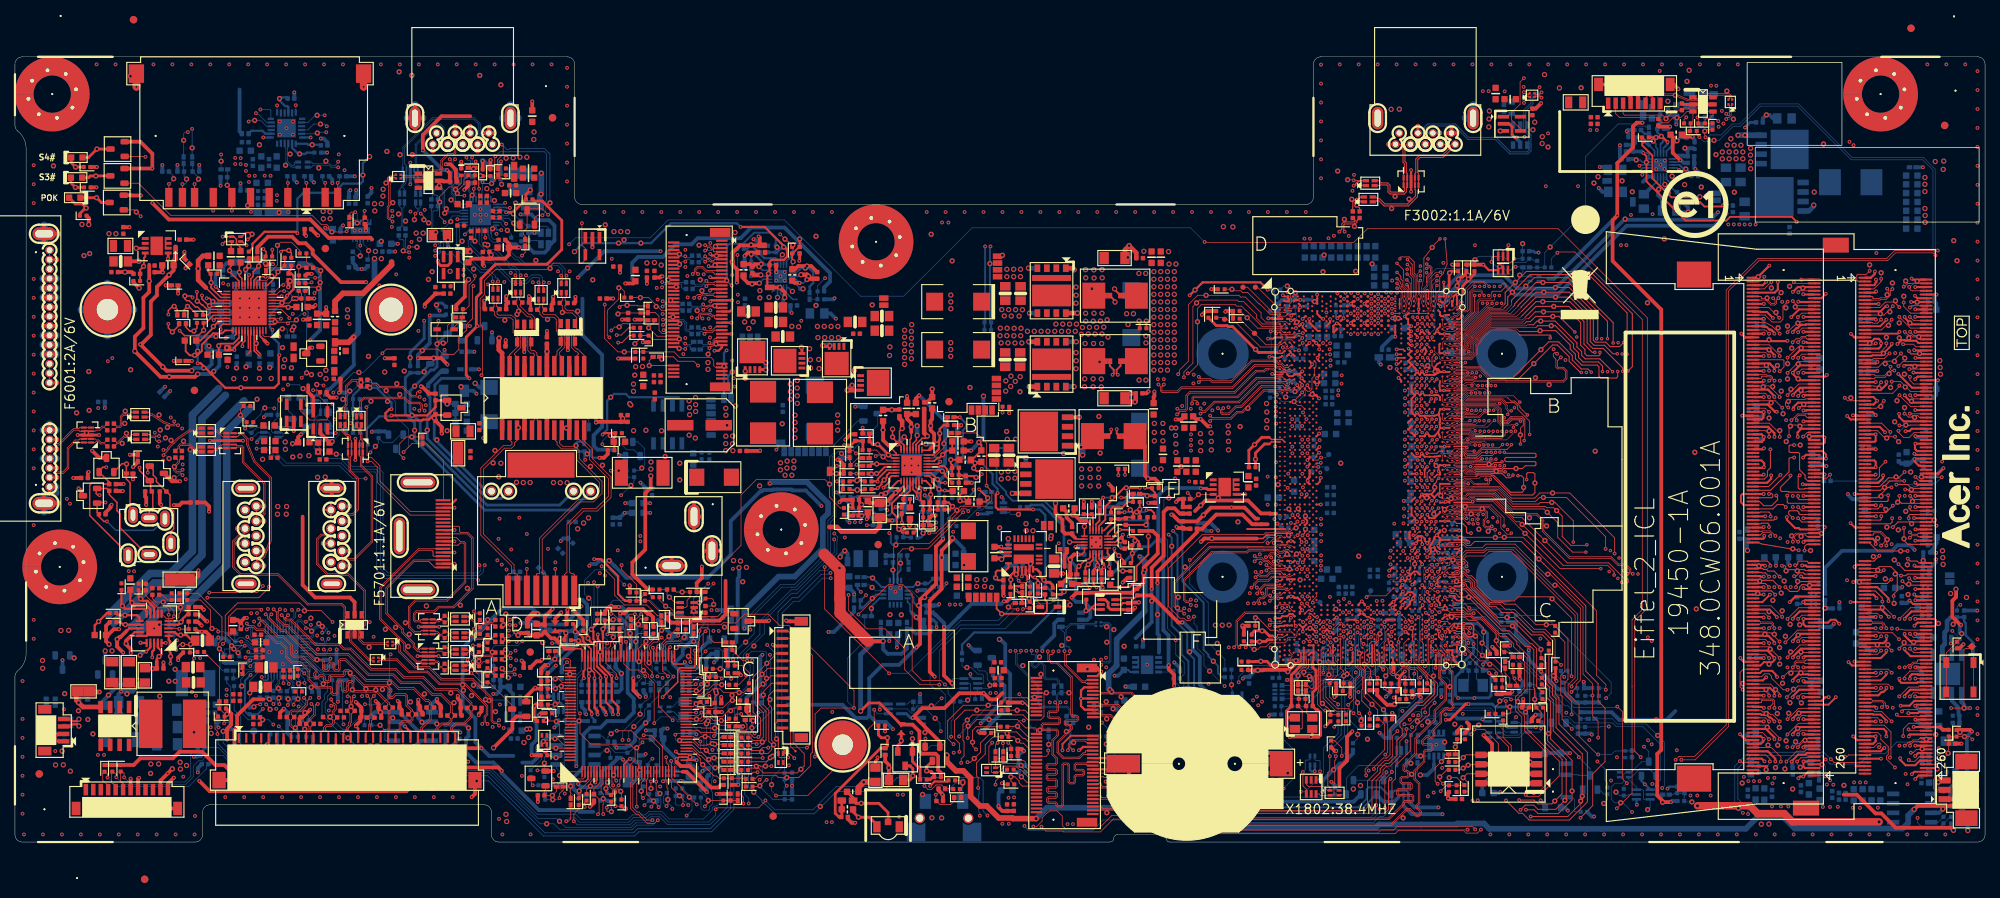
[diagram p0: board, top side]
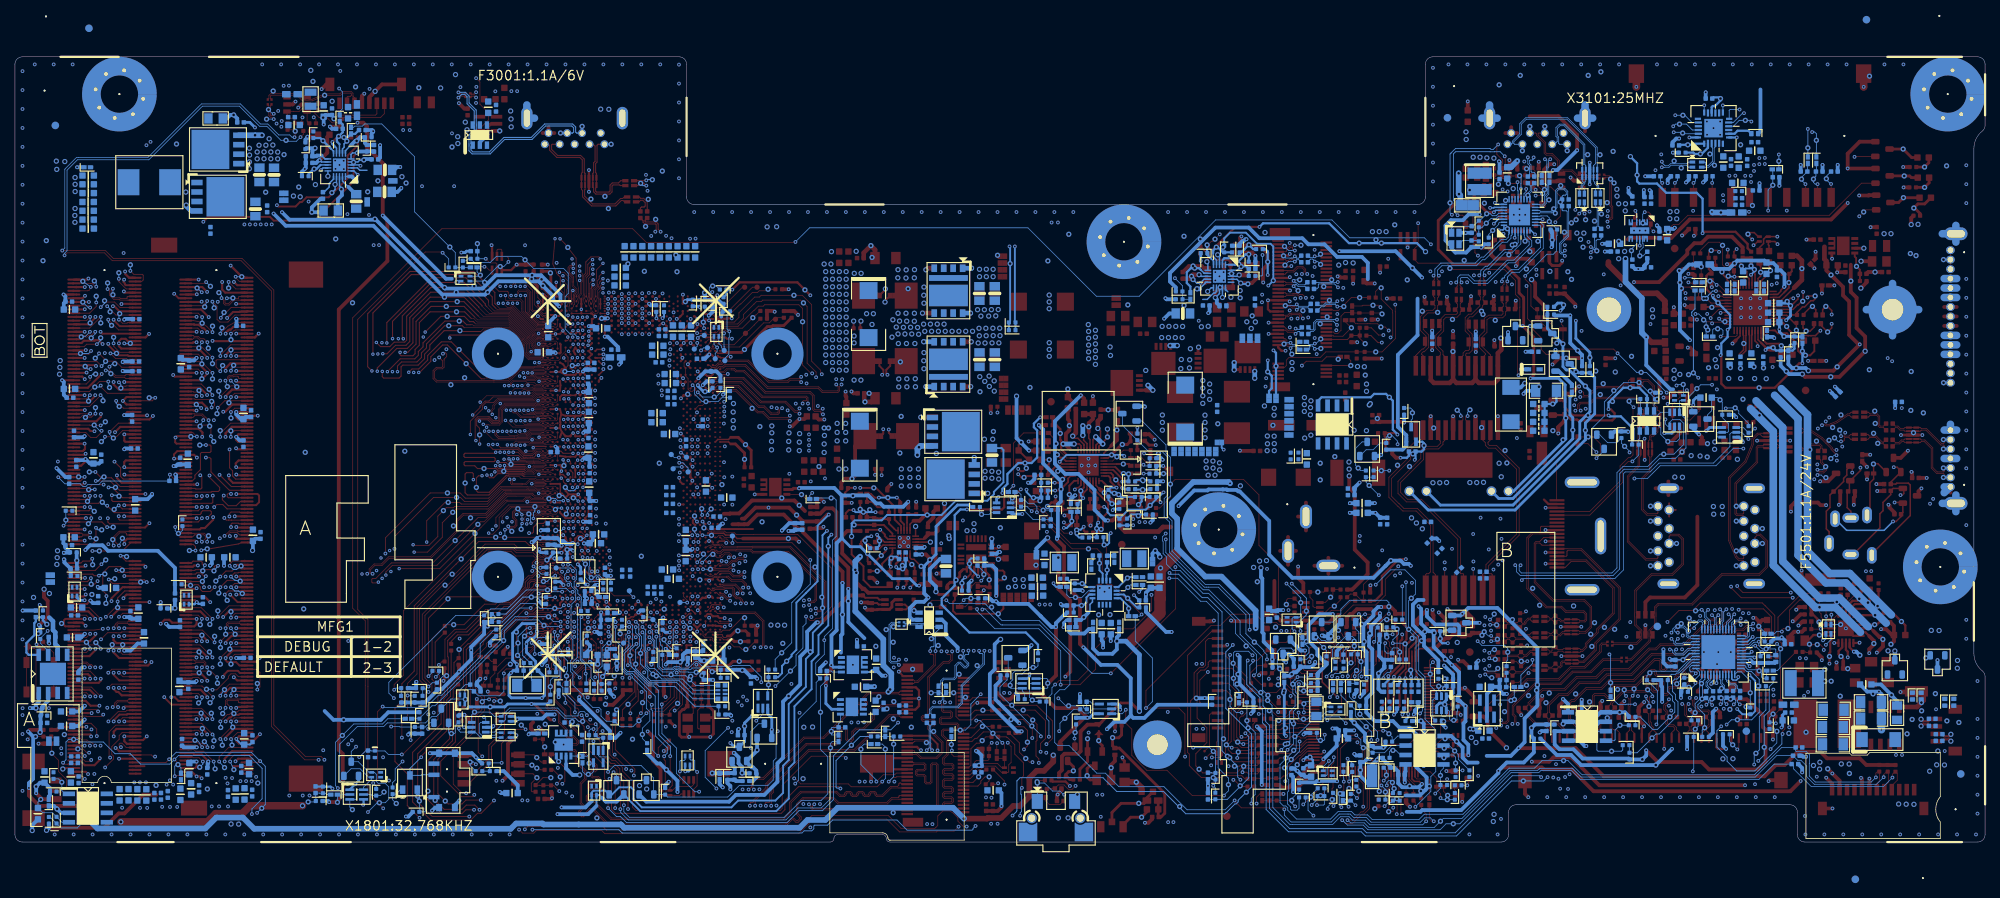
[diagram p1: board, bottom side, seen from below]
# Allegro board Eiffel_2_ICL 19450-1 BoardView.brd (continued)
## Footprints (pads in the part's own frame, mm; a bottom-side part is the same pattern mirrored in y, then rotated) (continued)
C166KK-12209-L
  round 0.254 hole 1.27 unplated: (-15.595,0) (15.595,0)
  oval 1.727x3.124 hole 1.016x2.413: 23(18.075,1.11) 24(-18.075,1.11)
  oval 1.041x1.168 hole 0.762: P1(1.905,1.84) P2(0.635,1.84) P3(-0.635,1.84) P4(-1.905,1.84) P5(-3.175,1.84) P6(-4.445,1.84) P7(-5.715,1.84) P8(-6.985,1.84) P9(-8.255,1.84) P10(-9.525,1.84) P11(-10.795,1.84) P12(-12.065,1.84) P13(-13.335,1.84) P14(-14.605,1.84) P15(-15.875,1.84) S1(15.875,1.84) S2(14.605,1.84) S3(13.335,1.84) S4(12.065,1.84) S5(10.795,1.84) S6(9.525,1.84) S7(8.255,1.84)
C402-TO0D2H26
  custom 0.152x0.152 smd: 1(0,0.457) 2(0,-0.457)
C402H22
  custom 0.152x0.152 smd: 1(0,0.445) 2(0,-0.445)
C402H24
  custom 0.152x0.152 smd: 1(0,0.445) 2(0,-0.445)
C603H32
  custom 0.216x0.216 smd: 1(0,0.762) 2(0,-0.762)
C603H36
  custom 0.216x0.216 smd: 1(0,0.762) 2(0,-0.762)
C603H38
  custom 0.216x0.216 smd: 1(0,0.762) 2(0,-0.762)
C603H40
  custom 0.216x0.216 smd: 1(0,0.762) 2(0,-0.762)
C805H54
  rect 1.397x1.143 smd: 1(0,0.965) 2(0,-0.965)
C805H56
  rect 1.397x1.143 smd: 1(0,0.965) 2(0,-0.965)
C1206H71
  rect 1.651x1.27 smd: 1(0,1.397) 2(0,-1.397)
CON2C-U
  custom 0.171x0.171 smd: 1(0,0.533) 2(0,-0.533)
CON2O-U
  custom 0.159x0.159 smd: 1(0,0.254) 2(0,-0.254)
CT7343H79
  rect 2.413x2.286 smd: 1(0,3.15) 2(0,-3.15)
CT7343H83
  rect 2.413x2.286 smd: 1(0,3.15) 2(0,-3.15)
D4724AKH44
  rect 2.007x1.549 smd: A(0,2.221) K(0,-2.221)
DFN8F3-G2517H32
  rect 0.406x0.94 smd: 1(0.975,1.538) 2(0.325,1.538) 3(-0.325,1.538) 4(-0.975,1.538) 5(-0.975,-1.538)
  rect 0.025x0.025 smd: 6(-0.325,-1.538) 8(0.975,-1.538)
  custom 0.235x0.235 smd: 7(0.325,-1.538)
  rect 2.489x1.676 smd: 9(0,0)
DFN10G2510H22
  rect 0.305x0.787 smd: 1(1,0.494) 5(-1,0.494) 6(-1,-0.494) 10(1,-0.494)
  rect 0.254x0.787 smd: 2(0.521,0.494) 4(-0.521,0.494) 7(-0.521,-0.494) 9(0.521,-0.494)
  rect 0.025x0.025 smd: 3(0,0.494)
  rect 0.406x1.753 smd: 8(0,-0.494)
DO214AAAK-1121H97
  rect 2.311x2.032 smd: A(0,2.322) K(0,-2.322)
DUMMY-LD65D85-4PH20
  rect 0.305x0.356 smd: 1(-0.25,0.325) 2(-0.25,-0.325) 3(0.25,-0.325) 4(0.25,0.325)
GAP-CLOSE-PWR-3
  rect 0.66x0.762 smd: 1(-0.305,0) 2(0.305,0)
GEN315R158-8-F-C-S-U
  round 0.254 hole 4.013 unplated: (0,0)
  round 0.864 hole 0.508: 1(3.189,0.634) 2(1.806,2.703) 3(-0.634,3.189) 4(-2.703,1.806) 5(-3.189,-0.634) 6(-1.806,-2.703) 7(0.634,-3.189) 8(2.703,-1.806)
J1100D-C6DH-0002R
  oval 1.321x2.235 hole 0.61x1.524: 1(2.9,-1) 4(2.1,2.3) 5(-2.18,2.8) 6(-2.825,-2.6)
  oval 2.235x1.321 hole 1.524x0.61: 2(0,2.43) 3(0,-2.48)
L402-TO0D2H24
  custom 0.152x0.152 smd: 1(0,0.457) 2(0,-0.457)
L402H24
  custom 0.14x0.14 smd: 1(0,0.445) 2(0,-0.445)
L603H38
  custom 0.216x0.216 smd: 1(0,0.762) 2(0,-0.762)
L2520-D620H48
  rect 2.261x1.245 smd: 1(0,1.018) 2(0,-1.018)
L3030-3009-2H40
  rect 3.251x1.524 smd: 1(0,1.108) 2(0,-1.108)
L4947-1115H119
  rect 2.007x2.261 smd: 1(0,2.049) 2(0,-2.049)
L7066-1830-UH119
  rect 3.505x2.921 smd: 1(0,2.78) 2(0,-2.78)
L7366-1930H158
  rect 3.505x3.073 smd: 1(0,2.856) 2(0,-2.856)
L8080-6020H158
  rect 6.502x3.15 smd: 1(0,2.944) 2(0,-2.944)
L125100-4P-1H37
  rect 0.762x0.432 smd: 1(0.625,0.341) 2(-0.625,0.341) 3(-0.625,-0.341) 4(0.625,-0.341)
L125100-4P-4H24
  rect 0.762x0.432 smd: 1(-0.625,0.341) 2(0.625,0.341) 3(0.625,-0.341) 4(-0.625,-0.341)
L125100-4P-5H24
  rect 0.457x0.838 smd: 1(-0.326,0.587) 2(0.326,0.587) 3(-0.326,-0.587) 4(0.326,-0.587)
LED1608-1A2KH40
  custom 0.216x0.216 smd: 1A(0,0.762) 2K(0,-0.762)
LED3020-3P-6H44
  rect 0.991x1.499 smd: 1(1.495,0) 3(-1.495,0)
  rect 0.889x0.889 smd: 2(0,-0.65)
LQFP128H63
  rect 0.203x1.524 smd: 1(6.2,7.747) 2(5.8,7.747) 3(5.4,7.747) 4(5,7.747) 5(4.6,7.747) 6(4.2,7.747) 7(3.8,7.747) 8(3.4,7.747) 9(3,7.747) 10(2.6,7.747) 11(2.2,7.747) 12(1.8,7.747) 13(1.4,7.747) 14(0.999,7.747) 15(0.599,7.747) 16(0.199,7.747) 17(-0.199,7.747) 18(-0.599,7.747) 19(-0.999,7.747) 20(-1.4,7.747) 21(-1.8,7.747) 22(-2.2,7.747) 23(-2.6,7.747) 24(-3,7.747) 25(-3.4,7.747) 26(-3.8,7.747) 27(-4.2,7.747) 28(-4.6,7.747) 29(-5,7.747) 30(-5.4,7.747) 31(-5.8,7.747) 32(-6.2,7.747) 65(-6.2,-7.747) 66(-5.8,-7.747) 67(-5.4,-7.747) 68(-5,-7.747) 69(-4.6,-7.747) 70(-4.2,-7.747) 71(-3.8,-7.747) 72(-3.4,-7.747) 73(-3,-7.747) 74(-2.6,-7.747) 75(-2.2,-7.747) 76(-1.8,-7.747) 77(-1.4,-7.747) 78(-0.999,-7.747) 79(-0.599,-7.747) 80(-0.199,-7.747) 81(0.199,-7.747) 82(0.599,-7.747) 83(0.999,-7.747) 84(1.4,-7.747) 85(1.8,-7.747) 86(2.2,-7.747) 87(2.6,-7.747) 88(3,-7.747) 89(3.4,-7.747) 90(3.8,-7.747) 91(4.2,-7.747) 92(4.6,-7.747) 93(5,-7.747) 94(5.4,-7.747) 95(5.8,-7.747) 96(6.2,-7.747)
  rect 1.524x0.203 smd: 33(-7.747,6.2) 34(-7.747,5.8) 35(-7.747,5.4) 36(-7.747,5) 37(-7.747,4.6) 38(-7.747,4.2) 39(-7.747,3.8) 40(-7.747,3.4) 41(-7.747,3) 42(-7.747,2.6) 43(-7.747,2.2) 44(-7.747,1.8) 45(-7.747,1.4) 46(-7.747,0.999) 47(-7.747,0.599) 48(-7.747,0.199) 49(-7.747,-0.199) 50(-7.747,-0.599) 51(-7.747,-0.999) 52(-7.747,-1.4) 53(-7.747,-1.8) 54(-7.747,-2.2) 55(-7.747,-2.6) 56(-7.747,-3) 57(-7.747,-3.4) 58(-7.747,-3.8) 59(-7.747,-4.2) 60(-7.747,-4.6) 61(-7.747,-5) 62(-7.747,-5.4) 63(-7.747,-5.8) 64(-7.747,-6.2) 97(7.747,-6.2) 98(7.747,-5.8) 99(7.747,-5.4) 100(7.747,-5) 101(7.747,-4.6) 102(7.747,-4.2) 103(7.747,-3.8) 104(7.747,-3.4) 105(7.747,-3) 106(7.747,-2.6) 107(7.747,-2.2) 108(7.747,-1.8) 109(7.747,-1.4) 110(7.747,-0.999) 111(7.747,-0.599) 112(7.747,-0.199) 113(7.747,0.199) 114(7.747,0.599) 115(7.747,0.999) 116(7.747,1.4) 117(7.747,1.8) 118(7.747,2.2) 119(7.747,2.6) 120(7.747,3) 121(7.747,3.4) 122(7.747,3.8) 123(7.747,4.2) 124(7.747,4.6) 125(7.747,5) 126(7.747,5.4) 127(7.747,5.8) 128(7.747,6.2)
MSS3-Q-T-R
  round 0.254 hole 0.965 unplated: (-1.5,0) (1.5,0)
  rect 0.61x1.499 smd: 1(-2.25,1.75) 2(0.751,1.75) 3(2.25,1.75)
  rect 0.991x0.813 smd: 4(-3.65,1.056) 5(-3.65,-1.056) 6(3.65,1.056) 7(3.65,-1.056)
NTC-402H22-U
  custom 0.14x0.14 smd: 1(0,0.445) 2(0,-0.445)
OSC-3225-4P-4H36
  rect 1.397x1.067 smd: 1(-1.171,-0.756) 2(1.171,-0.756) 3(1.171,0.756) 4(-1.171,0.756)
POLYSW-2114H30
  rect 1.6x0.965 smd: 1(0,0.94) 2(0,-0.94)
POLYSW-4633-UH43
  rect 3.505x1.626 smd: 1(0,1.834) 2(0,-1.834)
PPAK-5PH48
  rect 0.762x1.524 smd: 1(-1.905,-3.81) 2(-0.635,-3.81) 3(0.635,-3.81) 4(1.905,-3.81)
  rect 5.283x5.08 smd: 5(1.499,1.448)
  rect 0.025x0.025 smd: 6(-1.499,1.448) 7(-1.499,-1.448) 8(1.499,-1.448)
PPAK-8P-3333-1H40
  rect 0.406x0.94 smd: 1(-0.975,-2.283) 2(-0.325,-2.283) 3(0.325,-2.283) 4(0.975,-2.283)
  rect 0.025x0.025 smd: 5(0.65,1) 6(0,1) 7(-0.65,1)
  rect 3.251x3.099 smd: 8(0,0)
PPAK-8P-3333-2H40
  rect 0.406x0.914 smd: 1(-0.975,-2.347) 2(-0.325,-2.347) 3(0.325,-2.347) 4(0.975,-2.347)
  rect 3.48x3.023 smd: 5(1.01,0.895)
  rect 0.025x0.025 smd: 6(-1.01,0.895) 7(-1.01,-0.895) 8(1.01,-0.895)
PPAK-8P-G5324H44-COLAY
  rect 0.762x1.016 smd: 1(-1.905,-3.01) 2(-0.635,-3.01) 3(0.635,-3.01) 4(1.905,-3.01) 5(1.905,3.01) 6(0.635,3.01) 7(-0.635,3.01) 8(-1.905,3.01)
  rect 5.207x2.896 smd: 9(0,0.65)
  rect 5.207x0.787 smd: 10(0,-1.7)
PPAK-8PH48
  rect 0.762x1.524 smd: 1(-1.905,-3.81) 2(-0.635,-3.81) 3(0.635,-3.81) 4(1.905,-3.81)
  rect 5.283x5.08 smd: 5(0,0)
  rect 0.025x0.025 smd: 6(0.635,2.032) 7(-0.635,2.032) 8(-1.905,2.032)
QFN16G3-G2H34
  rect 0.305x0.787 smd: 1(0.75,1.614) 2(0.25,1.614) 3(-0.25,1.614) 4(-0.75,1.614) 9(-0.75,-1.614) 10(-0.25,-1.614) 11(0.25,-1.614) 12(0.75,-1.614)
  rect 0.787x0.305 smd: 5(-1.614,0.75) 6(-1.614,0.25) 7(-1.614,-0.25) 8(-1.614,-0.75) 13(1.614,-0.75) 14(1.614,-0.25) 15(1.614,0.25) 16(1.614,0.75)
  rect 2.007x2.007 smd: 17(0,0)
QFN20-G1D75H32
  rect 0.203x0.914 smd: 1(0.8,1.551) 2(0.4,1.551) 3(0,1.551) 4(-0.4,1.551) 5(-0.8,1.551) 11(-0.8,-1.551) 12(-0.4,-1.551) 13(0,-1.551) 14(0.4,-1.551) 15(0.8,-1.551)
  rect 0.914x0.203 smd: 6(-1.551,0.8) 7(-1.551,0.4) 8(-1.551,0) 9(-1.551,-0.4) 10(-1.551,-0.8) 16(1.551,-0.8) 17(1.551,-0.4) 18(1.551,0) 19(1.551,0.4) 20(1.551,0.8)
  rect 1.753x1.753 smd: 21(0,0)
QFN20-G2D1H34
  rect 0.305x1.092 smd: 1(0.999,1.956) 5(-0.999,1.956) 11(-0.999,-1.956) 15(0.999,-1.956)
  rect 0.305x1.143 smd: 2(0.5,1.93) 3(0,1.93) 4(-0.5,1.93) 12(-0.5,-1.93) 13(0,-1.93) 14(0.5,-1.93)
  rect 1.092x0.305 smd: 6(-1.956,0.999) 10(-1.956,-0.999) 16(1.956,-0.999) 20(1.956,0.999)
  rect 1.143x0.305 smd: 7(-1.93,0.5) 8(-1.93,0) 9(-1.93,-0.5) 17(1.93,-0.5) 18(1.93,0) 19(1.93,0.5)
  rect 2.108x2.108 smd: 21(0,0)
QFN22G4-G2P-1H36
  rect 0.305x0.914 smd: 1(1.25,2.051) 2(0.75,2.051) 3(0.25,2.051) 4(-0.25,2.051) 5(-0.75,2.051) 6(-1.25,2.051) 12(-1.25,-2.051) 13(-0.75,-2.051) 14(-0.25,-2.051) 15(0.25,-2.051) 16(0.75,-2.051) 17(1.25,-2.051)
  rect 0.914x0.305 smd: 7(-2.051,1.25) 8(-2.051,0.75) 9(-2.051,0.25) 10(-2.051,-0.75) 11(-2.051,-1.25) 18(2.051,-1.25) 19(2.051,-0.75) 20(2.051,-0.25) 21(2.051,0.25) 22(2.051,1.25)
  rect 2.692x1.245 smd: 23(0,0.7)
  rect 2.692x0.838 smd: 24(0,-0.9)
QFN24-G2D5H40-U
  rect 0.305x0.838 smd: 1(1.25,2.095) 6(-1.25,2.095) 13(-1.25,-2.095) 18(1.25,-2.095)
  rect 0.305x0.965 smd: 2(0.751,2.032) 3(0.25,2.032) 4(-0.25,2.032) 5(-0.751,2.032) 14(-0.751,-2.032) 15(-0.25,-2.032) 16(0.25,-2.032) 17(0.751,-2.032)
  rect 0.838x0.305 smd: 7(-2.095,1.25) 12(-2.095,-1.25) 19(2.095,-1.25) 24(2.095,1.25)
  rect 0.965x0.305 smd: 8(-2.032,0.751) 9(-2.032,0.25) 10(-2.032,-0.25) 11(-2.032,-0.751) 20(2.032,-0.751) 21(2.032,-0.25) 22(2.032,0.25) 23(2.032,0.751)
  rect 2.489x2.489 smd: 25(0,0)
QFN32J4-G2D75H32
  rect 0.203x0.838 smd: 1(1.4,2.051) 8(-1.4,2.051) 17(-1.4,-2.051) 24(1.4,-2.051)
  rect 0.203x0.914 smd: 2(1,2.051) 3(0.6,2.051) 4(0.2,2.051) 5(-0.2,2.051) 6(-0.6,2.051) 7(-1,2.051) 18(-1,-2.051) 19(-0.6,-2.051) 20(-0.2,-2.051) 21(0.2,-2.051) 22(0.6,-2.051) 23(1,-2.051)
  rect 0.838x0.203 smd: 9(-2.051,1.4) 16(-2.051,-1.4) 25(2.051,-1.4) 32(2.051,1.4)
  rect 0.914x0.203 smd: 10(-2.051,1) 11(-2.051,0.6) 12(-2.051,0.2) 13(-2.051,-0.2) 14(-2.051,-0.6) 15(-2.051,-1) 26(2.051,-1) 27(2.051,-0.6) 28(2.051,-0.2) 29(2.051,0.2) 30(2.051,0.6) 31(2.051,1)
  rect 2.743x2.743 smd: 33(0,0)
QFN32J4-G2D85H36
  rect 0.203x0.864 smd: 1(1.4,2.085) 2(1,2.085) 3(0.6,2.085) 4(0.2,2.085) 5(-0.2,2.085) 6(-0.6,2.085) 7(-1,2.085) 8(-1.4,2.085) 17(-1.4,-2.085) 18(-1,-2.085) 19(-0.6,-2.085) 20(-0.2,-2.085) 21(0.2,-2.085) 22(0.6,-2.085) 23(1,-2.085) 24(1.4,-2.085)
  rect 0.864x0.203 smd: 9(-2.085,1.4) 10(-2.085,1) 11(-2.085,0.6) 12(-2.085,0.2) 13(-2.085,-0.2) 14(-2.085,-0.6) 15(-2.085,-1) 16(-2.085,-1.4) 25(2.085,-1.4) 26(2.085,-1) 27(2.085,-0.6) 28(2.085,-0.2) 29(2.085,0.2) 30(2.085,0.6) 31(2.085,1) 32(2.085,1.4)
  rect 2.845x2.845 smd: 33(0,0)
QFN48J6-G4D55H40
  rect 0.203x1.016 smd: 1(2.2,3) 2(1.8,3) 3(1.4,3) 4(1,3) 5(0.6,3) 6(0.2,3) 7(-0.2,3) 8(-0.6,3) 9(-1,3) 10(-1.4,3) 11(-1.8,3) 12(-2.2,3) 25(-2.2,-3) 26(-1.8,-3) 27(-1.4,-3) 28(-1,-3) 29(-0.6,-3) 30(-0.2,-3) 31(0.2,-3) 32(0.6,-3) 33(1,-3) 34(1.4,-3) 35(1.8,-3) 36(2.2,-3)
  rect 1.016x0.203 smd: 13(-3,2.2) 14(-3,1.8) 15(-3,1.4) 16(-3,1) 17(-3,0.6) 18(-3,0.2) 19(-3,-0.2) 20(-3,-0.6) 21(-3,-1) 22(-3,-1.4) 23(-3,-1.8) 24(-3,-2.2) 37(3,-2.2) 38(3,-1.8) 39(3,-1.4) 40(3,-1) 41(3,-0.6) 42(3,-0.2) 43(3,0.2) 44(3,0.6) 45(3,1) 46(3,1.4) 47(3,1.8) 48(3,2.2)
  rect 4.547x4.547 smd: 49(0,0)
QFN48J6-G465H40
  rect 0.203x0.965 smd: 1(2.2,3.025) 2(1.8,3.025) 3(1.4,3.025) 4(1,3.025) 5(0.6,3.025) 6(0.2,3.025) 7(-0.2,3.025) 8(-0.6,3.025) 9(-1,3.025) 10(-1.4,3.025) 11(-1.8,3.025) 12(-2.2,3.025) 25(-2.2,-3.025) 26(-1.8,-3.025) 27(-1.4,-3.025) 28(-1,-3.025) 29(-0.6,-3.025) 30(-0.2,-3.025) 31(0.2,-3.025) 32(0.6,-3.025) 33(1,-3.025) 34(1.4,-3.025) 35(1.8,-3.025) 36(2.2,-3.025)
  rect 0.965x0.203 smd: 13(-3.025,2.2) 14(-3.025,1.8) 15(-3.025,1.4) 16(-3.025,1) 17(-3.025,0.6) 18(-3.025,0.2) 19(-3.025,-0.2) 20(-3.025,-0.6) 21(-3.025,-1) 22(-3.025,-1.4) 23(-3.025,-1.8) 24(-3.025,-2.2) 37(3.025,-2.2) 38(3.025,-1.8) 39(3.025,-1.4) 40(3.025,-1) 41(3.025,-0.6) 42(3.025,-0.2) 43(3.025,0.2) 44(3.025,0.6) 45(3.025,1) 46(3.025,1.4) 47(3.025,1.8) 48(3.025,2.2)
  rect 4.648x4.648 smd: 49(0,0)
R402H14
  custom 0.14x0.14 smd: 1(0,0.445) 2(0,-0.445)
R402H15
  custom 0.14x0.14 smd: 1(0,0.445) 2(0,-0.445)
R402H16
  custom 0.14x0.14 smd: 1(0,0.445) 2(0,-0.445)
R402H18
  custom 0.14x0.14 smd: 1(0,0.445) 2(0,-0.445)
R603H22
  custom 0.216x0.216 smd: 1(0,0.762) 2(0,-0.762)
R805H24
  rect 1.397x1.143 smd: 1(0,0.965) 2(0,-0.965)
R1206H26
  rect 1.651x1.27 smd: 1(0,1.397) 2(0,-1.397)
R1206H28
  rect 1.651x1.27 smd: 1(0,1.397) 2(0,-1.397)
R2512H32
  rect 3.505x1.778 smd: 1(0,2.794) 2(0,-2.794)
SC70-5H44
  rect 0.406x1.219 smd: 1(0.65,0.826) 2(0,0.826) 3(-0.65,0.826) 4(-0.65,-0.826) 5(0.65,-0.826)
SC70-6H44
  rect 0.406x1.016 smd: 1(-0.65,-0.94) 2(0,-0.94) 3(0.65,-0.94) 4(0.65,0.94) 5(0,0.94) 6(-0.65,0.94)
SE331721H237
  rect 1.422x3.556 smd: 1(0,2.574) 2(0,-2.574)
SKRBAJF010
  rect 1.473x0.813 smd: 1(-1.971,1.825) 2(-1.971,-1.825) 3(1.971,1.825) 4(1.971,-1.825)
SKT-HDMI22-148070
  rect 0.305x2.007 smd: 1(4.21,3.37) 2(3.71,3.37) 3(3.21,3.37) 4(2.71,3.37) 5(2.21,3.37) 6(1.71,3.37) 7(1.21,3.37) 8(0.71,3.37) 9(0.21,3.37) 10(-0.29,3.37) 11(-0.79,3.37) 12(-1.29,3.37) 13(-1.79,3.37) 14(-2.29,3.37) 15(-2.79,3.37) 16(-3.29,3.37) 17(-3.79,3.37) 18(-4.29,3.37) 19(-4.79,3.37)
  oval 4.928x1.524 hole 4.216x0.813: 20(0,-2.48)
  oval 1.524x4.674 hole 0.813x3.962: 21(-7.2,0) 22(7.2,0)
SKT-SOIC8-1H211
  rect 0.889x1.499 smd: 1(1.905,3.751) 2(0.635,3.751) 3(-0.635,3.751) 4(-1.905,3.751) 5(-1.905,-3.751) 6(-0.635,-3.751) 7(0.635,-3.751) 8(1.905,-3.751)
SKT-USB11-138166
  round 1.067 hole 0.711: 1(-3.5,2) 2(-1,2) 3(1,2) 4(3.5,2) 5(4,3.5) 6(2,3.5) 7(0,3.5) 8(-2,3.5) 9(-4,3.5)
  oval 1.524x3.023 hole 0.813x2.311: 10(-6.4,0) 11(6.4,0)
SKT-USB11-160090-3-U
  round 1.27 hole 0.864: 1(-3.5,-0.1) 2(-1,-0.1) 3(1,-0.1) 4(3.5,-0.1) 5(4,1.4) 6(2,1.4) 7(0,1.4) 8(-2,1.4) 9(-4,1.4)
  oval 1.321x2.921 hole 0.61x2.21: 10(-6.4,0) 11(6.4,0)
SMD49-12H34
  rect 1.753x1.397 smd: 1(0,1.295) 2(0,-1.295)
SMD-ARES4
  rect 0.356x0.66 smd: 1(-0.325,-0.599) 2(0.325,-0.599) 3(0.325,0.599) 4(-0.325,0.599)
SMD-ARES4H18
  rect 0.356x0.66 smd: 1(-0.325,-0.599) 2(0.325,-0.599) 3(0.325,0.599) 4(-0.325,0.599)
SMD-ARES4H20
  rect 0.356x0.66 smd: 1(-0.325,-0.599) 2(0.325,-0.599) 3(0.325,0.599) 4(-0.325,0.599)
SMD-OSC38H32
  rect 1.092x0.737 smd: 1(-0.769,-0.495) 2(0.769,-0.495) 3(0.769,0.495) 4(-0.769,0.495)
SOD323AKH38
  rect 0.559x1.016 smd: A(0,1.143) K(0,-1.143)
SOD882-10D6-1H20
  custom 0.114x0.114 smd: 1(0,0.445) 2(0,-0.445)
SOD-523-4H28
  rect 0.559x0.864 smd: 1(0,0.778) 2(0,-0.778)
SOIC8-1H86
  rect 0.635x1.651 smd: 1(-1.905,-3.493) 2(-0.635,-3.493) 3(0.635,-3.493) 4(1.905,-3.493) 5(1.905,3.493) 6(0.635,3.493) 7(-0.635,3.493) 8(-1.905,3.493)
SOIC8-G3530H63
  rect 0.635x1.651 smd: 1(-1.905,-2.555) 2(-0.635,-2.555) 3(0.635,-2.555) 4(1.905,-2.555) 5(1.905,2.555) 6(0.635,2.555) 7(-0.635,2.555) 8(-1.905,2.555)
  rect 3.505x2.997 smd: 9(0,0)
SOIC8H69
  rect 0.635x1.651 smd: 1(-1.905,-2.54) 2(-0.635,-2.54) 3(0.635,-2.54) 4(1.905,-2.54) 5(1.905,2.54) 6(0.635,2.54) 7(-0.635,2.54) 8(-1.905,2.54)
SOIC8H75
  rect 0.635x1.651 smd: 1(-1.905,-2.54) 2(-0.635,-2.54) 3(0.635,-2.54) 4(1.905,-2.54) 5(1.905,2.54) 6(0.635,2.54) 7(-0.635,2.54) 8(-1.905,2.54)
SON14J3020-G2610H34
  rect 0.025x0.025 smd: 1(1.2,1.105) 6(-0.8,1.105) 9(-0.8,-1.105) 14(1.2,-1.105)
  custom 0.151x0.151 smd: 2(0.8,1.105) 7(-1.2,1.105) 8(-1.2,-1.105) 13(0.8,-1.105)
  rect 0.203x0.813 smd: 3(0.4,1.105) 4(0,1.105) 5(-0.4,1.105) 10(-0.4,-1.105) 11(0,-1.105) 12(0.4,-1.105)
  rect 2.591x0.889 smd: 15(0,0)
SOT23-2D4-312H44
  custom 0.191x0.191 smd: 1(-0.984,-0.953) 2(0.984,-0.953) 3(0,0.953)
SOT23-2D4-312H46
  custom 0.191x0.191 smd: 1(-0.984,-0.953) 2(0.984,-0.953) 3(0,0.953)
SOT23CBE2D4H44
  custom 0.191x0.191 smd: B(-0.984,-0.953) C(0,0.953) E(0.984,-0.953)
SOT23DGS2D4H44
  custom 0.191x0.191 smd: D(0,0.953) G(-0.984,-0.953) S(0.984,-0.953)
SOT-6-1H58
  rect 0.584x1.219 smd: 1(-0.95,-1.194) 2(0,-1.194) 3(0.95,-1.194) 4(0.95,1.194) 5(0,1.194) 6(-0.95,1.194)
SOT-6H58
  rect 0.584x1.016 smd: 1(-0.953,-1.346) 2(0,-1.346) 3(0.953,-1.346) 4(0.953,1.346) 5(0,1.346) 6(-0.953,1.346)
SOT-23-5H40
  rect 0.508x1.524 smd: 1(-0.95,-1.143) 2(0,-1.143) 3(0.95,-1.143) 4(0.95,1.143) 5(-0.95,1.143)
SOT-23-10H44
  rect 0.762x1.143 smd: 1(-0.984,-0.953) 2(0.984,-0.953) 3(0,0.953)
SOT-323H40
  rect 0.508x1.168 smd: 1(-0.648,-0.991) 2(0.648,-0.991) 3(0,0.991)
SOT-363-1H44
  rect 0.356x1.219 smd: 1(-0.65,-0.922) 2(0,-0.922) 3(0.65,-0.922) 4(0.65,0.922) 5(0,0.922) 6(-0.65,0.922)
SOT-363H44
  rect 0.406x1.016 smd: 1(-0.65,-0.94) 2(0,-0.94) 3(0.65,-0.94) 4(0.65,0.94) 5(0,0.94) 6(-0.65,0.94)
STF236R128H34
  round 5.994 hole 3.251: 1(0,0)
STF256R109H124
  round 6.502 hole 2.769: 1(0,0)
STF256R113-UH286
  round 6.502 hole 2.87: 1(0,0)
TA2-32N-Q-T-R
  rect 1.499x2.007 smd: 1(-2.5,2.25) 2(2.5,2.25)
  custom 0.622x0.622 smd: 3(-3.75,-1.85) 4(3.75,-1.85)
  round 1.372 hole 0.965: 5(3.25,0) 6(-3.25,0)
TPAD14-OP
  round 0.356 smd: 1(0,0)
TPAD28
  round 0.711 smd: 1(0,0)
TVS5436-1121H105
  rect 2.337x2.007 smd: 1(0,2.299) 2(0,-2.299)
unnamed#2
  round 0.254 hole 3.2 unplated: (0,0)
XFORM24C1510H168
  rect 0.61x2.642 smd: 1(-5.5,-4.314) 2(-4.5,-4.314) 3(-3.5,-4.314) 4(-2.5,-4.314) 5(-1.5,-4.314) 6(-0.5,-4.314) 7(0.5,-4.314) 8(1.5,-4.314) 9(2.5,-4.314) 10(3.5,-4.314) 11(4.5,-4.314) 12(5.5,-4.314) 13(5.5,4.314) 14(4.5,4.314) 15(3.5,4.314) 16(2.5,4.314) 17(1.5,4.314) 18(0.5,4.314) 19(-0.5,4.314) 20(-1.5,4.314) 21(-2.5,4.314) 22(-3.5,4.314) 23(-4.5,4.314) 24(-5.5,4.314)

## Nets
1V_CPU_CORE: C701.1 C702.1 C703.1 CPU1.A19 CPU1.A21 CPU1.A23 CPU1.A24 CPU1.A27 CPU1.A29 CPU1.AA12 CPU1.AB1 CPU1.AB13 CPU1.AC12 CPU1.B19 CPU1.B23 CPU1.B27 CPU1.B29 CPU1.BN10 CPU1.BP9 CPU1.BP11 CPU1.BR10 CPU1.BT9 CPU1.BT11 CPU1.BU10 CPU1.BV9 CPU1.BV36 CPU1.BW9 CPU1.BW10 CPU1.BW36 CPU1.BY10 CPU1.C19 CPU1.C23 CPU1.C27 CPU1.C29 CPU1.CA9 CPU1.CA36 CPU1.CB10 CPU1.CC9 CPU1.CC11 CPU1.CC36 CPU1.CD10 CPU1.CE11 CPU1.CE34 CPU1.CE35 CPU1.CF10 CPU1.CF33 CPU1.CG11 CPU1.CG34 CPU1.CG35 CPU1.CH10 CPU1.CJ11 CPU1.CJ34 CPU1.CJ35 CPU1.CK10 CPU1.CL34 CPU1.CL35 CPU1.CN34 CPU1.CN35 CPU1.CP33 CPU1.CR34 CPU1.CR35 CPU1.CT33 CPU1.CT34 CPU1.CT35 CPU1.CU33 CPU1.D19 CPU1.D21 CPU1.D23 CPU1.D24 CPU1.D27 CPU1.D29 CPU1.F19 CPU1.F21 CPU1.F23 CPU1.F24 CPU1.F27 CPU1.F29 CPU1.G1 CPU1.G19 CPU1.G23 CPU1.G27 CPU1.G29 CPU1.H19 CPU1.H23 CPU1.H27 CPU1.H29 CPU1.J18 CPU1.J20 CPU1.J22 CPU1.J23 CPU1.J26 CPU1.J28 CPU1.J30 CPU1.J32 CPU1.K17 CPU1.K19 CPU1.K21 CPU1.K23 CPU1.K24 CPU1.K27 CPU1.K29 CPU1.K31 CPU1.M1 CPU1.U1 CPU1.V13 CPU1.W12 CPU1.Y13 FC9001.1 FC9002.1 FC9003.1 FC9004.1 FC9005.1 FC9006.1 G2401.1 PC1002.1 PC1003.1 PC1004.1 PC1005.1 PC1006.1 PC1007.1 PC1008.1 PC1009.1 PC1010.1 PC1011.1 PC1012.1 PC1013.1 PC1014.1 PC1026.1 PC1027.1 PC1028.1 PC1029.1 PC1030.1 PC1031.1 PC1032.1 PG4701.2 PG4707.2 PL4701.2 PL4702.2 PR4638.2 PT4701.1 R704.1
3V_5V_PWRGD: D5301.K PR4509.2 PR4510.2 PR4511.1
3V_MIC2V: R2723.2 U2701.29
5V_3D3V_S0_ON: C4013.1 R4035.2 U4003.3 U4003.5
5V_AUDIO_S0: C2706.1 C2707.1 C2708.1 C2709.1 R2714.2 R2755.2 U2701.41 U2701.46
5V_AUDIO_S0_S: D2701.1 R2714.1 R2768.2 R2769.2
5V_AUX_S5: PG4533.2 R2712.2 RC4502.1
5V_FANCTL1_FSM#: R2601.2 U2601.1
5V_HDD: C6001.1 C6002.1 F6001.2 SATA1.P7 SATA1.P8 SATA1.P9
5V_HDMI: F5701.2 R5720.1
5V_HDMI_CONN: C5714.1 HDMI1.18 R5720.2
5V_PANEL_VCC: C5527.1 C5528.1 C5550.1 C5551.1 LVDS1.1 LVDS1.2 LVDS1.3 U5504.1
5V_PVDD2: C2710.1 C2711.1 R2755.1 U2701.26
5V_S0: C2601.1 C2602.1 C4011.1 C4048.1 C5713.1 D5701.3 EC6908.1 EC6909.1 EC6910.1 F5701.1 F6001.1 Q5702.G R2604.1 R2606.1 R2769.1 R6404.2 U2601.2 U4003.13 U4003.14
5V_S5: C3405.1 C3515.1 C3524.1 C4009.1 C4017.1 C5554.1 C5556.1 EC6906.1 EC6907.1 EC6913.1 EC6914.1 EC6915.1 EC6916.1 EC6917.1 EC6923.1 G6401.1 PC5206.1 PC5302.1 PG4505.2 PG4506.2 PG4511.2 PG4512.2 PG4516.2 PG4517.2 PR4604.1 PR4609.1 PR5001.1 PR5005.2 PR5108.2 PR5109.1 PR5410.1 PR5413.1 PR5422.1 PU5201.6 PU5301.21 R2768.1 R3401.1 R3402.1 R6402.1 R24010.2 U3401.5 U3402.5 U3503.5 U3504.5 U4003.1 U4003.2 U4003.4 U4007.3 U4010.3 U4011.3 U4012.3 U5301.3 U5504.5
5V_STB: R2710.1 R2712.1 U2701.20
5V_SUS1: L6406.2 R6407.2
5V_USB30E: C3521.1 C3522.1 C3523.1 C3526.1 ED3502.5 U3504.1 USB3R2.1
5V_USB30F: C3516.1 C3517.1 C3518.1 C3520.1 ED3505.5 U3503.1 USB3R1.1
5V_USB30H: C3409.1 C3411.1 C3418.1 C3423.1 ED3401.5 U3402.1 USB3R4.1
5V_USB30R: C3404.1 C3406.1 C3407.1 C3417.1 U3401.1 USB3R3.1
19V_AD_JK: DCIN1.3 EC4301.1 EC4302.1 ED4301.K PC4301.1 PR4301.2 PU4301.1 PU4301.2 PU4301.3
19V_ADP: PC4302.1 PR4302.1 PR4303.1 PR4305.1 PU4301.5 PU4301.6 PU4301.7 PU4301.8 R4325.1
19V_ADP_GATE: PC4301.2 PR4301.1 PR4304.1 PU4301.4
19V_BOOST_ISW: C5501.1 R5535.2 U5501.19
19V_BOOST_ISW_R: Q5506.1 Q5506.2 Q5506.3 R5535.1 R5538.1 R5539.1
19V_BOOST_LDR: R5533.2 U5501.1
19V_BOOST_LDR_R: Q5506.4 R5533.1
19V_BOOST_LX: D5501.A L5502.2 Q5506.5 Q5506.6 Q5506.7 Q5506.8 R5532.1
19V_BOOST_SNB: C5544.1 R5532.2
19V_DCBATOUT: EC6901.1 EC6902.1 EC6903.1 EC6904.1 EC6905.1 EC6918.1 EC6919.1 EC6920.1 EC6921.1 EC6922.1 F5501.1 PC4505.1 PC4506.1 PG4503.1 PG4504.1 PG4507.1 PG4510.1 PG4518.1 PG4702.1 PG4703.1 PG4704.1 PG4705.1 PG4708.1 PG4709.1 PG4710.1 PG4711.1 PG5001.1 PG5002.1 PG5003.1 PG5004.1 PG5101.1 PG5102.1 PG5301.1 PG5302.1 PR4305.2 PR4605.2 PT4703.1 PT5002.1 PU4503.12 R4318.1 R4324.1 R5503.1 R24018.1 R24096.2
19V_DCBATOUT_LCD: C5502.1 C5503.1 C5536.1 C5541.1 F5501.2 L5502.1 R5503.2 R5506.1
19V_DCBATOUT_LCD_BOOST: C5537.1 C5538.1 C5539.1 C5540.1 C5542.1 CNVBD1.9 CNVBD1.10 D5501.K U5501.18
19V_DCBATOUT_LCD_VIN: C5505.1 R5506.2 U5501.4
AV18: C3302.2 U3301.1
GND: BTT1.2 C501.2 C701.2 C702.2 C703.2 C1101.2 C1102.2 C1103.2 C1104.2 C1105.2 C1106.2 C1107.2 C1108.2 C1109.2 C1110.2 C1111.2 C1112.2 C1113.2 C1114.2 C1115.2 C1116.2 C1117.2 C1118.2 C1119.2 C1120.2 C1121.2 C1122.2 C1125.2 C1126.2 C1127.2 C1128.2 C1129.2 C1205.2 C1206.2 C1207.2 C1208.2 C1209.2 C1213.2 C1214.2 C1215.2 C1216.2 C1217.2 C1218.2 C1219.2 C1220.2 C1222.2 C1223.2 C1232.2 C1234.2 C1235.2 C1236.2 C1237.2 C1238.2 C1250.2 C1251.2 C1252.2 C1271.2 C1272.2 C1281.2 C1302.2 C1312.2 C1313.2 C1314.2 C1315.2 C1316.2 C1317.2 C1318.2 C1319.2 C1320.2 C1321.2 C1322.2 C1325.2 C1327.2 C1329.2 C1330.2 C1331.2 C1332.2 C1333.2 C1334.2 C1335.2 C1336.2 C1338.2 C1339.2 C1340.2 C1341.2 C1342.2 C1343.2 C1701.2 C1705.2 C1801.2 C1802.2 C1805.2 C1806.2 C1820.2 C1821.2 C1823.2 C1904.2 C2201.2 C2202.2 C2203.2 C2204.2 C2205.2 C2206.2 C2207.2 C2208.2 C2209.2 C2210.2 C2211.2 C2212.2 C2213.2 C2214.2 C2215.2 C2216.2 C2217.2 C2218.2 C2219.2 C2401.1 C2402.2 C2403.2 C2405.2 C2406.2 C2408.2 C2410.2 C2412.1 C2415.2 C2416.2 C2417.2 C2418.1 C2419.2 C2420.2 C2422.2 C2423.2 C2424.2 C2425.2 C2426.2 C2501.2 C2502.2 C2503.2 C2507.2 C2601.2 C2602.2 C2603.2 C2604.2 C2605.2 C2701.2 C2704.1 C2706.2 C2707.2 C2708.2 C2709.2 C2714.2 C2716.2 C2717.2 C2718.2 C2719.1 C2720.2 C2726.2 C2907.2 C2908.2 C2910.2 C2911.2 C3001.2 C3002.2 C3004.2 C3005.2 C3006.2 C3007.2 C3008.2 C3009.2 C3102.2 C3103.2 C3106.2 C3118.2 C3119.2 C3125.2 C3126.1 C3127.1 C3128.2 C3129.2 C3130.2 C3133.2 C3134.2 C3135.2 C3136.2 C3137.2 C3138.2 C3139.2 C3140.2 C3141.2 C3142.2 C3143.2 C3147.2 C3151.2 C3152.2 C3153.2 C3154.2 C3155.2 C3301.2 C3302.1 C3303.2 C3304.2 C3305.2 C3306.2 C3307.2 C3308.2 C3309.1 C3312.1 C3313.1 C3314.1 C3401.2 C3404.2 C3405.2 C3406.2 C3407.2 C3409.2 C3411.2 C3412.2 C3417.2 C3418.2 C3423.2 C3515.2 C3516.2 C3517.2 C3518.2 C3520.2 C3521.2 C3522.2 C3523.2 C3524.2 C3526.2 C4001.2 C4007.2 C4008.2 C4009.2 C4011.2 C4012.2 C4013.2 C4014.2 C4015.2 C4016.2 C4017.2 C4018.2 C4019.2 C4020.2 C4024.2 C4025.2 C4026.2 C4030.2 C4048.2 C4049.2 C4053.2 C4060.2 C4061.2 C4062.2 C4069.2 C4070.2 C4072.2 C4085.1 C4093.2 C4303.2 C4304.2 C4501.2 C4502.2 C5301.2 C5302.2 C5303.2 C5304.2 C5502.2 C5503.2 C5506.2 C5507.1 C5508.1 C5513.1 C5514.1 C5516.1 C5517.1 C5518.1 C5519.1 C5521.1 C5522.1 C5523.1 C5524.1 C5525.1 C5526.1 C5527.2 C5528.2 C5529.1 C5530.1 C5531.1 C5532.1 C5533.1 C5534.1 C5536.2 C5537.2 C5538.2 C5539.2 C5540.2 C5541.2 C5542.2 C5544.2 C5545.2 C5550.2 C5551.2 C5554.2 C5556.2 C5559.2 C5607.2 C5608.2 C5609.2 C5610.2 C5611.2 C5612.2 C5613.2 C5614.2 C5615.2 C5616.2 C5617.2 C5618.2 C5619.2 C5620.2 C5621.2 C5713.2 C5714.2 C5721.2 C5722.2 C6001.2 C6002.2 C6103.2 C6104.2 C6105.2 C6106.2 C6107.2 C6108.2 C6109.2 C6301.2 C6303.2 C6304.2 C6305.2 C6341.2 C6342.2 C6345.2 C6401.2 CAM1.4 CAM1.5 CAM1.9 CAM1.10 CNVBD1.1 CNVBD1.2 CNVBD1.3 CNVBD1.13 CNVBD1.14 CPU1.A3 CPU1.A11 CPU1.A16 CPU1.A17 CPU1.A31 CPU1.A34 CPU1.A36 CPU1.A39 CPU1.A42 CPU1.A44 CPU1.A46 CPU1.A48 CPU1.A49 CPU1.AA45 CPU1.AA47 CPU1.AB3 CPU1.AB5 CPU1.AB6 CPU1.AB11 CPU1.AB38 CPU1.AB39 CPU1.AB41 CPU1.AB42 CPU1.AB43 CPU1.AC45 CPU1.AC49 CPU1.AD10 CPU1.AD11 CPU1.AD34 CPU1.AD37 CPU1.AE6 CPU1.AF37 CPU1.AF45 CPU1.AF47 CPU1.AG1 CPU1.AG3 CPU1.AG5 CPU1.AG9 CPU1.AG11 CPU1.AG38 CPU1.AG39 CPU1.AG41 CPU1.AG42 CPU1.AG43 CPU1.AH2 CPU1.AH37 CPU1.AH45 CPU1.AH49 CPU1.AJ2 CPU1.AJ3 CPU1.AK37 CPU1.AL2 CPU1.AL6 CPU1.AL45 CPU1.AL47 CPU1.AM2 CPU1.AM37 CPU1.AN2 CPU1.AN6 CPU1.AN38 CPU1.AN39 CPU1.AN41 CPU1.AN42 CPU1.AN43 CPU1.AN45 CPU1.AN49 CPU1.AR1 CPU1.AR2 CPU1.AR3 CPU1.AR7 CPU1.AR9 CPU1.AR11 CPU1.AT3 CPU1.AT5 CPU1.AT6 CPU1.AT7 CPU1.AT45 CPU1.AT47 CPU1.AU37 CPU1.AV3 CPU1.AV7 CPU1.AV11 CPU1.AV38 CPU1.AV39 CPU1.AV41 CPU1.AV42 CPU1.AV43 CPU1.AV45 CPU1.AV49 CPU1.AY3 CPU1.AY7 CPU1.B2 CPU1.B3 CPU1.B17 CPU1.B21 CPU1.B24 CPU1.B31 CPU1.B48 CPU1.BA1 CPU1.BA2 CPU1.BA45 CPU1.BA47 CPU1.BB3 CPU1.BB7 CPU1.BB11 CPU1.BC37 CPU1.BD3 CPU1.BD5 CPU1.BD6 CPU1.BD7 CPU1.BD38 CPU1.BD39 CPU1.BD41 CPU1.BD42 CPU1.BD43 CPU1.BD45 CPU1.BD49 CPU1.BE1 CPU1.BE2 CPU1.BF3 CPU1.BF7 CPU1.BF45 CPU1.BF47 CPU1.BG3 CPU1.BG7 CPU1.BG41 CPU1.BH37 CPU1.BJ1 CPU1.BJ2 CPU1.BJ3 CPU1.BJ7 CPU1.BJ41 CPU1.BJ43 CPU1.BJ45 CPU1.BJ49 CPU1.BM3 CPU1.BM5 CPU1.BM6 CPU1.BM7 CPU1.BM11 CPU1.BM45 CPU1.BM47 CPU1.BP1 CPU1.BP2 CPU1.BP3 CPU1.BP7 CPU1.BP43 CPU1.BR45 CPU1.BR49 CPU1.BT3 CPU1.BT7 CPU1.BT39 CPU1.BT41 CPU1.BT42 CPU1.BT43 CPU1.BU45 CPU1.BU47 CPU1.BV1 CPU1.BV2 CPU1.BV3 CPU1.BV7 CPU1.BV11 CPU1.BW3 CPU1.BW5 CPU1.BW6 CPU1.BW7 CPU1.BW37 CPU1.BY37 CPU1.BY45 CPU1.BY49 CPU1.C6 CPU1.C11 CPU1.C13 CPU1.C14 CPU1.C16 CPU1.C17 CPU1.C21 CPU1.C24 CPU1.C31 CPU1.C34 CPU1.C39 CPU1.C48 CPU1.C49 CPU1.CA3 CPU1.CA7 CPU1.CA38 CPU1.CA41 CPU1.CA42 CPU1.CA43 CPU1.CB37 CPU1.CB45 CPU1.CB47 CPU1.CC3 CPU1.CC7 CPU1.CE9 CPU1.CE37 CPU1.CE45 CPU1.CE49 CPU1.CG9 CPU1.CG37 CPU1.CG39 CPU1.CG43 CPU1.CG45 CPU1.CG47 CPU1.CH3 CPU1.CH5 CPU1.CJ9 CPU1.CJ37 CPU1.CJ42 CPU1.CK9 CPU1.CK45 CPU1.CK49 CPU1.CL37 CPU1.CL42 CPU1.CL49 CPU1.CM9 CPU1.CM45 CPU1.CM47 CPU1.CN3 CPU1.CN5 CPU1.CN37 CPU1.CN39 CPU1.CP9 CPU1.CR32 CPU1.CR37 CPU1.CR45 CPU1.CR49 CPU1.CT9 CPU1.CT37 CPU1.CT39 CPU1.CT42 CPU1.CU45 CPU1.CU47 CPU1.CU49 CPU1.CV3 CPU1.CV5 CPU1.CV9 CPU1.CV34 CPU1.CV35 CPU1.CY9 CPU1.CY41 CPU1.CY45 CPU1.CY49 CPU1.D13 CPU1.D17 CPU1.D31 CPU1.D44 CPU1.D49 CPU1.DA9 CPU1.DA10 CPU1.DA33 CPU1.DB32 CPU1.DB35 CPU1.DB38 CPU1.DB45 CPU1.DB47 CPU1.DB49 CPU1.DC3 CPU1.DC5 CPU1.DC6 CPU1.DC49 CPU1.DD37 CPU1.DD42 CPU1.DE6 CPU1.DE10 CPU1.DE13 CPU1.DE15 CPU1.DE17 CPU1.DE18 CPU1.DE20 CPU1.DE22 CPU1.DE23 CPU1.DE26 CPU1.DE28 CPU1.DE29 CPU1.DE33 CPU1.DE45 CPU1.DF13 CPU1.DF22 CPU1.DF28 CPU1.DF33 CPU1.DF35 CPU1.DF39 CPU1.DG6 CPU1.DG10 CPU1.DG12 CPU1.DG13 CPU1.DG15 CPU1.DG22 CPU1.DG23 CPU1.DG47 CPU1.DH1 CPU1.DH3 CPU1.DH5 CPU1.DH45 CPU1.DJ19 CPU1.DJ21 CPU1.DJ27 CPU1.DJ31 CPU1.DJ33 CPU1.DJ36 CPU1.DJ42 CPU1.DK3 CPU1.DK4 CPU1.DK6 CPU1.DK8 CPU1.DK49 CPU1.DL10 CPU1.DL13 CPU1.DL44 CPU1.DL47 CPU1.DM47 CPU1.DN15 CPU1.DN19 CPU1.DN24 CPU1.DN31 CPU1.DN36 CPU1.DN42 CPU1.DP45 CPU1.DR49 CPU1.DT1 CPU1.DT3 CPU1.DT6 CPU1.DT7 CPU1.DT8 CPU1.DT10 CPU1.DT15 CPU1.DT20 CPU1.DT27 CPU1.DT32 CPU1.DT37 CPU1.DT42 CPU1.DT49 CPU1.DU1 CPU1.DU2 CPU1.DU7 CPU1.DU10 CPU1.DU15 CPU1.DU20 CPU1.DU27 CPU1.DU32 CPU1.DU37 CPU1.DU47 CPU1.DU48 CPU1.DU49 CPU1.DV2 CPU1.DV8 CPU1.DV44 CPU1.DV48 CPU1.DW1 CPU1.DW2 CPU1.DW7 CPU1.DW10 CPU1.DW20 CPU1.DW27 CPU1.DW44 CPU1.DW46 CPU1.DW48 CPU1.DW49 CPU1.E6 CPU1.E11 CPU1.E34 CPU1.E36 CPU1.E39 CPU1.E42 CPU1.F8 CPU1.F11 CPU1.F31 CPU1.F45 CPU1.F47 CPU1.G3 CPU1.G5 CPU1.G21 CPU1.G24 CPU1.G31 CPU1.G36 CPU1.G49 CPU1.H17 CPU1.H21 CPU1.H24 CPU1.H31 CPU1.H33 CPU1.H36 CPU1.H45 CPU1.H49 CPU1.J6 CPU1.J10 CPU1.J13 CPU1.J15 CPU1.J16 CPU1.J36 CPU1.K8 CPU1.K11 CPU1.K15 CPU1.K33 CPU1.L36 CPU1.L39 CPU1.L41 CPU1.L42 CPU1.L43 CPU1.L45 CPU1.L47 CPU1.M3 CPU1.M5 CPU1.M10 CPU1.M36 CPU1.N45 CPU1.N49 CPU1.P8 CPU1.P11 CPU1.P41 CPU1.R3 CPU1.R37 CPU1.T11 CPU1.T36 CPU1.T41 CPU1.T43 CPU1.T45 CPU1.T47 CPU1.U3 CPU1.U5 CPU1.U37 CPU1.V9 CPU1.V11 CPU1.V36 CPU1.V45 CPU1.V49 CPU1.W37 CPU1.Y9 CPU1.Y36 CPU1.Y38 CPU1.Y43 CRS1.3 CRS1.6 CRS1.12 CRS1.13 D2401.3 D2402.3 D2403.3 D2701.3 D3102.1 D6301.2 D6903.2 D6904.2 DBGH1.3 DBGH1.15 DBGH1.16 DCIN1.1 DCIN1.2 DIMM1.1 DIMM1.2 DIMM1.5 DIMM1.6 DIMM1.9 DIMM1.10 DIMM1.14 DIMM1.15 DIMM1.18 DIMM1.19 DIMM1.22 DIMM1.23 DIMM1.26 DIMM1.27 DIMM1.30 DIMM1.31 DIMM1.35 DIMM1.36 DIMM1.39 DIMM1.40 DIMM1.43 DIMM1.44 DIMM1.47 DIMM1.48 DIMM1.51 DIMM1.52 DIMM1.56 DIMM1.57 DIMM1.60 DIMM1.61 DIMM1.64 DIMM1.65 DIMM1.68 DIMM1.69 DIMM1.72 DIMM1.73 DIMM1.77 DIMM1.78 DIMM1.81 DIMM1.82 DIMM1.85 DIMM1.86 DIMM1.89 DIMM1.90 DIMM1.93 DIMM1.94 DIMM1.98 DIMM1.99 DIMM1.102 DIMM1.103 DIMM1.106 DIMM1.107 DIMM1.166 DIMM1.167 DIMM1.168 DIMM1.171 DIMM1.172 DIMM1.175 DIMM1.176 DIMM1.180 DIMM1.181 DIMM1.184 DIMM1.185 DIMM1.188 DIMM1.189 DIMM1.192 DIMM1.193 DIMM1.196 DIMM1.197 DIMM1.201 DIMM1.202 DIMM1.205 DIMM1.206 DIMM1.209 DIMM1.210 DIMM1.213 DIMM1.214 DIMM1.217 DIMM1.218 DIMM1.222 DIMM1.223 DIMM1.226 DIMM1.227 DIMM1.230 DIMM1.231 DIMM1.234 DIMM1.235 DIMM1.238 DIMM1.239 DIMM1.243 DIMM1.244 DIMM1.247 DIMM1.248 DIMM1.251 DIMM1.252 DIMM1.256 DIMM1.260 DIMM1.261 DIMM1.262 DIMM2.1 DIMM2.2 DIMM2.5 DIMM2.6 DIMM2.9 DIMM2.10 DIMM2.14 DIMM2.15 DIMM2.18 DIMM2.19 DIMM2.22 DIMM2.23 DIMM2.26 DIMM2.27 DIMM2.30 DIMM2.31 DIMM2.35 DIMM2.36 DIMM2.39 DIMM2.40 DIMM2.43 DIMM2.44 DIMM2.47 DIMM2.48 DIMM2.51 DIMM2.52 DIMM2.56 DIMM2.57 DIMM2.60 DIMM2.61 DIMM2.64 DIMM2.65 DIMM2.68 DIMM2.69 DIMM2.72 DIMM2.73 DIMM2.77 DIMM2.78 DIMM2.81 DIMM2.82 DIMM2.85 DIMM2.86 DIMM2.89 DIMM2.90 DIMM2.93 DIMM2.94 DIMM2.98 DIMM2.99 DIMM2.102 DIMM2.103 DIMM2.106 DIMM2.107 DIMM2.166 DIMM2.167 DIMM2.168 DIMM2.171 DIMM2.172 DIMM2.175 DIMM2.176 DIMM2.180 DIMM2.181 DIMM2.184 DIMM2.185 DIMM2.188 DIMM2.189 DIMM2.192 DIMM2.193 DIMM2.196 DIMM2.197 DIMM2.201 DIMM2.202 DIMM2.205 DIMM2.206 DIMM2.209 DIMM2.210 DIMM2.213 DIMM2.214 DIMM2.217 DIMM2.218 DIMM2.222 DIMM2.223 DIMM2.226 DIMM2.227 DIMM2.230 DIMM2.231 DIMM2.234 DIMM2.235 DIMM2.238 DIMM2.239 DIMM2.243 DIMM2.244 DIMM2.247 DIMM2.248 DIMM2.251 DIMM2.252 DIMM2.256 DIMM2.261 DIMM2.262 EC1720.2 EC1801.2 EC1802.2 EC2902.2 EC2903.2 EC2904.2 EC2905.2 EC3101.2 EC3102.2 EC3103.2 EC3104.2 EC3105.2 EC3106.2 EC3107.2 EC3108.2 EC3321.2 EC3322.2 EC3323.2 EC3324.2 EC3325.2 EC3326.2 EC3327.2 EC3328.2 EC4301.2 EC4302.2 EC5501.2 EC5502.2 EC5503.2 EC6401.2 EC6402.2 EC6901.2 EC6902.2 EC6903.2 EC6904.2 EC6905.2 EC6906.2 EC6907.2 EC6908.2 EC6909.2 EC6910.2 EC6913.2 EC6914.2 EC6915.2 EC6916.2 EC6917.2 EC6918.2 EC6919.2 EC6920.2 EC6921.2 EC6922.2 EC6923.2 ECIO1.6 ECIO1.35 ECIO1.71 ED2901.3 ED2902.3 ED2903.3 ED2904.3 ED2905.3 ED3002.2 ED3101.1 ED3102.1 ED3103.1 ED3401.2 ED3402.3 ED3402.8 ED3403.3 ED3403.8 ED3501.3 ED3501.8 ED3502.2 ED3504.3 ED3504.8 ED3505.2 ED4301.A ED5701.3 ED5701.8 ED5702.3 ED5702.8 ED5703.2 ED6001.3 ED6001.8 ED6101.2 ED6902.1 FANC1.3 FANC1.4 FANC1.5 FC9001.2 FC9002.2 FC9003.2 FC9004.2 FC9005.2 FC9006.2 FC9007.2 FC9008.2 FC9009.2 FC9010.2 FC9011.2 FC9012.2 FC9085.2 FC9086.2 FC9087.2 FC9088.2 FC9089.2 FC9090.2 FC9091.2 FC9092.2 G2530.2 GDT1.1 H1.1 H1.2 H1.3 H1.4 H1.5 H1.6 H1.7 H1.8 H2.1 H2.2 H2.3 H2.4 H2.5 H2.6 H2.7 H2.8 H3.1 H3.2 H3.3 H3.4 H3.5 H3.6 H3.7 H3.8 H4.1 H4.2 H4.3 H4.4 H4.5 H4.6 H4.7 H4.8 H5.1 H5.2 H5.3 H5.4 H5.5 H5.6 H5.7 H5.8 HDMI1.2 HDMI1.5 HDMI1.8 HDMI1.11 HDMI1.17 HDMI1.20 HDMI1.21 HDMI1.22 HS5.1 HS6.1 HS7.1 LAN1.33 LED1.3 LVDS1.7 LVDS1.14 LVDS1.17 LVDS1.24 LVDS1.31 LVDS1.32 MFG1.4 MFG1.5 MFG1.6 MFG1.7 NGFFE1.1 NGFFE1.7 NGFFE1.13 NGFFE1.18 NGFFE1.19 NGFFE1.33 NGFFE1.39 NGFFE1.45 NGFFE1.51 NGFFE1.57 NGFFE1.63 NGFFE1.69 NGFFE1.75 NGFFE1.76 NGFFE1.77 NGFFM1.1 NGFFM1.3 NGFFM1.9 NGFFM1.15 NGFFM1.21 NGFFM1.27 NGFFM1.33 NGFFM1.39 NGFFM1.45 NGFFM1.51 NGFFM1.57 NGFFM1.71 NGFFM1.73 NGFFM1.75 NGFFM1.76 NGFFM1.77 PC1002.2 PC1003.2 PC1004.2 PC1005.2 PC1006.2 PC1007.2 PC1008.2 PC1009.2 PC1010.2 PC1011.2 PC1012.2 PC1013.2 PC1014.2 PC1026.2 PC1027.2 PC1028.2 PC1029.2 PC1030.2 PC1031.2 PC1032.2 PC1042.2 PC1043.2 PC1044.2 PC1045.2 PC1046.2 PC1047.2 PC1048.2 PC1049.2 PC1050.2 PC1051.2 PC1052.2 PC1053.2 PC1054.2 PC1055.2 PC1056.2 PC1057.2 PC1058.2 PC1059.2 PC4302.2 PC4501.2 PC4502.2 PC4503.2 PC4504.2 PC4505.2 PC4506.2 PC4507.2 PC4508.2 PC4509.2 PC4510.2 PC4511.2 PC4514.2 PC4515.2 PC4516.2 PC4517.2 PC4602.2 PC4603.2 PC4605.2 PC4606.2 PC4608.1 PC4609.2 PC4611.2 PC4624.1 PC4701.2 PC4702.2 PC4703.2 PC4704.2 PC4705.2 PC4706.2 PC4707.2 PC4708.2 PC4709.2 PC4710.2 PC5001.2 PC5002.2 PC5004.2 PC5006.2 PC5007.2 PC5008.2 PC5013.1 PC5101.2 PC5102.2 PC5103.2 PC5104.2 PC5105.2 PC5106.2 PC5107.2 PC5108.2 PC5109.2 PC5110.2 PC5113.2 PC5114.2 PC5115.2 PC5116.2 PC5117.1 PC5118.1 PC5119.1 PC5120.1 PC5121.1 PC5122.1 PC5201.2 PC5202.2 PC5203.2 PC5205.2 PC5206.2 PC5207.2 PC5301.2 PC5302.2 PC5303.2 PC5305.2 PC5306.2 PC5307.2 PC5308.2 PC5313.2 PC5314.2 PC5315.2 PC5316.2 PC5401.1 PC5402.1 PC5403.1 PC5406.1 PC5407.1 PC5410.2 PC5411.2 PC5412.2 PR4302.2 PR4303.2 PR4304.2 PR4503.2 PR4504.2 PR4507.2 PR4508.2 PR4637.1 PR4644.2 PR4659.2 PR4667.2 PR4668.2 PR4669.2 PR5004.1 PR5006.2 PR5018.2 PR5106.2 PR5116.2 PR5201.2 PR5303.2 PR5304.2 PR5407.2 PT4501.2 PT4502.2 PT4701.2 PT4703.2 PT5001.2 PT5002.2 PU4503.21 PU4504.1 PU4504.2 PU4504.3 PU4505.1 PU4505.2 PU4505.3 PU4601.33 PU4701.5 PU4701.6 PU4701.7 PU4702.5 PU4702.6 PU4702.7 PU4703.5 PU4703.6 PU4703.7 PU4704.5 PU4704.6 PU4704.7 PU5001.14 PU5001.21 PU5003.1 PU5003.2 PU5003.3 PU5004.1 PU5004.2 PU5004.3 PU5102.1 PU5102.2 PU5102.3 PU5103.1 PU5103.3 PU5103.14 PU5103.21 PU5201.1 PU5301.4 PU5301.12 PU5301.13 PU5301.14 PU5301.15 PU5301.19 PU5401.9 PU5401.12 PU5401.17 PWRBT1.2 PWRBT1.4 Q2401.S Q2402.S Q2403.1 Q2403.4 Q2404.S Q2501.S Q3401.1 Q3401.4 Q3402.S Q4001.1 Q4001.4 Q4004.1 Q4004.4 Q4006.1 Q4006.4 Q4007.S Q4009.4 Q4012.1 Q4012.4 Q4013.E Q4301.S Q4308.S Q5702.S Q6805.S R301.1 R309.1 R310.1 R313.1 R401.1 R403.1 R505.1 R506.1 R507.1 R605.1 R607.1 R705.1 R1215.2 R1306.2 R1502.2 R1511.2 R1512.2 R1513.2 R1514.2 R1516.2 R1517.2 R1521.2 R1523.2 R1525.2 R1527.2 R1529.2 R1533.2 R1534.2 R1602.2 R1603.2 R1604.2 R1706.2 R1726.2 R1728.1 R1729.1 R1730.2 R1746.2 R1818.2 R1819.2 R1821.2 R1833.2 R1839.1 R1840.1 R1841.1 R1842.1 R1843.1 R1844.1 R1902.2 R1903.2 R2101.2 R2102.2 R2103.1 R2209.2 R2210.2 R2511.2 R2514.2 R2531.2 R2601.1 R2607.2 R2702.1 R2703.1 R2704.1 R2705.1 R2706.1 R2730.2 R2909.1 R2922.1 R2923.1 R2924.1 R3102.1 R3161.2 R3301.1 R3311.2 R3404.2 R4012.2 R4038.2 R4057.1 R4321.2 R4326.1 R5502.1 R5531.2 R5538.2 R5539.2 R5602.2 R5606.2 R5610.2 R5612.2 R5618.2 R5619.2 R5620.2 R5622.2 R5623.2 R5624.2 R5730.2 R6119.2 R6120.2 R6308.2 R6410.2 R6802.2 R6807.2 R24011.2 R24029.2 R24055.2 R24062.2 R24065.2 R24091.2 R24097.2 R24110.2 R24111.2 RC4502.2 RJ1.13 RN1201.2 RN1301.2 SATA1.23 SATA1.24 SATA1.P4 SATA1.P5 SATA1.P6 SATA1.P10 SATA1.P11 SATA1.P12 SATA1.S1 SATA1.S4 SATA1.S7 SPK1.5 SPK1.6 TSMT1.6 TSMT1.16 TSMT1.49 U2401.4 U2501.4 U2504.4 U2601.5 U2601.6 U2601.7 U2601.8 U2701.49 U3101.2 U3102.2 U3103.2 U3301.24 U3301.25 U3401.2 U3402.2 U3503.2 U3504.2 U4003.11 U4003.15 U4007.5 U4009.3 U4010.5 U4011.5 U4012.5 U4013.3 U4020.3 U4303.1 U4303.2 U5301.5 U5501.20 U5504.2 U5602.1 U5602.2 U5602.4 U5602.7 USB3R1.4 USB3R1.7 USB3R1.10 USB3R1.11 USB3R2.4 USB3R2.7 USB3R2.10 USB3R2.11 USB3R3.4 USB3R3.7 USB3R3.10 USB3R3.11 USB3R4.4 USB3R4.7 USB3R4.10 USB3R4.11 X1802.2 X1802.4 X3101.2 X3101.4
V12: SATA1.P13 SATA1.P14 SATA1.P15
V33: SATA1.P1 SATA1.P2 SATA1.P3
VCCAUX_SENSE: CPU1.BF9 PC5013.2 PR5016.2 PR5017.2
VCCCORE_SENSE: CPU1.F17 PR4671.2 R704.2
VCCIN_AUX_VID0: CPU1.CL38 D4005.1 PR5035.1 RN2201.3(B)
VCCIN_AUX_VID1: CPU1.CJ38 D4005.2 PR5034.1 RN2201.4
VCCPLL_OC: C4015.1 R4016.1 U4007.6 U4007.7 U4007.8
VCCST_EN: D4004.3 D4005.3 R4054.2
VCCST_OVERRIDE: D4004.1 Q4004.6 R4052.2
VCCST_OVERRIDE_N: Q4004.2 Q4004.3 R4053.2
VCCST_PWRGD: CPU1.CF2 R4005.2
VCCST_PWRGD_R: R4004.1 R4005.1 U4013.4
VCCSTPWRGOOD_TCSS: CPU1.CE3 CPU1.CE4 Q4004.5 R4057.2
VDDQ_EN: PC5207.1 PR5113.1 R5206.1 R24053.2 U4020.4
VDDQ_EN_EC: ECIO1.55 R24053.1
VSSAUX_SENSE: CPU1.BD9 PR5018.1 PU5001.7
VSSCORE_SENSE: CPU1.G17 PR4672.2 R705.2
0D6V_VREF_S0: C1234.1 C1250.1 C1251.1 C1252.1 C1319.1 C1320.1 C1321.1 C1322.1 DIMM1.258 DIMM2.258 PG5104.1
0D85V_S5_VCCLDOSTD_OUT: C2213.1 CPU1.DW37
1D2V_EDP: C5617.1 C5618.1 C5619.1 C5620.1 R5607.2 TSMT1.11 TSMT1.15 TSMT1.43
1D2V_EDP_SWR: R5607.1 TSMT1.17
1D2V_S3: C1102.1 C1103.1 C1104.1 C1105.1 C1106.1 C1107.1 C1109.1 C1110.1 C1111.1 C1112.1 C1113.1 C1116.1 C1117.1 C1118.1 C1128.1 C1129.1 C1205.1 C1206.1 C1207.1 C1208.1 C1209.1 C1213.1 C1214.1 C1215.1 C1216.1 C1217.1 C1218.1 C1219.1 C1220.1 C1222.1 C1223.1 C1237.1 C1312.1 C1313.1 C1314.1 C1315.1 C1316.1 C1317.1 C1318.1 C1327.1 C1329.1 C1330.1 C1331.1 C1332.1 C1333.1 C1334.1 C1335.1 C1336.1 C4016.1 CPU1.AA37 CPU1.AA49 CPU1.AB36 CPU1.AC35 CPU1.AC37 CPU1.AD35 CPU1.AD36 CPU1.AE36 CPU1.AF49 CPU1.AG36 CPU1.AJ36 CPU1.AL36 CPU1.AL49 CPU1.AN36 CPU1.AP37 CPU1.AR36 CPU1.AR37 CPU1.AT36 CPU1.AT49 CPU1.AV36 CPU1.AW37 CPU1.AY36 CPU1.BA37 CPU1.BA49 CPU1.BB36 CPU1.BD36 CPU1.BE37 CPU1.BF36 CPU1.BF37 CPU1.BF49 CPU1.BG36 CPU1.BJ36 CPU1.BL37 CPU1.BM49 CPU1.BN37 CPU1.BP38 CPU1.BP39 CPU1.BR37 CPU1.BT38 CPU1.BU37 CPU1.BU49 CPU1.CA39 CPU1.CB49 CPU1.L38 CPU1.L49 CPU1.N36 CPU1.T49 DIMM1.12 DIMM1.33 DIMM1.54 DIMM1.75 DIMM1.96 DIMM1.111 DIMM1.112 DIMM1.117 DIMM1.118 DIMM1.123 DIMM1.124 DIMM1.129 DIMM1.130 DIMM1.135 DIMM1.136 DIMM1.141 DIMM1.142 DIMM1.147 DIMM1.148 DIMM1.153 DIMM1.154 DIMM1.159 DIMM1.160 DIMM1.163 DIMM1.178 DIMM1.199 DIMM1.220 DIMM1.241 DIMM2.12 DIMM2.33 DIMM2.54 DIMM2.75 DIMM2.96 DIMM2.111 DIMM2.112 DIMM2.117 DIMM2.118 DIMM2.123 DIMM2.124 DIMM2.129 DIMM2.130 DIMM2.135 DIMM2.136 DIMM2.141 DIMM2.142 DIMM2.147 DIMM2.148 DIMM2.153 DIMM2.154 DIMM2.159 DIMM2.160 DIMM2.163 DIMM2.178 DIMM2.199 DIMM2.220 DIMM2.241 FC9085.1 FC9086.1 FC9087.1 FC9088.1 FC9089.1 FC9090.1 FC9091.1 FC9092.1 PC5103.1 PC5117.2 PC5118.2 PC5119.2 PC5120.2 PC5121.2 PC5122.2 PG5103.1 PL5101.2 PR5120.2 R510.1 R1231.1 R1303.1 R24020.1 RN1201.1 RN1301.1 U4007.1 U4007.2 U4007.9
1D2V_VCCPLL_OC: C1114.1 C1115.1 CPU1.CG38 CPU1.CG41 CPU1.CG42 CPU1.CG49 R4016.2
1D05V_LAN: C3106.1 C3137.1 C3138.1 C3139.1 C3140.1 C3141.1 C3142.1 C3147.1 L3101.2 LAN1.3 LAN1.8 LAN1.22 LAN1.30 R3103.2
1D05V_LAN_OUT: L3101.1 LAN1.24 R3103.1
1D05V_S5_BYPASS: CPU1.DJ15 PG5402.1 R2209.1
1D05V_S5_OUT: C2208.1 C4085.2 C4093.1 CPU1.BY2 CPU1.CB2 CPU1.CC1 U4010.1 U4010.2 U4010.9 U4011.1 U4011.2 U4011.9
1D05V_S5_VCCDSW_OUT: C2204.1 CPU1.DD34
1D05V_S5_VCCPRIM_OUT: C2203.1 CPU1.DF29 CPU1.DF31 CPU1.DG29 CPU1.DG31
1D05V_VCCIO_OUT: CPU1.AD7 R606.2 TP808.1
1D05V_VCCPLL: C1119.1 C1120.1 CPU1.CD1 CPU1.CD2
1D05V_VCCST: C1121.1 C1122.1 C4018.1 C4053.1 CPU1.CB1 PG4601.1 R302.1 R702.1 R707.1 R708.1 R4004.2 U4011.6 U4011.7 U4011.8
1D05V_VCCST_EN: C4062.1 R4054.1 U4011.4
1D05V_VCCSTG: C1126.1 C1127.1 C4019.1 C4060.1 CPU1.BY1 U4010.6 U4010.7 U4010.8
1D05V_VCCSTG_EN: C4061.1 R4006.1 R4034.1 R4047.1 U4007.4 U4010.4
1D05V_VCCSTG_EN_R: R4047.2 U4009.4
1D05V_VCCSTG_OUT_FUSE: CPU1.F33 CPU1.G33 R808.2
1D05V_VCCSTG_OUT_FUSE_R: C1125.1 CPU1.AB34 CPU1.R35 CPU1.T34 CPU1.U35 CPU1.V34 R808.1
1D05V_VCCSTG_OUT_LGC: CPU1.E5 R809.1
1D05V_VCCSTG_TERM: R306.1 R311.1 R312.1 R809.2 RN303.1 RN303.2
1D05V_VNN_BYPASS: CPU1.CY34 PG5401.1 R2210.1
1D8V_AUDIO_S0: C2715.1 R2701.2 R2766.1 R2767.2 U2701.40
1D8V_FCH_C10: C1101.1 C1108.1 C4020.1 C4070.1 CPU1.BG9 CPU1.BJ9 CPU1.BM9 CPU1.BW1 CPU1.BW2 U4012.6 U4012.7 U4012.8
1D8V_FCH_C10_EN: C4072.1 R4051.1 U4012.4
1D8V_S0: C5303.1 C5304.1 R2108.1 R2766.2 U5301.6 U5301.7 U5301.8
1D8V_S0_EN: C5302.1 R5301.2 U5301.4
1D8V_S5: C2210.1 C2211.1 C2212.1 C2410.1 C2420.1 C4069.1 C5301.1 CPU1.DD35 CPU1.DF15 CPU1.DF17 CPU1.DF18 CPU1.DF20 CPU1.DF34 CPU1.DG17 CPU1.DG18 CPU1.DG20 ECIO1.34 PG5304.2 PG5305.2 PG5318.2 PG5320.2 Q1904.2 Q1904.5 R1507.1 R1530.1 R2104.2 R2105.2 R2204.1 R2767.1 R6160.2 R24116.2 RN1914.1 RN1914.2 U4012.1 U4012.2 U4012.9 U5301.1 U5301.2 U5301.9
1D8V_S5_CLKLDO: C2215.1 CPU1.DW15 R2204.2 R2206.1
1D8V_S5_CLKLDO_R: C2216.1 R2206.2
1D8V_S5_PWRGD: PR5052.1 PR5317.1 PR5326.1
1D8V_VCCIN_AUX: C2217.1 C2218.1 C2219.1 CPU1.AH1 CPU1.AJ1 CPU1.AL1 CPU1.AM1 CPU1.AN1 CPU1.AT9 CPU1.AT11 CPU1.AU10 CPU1.AV9 CPU1.AW10 CPU1.AY9 CPU1.AY11 CPU1.BA10 CPU1.BB9 CPU1.CH1 CPU1.CK11 CPU1.CL10 CPU1.CM11 CPU1.CN1 CPU1.CN10 CPU1.CP11 CPU1.CR10 CPU1.CT11 CPU1.CU10 CPU1.CV1 CPU1.CV11 CPU1.CW10 CPU1.CY11 CPU1.DC1 CPU1.DC11 CPU1.DE12 CPU1.DF12 CPU1.P13 CPU1.R12 CPU1.T13 CPU1.U12 FC9007.1 FC9008.1 FC9009.1 FC9010.1 FC9011.1 FC9012.1 PC1042.1 PC1043.1 PC1044.1 PC1045.1 PC1046.1 PC1047.1 PC1048.1 PC1049.1 PC1050.1 PC1051.1 PC1052.1 PC1053.1 PC1054.1 PC1055.1 PC1056.1 PC1057.1 PC1058.1 PC1059.1 PG5006.1 PL5001.2 PR5017.1 PT5001.1
1D24V_S5_VCCDPHY_OUT: C2205.1 CPU1.DW32
2D5V_S3: C1232.1 C1235.1 C1236.1 C1238.1 C1340.1 C1341.1 C1342.1 C1343.1 DIMM1.257 DIMM1.259 DIMM2.257 DIMM2.259 PG5201.2 PG5203.2
2D5V_S3_EN: PR5204.1 Q4013.C R24042.2 RN4001.3(B)
2D5V_S3_EN_EC: ECIO1.56 R24042.1
2D5V_S3_PWRGD: PR5202.2 PU5201.7 R5206.2 U4020.2
3D3V_AUDIO_S0: C2716.1 C2717.1 C2719.2 C2720.1 R2709.2 R2721.2 R2758.2 R2759.2 U2701.1 U2701.9
3D3V_AUX_S5: C2406.1 C2408.1 C2416.1 C2426.1 D2401.1 D2402.1 D2403.2 ECIO1.3 ECIO1.32 ECIO1.64 L2401.2 PG4532.1 PR4509.1 R2519.2 R2710.2 R5522.1 R5523.1 R5524.1 R6408.2 R24006.1 R24030.2 R24035.1 R24045.1 R24056.2 R24060.1 R24072.2 R24076.1 R24086.1 R24088.2 R24095.2 R24104.1 R24109.1 R24115.1 RN2402.3(B) RN2402.4 RN2404.3(B) RN2404.4 U2401.8
3D3V_CAM: C3004.1 C3005.1 CAM1.8 ED3002.5 F3001.2
3D3V_CAM_R: F3001.1 R3005.2 R3006.2
3D3V_CARD: R3302.1 U3301.7
3D3V_CARD_C: C3309.2 C3312.2 C3313.2 C3314.2 CRS1.4 R3302.2 R3311.1
3D3V_DB1: DBGH1.10 R6810.1
3D3V_DMIC_R: F3002.1 R3008.2
3D3V_EDP_VDDIO: C5608.1 C5609.1 C5610.1 L5601.2 R5611.2 R5613.1 R5614.1 R5617.2 TSMT1.5 U5602.3 U5602.8
3D3V_EDP_VDDIOX: C5611.1 C5612.1 C5613.1 C5614.1 C5615.1 C5616.1 L5602.2 TSMT1.18 TSMT1.22
3D3V_LAN: C3118.1 C3119.1 C3129.1 C3130.1 C3133.1 C3134.1 C3135.1 C3136.1 C3143.1 C3153.1 D3102.2 ED3101.2 ED3102.2 ED3103.2 LAN1.11 LAN1.32 Q3111.G R3107.2 R3135.2 R3138.2 R3139.2 R3143.2 R3144.2 R3154.2 U3101.5 U3102.5 U3103.1
3D3V_LAN_EN: C3154.1 R3106.2 U3103.4
3D3V_LAN_VDDREG: C3102.1 C3103.1 LAN1.23 R3135.1
3D3V_MAIN_MSSD: C3303.1 C3304.1 C3305.1 C3306.1 C3307.1 C3308.1 L3302.2 U3301.5 U3301.6 U3301.8
3D3V_RTC_AUX: C2206.1 C2207.1 C2507.1 CPU1.DG33 D2501.3 R1704.1 R24004.2 RN1804.1 RN1804.2
3D3V_RTC_PWR: D2501.2 Q2501.G R2510.2 R2511.1
3D3V_RTC_VCC: BTT1.1 R2510.1
3D3V_S0: C1271.1 C1272.1 C1338.1 C1339.1 C4014.1 C4049.1 C6303.1 C6304.1 C6305.1 C6341.1 C6342.1 C6345.1 DIMM1.255 DIMM2.255 L3302.1 NGFFM1.2 NGFFM1.4 NGFFM1.12 NGFFM1.14 NGFFM1.16 NGFFM1.18 NGFFM1.70 NGFFM1.72 NGFFM1.74 PR4607.1 Q1801.2 Q1801.5 Q5701.2 Q5701.5 Q5705.G R1302.1 R1605.2 R1701.1 R1712.1 R1812.1 R1813.1 R2001.1 R2002.1 R2041.2 R2603.1 R2758.1 R3005.1 R3008.1 R3116.1 R3160.1 R4002.1 R4033.1 R4044.2 R5301.1 R5505.1 R5732.1 R6305.2 R6806.2 R6810.2 R24001.2 R24003.2 R24021.2 R24054.2 R24069.2 R24079.2 R24107.2 R24112.1 RN1810.3(B) RN1810.4 RN1915.1 RN1915.2 RN2403.3(B) RN2403.4 RN2405.3(B) RN2405.4 RN4002.1 RN4002.2 RN5702.3(B) RN5702.4 U4003.8 U4003.9
3D3V_S5: C2201.1 C2202.1 C2209.1 C2214.1 C2501.1 C2502.1 C3006.1 C3007.1 C3155.1 C4012.1 C4025.1 C4030.1 C5607.1 C6104.1 C6105.1 C6106.1 C6107.1 C6108.1 C6109.1 CPU1.DC33 CPU1.DE31 CPU1.DF23 CPU1.DF26 CPU1.DG26 CPU1.DG28 D4302.1 ED6101.5 L5601.1 L5602.1 NGFFE1.2 NGFFE1.4 NGFFE1.72 NGFFE1.74 PG4501.1 PG4502.1 PG4508.1 PG4509.1 PG4513.1 PG4514.1 PG4520.1 PG5202.2 PG5204.2 PR4510.1 PR5003.2 PR5110.1 PR5202.1 PR5325.1 PR5327.1 PR5420.1 PR5421.1 Q6402.G Q6801.S Q6803.S R1501.1 R1503.1 R1504.1 R1505.1 R1506.1 R1508.1 R1518.1 R1519.1 R1520.1 R1522.1 R1524.1 R1526.1 R1528.1 R1531.1 R1532.2 R1606.2 R1608.2 R1705.1 R1713.1 R1714.2 R1715.2 R1716.2 R1717.2 R1718.1 R1732.2 R1915.2 R2003.2 R2021.1 R2023.1 R2031.1 R2201.2 R2208.1 R2508.1 R2759.1 R3006.1 R3106.1 R3107.1 R4003.1 R4026.1 R4052.1 R4053.1 R4331.2 R5518.2 R6112.2 R6310.1 R6403.1 R24013.1 R24014.2 R24017.2 R24026.2 R24028.2 R24038.2 R24039.2 R24044.2 R24048.2 R24049.2 R24059.2 R24063.2 R24066.2 R24071.2 R24075.2 R24078.2 R24084.1 R24099.2 R24100.1 R24101.1 R24108.2 R24117.2 R24118.2 R24121.2 RN1811.3(B) RN1811.4 RN1812.5(B) RN1812.6 RN1812.7 RN1812.8 RN2201.1 RN2201.2 RN4001.1 RN4001.2 RN6119.3(B) RN6119.4 RN6120.3(B) RN6120.4 U2501.8 U2504.8 U3103.5 U4003.6 U4003.7 U4009.5 U4013.5 U4020.5
3D3V_S5_SPI: CPU1.DB34 R2208.2
3D3V_SB_RTC: C2503.1 D2501.1 R2514.1 R2519.1
3D3V_SB_SYS: D2402.2 ECIO1.67 R24026.1
3D3V_SIO_AVCC3: C2405.1 C2425.1 ECIO1.96 L2401.1
3D3V_VBAT_SIO: C2419.1 ECIO1.66 R24004.1
65W_OCP: ECIO1.17 Q4308.G R4331.1
AC_PRESENT: CPU1.DE46 R1713.2
ALL_SYS_PWRGD: Q4001.3 R4013.1 R4036.2 R4037.2 U4013.2
AUD_AGND: C2702.1 C2705.1 C2710.2 C2711.2 C2712.1 C2713.2 C2715.2 C2907.1 C2908.1 C2910.1 C2911.1 EC2909.2 EC2910.2 EC2911.2 EC2912.2 EC2913.2 R2702.2 R2703.2 R2704.2 R2705.2 R2706.2 R2711.1 R2733.2 R2902.2 R2909.2 R2922.2 R2923.2 R2924.2 U2701.25 U2701.38
AUD_HP1_JACK_L1: AUDS1.1 EC2912.1 ED2903.1 L2903.2
AUD_HP1_JACK_L2: C2723.2 R2904.1 RN2703.2 U2701.32
AUD_HP1_JACK_L2_R: L2903.1 R2904.2
AUD_HP1_JACK_R1: AUDS1.2 EC2910.1 ED2903.2 L2910.2
AUD_HP1_JACK_R2: C2724.2 R2905.1 RN2703.1 U2701.33
AUD_HP1_JACK_R2_R: L2910.1 R2905.2
AUD_HP1_JD#: AUDS1.6 EC2911.1 ED2904.1 R2713.2
AUD_HP1_JD#_TYPE: AUDS1.5 ED2904.2 R2902.1
AUD_SENSE_A: R2709.1 R2713.1 U2701.13
AUD_SPK_L+: ED2901.1 L2904.1 U2701.42
AUD_SPK_L+_CON: EC2902.1 L2904.2 SPK1.1
AUD_SPK_L-: ED2901.2 L2905.1 U2701.43
AUD_SPK_L-_CON: EC2903.1 L2905.2 SPK1.2
AUD_SPK_R+: ED2902.1 L2906.1 U2701.45
AUD_SPK_R+_CON: EC2904.1 L2906.2 SPK1.3
AUD_SPK_R-: ED2902.2 L2907.1 U2701.44
AUD_SPK_R-_CON: EC2905.1 L2907.2 SPK1.4
AUDIO_PC_BEEP: C2725.2 R2730.1 R2778.1
AUDIO_PC_BEEP255: R2732.1 U2701.12
AUDIO_PC_BEEP256: R2731.1 U2701.16
AUDIO_PC_BEEP_R: C2725.1 R2731.2 R2732.2
AUDIO_VREF: C2705.2 U2701.28
BIOS_REC: CPU1.DK29 R2108.2
BKLT_ADJ: R5510.1 R5511.2 R5512.1
BKLT_ADJ_PWM: C5515.1 R5511.1 R5515.1 U5501.5
BKLT_EN: C5506.1 R5504.2 R5505.2 R5509.2 R5519.2 R24040.1
BKLT_EN_EC: ECIO1.23 R24040.2
BKLT_EN_ENA: C5520.1 R5518.1 R5519.1 R5521.1 U5501.3
BOOT_HALT: R1503.2 R1510.1 R1511.1
BT_DISABLE_N: ECIO1.59 R6134.2 R24108.1
BT_PCMFRM_RSTN: NGFFE1.10 R1913.1
BT_PCMOUT_CLKREQ0: NGFFE1.14 R1912.1 R6119.1
BT_USB20_CON_N: ED6101.1 EL6103.1 NGFFE1.5
BT_USB20_CON_P: ED6101.6 EL6103.4 NGFFE1.3
BT_USB20_N: CPU1.DP10 EL6103.2
BT_USB20_P: CPU1.DN10 EL6103.3
CBN: C2703.1 U2701.35
CBP: C2703.2 U2701.37
CCD_USB20_CON_N: CAM1.7 ED3002.6 EL3001.3
CCD_USB20_CON_P: CAM1.6 ED3002.1 EL3001.2
CCD_USB20_N: CPU1.DK13 EL3001.4
CCD_USB20_P: CPU1.DJ13 EL3001.1
CFG0: CPU1.AB10 CPU1.AE7 CPU1.AG6 CPU1.AJ5 CPU1.AL7 CPU1.V10 CPU1.Y10 R606.1
CFG4: CPU1.AE9 R607.2
CFG_RCOMP: CPU1.AD6 R605.2
CHGR_PSYS_IMVP: PR4688.1 R4601.1
CNV_BRI_DT: NGFFE1.36 R1530.2 R2107.2 R6160.1
CNV_BRI_DT_R: CPU1.DL31 R2107.1
CNV_BRI_RSP: CPU1.DL29 R2104.1 R6131.1
CNV_BRI_RSP_R: NGFFE1.22 R6131.2
CNV_RGI_DT: NGFFE1.32 R1507.2 R1516.1 R2106.2
CNV_RGI_DT_R: CPU1.DP31 R2106.1
CNV_RGI_RSP: CPU1.DN29 R2105.1 R6132.1
CNV_RGI_RSP_R: NGFFE1.34 R6132.2
CNV_WR_CLK_DN: CPU1.DK44 NGFFE1.21
CNV_WR_CLK_DP: CPU1.DJ44 NGFFE1.23
CNV_WR_DN0: CPU1.DP44 NGFFE1.15
CNV_WR_DN1: CPU1.DG42 NGFFE1.9
CNV_WR_DP0: CPU1.DN44 NGFFE1.17
CNV_WR_DP1: CPU1.DG44 NGFFE1.11
CNV_WT_CLK_DN: CPU1.DL42 NGFFE1.71
CNV_WT_CLK_DP: CPU1.DK42 NGFFE1.73
CNV_WT_DN0: CPU1.DV45 NGFFE1.65
CNV_WT_DN1: CPU1.DU44 NGFFE1.59
CNV_WT_DP0: CPU1.DU45 NGFFE1.67
CNV_WT_DP1: CPU1.DT44 NGFFE1.61
CNV_WT_RCOMP: CPU1.DT45 R2102.1
CNVI_EN#: CPU1.DL27 TP2111.1
CODEC_I2C_SCL_DMIC_L: CPU1.DG36 Q1904.1 RN1914.4
CODEC_I2C_SCL_DMIC_R: Q1904.6 R3004.2 RN1915.4
CODEC_I2C_SDA_DMIC_L: CPU1.DG34 Q1904.4 RN1914.3(B)
CODEC_I2C_SDA_DMIC_R: Q1904.3 R3003.2 RN1915.3(B)
CPU_C10_GATE#: CPU1.DU40 R1712.2 R4006.2 R4034.2 R4051.2 R24113.2 U4009.1
CPU_C10_GATE#_EC: ECIO1.79 R24113.1
CPU_FAN_CTRL: C2603.1 R2602.2 U2601.4
CPU_FAN_CTRL_SIO: ECIO1.8 R2602.1 R2603.2
CPU_FAN_TACH_SIO: C2423.1 C2605.1 ECIO1.7 FANC1.2 R2606.2 R2607.1
CPU_POPI_RCOMP: CPU1.CJ41 R309.2
CPU_SMB_SCL: CPU1.DK27 Q1801.3 R5608.2 R6103.1 RN1811.1
CPU_SMB_SCL_DDR: DIMM1.253 DIMM2.253 Q1801.4 RN1810.1
CPU_SMB_SCL_P0: CPU1.DK24 RN1812.4
CPU_SMB_SCL_P1: CPU1.DN22 RN1812.2
CPU_SMB_SCL_WLAN: NGFFE1.60 R6103.2
CPU_SMB_SDA: CPU1.DP24 Q1801.6 R5609.2 R6104.1 RN1811.2
CPU_SMB_SDA_DDR: DIMM1.254 DIMM2.254 Q1801.1 RN1810.2
CPU_SMB_SDA_P0: CPU1.DJ24 RN1812.3
CPU_SMB_SDA_P1: CPU1.DL22 RN1812.1
CPU_SMB_SDA_WLAN: NGFFE1.58 R6104.2
CPVDD: C2701.1 C2714.1 R2701.1 R2721.1 U2701.36
CPVEE: C2704.2 U2701.34
CR_PE_REXT: R3301.2 U3301.2
CR_USB20_CON_N: L3301.2 U3301.3
CR_USB20_CON_P: L3301.3 U3301.4
CR_USB20_N: CPU1.DP11 L3301.1
CR_USB20_P: CPU1.DN11 L3301.4
CSI_RCOMP: CPU1.B4 R2103.2
D4302_PIN3: D4302.3 R4326.2
DBG_PMODE: CPU1.DL15 R1533.1 TP9904.1
DDR_VTT_CNTL_L1: C4026.1 Q4006.5 R4020.2
DDR_VTT_CNTL_L2: Q4006.2 Q4006.3 RN4002.3(B)
DDR_VTT_CNTL_L3: Q4006.6 R4018.1 RN4002.4
DEVSLP2: CPU1.CV48 R1605.1 R6320.1
DEVSLP2_CON: NGFFM1.38 R6320.2
DISP_RCOMP: CPU1.R2 R401.2
DMIC1_DATA_CON: R3001.1 U2701.2
DMIC_CLK_CON: R3002.1 U2701.3
DMIC_CLK_DMIC1: C3009.1 CAM1.3 ED3002.4 R3002.2 R3004.1
DMIC_DATA_DMIC1: C3008.1 CAM1.2 ED3002.3 R3001.2 R3003.1
DP_REXT: R5606.1 TSMT1.12
DP_VARY_BL_R: R5601.1 R5620.1 TSMT1.21
E51_RXD: DBGH1.12 TP4402.1
E51_TXD: DBGH1.11 R6141.2 R24074.2
E51_TXD_EC: ECIO1.97 R24074.1
E51_TXD_R: NGFFE1.44 R6141.1
EAPD#: R2754.2 U2701.47
EC_AUDIO_MUTE: ECIO1.81 R24015.1 R24017.1
EC_DTR2#_PH: ECIO1.26 R24069.1
EC_EUP: ECIO1.1 R24030.1 R24094.1
EC_EUP_EN: C2412.2 Q2402.G R24094.2
EC_EUP_EN#: Q2402.D R4501.1 R4502.1 R24072.1
EC_SCI#: CPU1.DU14 R2021.2
EC_SMB_SCL: R5625.2 R24118.1 R24119.2
EC_SMB_SCL_OZ: ECIO1.63 L5501.2 R24119.1 RN2402.1
EC_SMB_SCL_OZ_C: C5510.1 L5501.1 U5501.6
EC_SMB_SCL_TSMT: R5608.1 R5625.1 TSMT1.13
EC_SMB_SDA: R5626.2 R24117.1 R24120.2
EC_SMB_SDA_OZ: ECIO1.62 L5501.3 R24120.1 RN2402.2
EC_SMB_SDA_OZ_C: C5512.1 L5501.4 U5501.7
EC_SMB_SDA_TSMT: R5609.1 R5626.1 TSMT1.14
EC_SMI#: CPU1.DT14 R2023.2 R24005.1
EC_SMI#_R: ECIO1.9 R24005.2
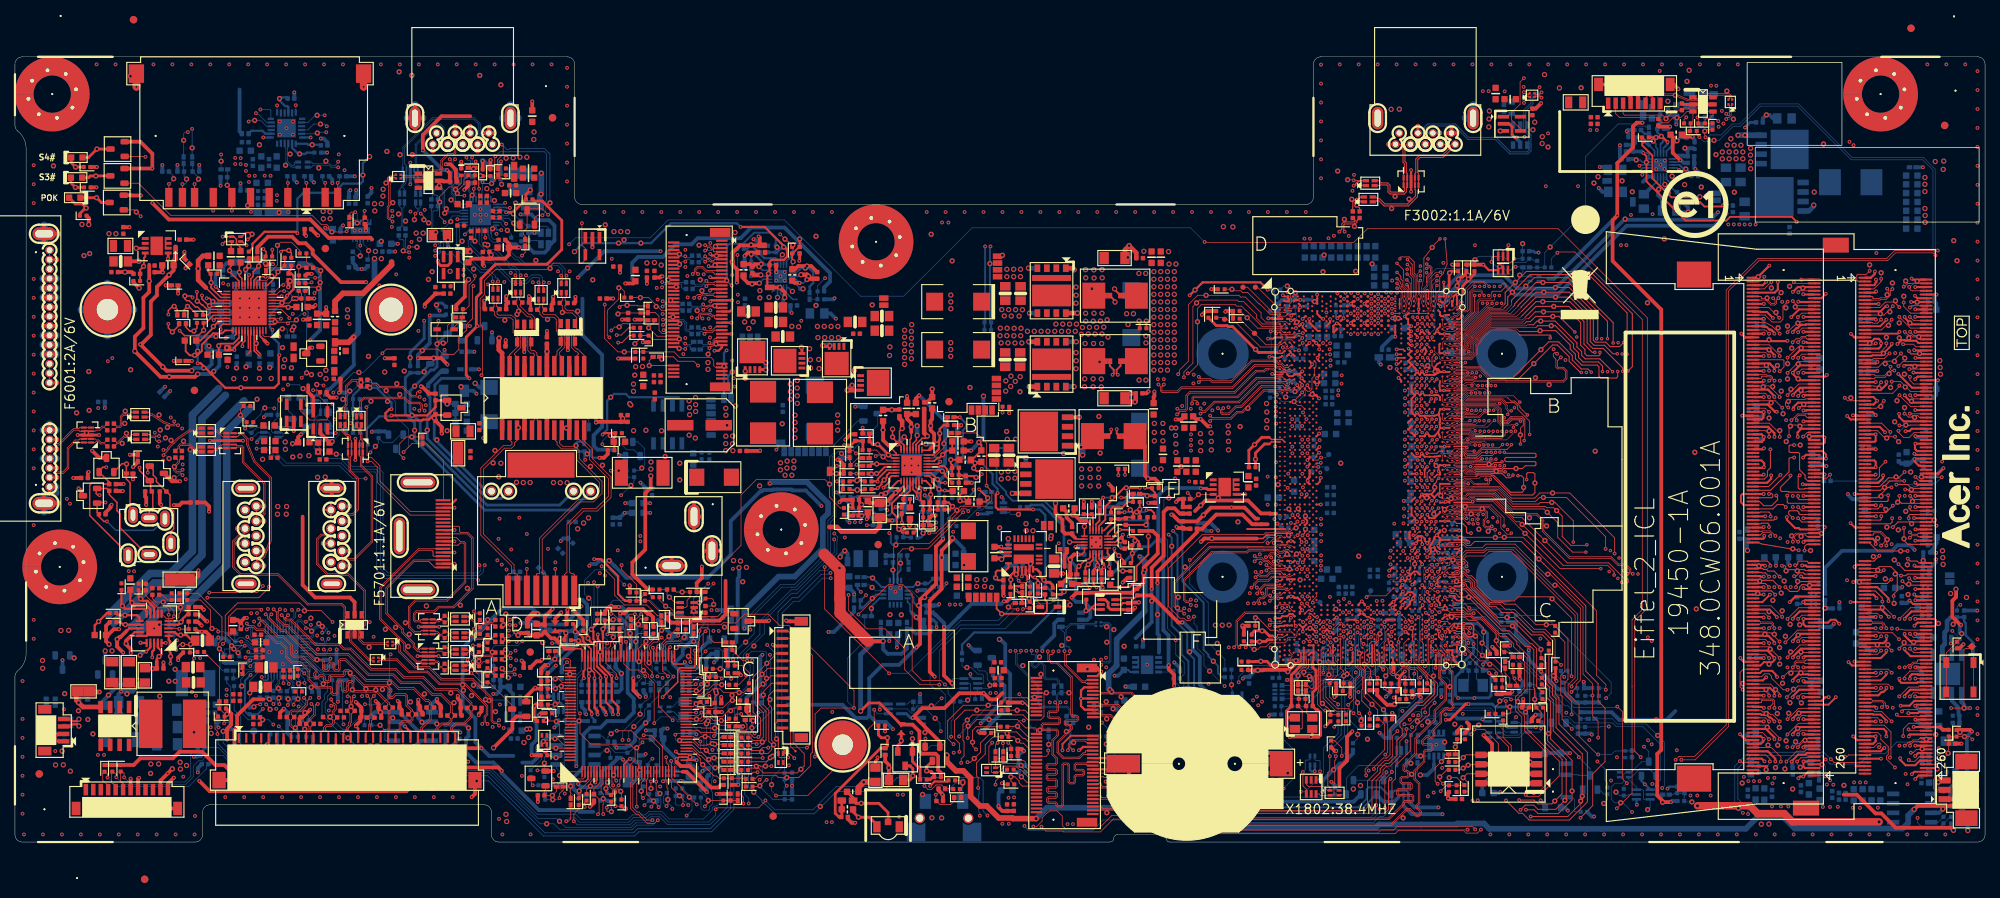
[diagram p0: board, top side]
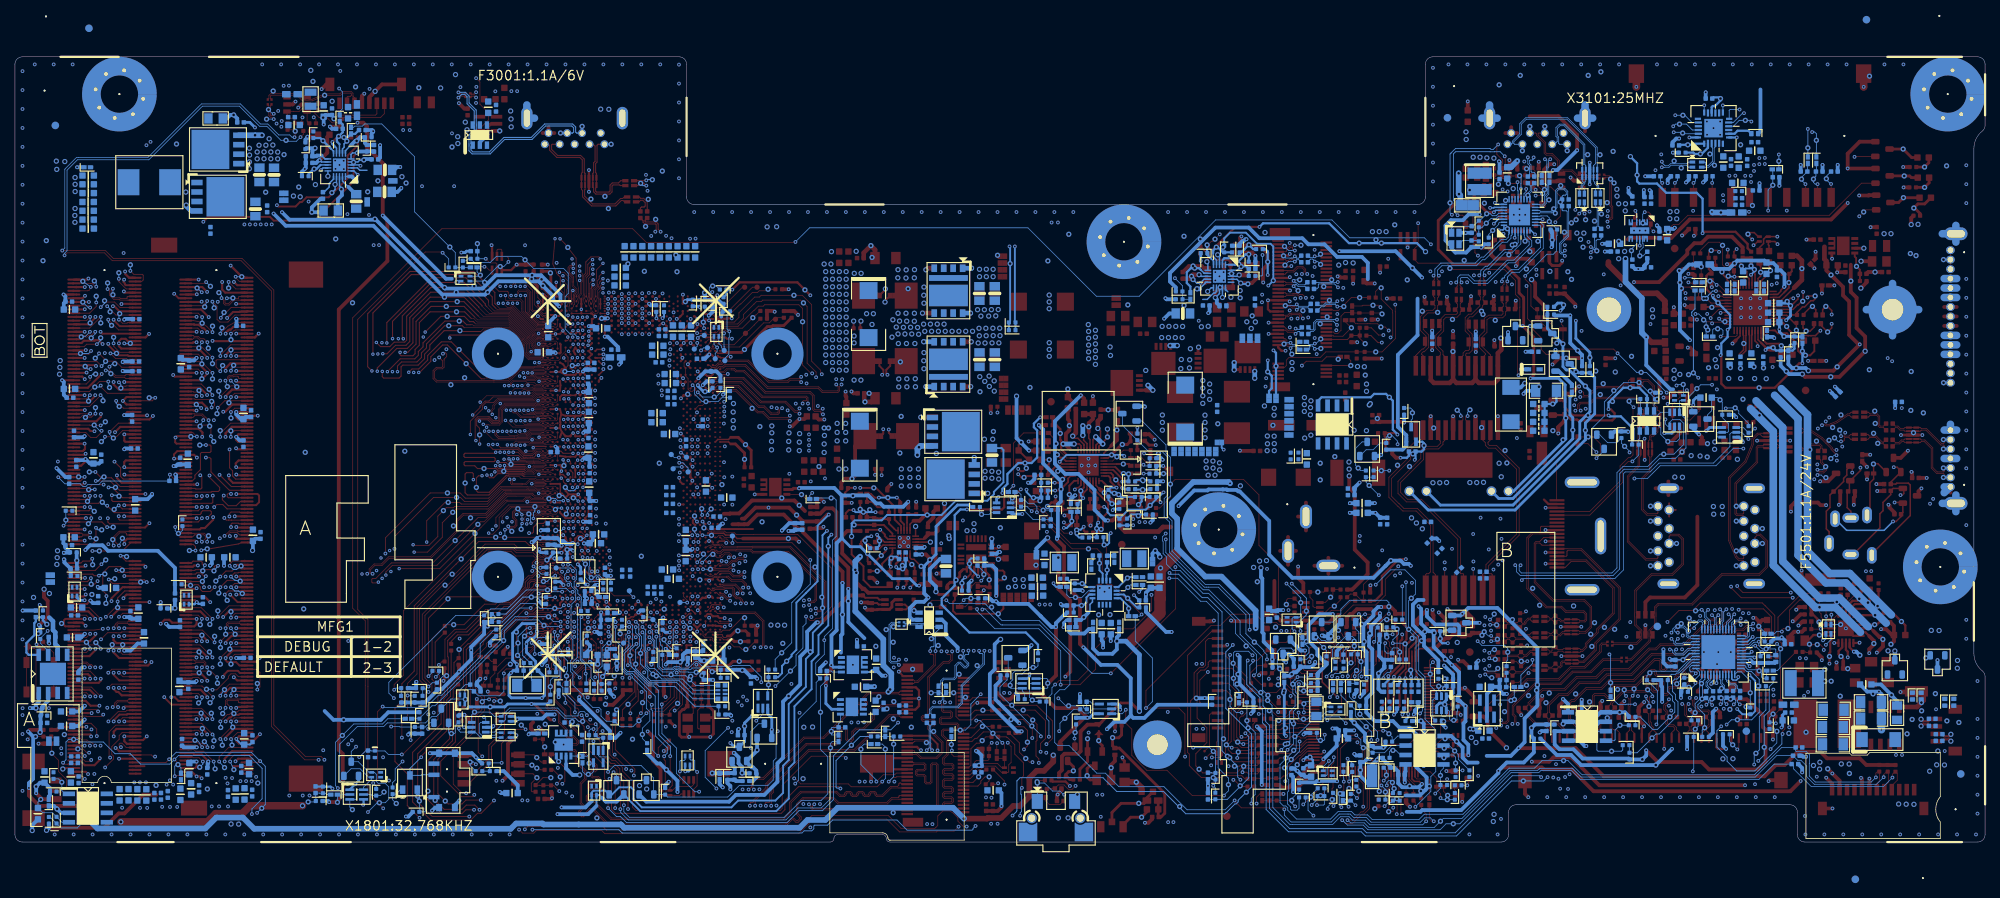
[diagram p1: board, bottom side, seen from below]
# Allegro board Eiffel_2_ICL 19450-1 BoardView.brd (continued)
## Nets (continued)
EC_VFSPI: C2402.1 ECIO1.15 R24035.2
ECIO_RSMRST#: R1709.1 R24014.1 R24037.2
EDP_AUX_CON_N: C5601.2 TSMT1.3
EDP_AUX_CON_P: C5602.2 TSMT1.4
EDP_AUX_CPU_N: C5601.1 CPU1.W4
EDP_AUX_CPU_P: C5602.1 CPU1.W3
EDP_BLCTRL_CPU: CPU1.DU19 R5510.2 R5601.2
EDP_BLEN_CPU: CPU1.DL19 R1844.2 R5504.1
EDP_HPD_CPU: CPU1.DW11 R5624.1 R5627.1
EDP_TX_C_N0: C5603.2 TSMT1.8
EDP_TX_C_N1: C5605.2 TSMT1.10
EDP_TX_C_P0: C5604.2 TSMT1.7
EDP_TX_C_P1: C5606.2 TSMT1.9
EDP_TX_CPU_N0: C5603.1 CPU1.Y5
EDP_TX_CPU_N1: C5605.1 CPU1.Y1
EDP_TX_CPU_P0: C5604.1 CPU1.Y3
EDP_TX_CPU_P1: C5606.1 CPU1.Y2
EDP_VDDEN_CPU: CPU1.DN21 R1843.2 R5537.1
EMMC_RCOMP: CPU1.DU28 R2101.1
ESPI_CON_ALERT#: DBGH1.1 R6801.2
ESPI_CPU_CLK: CPU1.CR47 R1804.1 R1805.1
ESPI_CPU_CLK_DBG: DBGH1.2 EC1802.1 R1805.2
ESPI_CPU_CLK_EC: EC1801.1 R1804.2 R24034.1
ESPI_CPU_CS#: CPU1.CT45 R24052.1 R24085.1
ESPI_CPU_CS#_DB: DBGH1.5 R24052.2
ESPI_CPU_CS#_EC: ECIO1.37 R24085.2
ESPI_CPU_IO0: CPU1.CN45 R24012.1 R24082.1
ESPI_CPU_IO0_DB: DBGH1.9 R24012.2
ESPI_CPU_IO0_EC: ECIO1.38 R24082.2
ESPI_CPU_IO1: CPU1.CN48 R24025.1 R24047.1
ESPI_CPU_IO1_DB: DBGH1.8 R24047.2
ESPI_CPU_IO1_EC: ECIO1.39 R24025.2
ESPI_CPU_IO2: CPU1.CN49 R24024.1 R24093.1
ESPI_CPU_IO2_DB: DBGH1.7 R24093.2
ESPI_CPU_IO2_EC: ECIO1.40 R24024.2
ESPI_CPU_IO3: CPU1.CN47 R24036.1 R24092.1
ESPI_CPU_IO3_DB: DBGH1.6 R24092.2
ESPI_CPU_IO3_EC: ECIO1.41 R24036.2
ESPI_CPU_RST#: CPU1.CR46 DBGH1.4 ECIO1.43 R1818.1
ESPI_EC_ALERT#: ECIO1.36 R1920.1 R6801.1 R24079.1 R24116.1
ESPI_EC_ALERT#_CPU: CPU1.DA49 R1920.2
EUP_DSW_SEL: ECIO1.12 R24060.2
EXT_PWR_GATE#: R24022.2 R24063.1
EXT_PWR_GATE#_R: ECIO1.78 R24022.1
FAN5V_OUT: R2605.1 U2601.3
FAN5V_OUT_CONN: C2604.1 FANC1.1 R2604.2 R2605.2
GPD_7: CPU1.DC47 R1528.2 R1529.1
GPP_A8_SFRM: CPU1.CT48 R1913.2
GPP_A9_CLKREQ0: CPU1.CT47 R1912.2 R1916.2
GPP_C2/SMBALERT#: CPU1.DL24 R1532.1
GPP_C5: CPU1.DP22 R1501.2 R1502.1
GPP_E6_JTAG_ODT: CPU1.DT12 R1504.2 R1512.1
GPP_H0: CPU1.DK38 R6309.1
GPP_H2: CPU1.DJ38 R1519.2 R6111.2
GSPI_MOSI: CPU1.CF48 R1520.2 R1521.1
H_CATERR#: CPU1.J4 R312.2
H_RCIN#: ECIO1.42 R24111.1
HDA_BITCLK_CODEC: R1904.1 U2701.6
HDA_BITCLK_CPU: CPU1.CY46 R1904.2
HDA_RST_N_CODEC: R1919.1 R2722.2
HDA_RST_N_CODEC_R: R2722.1 U2701.11
HDA_RST_N_CPU: C1904.1 CPU1.DA47 R1919.2
HDA_SDIN0_CODEC: C2726.1 R2718.2 U2701.8
HDA_SDIN0_CPU: CPU1.CV45 R2718.1
HDA_SDOUT_CODEC: R1905.1 U2701.5
HDA_SDOUT_CPU: CPU1.CY47 MFG1.2 Q1901.3 R1518.2 R1905.2
HDA_SPKR: CPU1.CH47 R2778.2
HDA_SYNC_CODEC: R1901.1 U2701.10
HDA_SYNC_CPU: CPU1.CV49 R1901.2
HDD_SATA_RX_CMC_N: C6006.1 EL6002.1
HDD_SATA_RX_CMC_P: C6005.1 EL6002.2
HDD_SATA_RX_CON_N: C6006.2 ED6001.4 ED6001.7 SATA1.S5
HDD_SATA_RX_CON_P: C6005.2 ED6001.5 ED6001.6 SATA1.S6
HDD_SATA_RX_N: CPU1.CK7 EL6002.3
HDD_SATA_RX_P: CPU1.CK6 EL6002.4
HDD_SATA_TX_CMC_N: C6004.1 EL6001.2
HDD_SATA_TX_CMC_P: C6003.1 EL6001.1
HDD_SATA_TX_CON_N: C6004.2 ED6001.2 ED6001.9 SATA1.S3
HDD_SATA_TX_CON_P: C6003.2 ED6001.1 ED6001.10 SATA1.S2
HDD_SATA_TX_N: CPU1.CW2 EL6001.4
HDD_SATA_TX_P: CPU1.CW1 EL6001.3
HDMI1_DDCCLK_CON: ED5703.1 HDMI1.15 Q5701.6 R5721.1
HDMI1_DDCDATA_CON: ED5703.6 HDMI1.16 Q5701.3 R5722.1
HDMI1_HPD_C: Q5705.D R5731.1
HDMI1_HPD_CON: ED5703.4 HDMI1.19 R5730.1 R5731.2
HDMI1_LS_R: Q5702.D R5701.2 R5702.2 R5703.2 R5706.2 R5707.2 R5708.2 R5709.2 R5710.2
HDMI_DDI_TX_CMC_N0: C5702.2 EL5703.1 R5702.1
HDMI_DDI_TX_CMC_N1: C5704.2 EL5702.2 R5706.1
HDMI_DDI_TX_CMC_N2: C5707.2 EL5701.2 R5708.1
HDMI_DDI_TX_CMC_N3: C5709.2 EL5704.1 R5710.1
HDMI_DDI_TX_CMC_P0: C5701.2 EL5703.2 R5701.1
HDMI_DDI_TX_CMC_P1: C5703.2 EL5702.1 R5703.1
HDMI_DDI_TX_CMC_P2: C5705.2 EL5701.1 R5707.1
HDMI_DDI_TX_CMC_P3: C5708.2 EL5704.2 R5709.1
HDMI_DDI_TX_CON_N0: ED5702.2 ED5702.9 EL5703.3 HDMI1.9 R5713.2
HDMI_DDI_TX_CON_N1: ED5701.5 ED5701.6 EL5702.4 HDMI1.6 R5712.1
HDMI_DDI_TX_CON_N2: ED5701.2 ED5701.9 EL5701.4 HDMI1.3 R5711.1
HDMI_DDI_TX_CON_N3: ED5702.5 ED5702.6 EL5704.3 HDMI1.12 R5715.2
HDMI_DDI_TX_CON_P0: ED5702.1 ED5702.10 EL5703.4 HDMI1.7 R5713.1
HDMI_DDI_TX_CON_P1: ED5701.4 ED5701.7 EL5702.3 HDMI1.4 R5712.2
HDMI_DDI_TX_CON_P2: ED5701.1 ED5701.10 EL5701.3 HDMI1.1 R5711.2
HDMI_DDI_TX_CON_P3: ED5702.4 ED5702.7 EL5704.4 HDMI1.10 R5715.1
HDMI_DDI_TX_N0: C5702.1 CPU1.AC5
HDMI_DDI_TX_N1: C5704.1 CPU1.AE2
HDMI_DDI_TX_N2: C5707.1 CPU1.AE3
HDMI_DDI_TX_N3: C5709.1 CPU1.AC1
HDMI_DDI_TX_P0: C5701.1 CPU1.AC3
HDMI_DDI_TX_P1: C5703.1 CPU1.AE1
HDMI_DDI_TX_P2: C5705.1 CPU1.AE5
HDMI_DDI_TX_P3: C5708.1 CPU1.AC2
HDMI_DET_CPU: CPU1.CV42 Q5705.S R5732.2
HDMI_SCL_CPU: CPU1.DL40 Q5701.1 RN5702.1
HDMI_SCL_R: C5721.1 D5701.1 R5721.2
HDMI_SDA_CPU: CPU1.DP42 Q5701.4 RN5702.2
HDMI_SDA_R: C5722.1 D5701.2 ED5703.5 R5722.2
HM_VCCP: G2401.2 R24061.1
HM_VCCP_R: C2409.1 ECIO1.95 R24061.2
HPGP_M2_SATA_DET#: CPU1.CR43 NGFFM1.69 R1608.1 R6305.1 R6308.1
ICH_RSMRST_N_R: D6904.1 ECIO1.82 R24037.1
IMON_VIN: C4303.1 R4318.2 U4303.3
IMON_VIN_N: C4302.1 R4324.2 U4303.5
IMON_VIN_P: C4302.2 R4325.2 U4303.4
IMON_VOUT: R4320.1 U4303.6
IMON_VOUT_Q5: Q4308.D R4327.2
IMON_VOUT_R1: R4319.1 R4320.2 R4321.1 R4322.1 R4327.1 R4332.1
IMON_VOUT_R1_G: Q4301.G R4332.2
INPUT3VSEL: CPU1.DN49 R1705.2 R1706.1
JP1: ECIO1.121 R24121.1
KBDATA: ECIO1.77 R24099.1
LAN_CLK_CPU_N: LAN1.16 R10013.2
LAN_CLK_CPU_N_C: CPU1.CJ3 R10013.1
LAN_CLK_CPU_P: LAN1.15 R10014.2
LAN_CLK_CPU_P_C: CPU1.CJ5 R10014.1
LAN_CLKREQ_CPU_N: D3101.K LAN1.12 R3116.2 R3143.1 R10021.2
LAN_CLKREQ_CPU_N_C: CPU1.DK33 D3101.A R10021.1
LAN_EESK: LAN1.27 R3136.1
LAN_LED_ACTIVE: R3154.1 RJ1.11
LAN_LINK_100: LAN1.26 R3152.2
LAN_LINK_1000: LAN1.25 R3151.2
LAN_LINK_N: ED3103.3 R3136.2 RJ1.12
LAN_MDI0_N: L3105.2 LAN1.2
LAN_MDI0_P: L3105.3 LAN1.1
LAN_MDI1_N: L3103.2 LAN1.5
LAN_MDI1_P: L3103.3 LAN1.4
LAN_MDI2_N: L3104.2 LAN1.7
LAN_MDI2_P: L3104.3 LAN1.6
LAN_MDI3_N: L3102.2 LAN1.10
LAN_MDI3_P: L3102.3 LAN1.9
LAN_MDO0_N: EC3102.1 L3105.1 U3102.1 XF3101.14
LAN_MDO0_N_C: RJ1.2 XF3101.11
LAN_MDO0_P: EC3101.1 L3105.4 U3102.6 XF3101.13
LAN_MDO0_P_C: RJ1.1 XF3101.12
LAN_MDO1_N: EC3104.1 L3103.1 U3101.1 XF3101.20
LAN_MDO1_N_C: RJ1.6 XF3101.5
LAN_MDO1_P: EC3103.1 L3103.4 U3101.6 XF3101.19
LAN_MDO1_P_C: RJ1.3 XF3101.6
LAN_MDO2_N: EC3106.1 L3104.1 U3102.4 XF3101.17
LAN_MDO2_N_C: RJ1.5 XF3101.8
LAN_MDO2_P: EC3105.1 L3104.4 U3102.3 XF3101.16
LAN_MDO2_P_C: RJ1.4 XF3101.9
LAN_MDO3_N: EC3108.1 L3102.1 U3101.4 XF3101.23
LAN_MDO3_N_C: RJ1.8 XF3101.2
LAN_MDO3_P: EC3107.1 L3102.4 U3101.3 XF3101.22
LAN_MDO3_P_C: RJ1.7 XF3101.3
LAN_PCIE_RX_N: C3145.1 LAN1.18
LAN_PCIE_RX_N_C: C3145.2 CPU1.CP7
LAN_PCIE_RX_P: C3146.1 LAN1.17
LAN_PCIE_RX_P_C: C3146.2 CPU1.CP6
LAN_PCIE_TX_N: C3132.2 LAN1.14
LAN_PCIE_TX_N_C: C3132.1 CPU1.DA2
LAN_PCIE_TX_P: C3131.2 LAN1.13
LAN_PCIE_TX_P_C: C3131.1 CPU1.DA1
LAN_RSET: LAN1.31 R3102.2
LAN_WAKE#: CPU1.DE47 R1714.1 R3141.1
LAN_WAKE#_R: Q3111.D R3141.2 R3142.1
LAN_WAKEB: LAN1.21 Q3111.S R3142.2 R3144.1
LAN_XTAL1: C3126.2 LAN1.28 R3121.1 X3101.1
LAN_XTAL2: LAN1.29 R3121.2 R3150.2
LAN_XTAL2_R: C3127.2 R3150.1 X3101.3
LCD_5V_ON1: C5545.1 C5559.1 R5536.1 R5537.2 U5504.4
LDO1_CAP: C2702.2 R2711.2 U2701.27
LDO2_CAP: C2712.2 U2701.39
LDO3_CAP: C2718.1 U2701.7
LDRQ#: ECIO1.45 R24021.1
LED2_N: LED683.2K R6802.1
LED2_P: LED683.1A Q6803.D
LED9_N: LED685.2K Q6805.D
LED9_P: LED685.1A R6806.1
LED10_N: LED684.2K R6807.1
LED10_P: LED684.1A Q6801.D
LED_GND: C5501.2 C5504.1 C5505.2 C5509.2 C5510.2 C5511.2 C5512.2 C5515.2 C5520.2 R5502.2 R5507.2 R5513.2 R5514.2 R5515.2 R5521.2 U5501.15 U5501.21
LINE1_L: C2723.1 U2701.22
LINE1_R: C2724.1 U2701.21
LINE1_VREFO_L: RN2703.3(B) U2701.31
LINE1_VREFO_R: RN2703.4 U2701.30
LPC_PME#: ECIO1.70 R24078.1
LPSS_UART2_RXD: CPU1.DT22 DBGH1.14 R2001.2 RN6120.1
LPSS_UART2_TXD: CPU1.DW22 DBGH1.13 R2002.2 RN6120.2
LVDS1_PIN4_PD: LVDS1.4 R5531.1
LVDS_TXE_N0: C5508.2 LVDS1.30 TSMT1.32
LVDS_TXE_N1: C5514.2 LVDS1.28 TSMT1.30
LVDS_TXE_N2: C5517.2 LVDS1.26 TSMT1.28
LVDS_TXE_N3: C5519.2 LVDS1.21 TSMT1.24
LVDS_TXE_NC: C5522.2 LVDS1.23 TSMT1.26
LVDS_TXE_P0: C5507.2 LVDS1.29 TSMT1.31
LVDS_TXE_P1: C5513.2 LVDS1.27 TSMT1.29
LVDS_TXE_P2: C5516.2 LVDS1.25 TSMT1.27
LVDS_TXE_P3: C5518.2 LVDS1.20 TSMT1.23
LVDS_TXE_PC: C5521.2 LVDS1.22 TSMT1.25
LVDS_TXO_N0: C5524.2 LVDS1.19 TSMT1.42
LVDS_TXO_N1: C5526.2 LVDS1.16 TSMT1.40
LVDS_TXO_N2: C5530.2 LVDS1.13 TSMT1.38
LVDS_TXO_N3: C5532.2 LVDS1.9 TSMT1.34
LVDS_TXO_NC: C5534.2 LVDS1.11 TSMT1.36
LVDS_TXO_P0: C5523.2 LVDS1.18 TSMT1.41
LVDS_TXO_P1: C5525.2 LVDS1.15 TSMT1.39
LVDS_TXO_P2: C5529.2 LVDS1.12 TSMT1.37
LVDS_TXO_P3: C5531.2 LVDS1.8 TSMT1.33
LVDS_TXO_PC: C5533.2 LVDS1.10 TSMT1.35
M_A_A0: CPU1.BB48 DIMM1.144
M_A_A1: CPU1.BL49 DIMM1.133
M_A_A2: CPU1.BG38 DIMM1.132
M_A_A3: CPU1.BL45 DIMM1.131
M_A_A4: CPU1.BJ46 DIMM1.128
M_A_A5: CPU1.BG48 DIMM1.126
M_A_A6: CPU1.BE45 DIMM1.127
M_A_A7: CPU1.BG45 DIMM1.122
M_A_A8: CPU1.BG47 DIMM1.125
M_A_A9: CPU1.BE47 DIMM1.121
M_A_A10: CPU1.BJ38 DIMM1.146
M_A_A11: CPU1.BB47 DIMM1.120
M_A_A12: CPU1.BE48 DIMM1.119
M_A_A13: CPU1.BM39 DIMM1.158
M_A_A14: CPU1.BG43 DIMM1.151
M_A_A15: CPU1.BJ42 DIMM1.156
M_A_A16: CPU1.BM41 DIMM1.152
M_A_ACT_N: CPU1.BE49 DIMM1.114
M_A_ALERT_N: CPU1.BD46 DIMM1.116
M_A_BA0: CPU1.BM43 DIMM1.150
M_A_BA1: CPU1.BG39 DIMM1.145
M_A_BG0: CPU1.BB49 DIMM1.115
M_A_BG1: CPU1.BD47 DIMM1.113
M_A_CKE0: CPU1.BG49 DIMM1.109
M_A_CKE1: CPU1.BF41 DIMM1.110
M_A_CLK0: CPU1.BL47 DIMM1.137
M_A_CLK1: CPU1.BF43 DIMM1.138
M_A_CLK#0: CPU1.BL48 DIMM1.139
M_A_CLK#1: CPU1.BF42 DIMM1.140
M_A_CS#0: CPU1.BM38 DIMM1.149
M_A_CS#1: CPU1.BG42 DIMM1.157
M_A_DQ0: CPU1.CA48 DIMM1.208
M_A_DQ1: CPU1.CA47 DIMM1.207
M_A_DQ2: CPU1.CA49 DIMM1.203
M_A_DQ3: CPU1.BV49 DIMM1.190
M_A_DQ4: CPU1.CA45 DIMM1.204
M_A_DQ5: CPU1.BV47 DIMM1.195
M_A_DQ6: CPU1.BV45 DIMM1.194
M_A_DQ7: CPU1.BV48 DIMM1.191
M_A_DQ8: CPU1.CC42 DIMM1.232
M_A_DQ9: CPU1.CC39 DIMM1.233
M_A_DQ10: CPU1.CC43 DIMM1.236
M_A_DQ11: CPU1.CE38 DIMM1.246
M_A_DQ12: CPU1.CC38 DIMM1.237
M_A_DQ13: CPU1.CE39 DIMM1.250
M_A_DQ14: CPU1.CE42 DIMM1.249
M_A_DQ15: CPU1.CE43 DIMM1.245
M_A_DQ16: CPU1.BT48 DIMM1.183
M_A_DQ17: CPU1.BT47 DIMM1.186
M_A_DQ18: CPU1.BT49 DIMM1.187
M_A_DQ19: CPU1.BN49 DIMM1.174
M_A_DQ20: CPU1.BT45 DIMM1.182
M_A_DQ21: CPU1.BN47 DIMM1.170
M_A_DQ22: CPU1.BN45 DIMM1.169
M_A_DQ23: CPU1.BN48 DIMM1.173
M_A_DQ24: CPU1.BV42 DIMM1.212
M_A_DQ25: CPU1.BV39 DIMM1.211
M_A_DQ26: CPU1.BV43 DIMM1.216
M_A_DQ27: CPU1.BW38 DIMM1.224
M_A_DQ28: CPU1.BV38 DIMM1.215
M_A_DQ29: CPU1.BW39 DIMM1.228
M_A_DQ30: CPU1.BW42 DIMM1.225
M_A_DQ31: CPU1.BW43 DIMM1.229
M_A_DQ32: CPU1.AY48 DIMM1.84
M_A_DQ33: CPU1.AY47 DIMM1.70
M_A_DQ34: CPU1.AY49 DIMM1.79
M_A_DQ35: CPU1.AU45 DIMM1.83
M_A_DQ36: CPU1.AY45 DIMM1.80
M_A_DQ37: CPU1.AU47 DIMM1.67
M_A_DQ38: CPU1.AU48 DIMM1.71
M_A_DQ39: CPU1.AU49 DIMM1.66
M_A_DQ40: CPU1.AY42 DIMM1.25
M_A_DQ41: CPU1.AY38 DIMM1.24
M_A_DQ42: CPU1.AY43 DIMM1.29
M_A_DQ43: CPU1.BB39 DIMM1.37
M_A_DQ44: CPU1.AY39 DIMM1.28
M_A_DQ45: CPU1.BB38 DIMM1.41
M_A_DQ46: CPU1.BB42 DIMM1.38
M_A_DQ47: CPU1.BB43 DIMM1.42
M_A_DQ48: CPU1.AR48 DIMM1.63
M_A_DQ49: CPU1.AR47 DIMM1.59
M_A_DQ50: CPU1.AR49 DIMM1.62
M_A_DQ51: CPU1.AM45 DIMM1.45
M_A_DQ52: CPU1.AR45 DIMM1.58
M_A_DQ53: CPU1.AM47 DIMM1.49
M_A_DQ54: CPU1.AM48 DIMM1.50
M_A_DQ55: CPU1.AM49 DIMM1.46
M_A_DQ56: CPU1.AT42 DIMM1.20
M_A_DQ57: CPU1.AT39 DIMM1.17
M_A_DQ58: CPU1.AR43 DIMM1.7
M_A_DQ59: CPU1.AT38 DIMM1.21
M_A_DQ60: CPU1.AR38 DIMM1.4
M_A_DQ61: CPU1.AR39 DIMM1.8
M_A_DQ62: CPU1.AR42 DIMM1.3
M_A_DQ63: CPU1.AT43 DIMM1.16
M_A_DQS_DN0: CPU1.BY47 DIMM1.198
M_A_DQS_DN1: CPU1.CC41 DIMM1.240
M_A_DQS_DN2: CPU1.BR47 DIMM1.177
M_A_DQS_DN3: CPU1.BV41 DIMM1.219
M_A_DQS_DN4: CPU1.AV46 DIMM1.74
M_A_DQS_DN5: CPU1.AY41 DIMM1.32
M_A_DQS_DN6: CPU1.AN46 DIMM1.53
M_A_DQS_DN7: CPU1.AR41 DIMM1.11
M_A_DQS_DP0: CPU1.BY46 DIMM1.200
M_A_DQS_DP1: CPU1.CE41 DIMM1.242
M_A_DQS_DP2: CPU1.BR46 DIMM1.179
M_A_DQS_DP3: CPU1.BW41 DIMM1.221
M_A_DQS_DP4: CPU1.AV47 DIMM1.76
M_A_DQS_DP5: CPU1.BB41 DIMM1.34
M_A_DQS_DP6: CPU1.AN47 DIMM1.55
M_A_DQS_DP7: CPU1.AT41 DIMM1.13
M_A_ODT0: CPU1.BJ39 DIMM1.155
M_A_ODT1: CPU1.BB45 DIMM1.161
M_A_PARITY: CPU1.BF39 DIMM1.143
M_B_A0: CPU1.P42 DIMM2.144
M_B_A1: CPU1.Y49 DIMM2.133
M_B_A2: CPU1.U48 DIMM2.132
M_B_A3: CPU1.Y45 DIMM2.131
M_B_A4: CPU1.U47 DIMM2.128
M_B_A5: CPU1.R49 DIMM2.126
M_B_A6: CPU1.U49 DIMM2.127
M_B_A7: CPU1.M47 DIMM2.122
M_B_A8: CPU1.M45 DIMM2.125
M_B_A9: CPU1.R47 DIMM2.121
M_B_A10: CPU1.P39 DIMM2.146
M_B_A11: CPU1.N46 DIMM2.120
M_B_A12: CPU1.R48 DIMM2.119
M_B_A13: CPU1.Y41 DIMM2.158
M_B_A14: CPU1.V41 DIMM2.151
M_B_A15: CPU1.Y42 DIMM2.156
M_B_A16: CPU1.V47 DIMM2.152
M_B_ACT_N: CPU1.M48 DIMM2.114
M_B_ALERT_N: CPU1.M49 DIMM2.116
M_B_BA0: CPU1.T38 DIMM2.150
M_B_BA1: CPU1.T42 DIMM2.145
M_B_BG0: CPU1.R45 DIMM2.115
M_B_BG1: CPU1.N47 DIMM2.113
M_B_CKE0: CPU1.U45 DIMM2.109
M_B_CKE1: CPU1.P43 DIMM2.110
M_B_CLK0: CPU1.Y47 DIMM2.137
M_B_CLK1: CPU1.M42 DIMM2.138
M_B_CLK#0: CPU1.Y48 DIMM2.139
M_B_CLK#1: CPU1.M43 DIMM2.140
M_B_CS#0: CPU1.V42 DIMM2.149
M_B_CS#1: CPU1.T39 DIMM2.157
M_B_DQ0: CPU1.AK48 DIMM2.203
M_B_DQ1: CPU1.AK45 DIMM2.207
M_B_DQ2: CPU1.AK49 DIMM2.208
M_B_DQ3: CPU1.AG47 DIMM2.195
M_B_DQ4: CPU1.AK47 DIMM2.204
M_B_DQ5: CPU1.AG45 DIMM2.191
M_B_DQ6: CPU1.AG48 DIMM2.194
M_B_DQ7: CPU1.AG49 DIMM2.190
M_B_DQ8: CPU1.AJ38 DIMM2.233
M_B_DQ9: CPU1.AL39 DIMM2.246
M_B_DQ10: CPU1.AJ39 DIMM2.237
M_B_DQ11: CPU1.AL43 DIMM2.249
M_B_DQ12: CPU1.AL38 DIMM2.250
M_B_DQ13: CPU1.AJ42 DIMM2.232
M_B_DQ14: CPU1.AL42 DIMM2.245
M_B_DQ15: CPU1.AJ43 DIMM2.236
M_B_DQ16: CPU1.AB49 DIMM2.173
M_B_DQ17: CPU1.AB48 DIMM2.174
M_B_DQ18: CPU1.AE49 DIMM2.187
M_B_DQ19: CPU1.AE47 DIMM2.186
M_B_DQ20: CPU1.AE48 DIMM2.182
M_B_DQ21: CPU1.AB47 DIMM2.169
M_B_DQ22: CPU1.AB45 DIMM2.170
M_B_DQ23: CPU1.AE45 DIMM2.183
M_B_DQ24: CPU1.AD38 DIMM2.212
M_B_DQ25: CPU1.AD39 DIMM2.216
M_B_DQ26: CPU1.AE39 DIMM2.224
M_B_DQ27: CPU1.AE43 DIMM2.225
M_B_DQ28: CPU1.AE38 DIMM2.228
M_B_DQ29: CPU1.AD43 DIMM2.215
M_B_DQ30: CPU1.AD42 DIMM2.211
M_B_DQ31: CPU1.AE42 DIMM2.229
M_B_DQ32: CPU1.J48 DIMM2.83
M_B_DQ33: CPU1.J45 DIMM2.79
M_B_DQ34: CPU1.J49 DIMM2.84
M_B_DQ35: CPU1.G47 DIMM2.66
M_B_DQ36: CPU1.J47 DIMM2.80
M_B_DQ37: CPU1.G45 DIMM2.71
M_B_DQ38: CPU1.G48 DIMM2.70
M_B_DQ39: CPU1.E48 DIMM2.67
M_B_DQ40: CPU1.J38 DIMM2.59
M_B_DQ41: CPU1.G39 DIMM2.46
M_B_DQ42: CPU1.G38 DIMM2.50
M_B_DQ43: CPU1.G42 DIMM2.45
M_B_DQ44: CPU1.J39 DIMM2.63
M_B_DQ45: CPU1.J42 DIMM2.62
M_B_DQ46: CPU1.G43 DIMM2.49
M_B_DQ47: CPU1.J43 DIMM2.58
M_B_DQ48: CPU1.B43 DIMM2.42
M_B_DQ49: CPU1.D43 DIMM2.24
M_B_DQ50: CPU1.A43 DIMM2.38
M_B_DQ51: CPU1.C40 DIMM2.29
M_B_DQ52: CPU1.C43 DIMM2.37
M_B_DQ53: CPU1.D40 DIMM2.41
M_B_DQ54: CPU1.B40 DIMM2.25
M_B_DQ55: CPU1.A40 DIMM2.28
M_B_DQ56: CPU1.B35 DIMM2.7
M_B_DQ57: CPU1.D35 DIMM2.21
M_B_DQ58: CPU1.A35 DIMM2.3
M_B_DQ59: CPU1.D38 DIMM2.4
M_B_DQ60: CPU1.C35 DIMM2.8
M_B_DQ61: CPU1.C38 DIMM2.16
M_B_DQ62: CPU1.B38 DIMM2.20
M_B_DQ63: CPU1.A38 DIMM2.17
M_B_DQS_DN0: CPU1.AH46 DIMM2.198
M_B_DQS_DN1: CPU1.AJ41 DIMM2.240
M_B_DQS_DN2: CPU1.AC47 DIMM2.177
M_B_DQS_DN3: CPU1.AE41 DIMM2.219
M_B_DQS_DN4: CPU1.H47 DIMM2.74
M_B_DQS_DN5: CPU1.G41 DIMM2.53
M_B_DQS_DN6: CPU1.C42 DIMM2.32
M_B_DQS_DN7: CPU1.D36 DIMM2.11
M_B_DQS_DP0: CPU1.AH47 DIMM2.200
M_B_DQS_DP1: CPU1.AL41 DIMM2.242
M_B_DQS_DP2: CPU1.AC46 DIMM2.179
M_B_DQS_DP3: CPU1.AD41 DIMM2.221
M_B_DQS_DP4: CPU1.H46 DIMM2.76
M_B_DQS_DP5: CPU1.J41 DIMM2.55
M_B_DQS_DP6: CPU1.D42 DIMM2.34
M_B_DQS_DP7: CPU1.C36 DIMM2.13
M_B_ODT0: CPU1.V43 DIMM2.155
M_B_ODT1: CPU1.V38 DIMM2.161
M_B_PARITY: CPU1.P38 DIMM2.143
M_VREF_CA_DIMMB: C1302.1 DIMM2.164 R1305.1 RN1301.3(B) RN1301.4
M_VREF_DQ_DIMMA: C1281.1 DIMM1.164 R1214.1 RN1201.3(B) RN1201.4
MCT1: GDT1.2 R3156.1 R3157.1 R3158.1 R3159.1 XF3101.1 XF3101.4 XF3101.7 XF3101.10
ME_CNTL1: Q1901.1 R1914.1
ME_CNTL2: MFG1.1 Q1901.2 R1915.1
ME_UNLOCK: CPU1.DU24 R1914.2 R2031.2
MIC_CAP: C2713.1 U2701.19
MINI1_WAKE#: NGFFE1.55 R6105.2 R6111.1 R6112.1
MINI_CLKREQ#_WLAN_C: NGFFE1.53 R6107.1
MODE_CFG0: R5611.1 R5612.1 TSMT1.47
MODE_CFG1: R5617.1 R5618.1 TSMT1.48
PB_IN_N_1: C2418.2 ECIO1.72 R24016.2 R24058.1
PCH_D1_SST: ECIO1.50 R24095.1
PCH_DPWROK: C1705.1 R1726.1 R1727.2 R24023.2 R24110.1
PCH_DPWROK_EC: ECIO1.57 R24023.1 R24048.1
PCH_DPWROK_R: CPU1.DR48 R1722.2 R1727.1
PCH_JTAG_TCK: CPU1.R5 TP9910.1
PCH_JTAG_TDO: CPU1.K2 CPU1.K3 R311.2 TP9909.1
PCH_OPI_RCOMP: CPU1.DU3 R310.2
PCH_PWROK: Q4007.D R1720.1 R4044.1
PCH_PWROK_C_1: Q4007.G Q4009.6 R4026.2
PCH_PWROK_C_2: Q4009.2 R4013.2
PCH_PWROK_C_3: Q4009.5 R4027.2
PCH_PWROK_R: CPU1.DN47 R1720.2 R1729.2
PCH_RTCRST_DOWN: CMOS1.2 CMOS1.4 R2531.1
PCH_SUSCLK_WLAN: NGFFE1.50 R6108.2
PCH_THERMTRIP: CPU1.E3 R302.2
PCIE_RCOMPN: CPU1.DN1 R1601.2
PCIE_RCOMPP: CPU1.DN3 R1601.1
PCIE_WAKE#: CPU1.DL45 R1716.1 R6105.1 R6301.1
PCIRST1#: ECIO1.30 R24008.1 R24106.2 RN2405.2
PCIRST2#: ECIO1.31 R24105.1 RN2405.1
PCIRST_LAN#: C3128.1 LAN1.19 R3114.1 R3115.1
PECI_EC: CPU1.CD5 R24002.1
PECI_EC_R: C2417.1 ECIO1.51 R24002.2
PLT_RST#: CPU1.CM49 D6903.1 EC1720.1 R3114.2 R24064.2
PLT_RST_N_SSD: C6301.1 D6301.1 NGFFM1.50 R6303.2
PLT_WLAN_RST#: C6103.1 NGFFE1.52 R6120.1 R24105.2
PLTRST_LAN_N: ED6902.2 R3115.2 R24106.1
PLTRST_N_SIO: ECIO1.46 R24064.1
PLTRST_SSD: R6303.1 R24008.2
PM_BATLOW#: CPU1.DH48 R1715.1
PM_CLKRUN#_EC: Q2401.D R1916.1 R24067.2
PM_CLKRUN#_EC_R: ECIO1.80 Q2401.G R24001.1 R24067.1
PM_PWRBTN#: CPU1.CY42 R1717.1 R24009.2
PM_RSMRST#: CPU1.DG49 R1709.2 R1722.1 R1728.2
PM_SLP_S0#: CPU1.CL45 R1718.2
PM_SLP_S3#: CPU1.DF47 D4004.2 PR5405.2 Q6803.G R1841.2 R4035.1 R4036.1 R4045.1 R24068.2 U4009.2
PM_SLP_S3_N: ECIO1.68 R24068.1
PM_SLP_S4#: CPU1.DC48 Q3401.2 Q6801.G R1842.2 R4011.1 R24057.2 U4020.1
PM_SLP_S4_N: ECIO1.74 R24057.1
PM_SLP_SUSB#: CPU1.DM49 R1840.2 R5305.1 R24081.1
PM_SLP_SUSB#_ECIO: ECIO1.5 R24081.2
PMCALERT#: CPU1.CL39 R1732.1
PROC_TCK: CPU1.N2 CPU1.P3 R301.2 TP9905.1
PROC_TDI: CPU1.K1 CPU1.K5 RN303.4 TP9906.1
PROC_TMS: CPU1.N3 CPU1.P4 RN303.3(B) TP9907.1
PROC_TRST#: CPU1.N1 CPU1.N5 R313.2 TP9908.1
PROCHOT#_CPU: PR4613.1 PU4601.2 R4602.1
PROCHOT#_CPU_R: R306.2 R325.2 R4602.2 R24924.1
PROCHOT_N_CPU: CPU1.C3 R24924.2
PROCHOT_N_EC: ECIO1.11 R24071.1
PROCHOT_N_OCP: Q4301.D R325.1 R24059.1 R24087.2
PROCHOT_N_OCP_R: ECIO1.54 R24087.1
PS8625_BKLT_EN: R5509.1 R5623.1 TSMT1.44
PS8625_BKLT_PWM: R5512.2 R5619.1 TSMT1.19
PS8625_HPD_R: R5627.2 TSMT1.1
PS8625_LCD_PW_EN: C5621.1 R5536.2 R5622.1 TSMT1.20
PSYS: R4319.2 R4601.2
PWR_1D05V: PC5410.1 PG5402.2 PL5402.2 PR5408.1
PWR_1D05V_EN: PR5403.1 PU5401.6
PWR_1D8V: PC5301.1 PC5303.1 PC5305.1 PC5306.1 PC5307.1 PG5304.1 PG5305.1 PG5315.2 PG5318.1 PG5320.1 PL5301.2
PWR_1D8V_BT: PC5320.2 PU5301.20
PWR_1D8V_EN: PC5314.1 PR5331.2 PU5301.2
PWR_1D8V_EN_R: D5301.A PR5325.2 PR5331.1 R5305.2
PWR_1D8V_PFM: PR5303.1 PU5301.3
PWR_1D8V_PG: PR5326.2 PR5327.2 PU5301.1
PWR_1D8V_PH: PC5320.1 PL5301.1 PU5301.10 PU5301.11 PU5301.16 PU5301.17 PU5301.18 PU5301.24
PWR_1D8V_SS: PC5313.1 PU5301.22
PWR_1D8V_TON: PR5301.2 PU5301.6
PWR_1D8V_VFB: PC5312.2 PR5302.2 PR5304.1 PU5301.5
PWR_1D8V_VFB_A: PC5312.1 PG5315.1 PR5302.1
PWR_2D5V_EN: PC5205.1 PR5204.2 PU5201.8
PWR_2D5V_FB: PC5204.2 PR5201.1 PR5203.2 PU5201.2
PWR_2D5V_VIN: PC5201.1 PG5202.1 PG5204.1 PU5201.5 PU5201.9
PWR_2D5V_VPP: PC5202.1 PC5203.1 PC5204.1 PG5201.1 PG5203.1 PR5203.1 PU5201.3 PU5201.4
PWR_3D3V: PC4514.1 PG4501.2 PG4502.2 PG4508.2 PG4509.2 PG4513.2 PG4514.2 PG4520.2 PG4529.2 PL4501.1 PT4501.1
PWR_3D3V_5V_PG: PR4511.2 PU4503.7
PWR_3D3V_BOOT2: PR4501.2 PU4503.9
PWR_3D3V_BOOT2_A: PC4512.2 PR4501.1
PWR_3D3V_CS2: PR4503.1 PU4503.5
PWR_3D3V_EN2: C4501.1 PU4503.6 R4501.2
PWR_3D3V_FB2: PR4505.2 PR4507.1 PU4503.4
PWR_3D3V_FB2_A: PG4529.1 PR4505.1
PWR_3D3V_HG2: PU4501.4 PU4503.10
PWR_3D3V_LDO3: PC4516.1 PG4532.2 PU4503.3
PWR_3D3V_LG2: PU4503.11 PU4504.4
PWR_3D3V_PH2: PC4512.1 PL4501.2 PU4501.1 PU4501.2 PU4501.3 PU4503.8 PU4504.5 PU4504.6 PU4504.7 PU4504.8
PWR_5V: PC4515.1 PG4505.1 PG4506.1 PG4511.1 PG4512.1 PG4516.1 PG4517.1 PG4530.2 PG4531.2 PL4502.2 PT4502.1
PWR_5V_BOOT1: PR4502.1 PU4503.17
PWR_5V_BOOT1_A: PC4513.1 PR4502.2
PWR_5V_BYP1: PG4530.1 PU4503.14
PWR_5V_CS1: PR4504.1 PU4503.1
PWR_5V_EN1: C4502.1 PU4503.20 R4502.2
PWR_5V_FB1: PR4506.2 PR4508.1 PU4503.2
PWR_5V_FB1_A: PG4531.1 PR4506.1
PWR_5V_HG1: PU4502.4 PU4503.16
PWR_5V_LDO5: PC4517.1 PG4533.1 PU4503.13
PWR_5V_LG1: PU4503.15 PU4505.4
PWR_5V_PH1: PC4513.2 PL4502.1 PU4502.1 PU4502.2 PU4502.3 PU4503.18 PU4505.5 PU4505.6 PU4505.7 PU4505.8
PWR_DCBATOUT_1D8V: PC5308.1 PC5315.1 PC5316.1 PG5301.2 PG5302.2 PR5301.1 PU5301.7 PU5301.8 PU5301.9 PU5301.23
PWR_DCBATOUT_3D3V: PC4501.1 PC4502.1 PC4503.1 PC4504.1 PG4503.2 PG4510.2 PU4501.5 PU4501.6 PU4501.7 PU4501.8
PWR_DCBATOUT_5V: PC4507.1 PC4508.1 PC4509.1 PC4510.1 PC4511.1 PG4504.2 PG4507.2 PG4518.2 PU4502.5 PU4502.6 PU4502.7 PU4502.8
PWR_DCBATOUT_VCCAUX: PC5006.1 PC5007.1 PC5008.1 PG5001.2 PG5002.2 PG5003.2 PG5004.2 PR5033.2 PU5002.5 PU5002.6 PU5002.7 PU5002.8 PU5005.5 PU5005.6 PU5005.7 PU5005.8
PWR_DCBATOUT_VCOREA: PC4702.1 PC4703.1 PC4704.1 PC4709.1 PG4702.2 PG4703.2 PG4704.2 PG4705.2 PU4701.2 PU4701.3 PU4701.4 PU4701.10 PU4702.2 PU4702.3 PU4702.4 PU4702.10
PWR_DCBATOUT_VCOREB: PC4705.1 PC4706.1 PC4707.1 PC4710.1 PG4708.2 PG4709.2 PG4710.2 PG4711.2 PU4703.2 PU4703.3 PU4703.4 PU4703.10 PU4704.2 PU4704.3 PU4704.4 PU4704.10
PWR_DCBATOUT_VDDQ: PC5101.1 PC5105.1 PC5106.1 PC5107.1 PG5101.2 PG5102.2 PR5111.1 PU5101.5 PU5101.6 PU5101.7 PU5101.8
PWR_DDR_SN: PC5104.1 PR5105.2
PWR_DMIC: C3001.1 C3002.1 CAM1.1 F3002.2
PWR_ID0: CNVBD1.4 EC5501.1 ECIO1.18 R5522.2
PWR_ID1: CNVBD1.5 EC5502.1 ECIO1.19 R5523.2
PWR_ID2: CNVBD1.6 EC5503.1 ECIO1.76 R5524.2
PWR_ISEN1: CNVBD1.12 U5501.17
PWR_ISEN2: CNVBD1.11 U5501.16
PWR_ISEN3: CNVBD1.8 U5501.14
PWR_ISEN4: CNVBD1.7 U5501.13
PWR_ISET: R5507.1 U5501.12
PWR_LPF: C5511.1 U5501.9
PWR_MCT1_R: C3125.1 R3156.2 R3157.2 R3158.2 R3159.2
PWR_RT: R5514.1 U5501.10
PWR_SSTCMP: R5508.1 U5501.11
PWR_SSTCMP_1: C5509.1 R5508.2
PWR_STATUS: R5513.1 U5501.8
PWR_VCCAUX_BOOT: PR5007.1 PU5001.10
PWR_VCCAUX_BOOTA: PC5003.1 PR5007.2
PWR_VCCAUX_COMP: PC5010.1 PC5012.1 PU5001.5
PWR_VCCAUX_COMPA: PC5010.2 PR5013.1
PWR_VCCAUX_COMPB: PC5011.2 PR5014.1
PWR_VCCAUX_CS_DIS: PR5004.2 PU5001.1
PWR_VCCAUX_EN: PC5002.1 PR5052.2 PU5001.19
PWR_VCCAUX_FB: PC5011.1 PC5012.2 PR5013.2 PR5015.1 PU5001.6
PWR_VCCAUX_FSWEL: PR5005.1 PR5006.1 PU5001.9
PWR_VCCAUX_HG: PU5001.11 PU5002.4 PU5005.4
PWR_VCCAUX_ISENSEN: PC5005.1 PG5006.2 PR5010.2 PR5011.2 PU5001.3
PWR_VCCAUX_ISENSEP: PC5005.2 PR5008.2 PR5009.1 PU5001.2
PWR_VCCAUX_ISENSEP_A: PG5005.2 PR5008.1
PWR_VCCAUX_LG: PU5001.13 PU5003.4 PU5004.4
PWR_VCCAUX_NTC: PR5009.2 PR5010.1 PR5011.1
PWR_VCCAUX_PG: PR5003.1 PR5402.2 PU5001.4
PWR_VCCAUX_PH: PC5003.2 PG5005.1 PL5001.1 PU5001.12 PU5002.1 PU5002.2 PU5002.3 PU5003.5 PU5003.6 PU5003.7 PU5003.8 PU5004.5 PU5004.6 PU5004.7 PU5004.8 PU5005.1 PU5005.2 PU5005.3
PWR_VCCAUX_PVCC: PC5001.1 PR5001.2 PR5002.1 PU5001.15
PWR_VCCAUX_VCC: PR5002.2 PU5001.16
PWR_VCCAUX_VID0: PR5035.2 PU5001.18
PWR_VCCAUX_VID1: PR5034.2 PU5001.17
PWR_VCCAUX_VOUT: PR5012.1 PU5001.8
PWR_VCCAUX_VOUTA: PR5012.2 PR5014.2 PR5015.2 PR5016.1
PWR_VCCAUX_VSYS: PC5004.1 PR5033.1 PU5001.20
PWR_VCORE_ALERT#: PR4630.2 PR4674.2 PU4601.3
PWR_VCORE_BOOTA: PR4612.1 PU4601.25
PWR_VCORE_BOOTA_A: PC4604.2 PR4612.2
PWR_VCORE_BOOTB: PR4616.1 PU4601.1
PWR_VCORE_BOOTB_A: PC4607.2 PR4616.2
PWR_VCORE_CLK: PR4634.2 PU4601.5
PWR_VCORE_COMP: PC4612.1 PR4640.1 PU4601.15
PWR_VCORE_DATA: PR4636.2 PU4601.4
PWR_VCORE_FB: PC4612.2 PC4613.1 PR4640.2 PR4641.1 PU4601.16
PWR_VCORE_HGA: PU4601.26 PU4701.1 PU4702.1
PWR_VCORE_HGB: PU4601.32 PU4703.1 PU4704.1
PWR_VCORE_IMON: PR4601.2 PU4601.11
PWR_VCORE_ISEN1N: PR4629.1 PU4601.19
PWR_VCORE_ISEN1N_A: PC4601.1 PC4608.2 PG4707.1 PR4629.2 PR4662.2
PWR_VCORE_ISEN1P: PC4601.2 PR4628.1 PR4662.1 PU4601.20
PWR_VCORE_ISEN1P_A: PG4706.1 PR4655.2
PWR_VCORE_ISEN1P_B: PR4628.2 PR4655.1
PWR_VCORE_ISEN2N: PR4635.1 PU4601.18
PWR_VCORE_ISEN2N_A: PC4610.2 PC4611.1 PG4701.1 PR4635.2 PR4663.2
PWR_VCORE_ISEN2P: PC4610.1 PR4633.1 PR4663.1 PU4601.17
PWR_VCORE_ISEN2P_A: PG4712.1 PR4646.2
PWR_VCORE_ISEN2P_B: PR4633.2 PR4646.1
PWR_VCORE_LGA: PU4601.28 PU4701.8 PU4702.8
PWR_VCORE_LGB: PU4601.30 PU4703.8 PU4704.8
PWR_VCORE_NTC1N: PR4639.1 PR4665.1
PWR_VCORE_NTC1N_A: PR4643.1 PR4665.2 PR4677.2
PWR_VCORE_NTC1P: PR4601.1 PR4639.2 PR4643.2
PWR_VCORE_PHA: PC4604.1 PG4706.2 PL4701.1 PR4704.1 PU4601.27 PU4701.9 PU4702.9
PWR_VCORE_PHB: PC4607.1 PG4712.2 PL4702.1 PR4705.1 PU4601.31 PU4703.9 PU4704.9
PWR_VCORE_PSYS: PC4624.2 PR4637.2 PR4688.2 PU4601.9
PWR_VCORE_PVCC: PC4603.1 PR4609.2 PU4601.29
PWR_VCORE_RGND: PR4644.1 PR4672.1 PU4601.13
PWR_VCORE_SET1: PR4624.1 PR4666.2 PU4601.8
PWR_VCORE_SET1_A: PR4619.2 PR4666.1
PWR_VCORE_SET1_B: PR4624.2 PR4669.1
PWR_VCORE_SET2: PR4625.1 PR4660.2 PU4601.7
PWR_VCORE_SET2_A: PR4620.2 PR4660.1
PWR_VCORE_SET2_B: PR4625.2 PR4668.1
PWR_VCORE_SET3: PR4626.1 PR4661.2 PU4601.6
PWR_VCORE_SET3_A: PR4621.2 PR4661.1
PWR_VCORE_SET3_B: PR4626.2 PR4667.1
PWR_VCORE_SNA: PC4701.1 PR4704.2
PWR_VCORE_SNB: PC4708.1 PR4705.2
PWR_VCORE_TSEN: PR4701.2 PR4702.2 PU4601.21
PWR_VCORE_TSEN_A: PR4622.2 PR4627.1 PR4701.1 PR4702.1
PWR_VCORE_TSEN_A_A: PR4627.2 PR4659.1
PWR_VCORE_VCC: PC4602.1 PR4604.2 PU4601.10
PWR_VCORE_VCCST: PC4609.1 PG4601.2 PR4613.2 PR4630.1 PR4631.1 PR4632.1
PWR_VCORE_VIN: PC4605.1 PR4605.1 PU4601.22
PWR_VCORE_VR_EN: PU4601.23 R4603.1
PWR_VCORE_VR_READY: PR4607.2 PU4601.24 R4604.1
PWR_VCORE_VREF: PR4615.2 PR4619.1 PR4620.1 PR4621.1 PR4622.1 PR4677.1 PU4601.12
PWR_VCORE_VREF_A: PC4606.1 PR4615.1
PWR_VCORE_VSEN: PC4613.2 PR4638.1 PR4641.2 PR4671.1 PU4601.14
PWR_VDDQ_BOOT: PR5115.1 PU5103.18
PWR_VDDQ_BOOT_A: PC5111.1 PR5115.2
PWR_VDDQ_CS: PR5106.1 PU5103.13
PWR_VDDQ_EN: PC5110.1 PR5113.2 PU5103.8
PWR_VDDQ_FB: PC5112.2 PR5116.1 PR5117.2 PU5103.6
PWR_VDDQ_HG: PU5101.4 PU5103.17
PWR_VDDQ_LG: PU5102.4 PU5103.15
PWR_VDDQ_PG: PR5110.2 PU5103.10
PWR_VDDQ_PH: PC5111.2 PL5101.1 PR5105.1 PU5101.1 PU5101.2 PU5101.3 PU5102.5 PU5102.6 PU5102.7 PU5102.8 PU5103.16
PWR_VDDQ_TON: PR5111.2 PU5103.9
PWR_VDDQ_VDD: PC5108.1 PR5109.2 PU5103.12
PWR_VDDQ_VDDQ: PC5112.1 PR5117.1 PR5120.1 PU5103.5
PWR_VDDQ_VID: PC5109.1 PR5108.1 PU5103.11
PWR_VDDQ_VLDOIN: PC5102.1 PG5103.2 PU5103.19
PWR_VDDQ_VTT: PC5114.1 PC5115.1 PG5104.2 PU5103.2 PU5103.20
PWR_VDDQ_VTTREF: PC5113.1 PU5103.4
PWR_VNN: PC5411.1 PC5412.1 PG5401.2 PL5401.2 PR5419.2
PWR_VNN1D05V_BOOTA: PC5404.2 PU5401.2
PWR_VNN1D05V_BOOTA_A: PC5404.1 PR5401.1
PWR_VNN1D05V_BOOTB: PC5405.2 PU5401.3
PWR_VNN1D05V_BOOTB_A: PC5405.1 PR5423.1
PWR_VNN1D05V_FB2: PR5407.1 PR5408.2 PU5401.5
PWR_VNN1D05V_PG1: PC5406.2 PR5403.2 PR5420.2 PU5401.14
PWR_VNN1D05V_PG2: PC5407.2 PR5421.2 PU5401.7
PWR_VNN1D05V_PHA: PL5401.1 PR5401.2 PU5401.1
PWR_VNN1D05V_PHB: PL5402.1 PR5423.2 PU5401.4
PWR_VNN1D05V_VCC: PC5401.2 PR5413.2 PU5401.8
PWR_VNN1D05V_VID: PR5405.1 PU5401.13
PWR_VNN1D05V_VINA: PC5402.2 PR5422.2 PU5401.11
PWR_VNN1D05V_VINB: PC5403.2 PR5410.2 PU5401.10
PWR_VNN1D05V_VOUT1: PR5419.1 PU5401.16
PWR_VNN_EN: PR5402.1 PU5401.15
PWR_VREF: C5504.2 U5501.2
PWR_VTT_EN: PC5116.1 PR5114.2 PU5103.7
PWRBTN#: EC6401.1 L6405.1 PWRBT1.1
PWRBTN#_1: L6405.2 R6408.1 R6409.2
PWRBTN_IN: C6401.1 R6409.1 R24058.2 R24088.1
PWRGD_PS_L: C2424.1 Q2403.2 R24018.2 R24097.1
PWRGD_PS_L1: Q2403.5 Q2403.6 R24100.2
PWRLED_CON: L6401.1 LED1.2 R6412.2
PWRLED_CON_5V: L6401.2 R6404.1
PWROK3_1: ECIO1.29 R24089.2
PWROK3_1_R: C2403.1 R24032.1 R24062.1 R24089.1 R24112.2
Q4002_2: C4001.1 Q4001.2 R4002.2 R4038.1
Q4002_6: Q4001.5 Q4001.6 R4003.2
Q9639_AB_EC: Q4009.1 Q4009.3
RING2: AUDS1.3 EC2913.1 ED2905.2 R2733.1 U2701.17
RSMRST_PWRGD#: PR5317.2 R24031.1
RSMRST_PWRGD#_ECIO: ECIO1.2 R24031.2
RSVD: CPU1.J3 R403.2
RTC_DET#: CPU1.CH45 Q2501.D R2003.1
RTC_INTRUDER#: C1701.1 CPU1.DR47 R1704.2 R1746.1
RTC_RST#: C1821.1 CMOS1.1 CMOS1.3 CPU1.DT47 G2530.1 Q1820.D RN1804.3(B)
RTC_RST#_R: Q1820.S R1833.1
RTCRST_ON: C1823.1 Q1820.G R1821.1 R24033.2 R24056.1
RTCRST_ON_R: ECIO1.75 R24033.1
RTL_ISOLATE_N: LAN1.20 R3160.2 R3161.1
SA1_DIMB: DIMM2.260 R1302.2
SATAXPCIE1: CPU1.CR42 TP1611.1
SD3_RCOMP: CPU1.CJ43 R1902.1
SD_CD_N#: CRS1.11 EC3328.1 U3301.10
SD_CLK: R3305.1 U3301.18
SD_CLK_1: CRS1.5 EC3326.1 R3305.2
SD_CMD: CRS1.2 EC3327.1 U3301.20
SD_DATA0: R3303.1 U3301.13
SD_DATA0_1: CRS1.7 EC3322.1 R3303.2
SD_DATA1: R3304.1 U3301.12
SD_DATA1_1: CRS1.8 EC3323.1 R3304.2
SD_DATA2: CRS1.9 EC3324.1 U3301.23
SD_DATA3: CRS1.1 EC3325.1 U3301.22
SD_WP: CRS1.10 EC3321.1 U3301.11
SDREG: C3301.1 U3301.16
SE_BJT_B1: Q4012.5 R4011.2
SE_BJT_B2: C4024.1 R4012.1 R4014.2 R4033.2
SE_BJT_B3: Q4012.2 R4014.1
SE_VPP_EN_B: Q4012.3 Q4012.6 Q4013.B RN4001.4
SE_VTT_EN: PR5114.1 R4018.2 R4022.2 R4045.2
SELEEVE: AUDS1.4 EC2909.1 ED2905.1 R2723.1 U2701.18
SIO_AGND: C2404.2 C2407.2 C2409.2 C2411.2 C2413.2 C2414.2 C2421.2 C2427.2 ECIO1.83 R24007.2 R24027.2 R24073.2 R24077.2 R24091.1 R24098.2 RT2401.2 RT2402.2
SIO_ATXPG: ECIO1.98 Q2403.3 R24054.1
SIO_AUDIO_MUTE: R2754.1 R24015.2
SIO_BOARD_ID1: ECIO1.102 R24065.1 R24084.2
SIO_BOARD_ID2: ECIO1.103 R24011.1 R24013.2
SIO_BOARD_ID3: ECIO1.104 R24055.1 R24101.2
SIO_CE_N: ECIO1.27 R24076.2 U2401.1
SIO_CLK_DB: ECIO1.48 R24103.1 RN2404.2
SIO_COPEN#: ECIO1.65 R24029.1
SIO_DAT_DB: ECIO1.49 R24103.2 RN2404.1
SIO_DEBUG_RX: ECIO1.124 RN2403.2
SIO_DEBUG_TX: ECIO1.123 RN2403.1
SIO_GP17: ECIO1.25 R24019.2 R24039.1
SIO_HOLD#: R24109.2 U2401.7
SIO_K8PWR_EN: ECIO1.125 R24075.1
SIO_MAIN_VCC3: ECIO1.89 R24051.1 R24107.1
SIO_PCICLK: ECIO1.44 R24034.2
SIO_PSON_N: ECIO1.73 Q2404.G R24066.1
SIO_PSON_N_1: Q2404.D R24051.2
SIO_SCK: R24006.2 R24102.2 U2401.6
SIO_SCK_R: ECIO1.22 R24102.1
SIO_SI: ECIO1.21 R24086.2 U2401.5
SIO_SO: ECIO1.28 R24045.2 U2401.2
SIO_VCORE: C2401.2 C2415.1 ECIO1.33
SIO_VIN1: ECIO1.94 R24020.2 R24027.1
SIO_VIN2: C2407.1 ECIO1.93 R24007.1 R24096.1
SIO_VIN3: C2413.1 ECIO1.92 R24010.1 R24073.1
SIO_VIN4: C2411.1 ECIO1.91 R24003.1 R24098.1
SIO_VIN5: C2414.1 C4304.1 D4302.2 ECIO1.90 R4322.2 R24077.1
SIO_VREF: C2421.1 ECIO1.88 R24046.2 R24114.2
SIO_WP#: R24115.2 U2401.3
SIO_WRST#: C2422.1 ECIO1.47 R24104.2
SM_DRAMRST#: C501.1 C1325.1 DIMM1.108 DIMM2.108 R511.1
SM_DRAMRST#_CPU: CPU1.DK47 R510.2 R511.2
SM_PGCNTL: CPU1.M39 R4020.1 R4022.1
SM_RCOMP_0: CPU1.D47 R505.2
SM_RCOMP_1: CPU1.E46 R506.2
SM_RCOMP_2: CPU1.C47 R507.2
SML1ALERT: CPU1.CL48 R1505.2 R1513.1
SNDW_RCOMP: CPU1.CV38 R1903.1
SPEED_100_L1: ED3102.3 R3138.1 R3152.1 RJ1.10
SPEED_1000_L1: ED3101.3 R3139.1 R3151.1 RJ1.9
SPI_CLK_ROM: R1823.1 U2501.6 U2504.6
SPI_CLK_ROM_R: CPU1.DB42 R1823.2 R1839.2
SPI_CS_CPU_N0: CPU1.DB43 R2508.2 U2501.1 U2504.1
SPI_HOLD_ROM: R1826.1 U2501.7 U2504.7
SPI_HOLD_ROM_R: CPU1.DD41 R1531.2 R1534.1 R1826.2
SPI_SI_ROM: R1825.1 U2501.5 U2504.5
SPI_SI_ROM_R: CPU1.DD43 R1510.2 R1825.2
SPI_SO_ROM: R1827.1 U2501.2 U2504.2
SPI_SO_ROM_R: CPU1.DF43 R1827.2
SPI_WP_R_N: ECIO1.14 R24028.1
SPI_WP_ROM: R1824.1 U2501.3 U2504.3
SPI_WP_ROM_R: CPU1.DF42 R1506.2 R1514.1 R1824.2
SRTC_RST#: C1820.1 CPU1.DK46 RN1804.4
SSD1_CLK_CPU_CON_N: NGFFM1.53 R6314.1
SSD1_CLK_CPU_CON_P: NGFFM1.55 R6313.1
SSD1_CLK_CPU_N: CPU1.CL2 R6314.2
SSD1_CLK_CPU_P: CPU1.CL1 R6313.2
SSD1_CLKREQ_CPU_N: CPU1.DN34 R1813.2 R6302.1
SSD1_PCIE_RX_N0: CPU1.CA6 NGFFM1.43
SSD1_PCIE_RX_N1: CPU1.CC5 NGFFM1.29
SSD1_PCIE_RX_N2: CPU1.CE6 NGFFM1.17
SSD1_PCIE_RX_N3: CPU1.CG7 NGFFM1.5
SSD1_PCIE_RX_P0: CPU1.CA5 NGFFM1.41
SSD1_PCIE_RX_P1: CPU1.CC6 NGFFM1.31
SSD1_PCIE_RX_P2: CPU1.CE7 NGFFM1.19
SSD1_PCIE_RX_P3: CPU1.CG6 NGFFM1.7
SSD1_PCIE_TX_CON_N0: C6307.1 NGFFM1.47
SSD1_PCIE_TX_CON_N1: C6309.1 NGFFM1.35
SSD1_PCIE_TX_CON_N2: C6311.1 NGFFM1.23
SSD1_PCIE_TX_CON_N3: C6332.1 NGFFM1.11
SSD1_PCIE_TX_CON_P0: C6306.1 NGFFM1.49
SSD1_PCIE_TX_CON_P1: C6308.1 NGFFM1.37
SSD1_PCIE_TX_CON_P2: C6310.1 NGFFM1.25
SSD1_PCIE_TX_CON_P3: C6331.1 NGFFM1.13
SSD1_PCIE_TX_N0: C6307.2 CPU1.CP1
SSD1_PCIE_TX_N1: C6309.2 CPU1.CR3
SSD1_PCIE_TX_N2: C6311.2 CPU1.CT2
SSD1_PCIE_TX_N3: C6332.2 CPU1.CT3
SSD1_PCIE_TX_P0: C6306.2 CPU1.CP2
SSD1_PCIE_TX_P1: C6308.2 CPU1.CR4
SSD1_PCIE_TX_P2: C6310.2 CPU1.CT1
SSD1_PCIE_TX_P3: C6331.2 CPU1.CT5
SSD_CLKREQ#: NGFFM1.52 R6302.2
SSD_WAKE#: NGFFM1.54 R6301.2 R6309.2 R6310.2
SUS_CLK_CPU: CPU1.DF49 R6108.1 R6311.1
SUSCLK_SSD: NGFFM1.68 R6311.2
SUSLED_1: Q6401.1 R6405.1
SUSLED_2: Q6402.D R6402.2 R6405.2
SUSLED_CON: EC6402.1 L6406.1 R6410.1 R6411.2 R6412.1
SUSLED_CON_OR: LED1.1 R6411.1
SUSLED_CON_P1: Q6401.3 R6407.1
SUSLED_N: ECIO1.20 Q6402.S R6403.2
SVID_ALERT#_CPU: PR4674.1 R706.2 R707.2
SVID_ALERT#_CPU_R: CPU1.H1 R706.1
SVID_CLK_CPU: CPU1.H2 PR4632.2 PR4634.1 R702.2
SVID_DATA_CPU: CPU1.H3 PR4631.2 PR4636.1 R708.2
SW_ON_N_SIO: ECIO1.69 R24009.1 R24016.1 R24044.1
SYS_PWROK: CPU1.DP19 Q6805.G R1730.1 R24032.2
SYS_RESET#: CPU1.DK19 R1701.2
SYS_TMPIN1: C2427.1 ECIO1.87 R24114.1 RT2402.1
TBT_LSX0_RXD: CPU1.DK17 R1522.2 R1523.1
TBT_LSX1_RXD: CPU1.DP17 R1524.2 R1525.1
TBT_LSX2_RXD: CPU1.DL34 R1526.2 R1527.1
TBT_LSX3_RXD: CPU1.DL33 R1508.2 R1517.1
TCRCOMP_DN: CPU1.AY1 R402.1
TCRCOMP_DP: CPU1.AY2 R402.2
TEST_MODE: R5602.1 TSMT1.2
THERMAL_SHUT#: CPU1.DU22 R2041.1 R24019.1
TP_CPU_PWRGD: CPU1.CF1 TP1702.1
TP_DA11: CPU1.DA11 TP619.1
TP_ISP_0: CPU1.BF11 TP603.1
TP_ISP_1: CPU1.BD11 TP602.1
TP_ISP_TRIG_0: CPU1.BE10 TP604.1
TP_ISP_TRIG_1: CPU1.BF10 TP605.1
TP_PCH_IST_1: CPU1.CY32 TP607.1
TP_PROC_SELECT#: CPU1.D4 TP609.1
TP_SKTOCC#: CPU1.C5 TP608.1
TS#_DIMM1_0: DIMM1.134 R1231.2
TS#_DIMM1_1: DIMM2.134 R1303.2
TSMT_SMB_SCL_U: R5615.2 U5602.6
TSMT_SMB_SCL_U_R: R5613.2 R5615.1 TSMT1.46
TSMT_SMB_SDA_U: R5616.2 U5602.5
TSMT_SMB_SDA_U_R: R5610.1 R5614.2 R5616.1 TSMT1.45
USB1_USB20_CON_N: ED3505.6 EL3509.2 USB3R1.2
USB1_USB20_CON_P: ED3505.1 EL3509.3 USB3R1.3
USB1_USB20_N: CPU1.DN8 EL3509.1
USB1_USB20_P: CPU1.DP8 EL3509.4
USB1_USB30_RX_CON_N: ED3504.1 ED3504.10 EL3508.4 USB3R1.5
USB1_USB30_RX_CON_P: ED3504.2 ED3504.9 EL3508.3 USB3R1.6
USB1_USB30_RX_N: CPU1.DJ8 EL3508.2
USB1_USB30_RX_P: CPU1.DJ6 EL3508.1
USB1_USB30_TX_CMC_N: C3513.2 EL3507.2
USB1_USB30_TX_CMC_P: C3514.2 EL3507.1
USB1_USB30_TX_CON_N: ED3504.4 ED3504.7 EL3507.4 USB3R1.8
USB1_USB30_TX_CON_P: ED3504.5 ED3504.6 EL3507.3 USB3R1.9
USB1_USB30_TX_N: C3513.1 CPU1.DJ2
USB1_USB30_TX_P: C3514.1 CPU1.DJ1
USB2_COMP: CPU1.DN5 R1603.1
USB2_USB20_CON_N: ED3502.6 EL3503.2 USB3R2.2
USB2_USB20_CON_P: ED3502.1 EL3503.3 USB3R2.3
USB2_USB20_N: CPU1.DK11 EL3503.1
USB2_USB20_P: CPU1.DJ11 EL3503.4
USB2_USB30_RX_CON_N: ED3501.1 ED3501.10 EL3502.4 USB3R2.5
USB2_USB30_RX_CON_P: ED3501.2 ED3501.9 EL3502.3 USB3R2.6
USB2_USB30_RX_N: CPU1.DG9 EL3502.2
USB2_USB30_RX_P: CPU1.DG7 EL3502.1
USB2_USB30_TX_CMC_N: C3501.2 EL3501.2
USB2_USB30_TX_CMC_P: C3502.2 EL3501.1
USB2_USB30_TX_CON_N: ED3501.4 ED3501.7 EL3501.4 USB3R2.8
USB2_USB30_TX_CON_P: ED3501.5 ED3501.6 EL3501.3 USB3R2.9
USB2_USB30_TX_N: C3501.1 CPU1.DJ3
USB2_USB30_TX_P: C3502.1 CPU1.DJ5
USB3_USB20_CON_N: ED3401.1 EL3401.3 USB3R3.2
USB3_USB20_CON_P: ED3401.6 EL3401.2 USB3R3.3
USB3_USB20_N: CPU1.DP13 EL3401.4
USB3_USB20_P: CPU1.DN13 EL3401.1
USB3_USB30_RX_CON_N: ED3402.1 ED3402.10 EL3404.4 USB3R3.5
USB3_USB30_RX_CON_P: ED3402.2 ED3402.9 EL3404.3 USB3R3.6
USB3_USB30_RX_N: CPU1.DE7 EL3404.2
USB3_USB30_RX_P: CPU1.DE9 EL3404.1
USB3_USB30_TX_CMC_N: C3413.2 EL3403.2
USB3_USB30_TX_CMC_P: C3414.2 EL3403.1
USB3_USB30_TX_CON_N: ED3402.4 ED3402.7 EL3403.4 USB3R3.8
USB3_USB30_TX_CON_P: ED3402.5 ED3402.6 EL3403.3 USB3R3.9
USB3_USB30_TX_N: C3413.1 CPU1.DF3
USB3_USB30_TX_P: C3414.1 CPU1.DF5
USB4_USB20_CON_N: ED3401.4 EL3402.3 USB3R4.2
USB4_USB20_CON_P: ED3401.3 EL3402.2 USB3R4.3
USB4_USB20_N: CPU1.DK10 EL3402.4
USB4_USB20_P: CPU1.DJ10 EL3402.1
USB4_USB30_RX_CON_N: ED3403.1 ED3403.10 EL3406.4 USB3R4.5
USB4_USB30_RX_CON_P: ED3403.2 ED3403.9 EL3406.3 USB3R4.6
USB4_USB30_RX_N: CPU1.DC7 EL3406.2
USB4_USB30_RX_P: CPU1.DC9 EL3406.1
USB4_USB30_TX_CMC_N: C3415.2 EL3405.2
USB4_USB30_TX_CMC_P: C3416.2 EL3405.1
USB4_USB30_TX_CON_N: ED3403.4 ED3403.7 EL3405.4 USB3R4.8
USB4_USB30_TX_CON_P: ED3403.5 ED3403.6 EL3405.3 USB3R4.9
USB4_USB30_TX_N: C3415.1 CPU1.DF2
USB4_USB30_TX_P: C3416.1 CPU1.DF1
USB_EN: C3401.1 Q3401.5 Q3401.6 Q3402.D R3401.2
USB_EN_FRONT: C3412.1 R3403.2 U3401.4 U3402.4 U3503.4 U3504.4
USB_EN_REAR: Q3401.3 R3402.2 R3403.1 R3404.1
USB_ID: CPU1.DL6 R1604.1
USB_OC#: CPU1.CT43 CPU1.DW14 R1606.1
USB_SIO_EUP: Q3402.G R24038.1 R24070.1
USB_SIO_EUP_R: ECIO1.10 R24070.2
USB_VBUSSENSE: CPU1.DL11 R1602.1
V_5_LED: G6401.2 Q6401.2
V_SMA_VREF_CA: C1221.1 CPU1.C44 R1214.2
V_SMA_VREF_CA_C: C1221.2 R1215.1
V_SMB_VREF_CA: C1328.1 CPU1.B45 R1305.2
V_SMB_VREF_CA_C: C1328.2 R1306.1
VCORE_EN: R4037.1 R4603.2 R24041.1
VCORE_EN_EC: ECIO1.4 R24041.2
VCORE_PWRGD: R4027.1 R4604.2
VRALERT#: CPU1.CN38 R2201.1
VRD_TMPIN2: C2404.1 ECIO1.86 R24046.1 RT2401.1
VTT_CT_3D3V_S0: C4008.1 U4003.10
VTT_CT_5V_S0: C4007.1 U4003.12
W_DISABLE#2: CPU1.DW12 R6133.2
W_DISABLE#2_CON: NGFFE1.54 R6133.1 R6134.1 RN6119.2
WIFI_DISABLE_N: ECIO1.58 NGFFE1.56 R24049.1 RN6119.1
WLAN_CLK_CPU_CON_N: NGFFE1.49 R6109.1
WLAN_CLK_CPU_CON_P: NGFFE1.47 R6110.1
WLAN_CLK_CPU_N: CPU1.CK3 R6109.2
WLAN_CLK_CPU_P: CPU1.CK4 R6110.2
WLAN_CLKREQ_CPU#: CPU1.DP36 R1812.2 R6107.2
WLAN_PCIE_RX_N: CPU1.CM7 NGFFE1.43
WLAN_PCIE_RX_P: CPU1.CM6 NGFFE1.41
WLAN_PCIE_TX_N: C6101.1 NGFFE1.37
WLAN_PCIE_TX_N_C: C6101.2 CPU1.CY3
WLAN_PCIE_TX_P: C6102.1 NGFFE1.35
WLAN_PCIE_TX_P_C: C6102.2 CPU1.CY4
XCLK_BIASREF: CPU1.DU6 R1819.1
XDP_PRDY#: CPU1.P6 TP9902.1
XDP_PREQ#: CPU1.M6 TP9901.1
XRF_TDC1: C3151.1 C3152.1 XF3101.15 XF3101.18 XF3101.21 XF3101.24
XTL_32K_X1_CPU: C1802.1 CPU1.DL48 R1811.1 X1801.1
XTL_32K_X2_CPU: C1801.1 CPU1.DL49 R1811.2 X1801.2
XTL_38D4M_X1_CPU: CPU1.DW8 ER1801.1
XTL_38D4M_X1_CPU_R: C1805.1 ER1801.2 R1820.1 X1802.3
XTL_38D4M_X2_CPU: CPU1.DU8 ER1802.1
XTL_38D4M_X2_CPU_R: C1806.1 ER1802.2 R1820.2 X1802.1

Pads without a net: CPU1 A4 A5 A7 A9 A12 A14 A33 A47 AA35 AB7 AB9 AD3 AD4 AD9 AE11 AF10 AG7 AH10 AJ6 AJ7 AJ9 AJ11 AK10 AL3 AL5 AL9 AL11 AM10 AN3 AN5 AN7 AN9 AN11 AP10 AR5 AR6 AR10 AT1 AT2 AU1 AU2 AV1 AV2 AV5 AV6 AY5 AY6 B7 B9 B12 B14 B33 B47 BB1 BB2 BB5 BB6 BC10 BD1 BD2 BF1 BF2 BF5 BF6 BF38 BG5 BG6 BG11 BH1 BH2 BH10 BJ5 BJ6 BJ11 BJ47 BL1 BL2 BL10 BM1 BM2 BM36 BM42 BP5 BP6 BP36 BP41 BP42 BR1 BR2 BT1 BT2 BT5 BT6 BT36 BV5 BV6 BW11 C1 C2 C7 C8 C9 C12 C33 CA11 CC45 CC47 CC48 CC49 CD3 CE46 CE47 CF3 CF5 CF45 CF47 CF49 CG32 CH33 CH48 CH49 CJ1 CJ2 CJ6 CJ7 CJ32 CJ39 CK33 CK46 CK47 CL3 CL5 CL32 CL41 CL43 CL47 CM33 CN32 CN41 CN42 CN43 CP3 CP5 CR38 CR39 CR41 CT6 CT7 CT32 CT38 CT41 CT49 CV6 CV7 CV32 CV37 CV39 CV41 CV43 CV47 CW3 CW5 CW33 CY6 CY7 CY35 CY37 CY38 CY39 CY43 D1 D2 D7 D8 D9 D12 D14 D33 DA3 DA5 DA6 DA7 DA45 DA48 DB10 DB37 DB39 DB41 DC45 DD1 DD2 DD3 DD5 DD38 DD39 DE3 DE4 DE49 DF37 DF38 DF41 DF45 DF48 DG38 DG40 DH47 DH49 DJ17 DJ22 DJ29 DJ34 DJ40 DK15 DK21 DK22 DK31 DK34 DK36 DK40 DL1 DL2 DL3 DL5 DL8 DL17 DL21 DL36 DL38 DN6 DN17 DN27 DN33 DN38 DN40 DN48 DP1 DP2 DP3 DP5 DP6 DP15 DP21 DP27 DP29 DP33 DP34 DP38 DP40 DR5 DT2 DT11 DT16 DT18 DT19 DT23 DT24 DT28 DT29 DT30 DT33 DT34 DT36 DT38 DT40 DT41 DU11 DU12 DU16 DU18 DU23 DU29 DU30 DU33 DU34 DU36 DU38 DU41 DU42 DV3 DV4 DV6 DV11 DV14 DV16 DV19 DV22 DV24 DV28 DV30 DV33 DV36 DV38 DV41 DV47 DW3 DW4 DW6 DW16 DW18 DW19 DW23 DW24 DW28 DW29 DW30 DW33 DW34 DW36 DW38 DW40 DW41 DW42 DW47 E1 E16 F6 F10 F13 F15 G6 G8 G10 G11 G13 G15 G34 H5 H34 J8 J11 J34 K6 K10 K13 L6 L8 L10 L11 L13 L34 M8 M11 M13 M34 M38 M41 N34 P10 R1 T6 T7 T9 T10 V1 V2 V3 V5 V6 V7 V39 V46 W35 Y6 Y7 Y11 Y34 Y39; D2401 2; D2403 1; D2701 2; DIMM1 87 88 91 92 95 97 100 101 104 105 162 165; DIMM2 87 88 91 92 95 97 100 101 104 105 162 165; ECIO1 13 16 24 52 53 60 61 84 85 99 100 101 105 106 107 108 109 110 111 112 113 114 115 116 117 118 119 120 122 126 127 128; ED3502 3 4; ED3505 3 4; ED5703 3; ED6101 3 4; HDMI1 13 14; LVDS1 5 6; MFG1 3; NGFFE1 6 8 12 16 20 38 40 42 46 48 62 64 66 68 70; NGFFM1 6 8 10 20 22 24 26 28 30 32 34 36 40 42 44 46 48 56 58 67; PU4503 19; PWRBT1 3 5 6; U2701 4 14 15 23 24 48; U3103 3; U3301 9 14 15 17 19 21; U3401 3; U3402 3; U3503 3; U3504 3; U4013 1; U5504 3

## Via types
v1: diameter 0.711, hole 0.356, TOP to BOTTOM, 1255 vias
v2: diameter 0.711, hole 0.406, TOP to BOTTOM, 536 vias
v3: diameter 0.508, hole 0.254, TOP to BOTTOM, 2813 vias
v4: diameter 0.457, hole 0.203, TOP to BOTTOM, 337 vias

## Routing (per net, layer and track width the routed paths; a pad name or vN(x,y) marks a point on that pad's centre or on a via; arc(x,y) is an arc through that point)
1V_CPU_CORE: length 146.1
  TOP w0.152: v3(168.47,62.77) 168.56,62.69 169.79,62.69 CPU1.AB1
  TOP w0.203: CPU1.U1 169.65,65.02 169.51,65.02 169.43,64.94 168.7,64.94 168.56,65.08 v3(168.09,65.08)
  TOP w0.254: CPU1.M1 168.79,67.67 168.62,67.5 v3(167.92,67.5)
  TOP w0.305: v3(167.95,70.23) 168.51,70.23 168.51,70.23 168.51,70.23 168.54,70.2 168.63,70.2 168.65,70.18 169.22,70.18 169.25,70.15 169.76,70.15 169.79,70.18 CPU1.G1
  TOP w0.508: v3(123.37,43.8) 122.85,43.8 PR4638.2 ; v3(73.2,30.79) 72.39,29.98 G2401.1
  L4 w0.508: 151.06,77.96 149.08,79.95 132.53,79.95 131.36,78.79 131.36,74.33 127.42,70.38 127.42,65.24 124.07,61.9 119.7,61.9 117.65,59.85 115.71,59.85 113.61,59.85 113.32,59.57 112.88,59.57 111.03,57.71 111.03,54.82 108.07,51.86 v3(108.07,45.06) 108.68,45.06 111.68,42.07 113.68,42.07 113.9,41.85 114.42,41.85 114.87,42.3 117.28,42.3 117.93,41.65 121.05,41.65 121.42,42.02 121.42,42.21 123.01,43.8 v3(123.37,43.8) ; v3(73.2,30.79) 73.2,31.28 75.52,33.59 75.52,35.23 76.55,36.26 76.55,36.64 v3(76.96,37.05)
  BOTTOM w0.508: v3(108.07,45.06) 105.98,47.15 104.18,47.15 104.05,47.29 102.15,47.29 102.15,47.28 101.61,47.28 101.54,47.21 100.27,47.21 100.09,47.03 99.89,47.03 95.92,43.06 95.92,38.54 92.82,35.44 81.94,35.44 80.33,37.05 80.32,37.05 v1(79.63,37.74) 78.31,37.74 77.88,37.3 77.21,37.3 v3(76.96,37.05)
  vias: v1(149.14,78.4) v1(149.54,60.18) v1(175.28,76.48) v1(175.44,78.72) v1(177.65,50.8) v1(179.66,76.54) v1(180.06,38.33) v1(181.86,77.54) v2(148.97,70.85) v2(149.88,70.85) v2(150.61,76.26) v2(150.64,61.95) v2(151.53,76.26) v2(151.56,67.86) v2(151.56,66.94) v2(151.55,61.95) v2(152.62,76.5) v2(152.62,75.48) v2(152.62,74.46) v2(152.62,73.45) v2(152.62,72.43) v2(152.62,71.42) v2(152.62,70.4) v2(152.62,69.38) v2(152.62,68.37) v2(152.62,67.35) v2(152.62,66.34) v2(152.62,65.32) v2(152.62,64.3) v2(152.62,63.29) v2(153.53,76.5) v2(153.53,75.48) v2(153.53,74.46) v2(153.53,73.45) v2(153.53,72.43) v2(153.53,71.42) v2(153.53,70.4) v2(153.53,69.38) v2(153.53,68.37) v2(153.53,67.35) v2(153.53,66.34) v2(153.53,65.32) v2(153.53,64.3) v2(153.53,63.29) v2(154.44,76.5) v2(154.44,75.48) v2(154.44,74.46) v2(154.44,73.45) v2(154.44,72.43) v2(154.44,71.42) v2(154.44,70.4) v2(154.44,69.38) v2(154.44,68.37) v2(154.44,67.35) v2(154.44,66.34) v2(154.44,65.32) v2(154.44,64.3) v2(154.44,63.29) v2(154.65,77.51) v2(155.36,76.5) v2(155.36,75.48) v2(155.36,74.46) v2(155.36,73.45) v2(155.36,72.43) v2(155.36,71.42) v2(155.36,70.4) v2(155.36,69.38) v2(155.36,68.37) v2(155.36,67.35) v2(155.36,66.34) v2(155.36,65.32) v2(155.36,64.3) v2(155.57,77.51) v3(175.02,43.34) v3(175.01,42.58) v3(175.03,41.24) v3(175.03,40.35) v3(176.29,64.61) v3(176.29,63.88) v3(178.1,72.84) v3(178.29,73.66) v3(179.01,70.89) v3(179.01,68.1) v3(179.06,73.64) v3(179.95,73.59) v3(179.93,72.84) v3(179.93,71.54) v3(179.93,70.89) v3(179.93,70.24) v3(179.93,68.11) v3(180.84,70.89) v3(180.86,73.59) v3(180.85,68.1) v3(181.73,73.57) v3(181.76,72.84) v3(181.76,72.19) v3(181.76,71.54) v3(181.76,70.89) v3(181.76,70.24) v3(181.76,69.59) v3(181.77,68.09) v3(182.68,73.49) v3(182.68,72.84) v3(182.68,72.19) v3(182.68,71.54) v3(182.68,70.89) v3(182.68,70.24) v3(182.68,69.59) v3(182.68,68.11) v3(183.59,72.84) v3(183.59,72.19) v3(183.59,71.54) v3(183.59,70.89) v3(184.27,38.16) v3(184.34,37.23) v3(184.36,39.08) v3(184.83,42.69) v3(185.94,36.31) v3(186.03,39.04) v3(186.13,44.72) v3(186.07,42.74) v3(186.15,43.67)
3V_5V_PWRGD: length 95.5
  TOP w0.102: D5301.K 141.28,31.55 141.38,31.65 v1(141.38,31.8) 141.38,32.14 141.1,32.42 139.2,32.42 v3(139.19,32.43) ; v3(117.15,22.62) 117.14,22.62 108.5,31.26 v3(108.5,36.87)
  L3 w0.127: v3(108.5,36.87) 108.83,37.21 108.83,49.32 108.75,49.41 108.75,52.64 110.84,54.74 110.84,57.85 113.28,60.29 113.28,70.9 v3(108.56,75.62)
  BOTTOM w0.102: v3(139.19,32.43) 138.75,31.98 134.01,31.98 131.75,29.72 126.77,29.72 119.67,22.62 v3(117.15,22.62) ; PR4511.1 PR4509.2 107.54,73.84 PR4510.2 107.55,74.61 v3(108.56,75.62)
3V_MIC2V: length 17
  TOP w0.203: R2723.2 34.49,78.55 v3(34.49,79.45) ; U2701.29 26.78,72.24 v1(26.52,72.49) 26.1,72.92 v3(25.7,72.92)
  L3 w0.203: v3(25.7,72.92) 25.75,72.92 25.75,75.6 28.82,78.66 33.7,78.66 34.49,79.45 v3(34.49,79.45)
5V_3D3V_S0_ON: length 8
  TOP w0.102: v3(45.6,84.47) 45.08,84.47 44.8,84.2 R4035.2 45.12,83.76 v1(45.86,83.01) 46.15,83.01 C4013.1 46.88,84.63 v3(46.86,84.65)
  BOTTOM w0.102: U4003.5 46.68,84.41 46.86,84.59 v3(46.86,84.65) ; U4003.3 45.88,84.2 v3(45.6,84.47)
5V_AUDIO_S0: length 16.9
  TOP w0.203: v3(30.48,66.5) 30.48,66.86 30.82,67.2 U2701.41 ; U2701.46 32.82,67.87 33.03,67.67
  TOP w0.254: 33.03,67.67 33.41,67.29
  TOP w0.508: 33.41,67.29 v3(33.84,66.85)
  BOTTOM w0.508: R2755.2 39.19,77.46 39.2,77.45 39.67,77.45 40.89,76.23 v1(40.89,75.04) 40.89,72.28 40.9,72.27 40.9,71.75 40.89,71.74 40.89,68.64 v3(39.55,67.3)
  vias: v1(32.33,66.86) v1(35.85,66.31)
5V_AUDIO_S0_S:
  vias: v1(37.05,63.6)
5V_AUX_S5: length 105.5
  TOP w0.305: v3(97.23,82.49) 97.24,82.49 97.24,82.47 97.26,82.49 100.47,82.49 103.49,79.46 103.49,78.52 103.06,78.08 101.41,78.08 101.12,77.79 RC4502.1 101.11,77.35 101.11,76.36 v1(100.98,76.23) 100.82,76.07 PG4533.2 ; R2712.2 31.36,79.17 31.82,79.64 31.82,80.21 33.45,81.84 37.66,81.84 v3(37.85,81.64)
  L4 w0.305: v2(74.98,79.17) 74.98,80.36 73.87,81.48 73.87,84.5 70.84,87.53 70.84,91.14 68.05,93.93 66.07,93.93 64.02,95.98 55.73,95.98 54.92,95.17 50.77,95.17 v2(47.53,91.92)
  BOTTOM w0.305: v2(74.98,79.17) 76.13,80.32 v1(80.89,80.32) 85.24,80.32 87.89,82.97 96.75,82.97 v3(97.23,82.49) ; v3(37.85,81.64) 37.85,86.28 38.64,87.06 42.72,87.06 43.97,88.3 46.33,88.3 46.63,88.6 v1(46.63,89.44) 46.63,91.02 v2(47.53,91.92)
5V_FANCTL1_FSM#: length 3.6
  BOTTOM w0.102: R2601.2 258.17,8.47 v1(257.72,8.02) 257.72,6.9 257.28,6.46 U2601.1
5V_HDD: length 5
  TOP w0.508: 3.8,70.48 SATA1.P8 5.48,70.48 ; 5.48,69.22 SATA1.P7 3.8,69.22 ; 3.8,71.75 SATA1.P9 5.48,71.75
  vias: v1(10.01,78.92)
5V_HDMI:
  vias: v1(57.91,55.17)
5V_HDMI_CONN: length 2
  TOP w0.305: 59.11,45.92 58.51,45.33 HDMI1.18
  vias: v1(56.55,53.94)
5V_PANEL_VCC:
  vias: v1(69.01,15.18) v2(33.79,11.18) v2(35.13,11.16) v2(68.21,13.35) v2(68.83,14.02)
5V_PVDD2: length 15.5
  TOP w0.203: U2701.26 27.8,73.44 27.39,73.85 27.39,73.98 26.92,74.46 26.92,74.46 v3(26.92,74.46)
  BOTTOM w0.508: R2755.1 36.3,76.86 34.32,76.86 v1(33.58,77.6) 33.2,77.98 29.56,77.98 C2711.1 29.2,77.63 28.36,77.63 27.89,77.15 C2710.1 27.39,76.67 26.88,76.16 26.88,74.5 v3(26.92,74.46)
5V_S0: length 291.7
  TOP w0.381: v3(115.6,11.35) 115.6,11.14 115.33,10.87 115.33,10.02 R6404.2
  TOP w0.508: v3(262.23,14.82) 262.01,15.03 R2606.1 ; Q5702.G 67.22,16.85 66.66,16.28 66.66,15.16 v2(64.14,12.64) ; v3(262.13,7.26) 262.13,6.25 260.72,4.84 254.97,4.84 v2(254.5,4.38)
  TOP w0.762: v2(136.83,3.14) 133.74,3.14 133.65,3.23 131.83,3.23 130.23,4.84 129.32,4.84 128.07,6.09 128.07,8.57 127.09,9.55 126.1,9.55 124.86,10.78 v2(124.86,11.65)
  L3 w0.762: v2(64.14,12.64) 64.34,12.44 72.05,12.44 72.8,11.68 80.96,11.68 81.87,12.59 85.43,12.59 85.74,12.9 91.21,12.9 92.42,11.7 93.05,11.7 93.72,11.03 98.42,11.03 99.07,10.38 100.44,10.38 102.2,12.14 105.33,12.14 108.04,9.42 113.66,9.42 v3(115.6,11.35) 115.89,11.65 v2(124.86,11.65)
  L4 w0.762: v2(49.55,63.04) 49.6,62.98 49.6,50.28 48.5,49.18 48.5,32.83 55.12,26.21 55.12,22.03 57.97,19.18 57.97,17.49 62.11,13.35 63.41,13.35 63.97,12.79 64,12.79 64.14,12.66 v2(64.14,12.64)
  BOTTOM w0.508: v3(262.23,14.82) 261.56,14.15 261.56,8.47 262.13,7.9 v3(262.13,7.26)
  BOTTOM w0.762: v2(136.83,3.14) 138.29,4.6 153.76,4.6 155.4,2.96 157.8,2.96 158.85,1.91 182.35,1.91 182.79,2.35 182.8,2.35 188.45,2.35 193.16,2.35 193.31,2.49 196.85,2.49 197.56,1.78 210.73,1.78 210.73,1.77 212.63,1.77 212.63,1.78 231.94,1.78 233.44,3.28 237.03,3.28 238.49,1.82 252.94,1.82 253.7,2.58 253.7,3.58 v2(254.5,4.38)
  vias: v1(47.38,65.13) v1(52.17,63.16) v1(54.83,63.07) v1(59.78,61.05) v2(12.61,81.58) v2(13.53,81.58) v2(44.54,70.42) v2(44.58,71.38)
5V_S5: length 340.8
  TOP w0.305: PU5301.21 132.68,38.38 v2(132.22,37.92)
  TOP w0.381: G6401.1 115.85,18.65 114.41,18.65 113.32,17.56 v2(113.32,17.56) ; U4012.3 159.82,47.27 159.67,47.43 v3(158.92,47.43) ; U5301.3 v2(16.25,79.63)
  TOP w0.508: v3(154.61,23.72) 154.61,23.16 155.33,22.43 v3(155.33,20.94) ; U3402.5 39.98,59.66 39.7,59.94 39.68,59.94 39.3,60.32 39.3,61.27 ; v3(74.79,31.12) 76.14,29.77 R24010.2 ; v3(142.85,34.39) 142.62,34.62 PR5001.1 ; v2(132.22,37.92) 132.08,38.05 PC5302.1 ; v3(121.17,59.91) 120.72,59.46 PR4609.1 ; 114.33,26.94 v2(116.34,26.94) ; v3(117.55,43.13) 116.92,43.13 116.49,43.56 PR4604.1 ; EC6915.1 69.91,24.24 70.42,24.24 v3(70.62,24.44) ; v3(224.81,94.59) 223.64,94.59 PR5109.1 ; PR5005.2 v3(144.3,45.64) ; EC6906.1 40.56,81.35 v3(40.61,81.35) ; R6402.1 124.08,9.27 123.71,9.64 123.71,11.49 123.36,11.83 121.54,11.83 121.2,12.18 121.2,14.83 120.29,15.74 G6401.1
  TOP w0.635: PR4604.1 115.87,42.28 115.23,41.64 110.76,41.64 110.16,42.24 109.15,42.24
  TOP w1.016: v2(249.8,2.7) 238.19,2.7 237.09,3.81 233.54,3.81 232.49,4.86 v2(225.47,4.86)
  TOP w1.524: 108.43,38.6 110.53,36.49 110.53,32.66 110.56,32.63 110.56,30.7 114.33,26.94
  L3 w0.508: v3(117.55,43.13) 117.73,43.13 118.17,43.56 121.44,43.56 122.32,44.44 124.33,44.44 124.84,43.93 124.84,42.54 123.45,41.15 123.45,40.19 123.96,39.68 125.35,39.68 125.81,39.23 125.81,36.59 126.38,36.02 131.25,36.02 131.64,36.41 131.64,37.34 v2(132.22,37.92)
  L3 w1.016: v2(188.32,9) 191.73,9 192.3,9.56 200.5,9.56 201.82,8.24 211.97,8.24 214.22,6 217.61,6 219.15,4.46 225.07,4.46 v2(225.47,4.86)
  L4 w0.635: v3(40.61,81.35) 39.1,82.85 19.47,82.85 v2(16.25,79.63) ; v3(144.3,45.64) 143.25,44.59 139.09,44.59 138.34,45.35 136.22,45.35 133.85,47.72 131.61,47.72 130.78,48.54 129.2,48.54 128.77,48.98 123.97,48.98 123.23,48.25 123.23,45.59 122,44.36 119.35,44.36 118.11,43.13 v3(117.55,43.13)
  BOTTOM w0.381: v3(154.61,23.72) 154.33,23.45 U4010.3 ; U4011.3 154.55,17.8 155.33,18.58 v3(155.33,20.94) ; 190.15,10.45 U4007.3 ; 153.21,40.76 152.06,39.61 150.7,39.61 146.41,35.32 144.07,35.32 143.14,34.39 v3(142.85,34.39)
  BOTTOM w0.508: v3(117.55,43.13) 117.9,43.13 119.33,44.55 119.33,47.21 121.49,49.37 123.26,49.37 124.64,50.74 124.64,56.44 v3(121.17,59.91) ; PR5422.1 116.04,27.75 116.34,27.44 v2(116.34,26.94) 116.34,25.84 116.94,25.24 118.82,25.24 119.53,25.95 PR5410.1 120.1,28.56 120.7,27.97 122.5,27.97 122.72,28.18 PR5413.1 ; v3(74.79,31.12) 74.79,30.27 73.69,29.17 70.69,29.17 70.47,28.95 70.47,27.87 ; v3(154.61,23.72) 154.61,23.75 154.59,23.78 154.59,27.71 153.89,28.4 153.89,40.09 153.21,40.76 153.21,46.49 ; v3(224.81,94.59) 224.81,94.46 225.07,94.19 PR5108.2 ; 153.21,46.49 149.66,46.49 148.58,45.41 148.02,45.41 147.57,44.96 144.98,44.96 v3(144.3,45.64) ; 153.21,46.49 154.21,47.48 158.87,47.48 v3(158.92,47.43) ; R3401.1 33.68,57.3 v3(33.36,56.97) ; 190.15,10.45 190.15,9.88 189.27,9 v2(188.32,9)
  BOTTOM w0.61: PU5201.6 258.27,26.22 258.59,26.53 PC5206.1 258.59,28.12 258.9,28.43 258.9,29.6 259.4,30.11
  BOTTOM w0.635: v2(113.32,17.56) 113.32,17.56 113.32,25.13 115.13,26.94 v2(116.34,26.94)
  vias: v1(32.45,59.39) v1(39.73,62.68) v1(77.43,75.39) v1(82.37,58.8) v1(205.43,93.21) v2(40.9,62.71) v2(41.3,84.58) v2(41.33,83.57) v2(41.67,63.27) v2(41.68,62.14) v2(42.21,84.53) v2(42.24,83.59) v2(70.73,26.77) v2(75.41,42.01) v2(76.2,42.78) v2(76.86,43.47) v2(90.34,59.17) v2(90.39,58.26) v2(90.41,57.3) v2(91.2,59.61) v2(91.21,58.66) v2(91.21,57.75) v2(96.57,58.48) v2(99.78,47.77) v2(161.93,82.52) v2(163.21,82.49) v2(184.42,98.26) v2(185.51,98.28) v2(203.42,95.52) v2(203.65,96.54) v2(204.65,93.68) v2(204.67,94.59) v2(257.32,91.26) v2(258.4,90.2) v2(258.45,91.32) v2(261.51,32.81) v3(79.98,78.22) v3(202.29,94.56) v3(205.43,95.04)
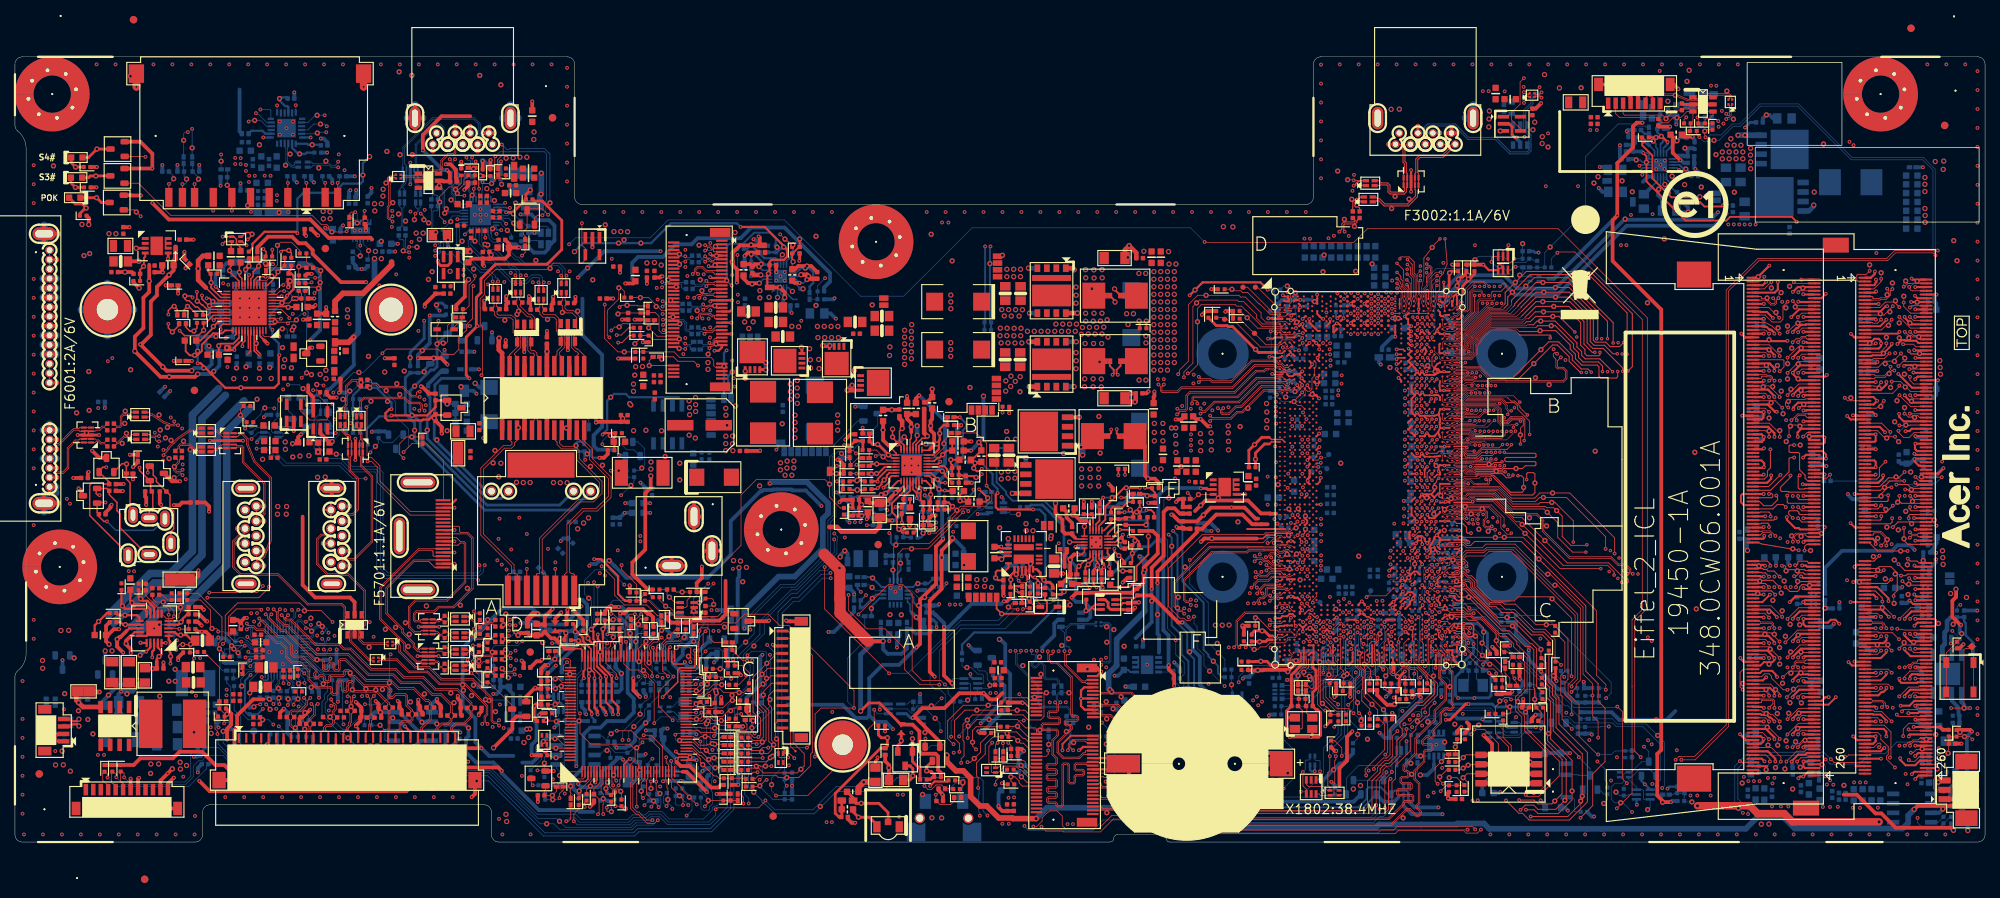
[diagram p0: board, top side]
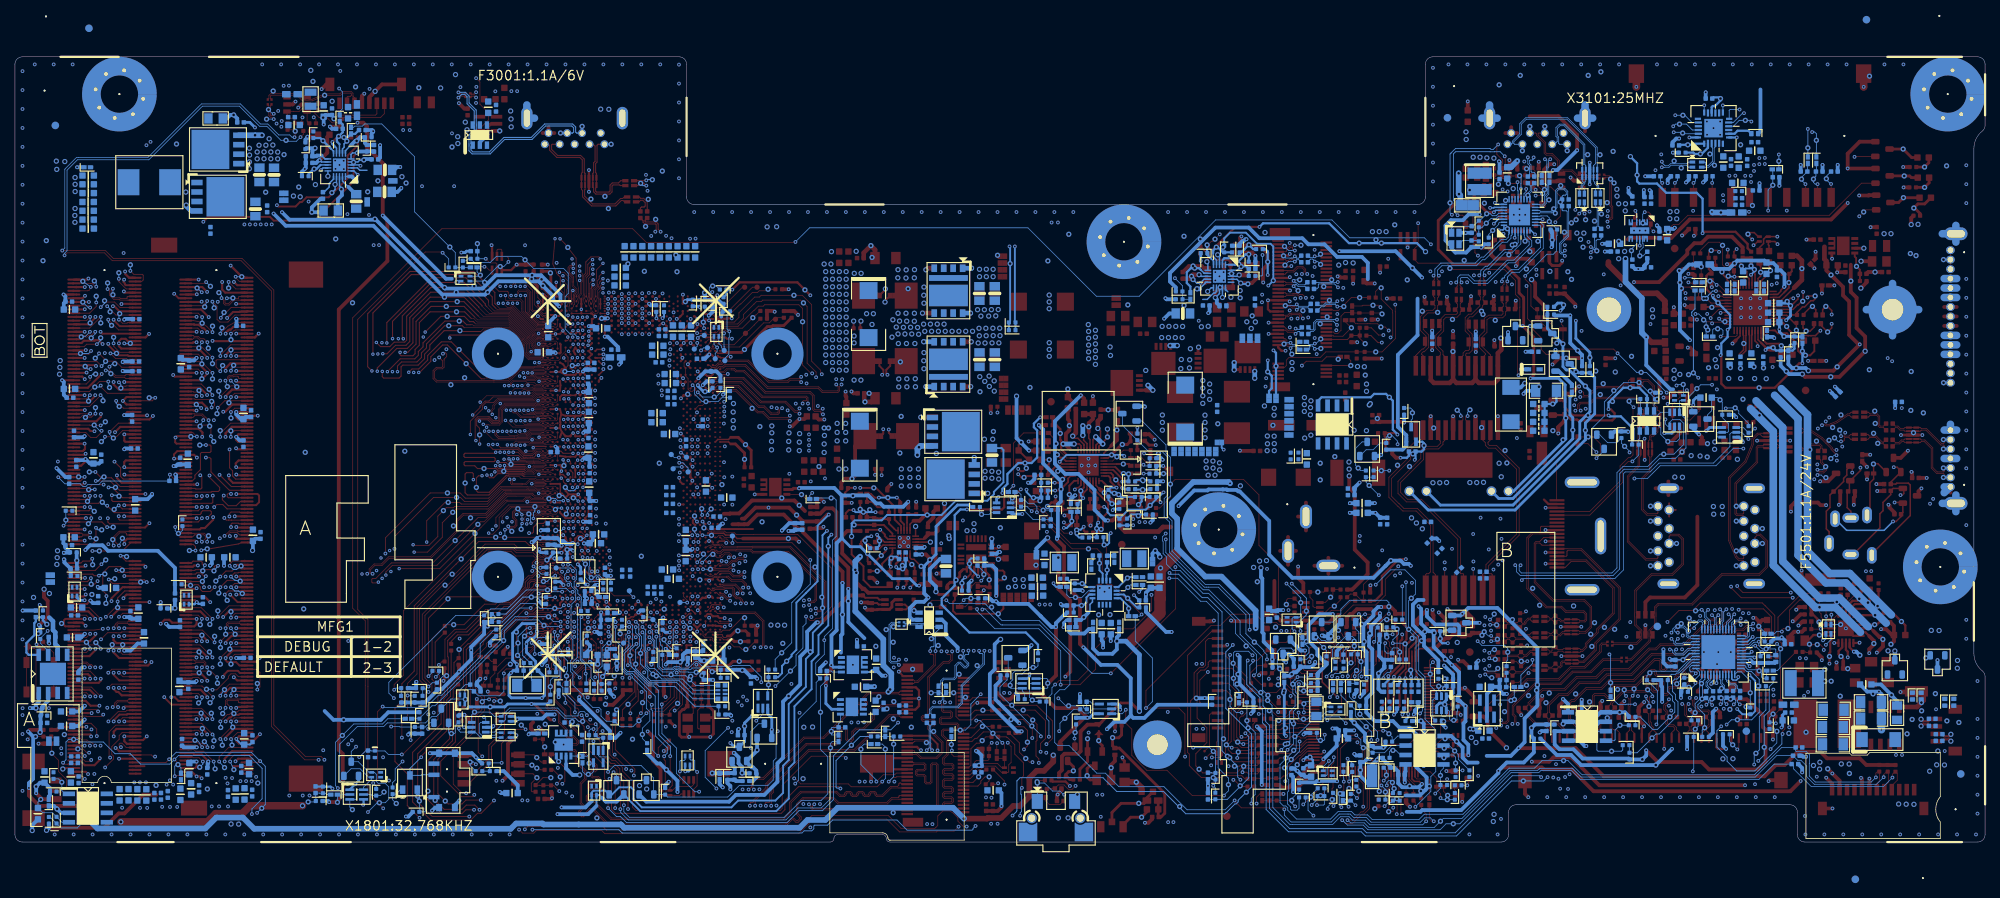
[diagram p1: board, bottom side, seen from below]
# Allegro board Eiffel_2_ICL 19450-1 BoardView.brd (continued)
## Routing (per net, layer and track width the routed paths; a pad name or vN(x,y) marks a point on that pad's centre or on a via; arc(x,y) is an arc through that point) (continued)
5V_STB: length 5
  TOP w0.203: 30.84,76.75 30.84,76.1 30.82,76.08 U2701.20
  TOP w0.508: R2710.1 R2712.1 31.34,77.27 ; 30.84,76.75 31.34,77.26 31.34,77.27 ; 31.34,77.27 v1(31.37,77.27)
5V_SUS1: length 3.6
  TOP w0.508: L6406.2 116.61,10.85 117.11,10.35 v1(117.11,9.96) R6407.2
5V_USB30E: length 2.4
  TOP w0.508: 191.71,95.08 USB3R2.1 ; USB3R2.1 192.5,95.87 ; USB3R2.1 193.29,95.08
  vias: v1(199.05,95.36) v2(197.52,96.96) v2(197.5,95.9) v2(197.58,98.04)
5V_USB30F: length 19.4
  TOP w0.508: USB3R1.1 63.5,95.87 ; USB3R1.1 64.29,95.08 ; USB3R1.1 62.71,95.08 ; ED3505.5 57.34,88.69 57.43,88.59 C3516.1 58.27,88.62 58.27,89.74 v3(57.9,90.11) ; 61.01,97.33 57.17,97.33 54.66,94.83 54.66,92.78 v3(54.67,92.77)
  BOTTOM w0.508: v3(54.67,92.77) 57.33,90.11 v3(57.9,90.11)
  vias: v1(79.11,82.77) v1(81.62,80.76) v2(69.53,94.22) v2(69.56,95.23) v2(80.27,81.86) v2(81.18,81.86) v2(82.09,81.85)
5V_USB30H: length 26.8
  TOP w0.254: 41.45,44.54 USB3R4.1 ; USB3R4.1 42.34,45.43 ; USB3R4.1 42.34,43.65
  TOP w0.508: ED3401.5 45.52,32.17 44.9,32.8 40.23,32.8 38.55,34.48 38.55,43.64
  L3 w0.508: USB3R4.1 42.34,45.43 ; USB3R4.1 42.34,43.65 ; USB3R4.1 41.45,44.54
  L4 w0.508: USB3R4.1 42.34,45.43 ; USB3R4.1 42.34,43.65 ; USB3R4.1 41.45,44.54
  vias: v1(37.23,51.64) v2(38.19,51.76) v2(39.39,51.82)
5V_USB30R: length 5.3
  L3 w0.508: 30.84,43.65 USB3R3.1 ; USB3R3.1 30.84,45.43 ; USB3R3.1 29.95,44.54
  L4 w0.508: USB3R3.1 30.84,45.43 ; USB3R3.1 30.84,43.65 ; USB3R3.1 29.95,44.54
  vias: v1(37.2,53.42) v2(35.22,45) v2(35.18,43.97) v2(36.22,53.65) v2(36.25,52.67) v2(36.4,45) v2(36.36,43.97)
19V_AD_JK: length 7.6
  TOP w0.508: DCIN1.3 89.87,37.05 ; DCIN1.3 88,35.98 ; DCIN1.3 86.13,37.05 ; DCIN1.3 88,38.12
  BOTTOM w0.508: EC4302.1 v3(85.12,45.44) ; EC4301.1 v3(85.13,44.15)
  vias: v1(81.44,56.8) v1(82.52,58.61) v1(89.09,50.8) v1(89.09,48.57) v2(82.9,55.17) v2(84.55,55.22) v2(86.64,55.16)
19V_ADP: length 17.8
  TOP w0.508: R4325.1 84.81,33.86 82.74,35.93 82.74,37.49 84.46,39.22 84.46,46.77 85.2,47.51 v2(85.2,49.1)
  vias: v1(87.14,51.69) v2(85.24,50.96) v2(85.22,50.01)
19V_ADP_GATE: length 20.4
  TOP w0.305: v3(78.75,54.65) 78.94,54.84 PR4301.1 80.45,54.4 80.23,54.19 PC4301.2 80.33,53.59 PR4304.1
  BOTTOM w0.305: v3(78.75,54.65) 78.75,54.7 79.36,55.31 79.36,59.18 v1(79.82,59.64) 80.27,60.09 81.87,60.09 82.32,59.64 88.92,59.64 89.38,59.18 PU4301.4
19V_BOOST_ISW: length 5.5
  TOP w0.305: U5501.19 19.15,26.1 19.62,25.63 19.62,25.2 v1(19.31,24.88) 19.02,24.59 19.02,24.24
  TOP w0.508: 19.02,24.24 C5501.1 17.46,23.27 R5535.2
19V_BOOST_ISW_R:
  vias: v1(15.01,19.87)
19V_BOOST_LDR: length 17.2
  TOP w0.305: U5501.1 20.6,27.1 20.75,26.95 20.75,25.48 20.85,25.37 v1(20.85,24.89) v3(20.85,23.93)
  TOP w0.635: v3(11.33,20.12) 10.24,20.12 R5533.2
  L3 w0.635: v3(20.85,23.93) 20.85,22.19 19.96,21.29 12.5,21.29 v3(11.33,20.12)
19V_BOOST_LDR_R: length 4.8
  TOP w0.635: Q5506.4 9.12,18.11 v1(8.53,18.7) 8.23,19 R5533.1
19V_BOOST_LX:
  vias: v1(10.45,14.5) v3(11.13,11.68) v3(11.94,11.68)
19V_BOOST_SNB: length 5
  BOTTOM w0.508: R5532.2 11.8,18.91 12.53,19.65 v1(12.53,19.71) 13.96,21.13 C5544.1
19V_DCBATOUT: length 61.5
  TOP w0.508: R24096.2 73.91,30.4 74.03,30.53 v3(74.03,31.14) ; PR4605.2 v3(128.12,52.5) ; v3(92.05,36.95) 92.05,35.43 91.35,34.73 R4324.1 92.52,33.53 R4318.1
  L3 w0.508: v3(80.79,39.12) 83.49,39.12 83.96,38.65 90.35,38.65 v3(92.05,36.95) ; v3(128.12,52.5) 126.39,50.78 126.39,46.79 127.34,45.84 128.04,45.84 128.04,45.84 130.24,45.84 131.35,44.73 134.57,44.73 136.17,43.12 v3(136.97,43.12)
  BOTTOM w0.203: PU4503.12 102.99,73.84 103.21,73.62 103.38,73.62 104.23,72.77 104.83,72.77
  BOTTOM w0.508: v2(129.78,59.79) 129.78,54.17 v3(128.12,52.5) ; R24018.1 73.26,24.38 75.18,26.3 75.18,27.61 76.67,29.1 76.67,31.84 76.05,32.46 75.23,32.46
  vias: v1(23.54,26.53) v1(125.59,77.93) v1(127.98,60.96) v1(177.25,89.98) v1(225.97,87.84) v1(227.94,92.19) v2(119.21,68.63) v2(119.21,67.71) v2(119.21,66.8) v2(119.21,65.88) v2(119.21,64.97) v2(119.21,64.06) v2(120.13,68.48) v2(120.13,67.56) v2(120.13,66.65) v2(120.13,65.73) v2(120.13,64.82) v2(120.17,69.39) v2(204.96,102.92) v2(224.35,103.49) v2(225.77,86.53) v2(226.68,86.64) v3(83.79,41.05) v3(83.82,40.32) v3(220.4,103.41)
19V_DCBATOUT_LCD: length 19.2
  TOP w0.508: v3(25.77,29.6) 25.65,29.6 24.72,30.52 R5506.1
  L4 w0.508: v3(26.23,15.39) 25,16.62 25,21.64 23.29,23.35 23.29,25.03 24.11,25.85 24.11,29.11 24.67,29.67 25.7,29.67 v3(25.77,29.6)
  vias: v1(20.62,21.57) v1(21.46,23.17) v1(21.48,21.56) v1(23.99,14.72) v2(26.29,14.58) v3(23.72,20.13) v3(24.25,19.62)
19V_DCBATOUT_LCD_BOOST: length 2.1
  TOP w0.305: U5501.18 18.65,25.78 18.4,25.53 v3(18.4,24.77)
  vias: v1(18.18,9.2) v1(18.4,23.25) v1(19.41,19.56) v2(18.21,10.46) v2(19.26,10.47)
19V_DCBATOUT_LCD_VIN: length 4.4
  TOP w0.305: R5506.2 23.06,30.52 22.47,29.93 22.47,29.72 v1(22.25,29.5) 21.9,29.15 U5501.4
  TOP w0.508: C5505.1 R5506.2
AV18: length 3.5
  BOTTOM w0.305: U3301.1 39.15,93.64 39.28,93.5 v1(39.84,93.5) 40.91,93.5 C3302.2
GND: length 2029.7
  TOP w0.127: CPU1.M5 171.46,67.74 171.94,68.22 172.56,68.22 v3(172.59,68.25) ; CPU1.BJ49 v4(193.79,49.31) ; 185.11,72.19 184.54,72.19 v3(184.52,72.17) ; CPU1.AH49 193.8,59.29 v4(193.89,59.2) ; v4(195.61,73.29) 195.61,71.14 193.9,69.44 193.9,69.44 CPU1.H49 ; v4(193.77,54.28) 193.76,54.29 CPU1.AV49 ; v4(193.77,61.78) 193.76,61.79 CPU1.AC49 ; CPU1.Y43 189.88,63.89 189.88,65.02 190.21,65.35 CPU1.T43 ; v4(193.82,46.77) 193.81,46.78 CPU1.BR49 ; CPU1.A42 189.41,73.78 v4(189.23,73.96) ; CPU1.A36 186.79,74.27 186.71,74.35 ; v3(193.87,35.68) 193.76,35.57 193.05,35.57 193.01,35.52 CPU1.CU49 ; 185.1,72.84 v3(184.51,72.84) ; v4(193.88,56.71) 193.81,56.79 CPU1.AN49 ; v3(193.81,66.8) 193.78,66.83 CPU1.N49 ; CPU1.E42 CPU1.E39 CPU1.E36 ; CPU1.V49 v4(193.75,64.3) ; v3(184.51,71.52) 184.53,71.54 185.1,71.54 ; v4(193.84,51.83) 193.8,51.79 192.91,51.79 CPU1.BD49 ; v3(194.06,28.24) 193.18,28.24 193.07,28.35 192.76,28.35 192.74,28.33 192.53,28.33 CPU1.DM47 ; CPU1.E34 184.56,70.89 v4(184.55,70.9)
  TOP w0.152: v3(193.88,32.43) 193.86,32.4 CPU1.DC49 ; v4(193.82,44.28) 193.82,44.28 CPU1.BY49 ; CPU1.DL47 192.09,28.62 192.75,29.28 CPU1.DK49 ; CPU1.B48 192.78,72.71 CPU1.A48
  TOP w0.18: v4(186.52,74.75) 186.71,74.56 186.71,74.35
  TOP w0.203: 185.55,71.51 CPU1.C34 CPU1.A34 ; CPU1.CK49 193.27,39.28 193.28,39.28 v3(193.74,39.28) 193.24,38.78 CPU1.CL49 ; CPU1.BA45 v4(191.57,53.04) CPU1.BA47 ; CPU1.DC49 192.88,32.76 CPU1.DB49 CPU1.DB47 ; CPU1.CU47 CPU1.CU49 ; v3(86.22,26.25) 86,26.03 ECIO1.71 ; v3(193.59,36.77) 193.53,36.77 193.53,36.77 CPU1.CR49 ; CPU1.BM45 190.92,48 190.92,46.82 CPU1.BR45 190.94,46.77 190.7,46.77 190.21,46.28 CPU1.BT43 ; CPU1.D49 193.39,71.4 193.91,71.93 193.91,72.37 v4(193.89,72.39) ; CPU1.AN43 CPU1.AN42 ; v4(189.21,42.99) 188.91,43.28 CPU1.CA41 ; v3(188.58,39.94) 188.58,40.16 188.48,40.27 188.48,40.47 CPU1.CG39 ; CPU1.CA38 187.15,42.98 CPU1.CB37 ; CPU1.CA38 187.61,43.25 ; CPU1.CA38 187.15,43.9 CPU1.BY37 ; v3(88.56,12.14) 88.91,11.78 ECIO1.35 ; NGFFE1.18 135.96,18 135.3,18.66 v3(135.04,18.66) ; CPU1.BD38 187.78,51.67 187.79,51.68 188.17,51.68 188.17,51.67 CPU1.BD39 ; CPU1.BD43 CPU1.BD42 CPU1.BD41 ; v3(194.16,29.29) 194.18,29.3 195.13,29.3 195.47,28.97 195.47,28.51 195.45,28.5 195.45,27.74 195.25,27.53 194.69,27.53 194.38,27.84 194.38,27.91 v3(194.06,28.24) ; CPU1.DP45 191.13,27.17 190.79,27.51 190.79,28.19 v3(190.85,28.25) ; CPU1.BJ43 190.57,49.28 CPU1.BJ45 ; v3(77.76,7.99) 77.76,8.09 78,8.32 ECIO1.6 ; v3(194.04,34.42) 193.72,34.42 193.62,34.32 192.96,34.32 CPU1.CY49 ; CPU1.DJ27 182.17,29.84 182.07,29.84 181.93,29.98 181.65,29.98 181.43,30.2 181.11,30.2 180.93,30.39 180.93,30.41 CPU1.DG23 ; CPU1.BG41 CPU1.BJ41 ; CPU1.AG39 v4(187.87,60.36) CPU1.AG38 ; CPU1.CE49 v3(193.54,41.78) ; CPU1.AG43 CPU1.AG42 CPU1.AG41 188.57,60.3 188.57,60.31 v4(188.56,60.32) ; v3(142.11,39.57) 142.36,39.82 PU5001.14
  TOP w0.229: v4(188.1,71.44) 188.1,71.44 CPU1.E39
  TOP w0.254: CPU1.DE23 180.87,31.89 v3(180.48,32.28) 180.47,32.27 180.45,32.27 180.04,31.86 CPU1.DE22 ; v3(242.68,51.42) 242.68,51.99 242.24,52.42 DIMM2.94 ; CPU1.CG47 CPU1.CG45 ; CPU1.CG45 190.96,40.72 v3(190.53,41.15) 190.48,41.15 190.21,40.88 CPU1.CG43 189.75,39.88 CPU1.CJ42 189.72,39.37 189.72,38.77 CPU1.CL42 ; CPU1.CG45 v3(190.74,39.76) 190.74,39.5 CPU1.CK45 ; CPU1.A44 CPU1.A46 191.46,73.18 v4(191.46,75.06) ; CPU1.Y9 173.82,63.91 v3(173.82,64.08) 173.82,64.15 CPU1.V9 ; CPU1.J16 177.19,68.8 CPU1.K15 176.66,68.4 CPU1.J15 177.02,69.55 v3(177.13,69.55) 177.36,69.55 CPU1.H17 ; v3(168.88,28.88) 169.36,28.88 169.46,28.98 170.05,28.98 170.11,29.04 CPU1.DK3 CPU1.DK4 ; 172.58,28.71 CPU1.DK6 ; 172.58,28.71 v3(172.58,28.23) ; 172.58,28.71 172.58,28.79 172.66,28.87 172.74,28.87 CPU1.DK8 ; CPU1.M3 CPU1.M5 ; 190.77,57.35 CPU1.AN43 ; 190.77,57.35 CPU1.AN45 190.96,56.37 190.9,56.32 190.9,56 190.96,55.95 CPU1.AT45 ; 190.77,57.35 CPU1.AL45 v4(191.44,58.04) CPU1.AL47 ; CPU1.CY45 190.68,34.27 v3(190.49,34.46) 190.49,34.68 190.62,34.82 190.62,35.19 CPU1.CU45 ; CPU1.B2 170.15,72.53 170.51,72.53 170.52,72.52 CPU1.B3 170.7,72.83 170.6,72.93 CPU1.A3 170.06,73.16 v3(169.89,73.33) ; CPU1.BT43 189.95,46.46 189.79,46.63 ; CPU1.C11 CPU1.A11 174.51,73.39 v3(174.49,73.41) ; v3(180.81,27.46) 181.22,27.87 CPU1.DN24 ; v3(174.8,52.98) CPU1.BB11 ; CPU1.DL47 192.26,28.3 CPU1.DM47 ; CPU1.P8 173.14,66.6 v3(173.46,66.92) ; v3(189.33,32.67) 189.33,32.44 CPU1.DD42 ; DIMM1.44 v3(254.66,64.92) ; CPU1.D44 190.96,71.06 CPU1.F45 191.1,70.53 v4(191.59,70.53) 191.75,70.69 CPU1.F47 ; DIMM1.260 255.1,8.92 v3(254.64,8.46) ; CPU1.AF47 191.53,60.54 191.5,60.57 v4(191.5,60.57) 191.47,60.54 CPU1.AF45 190.89,61.24 CPU1.AC45 ; v3(173.1,46.62) 173.1,46.46 CPU1.BT7 ; CPU1.BT39 188.31,46.27 188.42,46.46 v4(188.52,46.63) ; v3(179.88,29.55) 179.88,29.56 179.63,29.82 CPU1.DJ21 CPU1.DJ19 ; CPU1.DG47 192.1,30.39 v3(191.68,30.39) 191.68,30.33 CPU1.DH45 ; CPU1.DJ36 187.07,29.5 v3(187.2,29.5) ; v3(174.99,45.27) CPU1.BV11 ; v3(189.27,43.89) CPU1.CA42 CPU1.CA43 190.96,44.19 CPU1.BY45 ; v3(250.76,16.17) 250.76,16.32 250,17.09 249.01,17.09 248.92,17.17 DIMM1.227 ; CPU1.CT37 187.06,35.87 187.49,36.28 187.85,36.28 CPU1.CT39 ; CPU1.CT37 186.93,35.87 186.67,36.12 v3(186.67,36.29) 186.96,36.57 CPU1.CR37 ; CPU1.CT37 CPU1.CV35 185.92,35.34 185.92,35.39 v3(185.92,35.39) 185.91,35.39 185.66,35.14 CPU1.CV34 ; CPU1.L42 189.56,68.24 v4(189.22,68.57) ; CPU1.DU15 176.63,25.71 176.77,25.86 176.77,25.9 ; 189.16,46.63 189.79,46.63 ; 189.16,46.63 189.31,46.46 CPU1.BT42 ; 189.16,46.63 v4(188.52,46.63) ; 189.79,46.63 CPU1.BP43 ; CPU1.CH3 170.65,40.35 170.97,40.35 v3(170.99,40.37) 170.99,40.36 170.99,40.35 171.29,40.35 CPU1.CH5 ; v3(178.95,28.17) 178.83,28.17 CPU1.DN19 ; CPU1.DV8 173.68,25.41 CPU1.DU10 ; 176.77,25.9 176.77,25.97 176.63,26.12 CPU1.DT15 ; 176.77,25.9 v3(176.8,25.9) ; CPU1.AB5 171.22,62.48 170.72,62.48 CPU1.AB3 ; DIMM2.256 239.86,9.92 239.67,10.12 v3(239.67,10.8) 240.21,10.8 240.34,10.92 DIMM2.252 ; CPU1.BF47 191.65,50.54 191.59,50.48 v4(191.56,50.48) 191.55,50.48 191.49,50.54 CPU1.BF45 190.77,50.34 v4(190.77,49.74) 190.96,49.55 CPU1.BJ45 ; CPU1.DL10 174.23,28.24 174.37,28.24 v3(174.4,28.21) ; CPU1.AN42 CPU1.AN41 ; CPU1.AN41 188.91,57.02 v4(189.27,56.67) ; CPU1.AN41 CPU1.AN39 v4(187.86,57.6) CPU1.AN38 CPU1.AM37 CPU1.AK37 CPU1.AH37 CPU1.AG38 CPU1.AF37 CPU1.AD37 ; CPU1.J13 176.23,69.68 v3(176.23,70.13) ; CPU1.CB47 v4(191.63,43.03) CPU1.CB45 ; DIMM1.209 250.02,21.67 250.78,22.43 v3(250.78,22.71) ; CPU1.DB35 186.31,33.12 186.7,33.5 187.23,33.5 CPU1.DB38 187.61,33.1 187.36,32.85 187.36,32.68 v3(187.36,32.67) 187.36,32.67 187.21,32.52 187.21,32.51 187.2,32.5 187.2,32.5 186.96,32.25 CPU1.DD37 186.96,31.94 CPU1.DF35 ; 234.3,13.83 234.3,13.5 234,13.19 233.65,13.19 233.63,13.17 DIMM2.243 ; v3(235.15,33.17) 234.16,32.17 DIMM2.167 ; CPU1.H45 190.96,69.13 190.57,68.74 v4(190.57,68.55) ; v4(188.52,46.63) 188.67,46.46 CPU1.BT41 ; CPU1.DU10 CPU1.DT10 CPU1.DT8 ; CPU1.DU10 CPU1.DW10 174.01,24.37 173.91,24.28 v3(173.91,23.79) ; CPU1.DE45 190.96,32.03 190.62,32.37 v3(190.62,32.65) 190.62,32.68 CPU1.DB45 ; CPU1.V45 190.54,64.06 CPU1.Y43 190.74,63.4 CPU1.AA45 ; v3(180.45,30.8) 180.13,31.12 CPU1.DF22 ; DIMM1.27 249.95,69.17 250.78,70 v3(250.78,70.05) ; NGFFM1.15 93.06,77.15 v3(92.96,77.24) ; CPU1.W37 186.89,64.28 CPU1.V36 CPU1.U37 CPU1.T36 CPU1.R37 187.06,65.86 v4(186.74,66.18) ; CPU1.W37 CPU1.Y36 ; CPU1.W37 CPU1.Y38 v4(187.89,63.1) ; CPU1.V11 174.56,64.71 v3(174.56,64.94) 174.56,64.95 174.56,65.06 174.78,65.27 CPU1.T11 ; CPU1.G3 170.77,70.15 170.95,69.96 v3(170.99,69.96) 171.28,69.96 CPU1.G5 ; DIMM1.43 248.78,65.17 248.88,65.27 250.12,65.27 251.49,66.65 v3(251.49,66.81) ; CPU1.DE33 184.94,31.77 v3(184.61,31.44) 184.92,31.12 CPU1.DF33 ; v3(249.35,70.06) 249.35,70.08 249.26,70.17 DIMM1.23 ; CPU1.DT27 CPU1.DU27 CPU1.DW27 v3(181.87,23.71) ; CPU1.AT45 190.71,54.99 ; CPU1.AT45 190.99,55.51 v4(191.49,55.51) 191.52,55.54 CPU1.AT47 ; CPU1.DN36 186.44,28.19 v3(186.35,28.19) ; v4(190.57,68.55) 190.96,68.16 CPU1.L45 v4(191.57,68.13) CPU1.L47 ; v4(190.57,68.55) 190.57,68.5 CPU1.L43 ; CPU1.DF39 188.62,31.66 v3(188.62,31.78) ; CPU1.U3 170.67,65.39 v3(170.96,65.39) ; CPU1.F8 172.89,70.5 v3(172.56,70.16) ; v3(183.52,29.5) 183.84,29.82 CPU1.DJ31 CPU1.DJ33 ; CPU1.DJ42 189.23,29.55 v3(189.07,29.55) ; v3(191.7,38.04) 191.68,38.03 CPU1.CM45 ; v3(194.16,29.29) 194.15,29.28 CPU1.DK49 ; CPU1.R3 170.96,65.72 v3(170.96,65.39) ; v3(171.83,61.27) 171.83,61.18 CPU1.AE6 ; CPU1.DV44 CPU1.DW44 190.4,23.39 v3(190.36,23.36) ; CPU1.L39 v4(188.52,68.59) 188.52,68.53 CPU1.L41 ; 190.71,54.99 190.33,54.55 CPU1.AV43 CPU1.AV42 189.56,54.49 v4(189.2,54.85) 188.91,54.56 CPU1.AV41 CPU1.AV39 ; 190.71,54.99 190.87,54.55 CPU1.AV45 ; v4(188.5,65.85) 188.91,66.26 CPU1.P41 189.02,66.1 189.16,65.85 189.01,65.59 CPU1.T41 ; v3(189.14,35.42) 189.56,35.83 CPU1.CT42 ; CPU1.BD39 v4(188.52,52.12) 188.68,51.94 CPU1.BD41 ; v3(184.16,36.4) 184.54,36.78 CPU1.CR32 ; CPU1.N45 190.87,66.74 190.87,65.64 CPU1.T45 v4(191.54,65.58) 191.57,65.55 CPU1.T47 ; CPU1.AH45 190.96,59.3 190.96,59.67 190.7,59.94 190.32,59.94 190.28,59.91 CPU1.AG43 ; CPU1.BW37 CPU1.BY37 ; CPU1.DT32 184.67,26.21 v3(184.67,25.91) 184.67,25.59 CPU1.DU32 ; v3(174.77,54.78) 174.77,54.78 CPU1.AV11 ; CPU1.AG39 188.34,59.93 188.56,60.3 188.56,60.31 v4(188.56,60.32) ; CPU1.A48 193.05,73.44 193.35,73.44 193.35,73.44 v4(193.34,73.44) 193.24,73.34 CPU1.A49 CPU1.C49 ; CPU1.DN15 176.44,28.13 v3(176.25,28.13) 176.2,28.13 175.8,28.52 CPU1.DL13 175.45,28.19 v3(175.33,28.19) ; CPU1.DT42 189.73,26.1 189.92,25.91 v3(189.92,25.91) ; DIMM2.90 242.35,53.42 242.53,53.6 242.53,54.2 v3(242.48,54.25) ; v4(187.89,63.1) CPU1.AB39 v4(188.54,63.14) 188.54,63.08 CPU1.AB41 CPU1.AB42 CPU1.AB43 CPU1.AA45 ; v4(187.89,63.1) CPU1.AB38 ; v3(252.52,68.43) 252.27,68.17 DIMM1.31 ; NGFFE1.33 141.48,14.25 140.37,13.14 v3(140.37,12.29) ; v3(185.41,62.24) 185.76,61.89 CPU1.AD34 ; CPU1.DR49 193.73,26.85 v3(193.74,26.83) ; CPU1.A39 CPU1.C39 188.1,71.44 v4(188.1,71.44) ; v3(168.9,30.04) 169.58,30.04 CPU1.DH1 CPU1.DH3 170.48,30.28 170.77,30.57 171.17,30.57 171.18,30.57 171.18,30.57 171.46,30.29 CPU1.DH5 ; v3(253.14,63.84) 253.25,63.96 254.07,63.96 254.11,63.92 DIMM1.48 ; CPU1.CA7 172.85,43.44 173.16,43.13 173.16,42.82 172.87,42.52 CPU1.CC7 ; v3(170.96,65.39) 171.28,65.39 CPU1.U5 ; CPU1.BG41 188.91,50.01 v4(189.23,50.33) ; CPU1.DU47 191.94,25.71 CPU1.DU48 192.61,25.06 CPU1.DV48 192.78,24.89 CPU1.DW48 193.38,23.83 v3(193.38,23.74) ; v3(174.47,62.2) 174.78,62.51 CPU1.AB11 ; v3(253.89,32.38) 254.35,31.93 254.44,31.93 254.45,31.92 254.87,31.92 254.88,31.93 DIMM1.168 ; v4(191.5,63.09) 191.5,63.08 ; 191.5,63.08 191.65,63.08 191.69,63.05 CPU1.AA47 ; 191.5,63.08 191.34,63.08 191.31,63.05 CPU1.AA45 ; v3(188.57,37.24) 188.57,37.38 CPU1.CN39 ; DIMM1.176 257.24,29.93 257.43,29.74 257.43,29.1 257.25,28.93 DIMM1.180 ; CPU1.C6 172.2,72.03 v3(172.2,71.71) 172.04,71.55 CPU1.E6 ; CPU1.CG39 187.93,40.36 187.93,40.23 v3(187.74,40.04) 187.72,40.01 187.22,40.01 187.16,40.07 ; CPU1.BD45 CPU1.BD43 ; CPU1.DT37 186.95,26.22 v3(186.95,25.9) 186.95,25.57 CPU1.DU37 ; CPU1.E36 186.68,70.89 186.44,70.65 186.4,70.65 v4(186.23,70.48) 186.57,70.14 CPU1.G36 CPU1.H36 v4(187.11,69.18) CPU1.J36 v4(187.1,68.5) CPU1.L36 v4(187.1,67.85) CPU1.M36 v4(187.1,67.2) ; DIMM1.222 254.79,18.42 v3(254.64,18.27) ; DIMM1.256 257.39,9.92 257.52,9.8 v2(257.59,9.8) ; v3(174.98,48.85) 174.86,48.73 174.86,48.34 174.53,48.01 CPU1.BM11 ; v3(173.46,70.15) 173.46,69.66 CPU1.J10 174.57,68.55 CPU1.K11 ; DIMM2.222 243.01,18.42 243.99,19.41 v3(243.99,19.43) ; CPU1.DW46 191.47,23.98 191.62,23.83 v3(191.62,23.83) ; CPU1.BU47 192.11,45.65 v3(191.73,45.65) 191.61,45.53 CPU1.BU45 ; v3(178.7,23.8) 178.83,23.8 179.23,24.2 179.23,24.22 179.25,24.23 CPU1.DW20 CPU1.DU20 ; DIMM1.22 v3(254.64,70.42) ; CPU1.J6 172.36,69.47 v3(172.55,69.47) 172.55,69 CPU1.K8 ; v3(187.88,42.99) 187.61,43.25 ; CPU1.DT7 CPU1.DU7 CPU1.DW7 172.7,23.8 v3(172.68,23.79) ; v3(145.56,22.85) 144.96,22.25 NGFFE1.1 ; CPU1.DT20 178.91,26.73 v3(178.91,26.79) ; v3(184.96,67.77) CPU1.K33 CPU1.H33 ; CPU1.AU37 187.15,54.88 CPU1.AV38 187.61,54.63 v4(187.85,54.87) ; DIMM2.201 233.91,23.67 234.36,24.12 235.5,24.12 235.76,24.38 v3(235.76,24.67) ; v3(189.05,27.51) 189.15,27.51 CPU1.DN42 ; CPU1.E11 174.51,70.82 CPU1.F11 175.17,70.16 v3(175.32,70.16) ; CPU1.DN31 184.32,27.57 184.42,27.57 v3(184.42,27.56) ; CPU1.BM47 CPU1.BM45 ; CPU1.AG11 174.41,59.85 v3(174.75,59.5) ; DIMM1.56 v3(257.67,61.92) ; CPU1.CR45 190.96,36.52 v3(190.68,36.25) ; CPU1.CN3 170.77,37.7 v3(170.96,37.52) 171.28,37.52 CPU1.CN5 ; DIMM1.5 249.15,74.67 249.27,74.8 249.27,74.93 249.45,75.11 249.45,75.39 249.42,75.43 249.42,75.42 v3(249.37,75.42) ; v3(235.76,16.17) 235.76,16.24 235.74,16.24 235.27,16.71 235.09,16.71 234.74,17.05 234.02,17.05 233.9,17.17 DIMM2.227 ; DIMM2.22 v3(239.67,70.42) ; CPU1.BC37 CPU1.BD38 ; DIMM2.205 233.85,22.67 234.14,22.96 235.44,22.96 235.48,22.92 235.5,22.92 235.94,22.48 235.94,22.33 v3(236.13,22.14) ; CPU1.DT49 CPU1.DU49 ; CPU1.BH37 v4(187.85,49.39) ; CPU1.DL44 190.59,28.52 v3(190.85,28.25) ; CPU1.G49 193.51,70.11 v3(193.92,70.52) ; CPU1.CY41 188.91,34.12 v3(188.58,34.45) ; v3(245.98,32.17) DIMM1.167
  TOP w0.279: DIMM1.64 v3(254.66,59.92) ; DIMM2.60 239.18,60.92 238.26,60 238.26,59.95 v3(238.25,59.95) ; v3(254.43,15.44) 254.45,15.42 DIMM1.234 ; DIMM2.5 234.21,74.67 v3(234.65,75.12) ; v3(254.15,75.56) 254.29,75.42 DIMM1.2 ; v3(235.76,24.67) 235.76,24.74 234.83,25.67 DIMM2.193 ; DIMM1.201 246.17,23.67 v3(245.7,24.14) ; DIMM2.192 239.32,25.92 238.27,24.87 238.27,24.75 v3(238.24,24.75) ; DIMM2.217 234.28,19.67 234.33,19.63 v3(234.34,19.63) ; DIMM2.230 239.72,16.42 v3(239.67,16.48) ; DIMM1.78 253.09,56.42 252.48,57.04 v3(252.48,57.41) ; DIMM2.9 235.81,73.67 236.23,74.1 v3(236.23,75.11) ; v3(254.64,19.53) 254.74,19.42 DIMM1.218 ; DIMM1.94 254.91,52.42 254.74,52.6 254.72,52.6 254.61,52.7 254.61,53.37 v3(254.66,53.42) DIMM1.90 ; DIMM1.252 255.26,10.92 254.64,10.3 253.35,10.3 252.63,11.01 v3(252.63,11.24) ; DIMM2.52 v3(239.66,62.92) ; v3(239.65,14.51) 239.65,14.52 239.75,14.42 DIMM2.238 ; DIMM2.6 238.89,74.42 v3(238.25,73.78) ; DIMM1.72 v3(254.64,57.92) ; DIMM1.52 254.47,62.92 254.43,62.97 254.4,62.97 v3(254.4,62.96) ; v3(242.48,54.25) 242.31,54.42 DIMM2.86 ; DIMM1.15 249.7,72.17 v3(249.72,72.15) ; DIMM2.56 239.09,61.92 238.24,62.77 v3(238.24,62.92) 238.24,62.99 239.18,63.92 DIMM2.48 ; DIMM1.35 248.86,67.17 249.18,67.49 249.73,67.49 250.06,67.16 v3(250.06,66.88) 250.06,66.5 249.74,66.17 DIMM1.39 ; DIMM1.210 254.96,21.42 254.89,21.35 252.78,21.35 252.5,21.63 v3(252.5,21.9) ; v3(258.42,50.14) 257.71,49.42 DIMM1.106 ; v3(249.35,22.71) 249.32,22.67 DIMM1.205 ; DIMM1.40 254.56,65.92 v3(254.51,65.97) ; DIMM1.93 v3(249.35,52.67) ; v3(254.63,11.54) 255.02,11.92 DIMM1.248 ; v3(250.59,54.96) 249.88,55.67 DIMM1.81 ; v3(251.1,30.21) 251.09,30.21 250.12,31.17 DIMM1.171 ; v3(238.24,64.93) 238.28,64.93 238.28,65.05 239.15,65.92 DIMM2.40 ; DIMM2.106 242.36,49.42 v3(242.49,49.29) ; DIMM1.243 249,13.17 249.34,13.52 v3(249.34,14.17) DIMM1.239 ; v3(242.68,51.42) DIMM2.98 ; DIMM1.36 255.07,66.92 254.76,67.23 253.32,67.23 253.24,67.31 252.79,67.31 252.27,66.79 v3(252.26,66.79) ; DIMM1.175 v3(249.34,30.17) ; DIMM2.10 239.66,73.42 v3(239.63,73.46) ; DIMM1.69 249.05,58.68 v3(249.53,59.16) 249.53,59.19 249.05,59.68 DIMM1.65 ; DIMM2.202 239.66,23.42 v3(239.66,23.43) ; DIMM1.202 254.66,23.42 v3(254.66,23.43) ; DIMM2.166 239.88,32.42 v3(239.63,32.17) 239.88,31.93 DIMM2.168 ; v3(237.52,67.21) 237.49,67.17 DIMM2.35 ; DIMM2.72 240.11,57.92 240.06,57.87 v3(239.67,57.87) ; DIMM1.166 254.66,32.42 v3(254.66,32.43) ; DIMM2.44 v3(239.67,64.92) ; DIMM2.30 239.66,68.42 v3(239.66,68.43) ; DIMM2.239 233.97,14.17 234.3,13.85 234.3,13.83 v3(234.34,13.83) ; DIMM1.217 249.69,19.67 250.14,20.13 250.39,20.13 250.78,20.52 v3(250.78,20.67) ; DIMM1.14 v3(254.09,72.42) ; DIMM2.181 v3(234.34,28.67) ; v3(238.31,58.04) 238.3,58.04 238.3,58.3 238.93,58.92 DIMM2.68 ; v3(249.34,49.28) 249.23,49.17 DIMM1.107 ; v3(250.78,61.7) 250.78,61.38 250.07,60.68 DIMM1.61 ; v3(236.1,30.17) 235.1,31.17 DIMM2.171 ; DIMM1.86 v3(254.66,54.42) ; v3(239.64,12.71) 239.86,12.92 DIMM2.244 ; v3(253.93,21.9) 253.93,22.22 254.21,22.5 254.99,22.5 255.07,22.42 DIMM1.206 ; v3(234.36,17.98) 234.36,17.98 234.23,18.11 233.89,18.11 233.89,18.12 232.96,18.12 DIMM2.223 ; v3(238.08,10.8) 238.08,10.85 238.96,11.72 239.95,11.72 240.15,11.92 DIMM2.248 ; v3(250.79,27.61) 250.79,27.07 250.39,26.67 DIMM1.189 ; v3(239.67,24.75) 239.69,24.75 239.87,24.92 DIMM2.196 ; v3(254.64,27.93) DIMM1.184 ; v3(234.44,10.83) 234.09,11.17 DIMM2.251 ; v3(254.64,25.92) DIMM1.192 ; v3(238.91,54.33) 238.87,54.33 238.87,54.92 239.37,55.42 DIMM2.82 ; DIMM2.247 234.89,12.17 235.89,11.17 v3(235.89,10.81) ; DIMM1.68 254.13,58.92 253.24,59.82 v3(253.24,59.92) ; v3(239.38,75.42) DIMM2.2 ; DIMM1.6 v3(254.64,74.42) ; DIMM1.231 v3(249.34,16.17) ; v3(235.57,70.28) 235.57,70.28 234.76,71.09 233.92,71.09 233.89,71.12 232.96,71.12 DIMM2.19 ; v3(253.24,29.93) 253.24,30.01 254.15,30.93 DIMM1.172 ; DIMM1.98 254.61,51.42 v3(254.54,51.36) 254.54,51.27 254.58,51.24 254.58,51.02 255.11,50.48 255.34,50.48 255.39,50.42 DIMM1.102 ; v3(238.24,16.48) 238.23,16.48 238.25,16.48 238.25,16.6 239.07,17.42 DIMM2.226 ; v3(253.72,17.29) 254.29,17.29 254.29,17.3 255.02,17.3 255.15,17.42 DIMM1.226 ; DIMM1.89 249.2,53.67 249.34,53.81 v3(249.34,54.67) DIMM1.85 ; DIMM2.107 234.23,49.17 v3(234.34,49.28) ; v3(254.66,68.43) 254.66,68.42 DIMM1.30 ; DIMM1.230 254.66,16.42 v3(254.66,16.43) ; v3(238.24,29.93) 238.24,30.01 239.15,30.93 DIMM2.172 ; DIMM1.99 249.15,51.17 249.35,50.98 v3(249.35,50.28) 249.25,50.17 DIMM1.103 ; DIMM2.235 234.63,15.17 235.77,14.03 v3(235.77,13.81) ; v3(239.67,67.03) 240.09,67.03 240.19,66.92 DIMM2.36 ; DIMM2.213 235.17,20.67 235.77,20.07 v3(235.77,19.62) ; DIMM1.235 250.39,15.17 250.76,14.81 v3(250.76,14.17) ; DIMM2.102 v3(242.73,50.42) ; DIMM1.197 250.03,24.67 250.78,25.43 v3(250.78,25.67) ; DIMM1.60 254.21,60.92 v3(252.37,62.77) ; DIMM1.82 254.18,55.42 253.87,55.12 253.32,55.12 253.31,55.13 253.31,55.1 v3(253.34,55.1) ; v3(253.21,19.53) 253.21,19.65 253.98,20.42 DIMM1.214 ; DIMM2.218 239.66,19.42 v3(239.66,19.43) ; v3(234.36,72.17) DIMM2.15 ; v3(249.35,20.67) DIMM1.213 ; DIMM1.251 v3(250.05,11.17) ; DIMM1.47 249.36,64.17 v3(249.56,64.38) ; DIMM2.18 239.06,71.42 v3(238.03,70.4) ; DIMM2.210 239.83,21.42 v3(239.66,21.59) ; DIMM1.26 254.12,69.42 253.21,70.33 v3(253.21,70.42) ; DIMM2.78 v3(239.66,56.42) ; DIMM1.247 250.02,12.17 250.34,12.49 250.34,12.56 250.4,12.61 v3(250.51,12.61) ; v3(253.21,25.92) 253.21,25.73 254.02,24.92 DIMM1.196 ; DIMM2.99 234.03,51.17 234.41,50.8 234.41,50.33 v3(234.35,50.28) ; DIMM2.26 240.01,69.42 239.96,69.37 239.41,69.37 239.36,69.32 239.29,69.32 238.88,68.92 238.72,68.92 238.24,68.43 v3(238.24,68.38) ; v3(234.67,22.1) 234.67,22.11 234.23,21.67 DIMM2.209 ; DIMM1.181 v3(249.34,28.67) ; DIMM2.197 v3(234.34,24.67) ; DIMM2.185 234.6,27.67 234.63,27.65 234.96,27.65 235.76,26.84 v3(235.76,26.67) ; DIMM2.206 240.36,22.42 240.29,22.5 238.97,22.5 238.22,21.75 v3(238.22,21.63) ; v3(234.34,30.11) 234.27,30.17 DIMM2.175 ; v3(235.76,68.17) 235.74,68.17 235.74,68.31 235.46,68.59 235.41,68.59 235.28,68.72 235.09,68.72 234.72,69.09 234.43,69.09 234.35,69.17 DIMM2.27 ; DIMM2.188 v3(239.66,26.93) ; DIMM1.193 v3(249.35,25.67) ; v3(238.98,72.47) 238.99,72.47 238.99,72.48 239.04,72.42 DIMM2.14 ; v3(239.66,59.82) 239.76,59.92 DIMM2.64 ; v3(238.24,14.43) 238.24,14.55 239.11,15.42 DIMM2.234 ; DIMM2.231 v3(234.34,16.17) ; DIMM1.73 248.93,57.67 v3(249.35,57.25) ; v3(250.88,71.86) 250.68,71.86 250,71.17 DIMM1.19 ; v3(238.24,26.93) 238.24,27.02 239.14,27.93 DIMM2.184 ; DIMM1.176 v3(254.66,29.93) ; DIMM2.176 v3(239.66,29.93) 239.66,29.23 239.96,28.93 DIMM2.180 ; v3(249.44,17.97) 249.24,18.17 DIMM1.223 ; DIMM1.77 245.97,56.67 v3(245.51,57.14) ; v3(254.64,71.45) 254.66,71.42 DIMM1.18 ; DIMM1.9 249.27,73.67 249.4,73.81 v3(249.4,73.84) ; DIMM2.189 v3(234.34,26.67) ; v3(253.79,14.16) 253.79,14.32 253.9,14.42 DIMM1.238 ; DIMM1.185 249.33,27.67 v3(249.36,27.65) ; v3(254.66,12.93) 254.66,12.92 DIMM1.244 ; DIMM2.23 v3(234.34,70.17) ; v3(253.21,27.93) 253.21,27.69 253.98,26.93 DIMM1.188 ; DIMM1.10 v3(257.48,73.42) ; v3(238.22,19.41) 238.24,19.41 238.24,19.55 239.11,20.42 DIMM2.214
  TOP w0.305: v3(234.37,52.81) 234.24,52.67 DIMM2.93 ; v3(235.09,77.3) 233.46,75.67 DIMM2.1 ; v3(187.08,87.21) ED3501.3 ED3501.8 v3(187.08,90.12) ; v3(170.97,35.04) 170.99,35.06 ; 170.99,35.06 170.99,35.11 171.1,35.23 CPU1.CV5 ; 170.99,35.06 170.82,35.23 CPU1.CV3 ; v3(191.7,38.04) 191.72,38.03 CPU1.CM47 ; LVDS1.17 46,15.21 v3(45.69,15.52) ; Q4006.4 197.51,76.7 v3(196.77,77.43) ; LVDS1.14 v3(43,12.49) ; v3(52.27,15.49) 53,14.77 LVDS1.24 ; CPU1.AD10 174.14,61.73 174.14,61.67 v3(174.48,61.33) 174.78,61.62 CPU1.AD11 ; NGFFE1.7 143.29,20.75 142.85,20.32 v3(142.85,19.25) ; CPU1.DG23 180.85,30.49 180.77,30.49 v3(180.45,30.8) 180.12,30.47 CPU1.DG22 ; v3(234.34,65.17) DIMM2.43 ; v3(56.78,24.93) ED5701.8 ED5701.3 v3(53.95,24.93) ; v3(93.18,72.5) 93.34,72.65 NGFFM1.33 v3(96.09,72.65) 96.09,71.46 95.79,71.15 NGFFM1.39 ; CPU1.DG6 172.18,30.83 172.44,31.08 v3(172.5,31.08) 172.5,31.11 172.18,31.43 CPU1.DE6 ; NGFFM1.9 93.38,78.65 v3(93.17,78.87) ; HDMI1.17 v3(58.89,44.83) ; v3(54.1,28.87) 54.11,28.87 ED5702.8 ED5702.3 v3(56.86,28.87) ; DIMM2.57 234.16,61.68 v3(234.36,61.88) ; NGFFE1.39 143.12,12.75 142.69,12.32 v3(142.58,12.32) ; DIMM2.65 234.34,59.68 v3(234.34,59.67) ; v3(190.53,41.15) 190.53,41.2 190.96,41.63 CPU1.CE45 ; CPU1.B21 179.34,72.51 v3(179.01,72.19) 179.34,71.86 CPU1.C21 ; v3(236.09,57.71) 236.08,57.71 236.08,57.71 235.84,57.71 234.88,58.68 DIMM2.69 ; CPU1.AB5 172.11,62.72 CPU1.AB6 172.18,62.78 v3(172.51,63.12) ; CPU1.DC6 171.88,32.76 CPU1.DC5 171.29,32.93 v3(170.99,32.93) 170.65,32.93 CPU1.DC3 ; CPU1.CG37 186.87,40.78 186.87,41.52 CPU1.CE37 ; DIMM1.57 249.33,61.68 v3(249.35,61.7) ; v3(234.35,50.28) 234.25,50.17 DIMM2.103 ; DIMM2.81 234.93,55.67 235.76,54.84 235.76,54.34 v3(235.78,54.33) ; CPU1.M10 174.05,67.25 v3(174.38,66.92) 174.7,66.6 CPU1.P11 ; HDMI1.2 57.38,37.32 58.88,37.32 v3(58.89,37.33) ; v3(142.85,19.25) 142.85,18.24 143.35,17.75 NGFFE1.19 ; v3(142.85,19.25) NGFFE1.13 ; NGFFM1.57 94.72,66.32 94.29,65.89 v3(93.74,65.89) ; v3(20.22,26.7) U5501.20 ; CPU1.G21 179.34,69.92 v3(179.01,69.59) 179.34,69.27 CPU1.H21 ; CPU1.C24 181.17,71.86 v3(180.84,72.19) 181.17,72.51 CPU1.B24 ; v3(249.24,76.51) 249.23,76.51 249.23,76.21 248.7,75.67 DIMM1.1 ; DIMM2.85 234.05,54.67 234.36,54.37 v3(234.36,54.33) 234.36,53.95 234.08,53.67 DIMM2.89 ; v3(132.16,39.61) 132.4,39.38 PU5301.19 ; CPU1.G24 181.17,69.92 v3(180.84,69.59) 181.17,69.27 CPU1.H24 ; CPU1.AG9 CPU1.AG11 ; DIMM2.77 234.07,56.67 234.29,56.9 234.29,57.62 v3(234.34,57.67) DIMM2.73 ; v3(249.56,63.17) DIMM1.51 ; v3(200.13,80.04) 200.13,79.98 200.06,79.91 Q4006.1 ; LVDS1.7 36,12.72 35.77,12.49 v3(34.71,12.49) ; HDMI1.11 57.83,41.83 57.83,41.83 57.84,41.83 58.89,41.83 v3(58.9,41.84) ; NGFFM1.45 v3(96.01,69.65) ; v3(93.14,73.96) 93.33,74.15 NGFFM1.27 ; v3(235.76,65.2) 235.76,65.32 234.91,66.17 DIMM2.39 ; NGFFE1.45 147.77,11.25 BTT1.2 147.77,9.75 NGFFE1.51 ; v3(235.76,63.19) 235.76,63.55 235.14,64.17 DIMM2.47 ; NGFFM1.51 v3(96.01,68.15) ; NGFFM1.21 93.27,75.65 v3(93.16,75.76) ; CPU1.C48 192.6,72.53 CPU1.B48 ; v3(235.76,59.67) 235.76,59.81 234.9,60.68 DIMM2.61 ; PU5301.4 135.44,35.85 135.67,35.62 135.67,35.2 v3(135.82,35.05) ; DIMM2.31 v3(234.34,68.17) ; HDMI1.8 v3(58.89,40.33) ; DIMM2.51 v3(234.34,63.17) ; HDMI1.5 v3(58.89,38.83) ; DIMM1.234 257.96,15.42
  TOP w0.381: v3(11.28,54.58) ED6001.3 ED6001.8 v3(8.4,54.58) ; R4057.1 148.45,31.15 148.4,31.2 Q4004.4 146.81,31.2 146.49,31.52 146.49,32.12 146.1,32.5 Q4004.1 ; X1802.4 170.38,16.69 170.38,16.68 ; v3(201.23,94.48) 201,94.48 200.62,94.86 200.62,95.92 200.22,96.32 U3504.2 ; v3(173.91,23.79) 173.91,23.41 174.34,22.98 174.34,22.31 174.35,22.31 174.35,20.52 173.9,20.08 C1805.2 174.35,17.78 174.52,17.78 174.96,17.34 174.96,14.34 174.69,14.07 173.81,14.07 173.78,14.1 v3(173.65,14.1) ; R1512.2 175.6,15.52 v3(175.58,15.52) ; ED3002.2 223.5,98.92 C3009.2 ; v3(56.67,77.97) 56.67,77.69 57.05,77.31 58.01,77.31 58.39,77.69 U3103.2 ; 170.38,16.68 170.38,17.57 C1806.2 171.04,22.4 172.43,23.79 v3(172.68,23.79) ; 170.38,16.68 170.4,16.66 170.4,14.51 v3(170.82,14.08) 173.64,14.08 v3(173.65,14.1) ; U4012.5 v3(164.87,46.62) ; EC3103.2 69.1,72.14 EC3106.2 ; v3(45.63,54.09) 45.63,54.09 ED3403.3 ED3403.8 45.63,51.94 45.62,51.93 45.62,51.61 45.61,51.6 v3(45.61,51.25) ; v3(116.59,14.84) 116.59,15.33 116.59,15.33 R6410.2 ; C4501.2 105.16,77.99 v3(105.11,77.94) ; X1802.2 173.85,14.29 v3(173.65,14.1) ; v3(101.55,26.45) 101.55,26.46 101.71,26.3 DBGH1.3 ; v3(26.12,53.83) ED3402.3 ED3402.8 v3(30.56,53.83) ; R1706.2 198.4,21.81 v3(197.54,22.67) ; v3(20.5,78.23) 20.54,78.26 U5301.5
  TOP w0.508: SATA1.23 3.91,46.54 ; SATA1.23 5.73,45.43 ; SATA1.23 3.91,44.31 ; 111.51,79.87 H2.1 111.67,79.33 ; R2922.1 v3(20.2,74.65) ; DCIN1.1 93.4,40.92 ; DCIN1.1 92.33,39.05 ; DCIN1.1 93.4,37.18 ; DCIN1.1 94.47,39.05 ; PC5302.2 132.13,39.58 v3(132.16,39.61) ; Q6805.S 15.55,86.75 15.59,86.71 v3(16.87,86.71) ; R2607.2 258.34,15.05 257.96,15.42 ; LVDS1.31 28.88,8.3 v3(29,8.17) ; PC4602.2 114.27,43.49 114.15,43.37 v3(114.15,43.31) ; C3423.2 37.95,54.29 v3(38.34,54.68) ; v3(65.76,67.31) 65.76,66.51 C3152.2 ; EC6906.2 38.82,81.49 v3(39.02,81.3) ; v3(56.55,19.18) 56.55,18.82 57.06,18.32 C5517.1 C5513.1 ; R5502.1 24.07,35.2 24.59,35.71 v3(24.59,36.42) ; 19.8,76.42 C5301.2 ; 19.8,76.42 v3(19.82,76.4) ; 19.8,76.42 19.74,76.48 C5303.2 ; R6120.2 134.37,11.54 C6103.2 134.93,12.5 v3(135.21,12.22) ; v3(38.61,70.06) 39.36,70.06 C2716.2 ; v3(94.64,19.46) 94.64,18.65 C2417.2 ; 91,41.78 DCIN1.2 ; DCIN1.2 92.07,43.65 ; DCIN1.2 91,45.52 ; 3.8,74.3 SATA1.P11 5.48,74.3 ; C2502.2 192.13,5.78 v3(192.04,5.87) 192.04,6.6 R1534.2 ; 3.8,65.41 SATA1.P4 5.48,65.41 ; v3(150.09,31.44) 149.81,31.15 R4057.1 ; v3(102.03,76.43) 102.01,76.45 RC4502.2 ; v3(67.89,24.32) 68.18,24.04 EC6915.2 ; v3(177.05,12.21) 176.87,12.21 R1730.2 ; 1.6,102.41 H1.8 1.76,102.64 ; C3119.2 62.69,77.42 v3(62.87,77.23) ; C3119.2 62.68,78.23 61.24,78.23 C3153.2 ; C3119.2 62.69,78.24 C3118.2 65.69,78.24 66.2,78.75 C3136.2 ; v3(43.09,59.61) 42.27,59.61 41.76,60.12 C3412.2 ; USB3R1.11 53.6,98.85 ; USB3R1.11 53.6,95.31 ; USB3R1.11 52.58,97.08 ; USB3R1.11 54.62,97.08 ; C5522.1 54.62,17.39 54.27,17.74 C5516.1 54.27,18.26 54.05,18.48 v3(54.05,19.08) ; v3(60.22,87.48) 60.74,88 C3128.2 ; EC6401.2 124.37,6.28 v3(124.27,6.37) 124.27,6.42 123.76,6.92 C6401.2 ; EC6908.2 15.32,82.46 15.32,82.45 v3(15.34,82.45) ; v3(54.4,61.1) 54.4,61.1 54.4,61.08 54.54,61.08 55.49,60.14 56.36,60.14 C5721.2 ; CAM1.9 214.81,101.6 215.74,100.67 v2(215.74,100.67) 216.18,100.23 216.18,100.23 216.5,99.91 CAM1.4 ; v3(110.49,45.57) 110.81,45.89 PC4624.1 PR4637.1 ; v3(94.02,6.45) R24062.2 94.94,6.46 C2403.2 ; SATA1.24 5.73,81.57 ; SATA1.24 3.91,82.69 ; SATA1.24 3.91,80.46 ; PC1048.2 158.23,56.73 v3(158.87,56.73) 159.86,55.74 v3(160.17,55.74) ; 5.48,73.03 SATA1.P10 3.8,73.03 ; C2422.2 v3(94.73,17.43) ; C3136.2 67.28,79.72 67.3,79.74 v3(67.54,79.74) ; C3136.2 66.2,80.25 C3134.2 ; 113.05,77.26 H2.2 113.28,77.1 ; v3(203.77,17.07) 203.25,16.55 C1904.2 ; 5.48,67.94 SATA1.P6 3.8,67.94 ; C5524.1 49.09,17.43 48.73,17.79 C5518.1 48.73,18.51 v3(48.35,18.89) ; R2531.2 260.55,25.97 v3(261.1,26.52) ; v3(222.91,100.97) 222.28,101.6 CAM1.10 ; v3(45.69,15.52) 45.69,15.65 46.29,16.24 C5523.1 46.42,16.81 C5526.1 46.42,18.04 v3(45.68,18.77) ; v3(112.58,2.58) 112.12,2.58 111.61,3.09 EC6402.2 ; U3503.2 v3(77.38,79.74) ; R1511.2 193.25,14.86 v3(193.8,15.4) ; PR5018.2 147.1,47.48 v3(146.56,48.02) ; v3(86.76,75.85) 86.56,75.85 86.41,75.7 C6305.2 ; R3161.2 v3(62.68,91.34) ; C1127.2 156.52,44.94 C1126.2 156.52,45.93 C4072.2 155.99,46.01 v3(155.6,45.61) ; v3(36.62,74.41) 36.62,74.42 36.67,74.48 C2719.1 ; PR4304.2 79.44,52.04 78.93,51.53 v3(78.33,51.53) ; 114.45,84.38 H2.7 114.22,84.22 ; v3(187.24,19.4) 187.28,19.45 187.28,20.1 R1516.2 ; 2.76,38.17 H5.8 2.61,38.71 ; EC6916.2 81.21,56.35 EC6917.2 81.2,56.35 77.94,56.35 v3(77.85,56.26) ; C5533.1 38.14,16.59 C5532.1 38.57,16.76 v3(39.56,17.75) ; C2718.2 40,71.75 v3(40.26,72.01) ; v3(151.9,60.42) 151.87,60.42 151.87,60.41 151.63,60.17 PC4701.2 ; R1603.2 164.53,29.01 v3(164.49,29.04) 164.49,28.84 164.69,28.64 164.69,28.08 164.68,28.06 R1604.2 ; R2923.1 v3(21.28,64.53) ; LVDS1.32 61.65,6.46 v3(61.21,6.02) ; U2501.4 202.55,11.69 v3(202.23,11.37) ; C3524.2 203.78,98.36 v3(204.51,99.09) ; NGFFE1.76 144.98,23.35 145.48,22.85 v3(145.56,22.85) ; R2909.1 v3(15.39,51.94) ; v3(82.36,34.42) 82.4,34.39 R4321.2 ; D2403.3 100.96,29.62 v3(101.04,29.7) ; R2924.1 22.71,78.25 v3(22.71,79.17) ; C2907.2 v3(7.82,48.83) ; v3(43.43,60.26) 43.64,60.46 43.64,62.08 EC6907.2 ; v3(71.3,68.53) 71.3,67.72 C3151.2 ; v2(16.62,77.89) 15.17,77.89 C6002.2 ; v3(41.71,71.72) C2717.2 41.68,70.86 C2720.2 ; 3.8,75.56 SATA1.P12 5.48,75.56 ; 3.8,55.24 SATA1.S7 ; SATA1.S7 5.48,55.24 ; SATA1.S7 4.64,56.02 ; C3515.2 v3(81.08,76.37) ; R1728.1 v3(200.36,26.35) ; 5.63,96.43 H1.3 5.33,96.42 ; BTT1.2 149.28,9.74 v3(149.28,8.1) ; v3(111.28,53.96) 112,54.69 PC4609.2 ; 3.8,66.67 SATA1.P5 5.48,66.67 ; 1.28,99.13 H1.1 1.12,99.67 ; 140.64,36.88 140.64,38.47 140.94,38.77 PC5308.2 ; USB3R4.10 42.44,48.35 ; USB3R4.10 44.16,47.44 ; USB3R4.10 42.44,46.53 ; USB3R4.10 40.73,47.44 ; C4093.2 156.6,42.02 C1121.2 155.82,42.11 v3(155.65,42.28) ; C2605.2 v3(260.84,13.19) ; EC3107.2 65.83,72.13 EC3104.2 65.84,72.56 v3(65.84,73.2) ; PC1042.2 152.59,59.71 152.69,59.81 v3(152.69,60.41) ; PC4605.2 v3(128.16,53.72) ; v3(196.77,77.43) 195.58,77.43 R505.1 194.49,77.44 R507.1 ; v3(22.11,48.38) 21.04,48.38 ED2903.3 ; ED2905.3 8.92,46.63 8.92,47.04 v3(8.53,47.43) ; v3(135.04,18.66) 134.98,18.72 R6119.2 ; v3(217.19,100.36) 217.5,100.05 CAM1.5 ; PC4516.2 99.58,79.07 99.57,79.06 98.22,79.06 v3(97.78,78.61) ; v3(226.04,98.49) 225.61,98.92 ED3002.2 ; v3(140.5,36) 140.47,36.02 PC5315.2 ; 4.83,40.63 H5.7 5.06,40.78 ; v3(103.34,29.7) 103.4,29.7 103.5,29.6 103.88,29.6 103.89,29.6 DBGH1.15 ; 111.99,82.61 H2.8 112.15,82.84 ; 3.83,104.02 H1.7 4.06,104.18 ; 3.89,33.5 H5.2 3.66,33.66 ; C5722.2 57.24,55.62 57.24,55.53 57.18,55.47 57.18,54.86 57.24,54.8 57.24,54.8 v3(57.19,54.8) ; C2412.1 v3(70.07,5.38) ; v3(221.79,95.94) 220.38,95.94 C3008.2 ; v3(128.23,48.19) PC4608.1 ; C2908.2 25.51,45.54 26.01,45.03 v3(26.01,44.32) ; R24065.2 R24011.2 70.52,20.57 69.83,20.57 v3(69.7,20.69) 68.52,19.51 Q5702.S ; v3(155.54,56.67) 156.29,56.67 PC1047.2 ; 5.48,47.62 SATA1.S1 4.64,46.85 ; R301.1 159.92,71.21 R401.1 159.57,71.21 v3(159.07,70.7) ; C3409.2 40.93,54.8 U3402.2 ; C4013.2 47.04,82.69 v3(47.04,82.01) ; v3(178.93,19.49) 178.95,19.5 R1525.2 ; v3(10.34,52.48) 11.3,51.52 ED2904.3 ; v3(72.12,73.12) EC3102.2 71.92,72.08 EC3105.2 ; v3(68.25,68.45) U3101.2 ; EC3108.2 62.89,71.57 v3(62.89,72.6) ; D6301.2 v3(83.03,70.06) ; v3(36.04,17.88) 35.52,17.36 C5531.1 ; v3(131.81,4.84) 131.81,4.67 132.31,4.16 C6105.2 132.97,4.17 C6106.2 ; C6001.2 v2(14.74,76.44) 15.66,76.44 15.75,76.35 15.75,76.34 C5302.2 ; v3(162.2,71.12) 162.3,71.23 R403.1 R313.1 ; v3(54.91,71.8) 54.91,72.1 C3154.2 56.36,73.55 C3155.2 ; v3(75.11,73.12) 75.11,72.45 EC3101.2 ; C2726.2 v3(40.13,72.89) ; C6345.2 v3(84.68,74.88) ; 2.66,97.06 H1.2 2.89,96.9 ; EC6909.2 v3(49.56,64.87) ; C5508.1 62.52,17.53 62.15,17.16 v3(62.15,17.02) ; PR5006.2 v3(143.23,45.64) ; CNVBD1.14 v3(20.45,4.5) ; v3(31.06,30.06) 30.78,30.06 30.26,29.54 C5612.2 30.17,29.46 29.86,29.77 29.22,29.77 C5611.2 ; R1726.2 201.61,22.82 C1705.2 201.62,21.9 v3(201.66,21.9) ; C2405.2 69.96,29.2 70.86,29.2 C2425.2 71,30.21 v3(72.04,31.25) ; PC5313.2 132.43,33.09 v3(132.5,33.01) ; C5521.1 51.83,17.73 C5519.1 51.52,18.7 v3(51.3,18.92) ; U3102.2 v3(74.09,68.57) ; PC4515.2 99.85,52.45 v3(99.85,52.49) ; v3(55.54,89.12) 55.11,88.69 ED3505.2 ; U3401.2 37.36,55.14 v3(37.37,55.14) ; v3(57.73,90.89) 58.36,90.89 59.08,90.17 59.08,89.07 59.19,88.97 C3516.2 ; R506.1 193.39,77.43 v3(192.6,77.43) ; C3517.2 v3(69.32,99.32) ; PR5004.1 149.09,35.44 v3(148.44,34.8) ; v3(39.75,76.2) 39.15,76.2 R2730.2 ; C2423.2 77.59,5.24 77.57,5.24 v3(77.06,4.73) ; v3(10.92,87.79) R6802.2 ; C6301.2 v3(81.36,70.06) ; C5304.2 v3(23.94,80.79) ; C6342.2 82.86,74.91 v3(81.79,74.91) ; PC5013.1 152.77,45.49 v3(151.88,45.49) ; v3(119.55,59.8) PC4603.2 ; R6807.2 v3(10.97,90.52) ; v3(70.27,17.05) 70.5,17.28 R24055.2 ; ED3401.2 v3(45.52,29.08) ; D2701.3 39.03,65.8 39.54,66.3 v3(39.84,66.3) ; R24110.2 97,22.64 v3(97.27,22.37) ; EC3103.2 v3(68.89,73.19) ; R6308.2 v3(80.85,64.84) ; ED6902.1 v3(59.81,91.23) ; Q2402.S v3(72.18,9.51) ; EC6913.2 v3(80.17,72.89) ; v3(59.34,19.6) 59.34,19.26 59.72,18.88 59.72,18 C5507.1 59.73,17.09 C5514.1
  TOP w0.635: v3(119.87,42.45) 119.87,42.48 119.93,42.55 PC4606.2
  TOP w1.016: v3(46.73,101.27) 46.73,101.28 CRS1.12 ; 246.12,99.67 H4.1 246.28,99.13 ; 246.6,102.41 H4.8 246.76,102.64 ; v3(16.27,101.27) 16.28,101.28 CRS1.13 ; 250.63,96.43 H4.3 250.33,96.42 ; 247.89,96.9 H4.2 247.66,97.06
  L3 w0.254: v3(210.21,21.49) v3(204.41,27.29) 204.4,27.28 200.15,27.28 199.41,28.02 196.38,28.02 195.23,29.17 194.27,29.17 v3(194.16,29.29) 193.96,29.49 192.58,29.49 v3(191.68,30.39) 191.68,31.45 191.55,31.59 191.55,31.72 v3(190.62,32.65) 190.44,32.82 190.44,32.85 190.17,33.13 190.14,33.13 190.1,33.16 189.74,33.16 189.33,32.75 v3(189.33,32.67) 188.58,33.42 v3(188.58,34.45) 188.34,34.69 188,34.69 186.67,36.03 v3(186.67,36.29) 186.64,36.29 185.26,37.67 185.26,41.16 187.03,42.93 187.82,42.93 v3(187.88,42.99) ; v3(254.64,74.42) 254.64,75.08 v3(254.15,75.56) 253.82,75.9 253.82,76.93 252.65,78.09 250.34,78.09 249.77,78.65 249.77,78.65 v3(249.44,78.99) 245.76,82.67 234.14,82.67 233.99,82.82 v3(233.25,82.82) v3(232.51,82.82) v3(231.78,82.82) 231.07,82.82 v3(231.06,82.82) v3(230.33,82.82) v3(229.59,82.82) 227.95,81.18 196.79,81.18 v3(195.64,80.03)
  L3 w1.016: 5.48,75.56 SATA1.P12 3.8,75.56 ; 52.58,97.08 USB3R1.11 ; USB3R1.11 54.62,97.08 ; USB3R1.11 53.6,98.85 ; 3.8,74.3 SATA1.P11 5.48,74.3 ; USB3R1.10 67.42,97.08 ; USB3R1.10 66.4,98.85 ; USB3R1.10 65.38,97.08 ; SATA1.23 3.91,46.54 ; SATA1.23 5.73,45.43 ; SATA1.23 3.91,44.31 ; 3.91,80.46 SATA1.24 ; SATA1.24 5.73,81.57 ; SATA1.24 3.91,82.69 ; 4.64,56.02 SATA1.S7 3.8,55.24 ; 245.2,99.67 H4.1 245.2,102.38 ; 3.8,66.67 SATA1.P5 5.48,66.67 ; 3.8,67.94 SATA1.P6 5.48,67.94 ; 5.48,73.03 SATA1.P10 3.8,73.03 ; 5.48,66.18 SATA1.P4 3.8,65.41
  L4 w0.127: 201.84,36.22 201.84,36.36 198.6,39.6 198.12,39.6 196.94,40.78 194.53,40.78 v3(193.54,41.78) 193.54,42.23 191.38,44.38 187.49,44.38 187.19,44.68 187.17,44.68 v3(186.11,45.75)
  L4 w0.254: v4(185.2,73.64) 184.93,73.91 184.93,73.92 184.55,74.3 183.85,74.3 183.17,74.98 183.17,80.42 190.7,87.95 v3(205.14,87.95) v3(209.45,87.95) 209.69,87.71 v3(212.23,87.71) 217.33,87.71 217.33,87.71 218.92,87.71 220.62,86.01 224.53,86.01 v3(224.65,85.89) 224.71,85.82 225.82,85.82 229.54,82.1 230.91,82.1 230.93,82.08 231.13,82.08 232.13,81.08 232.17,81.08 235.09,78.16 v3(235.09,77.3) ; 201.84,36.22 201.84,33.21 210.21,24.85 v3(210.21,21.49) 210.49,21.49 212.14,19.84 212.14,19.53 216.59,15.07 217.33,15.07 218.08,14.32 219.98,14.32 221.99,12.31 v3(222.69,12.31) 223.44,11.56 223.53,11.56 223.84,11.24 223.84,11.16 226.26,8.73 v3(231.68,8.73) 232.46,8.73 232.9,9.18 238.04,9.18 v3(239.67,10.8)
  L4 w1.016: 3.8,55.24 SATA1.S7 ; SATA1.S7 4.64,56.02 ; SATA1.S7 5.48,55.24 ; 3.8,73.03 SATA1.P10 5.48,73.03 ; 3.8,74.3 SATA1.P11 5.48,74.3 ; HS6.1 12.4,73.29 ; HS6.1 12.4,69.51 ; HS6.1 14.29,71.4 ; HS6.1 10.51,71.4 ; 5.48,47.62 SATA1.S1 5.48,46.85 ; SATA1.24 5.73,81.57 ; SATA1.24 3.91,82.69 ; SATA1.24 3.91,80.46 ; 5.48,65.41 SATA1.P4 3.8,65.41 ; SATA1.23 5.73,45.43 ; SATA1.23 3.91,44.31 ; SATA1.23 3.91,46.54 ; 65.38,97.08 USB3R1.10 ; USB3R1.10 67.42,97.08 ; USB3R1.10 66.4,98.85 ; 3.8,75.56 SATA1.P12 5.48,75.56 ; 3.8,66.67 SATA1.P5 5.48,66.67 ; 2.81,41.7 H5.1 2.81,32.1 ; USB3R1.11 53.6,98.85 ; USB3R1.11 52.58,97.08 ; USB3R1.11 54.62,97.08 ; 5.48,67.94 SATA1.P6 3.8,67.94 ; 5.48,51.44 SATA1.S4 3.8,51.44
  BOTTOM w0.203: v3(217.7,90.69) 217.71,90.69 217.71,90.68 217.83,90.8 PU5103.3 ; PU5103.1 218.59,90 v3(218.07,89.49) ; PU5103.14 222.71,90.4 223,90.12 223,90.11 v3(222.99,90.11) ; U4003.11 v3(46.28,79.99) ; v3(31.53,24.37) 31.64,24.47 TSMT1.16 ; TSMT1.6 35.94,21.35 v3(35.99,21.31)
  BOTTOM w0.254: U4010.5 149.45,22.8 149.17,23.09 148.6,23.09 C4060.2 ; C1336.2 232.51,13.07 C1317.2 233.63,13.07 234.3,13.75 234.3,13.83 v3(234.34,13.83) ; v3(33.22,17.84) 32.52,17.14 R5606.2 31.22,17.14 30.81,17.55 30.81,21.63 v3(31.58,22.4)
  BOTTOM w0.305: v3(217.34,5) 217.28,5.05 Q4012.4 ; Q4013.E 217.95,8.21 v3(218.41,7.76) 219.12,7.04 Q4012.1 ; U3301.24 v3(39.62,94.49) ; Q4009.4 128.34,21.92 128.03,22.22 v3(128.03,22.53) ; C4304.2 77.21,51.8 77.48,51.53 v3(78.33,51.53) ; C4024.2 223.7,7.44 R4012.2 222.72,7.43 221.71,7.43 v3(221.45,7.17) ; RN1301.2 239.94,31.9 239.67,32.17 v3(239.63,32.17) 239.4,31.94 C1302.2
  BOTTOM w0.356: v3(186.47,13.53) 186.48,13.53 U4009.3 ; RN1201.2 255.68,32.78 255.32,32.43 v3(254.66,32.43)
  BOTTOM w0.381: Q4001.1 130.39,43.99 v3(129.01,43.99) ; R1902.2 193.56,38.82 193.74,39 v3(193.74,39.28) ; v3(204.18,79.05) 203.67,79.05 203.49,79.23 C4026.2 ; v3(193.59,36.77) 193.52,36.84 R1818.2 ; Q3401.1 32.97,54.29 32.45,53.78 v3(32.45,53.61) ; PR4669.2 116.76,44.65 v3(116.9,44.52) ; v3(115.89,17.75) 115.89,18.23 116.17,18.51 U4020.3 ; Q2403.4 73.49,18.25 73.11,18.64 72.6,18.64 72.19,19.04 Q2403.1 71.7,19.55 71.29,19.96 C2424.2 ; C3401.2 38.71,59.6 39.1,59.22 v3(39.1,58.61) ; v3(27.28,15.37) 27.14,15.51 C5502.2 27.14,16.31 27.14,17.01 C5503.2 ; v3(191.62,23.83) 191.49,23.7 R2102.2 ; v3(231.84,95.83) 232.52,96.51 PC5104.2 ; R2209.2 176.87,28.13 v3(176.25,28.13) ; R1903.2 188.19,36.86 v3(188.57,37.24) ; U4013.3 163.13,17.18 162.59,16.64 v3(162.59,15.07) ; v3(123.49,28.81) 123.47,28.84 123.47,29.4 123.09,29.78 PC5401.1 ; v3(132.21,46.27) 132.46,46.03 Q4001.4 ; v3(52.98,88.21) ED3504.3 ; v3(172.2,71.71) 172.33,71.85 R2103.1 ; Q3401.4 36.91,55.59 v3(37.37,55.14) ; ED5703.2 45.31,55.87 v3(44.99,56.19) ; PR4503.2 v3(105.11,77.94) ; v3(190.49,34.46) 190.94,34.91 R1839.1 ; 197.79,19.64 197.79,22.42 v3(197.54,22.67) 197.22,22.99 C1802.2 v3(196.73,23.84) 197.31,24.42 197.31,28 196.02,29.29 v3(194.16,29.29) 194.06,29.19 v3(194.06,28.24) 194.06,27.78 194.52,27.32 194.93,27.32 195.45,26.8 v3(195.45,26.55) 195.45,25.44 194.22,24.21 194.22,23.3 C1801.2 193.03,22.12 193.03,19.66 v3(193.39,19.31) v3(195.56,19.31) 195.58,19.34 197.49,19.34 197.79,19.64
  BOTTOM w0.406: ED3504.3 ED3504.8 v3(52.98,91.11)
  BOTTOM w0.508: R1843.1 178.46,24.29 178.7,24.05 v3(178.7,23.8) ; C2424.2 R24097.2 71.29,22.47 v3(72.48,23.67) ; PC4611.2 127.37,48.69 127.88,48.19 v3(128.23,48.19) ; EC3323.2 v3(21.78,90.81) ; C2206.2 183.82,29.8 v3(183.52,29.5) ; C1107.2 193.48,41.84 v3(193.54,41.78) ; C2215.2 173.84,23.86 v3(173.91,23.79) ; v3(221.79,95.94) 221.51,95.65 PC5110.2 ; v3(254.64,18.27) 255.4,17.51 PC5202.2 ; v3(172.49,55.79) 172.46,55.76 C2218.2 ; v3(164.55,21.92) 164.78,22.15 C4030.2 166.33,23.1 R1523.2 ; v3(254.64,27.93) 255.12,27.44 PC5201.2 ; v3(168.99,26.07) 169.04,26.01 C2216.2 ; C6104.2 131.81,6.58 v3(131.81,4.84) ; v3(257.67,61.92) 257.45,61.7 C1215.2 257.45,59.98 C1222.2 ; C1205.2 246.22,45.98 245.63,46.58 v3(245.63,46.68) ; ED3101.1 v3(57.57,66.01) ; v3(176.8,25.9) 176.77,25.9 176.77,25.86 176.37,25.45 R1844.1 176.34,25.08 R1602.2 ; v4(191.59,70.53) 192.53,69.59 C1116.2 ; v2(61.67,61.52) 62.22,60.97 GDT1.1 ; C4014.2 v3(51.31,80.23) ; v3(135.21,12.22) 135.12,12.14 134.99,12.14 134.48,11.63 C2209.2 134.49,10.24 C2201.2 ; PC5001.2 142.22,39.45 v3(142.11,39.57) ; v3(239.66,21.59) 239.83,21.43 C1333.2 241.76,21.43 C1316.2 ; EC4302.2 v3(81.78,45.44) ; 13.86,19.2 13.86,19.81 v3(14.22,20.17) 15.79,20.17 C5544.2 ; v3(254.66,16.43) 255.53,15.55 PC5203.2 ; R1729.1 189.84,25.84 v3(189.92,25.91) ; U5602.1 55.89,18.51 v3(56.55,19.18) ; v3(244.47,32.17) 244.47,31.34 R1306.2 ; C2910.2 20.5,60.19 20.5,60.19 v3(20.8,60.48) ; C1106.2 187.01,50.38 187.01,51.39 C1111.2 187.66,51.53 v4(187.98,51.22) ; v3(151.17,27.13) 151.16,26.76 151.16,26.26 C4019.2 ; v3(137.68,25.62) 137.68,26.1 139.27,27.69 139.27,29.31 139.77,29.81 ED6101.2 ; v3(180.45,30.8) 180.19,31.06 R1533.2 ; C1318.2 241.53,64.67 240.74,64.67 C1331.2 240.01,64.58 v3(239.67,64.92) ; R5730.2 v3(43.43,60.26) ; C5620.2 41.51,23.55 42.6,23.55 43.1,24.05 v3(43.1,25.83) ; C5554.2 68.16,24.06 v3(67.89,24.32) ; v3(160.34,41.72) 159.62,41.72 C1119.2 C1120.2 ; v3(97.78,78.61) PR4504.2 97.77,77.82 C4502.2 ; PC4506.2 109.31,70.89 v3(110.01,70.19) ; v3(254.66,23.43) 254.97,23.43 255.48,22.92 255.48,22.69 C1216.2 ; v3(208.09,4.21) 207.69,4.62 MFG1.4 ; FC9087.2 249.25,52.78 v3(249.35,52.67) ; PR4644.2 122.49,45.33 122.49,45.99 121.99,46.48 v3(121.91,46.48) ; v3(258.42,50.14) 257.21,48.93 C501.2 ; C3143.2 74.08,67.72 74.08,67.81 74.09,67.83 v3(74.09,68.57) ; C5545.2 65.09,20.81 C5556.2 66.21,20.42 66.75,19.87 U5504.2 ; C5545.2 65.06,21.68 C5559.2 ; C5545.2 65.06,20.34 64.58,19.86 v3(64.09,19.86) ; R1529.2 193.39,31.94 v3(193.88,32.43) ; v3(41.59,82.37) 41.59,82.38 41.75,82.22 42.59,82.22 C4011.2 ; v3(40.07,88.46) 39.69,88.84 EC3325.2 ; R5612.2 40.3,21.14 40.3,20.87 40.71,20.46 R5618.2 40.75,20.09 v3(40.75,19.35) ; v3(191.7,38.04) 191.67,38.01 R309.1 ; C1322.2 238.17,10.01 238.17,10.51 238.16,10.52 238.16,10.72 v3(238.08,10.8) ; PC5403.1 118.38,27.01 118.19,26.82 v3(118.19,26.09) ; PR5304.2 136.21,34.67 v3(135.82,35.05) ; v4(187.89,63.1) 187.62,63.37 C1104.2 C1103.2 ; v3(234.34,70.17) 234.31,70.14 C1129.2 ; EC3324.2 42.53,88.85 v3(42.53,88.37) ; v3(243.73,29.26) 243.73,29.25 243.32,28.84 C1332.2 ; v3(43.27,18.81) 43.27,20.8 43.4,20.93 R5610.2 43.4,21.71 R5623.2 ; v3(112.59,58.38) 112.66,58.44 Q4301.S ; v3(83.82,48.2) 84.49,47.53 EC6919.2 84.49,47.4 EC6904.2 ; Q4007.S 128.49,25.69 v3(127.79,26.4) ; v3(201.66,21.9) 201.66,21.86 202.11,21.41 C1820.2 201.61,20.62 C1821.2 ; v3(34.71,12.49) 35.11,12.9 R5531.2 ; v4(187.85,54.87) 187.65,55.08 C1105.2 187.09,55.13 C1109.2 ; v3(203.77,17.07) 204.44,17.07 R1833.2 ; v3(53.44,12.88) 53.64,12.88 54.36,13.59 U5602.4 ; MFG1.5 205.04,4.95 204.44,5.55 v3(204.44,5.58) ; v3(249.34,30.17) 248.62,30.17 C1220.2 248.38,29.94 C1209.2 ; v3(36.04,17.88) 36.48,17.44 36.48,14.64 R5602.2 ; v3(193.38,23.74) 193.38,23.84 192.88,24.33 R1746.2 ; v3(239.67,10.8) 240.42,10.8 C1320.2 ; PR5303.2 134.08,38 134.08,37.13 PC5314.2 133.01,37.08 132.5,36.57 v3(132.5,33.01) ; v3(168.13,7.06) 168.13,7.52 168.53,7.92 R2514.2 168.53,8.35 C2503.2 167.4,8.18 R2511.2 ; v3(252.9,34.22) 252.76,34.08 C1208.2 ; R24091.2 75.96,18.11 76.41,17.65 76.41,17.26 v3(76.55,17.13) ; C3302.1 41.89,93.83 41.38,94.34 v3(40.99,94.34) ; v3(179.01,72.19) 178.81,71.98 R705.1 ; ED2901.3 v3(6.38,24.39) ; D2402.3 v3(67.75,29.39) ; R1514.2 v3(202.23,11.37) 202.78,11.92 MFG1.7 MFG1.6 v3(208.39,11.92) ; v3(254.66,54.42) 254.81,54.28 FC9088.2 ; C1110.2 187.04,45.86 C703.2 186.11,45.75 v3(186.11,45.75) ; C1207.2 257.51,40.07 C1217.2 257.24,39.48 R1215.2 256.67,38.79 257.43,38.79 257.43,38.78 v3(257.44,38.78) ; v3(168.03,16.97) 168.03,16.97 168.03,16.96 168.17,17.1 R1502.2 ; FC9008.2 171.53,64.82 v3(170.96,65.39) ; v3(211.3,14.41) 211.15,14.56 210.43,14.56 R1821.2 209.44,14.54 C1823.2 ; U5602.2 54.56,16.13 54.05,16.64 v3(54.05,19.08) ; v3(37.44,100.54) C3301.2 ; v3(104.09,70.95) 103.92,71.12 PC4505.2 ; v3(77.76,7.99) 77.76,9.02 C2416.2 77.75,9.36 77.66,9.45 U2401.4 ; EC3327.2 37.4,88.84 v3(37.78,88.46) ; v3(249.56,64.38) 249.49,64.45 FC9085.2 ; C1102.2 187.09,61.35 C1113.2 187.86,60.37 v4(187.87,60.36) ; v3(234.34,24.67) 233.34,24.67 C1335.2 ; C4048.2 43.63,82.31 43.97,82.64 v3(43.97,82.7) ; v3(242.73,50.42) 242.43,50.42 242.22,50.64 C1334.2 240.91,50.64 C1329.2 ; C2207.2 185.76,27.95 186.01,28.19 v3(186.35,28.19) ; C4060.2 147.82,22.31 v3(147.34,22.31) ; EC6918.2 73.48,40.72 v3(73.14,40.38) ; C3126.1 69.6,81.7 v3(69.61,81.69) 69.63,81.71 X3101.4 ; C1112.2 257.45,72.25 C1218.2 257.24,72.49 257.24,73.18 v3(257.48,73.42) ; v3(193.7,25.23) 193.56,25.23 193.2,25.59 C1701.2 ; v3(162.59,15.07) Q2501.S ; R2101.2 184.65,25.89 v3(184.67,25.91) 184.71,25.87 C2205.2 ; C2213.2 187.44,25.41 v3(186.95,25.9) 186.95,26.38 R1527.2 ; v3(47.78,87.72) 47.78,87.08 C4012.2 ; PC5406.1 v3(112.45,33.22) 112.45,33.43 PC5411.2 PC5412.2 ; v3(176.39,8.08) 176.87,7.61 R1841.1 ; v3(155.35,24.09) 156.1,23.34 C4061.2 ; v3(249.35,57.25) 248.44,57.25 248.42,57.27 C1223.2 ; C3125.2 61.44,60.52 v3(61.84,60.12) ; D3102.1 v3(62.18,63.39) ; D6904.2 84.23,20.07 84.45,19.86 84.45,19.85 84.53,19.77 v3(84.53,19.46) ; EC6901.2 26.86,27.04 v3(27.25,27.44) 27.39,27.3 28.23,27.3 R5620.2 ; v3(169.11,60) 168.63,60.48 R607.1 ; PR4659.2 111.53,43.16 v3(111.85,42.84) ; v3(77.85,56.26) 77.85,57.31 R4326.1 ; v3(201.23,94.48) 201.23,94.32 201.7,93.85 ED3502.2 ; v3(190.74,39.76) 191.57,39.76 C1114.2 191.69,39.88 C1115.2 ; C1312.2 237.61,37.33 237.85,37.09 237.85,37.09 v3(237.84,37.09) ; v3(187.74,40.04) 187.74,40.04 187.02,40.04 PC1030.2 186.55,40.51 PC1005.2 ; v3(44.95,87.41) 44.76,87.22 C4009.2 ; C4008.2 46.89,76.84 v3(46.47,76.84) 45.88,76.84 EC6910.2 45.65,77.32 45.26,77.7 C4007.2 ; C1125.2 183.19,66.39 184.57,67.77 v3(184.96,67.77) ; ED3103.1 v3(63.93,68.37) ; v3(212.23,87.71) 212.23,87.7 212.74,87.19 PC5115.2 ; v3(215.07,93.45) 215.07,93.44 215.07,91.79 PC5113.2 ; v3(24.51,9.35) 24.51,9.93 EC5501.2 ; C3314.1 v3(30.23,88.35) ; R5624.2 v3(39.93,12.45) ; v3(23.98,11.43) 24.39,11.43 24.54,11.59 EC5502.2 ; Q2401.S 87.92,27.88 Q2404.S 88.57,27.59 88.68,27.7 v3(88.87,27.7) ; EC1802.2 104.13,7.55 v3(104.13,7.54) EC1801.2 ; PR5106.2 225.54,89.88 v3(225.16,90.27) 225.03,90.4 PC5108.2 225.02,91.08 PC5109.2 ; v4(191.57,53.04) 191.32,52.79 FC9091.2 ; v3(184.61,31.44) 184.6,31.42 C2203.2 ; v3(200.36,26.35) 200.36,26.75 R1842.1 ; v3(65.13,91.28) 65.06,91.21 C3106.2 ; FC9002.2 187.83,42.94 v3(187.88,42.99) ; v3(91.32,14.43) 91.11,14.64 R24111.2 ; v3(93.67,24.09) 94.06,24.48 D2401.3 93.3,25.25 92.64,24.59 92.64,24.51 R24029.2 92.64,24.5 92.64,23.53 C2419.2 ; v3(94.05,31.1) 94.8,31.1 C2426.2 95.63,30.99 C2408.2 ; PC1011.2 186.43,69.18 v4(187.11,69.18) ; FC9001.2 184.74,35.7 v3(184.14,35.7) ; PC5206.2 259.48,26.71 v3(259.41,26.64) ; Q4308.S 81.21,51.76 81.06,51.91 v3(80.92,51.91) ; v3(173.21,39.32) 173.33,39.19 PC1057.2 174.11,39.19 PC1012.2 ; v3(212.37,90.53) 212.77,90.53 213.16,90.14 PC5114.2 ; v3(123.85,31.91) 123.66,31.72 PC5407.1 ; R1521.2 211.15,20.64 211.14,20.63 R1513.2 210.24,20.64 210.24,21.45 v3(210.21,21.49) ; v3(59.68,14.7) 59.63,14.7 59.45,14.88 C5607.2 ; R605.1 171.31,61.79 v3(171.83,61.27) ; v3(38.34,54.68) 39.1,55.43 Q3402.S ; v3(234.36,54.33) 233.89,53.87 C1128.2 ; v3(167.02,15.14) 167.02,15.14 167.12,15.04 C2507.2 ; v3(262.96,31.04) 262.96,31.05 PC5205.2 ; C1315.2 233.08,57 C1330.2 233.7,56.71 234.34,57.35 v3(234.34,57.67) ; v3(193.74,26.83) 193.46,26.55 192.68,26.55 R1840.1 ; v3(253.89,32.38) 253.54,32.04 252.83,32.04 252.81,32.05 C1281.2 ; R3102.1 67.12,80.16 v3(67.54,79.74) 67.58,79.78 C3127.1 69.55,79.05 70.97,79.05 71.48,79.56 X3101.2 71.79,80.17 72.3,80.68 72.3,82.68 71.58,83.39 69.97,83.39 69.2,84.17 v3(67.74,84.17) ; EC4301.2 v3(81.7,44.15) 81.06,43.51 EC6902.2 81.04,43.49 EC6905.2 ; v3(52.27,15.49) 51.63,16.13 U5602.7 ; v3(41.83,92.46) R3301.1 ; v3(45.73,87.43) 45.73,86.58 C4017.2 ; C2603.2 261.68,2.27 v2(261.68,1.54) ; v4(191.54,65.58) 191.65,65.69 C1118.2 ; v3(84.52,11.82) 84.32,11.62 C2402.2 ; EC3328.2 v3(45.54,89.28) ; v3(31.53,24.37) 31.41,24.37 31.07,24.02 R5619.2 30.08,24.02 R5622.2 28.17,24.02 C5621.2 ; v3(261.99,17.96) PR5201.2 261.21,18.38 260.81,18.78 PU5201.1 ; v3(249.35,25.67) 248.51,25.67 247.56,26.62 C1206.2 ; C4049.2 v3(50.96,79.19) ; FC9089.2 254.69,51.21 v3(254.54,51.36) 253.96,50.77 253.49,50.77 C1214.2 252.73,50.76 FC9090.2 ; C2501.2 198.86,6.57 199,6.7 v3(199.04,6.7) ; C2204.2 187.62,32.41 v3(187.36,32.67) 187.64,32.95 R2210.2 ; FC9092.2 241.59,12.91 241.38,12.71 v3(239.64,12.71) ; v3(84.54,14.97) C2410.2 85.73,14.27 C2420.2 ; v3(117.16,26.96) PC5402.1 ; C1313.2 235.98,38.16 v3(235.98,37.05) ; v2(232.16,39.1) 232.17,39.1 232.11,39.16 C1327.2 231.81,40.67 C1314.2 ; R1517.2 184.34,20.38 184.23,20.27 184.23,20 183.72,19.5 v3(183.74,19.5) ; v3(120.92,33.69) 121.02,33.78 PR5407.2 ; C2401.1 91.11,8.76 C2415.2 91.64,9 92.14,9.51 v3(92.14,9.54) 92.24,9.54 92.56,9.86 C2406.2 ; C3005.2 222.41,97.5 C3004.2 v3(222.63,96.23) ; v3(27.56,88.01) 27.56,89.15 ; ED2902.3 v2(12.09,25.63) ; v3(249.56,63.17) 249.52,63.14 FC9086.2 ; v3(86.22,26.25) 86.87,25.6 C2418.1 ; ED3102.1 v3(60.97,69.2) ; v3(68.25,68.45) 68.25,67.93 68.24,67.93 68.24,67.49 C3129.2 ; v3(249.35,70.06) 249.26,70.15 248.23,70.15 C1237.2 ; EC3322.2 v3(24.7,90.81) ; PR5116.2 216.21,95.03 215.99,95.24 v3(215.99,95.33) 216.14,95.48 PC5116.2 ; EC3321.2 v3(19.75,90.81) ; C1325.2 242.41,49.2 v3(242.49,49.29) ; PC5207.2 v3(121.28,19.85) ; v3(110.13,48.37) PR4667.2 PR4668.2 ; C3130.2 v3(61.57,65.75) ; v3(98.97,80.84) 99.13,80.84 99.39,80.57 99.53,80.57 99.89,80.22 PR4508.2 PR4507.2
  BOTTOM w0.635: C4085.1 148.82,20.83 v3(148.82,20.85)
  BOTTOM w0.762: v3(62.68,91.34) 63.53,90.49 C3147.2
  BOTTOM w1.016: SATA1.S7 4.64,56.02 ; SATA1.S7 5.48,55.24 ; SATA1.S7 3.8,55.24 ; 5.48,51.44 SATA1.S4 3.8,51.44 ; 8.89,71.4 HS6.1 ; HS6.1 12.4,67.89 ; HS6.1 15.91,71.4 ; HS6.1 12.4,74.91 ; 3.8,65.41 SATA1.P4 5.48,65.41 ; 13.86,19.2 13.89,19.18 C5537.2 C5538.2 v3(13.89,15.06) ; 5.48,66.67 SATA1.P5 3.8,66.67 ; 111.99,82.61 H2.8 112.15,82.84 ; 247.89,96.9 H4.2 247.66,97.06 ; SATA1.23 3.91,46.54 ; SATA1.23 3.91,44.31 ; SATA1.23 5.73,45.43 ; 250.33,96.42 H4.3 250.63,96.43 ; 3.8,73.03 SATA1.P10 5.48,73.03 ; 115.72,76.62 H2.3 116.02,76.62 ; 52.58,97.08 USB3R1.11 ; USB3R1.11 53.6,98.85 ; USB3R1.11 54.62,97.08 ; SATA1.24 5.73,81.57 ; SATA1.24 3.91,82.69 ; SATA1.24 3.91,80.46 ; 3.8,75.56 SATA1.P12 5.48,75.56 ; 113.28,77.1 H2.2 113.05,77.26 ; 3.8,67.94 SATA1.P6 5.48,67.94 ; 5.48,47.62 SATA1.S1 5.48,46.85 ; USB3R1.10 67.42,97.08 ; USB3R1.10 65.38,97.08 ; USB3R1.10 66.4,98.85 ; 194.38,97.08 USB3R2.10 195.4,98.85 ; 3.8,74.3 SATA1.P11 5.48,74.3 ; 246.28,99.13 H4.1 246.12,99.67 ; 246.76,102.64 H4.8 246.6,102.41 ; 111.67,79.33 H2.1 111.51,79.87
  vias: v1(5.16,90.67) v1(6.66,19.9) v1(8.27,57.55) v1(9.25,78.64) v1(9.59,54.89) v1(9.9,63.1) v1(9.95,57.89) v1(15.49,102.71) v1(15.51,63.34) v1(49.84,92.62) v1(51.48,103.29) v1(53.18,102.81) v1(62.28,102.81) v1(65.11,101.55) v1(107.34,81.23) v1(107.34,71.96) v1(122.78,81.51) v1(259.79,80.65) v1(260.24,77.96) v2(6.32,12.2) v2(7.43,9.5) v2(9.54,5.06) v2(10.57,5.07) v2(11.58,5.1) v2(13.01,25.64) v2(22.14,10.7) v2(22.18,9.78) v2(23,10.27) v2(33.19,51.33) v2(36,63.74) v2(36.16,64.69) v2(40.55,48.92) v2(41.58,48.94) v2(64.83,48.98) v2(65.12,50.8) v2(67.21,48.24) v2(67.68,91.84) v2(68.12,48.21) v2(68.59,91.84) v2(69.04,48.21) v2(72.16,48.21) v2(73.08,48.18) v2(73.99,48.18) v2(82.89,61.41) v2(82.89,60.45) v2(90.35,54.57) v2(91.17,54.17) v2(96.49,81.74) v2(103.91,61.42) v2(103.91,60.4) v2(103.91,59.36) v2(104.1,69.16) v2(104.83,61.89) v2(104.83,60.88) v2(104.83,59.84) v2(104.83,58.83) v2(105.01,69.1) v2(106.49,66.16) v2(106.58,64.68) v2(106.62,63.58) v2(107.53,69.15) v2(107.6,67.65) v2(107.71,64.71) v2(107.77,63.49) v2(108.45,69.15) v2(108.51,67.65) v2(109.36,69.15) v2(109.43,67.65) v2(110.28,69.15) v2(110.34,67.65) v2(117.25,66.4) v2(117.2,65.25) v2(122.87,3.25) v2(124.18,3.23) v2(125.41,73.35) v2(125.41,72.44) v2(125.41,71.52) v2(125.4,66.97) v2(125.4,66.05) v2(125.4,65.14) v2(132.04,68.91) v2(132,67.91) v2(132.23,71.41) v2(132.15,66.94) v2(132.18,49.6) v2(132.17,48.68) v2(132.57,70.55) v2(132.91,67.91) v2(132.96,68.91) v2(133.07,66.94) v2(133.09,49.72) v2(133.09,48.79) v2(133.15,71.4) v2(133.52,70.53) v2(133.9,68.9) v2(133.86,67.9) v2(134.01,66.92) v2(134,49.72) v2(134,48.8) v2(134.09,71.39) v2(134.56,70.53) v2(134.81,68.9) v2(134.77,67.9) v2(134.92,66.92) v2(135.01,71.39) v2(135.48,42.69) v2(135.51,41.78) v2(135.68,68.49) v2(136.42,41.75) v2(136.59,68.49) v2(137.51,68.49) v2(138.42,68.49) v2(139.34,68.49) v2(139.5,69.45) v2(140.25,68.49) v2(140.41,69.45) v2(141.17,68.49) v2(141.32,69.45) v2(142.08,68.49) v2(142.24,69.45) v2(142.9,68.09) v2(143.05,69) v2(143.48,69.85) v2(143.82,68.13) v2(143.99,69.03) v2(144.5,69.85) v2(144.74,68.13) v2(144.95,69.02) v2(145.46,69.87) v2(145.67,68.13) v2(145.9,69.06) v2(146.36,70.04) v2(146.48,67.71) v2(149.15,69.41) v2(151.27,79.22) v2(152.66,50.03) v2(153.58,50.03) v2(154.58,79.18) v2(228.79,92.53) v2(228.79,91.62) v2(229.44,93.47) v2(229.71,92.54) v2(229.71,91.63) v2(229.93,94.32) v2(230.37,93.44) v2(230.62,92.54) v2(230.62,91.63) v2(231.29,93.44) v2(231.54,92.54) v2(231.54,91.62) v2(232.58,93.04) v2(232.56,92.12) v2(232.59,91.21) v2(232.59,90.3) v2(255.94,89.12) v2(255.93,88.2) v2(255.93,87.24) v2(255.94,84.96) v2(255.97,84.02) v2(255.96,83.11) v3(1.02,21.59) v3(1.02,16.51) v3(1.02,13.97) v3(1.02,11.43) v3(1.02,8.89) v3(1.02,6.35) v3(1.02,3.81) v3(1.22,1.02) v3(2.52,90.76) v3(2.52,88.22) v3(2.52,85.68) v3(2.52,75.52) v3(2.52,72.98) v3(2.52,70.44) v3(2.52,67.9) v3(2.52,65.36) v3(2.52,62.82) v3(2.52,60.28) v3(2.52,57.74) v3(2.52,55.2) v3(2.52,52.66) v3(2.52,50.12) v3(2.52,42.5) v3(2.52,29.8) v3(2.52,27.26) v3(3.76,1.02) v3(5.41,12.2) v3(6.3,1.02) v3(6.57,17.8) v3(8.84,1.02) v3(10.94,104.28) v3(11.16,58.2) v3(11.38,1.02) v3(13.48,104.28) v3(13.92,1.02) v3(16.46,1.02) v3(18.56,104.28) v3(18.74,54.9) v3(19,1.02) v3(19.14,53.04) v3(19.87,51.16) v3(20.88,56.94) v3(21.1,104.28) v3(21.54,1.02) v3(22.41,55.46) v3(22.48,50.64) v3(22.89,48.65) v3(23.64,104.28) v3(24,24.63) v3(24.13,3.5) v3(24.08,1.02) v3(24.82,24.67) v3(26.18,104.28) v3(26.57,84.68) v3(28.19,6.02) v3(28.35,19.67) v3(28.37,20.44) v3(28.72,104.28) v3(29.51,91.74) v3(29.51,90.93) v3(30.15,72.91) v3(30.15,71.64) v3(30.15,70.37) v3(30.25,91.72) v3(30.25,90.91) v3(30.73,6.02) v3(30.96,90.81) v3(30.96,89.99) v3(31.26,104.28) v3(31.42,72.91) v3(31.42,71.64) v3(31.42,70.37) v3(32.05,29.57) v3(32.44,30.7) v3(32.69,72.91) v3(32.69,71.64) v3(32.69,70.37) v3(33.27,6.02) v3(33.47,89.36) v3(33.8,104.28) v3(33.9,31.25) v3(34.07,25.47) v3(34.26,89.35) v3(35.02,17.87) v3(35.11,86.75) v3(35.08,85.99) v3(35.5,96.63) v3(35.5,94.85) v3(35.74,25.47) v3(35.81,6.02) v3(35.91,23.86) v3(36.23,31.1) v3(36.34,104.28) v3(36.39,95.74) v3(37.25,94.85) v3(37.23,70.83) v3(37.28,96.63) v3(37.67,25.47) v3(38.01,18.18) v3(38.18,30.33) v3(38.35,6.02) v3(38.88,104.28) v3(39.66,29.12) v3(40.5,27.69) v3(40.6,25.85) v3(40.89,6.02) v3(41.42,104.28) v3(42.06,17.64) v3(42.82,27.66) v3(43.39,92.21) v3(43.43,6.02) v3(43.96,104.28) v3(44.17,90.09) v3(44.45,18.78) v3(45.52,82.01) v3(45.97,6.02) v3(46.28,82.01) v3(46.51,19.57) v3(48.51,6.02) v3(49.04,104.28) v3(50.51,82.5) v3(50.56,84.64) v3(51.05,6.02) v3(51.58,104.28) v3(52.84,78.38) v3(53.01,84.55) v3(53.14,80.48) v3(53.52,58.11) v3(53.59,6.02) v3(54.12,104.28) v3(54.9,84.78) v3(54.87,59.34) v3(55.06,58.58) v3(56.13,6.02) v3(56.31,80.04) v3(56.66,104.28) v3(58.67,6.02) v3(59.2,104.28) v3(61.62,84.11) v3(61.74,104.28) v3(61.74,91.26) v3(62.38,84.88) v3(62.38,84.11) v3(62.38,83.35) v3(62.74,54.18) v3(63.14,84.11) v3(63.4,74.79) v3(64.02,15.44) v3(64.28,104.28) v3(64.65,37.78) v3(64.8,40.66) v3(64.93,43.37) v3(64.87,3.1) v3(65.23,37.2) v3(65.32,1.02) v3(65.5,15.29) v3(65.58,75.11) v3(65.87,36.55) v3(66.2,28.36) v3(66.44,76.34) v3(66.42,23.64) v3(66.51,39.24) v3(66.82,104.28) v3(66.97,30.18) v3(67.09,29.06) v3(67.08,25.66) v3(67.25,26.84) v3(67.17,24.38) v3(67.6,43.5) v3(67.67,22.3) v3(68.49,76) v3(68.6,41.3) v3(68.57,37.62) v3(69.1,1.03) v3(69.36,104.28) v3(69.41,75.07) v3(71.43,39.32) v3(71.58,75) v3(71.9,104.28) v3(72.41,37.51) v3(72.77,76.53) v3(73.98,103.83) v3(73.98,101.29) v3(73.98,98.75) v3(73.98,96.21) v3(73.98,93.67) v3(73.98,91.13) v3(73.98,88.59) v3(74.33,76.53) v3(76.45,84.48) v3(76.8,34.76) v3(78.99,84.48) v3(81.53,84.48) v3(84.07,84.48) v3(86,74.31) v3(86.12,72.75) v3(86.61,84.48) v3(86.8,70.81) v3(86.93,68.64) v3(89.15,84.48) v3(89.56,65.44) v3(89.84,79.43) v3(89.84,77.11) v3(89.83,67.59) v3(90.12,75.91) v3(90.15,73.04) v3(90.7,70.35) v3(91.69,84.48) v3(92.29,76.14) v3(92.45,72.89) v3(92.96,70.19) v3(93.14,67.66) v3(93.18,80.34) v3(93.18,71.29) v3(93.17,69.02) v3(93.34,31.1) v3(94.23,84.48) v3(96.33,62.2) v3(96.42,61.08) v3(96.77,84.48) v3(96.87,73.41) v3(96.9,72.39) v3(99.31,84.48) v3(101.85,84.48) v3(102.03,75.31) v3(102.59,75.87) v3(103.15,76.43) v3(103.15,75.31) v3(104.39,84.48) v3(104.8,15.19) v3(105.37,69.91) v3(105.67,15.18) v3(106.93,84.48) v3(109.47,84.48) v3(117.36,34.08) v3(117.99,33.57) v3(118.5,3.39) v3(118.63,34.08) v3(119.23,50.5) v3(120.14,51.41) v3(120.14,50.5) v3(120.14,49.58) v3(121.06,50.5) v3(122.17,84.48) v3(124.71,84.48) v3(125.27,31.85) v3(125.72,41.61) v3(125.98,31.85) v3(126.71,31.85) v3(127.25,84.48) v3(129.79,84.48) v3(130.7,19.98) v3(131.45,20.01) v3(132.33,84.48) v3(133.38,25.62) v3(134.87,84.48) v3(135.51,25.65) v3(137.41,84.48) v3(138.67,18.73) v3(139.85,25.58) v3(139.95,84.48) v3(140.82,18.75) v3(141.05,2.39) v3(141.76,2.41) v3(142.49,84.48) v3(144.3,40.78) v3(144.3,39.67) v3(144.86,40.22) v3(145.03,84.48) v3(145.42,40.78) v3(145.42,39.67) v3(146.21,24.72) v3(146.24,23.43) v3(146.15,8.1) v3(147.57,84.48) v3(150.11,84.48) v3(150.21,16.06) v3(151.01,16.04) v3(151.91,16.04) v3(152.65,84.48) v3(153.15,62.07) v3(153.94,62.07) v3(155.19,84.48) v3(155.45,48.77) v3(156.12,5.1) v3(156.41,58.47) v3(157.26,30.18) v3(157.35,48.36) v3(157.37,31.12) v3(157.57,58.11) v3(157.73,84.48) v3(157.92,61.5) v3(157.96,62.67) v3(158.28,32.39) v3(158.29,31.68) v3(158.35,5.1) v3(159.37,58.79) v3(160.27,84.48) v3(160.46,57.89) v3(161.95,4.89) v3(162.61,58.31) v3(162.65,26.1) v3(162.81,84.48) v3(164.08,4.89) v3(164.24,7.06) v3(164.92,26.11) v3(165.22,32.01) v3(165.35,84.48) v3(165.48,33.37) v3(166.49,7.05) v3(166.82,38.58) v3(166.91,37.41) v3(167.02,36.24) v3(167.45,32) v3(167.89,84.48) v3(167.87,49.01) v3(168.26,26.08) v3(168.67,37.62) v3(168.7,33.57) v3(168.87,53.06) v3(168.95,48.92) v3(169.01,56.12) v3(168.98,50.94) v3(168.97,45.26) v3(170.43,84.48) v3(170.63,49.4) v3(170.55,47.51) v3(170.97,42.79) v3(171.16,56.71) v3(171.17,55.77) v3(171.17,53.03) v3(171.18,52.13) v3(172.42,46.64) v3(172.49,53.96) v3(172.52,53.05) v3(172.52,52.13) v3(172.52,49.39) v3(172.6,57.62) v3(172.59,47.56) v3(172.69,26.82) v3(172.8,80.92) v3(172.97,84.48) v3(173.07,56.71) v3(173.24,41.15) v3(173.25,38.4) v3(173.2,36.56) v3(173.18,35.66) v3(173.53,80.91) v3(174.91,49.55) v3(175.02,104.25) v3(175.02,101.71) v3(175.02,99.17) v3(175.02,96.63) v3(175.02,94.09) v3(175.02,91.55) v3(175.02,89.01) v3(175.74,71.03) v3(176.02,80.97) v3(176.74,81.3) v3(177.22,73.57) v3(177.34,60.58) v3(177.31,59.9) v3(177.37,32.26) v3(177.53,104.28) v3(177.79,62.59) v3(177.77,61.48) v3(178.09,32.61) v3(178.74,81.28) v3(178.82,32.12) v3(179.23,87.34) v3(179.44,89.47) v3(180.07,104.28) v3(182.48,32.33) v3(182.61,104.28) v3(183.25,32.36) v3(183.77,73.7) v3(184.41,73.69) v3(184.55,75.3) v3(185.15,104.28) v3(186.63,38.09) v3(187.69,104.28) v3(188.57,15.62) v3(190.23,104.28) v3(191.41,77.67) v3(192.77,104.28) v3(195.31,104.28) v3(196.7,100.69) v3(197.47,100.7) v3(197.71,1.02) v3(197.85,104.28) v3(199.63,100.67) v3(200.25,1.02) v3(200.39,104.28) v3(202.17,101.27) v3(202.21,99.12) v3(202.79,1.02) v3(202.93,104.28) v3(204.3,101.24) v3(205.33,1.02) v3(205.47,104.28) v3(206.18,66.09) v3(207.77,64.64) v3(207.87,1.02) v3(208.01,104.28) v3(210.41,1.02) v3(210.55,104.28) v3(211.1,95.48) v3(211.98,95.48) v3(212.95,1.02) v3(213.09,104.28) v3(214.67,11.37) v3(215.49,1.02) v3(215.63,104.28) v3(216.48,101) v3(218.03,1.02) v3(218.17,104.28) v3(219.44,84.2) v3(219.94,91.37) v3(219.93,90.25) v3(220.51,90.8) v3(220.57,1.02) v3(220.71,104.28) v3(221.04,90.28) v3(221.09,91.39) v3(223.11,1.02) v3(223.25,104.28) v3(224.53,6.24) v3(225.44,6.24) v3(225.65,1.02) v3(225.79,104.28) v3(227.23,6.24) v3(228.19,1.02) v3(228.33,104.28) v3(228.25,96.69) v3(228.29,95.93) v3(228.72,98.05) v3(228.94,96.35) v3(230.73,1.02) v3(230.87,104.28) v3(233.27,1.02) v3(235.45,4.78) v3(235.77,35.6) v3(235.76,34.17) v3(235.81,1.02) v3(236.5,61.88) v3(236.54,40.73) v3(236.48,28.67) v3(236.49,17.98) v3(236.65,4.78) v3(236.82,72.45) v3(237.34,56.57) v3(237.53,40.24) v3(237.52,23.43) v3(237.49,12.75) v3(237.63,4.78) v3(237.95,34.2) v3(238.24,46.42) v3(238.24,44.92) v3(238.35,1.02) v3(240.89,1.02) v3(242.26,4.71) v3(243.22,4.71) v3(243.43,1.02) v3(244.27,4.72) v3(245.51,35.11) v3(245.97,1.02) v3(246.28,4.58) v3(247.24,4.58) v3(248.51,1.02) v3(249.63,4.6) v3(251.05,1.02) v3(251.48,39.95) v3(251.51,28.64) v3(251.63,18.01) v3(251.96,65.57) v3(252.52,23.43) v3(252.52,12.93) v3(252.59,43.43) v3(253.24,46.42) v3(253.61,7.75) v3(253.59,1.02) v3(256.13,1.02) v3(256.27,104.28) v3(258.67,1.02) v3(258.81,104.28) v3(261.35,104.28) v3(262.98,103.38) v3(262.98,100.84) v3(262.98,98.3) v3(262.98,95.76) v3(262.98,93.22) v3(262.98,90.68) v3(262.98,88.14) v3(262.98,85.6) v3(262.98,83.06) v3(262.98,80.52) v3(262.98,77.98) v3(262.98,75.44) v3(262.98,72.9) v3(262.98,70.36) v3(262.98,67.82) v3(262.98,65.28) v3(262.98,62.74) v3(262.98,60.2) v3(262.98,57.66) v3(262.98,55.12) v3(262.98,52.58) v3(262.98,50.04) v3(262.98,47.5) v3(262.98,44.96) v3(262.98,39.88) v3(262.98,37.34) v3(262.98,34.8) v3(262.98,32.26) v3(262.98,29.72) v3(262.98,27.18) v3(262.97,17.95) v3(262.98,17.02) v3(262.98,14.48) v3(262.98,6.86) v4(186.57,76.82) v4(188.33,77.24) v4(188.33,75.95) v4(189.18,76.34) v4(189.35,78.2) v4(195.3,43.23) v4(195.42,42.66) v4(196.05,43.31) v4(196.28,74.51) v4(196.26,53.2) v4(196.37,62.48) v4(196.64,61.21) v4(196.67,72.25) v4(196.85,56.5) v4(196.96,60.23) v4(197.21,51.39) v4(197.4,42.95) v4(197.51,73.29) v4(197.5,55.09) v4(197.82,52.27) v4(198.01,53.25) v4(198.14,57.91) v4(198.06,43.51) v4(198.24,74.51) v4(198.39,61.21) v4(198.67,55.08) v4(198.91,73.29) v4(198.94,41.4) v4(198.99,52.27) v4(198.99,50.48) v4(199.21,72.25) v4(199.56,56.91) v4(199.96,53.31) v4(200.01,41.91) v4(200.14,49.24) v4(200.48,55.08) v4(200.8,55.63) v4(200.93,58.24) v4(209.28,67.73) v4(210.57,62.97) v4(212.62,67.5) v4(213.41,63.08) v4(213.62,36.28) v4(213.79,39.09) v4(214.82,66.96) v4(214.79,35.36) v4(214.95,38.1) v4(215.37,65.45) v4(215.54,36.41) v4(217.49,35.95)
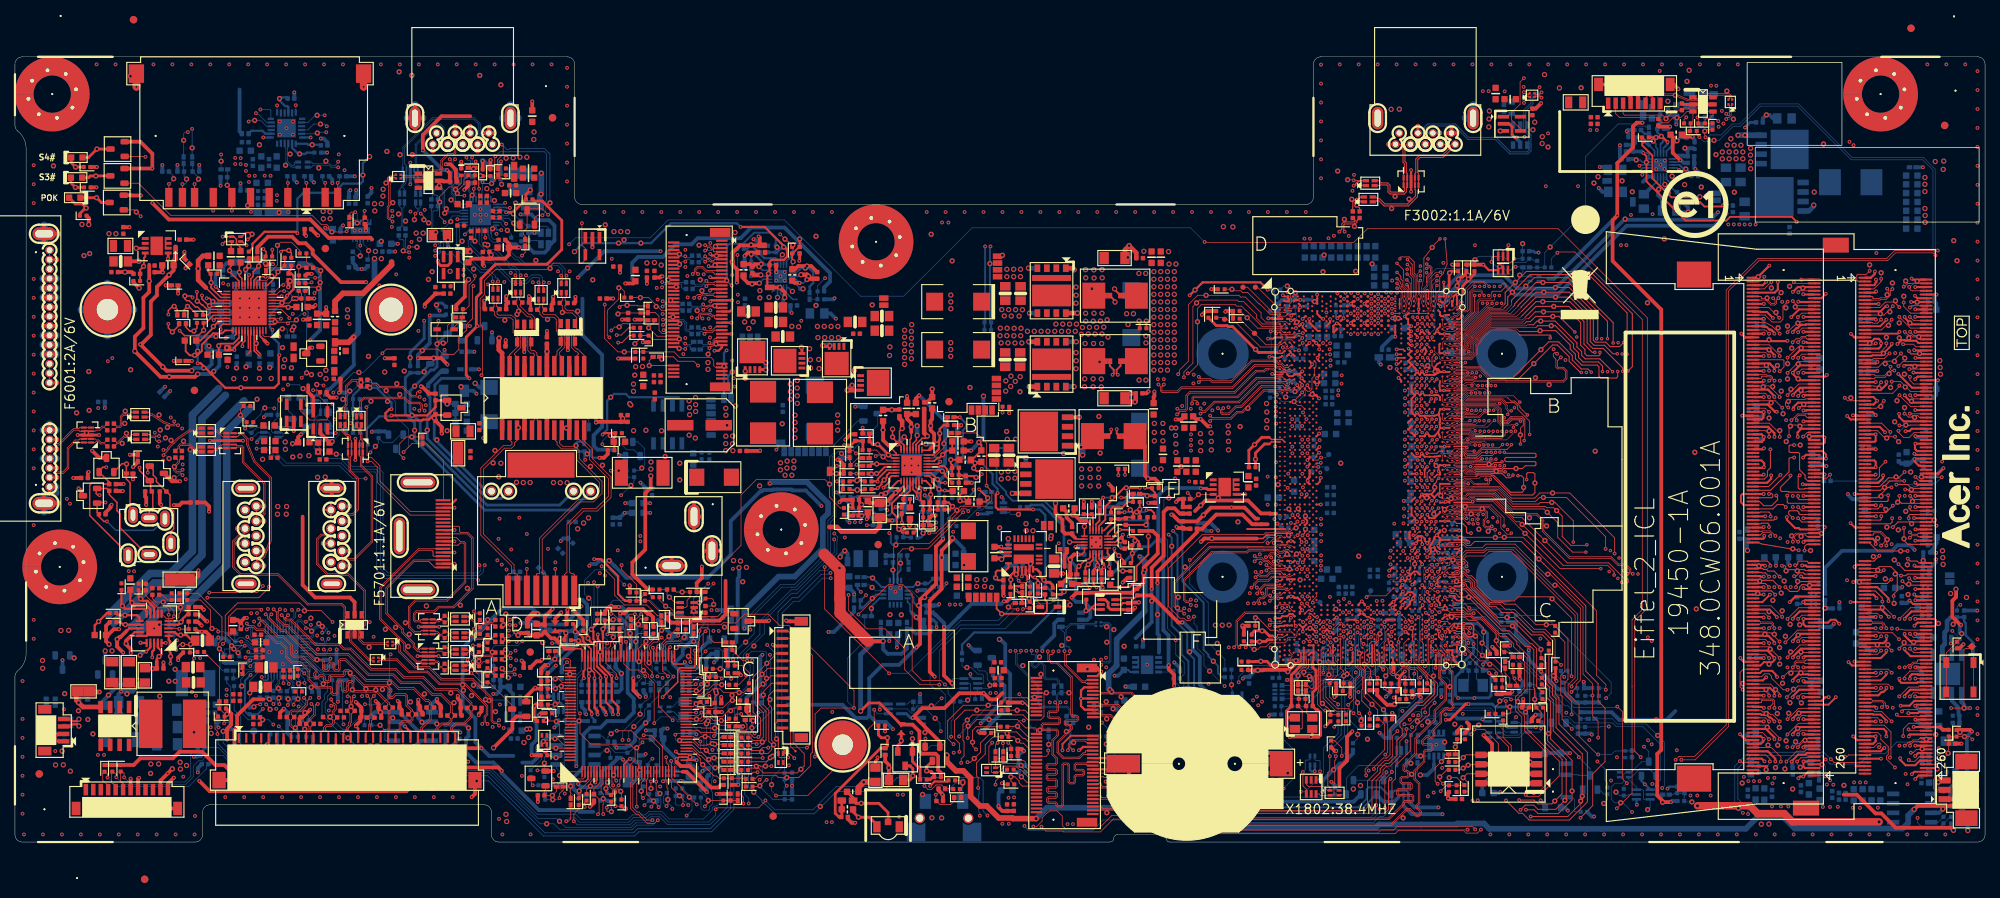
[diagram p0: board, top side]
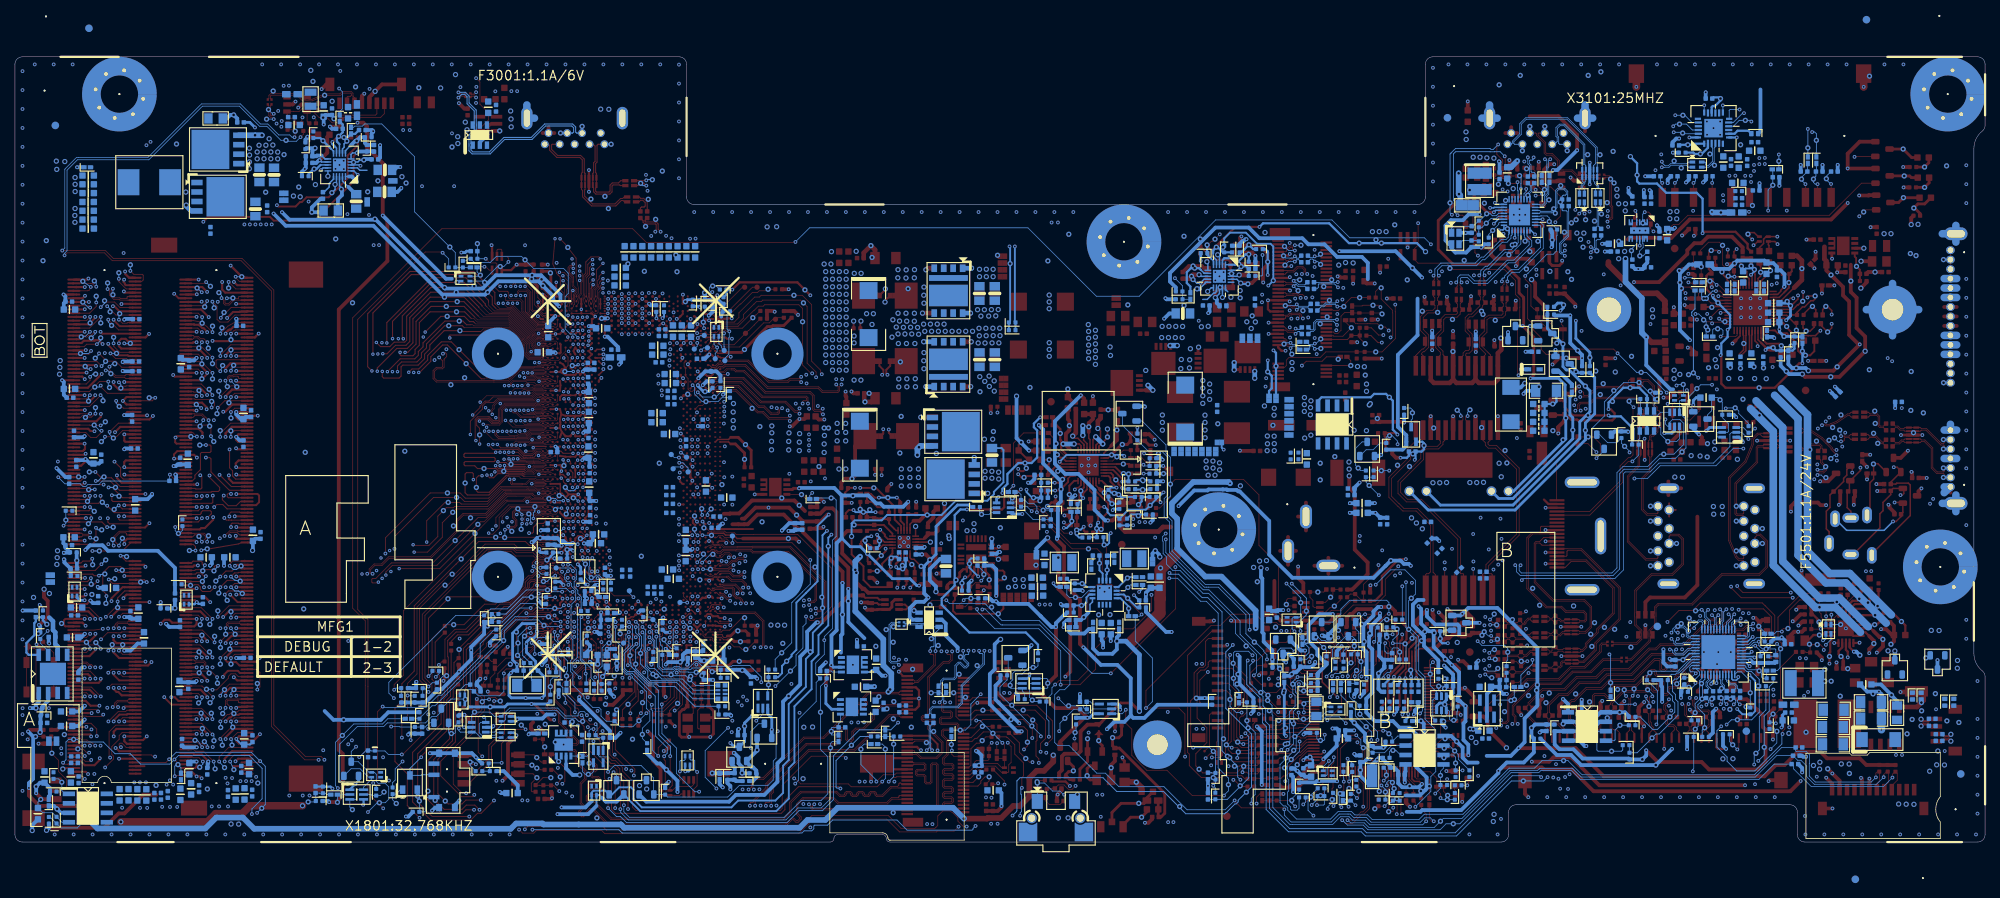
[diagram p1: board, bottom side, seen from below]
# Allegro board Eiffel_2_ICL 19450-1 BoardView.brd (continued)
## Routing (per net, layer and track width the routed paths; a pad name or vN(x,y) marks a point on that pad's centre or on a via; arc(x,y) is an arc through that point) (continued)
V12: length 3.5
  TOP w0.102: SATA1.P13 SATA1.P14 SATA1.P15
  BOTTOM w0.102: SATA1.P14 v1(5.57,78.11)
V33: length 3.5
  TOP w0.102: SATA1.P3 SATA1.P2 SATA1.P1
  BOTTOM w0.102: SATA1.P1 v1(5.57,61.59)
VCCAUX_SENSE: length 29.1
  TOP w0.254: PR5016.2 151.45,46.7 v1(151.71,46.44) 151.76,46.39 PC5013.2 152.78,46.84 152.37,47.25 PR5017.2 152.33,47.51 v3(151.44,47.51) ; v3(173.2,50.34) 173.2,50.34 173.2,50.35 173.48,50.62 CPU1.BF9
  L4 w0.254: v3(151.44,47.51) 151.57,47.63 154.17,47.63 155.73,47.63 156.5,48.4 156.5,49.01 157.76,50.27 166.31,50.27 167.45,51.42 170.07,51.42 170.95,50.54 172.99,50.54 173.2,50.35 v3(173.2,50.34)
VCCCORE_SENSE: length 88.8
  TOP w0.254: v3(177.22,70.26) 177.52,70.57 CPU1.F17 ; PR4671.2 123.07,42.49 v3(123.44,42.86)
  L4 w0.254: v3(123.44,42.86) 123.62,42.68 124.04,42.68 124.5,43.14 124.5,44.76 126.39,46.65 130.52,46.65 131.66,45.51 132.77,45.51 134.18,44.09 138.25,44.09 138.7,43.64 140.24,43.64 143.36,40.51 143.36,39.76 144.91,38.21 147.87,38.21 150.31,40.65 150.31,45.22 149.15,46.38 149.15,48.08 150.23,49.16 154.48,49.16 157.18,51.86 164.88,51.86 167.86,54.84 172.67,54.84 176.17,58.34 176.17,62.45 177.66,63.93 177.66,69.82 v3(177.22,70.26)
  BOTTOM w0.254: R704.2 177.02,70.45 v3(177.22,70.26)
VCCIN_AUX_VID0: length 143.4
  TOP w0.254: PR5035.1 144.52,34.56 v3(144.94,34.14)
  TOP w0.305: v3(188.02,39.08) 187.61,38.67 CPU1.CL38
  L3 w0.254: v3(155.19,41.73) 155.32,41.59 155.32,40.88 150.58,36.13 149.65,36.13 148.95,35.43 148.95,34.59 148.65,34.29 148.23,34.29 147.8,34.72 145.2,34.72 144.94,34.47 v3(144.94,34.14)
  L4 w0.254: 191.5,39.28 190.07,39.28 189.8,39.55 189,39.55 188.53,39.08 v3(188.02,39.08)
  L4 w0.508: v3(190.75,4.64) 192.41,4.64 193.49,5.73 193.49,6.91 193.53,6.95 193.53,7.42 199.53,13.42 200.23,13.42 202.98,16.17 202.98,17.22 203.71,17.96 203.71,18.08 204.32,18.69 204.32,21.07 205.12,21.87 205.12,22.22 205.24,22.34 205.24,25.51 202.13,28.62 199.82,28.62 195.29,33.14 195.29,38 194.62,38.67 192.72,38.67 192.12,39.28 191.5,39.28
  BOTTOM w0.254: 186.72,5.62 RN2201.3 186.72,6.63 186.47,6.88 184.87,6.88 D4005.1 183.98,6.39 183.03,7.34 181.44,7.34 181.12,7.02 181.12,5.78 179.99,4.65 167.99,4.65 167.08,5.56 162.09,5.56 161.06,6.59 161.06,9.31 161.06,10.23 160.31,10.99 160.31,18.51 158.01,20.81 158.01,24.55 157.08,25.48 157.08,28.06 155.78,29.36 v1(155.78,31.39) 155.78,41.13 v3(155.19,41.73)
  BOTTOM w0.508: 186.72,5.62 186.72,5.48 187.56,4.64 v3(190.75,4.64)
VCCIN_AUX_VID1: length 150.1
  TOP w0.254: PR5034.1 143.43,34.71 v3(144.02,34.12)
  TOP w0.305: v3(187.2,39.07) 187.61,39.48 CPU1.CJ38
  L3 w0.254: v3(154.59,41.23) 153.48,40.11 153.48,40.09 152.35,38.96 152.33,38.96 150.26,36.89 149.53,36.89 147.93,35.29 144.71,35.29 144.02,34.61 v3(144.02,34.12)
  L4 w0.254: 190.09,40.46 189.71,40.46 189.48,40.7 187.6,40.7 187.1,40.19 187.1,39.18 v3(187.2,39.07)
  L4 w0.508: 190.09,40.46 193.44,40.46 194.44,39.45 194.74,39.45 195.97,38.21 195.97,33.54 200.13,29.38 203.38,29.38 206,26.76 206,25.82 206,22.02 205.88,21.9 205.88,21.55 205.54,21.21 205.54,14.02 204.94,13.42 201.48,13.42 200.72,12.66 199.84,12.66 194.29,7.1 194.29,5.45 192.72,3.88 191.44,3.88 v3(191.29,3.74)
  BOTTOM w0.254: D4005.2 181.88,5.87 181.88,5.82 180.21,4.14 161.98,4.14 160.3,5.82 160.3,9.92 159.55,10.67 159.55,18.2 157.25,20.5 157.25,24.23 156.32,25.16 156.32,27.74 155.01,29.06 v1(155.01,39.67) 155.01,40.81 v3(154.59,41.23) ; 186.07,4.85 RN2201.4 185.69,6.3 185.33,5.93
  BOTTOM w0.508: 186.07,4.85 187.18,3.74 v3(191.29,3.74) ; D4005.2 183.38,5.41 184.81,5.41 185.33,5.93
VCCPLL_OC:
  vias: v1(192.94,15.79)
VCCST_EN: length 49.3
  TOP w0.102: v3(183.78,9.36) 183.78,9.13 182.87,8.22 v3(182.87,4.41)
  BOTTOM w0.102: R4054.2 154.48,13.47 154.71,13.23 v1(154.71,12.64) 154.71,5.8 155.94,4.57 159.07,4.57 160.68,2.96 181.81,2.96 182.83,3.98 182.83,4.36 v3(182.87,4.41) ; v3(183.78,9.36) 183.39,8.97 D4005.3 D4004.3
VCCST_OVERRIDE: length 54.5
  TOP w0.254: R4052.2 150.06,32.76 148.43,32.76 148.18,32.5 Q4004.6
  TOP w0.508: R4052.2 152.27,33.07 155.89,29.45 v3(156.43,29.45)
  BOTTOM w0.508: D4004.1 179.38,5.41 168.31,5.41 167.4,6.32 163.57,6.32 161.83,8.07 161.83,10.55 161.07,11.3 161.07,18.83 v1(160.33,19.58) 158.77,21.13 158.77,24.87 157.85,25.79 157.85,28.2 156.6,29.45 v3(156.43,29.45)
VCCST_OVERRIDE_N: length 5.1
  TOP w0.254: 144.34,31.46 143.92,31.04 v1(143.53,31.04) 143.53,31.95 143.57,31.99 R4053.2 ; 144.34,31.46 144.73,31.85 Q4004.2 ; 144.34,31.46 144.59,31.2 Q4004.3
VCCST_PWRGD: length 30.9
  TOP w0.102: v3(157.43,37.82) 157.55,37.82 159.88,40.15 167.23,40.15 167.94,40.86 168.93,40.86 169.2,41.13 169.67,41.13 169.95,40.85 CPU1.CF2
  BOTTOM w0.102: v3(157.43,37.82) 157.43,34.59 158.45,33.57 158.45,33.56 159.81,32.2 159.82,32.2 159.91,32.1 159.91,26.72 v1(161.25,25.38) 162.13,24.5 R4005.2
VCCST_PWRGD_R: length 3.6
  BOTTOM w0.102: R4005.1 163.02,22.1 R4004.1 v1(163.02,21.09) 163.02,20.53 163.13,20.42 U4013.4
VCCSTPWRGOOD_TCSS: length 28.1
  TOP w0.203: 166.42,40.7 167.23,40.7 167.69,41.17 168.78,41.17 169.02,41.41 CPU1.CE3 CPU1.CE4
  TOP w0.254: Q4004.5 148.27,31.85 148.46,32.04 R4057.2
  TOP w0.508: R4057.2 149.62,32.04 149.7,32.12 150.59,32.12 v3(150.62,32.15) ; v3(158.93,40.27) 158.95,40.27 159.38,40.7 v1(160.36,40.7) 166.42,40.7
  L3 w0.508: v3(150.62,32.15) 151.42,32.15 154.38,35.11 154.38,35.88 158.77,40.27 v3(158.93,40.27)
VDDQ_EN: length 231.4
  TOP w0.102: v3(97.98,22.35) 97.98,22.09 96.98,21.09 R24053.2
  L3 w0.127: v3(109.8,41.37) 109.49,41.68 109.49,49.21 109.13,49.57 109.13,52.49 111.23,54.58 111.23,57.7 114.78,61.26 114.78,63.16 113.74,64.2 113.74,68.51 128.36,83.13 165.84,83.13 166.17,82.8 169.75,82.8 174.73,82.8 176.86,84.94 176.86,93.9 177.7,94.73 177.7,98.03 182.51,102.84 200.41,102.84 201.48,101.77 204.47,101.77 206.01,100.22 206.01,97.32 206.4,96.93 212.06,96.93 212.51,97.38 212.59,97.38 214.33,99.12 218.62,99.12 v3(220.55,101.05) ; v3(97.98,22.35) 98.01,22.38 103.35,22.38 103.45,22.28 105.67,22.28 107.05,20.9 115.05,20.9 115.79,20.16 118.76,20.16 119.3,20.7 121.91,20.7 122.37,20.25 122.9,20.25 123.87,19.27 v3(124.18,19.27)
  BOTTOM w0.102: v3(109.8,41.37) 110.24,40.93 110.24,40.4 110.14,40.3 110.14,38.69 109.68,38.23 109.68,37.26 108.83,36.41 107.85,36.41 104.8,33.35 104.04,33.35 100.45,29.76 100.45,27.97 97.64,25.16 97.64,22.7 v3(97.98,22.35) ; U4020.4 119.59,18.51 119.9,18.82 PC5207.1 120.38,18.81 120.38,18.34 120.37,18.32 120.37,17.82 R5206.1 120.59,17.81 120.78,17.99 120.78,18.16 120.88,18.26 v1(122.81,18.26) 123.17,18.26 v3(124.18,19.27) ; v3(220.55,101.05) 220.09,100.59 220.09,98.36 220.47,97.97 PR5113.1
VDDQ_EN_EC: length 6.3
  TOP w0.102: ECIO1.55 91.86,19.78 92.54,20.46 92.94,20.46 93.57,21.09 v1(94.72,21.09) R24053.1
VSSAUX_SENSE: length 35.2
  TOP w0.203: 145.57,42.7 145.26,42.39 PU5001.7
  TOP w0.254: CPU1.BD9 173.48,51.5 v3(173.19,51.21) ; v3(150.73,47.5) v1(148.91,47.5) 148.63,47.5 147.4,46.27 PR5018.1 147.1,45.95 146.11,44.96 146.11,43.24 145.57,42.7
  L4 w0.254: v3(173.19,51.21) 172.91,50.93 171.11,50.93 170.23,51.8 167.29,51.8 166.15,50.66 157.6,50.66 156.11,49.17 156.11,48.56 155.57,48.01 154.96,48.01 151.06,48.01 150.73,47.68 150.73,47.5 v3(150.73,47.5)
VSSCORE_SENSE: length 91.1
  TOP w0.254: v3(178.04,70.23) 177.72,69.92 CPU1.G17
  L4 w0.254: v3(123.44,42.13) 123.45,42.13 123.62,42.3 124.2,42.3 124.88,42.98 124.88,44.6 126.54,46.27 130.36,46.27 131.51,45.13 132.61,45.13 134.03,43.71 138.09,43.71 138.54,43.26 140.08,43.26 142.98,40.35 142.98,39.6 144.76,37.83 148.02,37.83 150.69,40.49 150.69,45.38 149.53,46.54 149.53,47.92 150.39,48.78 154.64,48.78 157.34,51.48 165.04,51.48 168.02,54.46 172.83,54.46 176.55,58.18 176.55,62.29 178.04,63.77 v3(178.04,70.23)
  BOTTOM w0.254: R705.2 178.04,71.06 v3(178.04,70.23) ; v3(123.44,42.13) 123.05,42.13 122.39,42.79 v1(122.39,43.03) 122.39,44.18 PR4672.2
0D6V_VREF_S0: length 60.3
  TOP w0.254: v3(254.2,9.11) 254.51,9.42 DIMM1.258
  TOP w0.279: DIMM2.258 240.28,9.42 v3(239.65,8.8) 239.23,8.8 v3(238.98,8.55)
  L4 w1.016: 259.82,78.4 258.57,79.64 258.57,79.7 256.26,82.02 238.28,82.02 230.47,89.84 229.17,89.84 225.83,93.17 222.71,93.17 222.47,92.93 219.76,92.93 219.39,93.3 216.46,93.3 212.38,89.23 v2(212.14,89.23)
  vias: v1(211.58,88.37) v1(238.21,7.11) v1(255.57,12.5) v3(253.36,9.13)
0D85V_S5_VCCLDOSTD_OUT: length 3.1
  TOP w0.203: CPU1.DW37 187.11,24.31 v3(186.96,24.16)
  BOTTOM w0.508: v3(186.96,24.16) 186.65,23.85 v1(185.92,23.85) C2213.1
1D2V_EDP: length 18.4
  L3 w0.508: v3(31.55,23.58) 31.7,23.43 32.92,23.43 34.08,24.58 v3(42.27,24.58)
  BOTTOM w0.203: C5620.1 41.49,24.43 40.49,24.43 v1(40.48,24.45) 40.46,24.45 39.63,25.27 TSMT1.43 ; v3(31.55,23.58) 32.04,24.07 TSMT1.15 ; TSMT1.11 33.94,21.88 33.78,21.72 33.31,21.72 33.07,21.96 v3(33.07,22.13)
  BOTTOM w0.508: C5620.1 42.11,24.43 v3(42.27,24.58)
  vias: v1(30.42,20.92)
1D2V_EDP_SWR: length 1.9
  BOTTOM w0.203: TSMT1.17 31.02,24.87 v3(30.9,24.76)
  vias: v1(29.9,25.38)
1D2V_S3: length 281.2
  TOP w0.076: CPU1.AA49 192.92,63.01 194.6,63.01 v4(194.7,62.92) ; v4(195.16,60.21) 194.69,60.21 194.37,60.53 192.9,60.53 CPU1.AF49 ; CPU1.T49 193.47,65.51 193.56,65.5 194.56,65.5 194.64,65.58 194.64,65.58 v4(194.82,65.76) ; CPU1.AL49 192.91,58.02 194.62,58.02 v4(194.65,57.99) ; CPU1.BF49 193.17,50.55 193.33,50.54 194.5,50.54 194.63,50.4 v4(195.07,50.36) ; v4(195.68,55.16) 195.68,55.27 195.45,55.5 193.32,55.5 CPU1.AT49
  TOP w0.127: v4(194.56,52.89) 194.4,53.04 CPU1.BA49 ; v4(193.83,68.2) 193.76,68.13 CPU1.L49 ; v4(194.75,48.05) 194.73,48.03 CPU1.BM49
  TOP w0.152: CPU1.BU49 192.89,45.52 195.22,45.52 v3(195.34,45.64) ; v3(195.11,41.43) 194.65,41.43 194.52,41.56 194.52,42.21 194,42.73 193.18,42.73 CPU1.CB49
  TOP w0.229: v3(234.34,33.19) 234.32,33.17 DIMM2.163
  TOP w0.254: v3(188.58,43.89) 188.58,43.75 CPU1.CA39 ; CPU1.L38 187.92,67.83 v4(187.92,67.68) ; 249.34,34.17 249.57,34.17 251.06,32.68 v3(251.06,32.31) ; DIMM2.123 231.68,45.17 231.28,45.57 231.28,46.46 231.5,46.68 232.89,46.68 DIMM2.117 ; v3(186.27,50.34) 186.69,50.75 CPU1.BF36 ; v3(245.98,42.76) 246.56,42.17 DIMM1.135 ; CPU1.N36 186.96,66.62 v4(187.2,66.62) ; v3(242.66,73.52) 242.06,72.92 DIMM2.12 ; CPU1.BU37 187.44,46.02 187.45,46.02 CPU1.BT38 ; DIMM2.154 239.63,35.42 239.45,35.6 239.34,35.6 v3(239.34,35.62)
  TOP w0.279: DIMM1.117 v3(246.52,46.67) ; DIMM2.135 234.26,42.17 v3(234.34,42.25) ; v3(250.33,49.17) 250.33,48.82 249.69,48.17 DIMM1.111 ; DIMM1.148 254.69,36.92 v3(254.54,37.08) ; v3(254.53,52.07) 254.68,51.92 DIMM1.96 ; v3(254.65,48.19) 254.92,47.92 DIMM1.112 ; v3(249.34,39.97) 249.34,40.29 248.95,40.67 DIMM1.141 ; v3(239.66,40.23) 239.86,40.42 DIMM2.142 ; DIMM2.54 242.59,62.42 v3(242.8,62.64) ; v3(231.21,24.69) 231.21,24.69 231.21,24.62 231.65,24.17 DIMM2.199 ; v3(234.55,43.68) 234.56,43.68 234.56,43.67 DIMM2.129 ; DIMM1.136 v3(254.66,41.92) ; v3(234.51,37.05) 234.54,37.05 234.41,37.17 DIMM2.147 ; DIMM2.130 v3(239.66,43.42) ; v3(246.51,36.91) 246.51,36.99 246.69,37.17 DIMM1.147 ; v3(254.53,29.01) 254.95,29.42 DIMM1.178 ; v3(239.49,37.09) 239.49,37.08 239.99,37.08 240.15,36.92 DIMM2.148 ; DIMM2.141 234.27,40.67 234.4,40.8 234.4,40.98 234.42,41 234.42,41.06 v3(234.41,41.06) ; v3(235.33,49.17) 235.33,48.72 234.79,48.17 DIMM2.111 ; DIMM2.136 239.21,41.92 239.03,42.11 238.55,42.11 237.44,43.21 v3(237.44,43.57) ; DIMM1.153 v3(249.34,35.67) ; DIMM2.160 239.78,33.93 v3(239.66,34.04) ; DIMM2.96 239.99,51.92 v3(239.62,51.56) ; DIMM1.142 v3(254.66,40.42) ; v3(254.61,73.25) 254.94,72.92 DIMM1.12 ; v3(244.46,29.28) 243.94,29.81 243.32,29.81 242.94,29.42 DIMM2.178 ; v3(239.57,47.98) 239.62,47.93 240.02,47.93 240.03,47.94 241.09,47.94 DIMM2.112 ; DIMM1.33 246.5,67.67 v3(246.03,68.15) ; v3(234.34,35.61) 234.32,35.58 233.93,35.58 233.83,35.67 DIMM2.153 ; DIMM1.130 254.5,43.42 v3(254.48,43.44) ; DIMM1.160 254.66,33.93 v3(254.66,33.92) ; DIMM1.123 249.22,45.17 249.22,45.17 v3(249.35,45.17) ; v3(234.34,46.67) 234.33,46.67 DIMM2.117 ; v3(243.04,19.43) 242.59,19.43 242.09,18.92 DIMM2.220 ; DIMM2.159 v3(234.34,34.17) ; DIMM1.124 v3(254.66,44.92) ; v3(249.37,43.68) 249.36,43.67 DIMM1.129 ; DIMM1.241 246.83,13.67 v3(246.33,14.17) ; v3(254.64,62.07) 254.64,62.08 254.98,62.42 DIMM1.54 ; DIMM2.124 v3(239.66,44.92) ; v3(252.68,18.28) 253.87,18.28 254.51,18.92 DIMM1.220 ; v3(249.46,32.7) 249.46,32.78 249.06,33.17 DIMM1.163 ; v3(246.51,24.2) 246.51,24.19 246.52,24.17 DIMM1.199 ; DIMM1.159 249.34,34.17 ; DIMM2.118 v3(239.66,46.42) ; DIMM1.154 v3(254.62,35.42) ; DIMM1.118 v3(254.66,46.42)
  TOP w0.305: CPU1.AT36 186.69,55.33 CPU1.AR37 ; DIMM2.33 231.85,67.67 v3(231.34,68.18) ; DIMM2.75 v3(231.46,57.17) ; DIMM1.75 246.42,57.17 246.37,57.22 v3(246.29,57.22) ; v3(231.17,14.46) 231.95,13.67 DIMM2.241 ; CPU1.AR36 187.14,56.71 CPU1.AP37
  L4 w0.508: v3(75.22,10.18) 75.61,9.79 86.37,9.79 90.33,5.83 91.95,5.83 92.35,5.44 92.72,5.44 92.74,5.41 95.47,5.41 95.89,5.83 98.61,5.83 99.11,5.32 99.11,4.7 100.17,3.63 107.4,3.63 108.15,4.39 120.12,4.39 120.38,4.65 121.85,4.65 121.95,4.55 127.05,4.55 127.15,4.65 130.16,4.65 130.98,5.47 132.14,5.47 132.71,4.9 135.13,4.9 135.5,5.27 141.67,5.27 142.84,4.11 156.08,4.11 157.39,2.8 157.76,2.8 158.46,2.11 181.08,2.11 181.09,2.12 184.25,2.12 189.58,7.44 189.58,7.86 190.66,8.94 190.66,9.35 v3(191.25,9.95)
  BOTTOM w0.508: 222.5,17.57 221.32,16.39 v1(219.95,16.39) 214.98,16.39 213.96,17.4 209.81,17.4 R510.1 ; v3(75.22,10.18) 75.22,15.87 v1(75.59,16.24) 75.61,16.23 R24020.1
  vias: v1(194.73,10.31) v1(211.76,52.42) v1(215.76,83.54) v1(218.76,72.31) v1(221.02,80.88) v1(225.1,52.26) v1(225.31,31.26) v2(257.93,64.56) v2(257.98,63.65) v2(258.02,62.74) v2(258.29,39.06) v2(258.34,38.14) v2(258.38,37.23) v3(186.25,53.98) v3(186.25,53.1) v3(186.25,52.19) v3(186.26,60.55) v3(186.28,59.52) v3(186.26,58.63) v3(186.28,57.62) v3(186.26,54.97) v3(186.26,51.24) v3(186.27,49.42) v3(186.25,48.47) v3(190.47,13.07) v3(215.21,80.05) v3(215.93,80.05) v3(216.55,84.09) v3(218.81,27.46) v3(218.85,13.64) v3(219.33,26.96) v3(219.33,13.11) v3(258.24,51.03)
1D2V_VCCPLL_OC: length 64.6
  TOP w0.203: CPU1.CG38 187.96,41.04 188.11,41.04 188.11,41.05 188.41,41.05 188.41,41.04 188.56,41.04 CPU1.CG41 ; CPU1.CG49 194.5,40.53 194.76,40.27 v3(194.76,40.21)
  TOP w0.254: CPU1.CG42 189.56,40.41 v3(189.24,40.09) 188.91,40.43 CPU1.CG41
  L3 w0.508: v3(195.16,14.45) 195.97,14.45 196.47,14.95 197.45,14.95 198.22,14.18 203.24,14.18 204.01,13.41 210.71,13.41 v3(210.97,13.68)
  L4 w0.508: v3(194.76,40.21) 195.05,40.21 196.73,38.53 196.73,33.86 200.35,30.23 203.6,30.23 209.52,24.32 209.52,20.29 209.83,19.98 209.83,14.82 v3(210.97,13.68)
  BOTTOM w0.508: v3(194.76,40.21) 194.59,40.21 194.02,40.78 v1(193.62,40.78) 192.62,40.78 C1115.1 191.69,40.77 C1114.1 191.29,40.76 190.9,40.37 190.49,40.37 190.17,40.05 190.15,40.05 190.08,39.98 189.36,39.98 v3(189.24,40.09) ; R4016.2 195.06,14.55 v3(195.16,14.45)
1D05V_LAN: length 7.9
  BOTTOM w0.203: LAN1.8 60.85,82.03 v3(60.3,81.48) ; LAN1.3 62.98,81.1 v3(63.04,81.04) ; v3(65.83,82.92) 65.23,83.51 LAN1.30
  BOTTOM w0.762: v1(70.54,89.69) 70.54,86.94 v1(70.5,86.89) 70.32,86.72 R3103.2
  vias: v1(64.01,82.25) v1(64.25,86.03) v2(63.23,87.62)
1D05V_LAN_OUT:
  vias: v1(67.09,85.68)
1D05V_S5_BYPASS: length 86
  TOP w0.254: v3(177.12,30.11) 177.12,30.12 176.99,30.12 CPU1.DJ15
  TOP w0.508: v2(125.62,40.8) 125.62,40.55 124.18,39.11 v1(124.18,38.15) 124.18,33.95 122.59,32.36 122.59,22.84 v3(123.24,22.18)
  L3 w0.508: v3(123.24,22.18) 126.97,22.18 127.26,21.89 135.33,21.89 136.85,20.37 141.37,20.37 141.82,20.82 147.83,20.82 148.54,21.53 154.43,21.53 154.95,22.05 157.95,22.05 161.34,25.44 167.52,25.44 167.64,25.31 176.54,25.31 176.56,25.29 177.07,25.29 177.42,25.65 177.42,27.88 177.15,28.15 177.15,29.47 177.12,29.5 v3(177.12,30.11)
  BOTTOM w0.508: v2(125.62,40.8) 125.69,40.8 127.13,39.36 PG5402.1 ; v3(177.12,30.11) 177.21,30.02 R2209.1
1D05V_S5_OUT: length 30.6
  TOP w0.508: 167.86,42.62 167.04,42.62 167.04,42.61 166.27,42.61 166.26,42.62 165.8,42.62 164.49,43.92 160.98,43.92 159.08,42.02 C4093.1 158.38,41.53 153.1,36.25 v3(153.1,34.73)
  BOTTOM w0.508: v3(169.15,42.7) 169.25,42.7 169.76,42.19 C2208.1 ; 153.31,25.39 153.31,27.71 153.11,27.91 v1(153.11,30.51) 153.11,34.73 v3(153.1,34.73)
  vias: v3(151.71,23.77)
1D05V_S5_VCCDSW_OUT: length 2
  TOP w0.254: CPU1.DD34 186.15,32.69 v3(186.68,32.69)
  BOTTOM w0.508: v3(186.68,32.69) 186.68,32 C2204.1
1D05V_S5_VCCPRIM_OUT: length 0.8
  BOTTOM w0.508: C2203.1 183.02,30.71 v3(182.95,30.78)
1D05V_VCCIO_OUT: length 5
  TOP w0.254: CPU1.AD7 172.42,62.15 v3(172.42,62.2)
  BOTTOM w0.508: R606.2 169.46,62.59 169.99,63.12 TP808.1 171.5,63.12 v3(172.42,62.2)
1D05V_VCCPLL: length 8.2
  TOP w0.254: 165.1,41.98 CPU1.CD1 CPU1.CD2
  BOTTOM w0.508: v3(161.22,41.77) 161.23,41.77 160.24,42.77 C1119.1 C1120.1
  vias: v1(163.88,42.94)
1D05V_VCCST: length 163.6
  TOP w0.254: 110.07,49.4 PG4601.1
  TOP w0.508: v3(154.95,43.91) 155.12,43.91 156.03,43 C1121.1 158.41,43 v1(159.26,43.85) 160.26,44.85 v3(163.02,44.85) 164.77,44.85 166.25,43.37 166.59,43.37 ; R302.1 v3(160.32,74.13) ; v3(110.21,51.27) 110.42,51.27 111.08,50.61 R707.1 111.05,50.54 111.05,50.45 111.06,50.44 111.06,49.41 R702.1 110.07,49.4 110.07,49.4
  L3 w0.508: v3(111.21,40.84) 111.21,42.58 111.21,50.74 110.69,51.27 v3(110.21,51.27) ; v3(160.32,74.13) 160.32,69.83 158.24,67.75 158.24,64 163.39,58.85 163.39,47.77 163.02,47.4 v3(163.02,44.85)
  L4 w0.508: v3(154.95,43.91) 154.19,43.91 153.18,42.9 153.18,40.49 150.97,38.28 v3(150.74,38.28) 149.39,36.93 147.53,36.93 147.26,36.66 147.26,36.65 146.89,36.28 146.88,36.28 146.82,36.22 144.18,36.22 142.88,37.51 142.01,37.51 141.16,38.36 139.96,38.36 137.67,40.64 135.29,40.64 132.09,43.85 131.32,43.85 130.13,45.03 126.61,45.03 125.77,44.19 125.77,42.61 124.52,41.36 123.94,41.36 122.97,40.39 116.73,40.39 116.42,40.71 111.35,40.71 v3(111.21,40.84)
  BOTTOM w0.254: R4004.2 161.75,22.1 161.21,22.63 161.21,23.63 v1(160.59,24.25) 159.93,24.9 159.93,25.13 159.29,25.77 159.29,32.11 158.01,33.38 158.01,33.39 156.8,34.6 156.8,34.61 156.44,34.96 156.44,42.42 v3(154.95,43.91)
  BOTTOM w0.508: v3(110.21,51.27) 110.41,51.47 R708.1
  BOTTOM w0.762: v1(146.96,20.14) 146.56,20.54 146.56,22.61 147.64,23.69 147.64,27.19 151.39,30.95 v1(151.39,36.51) 151.39,37.63 v3(150.74,38.28)
  vias: v3(168.77,43.3)
1D05V_VCCST_EN: length 4.8
  BOTTOM w0.102: U4011.4 153.38,16.12 153.64,15.86 153.64,15.39 C4062.1 154.51,15.38 154.61,15.28 v1(154.61,14.85) 154.61,14.44 154.53,14.36 R4054.1
1D05V_VCCSTG: length 34.7
  TOP w0.508: 158.13,44.39 v1(158.9,45.15) 159.55,45.8 165.23,45.8 166.97,44.07 168.17,44.07 168.22,44.02 169.01,44.02 ; v3(152.32,33.95) 152.32,36.79 153.93,38.39 153.93,44.25 154.44,44.76 155.38,44.76 156.1,44.04 C1126.1 157.4,44.04 C1127.1
  BOTTOM w0.508: v3(152.32,33.95) v1(152.32,32.32) 152.32,29.49 150.17,27.34
  vias: v1(148.64,26.25)
1D05V_VCCSTG_EN: length 67.6
  TOP w0.102: v3(182.4,4.94) 182.41,4.94 182.41,8.26 183.33,9.17 183.33,9.68 183.82,10.18 184.28,10.18 185.58,11.48 185.58,13.5 186.45,14.37 186.45,15.14 v3(186.46,15.15)
  BOTTOM w0.102: U4010.4 154.49,22.8 154.63,22.93 C4061.1 R4034.1 155.21,21.73 156.05,20.89 v1(156.05,17.41) 156.05,12.41 155.08,11.44 155.08,6.46 155.97,5.57 158.63,5.57 160.88,3.32 181.66,3.32 182.41,4.06 182.41,4.94 v3(182.4,4.94) ; U4007.4 188.43,11.53 188.4,11.5 187.96,11.5 R4047.1 187.32,11.51 187.07,11.75 R4006.1 187.07,14.92 186.84,15.15 v3(186.46,15.15)
1D05V_VCCSTG_EN_R: length 4.1
  BOTTOM w0.102: U4009.4 186.48,9.45 186.84,9.09 v1(187.16,9.09) 187.59,9.09 187.94,9.44 R4047.2
1D05V_VCCSTG_OUT_FUSE: length 10.3
  TOP w0.203: CPU1.F33 184.9,70.57 v3(184.57,70.23) 184.89,69.92 CPU1.G33
  L3 w0.508: v3(184.57,70.23) 184.34,70 184.34,64.46 183.91,64.04 v3(183.03,64.04)
  BOTTOM w0.508: v3(184.57,70.23) v1(185.38,70.23) ; v3(183.03,64.04) 182.76,64.31 R808.2
1D05V_VCCSTG_OUT_FUSE_R: length 4.8
  TOP w0.203: CPU1.R35 186.01,66.07 v3(185.15,66.07) ; CPU1.AB34 185.74,62.65 185.15,63.24 v3(185.15,63.43) ; v3(185.14,64.76) 185.3,64.92 186,64.92 186.02,64.94 CPU1.U35 ; CPU1.T34 v3(185.14,65.4) ; CPU1.V34 185.39,64.11 v3(185.14,64.11)
  vias: v1(184.26,63.64)
1D05V_VCCSTG_OUT_LGC: length 2
  TOP w0.254: CPU1.E5 171.23,70.8 v3(171.03,70.6)
  BOTTOM w0.508: R809.1 170.51,71.11 v3(171.03,70.6)
1D05V_VCCSTG_TERM: length 5.6
  BOTTOM w0.508: v1(171.59,73.66) 171.59,73.46 171.56,73.43 R312.1 171.55,72.69 170.55,72.69 170.55,72.69 R809.2 169.75,72.69 169.24,72.18 R306.1 169.06,71.18 R311.1 169.35,70.89 169.35,70.46
1D05V_VNN_BYPASS: length 103.1
  TOP w0.254: v3(185.92,34.49) 185.66,34.23 CPU1.CY34
  L3 w0.508: v3(185.92,34.49) 185.54,34.49 185.14,34.89 177.22,34.89 176.25,33.91 176.25,32.92 v3(176.21,32.88)
  L4 w0.508: v3(176.21,32.88) 176.08,32.88 173.99,34.97 173.99,43.46 172.53,44.92 172.13,44.92 171.02,46.02 167.8,46.02 167.56,45.79 158.78,45.79 155.91,42.91 154.94,42.91 153.95,41.92 153.95,40.17 149.94,36.17 147.85,36.17 147.2,35.52 147.2,35.52 147.13,35.45 143.86,35.45 142.57,36.75 141.69,36.75 140.84,37.6 133.17,37.6 133.01,37.43 132.99,37.43 131.54,35.98 126.39,35.98 125.81,36.57 125.81,39.12 125.3,39.63 116.42,39.63 116.1,39.94 111.14,39.94 110.58,39.38 v2(110.58,38.23)
  BOTTOM w0.508: R2210.1 186.75,33.94 186.25,34.44 185.96,34.44 v3(185.92,34.49) ; PG5401.1 111.57,38.69 v1(111.2,39.06) 110.68,38.55 110.68,38.33 v2(110.58,38.23)
1D8V_AUDIO_S0: length 9.1
  TOP w0.203: U2701.40 30.42,67.37 30.03,66.98
  TOP w0.305: 30.03,66.98 29.42,66.36 v3(29.42,65.99) 28.82,65.99 28.61,66.2 C2715.1
  BOTTOM w0.305: v3(29.42,65.99) 29.11,66.29 28.62,66.29 28.61,66.29 28.6,66.29 v1(28.4,66.29) 28.02,65.91 R2767.2 27.39,65.91 R2766.1 25.79,65.91 25.53,66.17 R2701.2
1D8V_FCH_C10: length 2
  TOP w0.305: CPU1.BM9 173.22,48.27 v3(173.22,48.45) 173.22,48.67 CPU1.BJ9 CPU1.BG9
  vias: v1(169.26,47.93) v3(167.87,45.24)
1D8V_FCH_C10_EN: length 5.2
  TOP w0.102: v3(157.16,46.82) 157.48,46.5 C4072.1 158.01,46.01 v1(158.6,46.6) 158.63,46.62 U4012.4
  BOTTOM w0.102: v3(157.16,46.82) 157.5,46.49 R4051.1
1D8V_S0: length 267.1
  TOP w0.508: C5303.1 21.26,76.66 v1(20.65,76.05) 20.3,75.69 20.28,75.69 19.03,74.44 19.03,73.31 18.21,72.49 18.21,68.01 16.94,66.74 v3(16.8,66.74) v1(19.82,63.72) 20.33,63.21 v2(23.68,63.21) ; v3(60.74,10.78) 58.42,10.78 57.84,11.35 55.42,11.35 51.69,7.61 v3(32.16,7.61)
  TOP w0.635: C5303.1 21.26,77.91 21.52,78.17 21.52,79.82
  L3 w0.508: v3(175.22,6.72) 174.23,5.74 155.62,5.74 155.26,5.38 145.1,5.38 144.95,5.53 136.02,5.53 134.66,4.17 131.53,4.17 131.04,4.65 117.68,4.65 116.82,3.79 107.25,3.79 106.82,3.36 106.17,3.36 94.05,3.36 93.79,3.62 91.51,3.62 90.9,4.23 89.15,4.23 88.61,3.69 85.22,3.69 84.54,3.01 77.3,3.01 76.24,4.06 72.29,4.06 70.33,6.02 69.25,6.02 66.39,8.88 64.89,8.88 64.27,9.49 63.08,9.49 62.67,9.91 61.61,9.91 v3(60.74,10.78) ; v3(32.16,7.61) 32.16,7.46 31.71,7 23.33,7 22.55,7.78 v3(22.55,8.76)
  L4 w0.508: v3(22.55,8.76) 23.83,10.04 23.83,10.59 22.47,11.95 22.47,20.09 19.05,23.5 19.05,25.47 18.67,25.86 18.67,25.97 18.4,26.24 18.4,27.36 17.74,28.03 17.74,31.8 12.85,36.7 12.85,39.92 9.58,43.19 9.58,44.73 7.11,47.19 7.11,50.59 7.76,51.24 7.76,58.6 15.91,66.74 v3(16.8,66.74)
  BOTTOM w0.508: v2(23.68,63.21) 24.04,63.57 v1(25.29,63.57) 25.85,63.57 26.36,64.07 26.36,65.02 R2766.2 ; R2108.1 179.29,11.88 177.94,10.53 177.54,10.53 v1(176.71,9.7) 175.22,8.21 v3(175.22,6.72)
1D8V_S0_EN: length 4
  TOP w0.254: R5301.2 16.77,76.19 C5302.1 16.78,76.75 v1(17.23,77.2) 17.28,77.25 17.28,78.32 17.46,78.51 U5301.4
1D8V_S5: length 310.3
  TOP w0.203: v3(88.66,11.11) 88.93,11.38 ECIO1.34
  TOP w0.254: 185.94,31.79 185.94,31.81 186.31,32.18 CPU1.DD35 ; 185.94,31.79 185.94,31.73 185.66,31.45 CPU1.DF34 ; 185.94,31.79 v3(185.95,31.79)
  TOP w0.381: R1530.1 185.5,20.49 185.5,22.13 186.24,22.87 v3(186.24,22.87)
  TOP w0.508: v3(88.66,11.11) 88.66,10.74 89.22,10.18 90.41,10.18 93.29,7.3 94.23,7.3 94.59,7.66 R24116.2 ; R6160.2 129.31,14.64 v3(129.11,14.84) ; R2104.2 182.54,20.37 R2105.2 182.54,19.73 183.87,18.4 184.82,18.4 ; v2(24.49,62.75) 24.12,62.38 v1(20.68,62.38) 19.51,62.38 v2(16.07,65.82) 16.07,67.79 17.22,68.93 17.22,72.99 17.99,73.77 v1(17.99,75.24) 17.99,77.42
  L3 w0.508: v3(185.92,17.59) 186.49,18.15 189.33,18.15 190.38,17.11 v3(191.69,17.11) ; v3(196.67,16.46) 197.71,16.46 198.62,15.55 v3(199.89,15.55) 199.89,15.56 203.63,15.56 203.8,15.39 v3(203.81,15.39) ; v3(31.67,30.68) 31.67,31.56 32.71,32.61 38.44,32.61 39.39,31.66 v2(55.14,31.66)
  L4 w0.508: v2(16.07,65.82) 9.05,58.8 9.05,51.31 8.48,50.74 8.48,48.76 9.2,48.04 9.2,46.19 10.56,44.83 10.56,43.28 13.61,40.23 13.61,37.01 19.44,31.19 19.44,26.17 20.54,25.07 22.18,25.07 23.24,26.13 23.24,29.31 24.37,30.44 30.55,30.44 30.8,30.69 31.65,30.69 v3(31.67,30.68) ; v3(177.96,30.79) 177.96,31.3 177.6,31.65 177.12,31.65 176.76,32.01 176.76,32.51 177.04,32.78 177.04,34.03 175.7,35.37 175.7,43.69 173.38,46.01 172.85,46.01 172.83,46.03 172.17,46.03 171.81,46.39 171.81,46.45 171.45,46.81 168.06,46.81 167.19,47.68 161.43,47.68 160.23,48.88 v3(160.23,49.39) ; v3(186.24,22.87) 186.31,22.94 186.31,27.11 185.74,27.67 185.74,30.24 186.05,30.55 186.05,31.69 v3(185.95,31.79) ; v3(129.11,14.84) 128.94,14.84 128.4,15.38 126.25,15.38 125.68,14.81 125.08,14.81 123.5,13.22 116.88,13.22 116.34,13.76 113.64,13.76 111.93,15.47 106.28,15.47 105.91,15.84 102.41,15.84 101.73,16.52 97.6,16.52 97.08,16.52 95.79,15.22 v3(87.44,15.22) 85.19,15.22 84.81,15.61 80.27,15.61 78.31,13.65 70.82,13.65 69.66,14.81 68.52,14.81 65.94,17.4 64.44,17.4 58.29,23.55 58.29,28.63 55.26,31.66 v2(55.14,31.66)
  BOTTOM w0.356: RN1914.2 197.05,16.85 v3(196.67,16.46) 196.93,16.2 RN1914.1
  BOTTOM w0.381: Q1904.5 v3(203.81,15.39)
  BOTTOM w0.406: Q1904.2 200.05,15.39 v3(199.89,15.55)
  BOTTOM w0.508: v2(24.49,62.75) 26.27,62.75 v1(26.63,63.12) 27.39,63.87 R2767.1 ; v3(191.69,17.11) 192.77,17.11 193.31,16.56 196.57,16.56 v3(196.67,16.46) ; v2(131.92,27.18) 132.05,27.18 132.71,26.52 132.71,23.17 133.36,22.52 133.36,18.47 129.73,14.84 v3(129.11,14.84) ; v3(87.44,15.22) 86.87,15.22 C2410.1 86.62,14.15 C2420.1 86.88,12.89 v3(88.66,11.11)
  vias: v1(146.28,28.87) v1(157.41,25.51) v1(161.11,26.64) v1(176.99,31.23) v2(160.87,29.08) v2(161.78,29.08) v2(162.7,29.1) v3(178.79,30.8)
1D8V_S5_CLKLDO: length 7.2
  TOP w0.203: CPU1.DW15 176.63,23.96 v3(176.78,23.81)
  BOTTOM w0.508: R2204.2 171.9,25.57 R2206.1 173.83,25.57 C2215.1 173.99,25.56 174.23,25.32 174.29,25.32 174.5,25.11 174.5,24.47 v1(174.85,24.13) 176.47,24.13 v3(176.78,23.81)
1D8V_S5_CLKLDO_R: length 2.4
  BOTTOM w0.508: C2216.1 170.57,24.32 v1(171.66,24.32) 172.06,24.32 172.43,24.68 R2206.2
1D8V_S5_PWRGD: length 17.3
  TOP w0.305: PR5052.1 145.62,34.49 145.77,34.34 v3(145.77,34.11) ; PR5317.1 134.95,32.71 134.98,32.74 PR5326.1 134.94,33.47 134.47,33.47 v3(134.18,33.76)
  L3 w0.305: v3(134.18,33.76) 134.23,33.82 138.93,33.82 140.43,35.32 142.72,35.32 143.49,34.55 143.49,33.9 143.54,33.85 143.54,33.74 143.84,33.43 145.15,33.43 145.77,34.05 v3(145.77,34.11)
1D8V_VCCIN_AUX: length 12
  TOP w0.203: CPU1.CH1 169.65,40.35 168.92,40.35 v3(168.68,40.11) ; CPU1.CV1 169.64,35.04 v3(169.15,35.04)
  TOP w0.254: v3(169.3,32.68) 169.38,32.76 CPU1.DC1 ; CPU1.CN1 v3(169.3,37.7)
  TOP w0.508: PL5001.2 151.42,53.11 151.42,49.15 v1(151.84,48.72) 152.75,48.72 153.26,48.22 PR5017.1
  vias: v1(154.98,55.52) v1(155.56,55.53) v1(156.25,50.35) v1(161.25,46.14) v1(164.18,55.71) v1(165.22,58.17) v1(172.21,35.16) v1(173.85,60.05) v2(152.68,56.14) v2(152.68,54.94) v2(152.68,53.79) v2(153.82,56.14) v2(153.82,54.94) v2(153.82,53.79) v2(155.53,54.53) v2(155.56,53.39) v2(155.56,52.24) v2(158.86,54.77) v2(158.89,53.63) v2(158.89,52.49) v2(160.28,54.87) v2(160.31,53.73) v2(160.31,52.58) v2(162.58,55.8) v2(162.58,54.88) v2(162.62,53.74) v2(162.62,52.59) v2(167.72,58.8) v2(167.74,55.54) v2(167.75,57.66) v2(167.75,56.52) v3(157.59,54.67) v3(157.59,53.94) v3(157.59,53.2) v3(157.59,52.49) v3(168.94,58.39) v3(168.94,57.09) v3(168.95,59.04) v3(168.95,57.74) v3(173.19,52.13) v3(173.26,53.96) v3(173.25,53.04) v3(174.78,66.08) v3(174.83,53.89) v3(174.89,55.48) v3(175.03,38.44) v3(175.01,37.71) v3(175.01,37.07) v3(175,36.44) v3(175.29,66.92) v3(176.23,66.89) v3(176.18,66.08) v3(176.24,65.39)
1D24V_S5_VCCDPHY_OUT: length 3.6
  TOP w0.254: CPU1.DW32 184.66,24.59 184.66,24.02
  TOP w0.508: 184.66,24.02 184.71,23.98 v3(184.71,22.79)
  BOTTOM w0.254: v3(184.71,22.79) 185.25,22.24 v1(185.25,22.19)
  BOTTOM w0.508: v3(184.71,22.79) C2205.1
2D5V_S3:
  vias: v1(231.45,7.91) v1(245.09,7.6) v1(259.05,11.91) v3(232.28,8.17) v3(233.03,8.17) v3(233.78,8.17) v3(246.45,8) v3(247.25,7.99) v3(248.01,7.99) v3(257.79,12.58) v3(257.78,11.83)
2D5V_S3_EN: length 224
  TOP w0.102: v3(94.72,21.93) 94.71,21.93 94.49,22.15 R24042.2
  L3 w0.127: v3(94.72,21.93) 95.56,21.1 105.77,21.1 106.96,19.91 114.62,19.91 115.16,19.37 122.7,19.37 123.65,18.42 134.39,18.42 134.62,18.19 134.84,18.19 134.84,18.19 135.87,18.19 136.71,17.35 143.49,17.35 144.85,18.71 155.41,18.71 156.45,19.75 159.16,19.75 163.07,23.65 167.53,23.65 168.08,24.21 175.36,24.21 175.53,24.04 175.85,24.04 176.5,23.39 176.99,23.39 177.94,24.35 179.47,24.35 180.37,25.25 187.89,25.25 188.33,24.82 189.77,24.82 191.17,23.41 191.86,23.41 192.64,24.19 194.45,24.19 194.95,24.69 204.78,24.69 206.85,22.61 207.8,22.61 208.08,22.34 208.08,22.08 210.04,20.12 212.81,20.12 213.16,19.77 213.78,19.77 218.29,15.26 v3(218.29,12.79) ; v3(260.68,31.81) 260.63,31.86 260.42,31.86 260.05,31.49 260.05,29.13 260.53,28.64 260.53,27.19 260.04,26.7 260.04,10.78 259.33,10.08 259.33,7.97 256.43,5.07 256.39,5.07 255.13,3.81 254.14,3.81 253.82,4.13 248.44,4.13 247.78,3.47 245.46,3.47 245.46,3.47 244.83,3.47 244.83,3.47 238.41,3.47 238.39,3.5 232.91,3.5 232.43,3.01 217.69,3.01 216.67,4.02 v3(216.7,4.02)
  BOTTOM w0.102: v3(216.7,4.02) 215.44,5.27 v1(215.17,5.27) 214.37,5.27 213.91,5.74 213.91,7.39 214.39,7.88 215.32,7.88 215.58,8.13 215.58,9.09 215.83,9.34 RN4001.3 216.55,9.34 217.98,10.77 Q4013.C 218.94,12.14 v3(218.29,12.79) ; PR5204.1 260.25,31.55 260.52,31.82 260.67,31.82 v3(260.68,31.81)
2D5V_S3_EN_EC: length 4.3
  TOP w0.102: R24042.1 93.06,21.46 v1(92.77,21.17) 92.53,20.93 92.44,20.93 91.7,20.18 ECIO1.56
2D5V_S3_PWRGD: length 184.3
  L3 w0.127: v3(259.61,28.32) 258.83,28.32 258.5,27.99 258.5,10.97 258.16,10.63 258.16,8.45 255.75,6.04 248.77,6.04 248.25,5.52 232.33,5.52 229.41,8.44 227.02,8.44 227.02,8.44 218.37,8.44 211.94,14.88 210.94,14.88 210.05,13.98 206.4,13.98 205.63,14.75 198.45,14.75 197.63,15.58 195.38,15.58 194.09,14.29 189.45,14.29 188.12,12.96 178.05,12.96 177.56,13.44 175.92,13.44 174.51,12.03 168.6,12.03 168.04,11.48 167.47,11.48 166.91,12.04 166.91,14.37 167.87,15.33 v3(167.87,16.27) ; v3(124.07,14.87) 124.26,14.68 128.28,14.68 128.91,15.31 129.3,15.31 129.55,15.06 152.93,15.06 154.29,16.42 156.35,16.42 157.27,17.34 v3(158.86,17.34)
  L4 w0.127: v3(158.86,17.34) 158.99,17.46 166.68,17.46 v3(167.87,16.27)
  BOTTOM w0.102: v3(259.61,28.32) 259.61,28.3 260.61,27.3 PR5202.2 260.61,26.67 259.54,25.61 PU5201.7 ; v3(124.07,14.87) 123.97,14.96 123.97,15.93 v1(123.31,16.59) 122.09,17.81 R5206.2 120.73,17.29 120.13,17.29 119.57,17.86 U4020.2
3D3V_AUDIO_S0: length 35.8
  TOP w0.203: U2701.9 35.96,72.64 36.05,72.73
  TOP w0.305: 36.05,72.73 36.33,73 36.33,73.13 v3(36.47,73.27) 37.33,74.13 37.33,75.93 37.02,76.24 C2719.2 36.67,76.5 37.01,76.84 R2709.2 ; v3(24.48,64.2) 24.9,64.2 28.18,60.92 v1(30.28,60.92) 34.78,60.92 35.35,61.48 35.35,65.2 v3(35.44,65.3)
  BOTTOM w0.305: v3(35.44,65.3) 35.35,65.4 35.35,66.87 34.5,67.72 v3(34.5,68.7) 34.17,69.03 34.17,70.69 v1(35.79,72.31) 36.48,73 36.48,73.27 v3(36.47,73.27) ; R2721.2 v1(24.48,65.83) v3(24.48,64.2)
  vias: v1(37.16,68.67)
3D3V_AUX_S5: length 429.8
  TOP w0.203: v3(75.47,7.78) 75.82,8.13 76.46,8.13 76.8,8.47 ECIO1.3 ; ECIO1.32 89.46,9.43 89.48,9.42 ; v3(86.79,19.43) 88.82,21.45 88.82,23.08 89.09,23.35 89.09,23.38 ECIO1.64 90.96,23.38 91.12,23.54 v3(91.12,25.68)
  TOP w0.305: R6408.2 124.94,8.12 123.23,8.12 v3(122.63,7.52)
  TOP w0.508: R5522.1 13.05,10.33 R5523.1 14.17,10.33 R5524.1 15.91,10.33 16.8,11.22 21.18,11.22 22.06,12.11 25.09,12.11 26.87,10.33 28.04,10.33 29.55,8.82 51.09,8.82 54.87,12.59 v3(62.51,12.59) ; v3(96.73,75.04) 96.76,75.08 96.76,76.79 96.16,77.39 96.16,79 97.18,80.02 PG4532.1 99.81,81.05 v3(99.66,81.21) ; R24095.2 98.08,18.04 R24104.1 98.01,17.58 v3(98.38,17.21) ; v3(92.72,6.7) 90,9.42 89.48,9.42 ; v3(47.05,75.09) 43.69,75.09 39.9,78.87 39.9,79.37 38.96,80.31 38.01,80.31 37.14,81.18 33.92,81.18 32.49,79.75 R2710.2
  TOP w0.61: L2401.2 68.69,29.84
  TOP w0.762: 68.69,29.84 69.45,30.6 v3(70.05,30.6)
  L3 w0.508: v3(47.05,75.09) 47.05,70.92 49.32,68.65 53.23,68.65 53.79,69.21 57.12,69.21 61.75,73.84 73.58,73.84 v3(75.45,75.71) ; v3(75.47,7.78) 76.11,7.78 76.97,6.93 85.6,6.93 85.85,6.68 89.85,6.68 89.87,6.7 v3(92.72,6.7) 94,5.43 94.33,5.43 95.25,4.51 105.7,4.51 106.14,4.95 115.99,4.95 118.02,6.99 119.83,6.99 120.33,6.48 121.77,6.48 122.63,7.35 v3(122.63,7.52) 123.14,7.01 124.53,7.01 125.7,5.84 129.91,5.84 129.94,5.88 132.29,5.88 132.85,5.31 134.19,5.31 135.55,6.67 145.42,6.67 145.57,6.52 154.79,6.52 155.33,7.06 162.08,7.06 162.72,7.7 168.79,7.7 v3(169.15,7.33) ; v3(109.83,72.92) 109.83,73.41 105.87,77.37 105.87,78.07 103.11,80.84 101.38,80.84 101.01,81.21 v3(99.66,81.21) 99.66,79.13 98.27,77.74 96.88,77.74 93.64,80.98 91.83,80.98 91.11,80.26 87.73,80.26 86.7,79.23 v3(86.52,79.23)
  L3 w0.762: v3(75.47,7.78) 72.74,7.78 v3(72.09,8.43)
  L4 w0.508: v3(80.62,12.66) 81.5,11.78 81.5,11.06 v3(81.48,11.04) ; v3(101.17,48.1) 100.91,48.36 100.91,50.38 98,53.29 98,58.22 97.05,59.17 97.05,68 96.64,68.41 96.64,70.21 95.46,71.39 95.46,73.14 96.73,74.41 v3(96.73,75.04)
  BOTTOM w0.508: R24056.2 84.97,16.44 v1(84.51,15.99) 83.09,14.56 83.09,13.59 82.36,12.87 R24045.1 81.86,12.66 v3(80.62,12.66) 80.53,12.75 80.53,12.75 80.34,12.94 R24076.1 ; v3(92.72,6.7) 92.72,8.75 C2406.1 ; v3(86.52,79.23) 78.98,79.23 v1(76.73,76.99) v3(75.45,75.71) ; v3(169.15,7.33) 169.57,7.75 R2519.2 ; D2402.1 70.28,30.38 v3(70.05,30.6) 69.26,31.39 65.35,31.39 59.99,26.03 v1(59.99,21.08) 59.99,18.28 61.7,16.57 61.7,13.4 v3(62.51,12.59) 63.55,11.56 66.79,11.56 ; v3(75.47,7.78) 75.89,7.35 78.12,7.35 78.64,7.88 C2416.1 78.64,9.46 79.15,9.96 R24060.1 79.7,10.17 80.12,10.6 80.18,10.6 80.69,11.11 R24115.1 81.23,11.29 v3(81.48,11.04) 81.48,11.03 82.14,10.37 R24035.1 ; v3(109.83,72.92) 109.69,72.78 PR4509.1 ; v3(98.38,17.21) 98.03,17.56 R24088.2 98.03,19.32 99.89,21.19 99.89,24.84 v3(100.16,25.11) ; v3(91.12,25.68) 91.71,25.68 93.08,27.05 D2401.1 ; U2401.8 71.53,14.21 v1(70.81,13.49) 70,12.69 70,11.31 69.34,10.65 67.99,10.65
  BOTTOM w0.762: v3(101.17,48.1) 101.35,48.28 106.11,48.28 108.96,45.43 108.96,44.06 108.26,43.36 108.26,39.37 104.48,35.6 102.31,35.6 97.74,31.02 v3(97.74,28.67)
  vias: v1(95.08,28.82) v1(99.02,26.29) v3(93.6,28.31) v3(94.31,28.31)
3D3V_CAM: length 1.3
  TOP w0.508: v3(226.4,99.3) 226.78,98.92 ED3002.5
  vias: v1(222.5,100.15) v2(221.49,99.34)
3D3V_CAM_R:
  vias: v1(224.06,102.01)
3D3V_CARD: length 15
  L3 w0.762: v3(36.6,84.5) 36.6,87.25 35.16,88.69 35.16,92.6 v3(33.27,94.49)
  BOTTOM w0.305: U3301.7 v3(33.27,94.49)
  BOTTOM w0.762: v3(36.6,84.5) 36.52,84.43 v1(35.4,84.43) R3302.1
3D3V_CARD_C:
  vias: v1(31.18,85.36) v3(31.4,89.36) v3(31.36,88.52) v3(31.63,84.52) v3(32.14,89.34)
3D3V_DB1: length 3.8
  TOP w0.381: DBGH1.10 v3(104.57,19.3)
  BOTTOM w0.508: v1(105.69,19.3) v3(104.57,19.3) 103.57,19.3 R6810.1
3D3V_DMIC_R:
  vias: v1(218.36,101.27) v2(206.96,101.12)
3D3V_EDP_VDDIO: length 56.8
  TOP w0.508: v3(45.41,12.3) 43.84,10.73 37.99,10.73 36.99,9.73 30.44,9.73 29.41,10.77 29.41,15.06 29.78,15.43 29.78,16.98 31.94,19.14 33.28,19.14
  BOTTOM w0.203: v3(36.7,21.21) 36.7,21.21 36.7,21.4 36.34,21.76 TSMT1.5
  BOTTOM w0.508: v3(45.41,12.3) 45.41,11.6 v1(45.93,11.08) R5613.1 47.76,11.2 53.92,11.2 55.17,12.44 57.03,12.44 57.67,13.09 57.67,14.87 ; 57.67,14.87 55.89,14.87 U5602.3 54.06,14.86 51.52,17.4 U5602.8 v1(48.97,17.4) 48.25,17.4 47.74,16.9 R5614.1 ; 57.67,14.87 L5601.2
  vias: v1(35.31,20.61)
3D3V_EDP_VDDIOX: length 45.6
  L4 w0.508: v3(41.96,12.49) 39.97,14.47 33.94,14.47 30.24,18.18 30.24,25.01 30.74,25.52 v3(31.28,25.52)
  BOTTOM w0.203: v3(31.14,27.51) 31.19,27.51 31.82,26.87 TSMT1.22 ; TSMT1.18 31.52,25.27 v3(31.28,25.52)
  BOTTOM w0.508: v3(41.96,12.49) v1(44.13,10.32) 54.13,10.32 55.48,11.68 57.39,11.68 L5602.2
3D3V_LAN: length 46.3
  TOP w0.508: v3(57.96,64.04) 57.11,64.9 v1(56.11,64.9) v3(54,64.9) ; U3102.5 v3(74.09,65.96) ; U3101.5 v3(68.25,65.72)
  L3 w0.508: v3(55.59,70.61) 55.57,70.63 55.57,75.95 58.09,78.48 v3(58.09,79.78)
  L4 w1.016: 66.05,81.84 67.09,81.84 68.8,83.55 68.8,88.45 66.48,90.77
  BOTTOM w0.203: v3(65.16,82.07) 65.14,82.09 64.59,82.09 64.47,82.21 LAN1.32 ; v3(59.28,83.51) LAN1.11
  BOTTOM w0.508: ED3101.2 57.13,63.15 55.37,61.39 R3154.2 ; R3139.2 v3(54,64.9) 54,65.33 v1(54.59,65.92) 55.59,66.91 v3(55.59,70.61) 57.63,70.61 R3138.2 ; R3143.2 58.09,82 58.09,81.78 58.01,81.69 v1(58.01,80.73) 58.01,79.87 v3(58.09,79.78)
  vias: v1(57.8,84.91) v1(62.99,80.16) v1(71.3,65.78) v2(65.82,91.71) v2(66.77,91.75) v3(64.53,81.57)
3D3V_LAN_EN:
  vias: v1(55.91,76.49)
3D3V_LAN_VDDREG:
  vias: v1(65.21,88.21) v3(63.98,87.25) v3(64.65,87.52)
3D3V_MAIN_MSSD: length 3.4
  BOTTOM w0.305: L3302.2 31.71,95.38 33.17,95.38 33.57,94.99 U3301.8
  vias: v1(32.76,93.51)
3D3V_RTC_AUX: length 148.4
  TOP w0.33: v3(185.44,30.8) 185.35,30.8 CPU1.DG33
  TOP w0.381: v3(194.78,18.51) 194.4,18.51 192.28,16.39 v3(191.75,16.39)
  L3 w0.381: v3(168.14,13.28) 168.27,13.15 174.23,13.15 175.51,14.43 177.98,14.43 178.33,14.08 183.52,14.08 185.85,16.41 v3(186.91,16.41) 186.94,16.39 v3(191.75,16.39) ; v3(93.68,14.22) 97.23,14.22 98.88,15.86 101.88,15.86 102.46,16.44 111.41,16.44 112.48,15.37 113.38,15.37 114.49,14.26 119.72,14.26 v3(120.13,14.67)
  L4 w0.381: v3(186.91,16.41) 186.5,16.83 186.5,17.9 185.75,18.65 185.75,21.24 185.63,21.35 185.63,25.82 184.86,26.59 184.86,27.05 185.08,27.27 185.08,30.44 v3(185.44,30.8) ; v3(165.24,16.95) 160.52,16.95 160.23,16.66 149.9,16.66 148.28,15.03 137.59,15.03 137.27,15.35 135.17,15.35 133.65,16.88 126.77,16.88 125.4,15.52 125.37,15.52 125.35,15.5 123.18,15.5 122.42,14.75 120.2,14.75 v3(120.13,14.67)
  BOTTOM w0.381: v3(168.14,13.28) 167.63,12.77 D2501.3 166.23,13.46 C2507.1 v1(166.23,15.53) 166.23,15.95 v3(165.24,16.95) ; C2207.1 185.49,28.9 C2206.1 185.49,30.76 v3(185.44,30.8) ; R1704.1 192.62,18.51 v3(194.78,18.51) 197.97,18.51 198.36,18.12 v1(200.32,18.12) 203.17,18.12 203.39,17.9 ; R24004.2 v1(93.91,20.31) 93.91,14.44 v3(93.68,14.22)
3D3V_RTC_PWR: length 7.7
  BOTTOM w0.508: R2511.1 165.12,8.18 164.61,8.69 164.61,9.17 R2510.2 164.66,9.59 165.09,10.03 165.29,10.03 165.94,10.68 D2501.2 164.55,12.25 v1(164.55,12.35) Q2501.G
3D3V_RTC_VCC: length 6.9
  TOP w0.508: BTT1.1 168.24,11.96 167.8,11.96 167.78,11.98 167.74,11.98 167.71,11.95 v3(167.66,11.95)
  BOTTOM w0.508: v3(167.66,11.95) 167.66,11.95 167.61,11.95 167.03,11.37 167.03,10.55 166.56,10.07 v1(166.56,9.26) 166.51,9.21 R2510.1
3D3V_S0: length 455.6
  TOP w0.254: DIMM1.255 246.63,10.17
  TOP w0.279: DIMM2.255 234.81,10.17
  TOP w0.381: v3(206.58,21.61) 206.44,21.75 R1605.2
  TOP w0.508: v3(83.74,19.48) 82.87,20.35 v3(82.87,21.97) ; R24003.2 78.01,30.61 R24107.2 79.05,30.95 79.62,31.52 v3(80.93,31.52) ; R24021.2 97.56,15.52 v3(97.56,15.48) ; v2(9.9,82.81) 9.9,83.69 R6806.2 ; v3(198.67,8.22) 197.94,8.95 197.94,13.17 196.81,14.3 v3(196.81,14.32) ; v3(124.36,40.67) 124.36,40.56 123.42,39.62 123.42,34.63 121.29,32.5 121.29,26.57 v3(120.82,26.1) ; 245.05,6.35 246.81,6.35 249.32,3.84 250.1,3.84 252.03,1.92 259.42,1.92 v2(259.77,1.57) ; v3(218.09,96.47) 217.32,96.47 216.82,95.96 216.82,93.15 214.71,91.04 v3(214.71,84.01) 214.09,83.39 214.09,77.92 220.6,71.41 220.6,12.36 220.07,11.82 220.07,7.51 220.07,7.5 220.07,6.25 220.96,5.35 v3(221.89,5.35) ; v3(28.42,13.76) 28.42,15.19 28.98,15.75 28.98,17.21 R5505.1 ; v2(16.65,74.28) 15.88,75.05 R5301.1 ; R3160.1 63.71,90.2 63.71,91.42 v3(63.75,91.45) ; R1812.1 189.24,20.39 R1813.1 188.21,19.6 v3(188.38,19.42) ; R24079.2 v3(96.92,7.67) ; PR4607.1 v3(126.8,55.9) ; v2(60.77,75.44) 60.29,74.95 60.29,73.14 59.15,72 59.15,71.47 R3116.1
  TOP w0.762: v3(45.4,67.71) 44.71,67.01 R2758.1
  L3 w0.508: v3(30.83,7.76) 27.14,11.44 27.14,13.25 27.65,13.76 v3(28.42,13.76) ; v3(83.74,19.48) 75.32,19.48 72.28,16.44 v3(72.28,15.36) ; v3(129.41,15.93) 129.37,15.88 128.67,15.88 128.54,15.75 118.33,15.75 117.72,15.14 v3(117.66,15.14) ; v3(86.84,8.15) 86.89,8.2 v3(89.22,8.2) 89.44,8.43 92.74,8.43 93.11,8.79 95.8,8.79 v3(96.92,7.67)
  L4 w0.381: v3(206.58,21.61) 206.58,21.04 206.44,20.9 206.44,13.43 204.84,11.83 204.84,9.71 204.97,9.58
  L4 w0.508: v3(67.93,8.87) 67.93,7.83 69.28,6.48 71.97,6.48 74.52,9.03 85.96,9.03 v3(86.84,8.15) ; v3(42.53,58.76) 42.38,58.76 42.12,58.51 42.12,55.71 v3(42.99,54.85) ; v3(45.4,67.71) 47.11,66 47.11,59.29 47.82,58.57 v3(47.82,55) ; v3(63.75,91.45) 62.11,89.81 61.66,89.81 58.65,86.8 58.65,82.14 59.66,81.12 59.66,81.09 60.77,79.98 v2(60.77,75.44)
  L4 w1.016: v3(129.41,15.93) 133.25,15.93 134.78,14.4 135.57,14.4 136.64,14.4 137.05,13.99 151.44,13.99 152.87,15.42 v2(157.12,15.42)
  BOTTOM w0.305: RN1810.4 173.54,9.66 173.72,9.48 v3(174.17,9.48) 174.19,9.5 RN1810.3 ; RN1915.2 197.15,14.66 v3(196.81,14.32) 197.11,14.01 RN1915.1
  BOTTOM w0.381: v3(42.99,54.85) 41.99,54.85 41.61,55.23 Q5701.5
  BOTTOM w0.508: R4044.2 131.93,21.64 132.6,20.98 132.6,19.11 v3(129.41,15.93) ; v3(82.87,21.97) 82.87,25.44 83.31,25.88 83.31,29.01 81.96,30.36 81.96,30.9 81.35,31.52 v3(80.93,31.52) ; 41.81,60.71 42.16,60.71 45.4,63.95 v3(45.4,67.71) ; v3(124.36,40.67) 124.36,40.89 124.25,41 R4002.1 124.25,45.28 123.85,45.67 123.85,48.41 126.22,50.78 126.22,55.32 v3(126.8,55.9) ; R24001.2 83.24,20.19 83.24,19.99 83.69,19.54 83.69,19.54 v3(83.74,19.48) ; 114.48,16.98 114.48,21.97 116.27,23.76 118.47,23.76 v3(120.82,26.1) ; 114.48,16.98 114.15,16.65 112.64,16.65 110.88,18.41 R6810.2 ; 114.48,16.98 115.33,16.12 116.69,16.12 v3(117.66,15.14) ; 205.45,75.54 206.24,75.54 v3(214.71,84.01) ; v3(47.82,55) 47.89,55.07 R5732.1 49.63,55.07 Q5705.G ; v3(182.86,14.65) 183.52,13.98 R1712.1 184.28,14.91 188.38,19.01 v3(188.38,19.42) ; v3(97.56,15.48) 96.92,14.84 v3(96.92,7.67) ; L3302.1 30.1,95.3 30.1,100.92 ; v2(259.77,1.57) 259.45,1.89 R2603.1 ; v3(170.46,21.74) 170.46,21.76 R1701.1 ; R4033.1 222.03,5.5 221.89,5.36 v3(221.89,5.35) ; R24054.2 72.79,15.87 v3(72.28,15.36) ; v3(86.84,8.15) 86.89,8.2 v3(89.22,8.2) 89.52,8.2 89.72,8 91.85,8 R24112.1
  BOTTOM w0.762: v2(48.18,78.23) 48.18,75.12 45.99,72.93 45.99,68.3 v3(45.4,67.71)
  vias: v1(7.93,24.69) v1(50.19,88.91) v1(68.59,15.14) v1(83.05,62.62) v1(83.88,80.32) v1(107.92,4.76) v1(121.63,6.38) v1(181.25,13.79) v2(3.7,24.35) v2(3.72,23.31) v2(5.45,10.34) v2(6.16,28.36) v2(6.49,10.36) v2(7.2,28.38) v2(8.98,82.83) v2(48.31,79.21) v2(49.1,78.23) v2(49.34,87.53) v2(49.32,86.62) v2(65.8,3.72) v2(65.9,2.75) v2(83.18,63.74) v2(84.09,63.77) v2(84.68,77.66) v2(85.7,77.71) v2(86.61,77.37) v2(158.29,15.39) v2(158.39,8.49) v2(179.35,7.11) v2(180.3,7.57) v3(6.96,46.02) v3(7.38,45.37) v3(55.89,7.12) v3(56.94,7.16) v3(108.76,2.67) v3(109.47,2.67) v3(118.29,6.35) v3(119,6.35) v3(132.32,2.45) v3(133.19,2.45) v3(150.11,8.1) v3(150.83,8.1) v3(199.48,8.22) v3(234.91,8.58) v3(235.51,7.86) v3(235.77,8.62) v3(242.8,7.71) v3(243.24,8.27) v3(243.67,7.69)
3D3V_S5: length 512
  TOP w0.254: v3(184.75,32.21) 185.2,32.66 CPU1.DC33
  TOP w0.305: CPU1.DE31 184.63,32.21 v3(184.75,32.21)
  TOP w0.381: PR5327.1 133.4,33.27 133.4,32.76 132.92,32.29 v3(132.52,32.29)
  TOP w0.508: v3(24.72,8.19) 26.09,6.81 52.47,6.81 55.4,9.75 59.16,9.75 59.41,10 64.76,10 v3(65.21,9.55) ; R24118.2 95.25,24.76 v3(95.51,24.5) 95.52,24.49 95.52,24.29 95.56,24.25 R24059.2 ; v3(81.09,30.67) 81.67,30.67 82.23,31.23 84.18,31.23 84.81,30.6 85.07,30.6 85.51,30.16 R24063.2 85.51,28.91 R24099.2 ; R1518.1 204.5,23.72 v3(204.5,22.84) ; R2023.1 177.05,20.27 R1524.1 177.04,19.67 v3(176.82,19.45) ; R1503.1 194.32,14.67 194.86,15.21 194.86,15.76 194.56,16.06 ; 177.48,7.56 177.48,9.9 178.5,10.91 178.5,14.12 v3(179.21,14.84) ; Q6402.G 123.93,13.45 120.72,16.66 v3(120.29,16.66) 121.59,17.96 124.55,17.96 126.54,19.95 v3(129.83,19.95) 130.65,19.13 131.48,19.13 132.35,20 ; v3(200.64,20.18) 200.4,19.94 199.38,19.94 199.37,19.94 199.37,19.94 199.25,19.82 198.5,19.82 198.49,19.83 ; v3(87.41,30.56) 87.41,29.93 87.92,29.42 R24078.2 R24044.2 90.37,29.42 90.65,29.7 94.41,29.7 95.23,30.52 95.23,35.03 ; R6310.1 v3(84.13,67.03) ; v3(260.78,29.11) 260.7,29.11 259.61,30.2 259.61,32.36 260.12,32.86 260.12,33.02 260.12,33.02 260.12,33.88 v2(260.09,33.91) ; v3(197.97,26.17) 198.55,25.59 R1715.2 ; R24013.1 R24101.1 69.83,18.44 v3(69.63,18.24) 69.63,18.18 69.49,18.04 69.49,16.72 R24121.2 ; PR5003.2 152.46,41.72 153.14,41.04 153.14,38.7 151.26,36.81 v1(151.26,36.12) 151.26,34.84 R4052.1 150.19,33.96 149.65,33.43 143.72,33.43 143.69,33.4 R4053.1 143.55,33.39 142.2,33.39 v3(141.6,32.79) ; v3(21.88,24.39) 21.88,24.74 R5518.2 ; Q6803.S 18.39,90.32 v3(18.41,90.34) 18.41,92.31 16.8,93.92 14.71,93.92 Q6801.S ; R1714.2 201.98,18.21 202.11,18.34 v3(202.11,19.19) ; v3(71.45,23.74) 71.01,23.74 70.52,23.25 R24084.1 ; v3(124.5,28.84) 124.5,22.34 125.69,21.15 ; R24075.2 69.25,11.64 v3(69.24,11.65) ; v3(18.41,85.7) 20.62,83.49 39.58,83.49 42.04,81.02 47.66,81.02 47.87,80.82 ; v3(184.55,17.32) 184.6,17.27 184.6,16.55 R2031.1
  TOP w0.762: 50.47,77.79 50.47,77.41 46.65,73.59 43.95,73.59 42.91,72.54 42.91,72.13 42.89,72.12 R2759.1
  L3 w0.508: v3(75.91,31.61) 79.85,31.61 80.58,30.88 80.88,30.88 v3(81.09,30.67) 81.7,31.28 86.69,31.28 v3(87.41,30.56) ; v3(86.47,7.45) 86.48,7.44 89.53,7.44 89.76,7.66 93.27,7.66 v3(93.77,8.16) ; v3(24.72,8.19) 25.29,8.76 25.29,12.95 22.4,15.83 22.4,23.86 v3(21.88,24.39) ; v3(18.41,90.34) v3(18.41,85.7)
  L4 w0.508: v3(132.52,32.29) 132.97,32.29 133.22,32.54 133.26,32.54 133.51,32.79 136.28,32.79 136.59,33.1 139.21,33.1 139.22,33.09 139.47,33.09 139.77,32.79 v3(141.6,32.79) ; v3(103.71,10.29) 102.97,10.29 101.33,11.92 101,11.92 100.99,11.93 97.54,11.93 v3(93.77,8.16)
  BOTTOM w0.381: R4003.1 135.91,44.93 136.18,45.2 137.69,45.2 140.57,42.32 140.57,38.6 142.15,37.02 142.15,36.91 142.16,36.9 142.16,34.1 ; v3(120.29,16.66) 120.01,16.66 119.47,17.21 U4020.5
  BOTTOM w0.508: R1915.2 210.7,4 211.28,3.42 v3(211.61,3.42) ; 82.71,75.48 82.71,77.68 83.51,78.47 86.83,78.47 88.52,80.16 90.68,80.16 91.49,80.98 97.24,80.98 98.66,82.4 103.13,82.4 109.22,76.31 109.22,75.16 108.44,74.38 PR4510.1 ; PR5325.1 133.4,32.68 133.26,32.54 133.22,32.54 132.97,32.29 v3(132.52,32.29) 132.17,31.94 128.2,31.94 126.54,30.28 126.54,30.28 125.1,28.84 v3(124.5,28.84) 124.5,29.36 123.38,30.48 123.3,30.48 PR5421.1 ; PR5202.1 260.61,28.94 v3(260.78,29.11) ; v3(87.41,30.56) 89.2,30.56 90.65,29.12 90.65,26.98 89.48,25.82 89.48,25.09 88.47,24.08 88.31,24.08 R24066.2 88.25,23.8 89.44,22.6 R24108.2 89.44,22.4 R24049.2 R24048.2 ; C2501.1 196.62,7.64 198.49,9.51 R1506.1 ; 142.16,34.1 142.16,33.35 v3(141.6,32.79) 142.18,32.21 143.25,32.21 144.09,31.37 144.09,30.17 143.74,29.81 ED6101.5 ; R1520.1 212.25,18.72 211.6,18.72 211.59,18.73 210.44,18.73 R2003.2 210.42,18.72 R1505.1 209.03,18.72 207.46,20.29 R1718.1 206.8,20.48 204.5,22.79 v3(204.5,22.84) 202.86,24.48 v3(202.86,25.72) 202.86,26.19 201.12,27.92 R1717.2 201.11,29.52 R1713.1 200.1,29.54 R1528.1 ; v3(75.91,31.61) 75.57,31.27 75.57,29.29 74.55,28.27 R24026.2 73.89,28.26 73.89,26.18 v3(71.45,23.74) 70.49,22.77 70.49,19.74 70.68,19.55 R24100.1 70.54,18.92 70.37,18.92 69.73,18.28 69.63,18.28 v3(69.63,18.24) 69.63,16.19 69.9,15.92 69.9,13.7 69.24,13.04 v3(69.24,11.65) ; 76.05,72.88 76.05,67.97 78.69,65.33 78.69,55.68 77.55,54.55 D4302.1 77.55,53.13 78.06,52.63 R4331.2 ; L5601.1 58.76,15.76 58.77,15.76 C5607.1 60.31,15.77 v1(60.78,15.3) 60.78,14.18 L5602.1 60.46,12.02 61.81,10.67 64.1,10.67 v3(65.21,9.55) 65.21,9.26 70.19,4.28 75.42,4.28 75.66,4.05 77.5,4.05 ; 77.66,6.25 75.74,6.25 75.01,6.98 75.01,6.99 74.83,7.17 74.83,8.66 76.19,10.02 76.19,14.43 77.1,15.34 78.46,15.34 79.34,16.22 81.76,16.22 82.93,17.38 R24014.2 82.93,19.23 82.11,20.04 82.11,25.84 82.55,26.28 82.55,27.53 82.28,27.8 R24017.2 82.28,28.95 81.95,29.28 81.95,29.29 81.09,30.16 v3(81.09,30.67) ; PR5420.1 112.44,30.87 109.75,28.18 v3(109.01,28.18) ; R6403.1 121.8,16.66 v3(120.29,16.66) ; R4026.1 129.57,19.7 v3(129.83,19.95) ; v2(97.03,36.79) 97.03,35.53 96.85,35.34 96.85,28.13 96.67,27.95 96.67,26.87 95.51,25.71 v3(95.51,24.5) 95.48,24.46 R24117.2 ; R1716.2 v3(191.13,19.44)
  vias: v1(49.09,80.56) v1(55.41,75.45) v1(67.28,70.76) v1(81.77,4.46) v1(86.68,64.75) v1(97.52,34.91) v1(143.72,23.18) v1(143.88,15.4) v1(184.87,18.48) v1(191.58,13.4) v2(48.18,85.6) v2(48.22,84.64) v2(49.1,85.6) v2(53.77,81.66) v2(54.21,80.82) v2(54.7,81.66) v2(58.31,76.54) v2(92.87,64.3) v2(92.88,63.39) v2(96.29,37.75) v2(97.22,37.68) v2(98.02,36.83) v2(102.59,50.85) v2(102.57,49.91) v2(103.2,49.19) v2(103.47,51.09) v2(103.45,50.16) v2(104.11,49.19) v2(104.38,51.1) v2(104.36,50.18) v2(234.02,2.4) v2(235.03,2.42) v2(259.38,33.33) v3(60.13,76.76) v3(60.11,76.02) v3(133.14,5.94) v3(133.88,5.99) v3(144.59,24.46) v3(165.91,19) v3(166.42,19.5) v3(166.6,18.33) v3(167.11,18.83) v3(176.79,15.46) v3(181.28,31.43) v3(182.11,30.79) v3(184.76,19.38) v3(189.33,6.13) v3(190.11,6.64) v3(194,17.2) v3(195.31,5.58) v3(196.02,5.6) v3(213.88,8.24) v3(227.28,101.44) v3(227.99,101.42) v3(245.83,93.9) v3(246.37,93.45)
3D3V_S5_SPI: length 1.5
  TOP w0.203: CPU1.DB34 185.66,33.28 v3(185.99,33.61)
  BOTTOM w0.508: R2208.2 185.99,33.12 v3(185.99,33.61)
3D3V_SB_RTC: length 4.8
  BOTTOM w0.508: v1(170.56,9.24) R2519.1 R2514.1 168.01,9.24 C2503.1 167.55,9.27 167.55,9.99 167.9,10.34 D2501.1
3D3V_SB_SYS: length 22.9
  TOP w0.203: ECIO1.67 87.6,25.94 v3(87.8,26.14)
  L4 w0.305: v3(71.99,26.67) 73.55,25.1 81.79,25.1 83.56,26.87 86.37,26.87 87.1,26.14 v3(87.8,26.14)
  BOTTOM w0.305: D2402.2 72.27,28.41 72.41,28.27 R24026.1 v1(73.01,27.28) 73.01,26.94 72.73,26.67 v3(71.99,26.67)
3D3V_SIO_AVCC3: length 10.8
  TOP w0.203: ECIO1.96 76,25.75 75.81,25.93 74.84,25.93
  TOP w0.508: 74.84,25.93 73.7,25.93 72.31,27.32 71.85,27.32 C2425.1 70.55,27.73 C2405.1 68.99,27.73 L2401.1 67.72,28.03 v1(67.41,27.73)
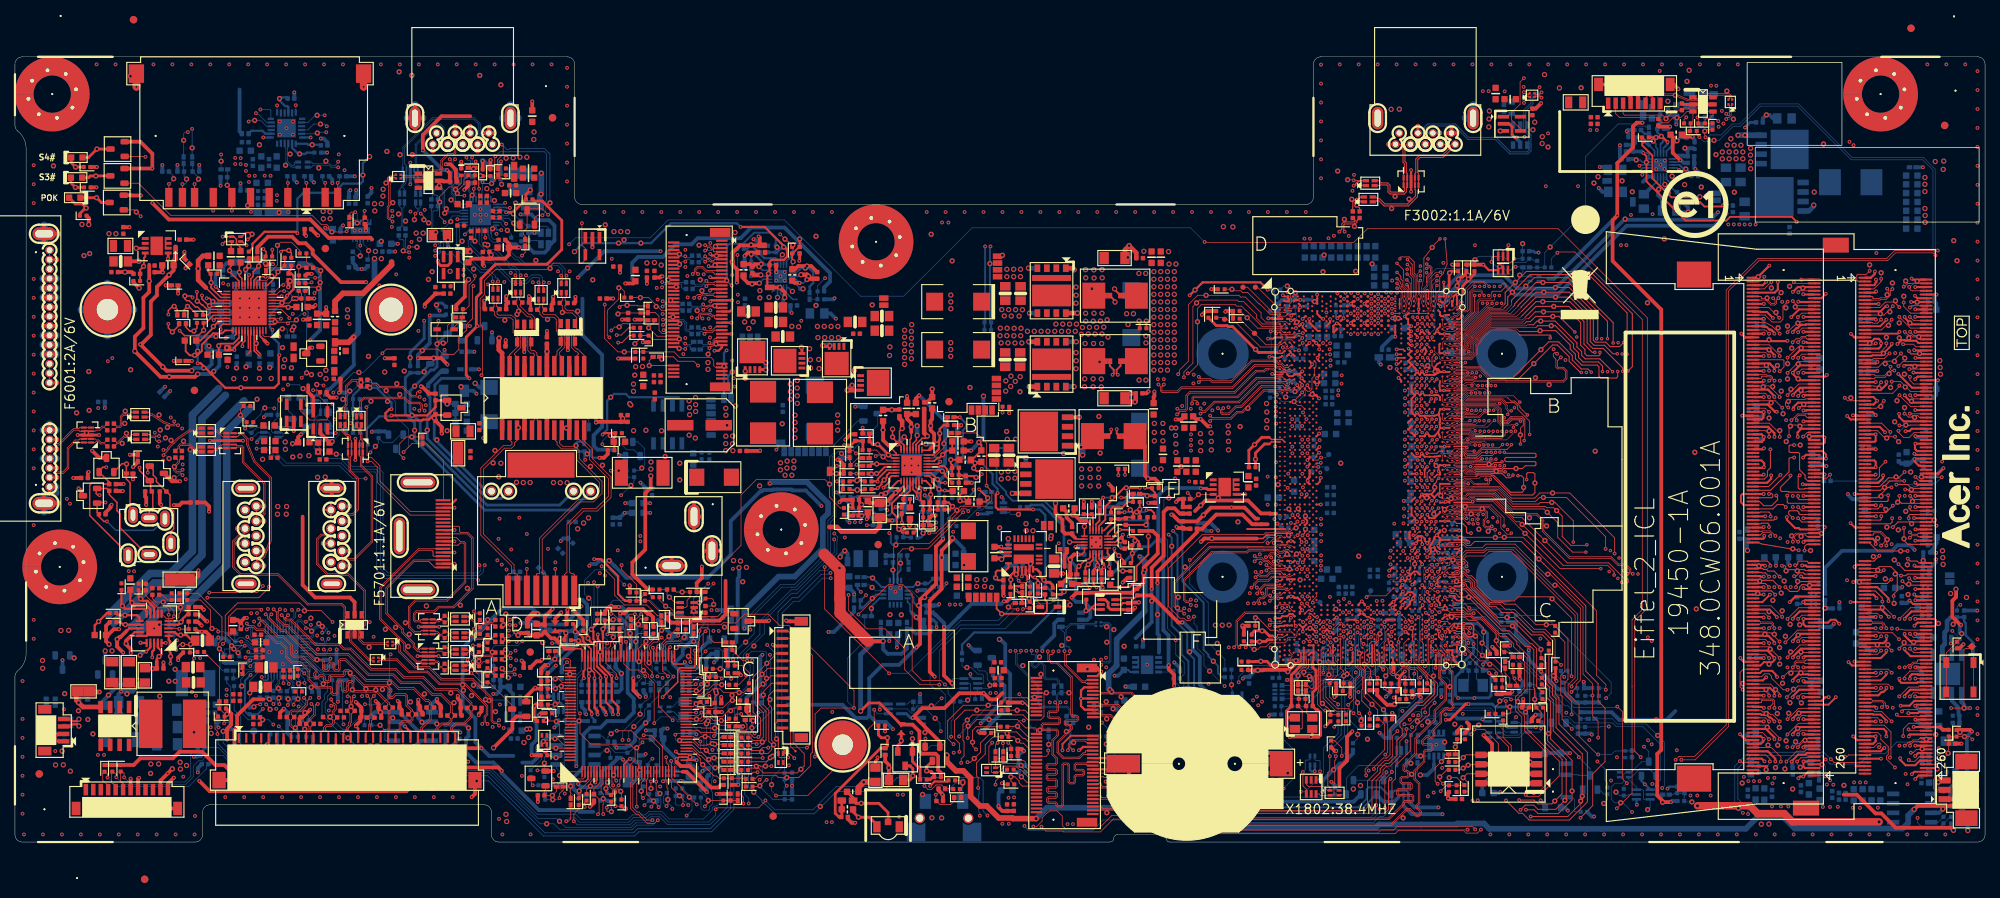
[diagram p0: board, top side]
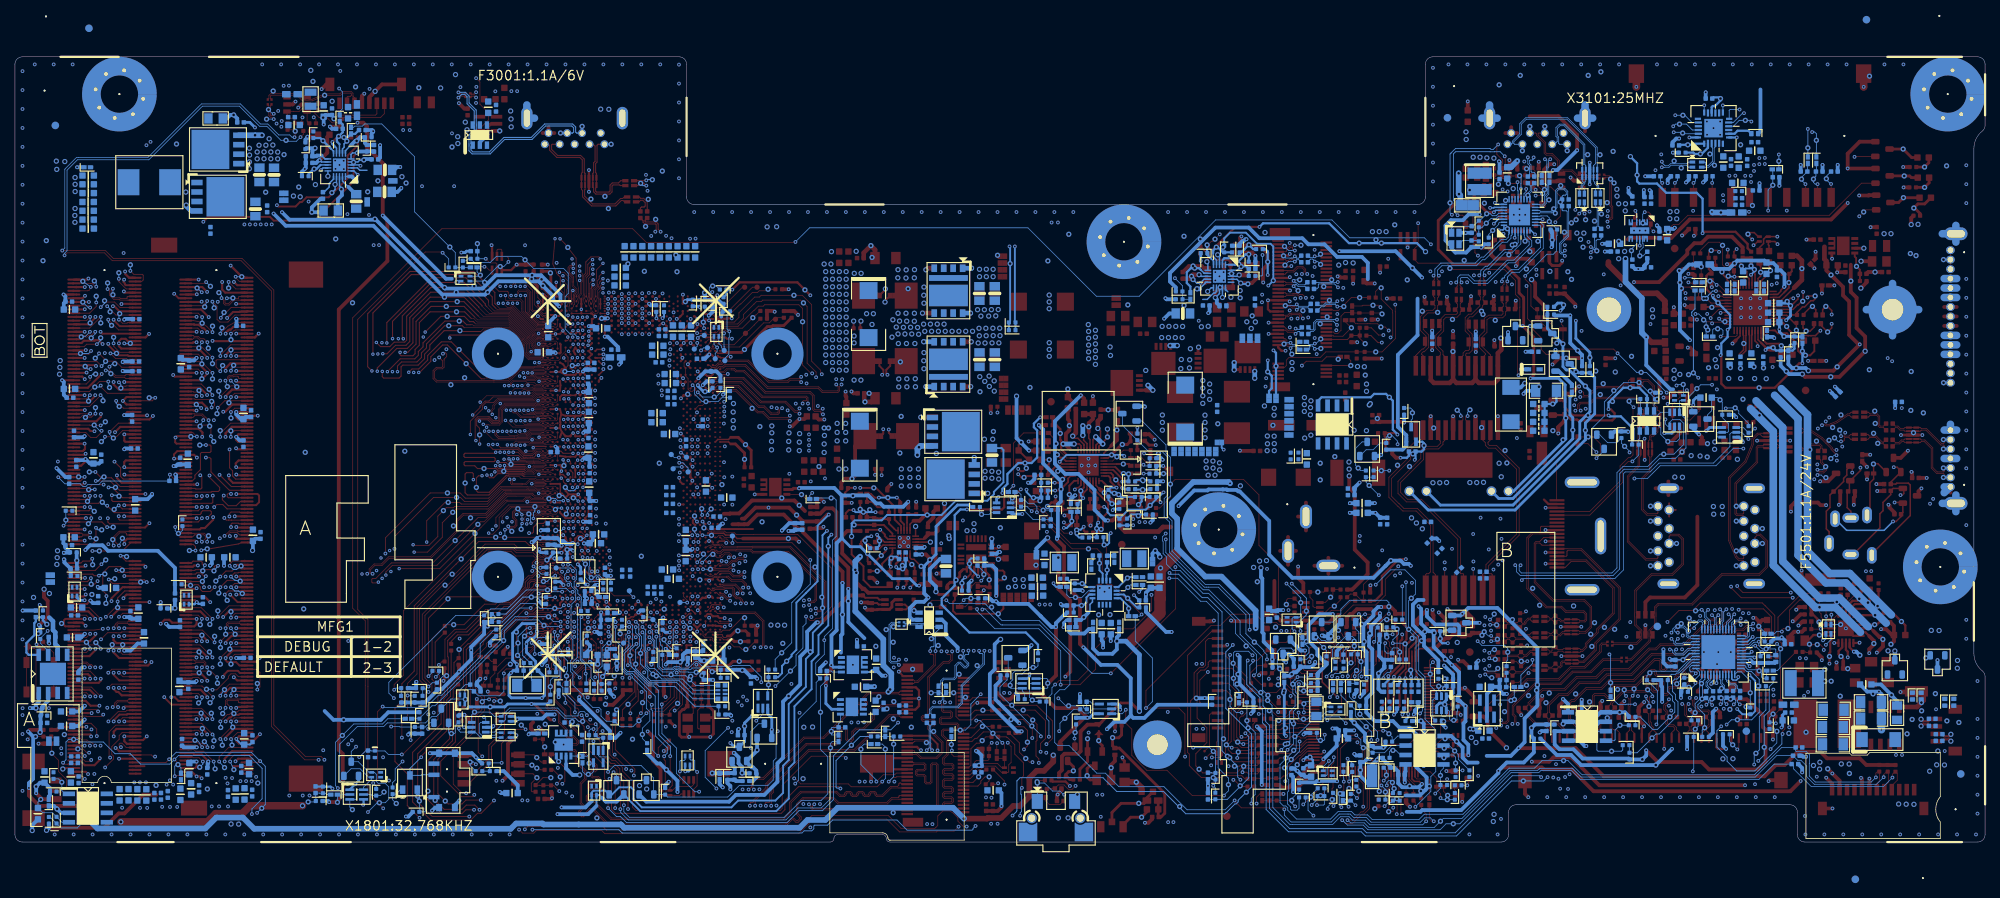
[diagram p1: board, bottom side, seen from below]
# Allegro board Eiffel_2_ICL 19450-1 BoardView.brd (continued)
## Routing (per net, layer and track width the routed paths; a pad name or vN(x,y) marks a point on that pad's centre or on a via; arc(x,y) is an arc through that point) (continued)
3D3V_VBAT_SIO: length 8
  TOP w0.203: ECIO1.66 88,24.14 88.27,23.87 89.5,23.87 89.72,24.1 89.72,24.14 v3(89.77,24.14)
  BOTTOM w0.508: v3(89.77,24.14) 89.77,23.95 90.25,23.47 91.7,23.47 C2419.1 91.75,23.33 92.32,22.76 92.66,22.76 v1(92.92,22.51) 93.14,22.29 R24004.1
65W_OCP: length 59.4
  TOP w0.102: v3(75.72,17.25) 75.72,17.25 75.72,14.58 77.18,13.12 82.39,13.12 83.1,12.41 83.1,11.03 82.4,10.32 ECIO1.17
  L4 w0.127: v3(78.72,53.34) 77.86,52.48 77.86,47.72 78.14,47.44 78.14,36.6 77.9,36.36 77.9,35.15 v3(77.6,34.85)
  BOTTOM w0.102: v3(75.72,17.25) 75.39,17.58 75.39,22 76.25,22.86 76.25,27.39 77.6,28.74 77.6,34.85 v3(77.6,34.85) ; v3(78.72,53.34) 78.72,53.77 79.46,54.5 v1(79.8,54.5) 80.04,54.5 80.25,54.29 R4331.1 81.08,53.51 81.99,52.61 82.93,52.61 Q4308.G
AC_PRESENT: length 11.6
  TOP w0.102: v3(190.43,31.75) 190.72,31.46 191.3,31.46 CPU1.DE46
  BOTTOM w0.102: R1713.2 198.7,29.52 196.22,32 194.31,32 193.65,31.34 v1(191.66,31.34) 190.85,31.34 v3(190.43,31.75)
ALL_SYS_PWRGD: length 91.4
  TOP w0.102: v3(124.61,21.12) 124.09,21.65 121.58,21.65 120.23,23 120.23,33.28 118.97,34.54 118.45,34.54 118.3,34.69 118.3,38.64 118.99,39.32 v1(120.15,39.32) 122.33,39.32 124.29,41.29 124.34,41.29 126.2,43.14 126.2,43.37 v3(127.06,44.22)
  L4 w0.127: v3(164.66,16.26) 164.53,16.39 160.78,16.39 158.84,14.46 153.33,14.46 152.04,13.17 136.7,13.17 136.34,13.53 134.41,13.53 133.34,14.61 129.92,14.61 129.43,14.12 128.85,14.12 128.17,14.8 126.49,14.8 125.8,14.12 v3(125.45,14.12)
  BOTTOM w0.102: v3(125.45,14.12) 125.45,16.23 125.79,16.57 R4013.1 125.79,19.14 125.04,19.88 125.04,20.69 v3(124.61,21.12) ; v3(127.06,44.22) 127.06,45 127.48,45.43 128.26,45.43 128.68,45.85 129.17,45.85 R4036.2 129.18,46.6 129.53,46.94 R4037.2 129.99,46.62 130.58,46.04 Q4001.3 ; v3(164.66,16.26) 163.78,17.14 U4013.2
AUD_AGND: length 19.6
  TOP w0.203: U2701.38 29.62,68.09 29.48,67.95
  TOP w0.508: EC2911.2 13.54,48 v3(14.56,48) ; EC2913.2 13.56,47.07 v3(14.45,47.07) ; R2733.2 v3(34.58,77.49) ; v3(19.59,45.22) 19.41,45.4 EC2912.2 ; v3(21.31,45.18) 22.05,45.18 22.39,45.53 23.52,45.53 C2908.1 ; v3(17.59,45.21) 17.59,46.18 17.44,46.33 17.44,47.01 EC2910.2 ; v3(15.83,50.3) 15.82,50.3 16.46,50.94 R2909.2 ; v3(9.85,49.64) 9.85,49.61 9.77,49.53 C2907.1 ; R2924.2 22.87,76.97 v3(22.87,76.94) ; R2923.2 v3(23.72,64.53) ; R2902.2 v3(15.82,48.64) ; EC2909.2 12.14,44.19 12.81,44.86 12.81,45.1 v3(12.94,45.23) ; R2922.2 v3(21.86,73.56)
  BOTTOM w0.508: R2705.2 28.4,67.74 v3(28.25,67.59) ; C2910.1 19.4,60.35 v3(20.12,61.06) ; C2911.1 v3(12.05,58.2)
  vias: v1(26,66.52) v3(27.91,74.94) v3(28.48,63.7) v3(28.59,74.74)
AUD_HP1_JACK_L1: length 39.1
  TOP w0.203: v3(17.8,49.54) 17.8,50.16 ED2903.1 18.53,49.96 18.53,49.2 18.96,48.77 18.96,48.35 EC2912.1 20.31,47.01 20.78,46.54 20.78,44.87 21.27,44.38 21.27,42 20.9,41.63 AUDS1.1 ; L2903.2 21.76,71.41 v1(21.34,71.83) 21.11,71.83 20.56,71.28 v3(20.56,70.75)
  L4 w0.203: v3(17.8,49.54) 17.31,50.03 17.31,61.53 21.15,65.37 21.15,70.34 20.74,70.75 v3(20.56,70.75)
AUD_HP1_JACK_L2: length 19.9
  TOP w0.203: v3(23.8,73.04) 23.61,73.23 v1(22.77,73.23) 22.77,72.84 23.01,72.6 23.35,72.6 24.18,71.76 24.46,71.76 25.2,71.03 R2904.1 25.82,70.68 26.17,71.04 U2701.32 ; v3(27.81,80.18) 28.17,80.54 RN2703.2 29.04,80.09 28.96,80 C2723.2
  L3 w0.203: v3(23.8,73.04) 23.8,76.17 v3(27.81,80.18)
AUD_HP1_JACK_L2_R: length 3.1
  TOP w0.203: L2903.1 22.68,71.38 v1(23.13,71.83) 23.29,71.83 24.31,70.81 R2904.2
AUD_HP1_JACK_R1: length 31.4
  TOP w0.203: AUDS1.2 18,44.37 18.48,44.85 18.48,46.88 EC2910.1 18.19,47.18 18.19,48.34 ED2903.2 16.7,49.82 v3(16.7,50.21) ; v3(20.56,69.5) 20.56,68.95 v1(21.1,68.41) 22.01,69.31 L2910.2
  L4 w0.203: v3(20.56,69.5) 20.56,69.5 20.56,65.94 16.7,62.08 v3(16.7,50.21)
AUD_HP1_JACK_R2: length 27.1
  TOP w0.203: v3(27.84,81.19) RN2703.1 29.34,81.19 29.68,80.85 29.68,80.27 30.23,79.72 C2724.2 ; U2701.33 26.59,70.64 26.45,70.49 26.43,70.49 26.14,70.19 26.14,70.18 25.58,69.62 R2905.1 v1(25.29,68.63) 24.57,67.91 23.7,67.91 23.7,67.91 23.34,67.91 23.33,67.91 22.73,67.91 v3(22.07,68.57)
  L3 w0.203: v3(27.84,81.19) 23.38,76.73 23.38,76.72 23.08,76.43 23.08,76.43 22.88,76.23 22.88,72.7 22.07,71.9 v3(22.07,68.57)
AUD_HP1_JACK_R2_R: length 3
  TOP w0.203: R2905.2 24.4,68.94 v1(23.98,68.52) 23.43,68.52 22.92,69.03 L2910.1
AUD_HP1_JD#: length 64.5
  TOP w0.203: v3(35.65,79.14) 35.84,79.33 v1(36.7,79.33) 36.75,79.33 37.04,79.05 R2713.2 ; AUDS1.6 15.17,38.63 10.03,43.78 10.03,47.88 10.28,48.13 11.84,48.13 11.96,48.01 12.57,48.01 12.58,48 EC2911.1 12.64,48.26 ED2904.1 11.29,49.78 11.78,50.27 v3(12.24,50.27)
  L4 w0.203: v3(35.65,79.14) 35.44,78.94 26.57,78.94 23.12,75.49 23.12,74.07 21.36,72.31 20.28,72.31 18.94,70.96 18.94,65.97 13.96,61 13.96,52.63 12.24,50.9 v3(12.24,50.27)
AUD_HP1_JD#_TYPE: length 9.4
  TOP w0.203: ED2904.2 13.26,49.64 14.35,50.73 14.92,50.73 v1(14.96,50.7) 14.93,50.67 R2902.1 14.93,48.67 15.42,48.18 15.42,44.25 AUDS1.5
AUD_SENSE_A: length 4.9
  TOP w0.203: U2701.13 33.84,74.66 34.57,75.4 34.57,75.54 35.04,76.01 35.04,76.24 v1(35.26,76.46) 36.09,77.29 R2709.1 36.14,77.3 36.14,77.82 36.16,77.84 36.16,78.34 R2713.1
AUD_SPK_L+: length 40.5
  TOP w0.203: 31.27,66.2 31.27,67.99 31.22,68.03 U2701.42
  BOTTOM w1.016: 12.55,30.45 18.12,36.02 20.81,36.02 23.79,39 23.79,57.3 27.3,60.81
  vias: v1(29.69,63.58) v2(29.32,62.14)
AUD_SPK_L+_CON: length 2.2
  TOP w0.305: v2(4.58,13.53) 4.83,13.78 5.45,13.78 5.72,13.5 SPK1.1
  vias: v1(3.51,16.04)
AUD_SPK_L-: length 41.8
  TOP w0.203: 31.14,65.4 31.57,65.84 31.57,67.99 31.62,68.04 U2701.43
  BOTTOM w1.016: 28.21,59.92 25.06,56.77 25.06,38.47 21.34,34.75 18.64,34.75 13.24,29.35
  vias: v1(30.97,63.73) v2(30.88,62.16)
AUD_SPK_L-_CON: length 2.2
  TOP w0.305: SPK1.2 5.79,14.5 5.47,14.18 4.85,14.18 v2(4.58,14.44)
  vias: v1(5.11,16.24)
AUD_SPK_R+: length 41.1
  TOP w0.203: U2701.45 32.42,68.01 32.36,67.95 32.36,66.01 32.94,65.43
  BOTTOM w1.016: 16.7,28.13 20.02,31.45 22.71,31.45 28.38,37.12 28.38,55.06 31.43,58.11
  vias: v1(34.14,63.63) v2(34.35,62.17)
AUD_SPK_R+_CON: length 2.3
  TOP w0.305: SPK1.3 7.35,15.5 7.64,15.79 8.35,15.79 v2(8.58,15.56)
  vias: v1(9.77,16.44)
AUD_SPK_R-: length 41.9
  TOP w0.203: U2701.44 32.02,67.95 32.06,67.92 32.06,65.88 32.78,65.16
  BOTTOM w1.016: 15.65,28.87 19.49,32.72 22.18,32.72 27.11,37.64 27.11,55.59 30.7,59.18
  vias: v1(32.77,63.53) v2(32.76,62.17)
AUD_SPK_R-_CON: length 2.3
  TOP w0.305: SPK1.4 7.31,16.5 7.62,16.19 8.3,16.19 v2(8.58,16.47)
  vias: v1(8.5,17.6)
AUDIO_PC_BEEP: length 3.3
  TOP w0.102: C2725.2 38.97,77.01 38.83,77.15 v1(38.04,77.15) 38.04,77.14 R2730.1 38.04,74.94 R2778.1
AUDIO_PC_BEEP255: length 4.1
  TOP w0.102: v3(35.97,74.71) 35.69,74.71 34.82,73.84 U2701.12
  BOTTOM w0.102: R2732.1 37.73,75.23 v1(36.88,75.23) 36.49,75.23 v3(35.97,74.71)
AUDIO_PC_BEEP256: length 11.2
  TOP w0.102: U2701.16 32.42,75.22 32.54,75.33 33.76,75.33 34.04,75.62 34.04,75.78 34.2,75.94 34.2,76.42 35.18,77.4 v1(35.18,80.02) 35.6,80.44 37.06,80.44 38.17,79.33 R2731.1
AUDIO_PC_BEEP_R: length 6.9
  TOP w0.102: R2731.2 39.06,77.82 39.43,77.44 39.54,77.44 39.95,77.03 C2725.1 40.6,77.01 40.6,77.01 v1(40.98,76.63) 40.98,75.97 40.68,75.67 v3(40.23,75.67)
  BOTTOM w0.102: R2732.2 38.77,75.27 39.18,75.67 v3(40.23,75.67)
AUDIO_VREF: length 9.2
  TOP w0.203: U2701.28 27.29,72.64 25.58,74.35
  TOP w0.635: 25.58,74.35 24.55,75.38 v1(24.55,76.9) 24.55,77.98 25.19,78.61 C2705.2
BIOS_REC: length 19.1
  TOP w0.102: CPU1.DK29 183.21,29.17 v3(183.52,28.86)
  BOTTOM w0.102: R2108.2 179.93,13.9 v1(179.93,14.43) 179.93,15.26 178.92,16.27 178.92,17.46 179.39,17.94 179.39,20.17 181.23,22.02 181.23,22.17 181.5,22.43 182.07,22.43 182.76,23.13 182.76,26.25 182.98,26.47 182.98,26.48 183.52,27.02 v3(183.52,28.86)
BKLT_ADJ: length 12.8
  TOP w0.114: R5512.1 27.9,25.41 v1(27.4,25.92) 27.31,26.01 27.31,26.69 27.75,27.14 27.75,30.14 24.53,33.36 R5510.1 R5511.2
BKLT_ADJ_PWM: length 7
  TOP w0.114: U5501.5 21.47,29.65 21.97,30.15 21.97,30.6 22.19,30.82 v1(22.19,31.49) 22.19,32.32 R5511.1 R5515.1 20.45,32.47 19.76,33.15 C5515.1
BKLT_EN: length 82.9
  TOP w0.114: R5519.2 27.4,23.43 C5506.1 27.4,17.92 R5505.2 28.09,17.2 R5509.2 28.09,16.3 28.04,16.24 v3(28.04,15.92)
  L3 w0.127: v3(28.04,15.92) 29.22,14.74 29.22,13.64 28.21,12.63 28.21,11.84 31.91,8.14 53.79,8.14 57.13,11.48 58.43,11.48 58.85,11.06 59.37,11.06 59.57,11.26 61.37,11.26 62.15,10.48 62.9,10.48 63.32,10.06 64.51,10.06 64.53,10.04 66.03,10.04 69.11,6.97 70.33,6.97 72.67,4.63 75.59,4.63 76.16,5.2 79.38,5.2 79.67,4.91 79.7,4.91 80.38,4.24 84.42,4.24 84.92,4.74 v3(85.29,4.74)
  BOTTOM w0.114: v3(85.29,4.74) 86.06,5.52 R24040.1 ; v3(28.04,15.92) 28.17,16.05 R5504.2 28.89,16.68 v1(28.41,17.16)
BKLT_EN_EC: length 7.8
  TOP w0.114: ECIO1.23 84.8,8.51 84.65,8.36 84.65,6.43 v1(85.58,5.5) 86.25,4.82 v3(86.25,4.67)
  BOTTOM w0.114: R24040.2 86.45,6.44 86.55,6.34 86.55,4.97 v3(86.25,4.67)
BKLT_EN_ENA: length 11.2
  TOP w0.114: v3(21.61,25.76) 21.61,26 22.09,26.48 v1(22.49,26.48) 23.11,26.48 23.44,26.15 R5518.1 23.98,25.42 24.06,25.49 R5519.1 ; U5501.3 21.95,28.65 v3(22.02,28.58) 22.05,28.55 R5521.1 C5520.1
  L3 w0.127: v3(21.61,25.76) 22.36,26.5 22.36,28.24 v3(22.02,28.58)
BOOT_HALT: length 3.2
  TOP w0.114: R1510.1 v1(193.01,12.76) 193.26,13 193.26,13.34 193.25,13.34 R1511.1 193.26,13.8 193.71,13.8 193.72,13.8 194.3,13.8 R1503.2
BT_DISABLE_N: length 58.4
  TOP w0.102: v3(132.39,13.26) 132.43,13.22 R6134.2 ; ECIO1.59 90.7,21.38 91.45,22.13 v3(92.13,22.13)
  L3 w0.127: v3(132.39,13.26) 131.96,12.84 130.46,12.84 130.36,12.94 126.66,12.94 126.17,12.45 125.6,12.45 125.6,12.44 125.31,12.73 115.39,12.73 113.18,10.52 109.09,10.52 105.42,14.19 101.71,14.19 99.8,12.27 97.99,12.27 97.91,12.35 v3(94.3,12.35)
  BOTTOM w0.102: v3(94.3,12.35) v1(93.45,13.21) 93.15,13.5 93.15,14.67 93.23,14.74 93.23,17.45 92.45,18.23 92.45,19.65 92.76,19.95 92.76,21.51 92.28,21.98 92.28,21.98 v3(92.13,22.13) 90.6,22.13 R24108.1
BT_PCMFRM_RSTN: length 115.9
  TOP w0.114: v3(126.8,10.62) 126.8,11.17 127.18,11.54 127.18,13.49 127.04,13.63 127.04,15.78 v1(127.62,16.36) 128.31,17.05 135.09,17.05 135.76,16.38 137.45,16.38 137.9,16.82 137.9,19.87 137.76,20 NGFFE1.10
  L3 w0.127: v3(207.88,17.35) 207.88,17.87 207.63,18.13 195.83,18.13 194.98,18.98 194.59,18.98 194.45,18.84 193.19,18.84 191.17,20.86 184.7,20.86 183.82,19.98 183.09,19.98 181.63,18.52 179.48,18.52 179.04,18.96 176.64,18.96 176.29,19.31 166.92,19.31 163.98,16.37 163.98,15.63 162.5,14.15 161.56,14.15 160,12.59 155.09,12.59 154.38,11.88 144.05,11.88 143.25,11.09 134.51,11.09 133.59,10.17 127.17,10.17 126.8,10.54 v3(126.8,10.62)
  L4 w0.127: v3(207.61,22.14) 207.61,22.08 207.88,21.81 v3(207.88,17.35)
  BOTTOM w0.114: R1913.1 207.16,22.59 v3(207.61,22.14)
BT_PCMOUT_CLKREQ0: length 122.2
  TOP w0.114: v3(208.62,15.16) 207.32,16.47 207.32,19.54 207.14,19.72 207.14,22.34 207.69,22.88 207.69,26.8 R1912.1 ; v3(125.78,13.13) 125.73,13.13 124.98,13.87 124.98,16.25 127.08,18.34 v1(130.42,18.34) 131.77,18.34 R6119.1 132.78,19.35 135.65,19.35 136,19 NGFFE1.14
  L3 w0.127: v3(167.95,14.74) 167.58,14.37 167.58,13.05 168.13,12.5 174.37,12.5 175.74,13.87 177.74,13.87 178.14,13.48 183.71,13.48 184.4,14.17 188.72,14.17 189.27,14.72 193.91,14.72 196.44,17.25 202.1,17.25 202.8,16.56 205.44,16.56 206.83,15.16 v3(208.62,15.16)
  L4 w0.127: v3(125.78,13.13) 127.04,13.13 127.24,12.93 129.45,12.93 129.46,12.92 130.33,12.92 130.54,12.71 135.97,12.71 137.07,11.62 151.86,11.62 153.89,13.64 159.18,13.64 161.11,15.58 163.41,15.58 163.72,15.26 166.19,15.26 166.78,14.67 167.89,14.67 v3(167.95,14.74)
BT_USB20_CON_N: length 15.4
  TOP w0.102: NGFFE1.5 143.58,21.25 143.43,21.4 142.99,21.4 140.67,23.71 140.67,25.57 v3(140.64,25.61)
  BOTTOM w0.102: 140.64,26.36 140.64,28.08 140.16,28.56 ED6101.1 140.96,28.86 141.43,29.33 144.72,29.33 EL6103.1 ; 140.64,26.36 v1(140.28,26.36) ; 140.64,26.36 v3(140.64,25.61)
BT_USB20_CON_P: length 14.9
  TOP w0.102: NGFFE1.3 143.59,21.75 143.45,21.6 143.08,21.6 140.88,23.8 140.88,25.04 140.98,25.14 141.3,25.14 141.35,25.19 v3(141.35,25.61)
  BOTTOM w0.102: 140.84,27.27 140.84,28.45 141.51,29.12 142.59,29.12 ED6101.6 143.12,29.12 144.71,29.12 EL6103.4 ; 140.84,27.27 140.84,26.28 140.94,26.18 141.21,26.18 141.35,26.05 v3(141.35,25.61) ; 140.84,27.27 v1(141.2,27.27)
BT_USB20_N: length 40.7
  TOP w0.102: CPU1.DP10 174.02,27.22 v3(174.39,26.85)
  L3 w0.114: v3(174.39,26.85) 174.21,26.67 174.21,26.42 173.96,26.17 171.59,26.17 170.55,27.22 167.37,27.22 167.32,27.27 160.48,27.27 157.77,24.56 154.75,24.56 153.27,23.08 147.93,23.08 147.13,23.89 145.68,23.89 v3(145.54,23.75)
  BOTTOM w0.102: v1(147.26,28.49) 146.87,28.49 ; 146.87,28.49 146.87,29.14 146.54,29.47 EL6103.2 ; 146.87,28.49 146.87,24.27 146.61,24.01 145.8,24.01 v3(145.54,23.75)
BT_USB20_P: length 41
  TOP w0.102: v3(174.41,27.55) 174.27,27.55 CPU1.DN10
  L3 w0.114: v3(145.54,24.46) 145.54,24.42 145.84,24.12 147.22,24.12 148.03,23.31 153.18,23.31 154.66,24.79 157.68,24.79 160.38,27.5 167.41,27.5 167.46,27.45 170.64,27.45 171.69,26.4 173.87,26.4 173.98,26.52 173.98,27.42 174.11,27.55 v3(174.41,27.55)
  BOTTOM w0.102: v1(146.31,26.8) 146.66,26.8 ; 146.66,26.8 146.66,24.35 146.52,24.21 145.8,24.21 v3(145.54,24.46) ; 146.66,26.8 146.67,26.8 146.66,26.81 146.66,29.06 146.46,29.27 145.93,29.27 145.88,29.22 145.88,29.06 145.8,28.97 EL6103.3
CBN: length 5.3
  TOP w0.203: U2701.35 27.54,69.84 27.36,69.65
  TOP w0.254: C2703.1 24.84,67.25 26.59,69 v1(26.59,69.14) 27.1,69.65 27.36,69.65
CBP: length 9.9
  TOP w0.203: U2701.37 28.43,68.61
  TOP w0.254: 28.43,68.61 28.17,68.61 27.78,68.22 26.56,68.22 25.04,66.71 25.04,65.85 24.48,65.28 v1(24.08,65.28) 24.07,65.27 23.43,65.27 22.88,65.82 22.88,67.13 C2703.2
CCD_USB20_CON_N: length 14
  TOP w0.102: CAM1.7 219.5,99.9 219.4,100 219.05,100 218.9,100.15 218.9,100.32 219,100.43 220.08,100.43 220.38,100.13 222.41,100.13 224.16,99.4 225.48,99.4 226.23,100.15 227.26,100.15 ED3002.6 227.82,100.15 229.65,100.15 229.76,100.04 229.76,99.72 EL3001.3
CCD_USB20_CON_P: length 14.6
  TOP w0.102: CAM1.6 218.5,99.8 218.7,100 218.7,100.41 218.92,100.63 220.16,100.63 220.46,100.33 222.45,100.33 224.2,99.6 224.58,99.6 ED3002.1 225.11,99.6 225.39,99.6 226.14,100.35 229.39,100.35 ; v1(229.39,100.71) 229.39,100.35 ; 229.39,100.35 229.74,100.35 229.97,100.13 229.97,99.72 EL3001.2
CCD_USB20_N: length 130.1
  TOP w0.102: v3(229.32,97.66) 229.57,97.41 229.68,97.41 229.78,97.51 229.78,98.76 EL3001.4 ; CPU1.DK13 175.88,29.17 v3(176.24,28.81)
  L3 w0.114: v3(176.24,28.81) 176.24,28.89 175.81,29.31 175.81,30.15 175.52,30.44 175.52,34.48 176.48,35.45 176.48,44.59 175.26,45.81 170.99,45.81 168.28,48.51 168.28,49.86 166.86,51.29 166.86,74.71 169.63,77.48 180.43,77.48 182.51,79.56 182.51,81.06 191.29,89.84 207.73,89.84 215.97,98.08 225.55,98.08 226.21,97.42 229.08,97.42 v3(229.32,97.66)
  BOTTOM w0.102: v3(229.32,97.66) 229.45,97.66 v1(230.02,98.23)
CCD_USB20_P: length 129.9
  TOP w0.102: v3(176.23,29.49) 176.23,29.72 176.13,29.82 CPU1.DJ13 ; EL3001.1 229.98,98.78 229.98,97.42 229.76,97.2 229.57,97.2 v3(229.32,96.95)
  L3 w0.114: v3(176.23,29.49) 176.41,29.49 176.52,29.61 176.52,29.91 176.44,29.99 176.12,29.99 176.04,30.08 176.04,30.24 175.75,30.53 175.75,34.39 176.71,35.35 176.71,44.68 175.36,46.04 171.08,46.04 168.51,48.61 168.51,49.95 167.09,51.38 167.09,74.62 169.72,77.25 180.53,77.25 182.74,79.46 182.74,80.96 191.38,89.61 207.82,89.61 216.07,97.85 225.45,97.85 226.11,97.19 229.08,97.19 v3(229.32,96.95)
  BOTTOM w0.102: v3(229.32,96.95) v1(230.28,96.95)
CFG0: length 13.6
  TOP w0.102: CPU1.AL7 172.36,58.55 171.87,58.55 171.53,58.88 CPU1.AJ5 171.53,59.26 CPU1.AG6 172.18,59.99 v3(172.5,60.31) 172.83,60.64 CPU1.AE7 173.21,60.45 173.47,60.45 173.54,60.52 173.61,60.52 173.79,60.7 173.79,60.76 173.8,60.78 173.8,62.18 174.13,62.51 CPU1.AB10 CPU1.Y10 174.33,63.77 174.33,64.28 CPU1.V10
  BOTTOM w0.102: R606.1 169.46,60.28 170.06,59.68 v1(170.29,59.68) 171.86,59.68 v3(172.5,60.31)
CFG4: length 7.2
  TOP w0.102: v3(173.19,61.26) 173.19,61.26 173.19,61.12 CPU1.AE9
  BOTTOM w0.102: R607.2 169.26,59.59 169.78,59.07 v1(171.4,59.07) 171.91,59.07 172.95,60.11 172.95,61.02 v3(173.19,61.26)
CFG_RCOMP: length 3.2
  TOP w0.203: CPU1.AD6 172.48,61.44 v3(172.48,61.28)
  BOTTOM w0.381: v3(172.48,61.28) 172.48,61.15 171.74,60.41 v1(171.53,60.41) 171,60.41 R605.2
CHGR_PSYS_IMVP: length 1.2
  TOP w0.102: PR4688.1 111.22,43.78 R4601.1
CNV_BRI_DT: length 74.7
  TOP w0.114: NGFFE1.36 135.75,13.5 135.35,13.9 135.09,13.9 134.22,14.77 130.94,14.77 R6160.1 130.74,14.64 129.4,13.3 129.4,12.06 v1(128.55,11.2) 128.05,10.71 v3(127.65,10.71) ; v3(183.55,20.61) 183.55,20.5 183.86,20.19 R1530.2 184.33,20.2 184.33,20.65 184.43,20.76 184.43,21.24 R2107.2
  L3 w0.127: v3(127.65,10.71) 127.87,10.93 133.27,10.93 134.06,11.72 142.99,11.72 143.78,12.51 154.12,12.51 154.83,13.22 159.4,13.22 166.15,19.97 178.88,19.97 178.89,19.96 179.13,19.96 179.66,19.42 181.62,19.42 182.81,20.61 v3(183.55,20.61)
CNV_BRI_DT_R: length 7.9
  TOP w0.114: CPU1.DL31 183.7,28.21 183.7,26.96 183.47,26.73 183.47,26.21 183.49,26.19 183.49,25.93 183.47,25.91 183.47,23.73 183.97,23.24 183.97,22.56 v1(183.68,22.28) 183.56,22.15 R2107.1
CNV_BRI_RSP: length 79.7
  TOP w0.114: R2104.1 181.51,21.87 v3(181.64,22) 181.64,23.11 181.18,23.57 181.18,23.92 181.49,24.23 181.49,24.27 181.52,24.3 181.52,26.59 181.84,26.91 182.32,26.91 182.5,27.09 182.5,27.78 183.1,28.38 CPU1.DL29 ; v3(126.56,12.1) 126.56,13.23 125.91,13.87 125.91,16.29 127.31,17.69 v1(128.89,17.69) 132.15,17.69 132.16,17.68 R6131.1
  L3 w0.127: v3(181.64,22) 181.64,21.74 180.65,20.75 179.51,20.75 179.36,20.61 165.88,20.61 159.13,13.86 154.57,13.86 153.87,13.16 134.6,13.16 133.01,11.57 127.09,11.57 v3(126.56,12.1)
CNV_BRI_RSP_R: length 4.1
  TOP w0.114: R6131.2 v1(134.29,17.68) 135.12,17.68 135.12,17.67 135.34,17.67 136.02,17 NGFFE1.22
CNV_RGI_DT: length 77.9
  TOP w0.114: NGFFE1.32 136.88,15.14 136.72,15.31 135.44,15.31 134.33,16.42 v1(130.53,16.42) 128.89,16.42 127.68,15.21 v3(127.68,13.95) ; v3(186.25,22.1) 186.27,22.08 R2106.2 186.27,20.22 R1516.1 186.28,19.73 186.44,19.58 R1507.2
  L3 w0.127: v3(127.68,13.95) 129.73,13.95 130.2,14.43 153.34,14.43 154.05,15.14 155.97,15.14 156.87,16.04 159.52,16.04 165.36,21.88 169.41,21.88 169.74,22.21 175.6,22.21 175.73,22.07 180.12,22.07 180.97,22.93 182.6,22.93 182.83,22.7 183.75,22.7 184.21,22.24 186.11,22.24 v3(186.25,22.1)
CNV_RGI_DT_R: length 9.9
  TOP w0.114: R2106.1 187.16,21.8 186.82,22.15 186.82,23.01 186.48,23.35 185.86,23.35 184.82,22.31 184.56,22.31 184.27,22.59 184.27,23.22 184.19,23.31 184.19,25.27 184.18,25.28 184.18,25.54 184.19,25.55 184.19,26.25 184.18,26.26 184.18,26.51 184.19,26.52 184.19,26.65 184.02,26.82 CPU1.DP31
CNV_RGI_RSP: length 72.4
  TOP w0.114: R6132.1 130.26,15.46 130.25,15.46 128.8,15.46 128.32,14.98 v1(128.32,13.39) 128.32,12.89 v3(128.78,12.43) ; R2105.1 182.54,21.98 v3(182.59,22.03) 182.28,22.34 182.28,24.1 182.19,24.19 182.19,26.49 182.4,26.7 182.43,26.7 182.75,27.02 182.75,27.52 CPU1.DN29
  L3 w0.127: v3(128.78,12.43) 129.01,12.2 132.75,12.2 134.34,13.79 153.6,13.79 154.3,14.49 158.87,14.49 165.62,21.24 179.1,21.24 179.3,21.44 180.38,21.44 181.58,22.63 181.9,22.63 182.28,22.26 182.51,22.03 v3(182.59,22.03)
CNV_RGI_RSP_R: length 4.5
  TOP w0.114: R6132.2 133.03,15.51 v1(134.36,15.51) 135.87,14 NGFFE1.34
CNV_WR_CLK_DN: length 80.3
  TOP w0.102: NGFFE1.21 145.35,17.25 145.5,17.11 146.86,17.11 151.58,12.39 157.68,12.39 162.56,7.5 162.56,6.75 162.86,6.45 162.86,5.4 162.96,5.31 163.37,5.31 163.47,5.21 163.47,4.95 v3(163.37,4.86) ; v3(189.95,28.84) 190.27,29.17 CPU1.DK44
  L4 w0.114: v3(163.37,4.86) 163.5,4.73 163.5,4.47 163.36,4.34 162.97,4.34 162.89,4.26 162.89,3.59 163.32,3.15 180.65,3.15 180.66,3.16 183.82,3.16 188.48,7.83 188.48,8.24 189.27,9.03 189.27,9.94 193.09,13.76 193.09,18.44 192.45,19.08 192.45,22.69 192.03,23.1 192.03,26.12 192.11,26.19 192.11,26.64 191.77,26.98 191.07,26.98 190.21,27.83 190.21,28.57 v3(189.95,28.84)
CNV_WR_CLK_DP: length 80.8
  TOP w0.102: v3(189.95,29.5) 190.27,29.82 CPU1.DJ44 ; 146.3,16.9 146.78,16.9 151.5,12.18 157.59,12.18 162.36,7.42 162.36,6.67 162.66,6.37 162.66,4.86 v3(162.66,4.85) ; 146.3,16.9 v1(146.3,16.52) ; 146.3,16.9 145.48,16.9 145.33,16.75 NGFFE1.23
  L4 w0.114: v3(189.95,29.5) 189.95,29.42 190.44,28.93 190.44,27.93 191.16,27.21 191.86,27.21 192.34,26.73 192.34,26.1 192.26,26.02 192.26,23.2 192.68,22.78 192.68,19.17 193.32,18.54 193.32,13.66 189.49,9.84 189.49,8.93 188.71,8.15 188.71,7.73 183.91,2.93 180.75,2.93 180.74,2.92 163.23,2.92 162.66,3.49 162.66,4.85 v3(162.66,4.85)
CNV_WR_DN0: length 79.7
  TOP w0.102: v3(165.52,4.87) 165.5,4.89 165.5,5.21 165.4,5.31 165.11,5.31 165.01,5.42 165.01,5.64 163.38,7.28 163.38,7.84 157.99,13.23 153.97,13.23 153.48,13.72 153.48,15.13 153.26,15.35 152.68,15.35 152.46,15.13 152.46,13.81 152.36,13.71 151.95,13.71 151.85,13.81 151.85,14.8 151.36,15.28 150.34,15.28 149.06,16.56 149.06,17.27 147.88,18.45 146.23,18.45 ; 146.23,18.45 v1(146.23,18.83) ; 146.23,18.45 145.5,18.45 145.2,18.75 NGFFE1.15 ; CPU1.DP44 190.23,27.22 189.92,26.91 v3(189.92,26.86)
  L4 w0.114: v3(165.52,4.87) 165.04,4.38 165.04,4.2 165.23,4 180.3,4 182.01,5.72 185,5.72 187.38,8.09 187.38,9.26 192.21,14.09 192.21,18.12 191.6,18.73 191.6,22.83 190.64,23.79 190.64,26.63 190.22,27.05 190.06,27.05 189.92,26.91 v3(189.92,26.86)
CNV_WR_DN1: length 79.7
  TOP w0.102: CPU1.DG42 189.35,30.47 v3(189.07,30.74) ; v1(146.72,20.46) 146.72,20.07 ; 146.72,20.07 145.52,20.07 145.34,20.25 NGFFE1.9 ; 146.72,20.07 149.69,20.07 150.37,19.4 150.37,19.08 149.98,18.69 149.98,18.55 150.26,18.26 150.41,18.26 150.8,18.65 151.11,18.65 151.52,18.25 151.52,17.93 151.14,17.56 151.14,17.41 151.43,17.13 151.58,17.13 151.95,17.5 152.26,17.5 155.69,14.07 158.29,14.07 163.75,8.62 164.76,8.62 165.32,8.06 165.32,7.36 165.64,7.04 v3(165.69,7.04)
  L4 w0.114: v3(165.69,7.04) 165.47,6.81 165.47,6.68 165.58,6.57 171.76,6.57 172.55,5.78 179.57,5.78 181.21,7.42 184.29,7.42 185.68,8.8 185.68,10.45 190.14,14.91 190.14,17.78 189.53,18.39 189.53,20.71 189.47,20.77 189.47,22.38 188.93,22.92 188.56,22.92 187.89,23.6 187.89,24.93 188.13,25.18 188.33,25.18 188.45,25.29 188.45,25.69 188.33,25.8 188.13,25.8 187.89,26.05 187.89,29.27 188.8,30.19 189.22,30.19 189.34,30.3 189.34,30.47 v3(189.07,30.74)
CNV_WR_DP0: length 79.7
  TOP w0.102: v3(189.92,27.51) 190.28,27.87 CPU1.DN44 ; 147.16,18.25 NGFFE1.17 ; 147.16,18.25 147.8,18.25 148.86,17.19 148.86,16.47 150.26,15.08 151.28,15.08 151.64,14.71 151.64,13.73 151.86,13.51 152.45,13.51 152.67,13.73 152.67,15.04 152.77,15.14 153.18,15.14 153.28,15.04 153.28,13.63 153.89,13.03 157.9,13.03 163.17,7.75 163.17,7.19 164.81,5.56 v3(164.81,4.87) ; 147.16,18.25 v1(147.16,17.87)
  L4 w0.114: v3(189.92,27.51) 190.15,27.28 190.32,27.28 190.87,26.73 190.87,23.88 191.83,22.93 191.83,18.82 192.44,18.21 192.44,13.99 187.61,9.16 187.61,8 185.09,5.49 182.1,5.49 180.39,3.78 165.14,3.78 164.81,4.11 v3(164.81,4.87)
CNV_WR_DP1: length 79.7
  TOP w0.102: 148.23,19.87 149.61,19.87 150.17,19.31 150.17,19.17 149.77,18.77 149.77,18.46 150.18,18.06 150.49,18.06 150.89,18.45 151.03,18.45 151.32,18.16 151.32,18.02 150.94,17.64 150.94,17.33 151.35,16.92 151.66,16.92 152.04,17.3 152.18,17.3 155.61,13.87 158.21,13.87 163.66,8.41 164.68,8.41 165.11,7.98 165.11,7.17 v3(164.98,7.04) ; 148.23,19.87 145.57,19.87 145.45,19.75 NGFFE1.11 ; 148.23,19.87 v1(148.23,19.49) ; v3(189.9,30.15) 190.22,30.47 CPU1.DG44
  L4 w0.114: v3(164.98,7.04) 165.24,6.78 165.24,6.59 165.49,6.34 171.67,6.34 172.46,5.55 179.66,5.55 181.3,7.19 184.39,7.19 185.91,8.7 185.91,10.36 190.37,14.82 190.37,17.88 189.76,18.49 189.76,20.8 189.7,20.86 189.7,22.48 189.02,23.15 188.65,23.15 188.11,23.69 188.11,24.83 188.23,24.95 188.43,24.95 188.67,25.2 188.67,25.78 188.43,26.03 188.23,26.03 188.11,26.14 188.11,29.18 188.9,29.96 189.71,29.96 v3(189.9,30.15)
CNV_WT_CLK_DN: length 78.6
  TOP w0.102: NGFFE1.71 145.54,4.75 145.8,4.5 157.03,4.5 157.13,4.6 157.13,4.82 v3(156.89,5.06) ; v3(189.07,28.2) 189.39,28.52 CPU1.DL42
  L4 w0.114: v3(156.89,5.06) 157.12,4.83 157.12,4.5 157.49,4.13 158.53,4.13 158.64,4.02 158.64,3.26 158.89,3.01 159.47,3.01 159.72,3.26 159.72,4.02 159.83,4.13 160.16,4.13 160.17,4.13 160.33,4.13 161.02,3.44 161.37,3.44 161.78,3.86 161.78,4.21 161.09,4.9 161.09,5.06 161.52,5.49 163.42,5.49 163.67,5.74 163.67,6.2 163.79,6.31 164.18,6.31 164.29,6.2 164.29,5.74 164.54,5.49 166.27,5.49 166.38,5.38 166.38,4.97 166.63,4.73 167.21,4.73 167.46,4.97 167.46,5.38 167.57,5.49 167.97,5.49 168.08,5.38 168.08,4.97 168.33,4.73 168.91,4.73 169.16,4.97 169.16,5.38 169.28,5.49 169.67,5.49 169.78,5.38 169.78,4.97 170.03,4.73 170.62,4.73 170.86,4.97 170.86,5.38 170.98,5.49 171.24,5.49 172.06,4.66 180.07,4.66 181.75,6.34 184.74,6.34 186.76,8.35 186.76,10.01 191.22,14.47 191.22,18.23 190.94,18.51 190.94,18.96 190.67,19.22 190.67,22.4 189.79,23.28 189.79,25.46 189.51,25.74 189.51,26.32 188.64,27.19 188.64,28.13 188.71,28.2 v3(189.07,28.2)
CNV_WT_CLK_DP: length 79
  TOP w0.102: v3(157.6,5.06) 157.33,4.79 157.33,4.51 157.11,4.29 146.31,4.29 ; 146.31,4.29 v1(146.31,3.94) ; 146.31,4.29 145.49,4.29 145.45,4.25 NGFFE1.73 ; v3(189.03,28.85) 189.19,28.85 CPU1.DK42
  L4 w0.114: v3(157.6,5.06) 157.35,4.81 157.35,4.6 157.59,4.36 158.62,4.36 158.87,4.11 158.87,3.35 158.98,3.24 159.38,3.24 159.49,3.35 159.49,4.11 159.74,4.36 160.07,4.36 160.42,4.36 161.11,3.67 161.27,3.67 161.55,3.95 161.55,4.11 160.86,4.8 160.86,5.15 161.43,5.72 163.33,5.72 163.44,5.83 163.44,6.29 163.69,6.54 164.28,6.54 164.52,6.29 164.52,5.83 164.64,5.72 166.36,5.72 166.61,5.47 166.61,5.07 166.72,4.96 167.12,4.96 167.23,5.07 167.23,5.47 167.48,5.72 168.06,5.72 168.31,5.47 168.31,5.07 168.43,4.96 168.82,4.96 168.93,5.07 168.93,5.47 169.18,5.72 169.76,5.72 170.01,5.47 170.01,5.07 170.13,4.96 170.52,4.96 170.63,5.07 170.63,5.47 170.88,5.72 171.33,5.72 172.16,4.89 179.98,4.89 181.65,6.57 184.65,6.57 186.53,8.45 186.53,10.1 190.99,14.56 190.99,18.13 190.71,18.41 190.71,18.86 190.44,19.13 190.44,22.3 189.57,23.18 189.57,25.36 189.28,25.65 189.28,26.23 188.41,27.1 188.41,28.22 v3(189.03,28.85)
CNV_WT_DN0: length 79
  TOP w0.102: CPU1.DV45 191.17,24.93 191.17,23.08 191.28,22.97 191.6,22.97 191.87,23.23 192.02,23.23 192.5,22.75 192.5,18.85 192.44,18.79 192.44,18.47 192.64,18.28 192.64,18.13 192.35,17.84 192.2,17.84 192,18.04 191.69,18.04 190.97,17.32 190.97,16.11 189.86,15 189.86,14.69 190.07,14.48 190.07,14.34 189.78,14.05 189.64,14.05 189.43,14.26 189.12,14.26 188.48,13.62 188.48,13.21 188.7,12.99 189.69,12.99 189.8,12.89 189.8,12.49 189.69,12.38 188.95,12.38 188.73,12.16 188.73,11.54 ; NGFFE1.65 145.46,6.25 145.54,6.17 145.54,6.05 145.64,5.95 146.53,5.95 147.18,5.31 153.61,5.31 154.29,5.99 158.39,5.99 159.29,5.09 159.29,3.74 158.84,3.28 158.84,3.14 159.13,2.85 159.27,2.85 159.62,3.2 159.93,3.2 160.71,2.42 184.4,2.42 186.46,4.47 186.98,4.47 187.87,3.59 188.01,3.59 188.3,3.88 188.3,4.02 187.72,4.6 187.72,4.91 188.06,5.25 188.06,7.82 187.47,8.4 187.47,9.59 188.73,10.85 188.73,11.54 ; v1(188.36,11.54) 188.73,11.54
CNV_WT_DN1: length 79.1
  TOP w0.076: CPU1.DU44 190.3,25.73 190.08,25.52 190.08,25.45 190.16,25.38 190.66,25.38 190.8,25.23 190.8,22.99 190.79,22.98 190.79,22.96
  TOP w0.102: NGFFE1.59 145.15,7.75 145.15,7.76 145.31,7.92 145.45,7.92 145.55,7.82 145.55,7.63 145.73,7.45 146.65,7.45 147.8,6.3 148.45,6.3 148.55,6.4 148.55,6.57 148.77,6.79 149.35,6.79 149.57,6.57 149.57,6.4 149.67,6.3 150.08,6.3 150.18,6.4 150.18,6.57 150.4,6.79 150.97,6.79 151.19,6.57 151.19,6.4 151.3,6.3 151.7,6.3 151.8,6.4 151.8,6.57 152.02,6.79 152.6,6.79 152.82,6.57 152.82,6.4 152.92,6.3 153.38,6.3 153.89,6.81 158.73,6.81 160.2,5.34 160.2,4.08 161.05,3.23 184.07,3.23 186,5.16 186,5.34 186.22,5.56 187.16,5.56 187.24,5.63 187.24,6.09 187.16,6.17 185.37,6.17 185.15,6.39 185.15,6.96 185.37,7.18 186.93,7.18 187.03,7.28 187.03,7.69 186.93,7.79 185.82,7.79 185.6,8.01 185.6,8.59 185.82,8.81 186.54,8.81 186.65,8.91 186.65,9.32 186.54,9.42 186.22,9.42 186,9.64 186,10.33 187.59,11.91 187.59,13.87 189.59,15.88 ; 189.59,15.88 190.16,16.45 190.16,17.66 191.63,19.13 191.63,21.13 190.79,21.98 190.79,22.96 ; 189.59,15.88 v1(189.32,16.14)
CNV_WT_DP0: length 79
  TOP w0.102: CPU1.DU45 191.13,25.67 191.61,25.19 191.61,24.73 191.78,24.56 191.78,24.25 192.12,23.91 192.12,23.42 192.7,22.84 192.7,18.76 192.64,18.7 192.64,18.56 192.84,18.36 192.84,18.05 192.43,17.64 192.12,17.64 191.92,17.84 191.78,17.84 191.18,17.24 191.18,16.03 190.07,14.92 190.07,14.77 190.27,14.57 190.27,14.25 189.87,13.85 189.55,13.85 189.35,14.05 189.2,14.05 188.69,13.54 188.69,13.3 188.79,13.2 189.78,13.2 190,12.98 190,12.4 189.78,12.18 189.03,12.18 188.93,12.08 188.93,10.77 187.67,9.51 187.67,8.49 188.26,7.9 188.26,5.16 187.92,4.83 187.92,4.68 188.5,4.11 188.5,3.79 188.09,3.39 187.78,3.39 186.9,4.27 186.55,4.27 185.77,3.49 ; 185.77,3.49 184.49,2.21 160.63,2.21 159.85,3 159.7,3 159.35,2.65 159.04,2.65 158.64,3.05 158.64,3.37 159.09,3.82 159.09,5.01 158.31,5.79 154.38,5.79 153.69,5.1 147.09,5.1 146.45,5.75 NGFFE1.67 ; 185.77,3.49 v1(186.02,3.23)
CNV_WT_DP1: length 79.1
  TOP w0.076: 190.99,22.96 190.99,22.98 190.98,22.99 190.98,25.32 190.8,25.5 190.78,25.54 190.72,25.65 190.71,25.73 190.63,25.96 CPU1.DT44
  TOP w0.102: 190.99,22.96 190.99,22.06 191.84,21.22 191.84,19.05 190.36,17.58 190.36,16.36 187.79,13.79 187.79,11.83 186.79,10.83 ; v1(187.06,10.56) 186.79,10.83 ; 186.79,10.83 186.2,10.24 186.2,9.72 186.3,9.62 186.63,9.62 186.85,9.4 186.85,8.82 186.63,8.6 185.91,8.6 185.8,8.5 185.8,8.1 185.91,7.99 187.01,7.99 187.23,7.77 187.23,7.2 187.01,6.98 185.46,6.98 185.36,6.88 185.36,6.47 185.46,6.37 187.25,6.37 187.45,6.17 187.45,5.55 187.25,5.35 186.3,5.35 186.2,5.25 186.2,5.08 184.15,3.03 160.97,3.03 160,4 160,5.25 158.65,6.6 153.97,6.6 153.47,6.1 152.84,6.1 152.62,6.32 152.62,6.49 152.52,6.59 152.11,6.59 152.01,6.49 152.01,6.32 151.79,6.1 151.21,6.1 150.99,6.32 150.99,6.49 150.89,6.59 150.48,6.59 150.38,6.49 150.38,6.32 150.16,6.1 149.59,6.1 149.37,6.32 149.37,6.49 149.26,6.59 148.86,6.59 148.76,6.49 148.76,6.32 148.54,6.1 147.72,6.1 146.56,7.25 NGFFE1.61
CNV_WT_RCOMP: length 4.5
  TOP w0.102: v3(192.67,23.63) 192.44,23.86 192.44,24.69 192.27,24.86 192.27,25.24 192.12,25.39 191.82,25.39 191.51,25.71 191.51,25.86 CPU1.DT45
  BOTTOM w0.114: R2102.1 192.38,23.34 v3(192.67,23.63)
CNVI_EN#: length 2.4
  TOP w0.102: CPU1.DL27 181.84,28.17 v3(181.74,28.17)
  BOTTOM w0.102: v3(181.74,28.17) 182.13,27.78 182.13,27 TP2111.1
CODEC_I2C_SCL_DMIC_L: length 31.4
  TOP w0.102: CPU1.DG36 186.9,30.47 v3(187.23,30.14)
  L4 w0.127: v3(188.07,17) 187.41,17.66 187.41,18.24 186.64,19.02 186.64,20.9 187.09,21.35 187.09,22.64 187.1,22.65 187.1,23.04 187.65,23.59 187.65,29.72 v3(187.23,30.14)
  BOTTOM w0.102: v3(188.07,17) 187.82,16.75 187.82,16.29 v1(187.93,16.19) 188.49,16.19 188.9,16.6 190.34,16.6 191.41,17.66 197.59,17.66 198.28,16.97 198.28,16.39 198.48,16.2 RN1914.4 198.84,15.65 199.75,14.74 Q1904.1
CODEC_I2C_SCL_DMIC_R: length 173.9
  TOP w0.102: v3(257.66,79.32) 251.88,79.32 250.82,78.27 233.56,78.27 229.31,74.02 229.31,15.71 225.08,11.48 223.12,11.48 223.11,11.47 222.97,11.47 v3(222.53,11.03) ; v3(226.53,94.52) 226.44,94.61 v1(226.44,95.33) 226.62,95.52 R3004.2
  L3 w0.127: v3(222.53,11.03) 222.53,11.29 221.91,11.9 217.48,11.9 216.35,13.03 214.67,13.03 214.4,13.03 212.14,15.29 210.81,15.29 209.89,14.36 206.56,14.36 205.69,15.23 v3(204.51,15.23)
  BOTTOM w0.102: v3(226.53,94.52) 226.87,94.52 227.17,94.83 228.65,94.83 230.11,96.29 231.09,96.29 233.79,98.99 238.99,98.99 246.18,91.8 255.5,91.8 255.5,91.8 255.75,91.8 257.32,90.23 257.32,79.66 v3(257.66,79.32) ; RN1915.4 201.58,14.01 202.31,14.74 Q1904.6 204.31,14.74 204.51,14.94 v3(204.51,15.23)
CODEC_I2C_SDA_DMIC_L: length 33.4
  TOP w0.102: CPU1.DG34 186.36,29.96 v3(186.36,29.51)
  L4 w0.127: v3(187.35,17.01) 187.04,17.32 187.04,18.14 186.31,18.88 186.31,21.03 186.76,21.49 186.76,22.56 186.86,22.67 186.86,23.22 187.41,23.76 187.41,28.48 186.37,29.52 186.37,29.51 v3(186.36,29.51)
  BOTTOM w0.102: Q1904.4 202.79,17.05 v1(202.42,17.42) 200.32,17.42 199.75,16.85 RN1914.3 198.83,16.85 197.71,17.97 191.28,17.97 190.21,16.9 188.62,16.9 188.52,17.01 188.52,17.23 188.25,17.5 187.73,17.5 187.35,17.12 v3(187.35,17.01)
CODEC_I2C_SDA_DMIC_R: length 177.7
  TOP w0.102: v3(225.73,94.53) 225.35,94.91 R3003.2 ; v3(257.35,78.68) 257.01,79.02 252,79.02 250.95,77.96 233.69,77.96 229.63,73.91 229.63,15.51 225.14,11.02 v3(223.31,11.02)
  L3 w0.127: v3(223.31,11.02) 222.1,12.23 217.62,12.23 216.49,13.36 214.53,13.36 212.18,15.71 210.77,15.71 209.75,14.69 206.69,14.69 205.26,16.13 201.79,16.13 201.16,16.76 v3(201.15,16.76)
  BOTTOM w0.102: v3(257.35,78.68) 257.35,78.96 257.01,79.3 257.01,90.1 255.62,91.49 246.06,91.49 238.87,98.68 233.92,98.68 231.21,95.98 230.23,95.98 228.35,94.1 v1(227.68,94.1) 227.55,93.98 226.28,93.98 v3(225.73,94.53) ; v3(201.15,16.76) 200.91,16.52 Q1904.3 201.59,16.04 201.78,15.85 201.78,14.65 201.45,14.32 199.69,14.32 199.35,14.66 RN1915.3
CPU_C10_GATE#: length 172.8
  TOP w0.102: R24113.2 82.56,29.85 83.19,29.85 v3(83.91,30.57) ; v3(186.18,15.81) 186.97,15.81 187.7,16.54 188.26,16.54 188.52,16.81 188.52,17.19 188.44,17.27 188.44,17.77 188.63,17.96 188.85,17.96 190.62,19.72 190.62,21.29 188.14,23.76 188.14,24.93 188.42,25.21 CPU1.DU40
  L4 w0.127: v3(155.54,27.07) 155.54,27 153.17,24.62 149,24.62 148.33,25.3 145.29,25.3 145.06,25.07 145.06,24.22 144.83,23.98 144.08,23.98 143.96,24.1 129.85,24.1 129.47,24.47 127.44,24.47 127.11,24.14 122.68,24.14 121.1,22.57 118,22.57 117.49,22.05 116.91,22.05 116.28,22.68 107.35,22.68 106.74,23.3 104.72,23.3 104.5,23.51 100.56,23.51 99.31,24.76 99.31,25.17 98.41,26.07 93.05,26.07 92.97,26.16 90.77,26.16 90.06,26.87 87.95,26.87 84.55,30.26 84.21,30.26 v3(83.91,30.57) ; v3(186.18,15.81) 185.98,15.61 185.98,14.94 185.45,14.41 185.05,14.41 181.03,10.39 179.43,10.39 178.93,9.88 175.49,9.88 175.42,9.95 172.02,9.95 171.39,9.33 164.42,9.33 164.16,9.07 163.07,9.07 162.8,8.8 160.56,8.8 159.6,7.83 v3(159.44,7.83)
  BOTTOM w0.102: R4051.2 156.47,46.14 v1(154.62,46.14) 154.23,46.14 153.95,45.87 153.95,40.98 154.45,40.49 154.45,28.64 155.54,27.54 v3(155.54,27.07) 155.54,25.15 156.69,24 156.69,22.54 156.1,21.95 R4034.2 156.1,21.93 156.64,21.4 156.64,18.84 158.98,16.49 158.98,8.29 v3(159.44,7.83) ; v3(186.18,15.81) 185.99,15.62 185.99,14.98 186.18,14.79 R4006.2 186.18,14.31 185.86,13.98 R1712.2 185.17,13.98 U4009.1
CPU_C10_GATE#_EC: length 4.2
  TOP w0.102: R24113.1 82.45,28.88 v1(82.45,27.98) 82.45,27.37 82.61,27.21 82.61,27.17 82.62,27.16 82.62,26.01 82.8,25.84 ECIO1.79
CPU_FAN_CTRL: length 6.2
  BOTTOM w0.102: U2601.4 257.7,2.65 R2602.2 258.98,3.93 260.28,3.93 C2603.1 260.91,5.34 v1(260.54,5.71)
CPU_FAN_CTRL_SIO: length 195.7
  TOP w0.102: ECIO1.8 78.8,7.78 78.55,7.53 78.55,6.73 78.83,6.44 v1(78.83,5.81) 78.83,5.04 78.79,5 78.79,3.79 v3(78.83,3.74) ; v3(195.67,1.7) 195.26,2.11 185.25,2.11 184.74,1.6 159.16,1.6 157.21,3.56 146.98,3.56 145.26,1.84 140.73,1.84 140.61,1.95 140.6,1.95 140.34,2.21 140.34,3.49 139.65,4.18 138.72,4.18 138.26,3.87 137.64,3.25 137.64,2.8 136.94,2.1 136.49,2.1 v3(136.47,2.08)
  L3 w0.127: v3(195.67,1.7) 196.3,2.33 232.48,2.33 233.13,2.99 238.18,2.99 238.2,2.97 244.62,2.97 244.62,2.96 245.67,2.96 245.67,2.97 245.84,2.97 245.84,2.96 246.58,2.96 246.58,2.97 248.29,2.97 248.94,3.62 253.61,3.62 253.93,3.3 254.89,3.3 v3(254.95,3.24)
  L4 w0.127: v3(136.47,2.08) 135.75,1.36 80.16,1.36 78.83,2.68 v3(78.83,3.74)
  BOTTOM w0.102: v3(254.95,3.24) 254.95,2.59 255.65,1.89 257.82,1.89 R2602.1 259.3,3.37 R2603.2
CPU_FAN_TACH_SIO: length 217.2
  TOP w0.102: v3(262.29,13.77) 261.92,14.15 v1(261.24,14.15) R2606.2 260.17,14.16 R2607.1 259.13,13.7 259.12,13.69 C2605.1 259.12,11.93 258.16,10.96 258.16,9.47 257.08,8.38 257.08,7.21 257.28,7 FANC1.2 ; v3(137.56,2.06) 138.15,1.47 140.41,1.47 140.53,1.36 145.46,1.36 147.18,3.08 157.01,3.08 158.96,1.12 184.94,1.12 185.35,1.53 194.14,1.53 194.47,1.2 195.97,1.2 v3(196.44,1.67) ; ECIO1.7 78.4,7.96 77.59,7.16 C2423.1 78.27,5.76 78.27,3.88 v3(78.12,3.73)
  L3 w0.127: v3(196.44,1.67) 196.55,1.78 248.53,1.78 248.82,1.49 256.96,1.49 261.64,6.17 261.64,7.66 262.29,8.31 v3(262.29,13.77)
  L4 w0.127: v3(78.12,3.73) 78.23,3.62 78.23,2.57 79.95,0.85 136.35,0.85 v3(137.56,2.06)
CPU_POPI_RCOMP: length 2.7
  TOP w0.305: CPU1.CJ41 188.91,39.36 v3(189.21,39.07)
  BOTTOM w0.381: R309.2 189.99,38.59 190.01,38.6 v1(190.01,39.22) 189.36,39.22 v3(189.21,39.07)
CPU_SMB_SCL: length 199
  TOP w0.114: v3(176.19,11.52) 176.19,9.58 175.93,9.32 175.93,7.57 176.23,7.27 RN1811.1 175.89,6.92 175.36,7.45 173.32,7.45 173.05,7.73 Q1801.3 ; R6103.1 132.42,7.74 132.27,7.88 v3(132.25,7.88) ; v3(181.73,29.5) 182.05,29.17 182.05,29.17 CPU1.DK27
  L3 w0.127: v3(30.94,10.39) 32.32,9.01 53.43,9.01 56.93,12.5 61.88,12.5 62.66,11.72 63.42,11.72 63.56,11.58 63.58,11.58 63.65,11.51 63.67,11.51 63.87,11.31 68.02,11.31 68.78,10.55 72.96,10.55 74.32,9.19 78.8,9.19 79.15,9.54 89.42,9.54 90.34,10.46 92.6,10.46 93.21,9.85 97.25,9.85 99.22,7.87 101.25,7.87 102.01,8.63 104.64,8.63 106.13,7.14 115.08,7.14 117.27,9.33 124.78,9.33 125.91,8.2 131.96,8.2 132.27,7.88 ; v3(132.25,7.88) 132.27,7.88 ; 132.27,7.88 134.07,7.88 135.19,9 156.48,9 157.85,10.38 160.66,10.38 162.35,12.07 164.66,12.07 166.07,10.66 168.37,10.66 168.91,11.2 175.87,11.2 v3(176.19,11.52)
  BOTTOM w0.114: v3(176.19,11.52) 176.16,11.55 176.16,12.83 177.72,14.39 177.72,17.96 177.78,18.02 177.78,20.3 178.41,20.93 179.1,20.93 181.03,22.86 181.89,22.86 182.34,23.3 182.34,25.31 181.25,26.4 181.25,29.02 v3(181.73,29.5) ; v3(30.94,10.39) 30.94,11.67 v1(30.71,11.9) 30.25,12.36 30.25,16.83 29.37,17.7 R5608.2
CPU_SMB_SCL_DDR: length 98
  TOP w0.114: DIMM2.253 231.44,10.67 231.26,10.85 v3(231.14,10.85) ; v3(172.58,9.39) 172.58,9.22 172.59,9.21 172.59,7.53 173.05,7.07 Q1801.4 ; DIMM1.253 243.75,10.67 v3(243.33,11.1)
  L3 w0.127: v3(172.58,9.39) 173.01,8.96 175.42,8.96 175.49,9.03 178.88,9.03 180.54,10.69 182.47,10.69 182.77,10.39 189.77,10.39 190.53,11.15 196.3,11.15 197.11,11.96 202.35,11.96 203.12,11.2 207.18,11.2 208.97,9.4 213.39,9.4 214.9,7.89 214.9,7.72 215.64,6.98 217.87,6.98 219.01,5.84 222.78,5.84 223.65,6.71 228.09,6.71 230.9,3.91 v3(231.55,3.91)
  BOTTOM w0.114: v3(231.55,3.91) v1(230.93,4.53) 230.45,5.01 230.45,10.16 v3(231.14,10.85) 232.32,12.03 242.39,12.03 v3(243.33,11.1) ; RN1810.1 173.54,11.11 173.43,11 173.02,11 172.91,10.88 172.91,9.72 v3(172.58,9.39)
CPU_SMB_SCL_P0: length 19.3
  TOP w0.114: CPU1.DK24 181.16,29.17 v3(180.81,28.82)
  BOTTOM w0.114: v3(180.81,28.82) 180.81,28.05 180.3,27.54 180.3,26.33 180.82,25.81 v1(180.82,23.86) 180.82,23.28 178.96,21.42 175.35,21.42 173.14,19.21 RN1812.4
CPU_SMB_SCL_P1: length 16.3
  TOP w0.114: CPU1.DN22 180.17,27.87 v3(179.91,28.13)
  BOTTOM w0.114: RN1812.2 173.05,20.36 174.56,21.86 177.31,21.86 177.8,22.35 178.33,22.35 v1(178.5,22.52) 179.52,23.54 179.52,25.46 179.7,25.64 179.7,27.92 v3(179.91,28.13)
CPU_SMB_SCL_WLAN: length 5.3
  TOP w0.114: R6103.2 133.45,8.2 v1(133.45,8.75) 134,8.75 134.57,8.18 134.57,7.91 134.98,7.5 NGFFE1.60
CPU_SMB_SDA: length 200
  TOP w0.114: v3(181.73,27.52) 181.43,27.22 CPU1.DP24 ; v3(131.4,7.71) 131.42,7.73 131.42,8.2 R6104.1 ; v3(177,11.5) 177,11.04 176.85,10.89 176.85,7.89 176.75,7.79 176.75,6.42 176.6,6.27 RN1811.2 175.62,6.27 175.58,6.23 174.95,6.23 174.73,6.45 Q1801.6
  L3 w0.127: v3(177,11.5) 176.27,10.77 169.09,10.77 168.55,10.22 165.9,10.22 164.48,11.64 162.53,11.64 160.84,9.94 158.03,9.94 156.66,8.57 135.37,8.57 134.21,7.41 131.69,7.41 v3(131.4,7.71) 131.34,7.77 125.73,7.77 124.6,8.9 117.45,8.9 115.25,6.71 105.95,6.71 104.46,8.2 102.19,8.2 101.43,7.44 99.04,7.44 97.07,9.41 93.01,9.41 92.4,10.03 90.55,10.03 89.58,9.05 79.39,9.05 79.1,8.75 74.14,8.75 72.78,10.12 68.48,10.12 67.72,10.87 63.66,10.87 63.24,11.29 62.48,11.29 61.7,12.07 57.1,12.07 53.61,8.57 32.09,8.57 30.39,10.27 v3(30.39,10.88)
  BOTTOM w0.114: v3(181.73,27.52) 181.73,26.32 182.55,25.49 182.55,23.22 181.98,22.64 181.27,22.64 178.2,19.57 178.2,17.83 178.15,17.78 178.15,17.15 178.15,14.21 176.59,12.65 176.59,11.91 v3(177,11.5) ; R5609.2 28.38,21.36 28.92,20.81 28.92,17.56 29.6,16.89 v1(29.6,12.72) 29.6,11.68 v3(30.39,10.88)
CPU_SMB_SDA_DDR: length 109.5
  TOP w0.114: DIMM2.254 241.97,10.42 v3(242.62,11.08) ; Q1801.1 174.76,8.33 174.91,8.48 174.91,9.45 v3(174.89,9.48) ; v3(257.55,10.64) 257.34,10.42 DIMM1.254
  L3 w0.127: v3(232.24,3.75) 232.24,3.88 228.98,7.14 223.48,7.14 222.6,6.27 219.19,6.27 218.05,7.41 215.82,7.41 215.33,7.9 215.33,8.07 213.54,9.86 209.12,9.86 207.35,11.63 203.3,11.63 202.53,12.39 196.93,12.39 196.12,11.58 190.35,11.58 189.59,10.82 182.95,10.82 182.65,11.13 180.36,11.13 178.72,9.48 v3(174.89,9.48)
  BOTTOM w0.114: v3(257.55,10.64) 257.16,11.03 257.16,13.42 256.8,13.77 v1(256.13,13.77) 255.63,13.77 255.28,13.41 252.15,13.41 250.58,11.84 248.55,11.84 247.15,10.45 243.25,10.45 v3(242.62,11.08) 242.08,11.62 232.61,11.62 230.87,9.87 230.87,5.8 232.24,4.42 v3(232.24,3.75) ; RN1810.2 174.19,11.06 174.31,10.95 174.77,10.95 174.89,10.83 v3(174.89,9.48)
CPU_SMB_SDA_P0: length 19.2
  TOP w0.114: CPU1.DJ24 181.09,29.82 v3(180.81,29.53)
  BOTTOM w0.114: RN1812.3 173.2,19.86 174.97,21.64 178.79,21.64 179.2,22.04 179.2,22.91 180.16,23.88 v1(180.16,25.3) 180.16,25.88 180.02,26.02 180.02,27.56 180.4,27.94 180.4,29.13 v3(180.81,29.53)
CPU_SMB_SDA_P1: length 16.6
  TOP w0.114: v3(179.91,28.84) 180.23,28.52 CPU1.DL22
  BOTTOM w0.114: v3(179.91,28.84) 179.49,28.42 179.49,25.73 179.3,25.55 179.3,23.63 178.95,23.28 178.27,23.28 177.3,22.31 174.11,22.31 v1(173.57,21.77) 172.82,21.01 RN1812.1
CPU_SMB_SDA_WLAN: length 3.8
  TOP w0.114: R6104.2 133.89,9.72 v1(134.87,8.74) 135.61,8 NGFFE1.58
CPVDD: length 7.3
  TOP w0.203: U2701.36 27.81,69.44 27.56,69.18 v3(27.56,68.76)
  BOTTOM w0.381: R2721.1 25.5,67.77 R2701.1 v1(26.94,67.8) 27.56,68.43 v3(27.56,68.76) C2701.1 C2714.1
CPVEE: length 5.7
  TOP w0.203: U2701.34 26.9,70.24 v3(26.64,69.98)
  BOTTOM w0.381: v3(26.64,69.98) 26.07,70.55 v1(26.07,71.93) 26.41,72.26 C2704.2
CR_PE_REXT: length 4
  BOTTOM w0.305: U3301.2 37.14,93.11 37.96,92.28 v1(38.14,92.28) 38.92,92.28 39.1,92.46 R3301.2
CR_USB20_CON_N: length 4.9
  BOTTOM w0.102: 36.51,92.27 36.51,93.07 36.64,93.2 U3301.3 ; 36.51,92.27 36.51,91.31 37.11,90.71 37.32,90.71 37.43,90.82 37.43,91.09 37.53,91.19 L3301.2 ; 36.51,92.27 v1(36.87,92.27)
CR_USB20_CON_P: length 4.9
  BOTTOM w0.102: 36.52,91.01 v1(36.26,90.76) ; 36.52,91.01 37.02,90.51 L3301.3 ; 36.52,91.01 36.3,91.23 36.3,93.07 36.14,93.24 U3301.4
CR_USB20_N: length 209.7
  TOP w0.102: CPU1.DP11 174.87,26.89 174.97,26.79 v3(175.36,26.79)
  L4 w0.114: v3(175.36,26.79) 175.18,26.79 175.07,26.68 175.07,26.42 175.18,26.31 175.43,26.31 175.55,26.19 175.55,25.98 175.43,25.87 172.07,25.87 170.96,26.98 160.96,26.98 155.62,21.64 154.47,21.64 153.22,20.39 148.4,20.39 148.11,20.1 136.88,20.1 135.58,21.39 125.63,21.39 124.87,20.63 123.3,20.63 121.9,19.23 114.9,19.23 114.1,20.03 103.12,20.03 102.59,20.55 95.45,20.55 95.2,20.8 93.24,20.8 91.93,19.49 89.34,19.49 88.81,18.95 82.6,18.95 82.01,19.55 72.03,19.55 71.41,18.93 68.79,18.93 67.39,20.34 66.47,20.34 62.8,24 62.8,25.19 62.12,25.87 62.12,26.77 60.96,27.93 60.96,29.79 59.67,31.08 59.67,48.74 56.62,51.79 56.62,66.33 58.02,67.74 58.02,71.73 57.37,72.39 56.06,72.39 51.01,77.43 51.01,78.18 49.26,79.93 49.26,83.99 50.68,85.42 50.68,87.94 50.01,88.61 47.73,88.61 45.55,90.79 43.78,90.79 43.66,90.9 43.66,91.18 43.6,91.25 v3(43.32,91.25)
  BOTTOM w0.102: 41.67,90.97 v1(41.67,91.33) ; 41.67,90.97 42.16,90.97 42.44,90.69 42.87,90.69 43.32,91.13 v3(43.32,91.25) ; 41.67,90.97 39.97,90.97 39.75,91.19 L3301.1
CR_USB20_P: length 209.6
  TOP w0.102: CPU1.DN11 175.04,27.87 v3(175.37,27.53)
  L4 w0.114: v3(43.32,90.48) 43.39,90.56 45.46,90.56 47.64,88.38 49.92,88.38 50.45,87.85 50.45,85.51 49.03,84.09 49.03,79.83 50.78,78.08 50.78,77.34 55.96,72.16 57.27,72.16 57.8,71.63 57.8,67.84 56.39,66.43 56.39,51.69 59.44,48.64 59.44,30.99 60.73,29.69 60.73,27.83 61.89,26.67 61.89,25.78 62.57,25.1 62.57,23.91 66.37,20.11 67.29,20.11 68.7,18.7 71.51,18.7 72.12,19.32 81.91,19.32 82.51,18.73 88.91,18.73 89.44,19.26 92.02,19.26 93.33,20.57 95.1,20.57 95.35,20.32 102.5,20.32 103.02,19.8 114.01,19.8 114.8,19 122,19 123.39,20.4 124.96,20.4 125.73,21.17 135.49,21.17 136.78,19.87 148.2,19.87 148.49,20.16 153.32,20.16 154.56,21.41 155.72,21.41 161.06,26.75 170.87,26.75 171.98,25.64 175.53,25.64 175.78,25.89 175.78,27.13 v3(175.37,27.53)
  BOTTOM w0.102: 40.72,90.76 40,90.76 39.75,90.51 L3301.4 ; 40.72,90.76 v1(40.72,90.4) ; 40.72,90.76 42.08,90.76 42.36,90.48 v3(43.32,90.48)
CSI_RCOMP: length 3
  TOP w0.305: v3(172.24,72.7) 171.53,72.7 CPU1.B4
  BOTTOM w0.381: v3(172.24,72.7) 172.27,72.73 R2103.2 173.9,72.73 v1(174.16,72.47)
D4302_PIN3: length 3.6
  BOTTOM w0.102: D4302.3 76.9,56.58 76.73,56.75 v1(76.73,57.56) 76.73,57.97 76.97,58.2 R4326.2
DBG_PMODE: length 4.7
  TOP w0.102: CPU1.DL15 176.7,28.68 177.48,29.47 177.74,29.47 177.92,29.29 177.92,29.22 178.07,29.06 v3(178.07,28.94)
  BOTTOM w0.102: R1533.1 178.85,30.17 TP9904.1 178.07,29.39 v3(178.07,28.94)
DDR_VTT_CNTL_L1: length 5.8
  TOP w0.102: Q4006.5 199.41,77.52 199.55,77.66 200.36,77.66 v3(200.91,78.22)
  BOTTOM w0.102: v3(200.91,78.22) R4020.2 C4026.1 v1(202.03,80.25)
DDR_VTT_CNTL_L2: length 10.1
  TOP w0.102: v3(197.87,77.8) 197.87,78.32 198.09,78.54 Q4006.3 198.76,79.39 198.87,79.49 199.29,79.49 199.41,79.37 Q4006.2
  BOTTOM w0.102: v3(197.87,77.8) 198.49,77.18 v1(198.97,77.18) 199.34,77.18 201.29,75.23 RN4002.3
DDR_VTT_CNTL_L3: length 4.9
  TOP w0.102: Q4006.6 200.45,76.7 200.9,77.15 v3(201.09,77.15)
  BOTTOM w0.102: v3(201.09,77.15) 201.99,77.15 R4018.1 202.07,76.46 v1(201.63,76.02) 201.78,75.88 RN4002.4
DEVSLP2: length 205.5
  TOP w0.076: 194.39,35.22 194.33,35.27 193.73,35.27 193.63,35.37 193.14,35.37 193.09,35.32 192.75,35.18 192.59,35.02 CPU1.CV48
  TOP w0.102: 194.39,35.22 194.42,35.18 194.88,35.18 195.3,34.76 195.3,34.21 197.6,31.91 197.62,31.91 197.62,31.91 197.64,31.91 199.01,31.91 199.76,31.16 200.66,31.16 200.97,31.16 203.59,28.53 205.03,28.53 206.38,27.18 206.38,24.26 R1605.1 206.76,24.2 207.18,23.78 v3(207.18,23.75) ; v3(79.66,67.67) 79.37,67.96 79.37,70.96 79.39,70.98 79.39,71.3 80.92,72.84 v1(80.92,74.32) 81.19,74.32 81.66,73.85 R6320.1
  L3 w0.127: v3(104.93,23.89) 105.59,23.23 105.79,23.23 107.36,21.66 115.99,21.66 116.61,21.04 118.37,21.04 118.87,21.55 122.21,21.55 122.74,21.01 123.21,21.01 124,20.22 126.03,20.22 126.36,20.56 134.51,20.56 134.77,20.29 134.78,20.29 136.09,18.98 137.16,18.98 138.03,18.11 142.97,18.11 144.33,19.47 155.09,19.47 156.33,20.71 158.5,20.71 161.82,24.03 167.2,24.03 167.6,24.44 175.71,24.44 175.73,24.41 177.44,24.41 177.7,24.67 179.33,24.67 180.15,25.48 187.98,25.48 188.42,25.04 192.81,25.04 193.44,24.42 194.21,24.42 194.86,25.07 205.9,25.07 207.18,23.78 v3(207.18,23.75)
  L4 w0.127: v3(79.66,67.67) 79.24,67.25 79.24,51.75 78.24,50.75 78.24,48.01 78.82,47.43 78.82,37.46 79.34,36.94 79.34,36.34 79.31,36.31 79.71,35.91 79.71,33.4 81.53,31.58 83.81,31.58 87.1,28.29 89.43,28.29 91.18,26.54 93.13,26.54 93.21,26.45 98.57,26.45 99.69,25.33 99.69,24.92 100.59,24.03 104.53,24.03 104.66,23.89 v3(104.93,23.89)
DEVSLP2_CON: length 6.5
  TOP w0.102: R6320.2 v1(83.81,73.01) 84.93,73.01 86.64,71.3 87.36,71.3 87.46,71.4 NGFFM1.38
DISP_RCOMP: length 12.3
  TOP w0.203: CPU1.R2 169.82,65.54 169.21,65.54 169.1,65.66
  TOP w0.381: 169.1,65.66 166.63,65.66 v1(166.24,66.05) 163.17,69.13 162.56,69.13 162.44,69.25 160.98,69.25 R401.2
DMIC1_DATA_CON: length 237
  TOP w0.102: U2701.2 35.17,69.84 35.3,69.71 36.42,69.71 v3(36.58,69.56) 36.8,69.77 37.47,69.77 v1(37.71,70.02) ; R3001.1 223.66,96.89 v3(223.96,97.19)
  L3 w0.127: v3(125.08,83.08) 125.08,82.29 117.84,75.05 112.63,75.05 104.17,83.51 75.14,83.51 72.72,85.94 72.72,89.76 69.56,92.92 67.1,92.92 63.9,96.12 55.98,96.12 53.65,93.79 51.79,93.79 46.31,88.31 44.52,88.31 43.22,87.01 39.86,87.01 38.56,85.71 38.56,83.47 39.82,82.22 39.82,77.75 37.46,75.4 37.46,71.91 36.3,70.74 36.3,69.84 v3(36.58,69.56)
  L4 w0.127: v3(125.08,83.08) 125.25,83.25 173.59,83.25 175.83,85.48 175.83,89.02 181.23,94.42 182.74,94.42 184.88,96.57 193.12,96.57 194.85,94.83 198.51,94.83 201.34,97.66 223.49,97.66 v3(223.96,97.19)
DMIC_CLK_CON: length 237.2
  TOP w0.102: U2701.3 35.6,70.24 v3(35.64,70.19) ; v3(225.47,97.18) 225.57,97.07 R3002.1
  L3 w0.127: v3(124.24,83.08) 124.24,81.93 117.7,75.39 112.76,75.39 104.31,83.84 92.74,83.84 75.28,83.84 73.05,86.08 73.05,89.9 69.7,93.25 69.42,93.25 67.24,93.25 64.04,96.45 55.84,96.45 53.51,94.12 51.66,94.12 46.17,88.64 44.38,88.64 43.09,87.34 39.72,87.34 38.23,85.85 38.23,83.34 39.49,82.08 39.49,77.89 37.13,75.53 37.13,72.05 35.97,70.88 35.97,70.51 v3(35.64,70.19)
  L4 w0.127: v3(124.24,83.08) 124.73,83.58 173.46,83.58 175.5,85.62 175.5,89.16 181.09,94.75 182.56,94.75 184.71,96.9 193.25,96.9 194.94,95.21 198.42,95.21 201.2,97.99 223.85,97.99 224.67,97.18 v3(225.47,97.18)
  BOTTOM w0.102: v1(34.87,69.79) 35.24,69.79 v3(35.64,70.19)
DMIC_CLK_DMIC1: length 17.8
  TOP w0.102: R3004.1 226.48,96.41 R3002.2 226.46,96.84 226.68,97.06 227.07,97.06 227.54,97.53 ED3002.4 227.51,97.99 226.66,97.99 226.62,97.95 225.93,97.95 225.47,98.41 225.46,98.41 225.43,98.44 224.27,98.44 223.65,98.44 C3009.1 222.4,98.16 v1(221.24,97) 220.77,97.48 215.68,97.48 215.5,97.66 CAM1.3
DMIC_DATA_DMIC1: length 15.7
  TOP w0.102: CAM1.2 214.5,97.67 215.02,97.15 220.06,97.15 C3008.1 220.76,96.45 221.48,96.45 221.53,96.5 221.53,96.5 222.18,97.14 v1(222.71,97.14) 223.22,97.14 224.05,97.97 ED3002.3 224.85,97.96 224.85,96.68 R3001.2 224.55,95.45 R3003.1
DP_REXT: length 6.3
  BOTTOM w0.114: R5606.1 v1(31.46,20.01) 31.46,21.63 32.67,22.83 33.19,22.83 TSMT1.12
DP_VARY_BL_R: length 6.2
  BOTTOM w0.114: TSMT1.21 31.69,26.47 31.13,27.04 30.96,27.04 30.59,27.4 30.06,27.4 R5620.1 29.46,26.97 29.46,27.83 R5601.1 29.56,28.16 v1(30.33,28.93)
E51_RXD: length 6.3
  TOP w0.102: TP4402.1 103.92,12.86 103.92,17.05 103.67,17.3 DBGH1.12
E51_TXD: length 81.3
  TOP w0.102: DBGH1.11 104.79,18.3 105.23,18.74 105.23,21.72 v3(104.15,22.8) ; R24074.2 v3(71.56,24.8)
  L3 w0.127: v3(104.15,22.8) 105.69,22.8 107.2,21.28 115.34,21.28 115.96,20.66 118.52,20.66 118.95,21.08 122.07,21.08 122.52,20.63 123.05,20.63 123.84,19.84 124.63,19.84 125.18,19.3 132.06,19.3 132.59,19.82 v3(134.58,19.82)
  L4 w0.127: v3(104.15,22.8) 103.82,23.13 99.53,23.13 98.9,23.76 96.95,23.76 96.69,24.02 94.89,24.02 94.28,24.63 71.73,24.63 v3(71.56,24.8)
  BOTTOM w0.102: R6141.2 v1(137.33,15.01) 136.63,15.01 135.9,15.74 135.9,18.5 v3(134.58,19.82)
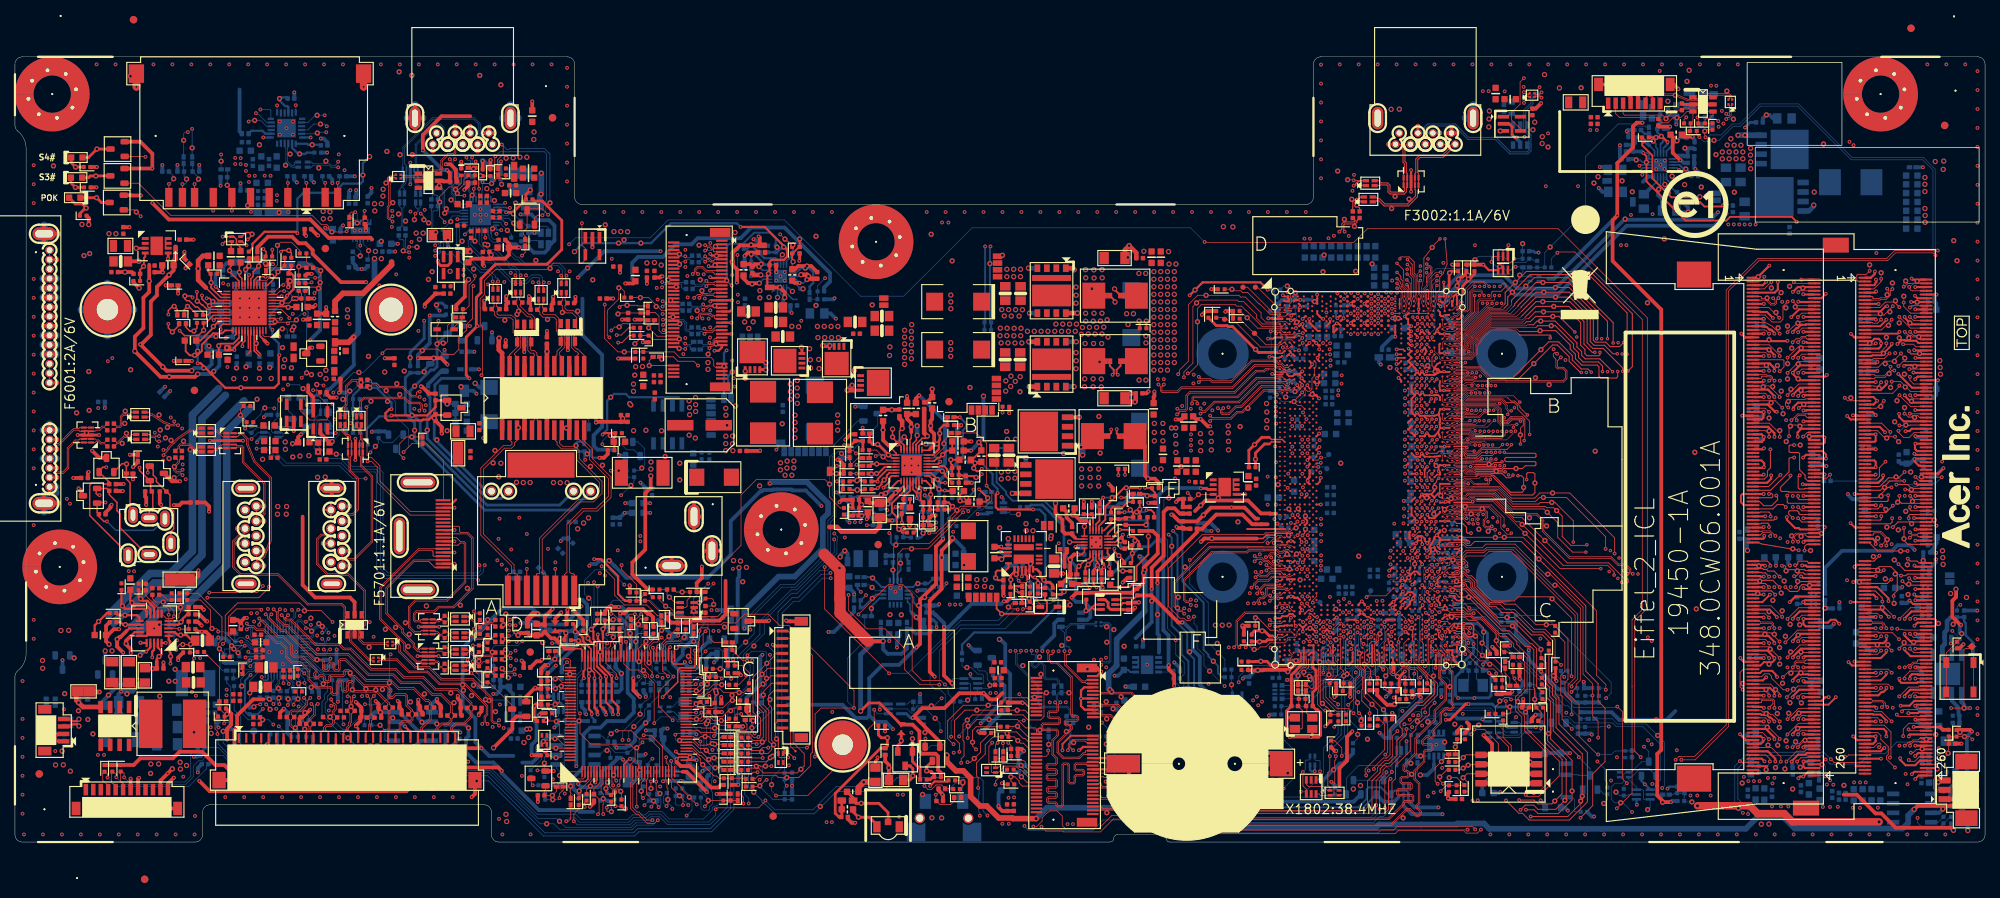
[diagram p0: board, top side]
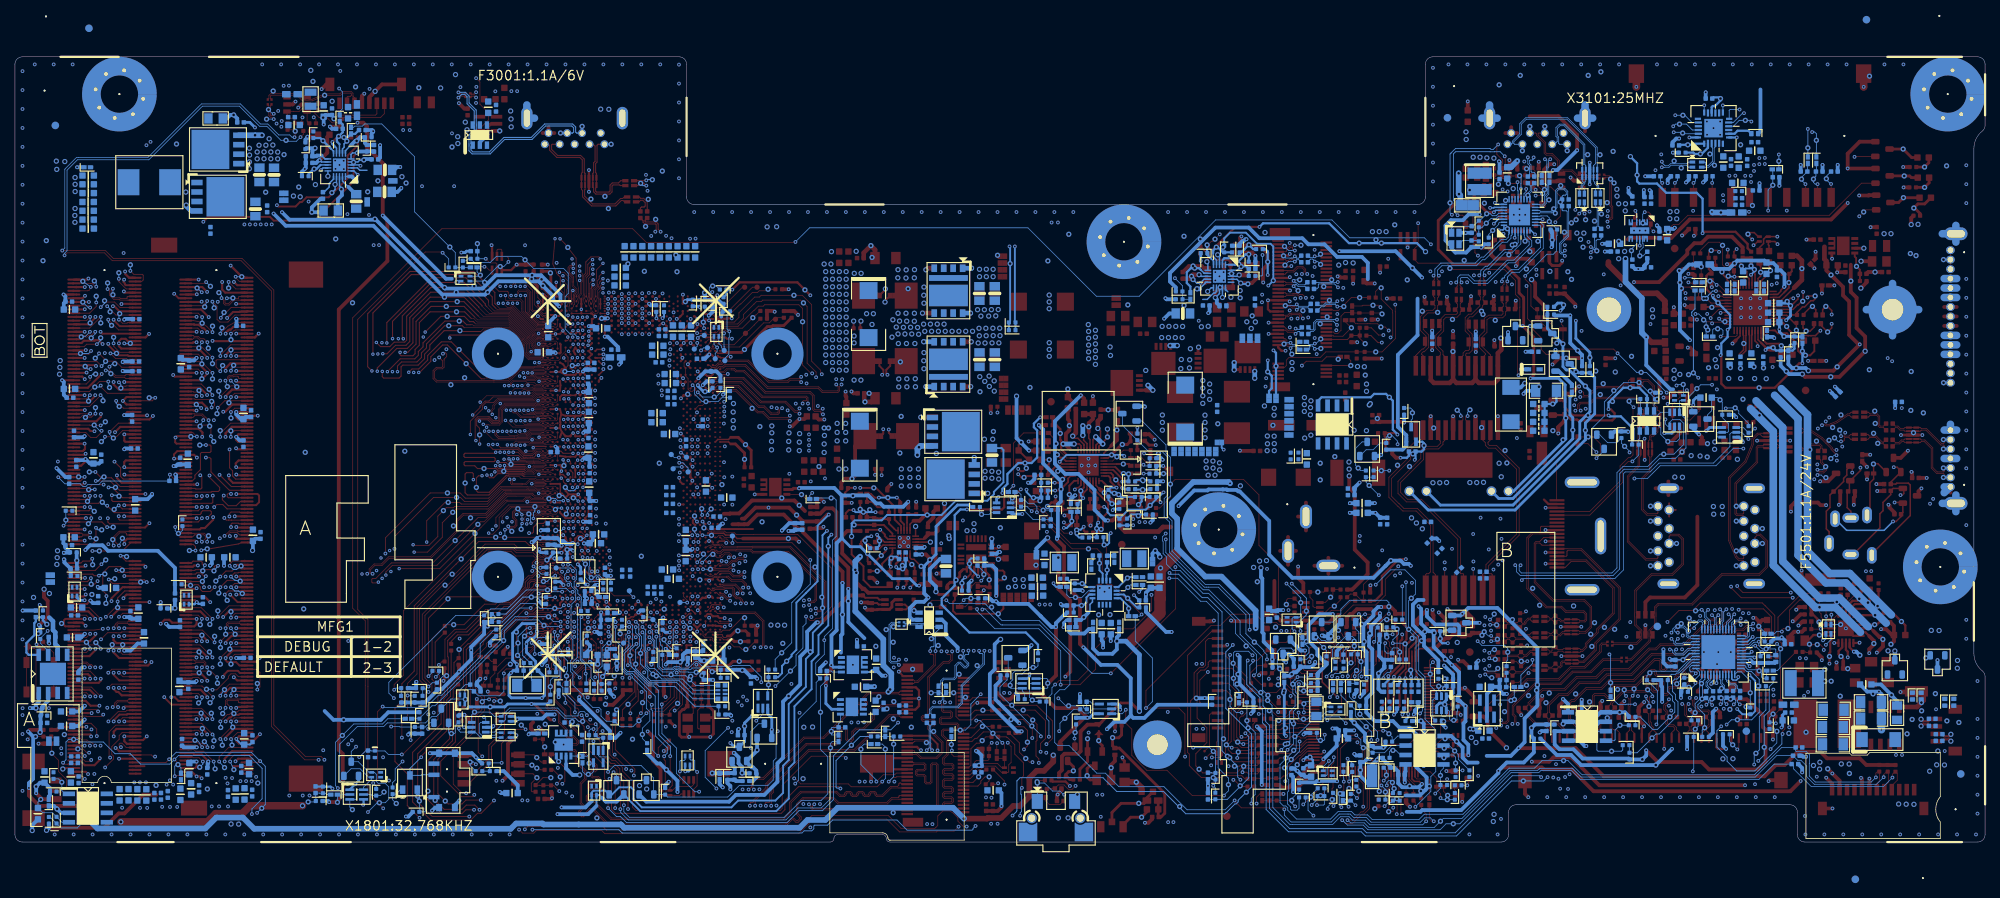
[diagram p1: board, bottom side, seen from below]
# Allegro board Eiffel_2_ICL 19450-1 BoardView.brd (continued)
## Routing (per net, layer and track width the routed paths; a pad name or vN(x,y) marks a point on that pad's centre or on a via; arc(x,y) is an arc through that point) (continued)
E51_TXD_EC: length 4.6
  TOP w0.102: 72.34,24.53 72.34,24.42 72.48,24.27 73.13,24.27 73.46,24.6 74.2,24.6 74.45,24.35 ECIO1.97 ; 72.34,24.53 72.34,25.5 R24074.1 ; 72.34,24.53 v1(72.33,24.53)
E51_TXD_R: length 4.1
  TOP w0.102: NGFFE1.44 138.19,11.5 138.47,11.78 138.47,12.26 v3(138.45,12.26)
  BOTTOM w0.102: R6141.1 v1(138.52,13.09) 138.52,12.9 138.45,12.83 v3(138.45,12.26)
EAPD#: length 6.3
  TOP w0.102: v3(35.43,67.79) 33.41,67.79 33.22,67.98 U2701.47
  BOTTOM w0.102: v3(35.43,67.79) 35.12,68.1 35.12,68.62 35.34,68.83 v1(35.83,68.83) 36.37,68.83 36.49,68.71 R2754.2
EC_AUDIO_MUTE: length 7.1
  TOP w0.102: ECIO1.81 82,26.73 v3(81.89,26.84)
  BOTTOM w0.102: v3(81.89,26.84) 81.69,27.04 81.69,28.47 R24017.1 81.39,29.06 80.62,29.84 v1(80.18,29.84) R24015.1
EC_DTR2#_PH: length 4.5
  TOP w0.102: ECIO1.26 86,8.17 v3(85.93,8.1) 85.93,7.01 v1(86.43,6.5)
  BOTTOM w0.102: R24069.1 85.98,8.61 85.93,8.56 v3(85.93,8.1)
EC_EUP: length 7.8
  TOP w0.102: v3(72.97,5.9) 72.97,6.49 73.46,6.98 R24094.1 73.46,8.54 74.35,9.43 75.99,9.43 ECIO1.1
  BOTTOM w0.102: v3(72.97,5.9) 72.75,5.68 v1(72.06,5.68) R24030.1
EC_EUP_EN: length 3.8
  TOP w0.102: R24094.2 72.58,6.82 v1(72.01,6.26) C2412.2 70.96,6.86 71.1,7.01 Q2402.G
EC_EUP_EN#: length 179.7
  TOP w0.102: Q2402.D 69.2,7.79 v3(69.38,7.61) ; v3(102.55,81.5) v1(103.19,80.85) 103.47,80.57 103.66,80.57 104.14,80.09 R4501.1
  L3 w0.127: v3(39.12,84.65) 39.12,85.45 40.01,86.33 43.18,86.33 44.78,87.93 46.48,87.93 48.25,89.7 51.46,89.7 52.27,90.51 53.31,90.51 55.5,92.69 64.41,92.69 64.62,92.48 64.8,92.48 64.8,92.49 69.05,92.49 72.33,89.2 72.33,86.1 72.33,85.76 75.57,82.52 93.05,82.52 96.82,78.75 ; 96.82,78.75 v3(96.82,78.73) ; 96.82,78.75 96.82,79.35 99.25,81.78 101.43,81.78 101.72,81.5 v3(102.55,81.5)
  L4 w0.127: v3(69.38,7.61) 69.38,8.4 63.57,14.22 62.4,14.22 58.75,17.86 58.75,19.38 55.82,22.31 55.82,26.65 54.83,27.65 54.83,28.81 54.15,29.49 53.21,29.49 49.2,33.49 49.2,48.89 50.95,50.64 50.95,64.56 47.72,67.79 47.72,72.67 49.69,74.64 49.69,75.37 46.13,78.94 44.2,78.94 39.12,84.01 v3(39.12,84.65)
  BOTTOM w0.102: R4502.1 96.92,75.92 96.82,76.02 v3(96.82,78.73) ; R24072.1 v3(69.38,7.61)
EC_SCI#: length 11.3
  TOP w0.102: R2021.2 178.37,17.43 178.27,17.53 177.06,17.53 175.3,19.3 175.3,21.65 v1(176.08,22.43) 176.08,22.44 176.08,23.74 175.6,24.22 175.6,25.36 CPU1.DU14
EC_SMB_SCL: length 90.8
  TOP w0.114: R24119.2 R24118.1 97.54,24.33 v3(98.1,24.33)
  L4 w0.127: v3(50.34,25.16) 51.05,24.45 51.05,20.75 52.3,19.51 52.3,17 59.5,9.8 59.5,8.71 59.49,8.71 v3(59.49,8.7)
  BOTTOM w0.114: R5625.2 v1(50.18,21.37) 50.18,25 v3(50.34,25.16) ; v3(59.49,8.7) 59.68,8.89 63.35,8.89 71,1.24 82.87,1.24 83.43,1.8 93.18,1.8 95.89,4.51 95.89,7.23 95.89,7.24 95.89,15.64 96.4,16.15 96.4,17.92 96.76,18.27 96.76,19.53 98.52,21.3 98.52,23.7 98.1,24.12 98.1,24.31 98.1,24.31 v3(98.1,24.33)
EC_SMB_SCL_OZ: length 99.6
  TOP w0.114: v3(34.04,34.25) 34.04,34.12 32.68,32.77 v3(25.78,32.77) ; ECIO1.63 91.17,22.98 91.59,23.4 91.59,26.9 91.73,27.05 v3(91.73,28.3) 91.73,28.5 91.96,28.73 92.79,28.73 93.07,28.44 93.07,27.35 93.65,26.78 R24119.1
  L3 w0.127: v3(92.9,34.65) 92.74,34.49 83.41,34.49 82.87,35.03 80.58,35.03 80.25,34.69 78.42,34.69 77.69,35.42 76.57,35.42 75.87,34.72 62.95,34.72 62.45,34.22 58.96,34.22 57.13,32.39 41.09,32.39 39.24,34.25 v3(34.04,34.25)
  L4 w0.127: v3(21.72,27.05) 21.55,27.21 21.55,28.77 25.55,32.77 v3(25.78,32.77)
  BOTTOM w0.114: v3(91.73,28.3) 91.73,28.58 92.33,29.18 RN2402.1 91.93,29.48 90.95,30.46 v1(90.95,30.98) 90.95,32.7 v3(92.9,34.65) ; v3(21.72,27.05) 21.51,27.05 21.33,27.24 L5501.2
EC_SMB_SCL_OZ_C: length 8
  TOP w0.114: U5501.6 20.26,30 21.13,30 21.31,30.17 v3(21.31,30.28) 21.31,30.96 20.07,32.19 v1(19.87,32.19) 18.89,32.19 18.42,32.66 C5510.1
  BOTTOM w0.114: L5501.1 21.33,29.65 21.31,29.67 v3(21.31,30.28)
EC_SMB_SCL_TSMT: length 29.7
  L4 w0.127: v3(46.91,18.48) 46.9,18.48 46.9,18.47 45.55,17.12 35.99,17.12 v3(34.63,15.76)
  BOTTOM w0.114: v3(46.91,18.48) 48.1,18.48 48.16,18.43 49.13,18.43 R5625.1 ; v3(34.63,15.76) 33.99,16.4 v1(33.19,16.4) 31.27,16.4 30.26,17.4 R5608.1 30.26,21.82 31.31,22.86 31.94,22.86 32.35,23.27 TSMT1.13
EC_SMB_SDA: length 134.1
  TOP w0.114: v3(42.56,29.51) 41.01,31.06 39.17,31.06 38.17,32.07 29.85,32.07 29.47,31.69 29.46,31.69 28.18,30.41 28.18,26.88 v3(27.88,26.58)
  L3 w0.127: v3(48.07,27.53) 47.78,27.24 44.83,27.24 v3(42.56,29.51)
  L4 w0.127: v3(98.81,24.35) 98.81,25.07 98.31,25.56 v3(92.54,25.56) ; v3(58.62,8.7) 58.62,9.98 51.78,16.83 51.78,19.38 50.62,20.53 50.62,23.85 48.07,26.41 v3(48.07,27.53)
  BOTTOM w0.114: R24120.2 91.06,26.52 90.6,26.07 90.6,25.4 91.02,24.98 91.96,24.98 v3(92.54,25.56) 92.98,26.01 94.4,26.01 94.84,25.57 94.84,23.63 R24117.1 ; v3(98.81,24.35) 98.81,24.25 98.94,24.12 98.94,21.12 97.17,19.36 97.17,18.1 96.82,17.74 96.82,15.98 96.31,15.46 96.31,7.41 96.34,7.38 96.34,4.36 93.35,1.38 83.6,1.38 83.04,0.82 70.83,0.82 63.46,8.19 v1(61.87,8.19) 59.13,8.19 v3(58.62,8.7) ; v3(27.88,26.58) 27.48,26.18 27.48,23.34 27.84,22.99 R5626.2
EC_SMB_SDA_OZ: length 99.7
  TOP w0.114: ECIO1.62 91.55,22.58 92.01,23.04 92.01,26.28 92.22,26.48 92.22,27.95 v3(92.54,28.27) ; v3(26.04,33.45) 32.44,33.45 33.22,34.22 v3(33.22,34.34)
  L3 w0.127: v3(93.61,34.66) 93.56,34.66 93.1,35.12 92.71,35.12 92.51,34.92 83.59,34.92 83.05,35.46 80.4,35.46 80.07,35.12 78.6,35.12 77.87,35.85 76.39,35.85 75.69,35.16 62.77,35.16 62.27,34.66 58.78,34.66 56.95,32.82 41.27,32.82 39.38,34.72 33.6,34.72 v3(33.22,34.34)
  L4 w0.127: v3(21.33,26.45) 21.12,26.66 21.12,28.95 25.62,33.45 v3(26.04,33.45)
  BOTTOM w0.114: v3(93.61,34.66) 93.61,34.66 91.7,32.76 v1(91.7,32.11) 91.7,30.33 91.91,30.13 RN2402.2 92.72,30.13 92.86,29.99 92.86,28.58 v3(92.54,28.27) 91.69,27.41 R24120.1 ; L5501.3 20.65,27.16 21.33,26.47 v3(21.33,26.45)
EC_SMB_SDA_OZ_C: length 8.8
  TOP w0.114: 19.15,31.44 19.18,31.48 20.3,31.48 20.62,31.15 20.62,30.51 v3(20.6,30.48) ; 19.15,31.44 17.53,33.06 C5512.1 ; 19.15,31.44 U5501.7
  BOTTOM w0.114: v3(20.6,30.48) 20.6,29.75 20.65,29.7 L5501.4 v1(19.36,29.17)
EC_SMB_SDA_TSMT: length 5.6
  BOTTOM w0.114: TSMT1.14 32.18,23.67 32.05,23.55 32.05,23.42 31.74,23.11 30.42,23.11 v1(30.27,22.95) 29.97,22.66 29.97,22.15 29.77,21.95 R5609.1 R5626.1
EC_SMI#: length 122.9
  TOP w0.102: R24005.1 79.88,4.68 79.92,4.64 v1(79.92,4.08) 79.41,4.08 79.31,4.18 v3(79.31,4.61) ; CPU1.DT14 175.99,26.39 176.28,26.09 176.28,25.32 176.52,25.08 176.77,25.08 177,24.85 177,24.29 177.23,24.06 177.23,22.35 R2023.2 176.18,21.27 176.18,19.43 176.77,18.83 176.95,18.83 v3(177.32,18.47)
  L3 w0.127: v3(79.31,4.61) 80.06,3.85 84.58,3.85 84.98,4.26 85.53,4.26 85.78,4.51 85.78,4.87 86.49,5.58 93.04,5.58 93.76,4.85 94.09,4.85 95.01,3.93 105.46,3.93 105.94,3.93 106.38,4.38 116.22,4.38 116.36,4.51 116.73,4.51 117.45,5.22 130.09,5.22 130.18,5.31 132.05,5.31 132.62,4.74 134.42,4.74 135.79,6.1 145.18,6.1 145.33,5.95 155.02,5.95 155.38,6.31 171.87,6.31 v3(172.31,6.75)
  BOTTOM w0.102: v3(177.32,18.47) 177.32,18.14 177.3,18.12 177.3,14.55 175.35,12.6 175.35,9.2 172.89,6.75 v3(172.31,6.75)
EC_SMI#_R: length 3.5
  TOP w0.102: ECIO1.9 79.2,8.53 79.19,8.53 v1(79.19,7.17) 79.19,6.77 79.64,6.32 R24005.2
EC_VFSPI: length 7.4
  TOP w0.203: ECIO1.15 81.6,10.43 82.32,11.16 v3(82.43,11.16)
  BOTTOM w0.508: v3(82.43,11.16) 82.78,11.16 83.21,10.73 C2402.1 v1(83.71,9.65) 83.71,8.85 82.75,7.9 R24035.2
ECIO_RSMRST#: length 154
  TOP w0.102: v3(201.38,11.49) 201.92,12.03 201.92,16.76 201.07,17.61 201.07,19.46 202.28,20.67 202.28,24.19 R1709.1
  L3 w0.127: v3(201.38,11.49) 201.37,11.5 197.49,11.5 196.47,10.49 190.54,10.49 190.01,9.96 183.38,9.96 182.72,9.31 181.62,9.31 181.39,9.53 v3(181.39,9.58)
  L4 w0.127: v3(181.39,9.58) 179.7,9.58 179.2,9.08 177.94,9.08 177.8,8.93 176.04,8.93 175.65,8.54 170.58,8.54 170.56,8.56 164.79,8.56 164.53,8.3 163.38,8.3 162.59,7.51 161.21,7.51 160.17,6.47 155.59,6.47 154.85,5.73 143.1,5.73 142.22,6.61 134.46,6.61 134.23,6.84 130.41,6.84 129.56,6 126.61,6 126.5,5.88 122.5,5.88 122.4,5.98 119.83,5.98 119.57,5.72 107.41,5.72 106.81,5.12 101.29,5.12 101.03,5.38 101.03,5.93 100.9,6.05 100.7,6.05 100.49,6.26 100.15,6.26 98.27,8.14 96.31,8.14 95.48,7.31 93.32,7.31 93.07,7.55 92.12,7.55 89.42,10.26 89.42,12.5 89.21,12.71 86.92,12.71 85.87,11.65 85.24,11.65 84.85,11.26 83.86,11.26 v3(81.42,13.7)
  BOTTOM w0.102: v3(81.42,13.7) 81.42,14.8 v1(83.77,17.15) 83.81,17.19 R24014.1 84.47,18.94 84.65,18.94 85.19,19.48 R24037.2
EDP_AUX_CON_N: length 2.7
  BOTTOM w0.102: C5601.2 37.1,20.49 37.1,20.63 37.4,20.92 37.4,21.45 37.04,21.8 37.04,21.88 37.14,21.98 TSMT1.3
EDP_AUX_CON_P: length 2.8
  BOTTOM w0.102: TSMT1.4 36.74,21.98 36.84,21.88 36.84,21.72 37.19,21.36 37.19,21.01 36.44,20.26 C5602.2
EDP_AUX_CPU_N: length 173.7
  TOP w0.102: v3(37.34,18.41) 37.34,18.65 37.89,19.19 v1(37.93,19.19) ; v3(158.64,61.67) 158.9,61.93 160.11,61.93 160.38,61.66 163.03,61.66 165.8,64.43 168.88,64.43 169.27,64.03 169.69,64.03 170.05,63.68 170.31,63.68 170.33,63.66 170.35,63.66 170.35,63.66 170.61,63.66 170.63,63.67 170.65,63.67 170.94,63.96 CPU1.W4
  L3 w0.114: v3(158.64,61.67) 158.34,61.97 157.61,61.97 157.1,61.45 157.1,58.63 157.1,58.63 157.1,49.22 156.83,48.95 156.83,47.66 154.12,44.95 154.12,42.05 151.85,39.78 151.49,39.78 147.63,35.92 143.7,35.92 143.24,36.37 140.93,36.37 140.68,36.62 139.82,36.62 137.56,34.36 133.98,34.36 133.39,33.77 133.39,32.06 132.21,30.88 122.73,30.88 122.35,30.5 113.7,30.5 113.1,31.1 109.87,31.1 109.27,31.7 106.95,31.7 106.54,32.11 92.38,32.11 92.25,31.98 80.86,31.98 80.54,32.3 65.69,32.3 63.82,30.43 63.82,22.18 61.77,20.14 43.31,20.14 39.68,19.96 38.74,19.87 38.08,19.56 37.34,18.82 v3(37.34,18.41)
  BOTTOM w0.102: C5601.1 37.06,18.99 37.06,18.7 v3(37.34,18.41)
EDP_AUX_CPU_P: length 173.5
  TOP w0.102: CPU1.W3 170.4,63.88 170.39,63.88 170.13,63.88 169.77,64.24 169.35,64.24 168.96,64.63 165.72,64.63 162.95,61.86 160.47,61.86 160.19,62.13 158.89,62.13 v3(158.64,62.39) ; v1(36.62,19.18) 36.6,19.16 36.6,18.41 36.57,18.38 v3(36.57,18.37)
  L3 w0.114: v3(158.64,62.39) 158.46,62.2 157.52,62.2 156.87,61.55 156.87,58.53 156.87,58.53 156.87,49.32 156.6,49.05 156.6,47.76 153.89,45.05 153.89,42.14 151.75,40.01 151.4,40.01 147.54,36.15 143.79,36.15 143.33,36.6 141.02,36.6 140.78,36.85 139.73,36.85 137.47,34.58 133.89,34.58 133.17,33.86 133.17,32.16 132.12,31.11 122.63,31.11 122.26,30.73 113.79,30.73 113.2,31.33 109.96,31.33 109.36,31.93 107.05,31.93 106.63,32.34 92.29,32.34 92.16,32.21 80.96,32.21 80.63,32.53 65.6,32.53 63.59,30.53 63.59,22.28 61.68,20.37 43.3,20.37 39.67,20.19 38.68,20.09 37.95,19.75 v3(36.57,18.37)
  BOTTOM w0.102: C5602.1 36.6,19.33 36.85,19.08 36.85,18.65 v3(36.57,18.37)
EDP_BLCTRL_CPU: length 181.5
  TOP w0.102: v3(179.07,25.91) 178.9,25.74 CPU1.DU19 ; v3(27.23,28.22) 27.23,28.43 27.03,28.64 v1(26.41,28.64) 26.22,28.83 26.22,29.4 26.23,29.41 26.23,29.79 26.22,29.8 26.22,31.1 24.85,32.47 R5510.2
  L3 w0.127: v3(27.23,28.22) 28.35,27.11 28.35,22.03 29.29,21.09 29.29,18.82 33.08,15.02 52.91,15.02 54.64,16.76 60.31,16.76 61.69,18.14 64.67,18.14 v3(64.98,18.44)
  L4 w0.127: v3(64.98,18.44) 65.07,18.36 66.33,18.36 68.87,15.81 70.21,15.81 71.14,14.89 78.03,14.89 79.71,16.57 82.56,16.57 82.88,16.89 93.53,16.89 94.94,18.31 102.08,18.31 103,17.39 106.51,17.39 106.99,16.91 112.52,16.91 113.24,16.19 120.88,16.19 121.56,16.88 124.78,16.88 126.22,18.31 134.16,18.31 134.81,17.66 137.62,17.66 138.4,16.88 144.24,16.88 144.81,17.46 148.76,17.46 149.36,18.06 155.5,18.06 161.15,23.71 171.24,23.71 171.84,24.3 177.47,24.3 v3(179.07,25.91)
  BOTTOM w0.102: v3(27.23,28.22) 27.94,28.22 28.22,27.93 R5601.2
EDP_BLEN_CPU: length 167.9
  TOP w0.102: CPU1.DL19 178.31,28.52 v3(178.04,28.25)
  L3 w0.127: v3(163.99,21.43) 160.4,17.84 157.24,17.84 156.2,16.8 149.66,16.8 148.3,15.44 132.62,15.44 131.56,16.5 122.63,16.5 121.97,17.16 117.78,17.16 115.66,15.04 114.43,15.04 113.59,15.88 112.69,15.88 111.63,16.95 102.25,16.95 101.67,16.37 96.17,16.37 95.66,15.86 87.07,15.86 86.53,16.4 77.29,16.4 75.76,14.87 67.43,14.87 66.65,14.09 55.32,14.09 53.05,11.83 29.84,11.83 29.21,12.46 v3(28.74,12.46)
  BOTTOM w0.102: v3(178.04,28.25) 177.58,27.79 177.58,26.91 177.48,26.81 177.48,26.42 177.25,26.19 R1844.2 177.25,23.58 177,23.32 175.87,23.32 175.66,23.53 174.98,23.53 174.77,23.32 173.73,23.32 172.85,24.19 172.52,24.19 171.89,23.57 167.96,23.57 167.86,23.66 165.5,23.66 163.99,22.15 v3(163.99,21.43) ; R5504.1 28.22,15.16 v1(27.91,14.85) 27.91,13.3 v3(28.74,12.46)
EDP_HPD_CPU: length 162.1
  TOP w0.102: CPU1.DW11 174.67,24.15 174.69,24.12 174.69,22.99 174.68,22.98 174.68,22.46 174.69,22.45 174.69,20.25 174.54,20.09 174.54,18.47 175.36,17.64 v3(175.59,17.64)
  L3 w0.127: v3(175.59,17.64) 174.95,17.64 174.91,17.68 168.08,17.68 167.23,16.83 167.23,16.25 163.48,12.5 162.17,12.5 160.48,10.81 157.68,10.81 156.3,9.44 135.01,9.44 134.22,8.65 126.08,8.65 124.96,9.77 117.09,9.77 114.9,7.58 106.56,7.58 104.97,9.17 100.96,9.17 100.61,8.82 98.88,8.82 97.43,10.28 93.42,10.28 92.79,10.9 92.16,10.9 91.58,11.49 90.55,11.49 89.03,9.97 78.77,9.97 78.42,9.62 74.5,9.62 73.14,10.98 68.96,10.98 68.2,11.74 64.05,11.74 63.84,11.94 63.83,11.94 62.71,13.06 56.87,13.06 53.29,9.48 v3(39.16,9.48)
  BOTTOM w0.102: v3(39.16,9.48) 39.16,9.75 39.04,9.87 R5624.1 39.04,14.94 v1(38.83,15.14) 38.46,15.52 R5627.1
EDP_TX_C_N0: length 2.5
  BOTTOM w0.102: TSMT1.8 35.14,21.82 35.24,21.72 35.24,21.32 34.94,21.02 34.94,20.56 C5603.2
EDP_TX_C_N1: length 3.2
  BOTTOM w0.102: TSMT1.10 34.34,21.82 34.44,21.72 34.44,21.64 34.09,21.28 33.55,21.28 33.2,20.94 33.2,20.63 C5605.2
EDP_TX_C_P0: length 2.6
  BOTTOM w0.102: TSMT1.7 35.54,21.82 35.45,21.72 35.45,21.24 35.14,20.94 35.14,20.53 35.42,20.25 C5604.2
EDP_TX_C_P1: length 3.2
  BOTTOM w0.102: C5606.2 33.4,20.62 33.4,20.85 33.63,21.08 34.17,21.08 34.65,21.56 34.65,21.72 34.74,21.82 TSMT1.9
EDP_TX_CPU_N0: length 173.8
  TOP w0.076: CPU1.Y5 171.13,63.22 170.91,63.11 170.46,63.04 170.29,62.96 170.02,62.96 169.94,62.99 169.74,62.99 169.68,62.97 169.66,62.96 169.63,62.95 168.95,62.95 168.57,63.32 167.96,63.32 167.94,63.31 167.93,63.31
  TOP w0.102: 167.93,63.31 167.66,63.31 167.42,63.06 166.34,63.06 163.48,60.2 157.49,60.2 157.11,59.82 157.11,58 156.87,57.76 156.08,57.76 155.98,57.66 155.98,57.41 155.92,57.35 v3(155.73,57.35) ; v1(34.1,19.17) 34.65,18.62 v3(34.65,18.49)
  L3 w0.114: v3(34.65,18.49) 34.95,18.8 34.95,19.03 35.18,19.26 37.17,20.09 37.67,20.58 37.99,20.72 38.67,20.85 40.44,21.03 61.42,21.03 62.7,22.3 62.7,30.55 65.33,33.18 80.9,33.18 81.21,32.88 91.91,32.88 92.02,32.99 106.9,32.99 107.32,32.57 109.63,32.57 110.23,31.97 113.47,31.97 114.06,31.38 121.2,31.38 122.51,32.69 126.98,32.69 127.63,32.04 130.29,32.04 135.82,37.58 141.13,37.58 141.34,37.37 142.99,37.37 143.25,37.63 148.1,37.63 150.99,40.51 150.99,42.08 153.24,44.33 153.24,45.31 155.93,48.01 155.93,49.51 156.22,49.8 156.22,57.4 156.16,57.47 155.85,57.47 v3(155.73,57.35)
  BOTTOM w0.102: v3(34.65,18.49) 34.95,18.8 34.95,19.05 C5603.1
EDP_TX_CPU_N1: length 177.3
  TOP w0.102: CPU1.Y1 169.5,63.51 169.44,63.58 169.06,63.58 168.82,63.82 166.17,63.82 163.19,60.84 156.37,60.84 155.83,60.3 153.71,60.3 153.49,60.52 153.49,61.1 v3(153.23,61.36) ; v1(32.02,18.13) 32.35,18.46 v3(32.87,18.46)
  L3 w0.114: v3(153.23,61.36) 153.47,61.12 153.47,59.89 154.65,58.71 154.65,47.77 152.44,45.55 152.44,44.45 149.87,41.89 149.87,41.88 149.76,41.76 149.76,40.73 147.62,38.6 143.3,38.6 142.72,38.02 141.75,38.02 141.54,38.22 135.56,38.22 130.02,32.69 127.9,32.69 127.25,33.34 122.24,33.34 120.93,32.03 114.33,32.03 113.73,32.62 110.5,32.62 109.9,33.22 107.6,33.22 107.19,33.63 91.75,33.63 91.64,33.53 81.47,33.53 81.17,33.83 65.06,33.83 62,30.77 62,22.52 61.48,22 39.34,22 39.22,22.02 38.39,22.02 38.17,21.93 37.94,21.78 36.91,20.76 33.54,19.36 33.34,19.16 33.34,18.79 33.01,18.46 v3(32.87,18.46)
  BOTTOM w0.102: C5605.1 33.21,18.98 33.21,18.8 v3(32.87,18.46)
EDP_TX_CPU_P0: length 173.5
  TOP w0.076: CPU1.Y3 170.27,63.14 170.25,63.13 170.05,63.13 169.97,63.16 169.68,63.16 169.62,63.13 169.6,63.13 169.02,63.13 168.65,63.5 167.96,63.5 167.94,63.51 167.93,63.51
  TOP w0.102: v3(155.76,58.11) 155.9,57.96 156.78,57.96 156.91,58.09 156.91,59.91 157.4,60.4 163.4,60.4 166.26,63.26 167.33,63.26 167.58,63.51 167.93,63.51 ; v1(35.36,19.32) 35.45,19.23 v3(35.45,18.49)
  L3 w0.114: v3(35.45,18.49) 35.18,18.76 35.18,18.94 35.31,19.07 37.3,19.89 37.8,20.39 38.06,20.5 38.71,20.63 40.45,20.8 61.52,20.8 62.93,22.21 62.93,30.46 65.42,32.95 80.81,32.95 81.11,32.65 92.01,32.65 92.11,32.76 106.81,32.76 107.22,32.34 109.54,32.34 110.14,31.74 113.37,31.74 113.96,31.15 121.29,31.15 122.6,32.46 126.89,32.46 127.54,31.81 130.38,31.81 135.92,37.35 141.03,37.35 141.24,37.14 143.09,37.14 143.35,37.4 148.2,37.4 151.21,40.41 151.21,41.99 153.46,44.24 153.46,45.21 156.16,47.91 156.16,49.42 156.45,49.71 156.45,57.5 156.24,57.71 156.05,57.71 155.76,58 v3(155.76,58.11)
  BOTTOM w0.102: C5604.1 35.47,19.37 35.15,19.05 35.15,18.59 35.26,18.49 v3(35.45,18.49)
EDP_TX_CPU_P1: length 177.3
  TOP w0.102: CPU1.Y2 170.01,63.4 170,63.41 169.96,63.41 169.59,63.78 169.14,63.78 168.9,64.02 166.09,64.02 163.11,61.04 156.29,61.04 155.75,60.5 153.79,60.5 153.69,60.6 153.69,61.07 153.76,61.14 153.76,61.18 v3(153.95,61.36) ; v3(33.67,18.46) 33.94,18.19 33.94,18.04 v1(34.19,17.78)
  L3 w0.114: v3(33.67,18.46) 33.57,18.55 33.57,19.07 33.67,19.17 37.04,20.56 38.09,21.6 38.28,21.73 38.43,21.8 39.2,21.8 39.31,21.77 61.58,21.77 62.23,22.43 62.23,30.68 65.15,33.6 81.08,33.6 81.38,33.3 91.74,33.3 91.85,33.41 107.09,33.41 107.51,32.99 109.81,32.99 110.41,32.39 113.64,32.39 114.23,31.8 121.02,31.8 122.33,33.11 127.15,33.11 127.8,32.46 130.12,32.46 135.65,37.99 141.44,37.99 141.65,37.79 142.82,37.79 143.4,38.37 147.72,38.37 149.99,40.63 149.99,41.67 150.1,41.79 150.1,41.79 152.67,44.36 152.67,45.46 154.88,47.68 154.88,58.81 153.7,59.99 153.7,61.11 v3(153.95,61.36)
  BOTTOM w0.102: v3(33.67,18.46) 33.41,18.71 33.41,19.02 C5606.1
EDP_VDDEN_CPU: length 133.4
  TOP w0.102: v3(178.99,27.46) 178.99,27.46 179.4,27.87 CPU1.DN21
  L3 w0.127: v3(109.52,17.44) 101.51,17.44 100.96,18 87.55,18 86.32,19.23 86.32,19.43 v3(83.55,22.2)
  L4 w0.127: v3(68,26.94) 69.35,25.59 69.35,22.87 69.9,22.32 74.89,22.32 75.37,22.79 83.36,22.79 83.55,22.6 v3(83.55,22.2) ; v3(109.52,17.44) 112.53,17.44 113.34,16.63 118.86,16.63 119.49,17.26 124.63,17.26 126.06,18.69 134.31,18.69 134.89,18.11 137.7,18.11 138.56,17.26 144.08,17.26 144.65,17.84 148.6,17.84 149.2,18.44 155.35,18.44 160.99,24.09 170.76,24.09 171.47,24.8 176.97,24.8 178,25.83 178,26.47 v3(178.99,27.46)
  BOTTOM w0.102: v3(68,26.94) 67.43,26.38 64.37,26.38 63.96,25.97 v1(63.96,25.46) 63.96,24.41 64.12,24.25 R5537.1 ; R1843.2 178.46,26.93 v3(178.99,27.46)
EMMC_RCOMP: length 4.9
  TOP w0.203: v3(183.35,23.12) 182.86,23.61 182.86,24.58 182.85,24.58 182.85,24.93 182.86,24.94 182.86,25.29 182.53,25.62 CPU1.DU28
  BOTTOM w0.508: v3(183.35,23.12) v1(183.35,23.95) 183.35,24.76 R2101.1
ESPI_CON_ALERT#: length 29
  TOP w0.114: DBGH1.1 102.85,28.29 103.6,28.29 106.86,25.03 106.86,12.02 106.63,11.8 106.63,10.25 105.02,8.64 v1(103.43,8.64) 102.31,8.64 102.05,8.9 99.6,8.9 99.17,8.47 R6801.2
ESPI_CPU_CLK: length 120.9
  TOP w0.102: v3(191.6,35.72) 191.6,36.25 192.12,36.77 CPU1.CR47
  L4 w0.127: v3(191.6,35.72) 190.38,35.72 190.25,35.86 188,35.86 186.76,34.62 186.76,33.79 186.16,33.19 184.2,33.19 183.72,32.71 183.72,31.91 183.62,31.81 183.39,31.58 183.39,30.46 182.82,29.89 182.82,23.06 183.55,22.33 183.55,21.62 182.8,20.87 182.8,19.07 183.39,18.49 183.39,16.12 182.32,15.06 182.32,13.69 180.65,12.01 179.2,12.01 178.22,11.03 175.96,11.03 175.74,11.25 171.06,11.25 170.38,10.58 165.45,10.58 164.09,11.94 161.95,11.94 160.16,10.15 158.55,10.15 156.46,8.06 151.91,8.06 151.33,7.48 143.55,7.48 142.65,8.38 133.66,8.38 132.8,9.24 130.65,9.24 129.62,8.21 125.68,8.21 125,8.89 114.98,8.89 113.99,7.9 105.64,7.9 105.38,8.15 103.76,8.15 103.44,7.83 103.44,7.57 v3(103.42,7.56)
  BOTTOM w0.114: v1(193.18,34.95) 192.68,34.95 191.98,35.64 191.68,35.64 v3(191.6,35.72) ; R1804.1 103.15,7.27 103.42,7.54 v3(103.42,7.56) 103.42,7.57 103.13,7.86 R1805.1
ESPI_CPU_CLK_DBG: length 24.2
  TOP w0.114: DBGH1.2 104.07,27.3 104.45,26.92 104.45,24.21 104.47,24.19 104.47,23.7 104.74,23.43 105.23,23.43 105.99,22.67 105.99,19.4 106.45,18.94 106.45,12.99 v3(106.12,12.66)
  BOTTOM w0.114: EC1802.1 103.67,9.3 103.63,9.26 R1805.2 103.13,11.88 v1(103.41,12.16) 103.91,12.66 v3(106.12,12.66)
ESPI_CPU_CLK_EC: length 14.8
  TOP w0.114: v3(99.12,14.58) 98.75,14.95 v1(98.75,15.32) R24034.1
  BOTTOM w0.114: v3(99.12,14.58) 98.67,14.14 98.67,8.58 101.54,5.72 R1804.2 103.16,5.71 EC1801.1
ESPI_CPU_CS#: length 125.1
  TOP w0.102: CPU1.CT45 190.97,35.83 190.82,35.83 190.42,35.43 189.94,35.43 v3(189.93,35.44)
  TOP w0.114: R24085.1 97.34,9.66 R24052.1 97.35,9.33 97.53,9.14 98.71,9.14 98.93,9.36 v3(99.5,9.36)
  L4 w0.127: v3(189.93,35.44) 189.76,35.44 189.32,35 188.32,35 186.19,32.86 184.48,32.86 184.1,32.48 184.1,31.97 183.74,31.6 183.74,30.31 183.1,29.67 183.1,25.58 183.79,24.89 183.79,22.66 184.02,22.44 184.02,20.81 184.02,20.81 184.02,20.42 184.02,20.41 184.02,20.38 183.69,20.05 183.45,20.05 183.27,19.87 183.27,19.3 183.91,18.67 183.91,14.47 183.92,14.46 180.77,11.3 179.27,11.3 178.61,10.65 175.8,10.65 175.68,10.77 171.76,10.77 171.08,10.1 165.39,10.1 163.94,11.55 162.25,11.55 160.29,9.59 158.65,9.59 156.72,7.66 152.12,7.66 151.52,7.07 143.38,7.07 142.45,8 133.5,8 132.77,8.73 130.68,8.73 129.72,7.77 125.57,7.77 124.84,8.51 115.54,8.51 114.53,7.5 106.67,7.5 106.16,6.99 103.57,6.99 103.47,7.09 103.23,7.09 102.95,7.36 102.95,7.6 102.32,8.24 102.27,8.24 101.14,9.36 v3(99.5,9.36)
  BOTTOM w0.114: v3(99.5,9.36) 99.35,10.15 99.35,10.16 v1(99.35,10.16)
ESPI_CPU_CS#_DB: length 25.6
  TOP w0.114: DBGH1.5 103.89,24.3 104.08,24.11 104.08,24.06 104.1,24.04 104.1,23.79 104.1,23.79 104.1,23.55 104.59,23.06 105.08,23.06 105.59,22.55 105.59,16.63 104.28,15.32 104.28,13.33 105.76,11.85 105.76,10.2 v1(105.32,9.76) 104.83,9.27 100.29,9.27 99.65,9.91 98.49,9.91 R24052.2
ESPI_CPU_CS#_EC: length 6.3
  TOP w0.114: R24085.2 94.71,9.95 v1(93.86,9.95) 93.57,9.95 91.9,11.62 91.75,11.62 90.79,12.58 ECIO1.37
ESPI_CPU_IO0: length 124
  TOP w0.114: v3(101.38,10.18) v1(100.57,10.18) 99.9,10.18 99.8,10.28 97.55,10.28 97.36,10.47 R24012.1 97.35,10.77 R24082.1 ; v3(190.55,37.19) 190.77,37.41 CPU1.CN45
  L4 w0.127: v3(101.38,10.18) 101.73,10.18 102.81,9.1 105.06,9.1 105.87,8.29 113.45,8.29 114.44,9.29 125.17,9.29 125.87,8.59 129.15,8.59 130.29,9.73 133.21,9.73 134.04,8.9 156.2,8.9 158.15,10.85 159.9,10.85 161.4,12.34 164.36,12.34 165.63,11.08 169.34,11.08 170.19,11.93 175.78,11.93 176.57,12.72 180.77,12.72 181.76,13.71 181.76,15.07 182.91,16.21 182.91,18.06 182.05,18.91 182.05,20.88 182.74,21.56 182.78,21.56 183.06,21.84 183.06,21.88 183.08,21.9 183.08,22.22 182.42,22.87 182.42,26.96 182.51,27.06 182.51,29.8 181.7,30.62 181.7,31.25 181.7,31.26 181.7,32.15 183.2,33.65 184.95,33.65 185.36,34.06 186.08,34.06 186.38,34.35 186.38,34.71 188.01,36.35 188.64,36.35 189.06,36.76 190.12,36.76 v3(190.55,37.19)
ESPI_CPU_IO0_DB: length 14.2
  TOP w0.114: DBGH1.9 101.66,20.3 100.99,19.63 100.99,18.49 101.39,18.09 101.39,13.64 101.78,13.25 101.78,11.88 v1(101.22,11.32) 100.67,10.76 R24012.2
ESPI_CPU_IO0_EC: length 6
  TOP w0.114: ECIO1.38 90.76,12.98 91.75,11.99 92.05,11.99 92.75,11.29 v1(93.69,11.29) 94.5,11.29 R24082.2
ESPI_CPU_IO1: length 132.1
  TOP w0.114: v3(100.21,11.27) 97.48,11.27 97.36,11.39 R24047.1 97.35,11.89 R24025.1 ; CPU1.CN48 192.85,37.15 193.39,37.15 193.43,37.18 193.76,37.18 194.05,36.89 194.05,36.77 194.34,36.48 194.56,36.48 v3(194.68,36.36)
  L4 w0.127: v3(100.21,11.27) 101.17,11.27 102.97,9.48 105.21,9.48 106.02,8.67 113.29,8.67 114.29,9.67 125.33,9.67 126.03,8.97 128.99,8.97 130.21,10.19 133.29,10.19 133.37,10.11 134.2,9.28 156.04,9.28 157.99,11.23 159.75,11.23 161.24,12.72 164.52,12.72 165.78,11.46 169.18,11.46 170.06,12.34 175.44,12.34 176.2,13.1 180.5,13.1 181.37,13.97 181.37,15.22 182.53,16.37 182.53,17.56 181.67,18.41 181.67,21.07 182.12,21.52 182.12,22.23 181.45,22.89 181.45,25.26 181.76,25.57 181.76,26.74 182.2,27.19 182.2,29.62 180.87,30.96 180.87,31.9 182.97,34.01 184.74,34.01 185.66,34.93 186.08,34.93 187.91,36.75 188.73,36.75 189.59,37.61 190.92,37.61 192.42,36.11 194.43,36.11 194.68,36.36 v3(194.68,36.36)
  BOTTOM w0.114: v3(100.21,11.27) v1(100.07,12.08)
ESPI_CPU_IO1_DB: length 14.7
  TOP w0.114: DBGH1.8 101.4,21.3 100.28,20.18 v1(100.28,19.72) 100.28,18.4 101.02,17.67 101.02,13.49 101.41,13.1 101.41,12.38 100.91,11.88 R24047.2
ESPI_CPU_IO1_EC: length 5.7
  TOP w0.114: ECIO1.39 90.92,13.38 91.76,12.54 92.4,12.54 v1(92.64,12.3) 93.05,11.89 R24025.2
ESPI_CPU_IO2: length 129.9
  TOP w0.102: v3(194.1,37.46) 193.48,37.46 193.43,37.41 CPU1.CN49
  TOP w0.114: R24024.1 97.34,12.99 R24093.1 97.97,12.36 98.6,12.36 98.68,12.28 99.82,12.28 100.19,12.66 v3(100.95,12.66)
  L4 w0.127: v3(194.1,37.46) 194.02,37.38 191.48,37.38 191.02,37.84 189.45,37.84 189.3,37.69 188.42,37.69 188,37.27 186.3,37.27 185.37,36.34 185.37,35.49 184.59,34.71 182.32,34.71 180.03,32.42 180.03,30.52 180.31,30.24 180.81,30.24 181.23,29.82 181.23,25.8 180.95,25.52 180.95,21.92 181.29,21.58 181.29,18.25 182.14,17.4 182.14,16.53 180.99,15.38 180.99,14.13 180.35,13.48 176.04,13.48 175.28,12.72 169.42,12.72 169.11,12.42 167.75,12.42 167.07,13.1 161.08,13.1 159.59,11.61 155.67,11.61 153.72,9.66 134.36,9.66 133.41,10.61 129.96,10.61 128.71,9.35 126.19,9.35 125.49,10.05 114.13,10.05 113.13,9.05 106.38,9.05 104.68,10.74 104.06,10.74 103.94,10.86 103.21,10.86 101.41,12.66 v3(100.95,12.66)
  BOTTOM w0.114: v3(100.95,12.66) v1(101.67,13.04)
ESPI_CPU_IO2_DB: length 14.2
  TOP w0.114: DBGH1.7 101.35,22.3 v1(100.24,21.18) 99.64,20.58 99.64,18.52 100.65,17.51 100.65,13.67 99.64,12.67 98.81,12.67 98.51,12.97 R24093.2
ESPI_CPU_IO2_EC: length 5.5
  TOP w0.114: R24024.2 94.92,13.12 v1(93.77,13.12) 92.82,13.12 92.7,12.99 91.65,12.99 90.86,13.78 ECIO1.40
ESPI_CPU_IO3: length 126.1
  TOP w0.114: v3(189.24,38.22) 190.16,38.22 190.7,37.68 191.12,37.68 191.16,37.72 191.41,37.72 191.73,37.41 CPU1.CN47 ; R24036.1 97.29,14.09 R24092.1 97.37,14.01 97.93,13.45 98.56,13.45 98.77,13.24 99.29,13.24 v3(99.39,13.13)
  L4 w0.127: v3(189.24,38.22) 188.55,38.22 187.99,37.66 186.19,37.66 185.04,36.51 185.04,35.6 184.44,34.99 182.13,34.99 179.7,32.55 179.7,30.41 180.37,29.74 180.37,27.6 180.03,27.26 180.03,24.45 180.52,23.95 180.52,21.81 180.91,21.43 180.91,17.73 181.02,17.62 181.02,16.03 180.61,15.63 180.61,14.29 180.19,13.86 175.88,13.86 175.12,13.1 169.26,13.1 168.97,12.81 167.94,12.81 167.27,13.48 160.92,13.48 159.43,11.99 155.44,11.99 153.48,10.04 134.57,10.04 133.62,10.99 129.8,10.99 128.55,9.73 126.34,9.73 125.65,10.43 113.97,10.43 112.97,9.43 106.92,9.43 103.22,13.13 99.4,13.13 v3(99.39,13.13)
  BOTTOM w0.114: v3(99.39,13.13) 100.14,13.4 100.14,13.41 v1(100.16,13.41)
ESPI_CPU_IO3_DB: length 14.6
  TOP w0.114: R24092.2 98.52,14.01 98.9,13.62 99.85,13.62 100.28,14.06 100.28,17.36 99.27,18.37 99.27,21.66 v1(100.11,22.5) 100.91,23.3 DBGH1.6
ESPI_CPU_IO3_EC: length 5.6
  TOP w0.114: ECIO1.41 90.88,14.18 91.11,13.95 91.7,13.95 91.9,14.15 v1(92.49,14.15) 92.98,14.15 93.38,13.75 94.3,13.75 94.65,14.09 R24036.2
ESPI_CPU_RST#: length 155.4
  TOP w0.114: CPU1.CR46 191.61,36.82 191.88,37.09 192.16,37.09 192.27,37.21 192.27,37.51 192.43,37.67 193.73,37.67 193.93,37.87 194.27,37.87 194.68,37.47 194.68,37.14 v3(194.5,36.97) ; DBGH1.4 101.84,25.3 101.73,25.18 101.73,24.93 v1(100.76,23.97) 98.9,22.11 98.9,17.43 99.43,16.9 99.65,16.9 99.91,16.64 99.91,14.37 v3(99.64,14.1) 99.53,13.99 99.06,13.99 98.55,14.5 96.33,14.5 96.28,14.56 94.03,14.56 93.91,14.68 93.52,14.68 92.76,14.68 92.72,14.72 91.87,14.72 91.6,14.98 ECIO1.43
  L4 w0.127: v3(194.5,36.97) 194.61,37.07 194.61,37.64 194.31,37.93 192.56,37.93 192.03,38.46 191.53,38.46 191.43,38.37 190.37,38.37 190.1,38.64 186.58,38.64 184.63,36.68 184.63,35.59 184.32,35.28 181.88,35.28 179.38,32.77 179.38,29.81 179.46,29.72 179.46,29.38 179.47,29.37 179.47,26.11 179.57,26.01 179.57,24.26 180.12,23.71 180.12,21.68 180.41,21.38 180.41,20.4 180.49,20.32 180.49,19.93 180.41,19.85 180.41,17.69 180.63,17.47 180.63,16.22 180.23,15.82 180.23,14.44 180.03,14.24 175.72,14.24 174.97,13.48 169.1,13.48 168.72,13.86 160.76,13.86 159.27,12.37 155.28,12.37 153.33,10.42 134.84,10.42 133.89,11.37 129.64,11.37 128.39,10.11 126.5,10.11 125.8,10.81 113.81,10.81 112.81,9.81 107.08,9.81 103.33,13.56 100.18,13.56 v3(99.64,14.1)
  BOTTOM w0.114: v3(194.5,36.97) 193.49,35.95 R1818.1
ESPI_EC_ALERT#: length 10.8
  TOP w0.114: ECIO1.36 90.82,12.18 91.83,11.16 91.83,10.71 v1(92.18,10.37) 93.69,8.86 94.03,8.86 94.34,8.55 R24116.1 95,8.56 R24079.1 97.86,8.56 R6801.1 97.94,7.44 R1920.1
ESPI_EC_ALERT#_CPU: length 125.6
  TOP w0.114: R1920.2 99.71,7.44 v1(99.82,7.54) 100.62,8.34 v3(100.73,8.34) ; CPU1.DA49 193.5,33.64 v3(193.81,33.33)
  L4 w0.127: v3(100.73,8.34) 100.73,7.69 101.2,7.22 101.66,7.22 102.81,6.07 103.05,6.07 103.23,5.88 106.49,5.88 107.09,6.48 114.95,6.48 115.96,7.49 120.51,7.49 120.96,7.05 122.89,7.05 123.07,7.23 124.69,7.23 125.15,6.76 129.25,6.76 130.2,7.71 130.74,7.71 130.74,7.72 131.38,8.35 132.61,8.35 133.35,7.62 134.53,7.62 134.78,7.37 142.54,7.37 143.42,6.49 154.48,6.49 155.22,7.23 157.94,7.23 159.11,8.4 159.11,8.73 159.56,9.18 162.64,9.18 162.91,9.45 163.97,9.45 164.23,9.71 171.23,9.71 171.86,10.33 175.58,10.33 175.65,10.27 178.77,10.27 179.43,10.92 180.93,10.92 184.79,14.78 184.79,16.35 185.02,16.59 185.02,18.12 184.51,18.63 184.51,18.96 184.29,19.18 184.29,19.99 184.75,20.45 184.75,22.09 184.24,22.59 184.24,24.87 183.64,25.46 183.64,28.39 184.02,28.76 184.02,31.44 184.33,31.75 184.33,32.39 184.57,32.63 184.97,32.63 185.35,32.25 187.53,32.25 187.93,32.65 187.93,33.18 189.76,35.01 190.12,35.01 190.22,35.11 192.03,35.11 v3(193.81,33.33)
EUP_DSW_SEL: length 3.3
  TOP w0.102: ECIO1.12 80.4,8.42 v3(80.59,8.23)
  BOTTOM w0.102: v3(80.59,8.23) 80.22,8.6 v1(80.22,8.98) 80.22,9.6 R24060.2
EXT_PWR_GATE#: length 2.9
  TOP w0.102: R24022.2 83.78,28.85 83.54,29.08 v1(83.54,29.21) 83.54,29.7 83.78,29.94 R24063.1
EXT_PWR_GATE#_R: length 4.2
  TOP w0.102: ECIO1.78 v1(83.2,26.89) 83.2,27.66 83.49,27.96 R24022.1
FAN5V_OUT: length 3.1
  BOTTOM w0.508: U2601.3 257.85,3.92 v1(258.36,4.43) 258.77,4.84 R2605.1
FAN5V_OUT_CONN: length 7.7
  TOP w0.508: FANC1.1 260.35,5.75 v3(261.15,6.55)
  BOTTOM w0.508: R2605.2 259.47,6.12 259.31,6.27 R2604.2 259.31,7.24 C2604.1 260.64,7.96 v1(261.15,7.45) v3(261.15,6.55)
GPD_7: length 9.1
  TOP w0.127: CPU1.DC47 191.93,32.44 191.61,32.76 v3(191.61,32.81)
  BOTTOM w0.127: R1528.2 198.19,30.57 195.92,32.85 v1(194.8,32.85) 192.84,32.85 R1529.1 192.81,32.81 v3(191.61,32.81)
GPP_A8_SFRM: length 28.3
  TOP w0.114: v3(208.58,22.24) 208.58,30.01 v1(205.98,32.62) 205.71,32.88 201.46,32.88 200.91,32.34 197.88,32.34 195.93,34.29 195.93,34.98 195.2,35.7 194.75,35.7 194.13,36.32 193.48,36.32 193.39,36.4 193.06,36.4 192.8,36.14 CPU1.CT48
  BOTTOM w0.114: v3(208.58,22.24) 208.05,22.77 R1913.2
GPP_A9_CLKREQ0: length 172.7
  TOP w0.114: v3(208.6,17.12) 208.6,18.85 207.71,19.74 207.71,21.41 208.1,21.8 208.1,21.84 208.11,21.85 208.11,27.27 R1912.2 206.22,29.15 v1(205.21,29.15) 203.82,29.15 201.07,31.9 199.6,31.9 199.38,32.12 197.71,32.12 197.7,32.12 197.69,32.12 195.62,34.18 195.62,34.85 195.04,35.43 194.71,35.43 194.05,36.09 193.6,36.09 193.37,35.86 192.22,35.86 CPU1.CT47 ; v3(88.14,16.33) 86.25,18.22 86.25,20.2 v3(88.24,22.2)
  L3 w0.127: v3(179.68,22.75) 179.68,22.85 180.09,23.25 182,23.25 182.42,23.67 184.68,23.67 185,23.34 187.5,23.34 188.14,22.71 192.39,22.71 192.64,22.96 196.52,22.96 197.13,23.58 204.67,23.58 206.04,22.2 206.04,20.12 207.6,18.56 207.8,18.56 208.31,18.05 208.31,17.85 208.6,17.56 v3(208.6,17.12)
  L4 w0.127: v3(88.14,16.33) 94.89,16.33 96.39,17.83 101.94,17.83 102.93,16.84 106.33,16.84 106.69,16.48 112.35,16.48 113.57,15.25 115.74,15.25 116.25,15.76 121.06,15.76 121.74,16.44 124.96,16.44 126.4,17.88 133.98,17.88 134.63,17.23 137.44,17.23 138.22,16.45 144.41,16.45 144.99,17.02 148.94,17.02 149.54,17.63 155.68,17.63 161.33,23.28 174.45,23.28 174.62,23.44 176.03,23.44 176.15,23.32 179.11,23.32 v3(179.68,22.75)
  BOTTOM w0.114: v3(88.24,22.2) 87.15,23.28 R1916.2
GPP_C2/SMBALERT#: length 2.6
  TOP w0.127: CPU1.DL24 181.35,28.52 v3(181.68,28.85)
  BOTTOM w0.127: v1(182.91,27.94) 182.91,28.66 R1532.1 181.75,28.91 v3(181.68,28.85)
GPP_C5: length 19.3
  TOP w0.127: CPU1.DP22 180.36,26.93 v3(180.71,26.57)
  BOTTOM w0.127: v3(180.71,26.57) 181.58,25.71 v1(181.58,24.99) 181.58,24.11 181.45,23.98 181.45,23.59 179.05,21.2 178.02,21.2 177.68,20.86 175.57,20.86 172.91,18.21 R1501.2 169.69,18.17 169.69,17.11 R1502.1
GPP_E6_JTAG_ODT: length 10.8
  TOP w0.127: CPU1.DT12 175.03,25.77 175.03,24.2 174.91,24.08 174.91,22.9 174.9,22.89 174.9,22.55 174.91,22.54 174.91,18.89 v1(175.2,18.59) 175.68,18.11 175.79,18.11 176.27,17.62 R1512.1 176.28,17.07 R1504.2
GPP_H0: length 204.4
  TOP w0.127: R6309.1 82.29,67.92 81.35,66.98 v3(80.84,66.98) ; v3(181.85,4.43) 181.85,4.43 181.85,8.22 182.95,9.32 182.95,9.82 183.67,10.54 184.13,10.54 185.19,11.61 185.19,13.63 185.89,14.33 185.89,15.17 185.59,15.47 185.59,16.02 187.89,18.33 188.7,18.33 190.21,19.84 190.21,21.17 189.21,22.17 189.21,22.34 187.46,24.09 187.46,26.24 187.45,26.25 187.45,26.52 187.46,26.53 187.46,26.82 187.28,27.01 187.28,28.77 CPU1.DK38
  L3 w0.127: v3(181.85,4.43) 181.07,3.65 160.44,3.65 159.5,4.59 144.76,4.59 144.39,4.96 136.26,4.96 134.85,3.55 v3(130.32,3.55)
  L4 w0.127: v3(100.8,26.43) 100.73,26.5 100.07,26.5 98.78,27.79 96.06,27.79 95,28.85 90.69,28.85 89.94,29.6 88.14,29.6 87.65,30.09 86.87,30.09 84.29,32.68 81.98,32.68 80.8,33.86 80.8,36.36 80.43,36.72 80.43,37.4 79.91,37.92 79.91,47.95 79.33,48.53 79.33,50.3 80.33,51.3 80.33,66.47 v3(80.84,66.98)
  BOTTOM w0.127: v3(130.32,3.55) 129.8,4.07 129.8,4.12 129.74,4.19 129.74,8.2 129.31,8.63 118.2,8.63 116.35,6.78 110.09,6.78 107.1,3.79 101.89,3.79 101.72,3.96 101.66,3.96 100.51,5.11 100.37,5.11 100.09,5.39 100.09,5.59 v1(98.99,6.69) 98.3,7.38 98.3,14.49 101.74,17.94 101.74,25.49 v3(100.8,26.43)
GPP_H2: length 75.2
  TOP w0.127: v3(188.09,30.17) 187.74,29.82 CPU1.DJ38 ; v3(184.33,8.48) 184.05,8.21 184.05,4.38 183.53,3.85 161.31,3.85 160.82,4.34 160.82,5.59 158.99,7.43 153.63,7.43 v3(153.38,7.18)
  L4 w0.127: v3(184.33,8.48) 184.39,8.48 185.05,9.14 185.05,10.71 189.51,15.17 189.51,17.51 188.9,18.12 188.9,20.37 188.79,20.48 188.79,22.25 188.46,22.58 v3(187.52,22.58)
  BOTTOM w0.127: v3(153.38,7.18) 153.43,7.23 153.85,7.23 153.97,7.36 153.97,10.92 v1(151.91,12.98) 150.73,14.16 R6111.2 ; v3(188.09,30.17) 188.24,30.02 188.24,24.41 187.52,23.7 v3(187.52,22.58) 187.43,22.5 R1519.2
GSPI_MOSI: length 36.8
  TOP w0.102: CPU1.CF48 192.86,40.87 v1(199.57,40.87) 202.08,40.87 211.91,31.03 211.91,22.39 213.18,21.12 v3(213.18,20.41)
  BOTTOM w0.102: R1520.2 212.24,19.62 R1521.1 212.95,20.64 v3(213.18,20.41)
H_CATERR#: length 3.5
  TOP w0.102: CPU1.J4 v3(171.65,68.91)
  BOTTOM w0.102: v3(171.65,68.91) 171.76,69.02 v1(171.76,69.71) 171.76,70.88 171.56,71.09 R312.2
H_RCIN#: length 4.2
  TOP w0.102: v3(88.49,14.39) 88.68,14.58 ECIO1.42
  BOTTOM w0.102: R24111.1 89.54,13.85 89.31,13.62 v1(89.05,13.62) 88.62,13.62 88.49,13.75 v3(88.49,14.39)
HDA_BITCLK_CODEC: length 263.4
  TOP w0.127: U2701.6 35.7,71.44 36.77,70.36 v3(36.77,70.27) ; v3(201.75,4.33) 202.38,4.95 203.51,4.95 204.08,4.38 206.48,4.38 v1(207.69,5.59) 207.87,5.78 207.87,11.08 205.37,13.58 205.37,18.5 R1904.1
  L3 w0.127: v3(57.16,8.49) 57.16,8.62 57.72,9.17 59.91,9.17 60.89,8.19 61.95,8.19 62.37,7.78 63.56,7.78 64.18,7.16 65.68,7.16 71.63,1.21 142.03,1.21 143.64,2.82 158.75,2.82 159.44,2.12 191.96,2.12 193.47,3.63 201.05,3.63 v3(201.75,4.33)
  L4 w0.127: v3(36.77,70.27) 37.26,69.78 37.26,64.19 36.24,63.16 34,63.16 33.4,62.56 33.4,61.71 28.01,56.32 28.01,50.66 27.52,50.17 27.52,33.15 28.56,32.12 39.15,32.12 40.47,30.79 42.48,30.79 43.8,29.47 43.8,28.44 49.05,23.2 49.05,19.76 49.47,19.34 49.47,14.1 55.41,8.15 56.83,8.15 v3(57.16,8.49)
HDA_BITCLK_CPU: length 21.9
  TOP w0.076: CPU1.CY46 191.99,34.15 192.11,34.03 192.36,34.03 192.48,33.99 192.58,33.96 192.62,33.92 192.75,33.87 192.77,33.85 193.03,33.85 193.13,33.89 193.23,33.92 193.58,33.92 193.69,33.81 194.28,33.81 194.44,33.64
  TOP w0.127: 194.44,33.64 199.11,28.97 v1(200.67,28.97) 203.05,26.6 203.27,26.6 203.9,25.96 203.9,20.86 R1904.2
HDA_RST_N_CODEC: length 259.2
  TOP w0.127: v3(201.57,5.63) 203.57,5.63 204.08,5.11 205.95,5.11 v1(206.34,5.5) 207.32,6.48 207.32,11.09 204.98,13.44 204.98,17.81 R1919.1
  L3 w0.127: v3(57.5,10.45) 57.8,10.15 60.01,10.15 61.2,8.95 62.27,8.95 62.69,8.54 63.88,8.54 64.49,7.92 65.99,7.92 71.93,1.98 134.36,1.98 136.57,4.19 139.9,4.19 140.26,3.83 159.18,3.83 160.12,2.89 191.64,2.89 193.15,4.39 200.34,4.39 v3(201.57,5.63)
  L4 w0.127: v3(38.43,62.26) 38.39,62.26 38.16,62.02 36.52,62.02 35.27,60.78 34.08,60.78 29.15,55.85 29.15,34.01 29.79,33.37 39.77,33.37 40.96,32.18 42.99,32.18 44.96,30.21 44.96,28.9 44.98,28.89 44.98,28.89 50.19,23.67 50.19,20.3 50.68,19.81 50.68,14.63 54.86,10.45 v3(57.5,10.45)
  BOTTOM w0.127: R2722.2 38.87,71.5 39.3,71.07 39.3,71.04 39.31,71.03 39.31,70.64 39.3,70.64 39.3,70.62 39.08,70.4 v1(39.08,62.92) v3(38.43,62.26)
HDA_RST_N_CODEC_R: length 5.1
  TOP w0.127: v3(36.06,73.89) 35.51,73.89 35.06,73.44 U2701.11
  BOTTOM w0.127: v3(36.06,73.89) 36.52,73.89 37.08,73.33 37.08,73.28 37.47,72.89 v1(37.7,72.89) 37.98,73.17 R2722.1
HDA_RST_N_CPU: length 24.9
  TOP w0.127: C1904.1 204.51,16.62 204.51,17.38 R1919.2 203.64,18.25 v1(203.64,19.14) 203.64,20.58 203.52,20.7 203.52,25.8 203.11,26.21 202.39,26.21 200.28,28.33 199.28,28.33 194.75,32.86 193.54,32.86 193.07,33.33 192.39,33.33 192.08,33.64 CPU1.DA47
HDA_SDIN0_CODEC: length 5.4
  TOP w0.127: R2718.2 38.39,73.56 C2726.1 37.36,72.89 v1(37.35,72.9) 36.73,72.28 36.06,72.28 36.01,72.24 U2701.8
HDA_SDIN0_CPU: length 299.4
  TOP w0.076: 194.41,34.97 194.37,34.97 194.29,35.04 193.51,35.04 193.39,35.17 193.19,35.17 193,35.09 192.94,35.03 192.94,34.72 192.84,34.63 192.07,34.63 192.06,34.61 191.79,34.61 191.49,34.9 CPU1.CV45
  TOP w0.127: v3(199.81,5.57) 201.52,3.85 202.01,3.85 202.92,2.95 208.29,2.95 210.71,5.37 210.71,12.03 206.9,15.84 206.9,19.36 206.42,19.84 206.42,21.05 205.93,21.54 205.93,24.79 206.01,24.87 206.01,27.03 204.88,28.17 203.44,28.17 200.81,30.79 199.24,30.79 198.46,31.57 197.6,31.57 197.02,32.15 197.02,32.19 195.08,34.12 195.08,34.67 194.79,34.97 194.41,34.97 ; R2718.1 39.05,73.91 39.55,74.41 40.52,74.41 v1(40.69,74.25) 40.69,74.16 v3(40.14,73.61)
  L3 w0.127: v3(55.68,9.09) 55.68,9.49 57.1,10.92 58.45,10.92 58.75,10.62 60.08,10.62 61.36,9.33 62.43,9.33 62.84,8.92 64.04,8.92 64.65,8.3 66.15,8.3 71.08,3.38 76.09,3.38 77.03,2.44 90.82,2.44 91.43,3.04 93.56,3.04 93.81,2.79 104.99,2.79 104.99,2.79 106.41,2.79 107.06,2.79 107.41,3.14 116.98,3.14 117.92,4.08 129.42,4.08 129.85,3.64 129.85,3.35 130.13,3.08 134.92,3.08 136.42,4.57 140.05,4.57 140.42,4.21 159.34,4.21 160.28,3.27 191.49,3.27 194.28,6.07 197.9,6.07 198.4,5.57 v3(199.81,5.57)
  L4 w0.127: v3(40.14,73.61) 38.14,71.62 38.14,63.99 36.55,62.4 36.36,62.4 35.17,61.21 33.98,61.21 28.77,56 28.77,50.34 28.71,50.28 28.71,33.73 29.44,32.99 39.61,32.99 40.81,31.79 42.56,31.79 44.58,29.77 44.58,28.74 49.81,23.51 49.81,20.14 50.3,19.65 50.3,14.47 v3(55.68,9.09)
HDA_SDOUT_CODEC: length 265
  TOP w0.127: U2701.5 35.37,71.04 v3(35.44,70.97) ; v3(202.48,4.32) 203.57,4.32 204.08,3.81 206.8,3.81 208.66,5.67 v1(208.66,6.83) 208.66,10.95 205.75,13.85 205.75,18.89 205.27,19.37 205.27,20.47 R1905.1
  L3 w0.127: v3(202.48,4.32) 201.41,3.25 193.62,3.25 192.12,1.74 159.28,1.74 158.59,2.44 143.8,2.44 142.19,0.83 71.47,0.83 65.52,6.78 64.02,6.78 63.4,7.39 62.21,7.39 61.8,7.81 60.73,7.81 60.36,8.18 58.48,8.18 58.01,8.66 v3(57.86,8.66)
  L4 w0.127: v3(57.86,8.66) 57.86,8.52 57.11,7.76 55.26,7.76 49.09,13.93 49.09,19.18 48.67,19.6 48.67,23.04 43.42,28.28 43.42,29.32 42.37,30.37 40.33,30.37 38.97,31.74 28.2,31.74 26.81,33.12 26.81,50.09 27.63,50.91 27.63,56.48 32.19,61.04 32.19,62.71 36.11,66.63 36.11,70.52 35.67,70.97 v3(35.44,70.97)
HDA_SDOUT_CPU: length 39.2
  TOP w0.076: 194.32,34.03 193.76,34.03 193.7,34.09 193.13,34.09 193.06,34.05 193,34.03 192.81,34.03 192.72,34.07 192.62,34.17 192.49,34.24 CPU1.CY47
  TOP w0.127: 194.32,34.03 194.49,34.03 198.97,29.54 200.91,29.54 204.48,25.97 v1(204.48,25.83) 204.48,24.73 R1518.2 205.17,24.05 205.17,22.6 R1905.2 205.17,21.46 205.17,21.22 205.65,20.74 205.65,19.53 206.13,19.05 206.13,14.92 209.56,11.5 v3(209.56,11.38)
  BOTTOM w0.127: v3(209.56,11.38) 211.07,9.87 Q1901.3 209.57,8.94 209.48,9.02 207.86,9.02 MFG1.2
HDA_SPKR: length 286.3
  TOP w0.127: CPU1.CH47 192.22,40.19 194.13,40.19 194.54,39.78 195.08,39.78 195.59,40.3 201.86,40.3 v1(204.21,37.95) 204.87,37.29 204.87,37.29 210.49,31.67 210.49,22.93 212.15,21.24 212.15,18.89 213.07,17.96 213.07,10.8 211.43,9.15 211.43,4.9 v3(209.78,3.25) ; v3(39.75,75.06) 39.64,74.94 R2778.2
  L3 w0.127: v3(157.41,1.97) 158.02,1.36 192.28,1.36 193.78,2.87 209.4,2.87 v3(209.78,3.25)
  L4 w0.127: v3(39.75,75.06) 41.24,73.57 41.24,69 45.46,64.78 45.46,55.7 48.11,53.06 48.11,51.23 46.14,49.26 46.14,47.15 46.46,46.83 46.46,32.27 52.63,26.1 52.63,21.76 54.52,19.87 54.52,17.01 59.15,12.38 60.42,12.38 62.27,10.52 62.58,10.52 68.96,4.15 73.96,4.15 75.58,5.77 81.07,5.77 83.05,3.79 86.49,3.79 87.38,2.9 107.52,2.9 108.42,3.81 112.66,3.81 113.55,2.92 119.46,2.92 120.62,4.08 121.61,4.08 121.71,3.98 127.29,3.98 127.39,4.08 135.95,4.08 136.58,4.7 141.44,4.7 142.6,3.53 155.84,3.53 v3(157.41,1.97)
HDA_SYNC_CODEC: length 275
  TOP w0.127: v3(35.74,73.21) 35.2,73.21 35.03,73.04 U2701.10 ; R1901.1 205.55,25.68 205.55,21.38 206.03,20.9 206.03,19.68 206.51,19.2 206.51,15.34 210.03,11.83 v1(210.03,6.15) 210.03,5.38 208.07,3.42 v3(203.11,3.42)
  L3 w0.127: v3(203.11,3.42) 203.11,4.59 202.91,4.8 201.41,4.8 200.62,4.01 193.31,4.01 191.8,2.51 159.6,2.51 158.91,3.2 143.48,3.2 141.87,1.59 71.79,1.59 65.83,7.54 64.33,7.54 63.72,8.16 62.53,8.16 62.11,8.57 61.05,8.57 60.07,9.55 57.12,9.55 v3(56.28,8.71)
  L4 w0.127: v3(35.74,73.21) 37.7,71.24 37.7,64.09 36.39,62.78 34.16,62.78 33.78,62.41 33.78,61.55 28.39,56.16 28.39,50.5 27.92,50.03 27.92,33.82 29.25,32.5 39.31,32.5 40.59,31.21 42.6,31.21 44.19,29.63 44.19,28.6 49.43,23.36 49.43,19.93 49.89,19.47 49.89,14.22 55.48,8.62 56.19,8.62 v3(56.28,8.71)
HDA_SYNC_CPU: length 16.1
  TOP w0.127: CPU1.CV49 193.35,34.79 193.82,34.79 193.86,34.84 194.21,34.84 194.48,34.57 194.48,34.36 198.72,30.12 v1(199.93,30.12) 200.87,30.12 203.21,27.78 204.68,27.78 205.54,26.92 R1901.2
HDD_SATA_RX_CMC_N: length 5
  TOP w0.102: EL6002.1 15.63,56.99 15.42,57.21 14.51,57.21 14.32,57.01 14.32,56.14 ; 14.32,56.14 14.32,55.79 14.1,55.57 13.61,55.57 C6006.1 ; 14.32,56.14 v1(14.72,56.14)
HDD_SATA_RX_CMC_P: length 4.9
  TOP w0.102: 14.79,57.41 15.4,57.41 15.63,57.64 EL6002.2 ; 14.79,57.41 v1(14.79,57.79) ; 14.79,57.41 14.43,57.41 14.12,57.1 14.12,55.88 14.02,55.78 13.6,55.78 C6005.1
HDD_SATA_RX_CON_N: length 10.3
  TOP w0.102: C6006.2 12.02,55.58 11.74,55.58 11.41,55.24 10.89,55.24 10.75,55.1 ED6001.4 ED6001.7 8.68,55.1 8.54,55.24 7.93,55.24 5.93,53.24 5.58,53.24 5.47,53.14 5.47,52.81 5.37,52.7 SATA1.S5
  BOTTOM w0.102: SATA1.S5 v1(5.58,52.7)
HDD_SATA_RX_CON_P: length 10.3
  TOP w0.102: C6005.2 12.04,55.78 11.66,55.78 11.32,55.44 10.89,55.44 10.75,55.58 ED6001.5 ED6001.6 8.68,55.58 8.54,55.44 7.84,55.44 5.84,53.44 5.58,53.44 5.47,53.54 5.47,53.87 5.37,53.98 SATA1.S6
  BOTTOM w0.102: SATA1.S6 v1(5.58,53.98)
HDD_SATA_RX_N: length 199.4
  TOP w0.102: CPU1.CK7 172.9,38.93 172.9,39.05 172.64,39.3 v3(172.54,39.3) ; v3(21.85,55.9) 21.8,55.95 21.45,55.95 21.31,55.81 20.87,55.81 20.6,55.92 ; 20.6,55.92 v1(20.43,55.6) ; 20.6,55.92 20.17,56.1 19.83,56.24 18.36,57.22 18.17,57.22 17.94,56.99 EL6002.3
  L3 w0.114: v3(172.54,39.3) 172.54,39.1 172.29,38.84 171.68,38.84 171.36,39.17 167.35,39.17 167.06,39.46 165.82,39.46 161.14,38.53 159.46,37.83 157.22,35.59 156.78,35.59 151.44,30.25 141.91,30.25 141.09,29.43 136.78,29.43 135.89,28.53 134.21,28.53 132.28,26.6 128.93,26.6 128.31,27.22 127.41,27.22 126.83,26.64 122.8,26.64 122.48,26.96 118.08,26.96 117.14,26.02 109.43,26.02 106.94,28.51 99.23,28.51 98.65,27.92 95.98,27.92 95.25,27.2 93.06,27.2 92.96,27.1 90.47,27.1 89.89,26.53 88.43,26.53 88,26.96 84.16,26.96 82.33,26.2 70.46,26.2 69.03,24.77 69.03,22.99 67.93,21.89 67.14,21.57 63.62,20.86 62.5,19.74 57.12,18.67 45.63,17.54 45.1,17.43 42.1,17.14 33.25,17.14 32.22,18.16 31.62,19.27 30.71,23.88 29.78,26.47 29.78,30.58 29.07,34.13 29.07,38.83 28.22,43.12 26.53,47.19 26.53,47.19 24.88,51.18 23.49,53.26 21.82,54.93 21.58,55.52 21.58,55.78 21.7,55.9 v3(21.85,55.9)
HDD_SATA_RX_P: length 199.5
  TOP w0.102: EL6002.4 17.94,57.64 18.17,57.42 18.42,57.42 18.9,57.1 19.11,56.96 ; CPU1.CK6 v3(172.52,38.4) ; 19.11,56.96 19.11,56.96 19.92,56.42 20.91,56.01 21.23,56.01 21.35,56.13 v3(21.35,56.4) ; 19.11,56.96 v1(19.32,57.28)
  L3 w0.114: v3(172.52,38.4) 172.3,38.62 171.59,38.62 171.27,38.94 167.26,38.94 166.96,39.23 165.84,39.23 161.21,38.31 159.59,37.64 157.32,35.36 156.87,35.36 151.53,30.02 142,30.02 141.18,29.2 136.88,29.2 135.98,28.31 134.3,28.31 132.38,26.38 128.84,26.38 128.22,26.99 127.51,26.99 126.92,26.41 122.71,26.41 122.39,26.73 118.17,26.73 117.24,25.79 109.33,25.79 106.85,28.28 99.33,28.28 98.74,27.7 96.07,27.7 95.35,26.97 93.15,26.97 93.05,26.87 90.56,26.87 89.99,26.3 88.34,26.3 87.9,26.73 84.21,26.73 82.37,25.97 70.56,25.97 69.26,24.68 69.26,22.9 68.05,21.69 67.21,21.35 63.73,20.65 62.61,19.53 57.15,18.44 45.67,17.31 45.13,17.21 42.11,16.91 33.15,16.91 32.04,18.02 31.41,19.2 30.49,23.82 29.55,26.44 29.55,30.55 28.84,34.11 28.84,38.8 28,43.05 26.34,47.06 24.68,51.07 23.31,53.11 21.63,54.8 21.35,55.47 v3(21.35,56.4)
HDD_SATA_TX_CMC_N: length 3.9
  TOP w0.102: 14.94,54.44 15.48,54.44 15.7,54.66 EL6001.2 ; 14.94,54.44 14.55,54.44 13.73,53.62 13.61,53.62 C6004.1 ; 14.94,54.44 v1(14.94,54.81)
HDD_SATA_TX_CMC_P: length 3.9
  TOP w0.102: C6003.1 13.63,53.42 13.82,53.42 14.12,53.72 ; 14.12,53.72 v1(14.38,53.46) ; 14.12,53.72 14.64,54.24 15.48,54.24 15.7,54.01 EL6001.1
HDD_SATA_TX_CON_N: length 12.8
  TOP w0.102: C6004.2 12.03,53.59 11.54,53.59 11.21,53.92 10.89,53.92 10.75,54.06 ED6001.2 ED6001.9 8.68,54.06 8.54,53.92 8.07,53.92 7.01,52.86 7.01,50.24 6.4,49.63 5.58,49.63 5.47,49.73 5.47,50.06 5.37,50.16 SATA1.S3
  BOTTOM w0.102: SATA1.S3 v1(5.58,50.16)
HDD_SATA_TX_CON_P: length 12.8
  TOP w0.102: C6003.2 12.06,53.39 11.46,53.39 11.13,53.72 10.89,53.72 10.75,53.58 ED6001.1 ED6001.10 8.68,53.58 8.54,53.72 8.16,53.72 7.21,52.77 7.21,50.16 6.49,49.43 5.58,49.43 5.47,49.33 5.47,49 5.37,48.9 4.64,48.9
  BOTTOM w0.102: 4.64,48.9 v1(5.58,48.9)
HDD_SATA_TX_N: length 196.3
  TOP w0.102: EL6001.4 18.01,54.66 18.24,54.44 18.85,54.44 18.86,54.44 v3(19.31,54.44) ; CPU1.CW2 169.88,34.28 169.14,34.28 169.03,34.39 167.5,34.39 167.03,33.91 167.03,33.87 166.89,33.73 166.89,33.47 167.02,33.33 v3(167.18,33.33)
  L3 w0.114: v3(167.18,33.33) 166.99,33.52 166.99,33.78 167.06,33.86 167.06,34.57 166.74,34.89 165.8,34.89 165.74,34.95 165.04,34.95 163.31,33.22 160.62,33.22 159.06,34.78 156.88,34.78 151.64,29.53 142.3,29.53 141.52,28.75 137.1,28.75 136.18,27.83 134.6,27.83 132.7,25.93 121.57,25.93 121.01,25.37 109.15,25.37 106.66,27.86 99.5,27.86 98.89,27.25 96.22,27.25 95.52,26.55 93.32,26.55 93.23,26.46 90.87,26.46 89.97,25.55 70.73,25.55 69.68,24.5 69.68,22.72 67.8,20.85 64.24,19.38 63.75,19.38 58.98,18.18 46.34,16.94 45.92,16.85 41.91,16.46 32.86,16.46 31.74,17.58 30.88,19.19 30.07,23.25 29.01,26.2 29.01,30.18 28.36,33.48 28.36,38.73 27.57,42.67 24.02,51.24 22.92,52.89 21.89,53.92 20.64,54.44 v3(19.31,54.44)
  BOTTOM w0.102: v1(19.47,55.26) 19.47,55.26 19.47,55.26 19.31,55.09 v3(19.31,54.44)
HDD_SATA_TX_P: length 196.6
  TOP w0.102: v3(166.46,33.33) 166.68,33.55 166.68,33.81 166.83,33.95 166.83,34 167.42,34.59 169.12,34.59 169.23,34.48 169.43,34.48 CPU1.CW1 ; EL6001.3 18.01,54.01 18.23,54.23 18.77,54.23 18.87,54.13 18.87,53.87 19.03,53.72 19.3,53.72 v3(19.31,53.73)
  L3 w0.114: v3(166.46,33.33) 166.76,33.63 166.76,33.88 166.83,33.95 166.83,34.47 166.64,34.66 165.7,34.66 165.65,34.72 165.14,34.72 163.41,32.99 160.53,32.99 158.97,34.55 156.97,34.55 151.73,29.3 142.39,29.3 141.61,28.52 137.19,28.52 136.27,27.6 134.69,27.6 132.79,25.7 121.66,25.7 121.1,25.15 109.05,25.15 106.56,27.63 99.6,27.63 98.98,27.02 96.31,27.02 95.61,26.32 93.42,26.32 93.32,26.23 90.97,26.23 90.07,25.33 70.82,25.33 69.91,24.41 69.91,22.63 67.93,20.66 64.29,19.15 63.78,19.15 59.02,17.96 46.37,16.71 45.96,16.63 41.93,16.23 32.76,16.23 31.56,17.44 30.66,19.11 29.85,23.19 28.79,26.16 28.79,30.15 28.13,33.46 28.13,38.71 27.35,42.61 25.59,46.87 25.59,46.87 23.82,51.13 22.74,52.75 21.76,53.73 20.59,54.21 19.96,54.21 19.84,54.1 19.84,53.71 19.73,53.6 19.44,53.6 v3(19.31,53.73)
  BOTTOM w0.102: v3(19.31,53.73) 19.7,53.73 v1(20.17,54.2)
HDMI1_DDCCLK_CON: length 28.9
  TOP w0.102: HDMI1.15 57.36,43.84 52.97,43.84 48.55,48.26 48.55,50.29 47.8,51.05 v3(47.26,51.05)
  BOTTOM w0.102: Q5701.6 40.95,54.08 41.32,53.71 v1(42.51,53.71) 43.45,54.65 43.45,55.52 44.64,56.71 45.6,56.71 46.27,56.05 ED5703.1 46.27,54.11 46.41,53.96 R5721.1 46.41,51.9 v3(47.26,51.05)
HDMI1_DDCDATA_CON: length 30.2
  TOP w0.102: HDMI1.16 52.98,44.33 48.91,48.4 48.91,50.44 47.79,51.55 47.54,51.55 47.18,51.91 47.18,58.23 v3(47.1,58.31)
  BOTTOM w0.102: Q5701.3 43.49,57.63 44,57.12 46.08,57.12 46.27,57.32 ED5703.6 46.19,57.89 R5722.1 47.6,59.41 47.7,59.31 v1(47.7,59.12) 47.7,58.91 v3(47.1,58.31)
HDMI1_HPD_C: length 7.3
  TOP w0.102: v3(52.07,51.48) 51.56,51.99 51.56,53.42 52.46,54.33 v1(53.18,54.33) R5731.1
  BOTTOM w0.102: v3(52.07,51.48) 51.05,52.5 Q5705.D
HDMI1_HPD_CON: length 30.3
  TOP w0.102: v3(52.08,52.29) 53.22,53.44 R5731.2 55.16,53.44 57.43,51.17 57.43,45.89 HDMI1.19
  BOTTOM w0.102: v3(52.08,52.29) 52.73,52.95 52.73,55.4 51.02,57.12 51.02,59.02 48.4,61.64 v1(46.37,61.64) 44.22,59.49 R5730.1 44.22,58.84 44.36,58.7 ED5703.4
HDMI1_LS_R: length 25.1
  TOP w0.102: v3(61.52,28.59) 61.52,28.31 61.92,27.91 R5709.2 63.06,28.67 R5702.2 ; R5701.2 62.81,26.37 R5707.2 v3(61.36,26.37) ; v3(61.34,24.25) 61.44,24.25 62.11,23.58 R5708.2 62.81,24.21 R5703.2 ; v3(61.17,22.67) 61.38,22.47 61.43,22.47 62.48,21.42 R5706.2 63.53,21.42 66.61,18.33 Q5702.D ; R5710.2 61.77,30.69 v3(61.52,30.94)
  L3 w0.127: v3(61.17,22.67) 61.34,22.83 v3(61.34,24.25) 61.36,24.27 v3(61.36,26.37) 61.52,26.52 v3(61.52,28.59) v3(61.52,30.94)
  BOTTOM w0.102: v3(61.34,24.25) v1(62.15,24.25)
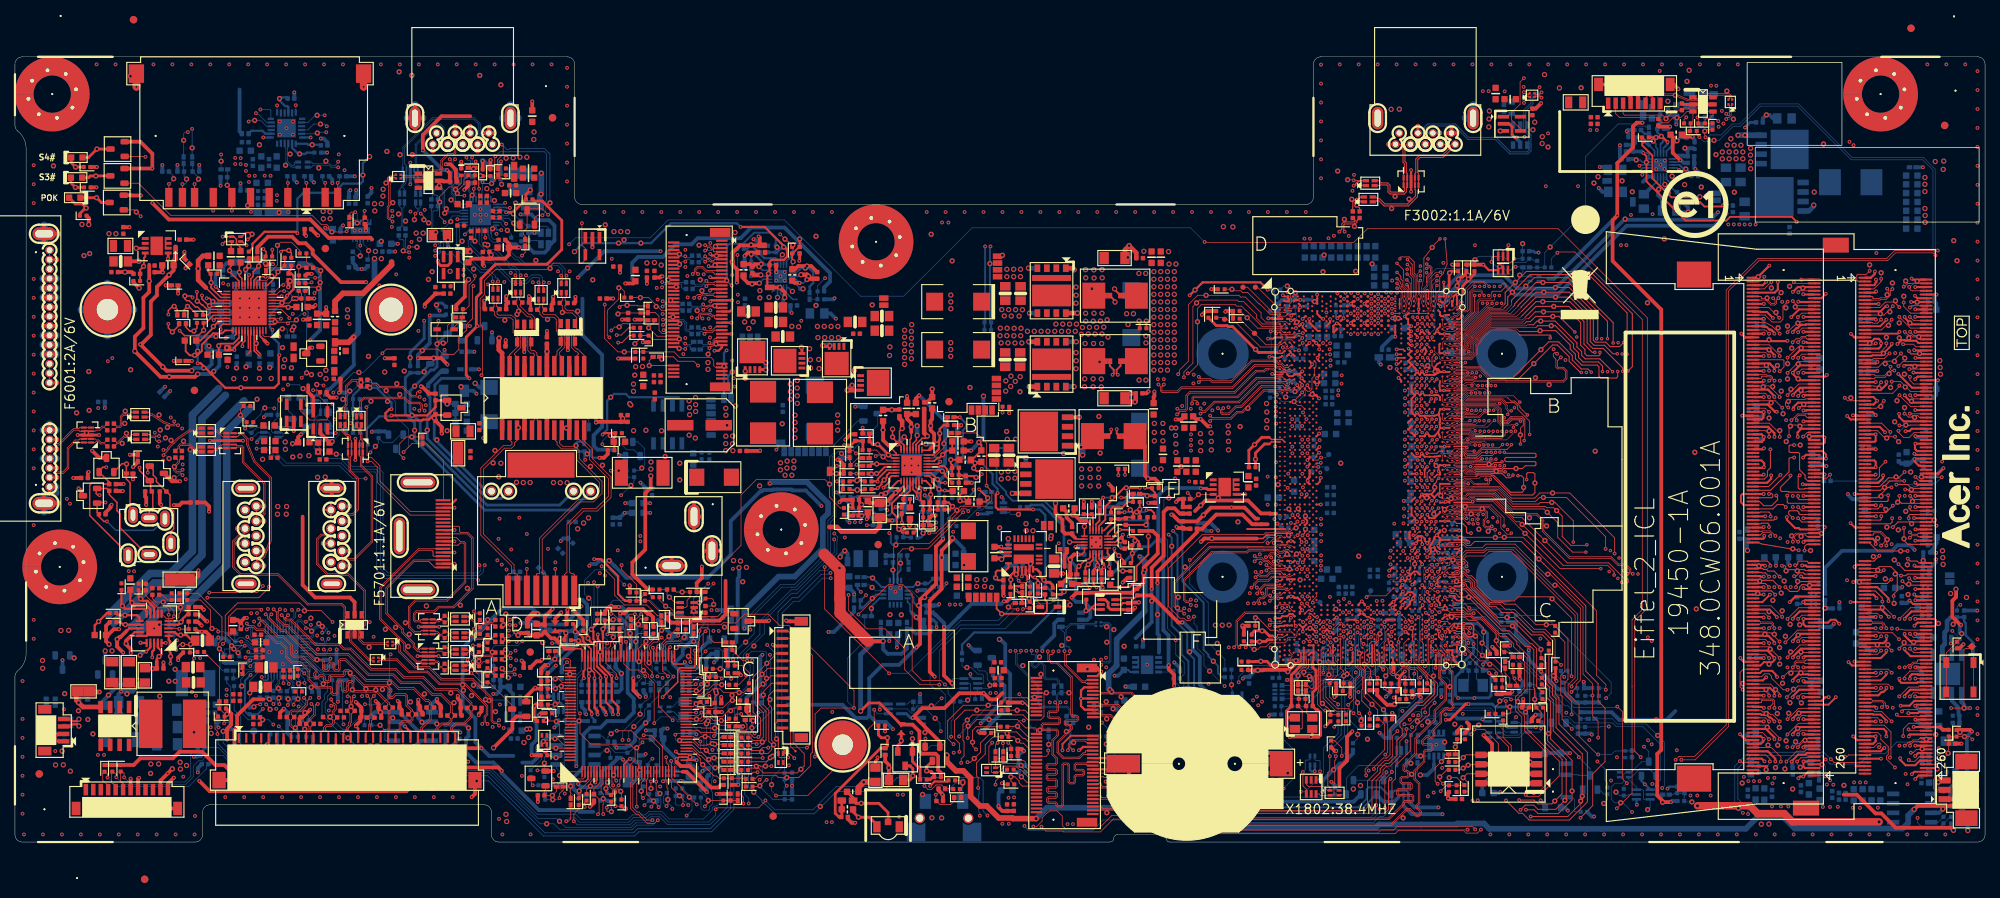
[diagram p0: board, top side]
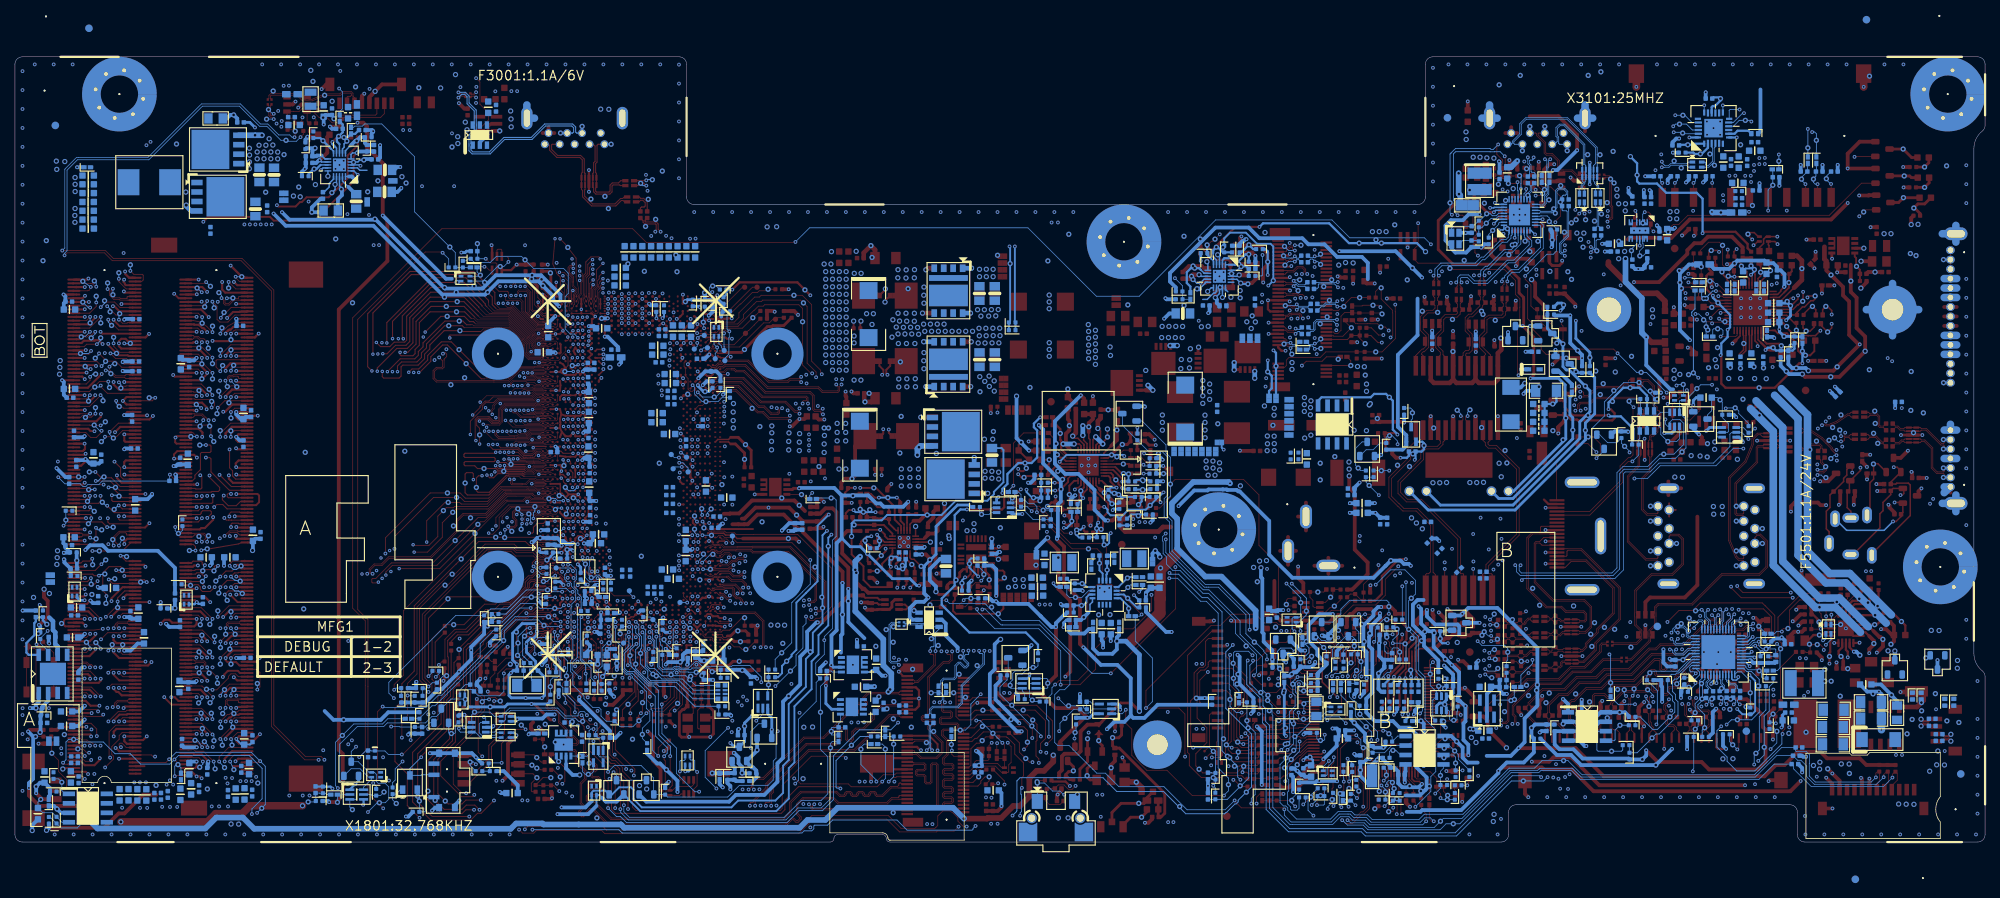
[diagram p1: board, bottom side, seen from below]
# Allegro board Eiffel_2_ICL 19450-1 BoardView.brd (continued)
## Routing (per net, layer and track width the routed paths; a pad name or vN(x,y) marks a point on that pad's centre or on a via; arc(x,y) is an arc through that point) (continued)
HDMI_DDI_TX_CMC_N0: length 4.9
  TOP w0.102: EL5703.1 60.8,28.06 61.03,27.83 61.28,27.83 61.76,27.35 62.9,27.35 R5702.1 63.74,27.37 64.02,27.37 C5702.2
HDMI_DDI_TX_CMC_N1: length 5
  TOP w0.102: EL5702.2 60.8,23.03 61.02,23.25 61.3,23.25 61.89,22.67 62.95,22.67 R5706.1 63.73,22.71 64,22.71 C5704.2
HDMI_DDI_TX_CMC_N2: length 4.9
  TOP w0.102: C5707.2 64.02,24.86 62.57,24.86 R5708.1 61.76,24.88 61.45,24.88 60.88,25.45 60.71,25.45 60.47,25.21 EL5701.2
HDMI_DDI_TX_CMC_N3: length 5.6
  TOP w0.102: EL5704.1 60.69,30.24 60.92,30.02 61.25,30.02 61.72,29.54 61.72,29.4 61.78,29.34 61.99,29.34 62.14,29.49 62.14,29.63 R5710.1 62.66,29.44 63.34,29.44 ; v1(63.34,29.82) 63.34,29.44 ; 63.34,29.44 64.03,29.44 C5709.2
HDMI_DDI_TX_CMC_P0: length 4.9
  TOP w0.102: EL5703.2 60.8,27.4 61.03,27.63 61.19,27.63 61.68,27.14 62.93,27.14 R5701.1 63.74,27.17 64.04,27.17 C5701.2
HDMI_DDI_TX_CMC_P1: length 5
  TOP w0.102: EL5702.1 60.8,23.68 61.02,23.46 61.39,23.46 61.97,22.88 62.87,22.88 R5703.1 63.36,23.32 63.76,22.92 64.11,22.92 C5703.2
HDMI_DDI_TX_CMC_P2: length 4.9
  TOP w0.102: C5705.2 64.02,25.06 62.59,25.06 R5707.1 61.78,25.09 61.53,25.09 60.97,25.65 60.69,25.65 60.49,25.86 EL5701.1
HDMI_DDI_TX_CMC_P3: length 5.1
  TOP w0.102: C5708.2 64.03,29.24 62.75,29.24 R5709.1 62.31,28.87 62.05,29.14 61.7,29.14 61.52,29.31 61.52,29.46 61.16,29.82 60.93,29.82 60.71,29.59 EL5704.2
HDMI_DDI_TX_CON_N0: length 27.1
  TOP w0.102: EL5703.3 58.44,28.06 58.34,27.95 58.11,27.95 57.82,28.24 R5713.2 57.19,27.85 57,27.85 56.65,28.21 56.4,28.21 56.26,28.34 ED5702.2 ED5702.9 54.45,28.34 54.32,28.21 53.6,28.21 52.93,28.88 52.93,31.48 53.76,32.31 57.93,32.31 60.41,34.79 60.41,40.08 60.19,40.3 59.69,40.3 59.15,40.84 57.38,40.84 HDMI1.9
HDMI_DDI_TX_CON_N1: length 29.4
  TOP w0.102: HDMI1.6 54.06,39.33 48.86,34.13 48.86,29.85 49.91,28.8 ; 49.91,28.8 v1(49.64,28.53) ; 49.91,28.8 52.11,26.6 52.11,25.71 53.76,24.06 54.42,24.06 54.54,23.93 ED5701.5 ED5701.6 56.18,23.93 56.31,24.07 56.6,24.07 56.7,23.97 56.7,23.69 56.7,23.57 56.9,23.37 57.24,23.37 R5712.1 57.77,23.23 58.46,23.23 58.67,23.03 EL5702.4
HDMI_DDI_TX_CON_N2: length 25.4
  TOP w0.102: 51.28,29.06 49.7,30.63 49.7,34.11 53.42,37.83 HDMI1.3 ; 51.28,29.06 v1(51.01,28.79) ; 51.28,29.06 51.84,28.49 51.84,28.07 53.37,26.55 53.37,26.12 53.92,25.57 54.16,25.57 54.28,25.46 ED5701.2 ED5701.9 56.47,25.46 56.61,25.59 57.21,25.59 R5711.1 57.73,25.39 58.32,25.39 58.5,25.21 EL5701.4
HDMI_DDI_TX_CON_N3: length 28.3
  TOP w0.102: v1(59.69,31.75) 59.44,32.01 ; 59.44,32.01 61.41,33.98 61.41,40.81 60.69,41.53 59.71,41.53 59.57,41.67 59.57,42.23 59.45,42.35 57.85,42.35 57.83,42.33 HDMI1.12 ; 59.44,32.01 58.84,31.41 56.82,31.41 56.21,30.8 53.84,30.8 53.59,30.55 53.59,29.83 53.69,29.73 54.32,29.73 54.45,29.87 ED5702.6 ED5702.5 56.31,29.87 56.45,29.73 56.76,29.73 57,29.96 57.19,29.96 R5715.2 57.68,30.35 58.02,30 58.3,30 58.54,30.24 EL5704.3
HDMI_DDI_TX_CON_P0: length 27.5
  TOP w0.102: 52.72,29.42 52.72,28.8 53.52,28 54.32,28 54.45,27.87 ED5702.10 ED5702.1 56.27,27.87 56.41,28 56.56,28 56.91,27.65 57.27,27.65 R5713.1 57.97,27.75 58.29,27.75 58.63,27.4 EL5703.4 ; 52.72,29.42 v1(52.33,29.42) ; 52.72,29.42 52.72,31.57 53.67,32.52 57.85,32.52 60.21,34.88 60.21,39.99 60.11,40.09 59.65,40.09 59.37,39.81 57.39,39.81 HDMI1.7
HDMI_DDI_TX_CON_P1: length 29.5
  TOP w0.102: HDMI1.4 56.13,38.33 56.02,38.43 56.02,39 55.9,39.13 54.14,39.13 49.06,34.05 49.06,29.93 52.31,26.68 52.31,26.23 ; 52.31,26.23 v1(52.69,26.23) ; 52.31,26.23 52.31,25.79 53.84,24.26 54.43,24.26 54.59,24.41 ED5701.4 ED5701.7 56.21,24.41 56.34,24.28 56.68,24.28 56.9,24.06 56.9,23.66 56.99,23.57 57.21,23.57 R5712.2 58.05,23.44 58.5,23.44 58.74,23.68 EL5702.3
HDMI_DDI_TX_CON_P2: length 25.4
  TOP w0.102: 52.59,27.61 53.57,26.64 53.57,26.21 54,25.77 54.16,25.77 54.32,25.93 ED5701.1 ED5701.10 56.47,25.93 56.61,25.8 57.24,25.8 R5711.2 57.87,26.12 58.03,25.97 58.03,25.67 58.1,25.6 58.33,25.6 58.6,25.86 EL5701.3 ; 52.59,27.61 v1(52.84,27.87) ; 52.59,27.61 52.05,28.16 52.05,28.57 49.9,30.72 49.9,34.02 53.51,37.63 55.46,37.63 56.25,36.83 HDMI1.1
HDMI_DDI_TX_CON_P3: length 27.6
  TOP w0.102: HDMI1.10 57.38,41.32 60.61,41.32 61.2,40.73 61.2,34.06 60.9,33.75 ; 60.9,33.75 58.76,31.61 56.73,31.61 56.12,31.01 53.76,31.01 53.39,30.64 53.39,29.74 53.61,29.52 54.32,29.52 54.45,29.39 ED5702.7 ED5702.4 56.27,29.39 56.41,29.52 56.84,29.52 57.08,29.76 57.27,29.76 R5715.1 57.69,29.46 58.03,29.8 58.33,29.8 58.54,29.59 EL5704.4 ; 60.9,33.75 v1(60.63,34.02)
HDMI_DDI_TX_N0: length 133.7
  TOP w0.102: C5702.1 65.59,27.4 65.94,27.4 v3(66.19,27.65) ; v3(158.87,57.44) 159.05,57.62 159.5,57.62 160.78,58.91 164.07,58.91 166.72,61.55 169.97,61.55 170.33,61.19 170.34,61.19 170.35,61.18 170.61,61.18 170.78,61.36 170.78,61.59 171.24,62.05 CPU1.AC5
  L3 w0.114: v3(66.19,27.65) 66.35,27.49 66.9,27.49 68.84,29.43 90.59,29.43 91.02,29.85 94.78,29.85 95.97,31.04 105.99,31.04 106.47,30.56 108.76,30.56 110.04,29.29 122.71,29.29 123.24,29.82 132.68,29.82 133.35,30.49 134.98,30.49 135.94,31.45 139.66,31.45 140.43,32.23 148.61,32.23 159.46,43.07 159.46,57.5 159.27,57.68 159.11,57.68 v3(158.87,57.44)
  BOTTOM w0.102: v3(66.19,27.65) 66.56,27.65 v1(67.12,28.2)
HDMI_DDI_TX_N1: length 137.8
  TOP w0.102: CPU1.AE2 169.86,61.21 167,61.21 164.27,58.48 163.57,58.48 162.62,57.54 161.84,57.54 161.74,57.64 161.74,58.01 v3(161.91,58.19) ; C5704.1 65.63,22.66 66.8,22.66 v3(66.98,22.48)
  L3 w0.114: v3(161.91,58.19) 161.91,41.01 157.18,36.28 156.88,36.28 151.3,30.7 141.62,30.7 140.82,29.9 136.59,29.9 135.66,28.97 133.98,28.97 132.89,27.88 126.04,27.88 125.51,27.34 122.69,27.34 122.44,27.6 115.4,27.6 115.19,27.39 108.66,27.39 107.12,28.93 100.31,28.93 99.72,29.52 96.98,29.52 95.08,27.62 92.88,27.62 92.79,27.52 90.3,27.52 89.75,26.97 88.58,26.97 87.65,27.9 81.26,27.9 80.5,27.15 73.74,27.15 73.12,27.77 70.86,27.77 68.61,25.52 68.61,23.73 67.64,22.77 67.26,22.77 v3(66.98,22.48)
  BOTTOM w0.102: v3(66.98,22.48) 66.89,22.48 66.46,22.04 v1(66.11,22.04)
HDMI_DDI_TX_N2: length 133.7
  TOP w0.076: 168.53,60.67 168.55,60.67 168.56,60.65 169.6,60.65 169.62,60.66 169.68,60.68 169.97,60.68 170.05,60.65 170.25,60.65 170.27,60.66 CPU1.AE3
  TOP w0.102: v3(66.44,24.65) 66.24,24.84 65.6,24.84 C5707.1 ; 168.53,60.67 167.33,60.67 164.42,57.76 163.73,57.76 162.89,56.91 160.43,56.91 v3(160.16,57.18)
  L3 w0.114: v3(160.16,57.18) 160.34,57.01 160.82,57.01 161.16,56.66 161.16,43.53 148.98,31.35 141.16,31.35 140.37,30.55 136.28,30.55 135.35,29.62 133.72,29.62 132.64,28.54 125.77,28.54 125.23,28 122.99,28 122.58,28.41 109.6,28.41 108.41,29.6 106.08,29.6 105.51,30.17 96.33,30.17 95.14,28.97 91.38,28.97 90.96,28.55 70.73,28.55 67.93,25.75 67.93,25.14 67.65,24.87 66.66,24.87 v3(66.44,24.65)
  BOTTOM w0.102: v1(65.64,24.5) 66.29,24.5 v3(66.44,24.65)
HDMI_DDI_TX_N3: length 134.8
  TOP w0.102: C5709.1 65.26,29.69 65.56,29.4 65.95,29.4 66.35,29.8 v3(66.35,29.84) ; CPU1.AC1 169.38,62.17 168.98,62.17 168.91,62.1 166.4,62.1 163.89,59.59 158.01,59.59 157.94,59.52 157.94,59.25 158.02,59.17 158.37,59.17 158.45,59.09 v3(158.45,58.8)
  L3 w0.114: v3(66.35,29.84) 66.35,29.7 66.23,29.58 66,29.58 65.89,29.7 65.89,30.36 66.18,30.65 67.6,30.65 68.4,29.85 90.42,29.85 90.85,30.27 94.61,30.27 95.8,31.46 106.25,31.46 106.68,31.04 109.01,31.04 109.6,30.45 111.63,30.45 112.28,29.8 122.56,29.8 123,30.23 132.48,30.23 133.96,31.71 135.28,31.71 136.64,33.08 139.25,33.08 140.35,34.17 141.55,34.17 143.08,32.65 148.44,32.65 158.28,42.49 158.28,58.64 v3(158.45,58.8)
  BOTTOM w0.102: v1(65.78,30.58) 65.78,30.41 v3(66.35,29.84)
HDMI_DDI_TX_P0: length 133.4
  TOP w0.102: CPU1.AC3 170.6,62.05 170.31,61.76 166.63,61.76 163.98,59.11 160.7,59.11 159.41,57.83 159.12,57.83 158.87,58.08 v3(158.87,58.15) ; C5701.1 65.62,27.2 66.02,27.2 66.19,27.03 v3(66.19,26.94)
  L3 w0.114: v3(158.87,58.15) 158.87,58.07 159.03,57.91 159.37,57.91 159.69,57.59 159.69,42.98 148.71,32 140.53,32 139.75,31.22 136.04,31.22 135.08,30.26 133.45,30.26 132.77,29.59 123.33,29.59 122.81,29.06 109.94,29.06 108.67,30.33 106.38,30.33 105.89,30.82 96.07,30.82 94.87,29.62 91.11,29.62 90.69,29.2 68.94,29.2 67,27.26 66.45,27.26 66.19,27 v3(66.19,26.94)
  BOTTOM w0.102: v1(65.35,27.2) 65.61,26.94 v3(66.19,26.94)
HDMI_DDI_TX_P1: length 138.5
  TOP w0.102: v3(161.2,58.19) 161.27,58.19 161.53,57.93 161.53,57.56 161.75,57.34 162.71,57.34 163.65,58.28 164.35,58.28 167.09,61.01 169.42,61.01 CPU1.AE1 ; v3(66.98,23.19) 66.66,22.87 65.48,22.87 65.29,23.06 C5703.1
  L3 w0.114: v3(66.98,23.19) 67.18,22.99 67.55,22.99 68.38,23.83 68.38,25.61 70.77,27.99 73.22,27.99 73.84,27.37 80.4,27.37 81.16,28.13 87.75,28.13 88.68,27.2 89.65,27.2 90.2,27.75 92.69,27.75 92.79,27.85 94.98,27.85 96.88,29.75 99.82,29.75 100.41,29.16 107.22,29.16 108.76,27.62 115.1,27.62 115.3,27.83 122.53,27.83 122.79,27.57 125.42,27.57 125.95,28.1 132.8,28.1 133.89,29.2 135.57,29.2 136.5,30.13 140.72,30.13 141.53,30.93 151.2,30.93 156.78,36.51 157.09,36.51 161.68,41.11 161.68,57.71 161.57,57.82 161.28,57.82 161.2,57.9 v3(161.2,58.19)
  BOTTOM w0.102: v3(66.98,23.19) 66.89,23.19 66.63,22.93 65.65,22.93 v1(65.3,23.28)
HDMI_DDI_TX_P2: length 133.8
  TOP w0.076: CPU1.AE5 171.13,60.75 170.91,60.63 170.46,60.56 170.29,60.49 170.02,60.49 169.94,60.52 169.74,60.52 169.68,60.49 169.66,60.49 169.63,60.48 168.56,60.48 168.55,60.46 168.53,60.46
  TOP w0.102: v3(66.44,25.36) 66.12,25.05 65.63,25.05 C5705.1 ; v3(160.16,56.47) 160.4,56.71 162.97,56.71 163.82,57.55 164.51,57.55 167.41,60.46 168.53,60.46
  L3 w0.114: v3(66.44,25.36) 66.7,25.1 67.56,25.1 67.7,25.23 67.7,25.84 70.63,28.78 90.86,28.78 91.29,29.2 95.05,29.2 96.24,30.4 105.6,30.4 106.17,29.83 108.51,29.83 109.7,28.64 122.67,28.64 123.08,28.23 125.14,28.23 125.68,28.77 132.54,28.77 133.62,29.84 135.25,29.84 136.19,30.78 140.27,30.78 141.07,31.58 148.89,31.58 160.93,43.63 160.93,56.56 160.72,56.78 160.4,56.78 160.16,56.53 v3(160.16,56.47)
  BOTTOM w0.102: v1(65.75,25.81) 65.98,25.81 v3(66.44,25.36)
HDMI_DDI_TX_P3: length 135.4
  TOP w0.102: v3(66.32,29.12) 66.25,29.2 65.56,29.2 C5708.1 ; v3(157.74,58.8) 157.74,59.6 157.93,59.79 163.81,59.79 166.32,62.3 168.82,62.3 168.9,62.38 169.83,62.38 CPU1.AC2
  L3 w0.114: v3(66.32,29.12) 66.09,29.35 65.91,29.35 65.66,29.61 65.66,30.45 66.08,30.88 67.69,30.88 68.5,30.07 90.33,30.07 90.75,30.5 94.51,30.5 95.7,31.69 106.35,31.69 106.77,31.27 109.1,31.27 109.69,30.68 111.72,30.68 112.37,30.03 122.47,30.03 122.9,30.46 132.39,30.46 133.86,31.94 135.18,31.94 136.55,33.31 139.16,33.31 140.26,34.4 141.64,34.4 143.17,32.88 148.35,32.88 158.06,42.59 158.06,58.31 157.74,58.63 v3(157.74,58.8)
  BOTTOM w0.102: v1(65.45,29.12) v3(66.32,29.12)
HDMI_DET_CPU: length 238.4
  TOP w0.102: CPU1.CV42 189.56,34.76 v3(189.83,34.49)
  L4 w0.127: v3(47.64,52.25) 46.64,51.26 46.64,50.3 45.76,49.42 45.76,46.99 46.08,46.67 46.08,32.11 52.25,25.94 52.25,21.54 53.58,20.21 53.58,17.41 59,12 60.26,12 62.33,9.93 62.64,9.93 68.8,3.77 74.12,3.77 75.74,5.38 79.21,5.38 81.19,3.41 86.34,3.41 87.22,2.52 107.79,2.52 108.53,3.26 112.67,3.26 113.6,2.32 131.53,2.32 132.12,2.92 133.38,2.92 133.69,2.61 135.06,2.61 135.08,2.63 135.47,2.63 135.53,2.57 137.74,2.57 138.76,1.54 142.01,1.54 142.3,1.83 156.12,1.83 157.07,0.87 185.55,0.87 190.08,5.4 192.23,5.4 192.51,5.68 192.51,6.85 192.95,7.29 192.95,7.66 199.29,13.99 199.77,13.99 202.13,16.35 202.13,17.31 203.75,18.93 203.75,21.67 201.95,23.47 201.95,26.18 200.41,27.72 199.84,27.72 195.55,32.01 193.71,32.01 190.84,34.88 190.32,34.88 189.92,34.49 v3(189.83,34.49)
  BOTTOM w0.102: Q5705.S 51.64,54.63 50.57,53.56 49.35,53.56 R5732.2 48.73,53.49 v1(48.31,53.06) 47.64,52.39 v3(47.64,52.25)
HDMI_SCL_CPU: length 194.1
  TOP w0.102: CPU1.DL40 188.29,28.21 188.29,27.09 188.75,26.63 188.75,24.33 v3(188.62,24.2)
  L3 w0.127: v3(86.78,22.03) 86.66,21.9 86.66,21.28 86.82,21.12 89.24,21.12 89.73,20.64 105.69,20.64 106.81,19.53 114.12,19.53 114.78,18.86 122.67,18.86 123.49,18.04 134.24,18.04 134.46,17.81 134.69,17.81 135.67,17.81 136.51,16.97 143.65,16.97 145.01,18.33 155.56,18.33 156.61,19.37 159.32,19.37 163.23,23.27 168.26,23.27 168.36,23.37 174.34,23.37 174.66,23.7 175.76,23.7 176.29,23.17 178.74,23.17 180.45,24.88 187.16,24.88 188.09,23.95 188.37,23.95 v3(188.62,24.2)
  L4 w0.127: v3(62.96,37.13) 62.8,36.97 62.8,35.73 69,29.53 69,27.15 70.11,26.04 70.11,23.27 70.19,23.18 74.68,23.18 75.05,23.55 86.12,23.55 86.61,23.07 86.61,22.43 86.77,22.27 86.77,22.03 v3(86.78,22.03)
  BOTTOM w0.102: RN5702.1 40.85,59.24 40.95,59.14 Q5701.1 40.95,57.55 40.08,56.68 40.08,56.34 40.08,52.84 v1(40.61,52.31) 41.49,51.43 43.61,51.43 45.04,50 48.37,50 48.97,49.4 48.97,36.61 49.85,35.73 62.27,35.73 62.78,36.25 62.78,36.95 v3(62.96,37.13)
HDMI_SCL_R: length 15.1
  TOP w0.305: D5701.1 56.96,59.23 56.95,59.22 56.38,59.22 C5721.1 56.37,58.34 55.24,57.22 v1(53.21,57.22) v3(50.45,57.22)
  BOTTOM w0.305: v3(50.45,57.22) 50.32,57.08 48.81,57.08 47.13,55.4 47.13,54.02 47.28,53.86 47.28,53.31 R5721.2
HDMI_SDA_CPU: length 200.9
  TOP w0.102: v3(188.94,23.56) 189.39,24.02 189.39,27.1 CPU1.DP42
  L3 w0.127: v3(86.09,22.22) 86.27,22.04 86.27,21.13 86.66,20.74 89.08,20.74 89.57,20.26 105.54,20.26 106.99,18.81 114.3,18.81 114.63,18.48 122.51,18.48 123.33,17.66 133.96,17.66 134.24,17.38 135.42,17.38 136.21,16.59 143.81,16.59 145.17,17.94 155.72,17.94 156.77,18.99 159.48,18.99 163.38,22.89 168.75,22.89 168.94,23.09 174.38,23.09 174.76,23.47 175.66,23.47 176.19,22.94 178.83,22.94 180.55,24.65 187.07,24.65 188,23.72 188.78,23.72 v3(188.94,23.56)
  L4 w0.127: v3(86.09,22.22) 86.23,22.36 86.23,22.91 85.97,23.17 75.21,23.17 74.83,22.8 70.04,22.8 69.73,23.11 69.73,25.88 68.62,26.99 68.62,29.37 62.42,35.57 62.42,36.94 v3(62.25,37.12) ; v3(42.84,56.68) 43.06,56.91 43.06,58.91 41.33,60.65 41.33,61.21 v3(41.35,61.23)
  BOTTOM w0.102: v3(42.84,56.68) 42.84,56.06 42.53,55.75 Q5701.4 42.26,56.3 41.91,56.64 40.88,56.64 40.44,56.2 40.44,53.27 40.84,52.87 40.84,52.87 41.17,52.55 41.17,52.54 41.69,52.02 v1(43.06,52.02) 43.54,52.02 45.2,50.35 48.52,50.35 49.33,49.54 49.33,36.76 50,36.09 62.12,36.09 62.43,36.39 62.43,36.94 v3(62.25,37.12) ; RN5702.2 40.42,61.33 v1(40.45,61.36) 41.22,61.36 v3(41.35,61.23)
HDMI_SDA_R: length 19.9
  TOP w0.305: v3(50.46,58.05) 50.19,58.05 49.65,57.51 49.65,56.85 49.96,56.55 54.58,56.55 54.69,56.66 55.47,56.66 56.19,57.37 C5722.1 56.48,57.26 D5701.2
  BOTTOM w0.305: ED5703.5 45.3,57.82 R5722.2 45.3,59.88 46.35,60.93 v1(47.55,60.93) 48.46,60.93 50.46,58.94 v3(50.46,58.05)
HM_VCCP: length 2.6
  TOP w0.305: 73.82,28.05 v1(73.82,28.05) ; 73.82,28.05 73.82,27.66 73.64,27.47 R24061.1 ; 73.82,28.05 73.53,28.33 G2401.2
HM_VCCP_R: length 7.6
  TOP w0.203: 75.97,26.43 76.4,26.01 ECIO1.95 76.4,23.14 76.18,22.93
  TOP w0.305: v3(76.24,21.98) 76.18,22.03 76.18,22.93 ; 75.97,26.43 75.51,26.89 v1(75.51,26.99) 75.45,27.06 R24061.2
  BOTTOM w0.305: C2409.1 75.92,21.67 76.23,21.98 v3(76.24,21.98)
HPGP_M2_SATA_DET#: length 272.1
  TOP w0.102: v3(189.88,37.19) 190.21,36.87 CPU1.CR43 ; NGFFM1.69 93.88,63.65 93.63,63.9 93.63,64.62 93.29,64.96 89.1,64.96 88.34,65.73 R6305.1 R6308.1 v1(81.65,65.73) 80.81,65.73 79.02,67.52 79.02,71.11 79.03,71.13 v3(79.03,72.08)
  L3 w0.127: v3(54.07,68.55) 57.27,68.55 60.81,72.09 79.03,72.09 v3(79.03,72.08)
  L4 w0.127: v3(54.07,68.55) 51.42,65.91 51.42,50.57 49.81,48.96 49.81,33.59 53.37,30.03 54.15,30.03 55.29,28.89 55.29,27.76 56.2,26.85 56.2,23.75 60.53,19.42 60.53,16.67 62.6,14.6 63.73,14.6 67.61,10.72 80.59,10.72 80.94,10.36 86.61,10.36 87.62,9.36 89.22,9.36 90.58,7.99 90.61,7.99 92.59,6.01 92.95,6.01 92.98,5.98 95.24,5.98 95.65,6.4 98.87,6.4 99.71,5.56 99.71,5.23 99.98,4.96 99.98,4.75 100.38,4.36 107.21,4.36 107.81,4.96 119.88,4.96 120.14,5.22 122.09,5.22 122.19,5.12 126.81,5.12 126.93,5.23 129.88,5.23 130.69,6.04 132.38,6.04 132.95,5.47 134.4,5.47 134.77,5.84 141.91,5.84 142.79,4.97 155.2,4.97 155.94,5.71 160.53,5.71 161.55,6.73 162.97,6.73 163.77,7.53 164.91,7.53 165.18,7.8 170.2,7.8 170.39,7.61 177.55,7.61 178.25,8.32 179.7,8.32 179.91,8.52 180.7,8.52 180.76,8.46 181.43,8.46 185.58,12.61 185.58,13.3 186.58,14.3 186.81,14.3 187.72,15.2 187.72,15.98 188.54,16.79 188.54,17.19 187.91,17.82 187.91,21.65 v3(188.32,22.06)
  BOTTOM w0.102: v3(188.32,22.06) 188.32,22.09 189.34,23.11 189.34,24.05 188.6,24.79 188.6,30.53 R1608.1 188.13,31 188.13,32.45 188.08,32.5 188.08,32.84 188.57,33.33 188.57,33.76 189.06,34.25 189.06,34.92 188.74,35.25 188.74,35.58 188.78,35.63 188.78,36.5 189.48,37.19 v3(189.88,37.19)
ICH_RSMRST_N_R: length 7.5
  TOP w0.102: v3(84.47,22.24) 83.63,23.08 82.41,23.08 81.6,23.9 ECIO1.82
  BOTTOM w0.102: 84.24,21.28 84.47,21.52 v3(84.47,22.24) 84.47,22.76 v1(84.22,23.01) ; 84.24,21.28 D6904.1 ; 84.24,21.28 R24037.1
IMON_VIN: length 4.7
  TOP w0.102: C4303.1 93.41,31.65 v1(93.63,31.86) 93.63,32.43 93.4,32.66 R4318.2 91.99,32.11 U4303.3
IMON_VIN_N: length 5.4
  TOP w0.102: U4303.5 89.9,31.46 90.07,31.63 90.07,32.42 90.46,32.81 R4324.2 90.46,33.53 v1(89.41,33.53) 88.61,33.53 C4302.1
IMON_VIN_P: length 4
  TOP w0.102: R4325.2 87.38,33.86 C4302.2 87.39,33.12 87.7,32.81 87.7,32.84 v1(87.7,32.84) 88.43,32.11 U4303.4
IMON_VOUT: length 3.8
  TOP w0.102: U4303.6 88.4,30.81 87.78,31.43 87.4,31.43 v1(87.2,31.64) 86.37,32.46 R4320.1
IMON_VOUT_Q5: length 5.9
  BOTTOM w0.102: R4327.2 82.99,49.81 83.44,49.81 83.44,49.81 83.65,49.81 v1(84,50.16) 84.34,50.5 84.34,52.8 83.48,53.67 Q4308.D
IMON_VOUT_R1: length 22
  TOP w0.102: v3(81.29,37.15) 81.29,36.56 83.27,34.57 83.27,33.47 R4321.1 R4322.1 83.49,32.34 R4319.1 85.05,33.26 R4320.2
  L4 w0.127: v3(81.23,46.52) 81.23,43 81.29,42.95 v3(81.29,37.15)
  BOTTOM w0.102: v3(81.23,46.52) v1(82.54,47.82) 82.93,48.22 82.93,48.44 82.98,48.49 R4327.1 R4332.1
IMON_VOUT_R1_G: length 74.7
  L4 w0.127: v3(98.54,28.47) 98.25,28.18 96.38,28.18 95.33,29.23 90.85,29.23 87.02,33.06 82.14,33.06 81.18,34.02 81.18,36.52 80.92,36.77 80.92,36.84 80.82,36.95 80.82,37.63 80.29,38.15 80.29,49.6 80.09,49.8 v3(79.84,49.8)
  BOTTOM w0.102: v3(98.54,28.47) 98.54,30.48 102.6,34.54 104.48,34.54 108.94,39.01 108.94,43.07 109.65,43.78 109.65,45.91 109.17,46.39 109.17,51.61 109.76,52.2 109.76,53.27 112.96,56.47 Q4301.G ; R4332.2 81.92,49.8 v1(80.9,49.8) v3(79.84,49.8)
INPUT3VSEL: length 10.3
  TOP w0.102: R1705.2 R1706.1 199.29,22.58 198.03,23.85 v1(197.62,23.85) 197.37,23.85 196.92,24.3 196.27,24.3 194.16,26.41 194.16,27 193.89,27.26 193.47,27.26 CPU1.DN49
JP1: length 5.4
  TOP w0.102: R24121.1 72.49,16.24 v1(72.55,16.18) 72.95,15.78 72.95,14.45 73.62,13.78 ECIO1.121
KBDATA: length 3.8
  TOP w0.102: ECIO1.77 83.6,25.98 v1(84.54,26.92) R24099.1
LAN_CLK_CPU_N: length 5.2
  BOTTOM w0.102: LAN1.16 59.71,85.51 59.62,85.43 59.31,85.43 59.02,85.72 59.02,86.6 58.67,86.95 58.67,87.5 ; R10013.2 59.19,88.26 58.89,88.26 58.67,88.04 58.67,87.5 ; 58.67,87.5 v1(59.04,87.5)
LAN_CLK_CPU_N_C: length 187.9
  TOP w0.076: CPU1.CJ3 170.27,39.76 170.25,39.77 170.05,39.77 169.97,39.74 169.68,39.74 169.62,39.77 169.6,39.77 169.32,39.77 169,39.45 167.22,39.45 167.21,39.44
  TOP w0.102: 155.52,32.84 155.52,34.82 160.16,39.46 165.13,39.46 165.15,39.44 167.21,39.44 ; 155.52,32.84 155.52,31.64 156.07,31.1 156.45,31.1 v3(156.69,31.34) ; 155.52,32.84 v1(155.88,32.84)
  L4 w0.114: v3(156.69,31.34) 156.66,31.37 156.32,31.37 156.21,31.26 156.21,30.96 156.11,30.86 155.36,30.86 152.49,27.99 147.46,27.99 147.06,27.59 143.61,27.59 143.29,27.27 132.83,27.27 132.12,26.55 130.89,26.55 130.34,27.1 127.13,27.1 126.36,26.33 121.8,26.33 120.38,24.9 108.36,24.9 106.55,26.71 104.43,26.71 101.9,29.23 101.9,29.83 100.85,30.88 96.98,30.88 96.01,31.85 91.39,31.85 88.08,35.15 84.65,35.15 83.39,36.41 83.39,37.48 84.59,38.67 84.59,48.52 83.97,49.14 83.97,59.84 84.96,60.84 84.96,64.03 82.91,66.08 82.91,68.84 82.56,69.19 82.56,72.71 81.17,74.1 61.25,74.1 59.13,76.22 59.13,79.83 57.03,81.93 57.03,86.54 58.63,88.14 58.63,90.91 58.73,91.01 59.1,91.01 59.2,91.11 59.2,91.45 59.09,91.57 v3(58.98,91.57)
  BOTTOM w0.102: R10013.1 59.39,89.39 59.39,89.82 59.29,89.92 58.86,89.92 58.79,89.99 58.79,90.48 58.72,90.54 58.72,91.47 58.83,91.57 v3(58.98,91.57)
LAN_CLK_CPU_P: length 5.1
  BOTTOM w0.102: v1(58.44,86.12) 58.81,86.12 ; 58.81,86.12 58.81,86.52 58.47,86.86 58.47,88.38 R10014.2 ; 58.81,86.12 58.81,85.63 59.22,85.23 59.6,85.23 59.71,85.11 LAN1.15
LAN_CLK_CPU_P_C: length 188.2
  TOP w0.076: CPU1.CJ5 171.13,39.68 170.91,39.79 170.46,39.86 170.29,39.94 170.02,39.94 169.94,39.91 169.74,39.91 169.68,39.93 169.66,39.94 169.63,39.95 169.25,39.95 168.93,39.63 167.24,39.63 167.23,39.65 167.21,39.65
  TOP w0.102: 167.21,39.65 165.23,39.65 165.22,39.66 160.08,39.66 157.05,36.63 ; v1(156.8,36.89) 157.05,36.63 ; 157.05,36.63 155.32,34.91 155.32,31.55 155.98,30.89 156.42,30.89 v3(156.69,30.63)
  L4 w0.114: v3(58.27,91.57) 58.4,91.43 58.4,88.23 56.8,86.64 56.8,81.83 58.91,79.73 58.91,76.13 61.16,73.88 81.07,73.88 82.33,72.62 82.33,69.1 82.68,68.75 82.68,65.99 84.73,63.94 84.73,60.93 83.74,59.94 83.74,49.04 84.36,48.42 84.36,38.77 83.16,37.57 83.16,36.31 84.55,34.92 87.99,34.92 91.29,31.62 95.92,31.62 96.88,30.65 100.75,30.65 101.67,29.73 101.67,29.14 104.33,26.48 106.45,26.48 108.26,24.67 120.47,24.67 121.9,26.1 126.45,26.1 127.23,26.87 130.24,26.87 130.79,26.32 132.21,26.32 132.93,27.04 143.38,27.04 143.71,27.36 147.15,27.36 147.55,27.76 152.59,27.76 155.46,30.63 v3(156.69,30.63)
  BOTTOM w0.102: R10014.1 58.52,89.52 58.52,89.76 58.59,89.82 58.59,90.39 58.52,90.46 58.52,91.31 v3(58.27,91.57)
LAN_CLKREQ_CPU_N: length 21.1
  TOP w0.102: v3(61.62,75.92) 61.62,75.46 60.86,74.7 60.86,71.89 60.43,71.46 R3116.2 60.02,70.46 59.93,70.37 R10021.2 59.93,70.14 58.85,69.05 D3101.K
  BOTTOM w0.102: LAN1.12 59.67,83.91 59.62,83.96 59.48,83.96 59.47,83.97 58.67,83.97 58.39,83.69 v1(58.39,83.21) 57.44,82.26 57.44,82.24 R3143.1 57.35,82.13 57.35,81.34 57.45,81.25 57.45,79.24 57.86,78.83 58.71,78.83 60.91,76.63 60.91,76.62 61.23,76.29 61.24,76.29 v3(61.62,75.92)
LAN_CLKREQ_CPU_N_C: length 229.7
  TOP w0.102: CPU1.DK33 184.73,29.17 v3(184.44,28.87) ; v3(185.26,14.88) 184.62,14.24 184.62,11.56 183.97,10.91 183.52,10.91 182.58,9.98 182.58,9.52 181.25,8.18 181.25,4.68 180.78,4.22 161.46,4.22 161.19,4.49 161.19,7.6 157.28,11.51 152.9,11.51 v3(152.66,11.27) ; R10021.1 59.05,70.34 57.99,69.28 57.99,67.1 57.79,66.91 v1(57.39,66.91) 57.03,66.91 56.56,67.38 D3101.A 56.56,69.22 56.75,69.41 v3(56.75,69.91)
  L4 w0.127: v3(185.26,14.88) 185.41,15.03 185.41,18.28 185.24,18.44 185.24,21.03 185.13,21.14 185.13,24.42 184,25.55 184,28.31 184.44,28.74 v3(184.44,28.87) ; v3(152.66,11.27) 152.57,11.18 135.17,11.18 134.19,12.16 129.18,12.16 128.98,11.96 128.96,11.96 128.95,11.94 127.46,11.94 126.74,12.66 125.07,12.66 124.2,11.79 116.45,11.79 115.58,12.66 114.31,12.66 112.11,10.46 109.67,10.46 109.2,10.93 109.06,10.93 106.48,13.51 105,13.51 103.81,14.7 102.12,14.7 101.39,15.43 98.7,15.43 96.28,13.02 91.06,13.02 90.23,13.85 84.06,13.85 83.36,14.55 81.07,14.55 79.17,12.65 67.59,12.65 66.55,13.69 66.55,15.79 65.52,16.82 64.21,16.82 57.72,23.31 57.72,26.8 56.16,28.36 56.16,29.09 54.4,30.86 53.62,30.86 50.57,33.91 50.57,48.51 53.08,51.03 53.08,55.13 52.67,55.54 52.67,65.83 v3(56.75,69.91)
LAN_EESK: length 6.3
  TOP w0.381: v3(65.82,84.46) 66.73,84.46 R3136.1 68.46,86.84 v1(69.06,87.44)
  BOTTOM w0.203: v3(65.82,84.46) 65.56,84.71 LAN1.27
LAN_LED_ACTIVE: length 21.1
  BOTTOM w0.381: R3154.1 55.37,59.86 55.63,59.6 55.63,57.28 55.25,56.9 v1(55.25,55.24) 55.25,54.09 63.27,46.07 65.17,46.07 RJ1.11
LAN_LINK_100: length 22.6
  L3 w0.381: v3(66.33,85.05) 65.4,85.05 65.11,84.76 65.11,84.17 59.51,78.57 59.51,76.35 57.01,73.85 57.01,71.37 v3(56.9,71.26)
  BOTTOM w0.203: v3(66.33,85.05) 65.84,85.05 65.77,85.11 LAN1.26
  BOTTOM w0.381: R3152.2 57.27,72.27 56.73,72.27 v1(56.49,72.03) 56.49,71.68 v3(56.9,71.26)
LAN_LINK_1000: length 29.5
  L3 w0.381: v3(65.69,85.72) 64.96,85.72 64.47,85.23 64.47,84.48 58.88,78.89 58.88,78.14 56.27,75.52 56.27,70.3 55.88,69.91 v3(54.84,69.91)
  BOTTOM w0.203: v3(65.69,85.72) 65.49,85.51 LAN1.25
  BOTTOM w0.381: R3151.2 v1(52.96,64.97) 52.96,65.23 52.96,65.23 52.96,65.66 54.84,67.54 v3(54.84,69.91)
LAN_LINK_N: length 59.7
  TOP w0.381: v3(60.91,62.18) 60.47,62.61 60.47,67.72 v3(61.95,69.2) 61.83,69.32 61.83,72.85 61.84,72.86 61.84,73.04 62.44,73.65 62.44,75.53 64.4,77.49 71.31,77.49 73.27,79.46 73.27,83.35 70.66,85.96 69.58,85.96 R3136.2
  BOTTOM w0.381: RJ1.12 63.19,47.05 56.19,54.05 v1(56.19,56.85) 56.27,56.94 56.27,61.3 57.15,62.18 v3(60.91,62.18) ; v3(61.95,69.2) ED3103.3
LAN_MDI0_N: length 15.1
  TOP w0.102: L3105.2 73.21,75.27 73.42,75.48 73.42,75.73 v3(73.19,75.96)
  BOTTOM w0.102: v1(71.71,76.93) 71.71,77.29 ; 71.71,77.29 68.16,77.29 67.36,78.09 67.04,78.09 64.69,80.44 64.05,80.44 63.53,80.95 63.53,81.29 63.38,81.44 LAN1.2 ; 71.71,77.29 72.78,77.29 73.38,76.69 73.38,76.15 v3(73.19,75.96)
LAN_MDI0_P: length 15
  TOP w0.102: v3(73.9,75.96) 73.78,75.83 73.78,75.46 73.89,75.35 L3105.3
  BOTTOM w0.102: v3(73.9,75.96) 73.73,76.13 73.73,76.84 72.93,77.64 69.8,77.64 ; v1(69.8,78) 69.8,77.64 ; 69.8,77.64 68.3,77.64 67.5,78.44 67.19,78.44 64.84,80.79 64.2,80.79 63.89,81.1 63.89,81.44 63.78,81.54 LAN1.1
LAN_MDI1_N: length 10.5
  TOP w0.102: L3103.2 67.08,75.36 67.24,75.52 67.24,75.82 v3(67.06,75.99)
  BOTTOM w0.102: 63.81,79.1 63.33,79.1 62.21,80.22 62.21,81.49 62.18,81.52 LAN1.5 ; 63.81,79.1 v1(63.81,78.74) ; 63.81,79.1 64.29,79.1 66.53,76.86 66.82,76.86 67.22,76.46 67.22,76.15 v3(67.06,75.99)
LAN_MDI1_P: length 10.5
  TOP w0.102: L3103.3 67.76,75.36 67.6,75.52 67.6,75.82 v3(67.78,75.99)
  BOTTOM w0.102: 63.11,79.82 63.48,79.45 64.44,79.45 66.67,77.22 66.97,77.22 67.58,76.61 67.58,76.19 v3(67.78,75.99) ; 63.11,79.82 62.56,80.37 62.56,81.37 62.58,81.39 LAN1.4 ; 63.11,79.82 v1(63.35,80.07)
LAN_MDI2_N: length 16.5
  TOP w0.102: L3104.2 70.17,74.43 70.35,74.61 70.35,74.85 v3(70.16,75.05)
  BOTTOM w0.102: v3(70.16,75.05) 70.31,75.21 70.31,75.58 70.2,75.69 69.36,75.69 68.56,74.9 66.66,74.9 63.88,77.68 62.99,77.68 62.33,78.34 61.24,79.43 ; 61.24,79.43 60.74,79.93 60.74,80.65 61.39,81.29 61.39,82.03 LAN1.7 ; 61.24,79.43 v1(61,79.18)
LAN_MDI2_P: length 16.5
  TOP w0.102: L3104.3 70.85,74.4 70.71,74.55 70.71,74.89 v3(70.87,75.05)
  BOTTOM w0.102: v3(70.87,75.05) 70.67,75.25 70.67,75.73 70.34,76.05 69.21,76.05 68.41,75.25 66.81,75.25 64.03,78.03 63.14,78.03 62.69,78.48 62.69,78.48 61.1,80.08 61.1,80.5 61.41,80.81 ; LAN1.6 61.78,81.42 61.74,81.38 61.74,81.15 61.41,80.81 ; 61.41,80.81 v1(61.64,80.58)
LAN_MDI3_N: length 12.8
  TOP w0.102: L3102.2 64.05,74.61 64.1,74.66 64.1,75.1 v3(64.02,75.19)
  BOTTOM w0.102: LAN1.10 59.86,83.11 59.81,83.07 59.51,83.07 59.2,82.76 59.2,79.6 61.71,77.09 ; 61.71,77.09 62.4,76.4 63.37,76.4 64.02,75.76 v3(64.02,75.19) ; 61.71,77.09 v1(61.47,76.85)
LAN_MDI3_P: length 12.7
  TOP w0.102: v3(64.75,75.19) 64.62,75.19 64.46,75.03 64.46,74.81 64.73,74.54 L3102.3
  BOTTOM w0.102: 59.56,80.57 59.56,82.61 59.66,82.71 LAN1.9 ; 59.56,80.57 59.56,79.75 62.55,76.76 63.52,76.76 64.37,75.91 64.37,75.73 64.47,75.63 64.64,75.63 64.74,75.53 64.74,75.2 v3(64.75,75.19) ; 59.56,80.57 v1(59.92,80.57)
LAN_MDO0_N: length 12.8
  TOP w0.102: 73.57,71.24 73.85,70.95 74.67,70.95 75.29,70.34 75.29,69.78 U3102.1 75.29,69.29 75.29,68.73 74.56,68 74.56,66.34 75.14,65.75 75.29,65.75 75.5,65.54 75.5,65.4 75.28,65.19 XF3101.14 ; 73.57,71.24 v1(73.36,71.03) ; 73.57,71.24 73.35,71.45 73.35,71.94 EC3102.1 73.38,72.66 73.38,72.96 73.21,73.14 L3105.1
LAN_MDO0_N_C: length 27.1
  TOP w0.102: XF3101.11 75.28,54.31 77.01,52.58 77.01,52.05 ; RJ1.2 73.67,35.89 73.97,36.19 73.97,42.65 76.07,44.75 77.89,44.75 78.53,45.39 78.54,45.39 79.53,46.38 79.53,48.76 77.01,51.29 77.01,52.05 ; 77.01,52.05 v1(76.68,52.05)
LAN_MDO0_P: length 12.8
  TOP w0.102: 75.18,70.95 v1(75.41,71.19) ; 75.18,70.95 74.82,71.31 74,71.31 73.71,71.6 73.71,71.94 EC3101.1 73.73,72.59 73.73,72.98 73.89,73.14 L3105.4 ; 75.18,70.95 75.64,70.49 75.64,68.59 74.91,67.86 74.91,67.27 U3102.6 74.91,67.02 74.91,66.48 75.29,66.11 75.43,66.11 76.28,65.26 XF3101.13
LAN_MDO0_P_C: length 27.1
  TOP w0.102: 78.5,50.3 79.89,48.91 79.89,46.23 78.69,45.03 78.67,45.03 78.04,44.39 76.22,44.39 74.33,42.5 74.33,36.22 74.57,35.98 74.86,35.98 74.94,35.89 RJ1.1 ; 78.5,50.3 77.37,51.43 77.37,52.73 76.28,53.81 XF3101.12 ; 78.5,50.3 v1(78.73,50.53)
LAN_MDO1_N: length 12.6
  TOP w0.102: L3103.1 67.08,73.28 67.28,73.08 67.28,72.68 EC3104.1 67.34,71.94 67.34,71.76 67.69,71.41 ; 67.69,71.41 v1(67.48,71.19) ; 67.69,71.41 68.66,70.43 69.05,70.43 69.31,70.18 69.31,69.57 U3101.1 69.31,69.34 69.31,68.69 68.72,68.11 68.72,65.93 69.1,65.56 69.47,65.56 69.59,65.44 69.59,65.22 69.28,64.91 XF3101.20
LAN_MDO1_N_C: length 28.7
  TOP w0.102: RJ1.6 v3(68.59,36.63) ; v3(69.34,57.13) 69.5,57.13 69.62,57.02 69.62,56.64 69.28,56.3 XF3101.5
  L3 w0.102: v3(68.59,36.63) 70.23,36.63 70.33,36.73 70.33,52.06 69.63,52.77 69.63,56.84 v3(69.34,57.13)
  BOTTOM w0.102: v1(69.02,57.96) 69.34,57.64 v3(69.34,57.13)
LAN_MDO1_P: length 12.3
  TOP w0.102: XF3101.19 70.28,64.9 69.94,65.24 69.94,65.58 69.61,65.91 69.25,65.91 69.08,66.08 69.08,66.95 U3101.6 69.08,67.19 69.08,67.96 69.67,68.55 69.67,70.32 69.2,70.79 68.81,70.79 67.69,71.9 67.69,72.05 EC3103.1 67.63,72.72 67.63,73.12 67.76,73.25 L3103.4
LAN_MDO1_P_C: length 28.7
  TOP w0.102: RJ1.3 v3(72.4,36.63) ; v3(70.25,57.13) 70.07,57.13 69.97,57.03 69.97,56.6 70.28,56.28 XF3101.6
  L3 w0.102: v3(72.4,36.63) 70.77,36.63 70.67,36.73 70.67,52.2 69.96,52.91 69.96,56.84 v3(70.25,57.13)
  BOTTOM w0.102: v3(70.25,57.13) 70.25,57.43 v1(70.73,57.91)
LAN_MDO2_N: length 12.1
  TOP w0.102: L3104.1 70.17,72.36 70.33,72.2 70.33,71.74 EC3106.1 70.33,71.06 70.33,70.8 70.75,70.38 71.37,70.38 ; 71.37,70.38 v1(71.37,70.08) ; 71.37,70.38 72.22,70.38 72.54,70.06 72.54,68.53 73.25,67.82 73.25,67.26 U3102.4 73.25,67.03 73.25,66.44 72.64,65.83 72.64,65.35 72.28,65 XF3101.17
LAN_MDO2_N_C: length 29.7
  TOP w0.102: RJ1.5 69.86,35.89 69.95,35.98 70.25,35.98 70.3,36.03 70.3,40.75 75.52,45.97 77.38,45.97 78.31,46.9 78.31,48.22 75.25,51.28 75.25,52.39 74.92,52.72 73.24,52.72 72.64,53.31 72.64,53.64 72.28,54 XF3101.8
LAN_MDO2_P: length 11.9
  TOP w0.102: XF3101.16 73.28,65.02 72.99,65.31 72.99,65.68 73.61,66.29 73.61,67.97 72.9,68.68 72.9,69.3 U3102.3 72.9,69.78 72.9,70.2 72.37,70.74 70.9,70.74 70.69,70.95 70.69,71.06 EC3105.1 70.68,71.75 70.68,72.13 70.85,72.3 L3104.4
LAN_MDO2_P_C: length 30
  TOP w0.102: 76.9,50.14 75.61,51.43 75.61,52.53 75.07,53.07 73.39,53.07 73,53.46 73,53.79 73.28,54.07 XF3101.9 ; 76.9,50.14 78.67,48.37 78.67,46.75 77.53,45.61 75.67,45.61 70.66,40.6 70.66,36.07 70.75,35.98 71.05,35.98 71.13,35.89 RJ1.4 ; 76.9,50.14 v1(77.13,50.36)
LAN_MDO3_N: length 12.7
  TOP w0.102: L3102.1 64.05,72.46 64.2,72.31 64.2,71.79 EC3108.1 64.24,71.1 64.24,70.7 64.64,70.3 65.64,70.3 ; 65.64,70.3 66.37,70.3 66.75,70.04 66.75,68.35 67.42,67.68 67.42,67.19 U3101.4 67.42,66.95 67.42,66.48 66.28,65.34 XF3101.23 ; 65.64,70.3 v1(65.64,69.97)
LAN_MDO3_N_C: length 26.3
  TOP w0.102: 64.56,52.28 v1(64.32,52.51) ; 64.56,52.28 62.43,50.15 62.43,41.15 64.41,39.16 66.53,37.04 66.53,36.07 66.44,35.98 66.14,35.98 66.05,35.89 RJ1.8 ; 64.56,52.28 65.46,53.18 66.42,53.18 66.61,53.37 66.61,53.61 66.28,53.93 XF3101.2
LAN_MDO3_P: length 12.4
  TOP w0.102: L3102.4 64.73,72.37 64.55,72.19 64.55,71.85 EC3107.1 64.6,71.13 64.6,70.84 64.78,70.66 66.48,70.66 67.11,70.23 67.11,69.65 U3101.3 67.11,69.27 67.11,68.5 67.78,67.83 67.78,66.33 66.95,65.51 66.95,65.36 67.28,65.03 XF3101.22
LAN_MDO3_P_C: length 26.3
  TOP w0.102: RJ1.7 67.32,35.89 67.24,35.98 66.94,35.98 66.89,36.03 66.89,37.19 64.76,39.31 62.78,41.29 62.78,50 63.85,51.07 ; 63.85,51.07 65.6,52.82 66.57,52.82 66.96,53.22 66.96,53.56 67.28,53.88 XF3101.3 ; 63.85,51.07 v1(64.08,50.84)
LAN_PCIE_RX_N: length 2.5
  BOTTOM w0.102: C3145.1 60.94,88.04 60.94,87.35 61.29,87 61.29,86.73 61.38,86.64 LAN1.18
LAN_PCIE_RX_N_C: length 191.1
  TOP w0.102: v3(172.46,36.59) 172.83,36.96 CPU1.CP7
  L4 w0.114: v3(61.27,91.83) 61.27,92.5 60.99,92.78 57.6,92.78 56.08,91.27 56.08,80.83 54.97,79.71 54.97,77.72 57.94,74.75 58.35,74.75 62.71,70.38 78.89,70.38 81.31,67.96 81.31,54.71 82.37,53.65 82.37,38.83 81.77,38.23 81.77,35.74 83.96,33.55 87.38,33.55 91.26,29.68 95.81,29.68 96.31,29.17 99.64,29.17 103.86,24.96 105.68,24.96 107.53,23.11 120.96,23.11 122.54,24.69 127.03,24.69 127.27,24.93 129.62,24.93 130.02,24.52 143.42,24.52 144.66,25.76 148.46,25.76 149.02,25.21 152.68,25.21 155.38,27.91 157.55,27.91 160.3,30.65 165.63,30.65 166.27,31.3 168.02,31.3 168.75,32.03 169.82,32.03 170.57,32.78 170.57,33.39 172.46,35.27 v3(172.46,36.59)
  BOTTOM w0.102: v1(61.44,90.29) 61.05,90.29 ; 61.05,90.29 61.05,89.51 61.27,89.29 C3145.2 ; 61.05,90.29 61.05,90.72 61.27,90.95 v3(61.27,91.83)
LAN_PCIE_RX_P: length 2.5
  BOTTOM w0.102: LAN1.17 60.98,86.64 61.09,86.75 61.09,86.92 60.74,87.26 60.74,88.03 C3146.1
LAN_PCIE_RX_P_C: length 191.6
  TOP w0.102: v3(171.79,36.59) 171.79,36.76 172.06,37.03 CPU1.CP6
  L4 w0.114: v3(171.79,36.59) 171.79,36.25 171.87,36.17 172.12,36.17 172.23,36.06 172.23,35.36 170.35,33.48 170.35,32.88 169.73,32.26 168.66,32.26 167.92,31.53 166.18,31.53 165.53,30.88 160.2,30.88 157.46,28.14 155.29,28.14 152.59,25.44 149.11,25.44 148.56,25.99 144.56,25.99 143.32,24.75 130.12,24.75 129.71,25.16 127.17,25.16 126.93,24.92 122.45,24.92 120.87,23.34 107.62,23.34 105.77,25.19 103.95,25.19 99.74,29.4 96.41,29.4 95.91,29.9 91.35,29.9 87.48,33.78 84.05,33.78 82,35.83 82,38.14 82.6,38.73 82.6,53.75 81.54,54.81 81.54,68.06 78.98,70.61 62.8,70.61 58.44,74.98 58.03,74.98 55.2,77.81 55.2,79.62 56.31,80.73 56.31,91.17 57.69,92.56 60.9,92.56 61.04,92.41 61.04,92.25 60.6,91.81 v3(60.5,91.81)
  BOTTOM w0.102: C3146.2 60.31,89.34 60.31,89.7 60.45,89.83 60.74,89.83 60.84,89.93 60.84,90.81 61.07,91.03 61.07,91.34 60.96,91.45 60.67,91.45 60.5,91.63 v3(60.5,91.81) ; v3(171.79,36.59) v1(170.81,36.59)
LAN_PCIE_TX_N: length 8.7
  BOTTOM w0.102: C3132.2 55.92,86.29 55.92,87.27 56.32,87.68 56.86,87.68 ; v1(56.86,88.04) 56.86,87.68 ; 56.86,87.68 57.27,87.68 57.57,87.37 57.57,85.16 58.15,84.58 59.58,84.58 59.71,84.71 LAN1.14
LAN_PCIE_TX_N_C: length 170.1
  TOP w0.102: v3(168.16,32.36) 168.34,32.54 168.59,32.54 169.17,33.13 169.64,33.13 169.95,33.43 CPU1.DA2
  L4 w0.114: v3(56.31,79.32) 56.06,79.07 55.84,79.07 55.62,78.85 55.62,78 58.22,75.4 58.61,75.4 62.67,71.34 79.06,71.34 81.96,68.45 81.96,54.98 83.02,53.92 83.02,38.45 82.43,37.87 82.43,36.02 84.25,34.2 87.69,34.2 91.5,30.39 96.04,30.39 96.58,29.85 99.88,29.85 104.12,25.62 106.07,25.62 107.92,23.76 120.58,23.76 122.16,25.34 126.76,25.34 127.02,25.6 132.51,25.6 133.14,26.22 144.01,26.22 144.42,26.64 148.58,26.64 149.07,26.15 152.53,26.15 155.07,28.68 157.41,28.68 160.17,31.44 163.85,31.44 164.93,32.52 167.99,32.52 v3(168.16,32.36)
  BOTTOM w0.102: 55.8,83.03 55.8,81.24 56.84,80.2 56.84,79.17 56.74,79.07 56.57,79.07 v3(56.31,79.32) ; 55.8,83.03 v1(55.43,83.03) ; 55.8,83.03 C3132.1
LAN_PCIE_TX_P: length 8.7
  BOTTOM w0.102: LAN1.13 59.71,84.31 59.64,84.38 58.06,84.38 57.85,84.59 ; v1(57.59,84.34) 57.85,84.59 ; 57.85,84.59 57.36,85.08 57.36,87.29 57.18,87.47 56.41,87.47 56.12,87.19 56.12,86.86 56.22,86.75 56.53,86.75 56.68,86.6 C3131.2
LAN_PCIE_TX_P_C: length 170
  TOP w0.102: v3(168.2,33.07) 168.2,32.84 168.29,32.75 168.5,32.75 169.09,33.33 169.4,33.33 CPU1.DA1
  L4 w0.114: v3(56.31,78.61) 56.08,78.84 55.93,78.84 55.85,78.75 55.85,78.09 58.32,75.62 58.71,75.62 62.76,71.57 79.16,71.57 82.19,68.54 82.19,55.08 83.25,54.02 83.25,38.36 82.66,37.77 82.66,36.12 84.35,34.43 87.78,34.43 91.59,30.61 96.14,30.61 96.67,30.08 99.98,30.08 104.21,25.84 106.16,25.84 108.02,23.99 120.49,23.99 122.07,25.57 126.67,25.57 126.93,25.83 132.42,25.83 133.04,26.45 143.91,26.45 144.32,26.87 148.68,26.87 149.17,26.38 152.44,26.38 154.97,28.91 157.31,28.91 160.08,31.67 163.76,31.67 164.84,32.75 167.6,32.75 167.7,32.85 167.7,33.11 167.81,33.22 168.04,33.22 v3(168.2,33.07)
  BOTTOM w0.102: 56,81.78 v1(56.37,81.78) ; 56,81.78 56,81.33 57.04,80.28 57.04,79.09 56.82,78.87 56.57,78.87 v3(56.31,78.61) ; 56,81.78 56,84.55 56.1,84.65 56.58,84.65 56.68,84.76 C3131.1
LAN_RSET: length 3.2
  BOTTOM w0.102: R3102.2 66.51,81.49 v1(65.98,82.02) 65.17,82.83 65.17,83 65.05,83.11 LAN1.31
LAN_WAKE#: length 297.9
  TOP w0.114: v3(49.25,65.54) 49.22,65.54 49.78,66.1 56.7,66.1 57.4,65.4 58.82,65.4 59.48,66.06 59.48,67.63 60.5,68.65 60.5,69.39 61.3,70.19 61.3,74.43 61.44,74.57 v3(61.44,74.57) ; v3(67.95,78.64) 68.37,79.05 R3141.1 ; v3(202.44,6.33) 202.69,6.08 204.15,6.08 206.94,8.87 206.94,10.84 202.63,15.15 202.63,17.8 R1714.1 202.99,18.16 202.99,24.78 201.26,26.52 201.26,26.82 200.12,27.96 198.96,27.96 195.76,31.16 195.25,31.16 195.06,30.97 194.64,30.97 194.18,31.43 192.83,31.43 192.6,31.66 192.6,31.69 192.34,31.69 CPU1.DE47
  L3 w0.127: v3(35.94,60.7) 38.96,60.7 39.53,60.13 42.52,60.13 v3(42.67,60.28) ; v3(67.95,78.64) 66.77,77.45 64.32,77.45 61.44,74.57 v3(61.44,74.57)
  L4 w0.127: v3(194.66,1.66) 194.84,1.66 199.52,6.33 v3(202.44,6.33) ; v3(35.94,60.7) 37.88,60.7 38.24,61.07 40.15,61.07 40.43,60.79 40.43,53.74 44.49,49.68 44.49,46.64 44.74,46.39 44.74,31.09 47.43,28.41 47.85,28.41 51.49,24.77 51.49,20.99 52.82,19.66 52.82,17.09 60.36,9.55 62.48,9.55 68.67,3.36 74.32,3.36 75.2,4.24 79.01,4.24 81.31,1.94 135.06,1.94 v3(135.28,2.16)
  BOTTOM w0.114: v3(49.25,65.54) 46.69,62.98 v1(46.09,62.98) 45.37,62.98 v3(42.67,60.28) ; v3(135.28,2.16) 135.61,1.83 135.61,1.73 135.74,1.59 144.44,1.59 145.8,2.95 154.42,2.95 155.11,2.27 156.84,2.27 156.95,2.16 156.95,1.77 157.22,1.5 158.25,1.5 158.53,1.22 182.63,1.22 183.07,1.66 v3(194.66,1.66)
LAN_WAKE#_R: length 26.5
  TOP w0.114: R3141.2 68.37,81.26 68.12,81.5 68.12,81.85 68.63,82.36 Q3111.D 68.91,84.98 70.58,84.98 v3(71.44,84.12) ; R3142.1 64.76,90.84 64.65,90.96 64.65,91.44 64.66,91.46 64.66,91.47 65.43,92.23 65.43,93.36 v3(65.24,93.55)
  BOTTOM w0.114: v3(65.24,93.55) 65.9,92.89 66.19,92.89 66.31,93 70.96,93 71.55,92.42 71.55,92.41 71.7,92.26 v1(71.7,85.72) 71.7,84.37 v3(71.44,84.12)
LAN_WAKEB: length 27.8
  TOP w0.114: v3(62.65,88.5) 62.83,88.32 v1(63.88,88.32) 64.55,88.98 65.64,88.98 65.79,89.14 R3144.1 64.76,89.45 R3142.2 64.63,89.45 64.3,89.77 64.3,91.89 v3(64.37,91.96) ; Q3111.S 69.62,83.66 70.02,84.06 v3(70.69,84.06)
  BOTTOM w0.114: v3(64.37,91.96) 64.98,92.58 65.76,92.58 65.77,92.57 66.33,92.57 66.33,92.58 70.94,92.58 71.23,92.28 71.23,86.06 71.13,85.95 71.13,85.6 71.13,85.6 71.13,84.5 v3(70.69,84.06) ; LAN1.21 62.58,87.33 62.67,87.42 62.67,87.8 62.67,87.8 62.67,88.48 v3(62.65,88.5)
LAN_XTAL1: length 8.7
  BOTTOM w0.114: X3101.1 71.48,82.34 71.24,82.58 68.81,82.58 C3126.2 68.58,82.59 R3121.1 67.71,83.33 v1(66.78,84.26) 66.29,84.26 66.03,83.99 65.5,83.99 65.17,84.31 LAN1.28
LAN_XTAL2: length 5
  BOTTOM w0.114: LAN1.29 65.23,83.91 65.51,83.64 66.18,83.64 v1(66.83,82.99) 67.38,82.44 R3121.2 67.84,81.9 67.84,81.9 R3150.2
LAN_XTAL2_R: length 2.9
  BOTTOM w0.114: R3150.1 67.96,80.67 C3127.2 69.99,80.67 X3101.3
LCD_5V_ON1: length 7.3
  BOTTOM w0.114: R5537.2 64.12,22.22 64.11,22.22 64.11,21.74 C5559.1 64.17,21.68 C5545.1 64.16,20.8 R5536.1 63.09,19.41 v1(63.53,18.97) 63.59,19.03 U5504.4
LDO1_CAP: length 5.8
  TOP w0.203: 26.93,73.7 27.59,73.04 U2701.27
  TOP w0.254: C2702.2 25.91,76.52 R2711.2 26.29,76.13 v1(26.29,75.02) 26.29,74.34 26.93,73.7
LDO2_CAP: length 5.4
  TOP w0.203: 30.02,67.6 U2701.39
  TOP w0.254: C2712.2 27.31,65.38 v1(27.31,66.55) 27.59,66.84 29.26,66.84 30.02,67.6
LDO3_CAP: length 3.3
  TOP w0.203: U2701.7 35.53,71.84
  TOP w0.254: 35.53,71.84 36.49,71.84 v1(36.62,71.71) 36.67,71.75 C2718.1
LDRQ#: length 6.2
  TOP w0.102: R24021.1 95.54,15.68 94.48,15.68 94.28,15.87 93.24,15.87 v1(92.87,16.24) 92.53,16.24 92.15,15.87 91.31,15.87 91.22,15.78 ECIO1.45
LED2_N: length 2.7
  TOP w0.381: R6802.1 v1(8.11,87.79) 7.5,88.4 LED683.2K
LED2_P: length 3.9
  TOP w0.381: LED683.1A 9.87,89.1 10.09,89.32 v1(10.83,89.32) 10.85,89.34 Q6803.D
LED9_N: length 4.2
  TOP w0.381: LED685.2K v1(10.94,86.41) 11.59,85.76 Q6805.D
LED9_P: length 4.3
  TOP w0.381: LED685.1A 8.09,85.58 9,85.58 v1(9.55,85.03) 9.44,85.03 8.7,84.29 R6806.1
LED10_N: length 2.6
  TOP w0.381: LED684.2K 7.54,91.1 v1(8.11,90.52) R6807.1
LED10_P: length 4.2
  TOP w0.381: LED684.1A 9.85,91.8 v1(10.98,92.93) Q6801.D
LED_GND: length 13.9
  TOP w0.305: U5501.15 17.65,27.65 v3(18.65,28.65)
  TOP w0.508: v3(25.3,31.16) 25.29,31.16 24.96,31.49 24.95,31.49 24.93,31.51 C5505.2 ; C5520.2 24.48,29.57 v3(25.01,29.04) ; R5507.2 12.21,28.99 C5509.2 ; v3(13.94,28.55) 13.26,28.55 12.47,27.76 C5509.2 ; C5509.2 12.21,26.92 v1(12.61,26.52) ; C5504.1 26.1,27.69 25.59,28.2 v3(25.05,28.2) 24.52,28.2 R5521.2 ; C5501.2 v3(19.9,24.09)
  vias: v3(15.25,36.33) v3(15.96,36.31)
LINE1_L: length 3.7
  TOP w0.203: C2723.1 28.96,77.22 28.75,77.01 v1(28.75,76.63) 28.75,76.5 30.02,75.22 U2701.22
LINE1_R: length 3.3
  TOP w0.203: C2724.1 30.23,77.34 30.07,77.19 30.07,76.41 ; 30.07,76.41 30.07,75.92 30.42,75.56 U2701.21 ; 30.07,76.41 v1(30.08,76.41)
LINE1_VREFO_L: length 19.9
  TOP w0.203: RN2703.3 30.47,80.54 30.97,80.04 v3(31.03,80.04) ; v3(24.38,73.78) 24.38,72.58 v1(24.43,72.53) 24.55,72.53 25.04,72.03 25.14,72.03 25.73,71.44 U2701.31
  L3 w0.203: v3(31.03,80.04) 31.15,80.04 31.71,80.6 31.71,81.02 31.34,81.39 29.89,81.39 24.38,75.88 v3(24.38,73.78)
LINE1_VREFO_R: length 17.7
  TOP w0.203: RN2703.4 30.39,81.19 30.93,81.73 31.57,81.73 v1(31.78,81.52) 31.78,81.38 v3(31.2,80.81) ; U2701.30 26.06,71.84 25.07,72.83 v3(25.07,73.3)
  L3 w0.203: v3(25.07,73.3) 25.07,75.74 30.14,80.81 v3(31.2,80.81)
LPC_PME#: length 4.7
  TOP w0.102: R24078.1 88.57,28.53 v1(87.64,27.59) 86.68,26.64 86.68,26.07 86.4,25.78 ECIO1.70
LPSS_UART2_RXD: length 98.9
  TOP w0.114: R2001.2 180.46,16.93 v3(180.12,17.28) 179.9,17.5 v1(179.9,18.69) 179.9,18.97 179.61,19.26 179.61,21.81 180.18,22.38 180.18,23.01 179.62,23.57 179.62,26.1 CPU1.DT22 ; v3(104.44,11.24) 103.82,11.87 RN6120.1 102.96,13.4 102.84,13.52 DBGH1.14
  L3 w0.127: v3(180.12,17.28) 179.65,17.75 176.95,17.75 176,18.7 167.66,18.7 165.79,16.83 165.79,16.25 163.06,13.52 161.75,13.52 160.18,11.95 155.36,11.95 153.86,10.45 134.59,10.45 133.8,9.66 126.96,9.66 125.84,10.78 116.67,10.78 114.48,8.59 107.09,8.59 v3(104.44,11.24)
LPSS_UART2_TXD: length 101.3
  TOP w0.114: CPU1.DW22 179.95,24.39 179.95,23.54 180.43,23.07 180.43,22.29 180.56,22.16 180.56,20.48 180.48,20.4 180.48,18.93 181.54,17.87 181.54,17.28 v3(181.53,17.27) 181.54,17.26 R2002.2 ; DBGH1.13 102.32,16.3 101.88,15.86 101.88,14 v1(102.05,13.83) 102.31,13.57 RN6120.2 102.31,11.47 102.43,11.35 v3(103.61,11.35)
  L3 w0.127: v3(181.53,17.27) 181.18,16.91 181.1,16.91 180.99,16.81 177.18,16.81 175.79,18.19 167.87,18.19 166.33,16.65 166.33,16.06 163.27,13.01 161.96,13.01 160.4,11.44 155.57,11.44 154.07,9.94 134.8,9.94 134.01,9.15 126.75,9.15 125.63,10.27 116.88,10.27 114.69,8.08 106.88,8.08 v3(103.61,11.35)
LVDS1_PIN4_PD: length 4.1
  TOP w0.102: LVDS1.4 33,12.62 v3(33.2,12.42)
  BOTTOM w0.102: R5531.1 34.23,13.45 v1(33.82,13.04) v3(33.2,12.42)
LVDS_TXE_N0: length 39.6
  TOP w0.102: 59.83,20.08 61.23,18.68 61.23,18.38 C5508.2 61.24,17.59 61.24,16.75 60.22,15.73 59.09,15.73 58.6,15.25 58.6,15 59,14.6 LVDS1.30 ; 59.83,20.08 59.32,20.59 56.38,20.59 54.76,22.21 52.14,22.21 51.06,23.28 47.77,23.28 45.04,26.01 44.12,26.01 43.56,26.58 40.33,26.58 37.01,29.9 36.43,29.9 36.3,30.03 36.3,30.13 v3(36.6,30.43) ; 59.83,20.08 v1(60.1,20.35)
  BOTTOM w0.102: v3(36.6,30.43) 36.27,30.1 36.27,29.11 36.34,29.03 TSMT1.32
LVDS_TXE_N1: length 39
  TOP w0.102: v3(35.52,31.21) 35.26,30.95 35.26,30.02 36.09,29.18 36.57,29.18 40.46,25.3 44.7,25.3 47.45,22.55 50.44,22.55 50.74,22.55 51.81,21.47 54.41,21.47 56.01,19.88 57.17,19.88 58.6,18.45 ; 58.6,18.45 58.6,17.34 C5514.2 58.56,16.56 58.56,16.24 58.05,15.73 57.22,15.73 56.64,15.14 56.64,14.98 57,14.62 LVDS1.28 ; 58.6,18.45 v1(58.83,18.69)
  BOTTOM w0.102: v3(35.52,31.21) 35.26,30.95 35.26,29.73 35.45,29.54 35.45,29.12 35.54,29.03 TSMT1.30
LVDS_TXE_N2: length 39.6
  TOP w0.102: 54.6,19.59 53.48,20.71 51.45,20.71 50.38,21.78 47.13,21.78 44.33,24.59 43.58,24.59 43.35,24.35 43.35,23.24 43.25,23.14 42.97,23.14 42.86,23.24 42.86,23.89 42.63,24.12 42.16,24.12 41.92,23.89 41.92,23.24 41.82,23.14 41.54,23.14 41.44,23.24 41.44,24.29 41.21,24.53 40.17,24.53 36.24,28.45 35.76,28.45 34.11,30.1 34.11,30.29 v3(34.37,30.54) ; 54.6,19.59 55.1,19.09 55.44,19.09 55.79,18.75 55.79,18.42 C5517.2 55.78,17.64 55.78,16.44 54.61,15.27 54.61,15 55,14.61 LVDS1.26 ; 54.6,19.59 v1(54.87,19.86)
  BOTTOM w0.102: v3(34.37,30.54) 34.09,30.26 34.09,30.03 34.65,29.47 34.65,29.13 34.74,29.03 TSMT1.28
LVDS_TXE_N3: length 39
  TOP w0.102: v3(31.08,29.3) 31.08,29.2 31.27,29.01 32.02,29.01 32.45,28.57 33.4,28.57 35.12,26.86 35.67,26.86 36.47,26.05 36.47,24.91 37.15,24.23 38.27,24.23 39.5,23 39.5,21.82 40.44,20.88 42.33,20.88 42.56,20.64 42.56,20.02 42.67,19.92 42.95,19.92 43.05,20.02 43.05,21.47 43.28,21.71 43.75,21.71 43.99,21.47 43.99,20.44 44.09,20.34 44.37,20.34 44.47,20.44 44.47,21.4 44.71,21.63 45.17,21.63 45.41,21.4 45.41,20.44 45.51,20.34 48.5,20.34 50.2,18.63 50.2,18.46 C5519.2 50.24,17.64 50.24,16.65 ; LVDS1.21 50,14.91 50.24,15.15 50.24,16.65 ; 50.24,16.65 v1(50.62,16.65)
  BOTTOM w0.102: v3(31.08,29.3) 31.35,29.02 31.59,29.02 31.83,28.79 31.83,27.69 31.93,27.59 32.1,27.59 32.18,27.67 TSMT1.24
LVDS_TXE_NC: length 39.8
  TOP w0.102: 52.62,18.79 52.62,19.64 52.36,19.9 50.95,19.9 50.54,19.49 50.4,19.49 50.2,19.69 50.2,19.83 50.51,20.14 50.51,20.48 49.92,21.07 46.81,21.07 45.52,22.37 45.07,22.37 44.97,22.47 44.97,22.91 44.73,23.15 44.27,23.15 44.03,22.91 44.03,22.53 43.93,22.43 42.3,22.43 42.06,22.19 42.06,21.71 41.96,21.61 41.68,21.61 41.58,21.71 41.58,22.19 41.34,22.43 40.83,22.43 40.6,22.2 40.46,22.2 40.26,22.4 40.26,22.55 40.49,22.77 40.49,23.1 38.65,24.94 37.51,24.94 37.19,25.26 37.19,26.43 35.93,27.68 35.31,27.68 33.24,29.75 32.97,29.75 v3(32.74,29.98) ; 52.62,18.79 v1(53,18.79) ; 52.62,18.79 52.62,18.38 53.3,17.7 53.3,17.55 C5522.2 53.34,16.73 53.34,16.38 53.04,16.08 52.05,16.08 51.71,15.75 51.71,15.16 52,14.88 LVDS1.23
  BOTTOM w0.102: v3(32.74,29.98) 32.95,29.77 33.58,29.77 33.95,29.41 33.95,29.24 33.94,29.24 TSMT1.26
LVDS_TXE_P0: length 39.6
  TOP w0.102: 58.4,20.36 59.22,20.36 61,18.58 61,18.37 C5507.2 61.01,17.59 61.01,16.85 60.13,15.96 58.99,15.96 58.37,15.34 58.37,14.97 58,14.6 LVDS1.29 ; 58.4,20.36 56.29,20.36 54.67,21.98 52.04,21.98 50.97,23.05 47.67,23.05 44.95,25.78 44.03,25.78 43.46,26.35 40.24,26.35 36.92,29.67 36.33,29.67 36.05,29.95 36.05,30.12 v3(35.74,30.43) ; 58.4,20.36 v1(58.4,19.98)
  BOTTOM w0.102: TSMT1.31 35.94,29.05 36.04,29.15 36.04,30.13 v3(35.74,30.43)
LVDS_TXE_P1: length 39.1
  TOP w0.102: 56.77,15.6 56.41,15.24 56.41,15.02 56,14.61 LVDS1.27 ; 56.77,15.6 v1(56.54,15.84) ; 56.77,15.6 57.13,15.96 57.96,15.96 58.33,16.33 58.33,16.59 C5513.2 58.37,17.39 58.37,18.35 57.07,19.65 55.91,19.65 54.32,21.25 51.71,21.25 50.64,22.32 50.44,22.32 47.36,22.32 44.6,25.07 40.36,25.07 36.48,28.96 36,28.96 35.03,29.92 35.03,30.84 v3(34.66,31.21)
  BOTTOM w0.102: TSMT1.29 35.14,29.04 35.22,29.11 35.22,29.45 35.03,29.64 35.03,30.85 v3(34.66,31.21)
LVDS_TXE_P2: length 39.5
  TOP w0.102: LVDS1.25 54,14.61 54.38,14.99 54.38,15.37 54.81,15.8 ; 54.81,15.8 55.55,16.54 55.55,17.64 C5516.2 55.56,18.44 55.56,18.66 55.35,18.86 55,18.86 53.38,20.48 51.36,20.48 50.29,21.56 47.04,21.56 44.24,24.36 43.68,24.36 43.58,24.26 43.58,23.15 43.34,22.91 42.87,22.91 42.64,23.15 42.64,23.79 42.53,23.89 42.25,23.89 42.15,23.79 42.15,23.15 41.92,22.91 41.45,22.91 41.21,23.15 41.21,24.2 41.11,24.3 40.07,24.3 36.15,28.22 35.67,28.22 33.88,30 33.88,30.26 v3(33.6,30.54) ; 54.81,15.8 v1(54.54,16.07)
  BOTTOM w0.102: v3(33.6,30.54) 33.86,30.29 33.86,29.94 34.42,29.38 34.42,29.09 34.34,29.02 TSMT1.27
LVDS_TXE_P3: length 39.1
  TOP w0.102: 39.98,21.02 39.27,21.72 39.27,22.9 38.17,24 37.05,24 36.24,24.81 36.24,25.96 35.57,26.63 35.03,26.63 33.31,28.35 32.36,28.35 31.93,28.78 31.34,28.78 v3(31.08,28.52) ; 39.98,21.02 v1(39.7,20.74) ; 39.98,21.02 40.35,20.65 42.23,20.65 42.34,20.55 42.34,19.92 42.57,19.69 43.04,19.69 43.28,19.92 43.28,21.38 43.38,21.48 43.66,21.48 43.76,21.38 43.76,20.34 43.99,20.11 44.46,20.11 44.7,20.34 44.7,21.3 44.8,21.41 45.08,21.41 45.18,21.3 45.18,20.34 45.42,20.11 48.4,20.11 49.98,18.53 49.98,18.39 C5518.2 50.01,17.64 50.01,15.25 49.85,15.09 49.4,15.09 49,14.69 LVDS1.20
  BOTTOM w0.102: v3(31.08,28.52) 31.35,28.79 31.5,28.79 31.6,28.69 31.6,27.6 31.83,27.36 32.13,27.36 32.21,27.27 TSMT1.23
LVDS_TXE_PC: length 39.8
  TOP w0.102: LVDS1.22 51,14.93 51.1,15.04 51.38,15.04 51.49,15.14 51.49,15.84 51.95,16.31 52.95,16.31 53.11,16.47 53.11,16.73 C5521.2 53.08,17.48 53.08,17.6 52.39,18.29 52.39,19.54 52.26,19.67 51.05,19.67 50.64,19.26 50.31,19.26 49.97,19.59 49.97,19.93 50.28,20.24 50.28,20.38 49.82,20.84 49.24,20.84 ; v3(32.74,29.13) 32.74,29.44 32.82,29.52 33.14,29.52 35.21,27.45 35.84,27.45 36.96,26.33 36.96,25.17 37.41,24.71 38.55,24.71 40.26,23.01 40.26,22.86 40.03,22.64 40.03,22.31 40.37,21.97 40.7,21.97 40.92,22.2 41.25,22.2 41.35,22.1 41.35,21.62 41.58,21.38 42.05,21.38 42.29,21.62 42.29,22.1 42.39,22.2 44.02,22.2 44.26,22.43 44.26,22.82 44.36,22.92 44.64,22.92 44.74,22.82 44.74,22.37 44.98,22.14 45.42,22.14 46.72,20.84 49.24,20.84 ; 49.24,20.84 v1(49.24,20.46)
  BOTTOM w0.102: TSMT1.25 33.54,28.99 33.72,29.17 33.72,29.24 33.72,29.31 33.49,29.54 32.87,29.54 32.74,29.41 v3(32.74,29.13)
LVDS_TXO_N0: length 39.6
  TOP w0.102: LVDS1.19 48,14.62 47.63,14.99 47.63,15.67 47.76,15.8 47.76,16.26 C5524.2 47.83,17.06 47.83,18.3 47.72,18.41 47.72,19.2 v3(48.1,19.58)
  L4 w0.102: v3(48.1,19.58) 47.85,19.83 47.85,20.59 47.62,20.83 45.85,20.83 45.75,20.93 45.75,21.21 45.85,21.31 47.84,21.31 48.08,21.55 48.08,22.01 47.84,22.25 43.38,22.25 43.28,22.35 43.28,22.63 43.38,22.73 47.07,22.73 47.31,22.97 47.31,23.44 47.07,23.67 43.44,23.67 43.34,23.77 43.34,24.05 43.44,24.16 45.31,24.16 45.54,24.39 45.54,25.04 45.31,25.27 42.09,25.27 41.99,25.37 41.99,25.58 v3(42.23,25.82)
  BOTTOM w0.102: v3(48.1,19.58) 48.35,19.84 v1(48.35,20.42) ; TSMT1.42 39.31,25.67 39.37,25.73 39.73,25.73 40.37,25.09 41.52,25.09 41.88,25.45 41.88,25.72 41.99,25.82 v3(42.23,25.82)
LVDS_TXO_N1: length 39.8
  TOP w0.102: LVDS1.16 45,14.6 44.63,14.96 44.63,15.25 44.96,15.57 44.96,15.92 45.11,16.08 45.11,17.19 C5526.2 45.16,17.97 45.16,18.8 45.21,18.84 45.21,19.31 v3(45.43,19.54)
  L4 w0.102: v3(42.02,27.25) 41.71,26.94 41.71,26.58 41.48,26.34 40.28,26.34 40.08,26.14 40.08,25.87 39.85,25.63 38.56,25.63 38.46,25.53 38.46,25.25 38.56,25.15 39.85,25.15 40.08,24.91 40.08,24.54 40.2,24.42 40.34,24.42 40.87,24.94 41.2,24.94 41.53,24.61 41.53,24.28 41.01,23.75 41.01,23.61 42.36,22.26 42.36,21.92 42.03,21.59 41.7,21.59 39.6,23.69 39.46,23.69 39.26,23.49 39.26,23.34 41.57,21.03 42.42,21.03 42.98,20.47 42.98,19.61 43.08,19.51 43.59,19.51 43.69,19.61 43.69,21.15 43.95,21.41 44.49,21.41 44.73,21.18 44.73,20.47 45.24,19.96 45.24,19.74 v3(45.43,19.54)
  BOTTOM w0.102: TSMT1.40 39.34,26.47 39.43,26.56 40.33,26.56 40.47,26.42 41.47,26.42 41.71,26.66 41.71,26.94 v3(42.02,27.25) ; v3(45.43,19.54) 45.43,19.17 45.04,18.78 v1(45.04,18.19)
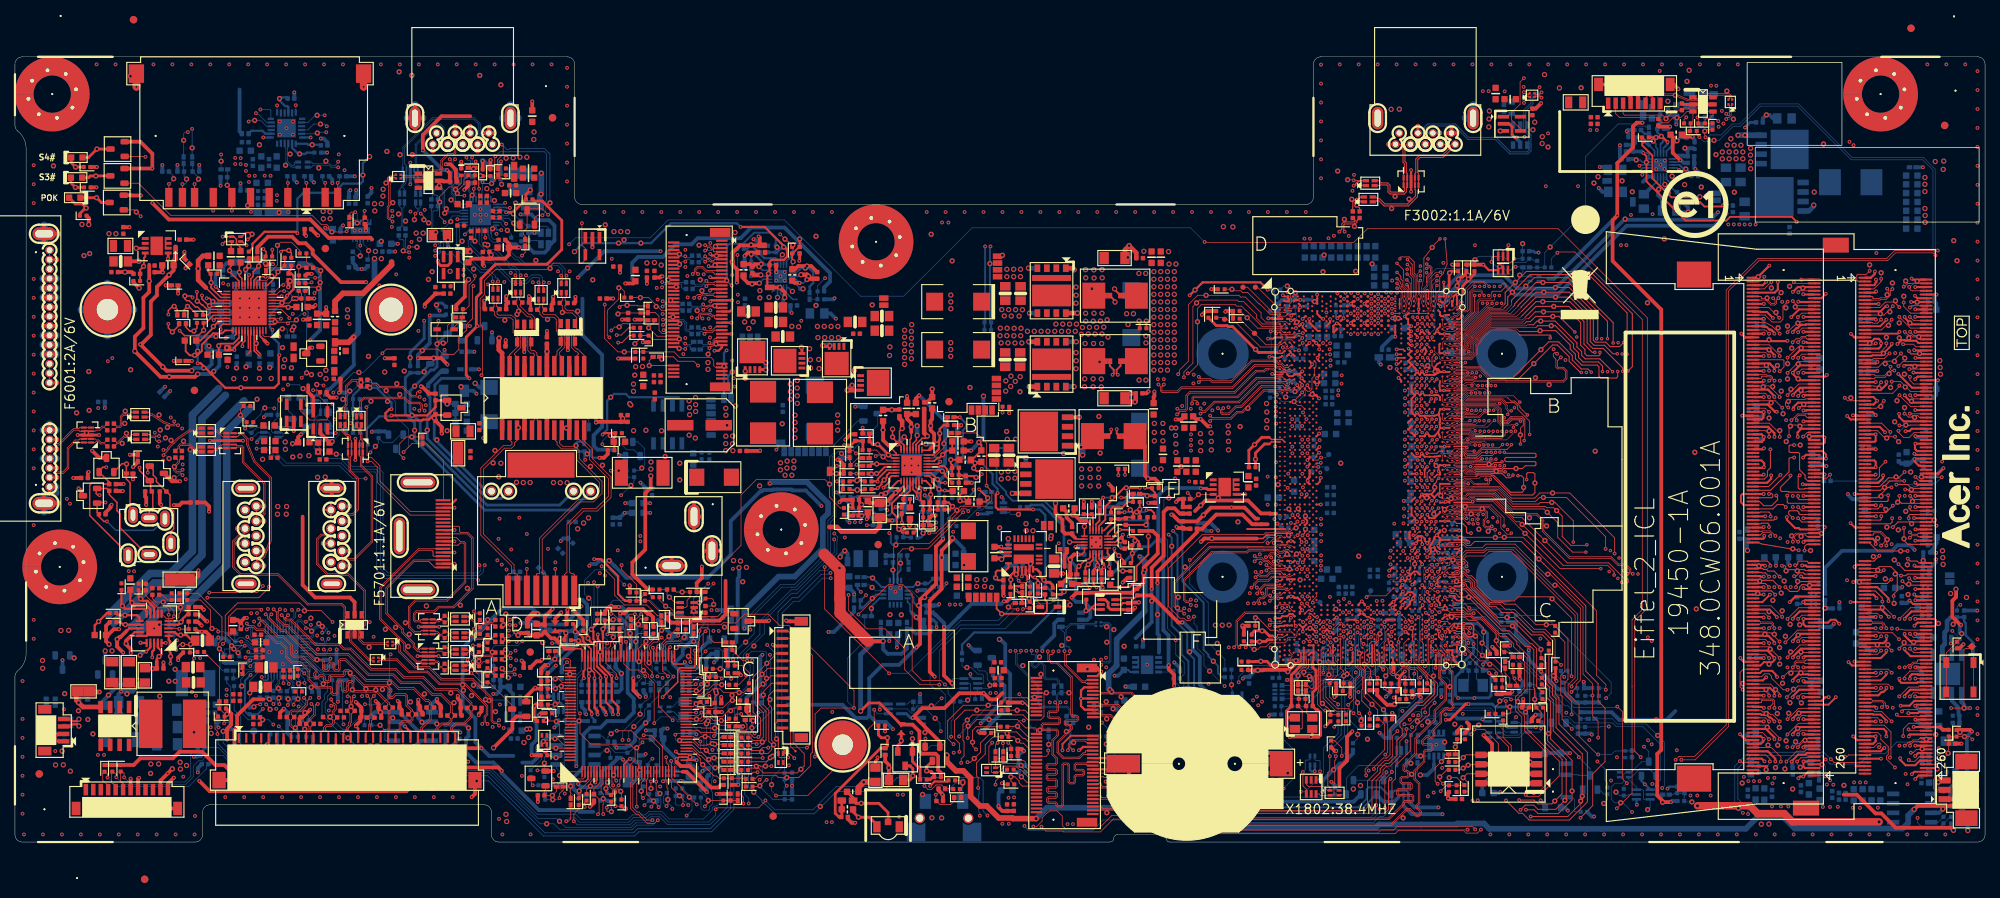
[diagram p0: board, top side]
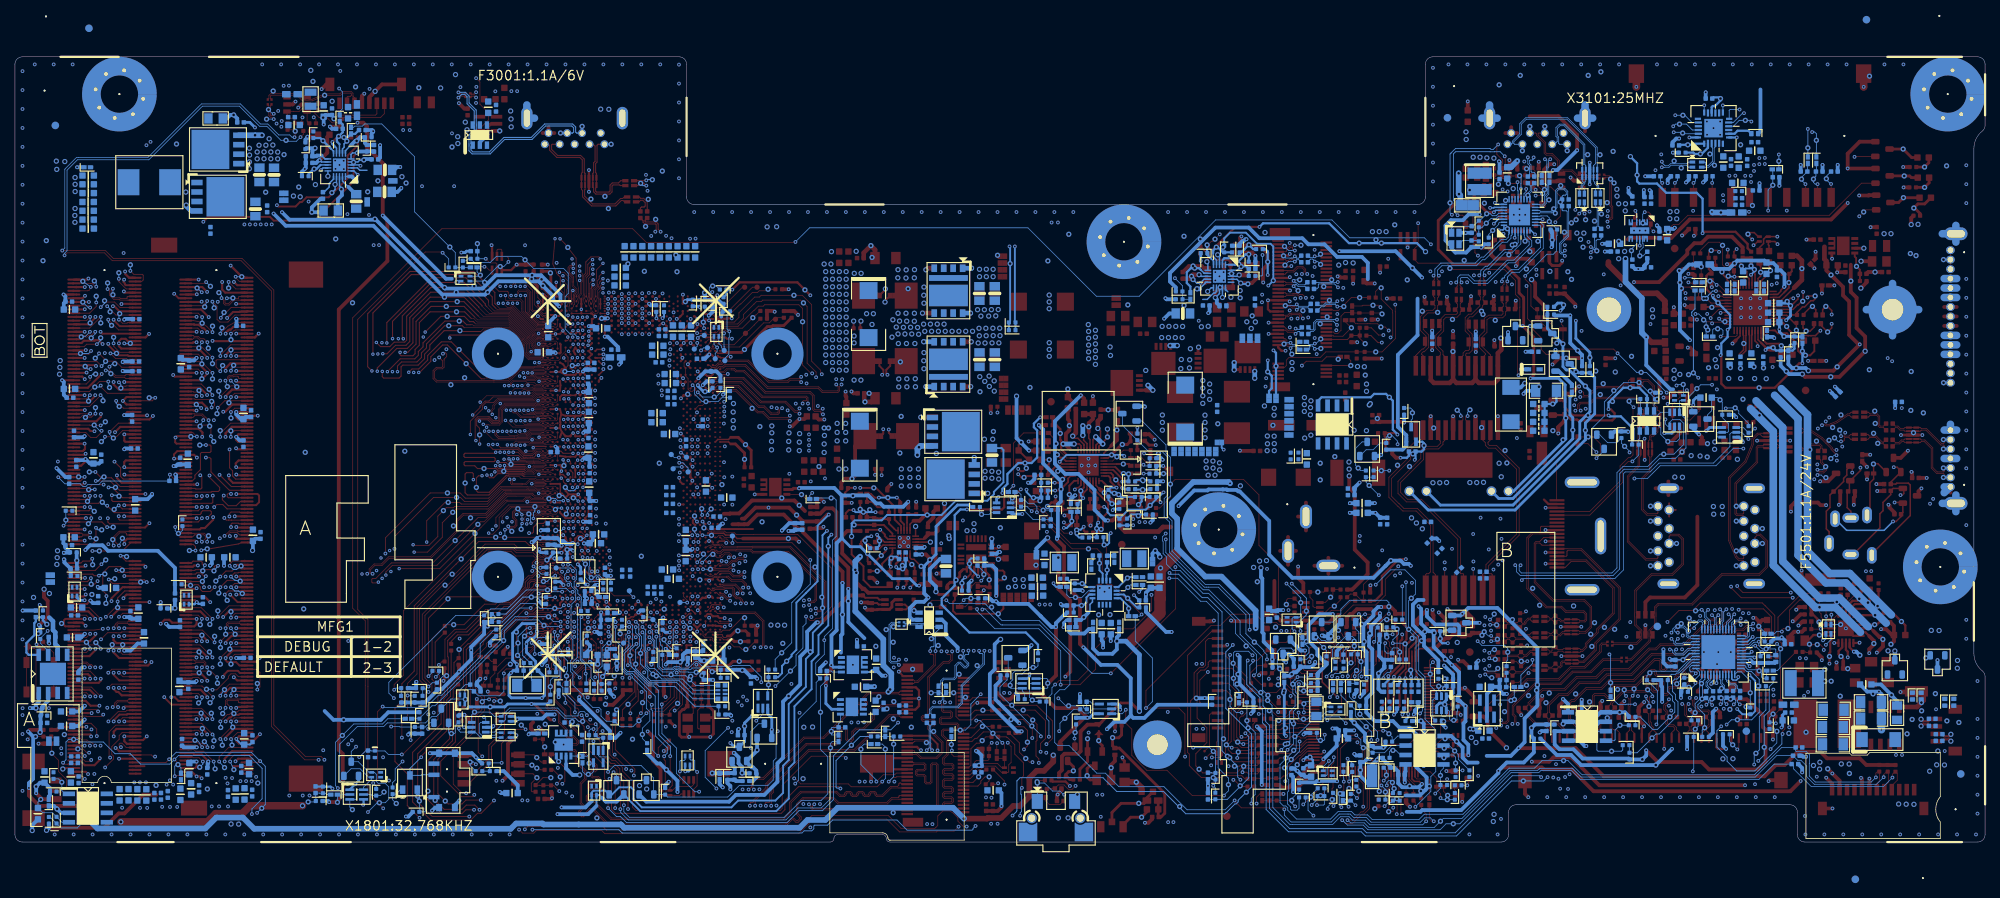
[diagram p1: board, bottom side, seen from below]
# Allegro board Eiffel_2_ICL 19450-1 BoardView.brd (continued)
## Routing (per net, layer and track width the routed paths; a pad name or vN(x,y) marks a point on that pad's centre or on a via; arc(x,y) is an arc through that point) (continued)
LVDS_TXO_N2: length 39.6
  TOP w0.102: v3(41.17,28.08) v1(41.17,28.92) ; v3(42.37,19.13) 42.37,18.95 42.72,18.59 42.82,18.59 43.05,18.36 43.05,17.75 42.75,17.45 42.75,17.16 C5530.2 42.78,16.3 42.78,15.86 42.42,15.49 41.81,15.49 41.59,15.27 41.59,15.08 42,14.67 LVDS1.13
  L4 w0.102: v3(41.17,28.08) 41.47,28.08 41.58,28.19 41.58,28.44 41.06,28.96 40.41,28.96 40.31,28.85 40.31,28.14 40,27.84 37.19,27.84 37.08,27.74 37.08,27.46 37.19,27.36 39.34,27.36 39.57,27.12 39.57,26.65 39.34,26.42 37.29,26.42 37.16,26.29 37.16,26 36.92,25.76 36.58,25.76 36.47,25.66 36.47,25.38 36.58,25.28 36.92,25.28 37.16,25.04 37.16,24.63 37.36,24.43 37.51,24.43 37.72,24.64 38.05,24.64 38.38,24.31 38.38,23.93 38.08,23.63 38.08,22.9 37.22,22.04 37.22,21.9 37.42,21.7 37.56,21.7 37.91,22.05 39.52,22.05 41.73,19.83 41.73,18.85 41.91,18.67 42.11,18.67 42.37,18.93 v3(42.37,19.13)
  BOTTOM w0.102: v3(41.17,28.08) 41.39,28.08 41.62,28.31 41.62,28.49 41.38,28.73 40.39,28.73 40.05,28.39 40.05,27.61 39.81,27.37 39.46,27.37 39.36,27.27 TSMT1.38
LVDS_TXO_N3: length 40.2
  TOP w0.102: LVDS1.9 38,14.55 37.59,14.96 37.59,15.19 37.01,15.77 37.01,16.34 C5532.2 37.02,17.17 37.02,17.36 37.14,17.48 38.31,17.48 39.22,18.39 39.22,18.97 v3(39.58,19.33)
  L4 w0.102: v3(39.58,19.33) 39.26,19.65 39.26,19.93 39.07,20.12 38.06,20.12 37.22,19.28 36.83,19.28 36.73,19.38 36.73,19.5 36.49,19.74 36.02,19.74 35.79,19.5 35.79,19.38 35.69,19.28 32.84,19.28 32.72,19.41 32.72,19.66 32.82,19.76 34.92,19.76 35.15,20 35.15,20.47 34.92,20.7 34.11,20.7 34.01,20.8 34.01,22.21 33.2,23.03 33.2,24.28 33.3,24.39 33.52,24.39 33.76,24.62 33.76,25.09 33.52,25.33 33.1,25.33 33,25.43 33,26.42 34.89,28.31 34.89,28.64 34.59,28.95 34.59,29.09 34.79,29.29 34.93,29.29 35.23,28.99 35.56,28.99 35.92,29.34 37.06,29.34 37.66,29.93 37.66,30.83 v3(37.97,31.14)
  BOTTOM w0.102: v1(38.8,31.02) 38.4,31.02 38.28,31.14 v3(37.97,31.14) 37.62,30.79 37.62,30.15 37.06,29.59 37.06,29.15 37.14,29.07 TSMT1.34
LVDS_TXO_NC: length 39.9
  TOP w0.102: v3(40.58,18.52) 40.39,18.52 40.24,18.38 40.24,17.03 39.66,16.45 39.66,16.23 C5534.2 39.63,15.44 39.63,14.98 40,14.61 LVDS1.11 ; v1(39.75,28.28) 39.35,28.68 v3(38.99,28.68)
  L4 w0.102: v3(40.58,18.52) 40.4,18.52 40.3,18.62 40.3,20.26 39.73,20.83 37.75,20.83 37.4,20.47 36.16,20.47 34.93,21.7 34.93,22.09 36.01,23.17 36.16,23.17 36.58,22.74 36.92,22.74 37.26,23.09 37.26,23.49 36.14,24.61 35.69,24.61 34.3,23.22 34.15,23.22 33.96,23.42 33.96,23.57 35.1,24.71 35.1,25.5 36.39,26.78 36.39,27.14 36.07,27.46 35.73,27.46 34.43,26.16 34.29,26.16 34.09,26.36 34.09,26.5 36.16,28.57 37.8,28.57 38.3,29.08 38.86,29.08 38.99,28.95 v3(38.99,28.68)
  BOTTOM w0.102: v3(38.99,28.68) 38.99,28.85 38.28,29.56 38.02,29.56 37.85,29.39 37.85,29.17 37.94,29.08 TSMT1.36
LVDS_TXO_P0: length 39.6
  TOP w0.102: v3(47.22,19.61) 47.49,19.35 47.49,18.31 47.6,18.2 47.6,17.11 C5523.2 47.54,16.33 47.54,15.89 47.41,15.76 47.41,15 47,14.59 LVDS1.18
  L4 w0.102: v3(47.22,19.61) 47.24,19.59 47.52,19.59 47.62,19.7 47.62,20.5 47.52,20.6 45.75,20.6 45.52,20.83 45.52,21.3 45.75,21.54 47.75,21.54 47.85,21.64 47.85,21.92 47.75,22.02 43.29,22.02 43.05,22.26 43.05,22.73 43.29,22.96 46.98,22.96 47.08,23.06 47.08,23.34 46.98,23.44 43.35,23.44 43.11,23.68 43.11,24.15 43.35,24.38 45.21,24.38 45.31,24.49 45.31,24.94 45.21,25.04 41.99,25.04 41.76,25.28 41.76,25.6 41.54,25.82 v3(41.38,25.82)
  BOTTOM w0.102: TSMT1.41 39.3,26.07 39.42,25.96 39.83,25.96 40.47,25.32 41.43,25.32 41.65,25.54 41.65,25.72 41.55,25.82 v3(41.38,25.82) ; v3(47.22,19.61) 47.03,19.8 v1(47.03,20.53)
LVDS_TXO_P1: length 39.5
  TOP w0.102: LVDS1.15 44,14.59 44.4,15 44.4,15.34 44.73,15.67 44.73,16.02 44.89,16.17 44.89,17.23 C5525.2 44.93,18.02 44.93,18.89 44.98,18.94 44.98,19.41 44.85,19.54 v3(44.58,19.54)
  L4 w0.102: v3(44.58,19.54) 44.84,19.54 45.01,19.71 45.01,19.87 44.5,20.38 44.5,21.08 44.4,21.18 44.04,21.18 43.92,21.06 43.92,19.51 43.68,19.28 42.98,19.28 42.75,19.51 42.75,20.38 42.32,20.8 41.48,20.8 39.03,23.25 39.03,23.58 39.36,23.91 39.7,23.91 41.79,21.82 41.94,21.82 42.13,22.02 42.13,22.16 40.78,23.52 40.78,23.85 41.3,24.37 41.3,24.52 41.1,24.71 40.96,24.71 40.44,24.19 40.1,24.19 39.85,24.44 39.85,24.82 39.75,24.92 38.46,24.92 38.23,25.16 38.23,25.63 38.46,25.86 39.75,25.86 39.85,25.96 39.85,26.23 40.19,26.57 41.38,26.57 41.48,26.67 41.48,26.94 v3(41.17,27.25)
  BOTTOM w0.102: TSMT1.39 39.3,26.87 39.39,26.79 40.42,26.79 40.56,26.65 41.38,26.65 41.48,26.75 41.48,26.95 v3(41.17,27.25) ; v3(44.58,19.54) 44.58,19.79 v1(45.22,20.43)
LVDS_TXO_P2: length 39.1
  TOP w0.102: LVDS1.12 41,14.71 41.36,15.07 41.36,15.37 41.71,15.72 42.33,15.72 42.56,15.95 42.56,16.39 C5529.2 42.52,17.11 42.52,17.54 42.82,17.85 42.82,18.26 42.72,18.36 42.45,18.36 v3(42.37,18.28)
  L4 w0.102: v3(42.37,18.28) 42.21,18.44 41.82,18.44 41.5,18.75 41.5,19.74 39.42,21.82 38,21.82 37.66,21.47 37.32,21.47 36.99,21.8 36.99,22.14 37.85,22.99 37.85,23.72 38.15,24.02 38.15,24.21 37.95,24.41 37.81,24.41 37.6,24.2 37.27,24.2 36.93,24.54 36.93,24.95 36.83,25.05 36.48,25.05 36.25,25.28 36.25,25.75 36.48,25.99 36.83,25.99 36.93,26.09 36.93,26.38 37.19,26.64 39.24,26.64 39.34,26.75 39.34,27.03 39.24,27.13 37.09,27.13 36.86,27.36 36.86,27.83 37.09,28.07 39.91,28.07 40.08,28.24 40.08,28.95 40.32,29.18 41.16,29.18 41.81,28.53 41.81,28.29 v3(42.02,28.08)
  BOTTOM w0.102: 40.72,28.96 40.29,28.96 39.82,28.48 39.82,27.7 39.71,27.6 39.43,27.6 39.36,27.67 TSMT1.37 ; 40.72,28.96 41.47,28.96 41.84,28.58 41.84,28.26 v3(42.02,28.08) ; 40.72,28.96 v1(40.72,29.29)
LVDS_TXO_P3: length 39.2
  TOP w0.102: LVDS1.8 37,14.6 37.36,14.96 37.36,15.09 36.78,15.67 36.78,16.4 C5531.2 36.79,17.14 36.79,17.45 37.04,17.7 38.21,17.7 38.99,18.48 38.99,19.06 38.73,19.33 v3(38.73,19.32)
  L4 w0.102: v3(37.12,31.14) 37.43,30.83 37.43,30.03 36.96,29.57 35.82,29.57 35.47,29.21 35.33,29.21 35.02,29.52 34.69,29.52 34.36,29.18 34.36,28.85 34.66,28.55 34.66,28.41 32.77,26.51 32.77,25.33 33,25.1 33.43,25.1 33.53,25 33.53,24.72 33.43,24.61 33.2,24.61 32.97,24.38 32.97,22.93 33.78,22.12 33.78,20.71 34.02,20.47 34.82,20.47 34.92,20.37 34.92,20.09 34.82,19.99 32.72,19.99 32.49,19.75 32.49,19.31 32.75,19.05 35.78,19.05 36.02,19.29 36.02,19.41 36.12,19.51 36.4,19.51 36.5,19.41 36.5,19.29 36.74,19.05 37.31,19.05 38.15,19.89 38.97,19.89 39.03,19.83 39.03,19.63 38.73,19.33 v3(38.73,19.32)
  BOTTOM w0.102: v3(37.12,31.14) 37.39,30.87 37.39,30.24 36.83,29.68 36.83,29.15 36.74,29.07 TSMT1.33
LVDS_TXO_PC: length 39.8
  TOP w0.102: v3(39.73,18.52) 40.02,18.23 40.02,17.12 39.43,16.54 39.43,16.26 C5533.2 39.41,15.47 39.41,15 39,14.6 LVDS1.10
  L4 w0.102: v3(39.73,18.52) 40.07,18.85 40.07,20.16 39.63,20.6 37.85,20.6 37.49,20.24 36.07,20.24 34.7,21.61 34.7,22.18 35.92,23.4 36.25,23.4 36.68,22.97 36.82,22.97 37.03,23.18 37.03,23.39 36.04,24.38 35.78,24.38 34.39,23 34.06,23 33.73,23.33 33.73,23.66 34.87,24.81 34.87,25.6 36.16,26.88 36.16,27.05 35.97,27.23 35.83,27.23 34.52,25.93 34.19,25.93 33.86,26.26 33.86,26.59 36.07,28.8 37.7,28.8 38.2,29.31 38.76,29.31 v3(38.99,29.53)
  BOTTOM w0.102: TSMT1.35 37.54,29.05 37.62,29.13 37.62,29.49 37.92,29.79 38.37,29.79 38.63,29.53 v3(38.99,29.53) 39.16,29.53 v1(39.66,30.03)
M_A_A0: length 72.7
  TOP w0.076: CPU1.BB48 192.93,52.76 194.17,52.76 194.43,52.5 194.57,52.5 194.65,52.42
  TOP w0.114: 194.65,52.42 v4(195.53,52.42)
  TOP w0.14: DIMM1.144 253.65,39.92 253.14,40.43 v3(253.14,42.14)
  L3 w0.165: v3(253.14,42.14) 251.85,42.72 246.74,42.72 246.17,43.29 244.46,43.29 243.47,43.29 241.34,45.42 236.71,45.42 234.22,46.06 231.77,48.51 223.3,48.51 203.76,48.51 203.13,47.88 202.33,47.88 202.2,48.02 202.2,48.29 201.88,48.6 200.07,48.6 198.88,49.79 197.3,49.79 196.25,50.84 195.7,50.84 195.53,51.01 195.53,51.43 195.67,51.57 195.84,51.57 195.97,51.7 195.97,52.2 195.75,52.42 v4(195.53,52.42)
  BOTTOM w0.14: v3(253.14,42.14) 252.87,41.87 v1(252.38,41.87)
M_A_A1: length 77.7
  TOP w0.076: 198.16,48.86 198.02,49 197.77,49 197.77,49 196.43,49 196.21,48.78 194.26,48.78 194.13,48.65 CPU1.BL49
  TOP w0.14: v3(251.55,43.43) 251.55,42.91 251.32,42.67 DIMM1.133 ; 198.16,48.86 200.48,46.54 203.37,46.54 203.68,46.84 v1(203.68,48.15) 203.68,49.35 203.5,49.54 202.71,49.54 202.57,49.4 v4(202.57,48.6)
  L3 w0.165: v3(251.55,43.43) 251.32,43.2 246.93,43.2 246.35,43.77 246.03,43.77 245.86,43.94 245.86,44.61 245.7,44.78 245.37,44.78 245.2,44.61 245.2,43.94 245.04,43.77 243.66,43.77 243.19,44.24 243.19,44.42 243.74,44.97 243.74,45.2 243.5,45.44 243.27,45.44 242.76,44.93 242.53,44.93 242.29,45.16 242.29,45.39 242.75,45.85 242.75,46.09 242.52,46.32 242.29,46.32 241.83,45.86 241.59,45.86 236.89,45.86 236.73,46.03 236.73,47.01 236.56,47.18 233.75,47.18 231.97,48.96 223.11,48.96 203.84,48.96 203.49,48.6 v4(202.57,48.6)
M_A_A2: length 83.4
  TOP w0.14: DIMM1.132 252.34,42.92 v3(251.65,42.23) ; CPU1.BG38 v4(187.91,50.32)
  L3 w0.089: v4(187.91,50.32) 187.91,50.61 188,50.7 188.7,50.7 189.66,51.66 189.97,51.66
  L3 w0.165: v3(251.65,42.23) 251.6,42.27 245.21,42.27 245.04,42.43 245.04,42.68 244.88,42.84 244.53,42.84 244.36,42.68 244.36,42.45 244.2,42.28 243.86,42.28 243.69,42.45 243.69,42.67 243.53,42.83 243.29,42.83 243.05,42.83 242.95,42.73 242.71,42.73 242.47,42.97 242.47,43.66 241.52,44.61 240.25,44.61 239.62,43.97 239.12,43.97 238.95,44.14 238.95,44.24 238.79,44.4 238.45,44.4 238.28,44.24 238.28,44.14 238.12,43.97 237.77,43.97 237.61,44.14 237.61,44.24 237.44,44.4 237.1,44.4 236.93,44.24 236.93,44 236.77,43.83 236.29,43.83 236.13,44 236.13,44.9 235.96,45.07 235.57,45.07 235.4,44.9 235.4,44.34 235.23,44.17 234.86,44.17 234.69,44.34 234.69,45.28 234.57,45.4 234.2,45.4 233.54,46.06 232.91,46.06 232.71,46.26 232.71,46.36 232.71,46.36 232.71,46.89 231.54,48.07 223.48,48.07 223.48,48.07 221.27,48.07 221.27,48.07 203.67,48.07 203.23,47.63 202.11,47.63 201.94,47.8 201.94,48.18 201.78,48.35 201.43,48.35 201.27,48.18 201.27,47.8 201.1,47.63 200.72,47.63 200.56,47.8 200.56,48.14 200.39,48.31 199.94,48.31 198.71,49.54 197.1,49.54 196.06,50.58 195.44,50.58 195.21,50.8 195.21,51.94 195.05,52.11 194.65,52.11 194.49,51.94 194.49,51.35 194.32,51.19 193.92,51.19 193.45,51.66 189.97,51.66
  BOTTOM w0.14: v3(251.65,42.23) v1(250.83,42.23)
M_A_A3: length 80.3
  TOP w0.076: CPU1.BL45 191.59,48.96 194.19,48.96 194.29,49.06 195.69,49.06
  TOP w0.14: v3(250.09,43.7) 250.09,43.31 249.95,43.17 DIMM1.131 ; v4(201.41,49.12) 201.87,49.12 202.17,48.83 v1(202.17,47.55) 202.17,47.12 201.96,46.91 200.43,46.91 198.25,49.09 198.21,49.09 198.1,49.2 197.85,49.2 197.8,49.25 196.05,49.25 195.86,49.06 195.69,49.06
  L3 w0.165: v4(201.41,49.12) 203.51,49.12 203.79,49.4 221.82,49.4 227.97,49.4 228.14,49.57 228.14,51.12 228.31,51.29 228.65,51.29 228.81,51.12 228.81,49.57 228.98,49.4 229.32,49.4 229.49,49.57 229.49,51.05 229.65,51.21 229.99,51.21 230.16,51.05 230.16,49.57 230.32,49.4 230.69,49.4 230.86,49.57 230.86,50.22 231.02,50.39 231.41,50.39 231.57,50.22 231.57,49.63 231.79,49.41 232.14,49.41 233.93,47.62 237.34,47.62 237.91,47.05 239.87,47.05 240.61,46.3 241.64,46.3 242.1,46.77 242.83,46.77 244.34,45.25 246.31,45.25 246.48,45.09 246.48,44.3 246.64,44.14 246.97,44.14 247.13,44.3 247.13,45.06 247.33,45.25 247.63,45.25 247.79,45.09 247.79,43.89 247.96,43.72 248.44,43.72 248.56,43.84 248.56,44.01 248.73,44.18 249.93,44.18 250.09,44.01 v3(250.09,43.7)
M_A_A4: length 80.1
  TOP w0.076: CPU1.BJ46 192.18,49.54 192.36,49.54 192.53,49.48 192.71,49.48 192.87,49.55 192.98,49.55 193.14,49.49 193.35,49.49 193.54,49.57 193.64,49.67 194.07,49.67 194.39,49.35 194.49,49.35 194.5,49.34 195.71,49.34
  TOP w0.14: v3(253.77,43.44) 253.77,43.79 253.91,43.92 DIMM1.128 ; 195.71,49.34 195.82,49.34 195.95,49.47 197.9,49.47 197.95,49.43 198.53,49.43 198.55,49.4 199.3,49.4 199.86,48.85 200.39,48.85 v4(200.75,49.21)
  L3 w0.165: v3(253.77,43.44) 254.44,42.77 256.67,42.77 256.87,42.97 256.87,43.62 256.56,43.94 251.36,43.94 250.68,44.62 249.15,44.62 248.08,45.7 244.89,45.7 244.89,45.7 244.52,45.7 243,47.22 240.48,47.22 240.2,47.49 238.35,47.49 237.77,48.07 234.11,48.07 233.16,49.02 233.16,49.35 230.81,51.7 229.13,51.7 229.12,51.7 228.85,51.7 228.21,52.35 227.84,52.35 227.65,52.16 227.65,50.01 227.49,49.85 222.74,49.85 222.74,49.84 222.01,49.84 222.01,49.85 203.72,49.85 203.41,49.54 201.08,49.54 v4(200.75,49.21)
  BOTTOM w0.14: v3(253.77,43.44) 253.77,43.07 v1(254.16,42.69)
M_A_A5: length 77.9
  TOP w0.076: 195.7,50.16 195.6,50.16 195.28,49.84 194.73,49.84 194.36,50.21 193.24,50.21 193.02,50.12 CPU1.BG48
  TOP w0.14: v3(253.95,44.92) 253.95,44.56 254.09,44.42 DIMM1.126 ; v4(199.59,50.48) 199.21,50.09 198.83,50.09 198.81,50.11 198.23,50.11 198.18,50.16 195.7,50.16
  L3 w0.165: v3(253.95,44.92) 254.49,44.38 255.91,44.38 256.09,44.56 256.09,45.71 255.92,45.88 250.73,45.88 249.23,47.38 247.82,47.38 247.41,47.79 245.96,47.79 245.66,48.09 245.66,48.81 245.45,49.02 245.12,49.02 244.95,48.86 244.95,48 244.79,47.83 244.42,47.83 244.25,48 244.25,48.59 244.09,48.76 243.35,48.76 242.11,48.76 241.73,49.14 240.57,49.14 239.53,50.17 237.75,50.17 237.15,50.76 233.72,50.76 233.71,50.77 233.63,50.77 231.36,53.04 229.54,53.04 228.9,53.68 224.69,53.68 222.23,51.22 203.75,51.22 203.01,50.48 v4(199.59,50.48)
  BOTTOM w0.14: v1(253.37,44.35) v3(253.95,44.92)
M_A_A6: length 76.7
  TOP w0.076: CPU1.BE45 191.28,51.88 191.5,52.1 191.94,52.1 192.18,52.04 192.36,52.04 192.53,51.99 192.71,51.99 192.87,52.05 192.98,52.05 193.14,51.99 193.35,51.99 193.54,52.07 193.66,52.19 193.99,52.19 194.2,51.98 194.2,51.97 194.23,51.94
  TOP w0.114: 194.23,51.94 194.23,51.81 194.43,51.61 194.6,51.61 195.51,51.61 195.91,51.61 196.58,52.27 v4(197.23,52.27)
  TOP w0.14: DIMM1.127 250.7,44.17 v3(251.63,45.1)
  L3 w0.165: v4(197.23,52.27) 196.39,52.27 196.23,52.11 196.23,51.23 197.38,50.08 203.08,50.08 203.73,50.73 222.41,50.73 223.21,51.53 223.33,51.53 224.11,52.31 224.11,52.46 224.88,53.24 228.69,53.24 229.34,52.59 231.18,52.59 233.98,49.79 234.55,49.79 234.61,49.73 234.91,49.73 235.07,49.89 235.07,50.13 235.24,50.3 235.57,50.3 235.74,50.13 235.74,49.89 235.9,49.73 236.23,49.73 236.4,49.89 236.4,50.13 236.56,50.3 236.89,50.3 237.06,50.13 237.06,49.89 237.22,49.73 239.35,49.73 240.38,48.69 241.55,48.69 241.93,48.31 243.16,48.31 244.13,47.35 247.01,47.35 247.77,46.59 249.33,46.59 250.96,44.96 251.49,44.96 v3(251.63,45.1)
  BOTTOM w0.14: v1(252.29,45.58) 252.27,45.58 251.8,45.1 v3(251.63,45.1)
M_A_A7: length 78.6
  TOP w0.076: CPU1.BG45 191.52,49.92 191.82,50.21 192.77,50.21 193.17,50.37 194.43,50.37 194.8,50 195.21,50 195.6,50.39 195.66,50.39
  TOP w0.14: 195.66,50.39 198.28,50.39 v4(198.39,50.5) ; v3(252.52,46.42) 252.52,45.69 252.79,45.42 DIMM1.122
  L3 w0.089: 200.13,51.25 200.03,51.35 199.34,51.35 199.04,51.35 198.62,50.93 198.45,50.93 198.39,50.87 v4(198.39,50.5)
  L3 w0.165: v3(252.52,46.42) 252.65,46.55 252.65,46.85 252.43,47.07 251.66,47.07 251.66,47.07 251.25,47.07 251.25,47.07 250.95,47.07 249.67,48.35 248.26,48.35 247.88,48.73 247,48.73 244.8,50.92 244.26,50.92 244.09,51.09 244.09,51.32 243.93,51.48 243.6,51.48 243.43,51.32 243.43,51.09 243.27,50.92 242.45,50.92 242.13,51.25 240.26,51.25 240.07,51.06 238.11,51.06 237.52,51.65 234.51,51.65 234.5,51.66 234.41,51.66 234.04,51.66 231.78,53.93 230.01,53.93 229.37,54.57 224.14,54.57 222.73,53.16 217.79,53.16 217.63,53 217.63,52.31 217.46,52.15 217.13,52.15 216.97,52.31 216.97,52.89 216.8,53.06 216.48,53.06 216.3,52.87 216.3,52.27 216.13,52.1 215.8,52.1 215.64,52.27 215.64,52.87 215.47,53.04 215.14,53.04 214.98,52.87 214.98,52.27 214.81,52.1 214.48,52.1 214.32,52.27 214.32,52.87 214.15,53.04 213.82,53.04 213.66,52.87 213.66,52.27 213.49,52.1 203.72,52.1 202.7,51.08 200.3,51.08 200.13,51.25
  BOTTOM w0.14: v1(198.5,49.72) 198.39,49.82 v4(198.39,50.5)
M_A_A8: length 77.5
  TOP w0.076: 195.74,49.62 195.65,49.54 195.63,49.54 195.6,49.51 194.56,49.51 194.55,49.52 194.24,49.83 194.14,49.83 194.01,49.83 194,49.83 193.57,49.83 193.45,49.71 193.3,49.65 193.17,49.65 193,49.72 192.84,49.72 192.67,49.65 192.56,49.65 192.22,49.77 CPU1.BG47
  TOP w0.14: v3(250.09,45.14) 250.09,45.14 250.06,45.14 249.6,44.67 DIMM1.125 ; 195.74,49.62 195.81,49.7 197.99,49.7 198.04,49.65 198.62,49.65 198.64,49.63 199.68,49.63 v4(199.69,49.64)
  L3 w0.165: v4(199.69,49.64) 200.32,49.64 200.47,49.79 203.23,49.79 203.73,50.29 222.19,50.29 223.06,50.29 223.23,50.45 223.23,50.92 223.39,51.09 223.72,51.09 223.89,50.92 223.89,50.45 224.05,50.29 224.38,50.29 224.55,50.45 224.55,52.18 224.75,52.38 225.05,52.38 225.21,52.21 225.21,50.52 225.38,50.35 225.71,50.35 225.87,50.52 225.87,52.66 226,52.79 226.4,52.79 226.53,52.66 226.53,50.52 226.7,50.35 227.03,50.35 227.19,50.52 227.19,52.63 227.35,52.79 228.51,52.79 229.15,52.15 230.99,52.15 233.61,49.53 233.61,49.2 234.3,48.51 239.89,48.51 240.07,48.34 240.07,48.09 240.22,47.94 240.38,47.94 240.66,47.66 243.19,47.66 243.95,46.9 244.87,46.9 245.03,46.74 245.03,46.31 245.2,46.14 248.28,46.14 248.76,45.66 249.63,45.66 250.09,45.21 v3(250.09,45.14)
  BOTTOM w0.14: v1(250.7,44.6) 250.17,45.14 v3(250.09,45.14)
M_A_A9: length 77.6
  TOP w0.076: CPU1.BE47 192.19,50.9 192.67,50.9 193.15,50.73 194.35,50.73 194.35,50.73 194.62,50.73 195.24,50.73 195.34,50.63 195.75,50.63
  TOP w0.14: DIMM1.121 250.87,45.67 251.01,45.81 v3(251.01,46.51) ; v4(199.27,50.99) 199.19,50.99 199.09,50.89 198.18,50.89 197.92,50.63 195.75,50.63
  L3 w0.089: v4(199.27,50.99) 199.43,51.14 199.93,51.14 200.25,50.83 200.67,50.83
  L3 w0.165: v3(251.01,46.51) 250.73,46.51 249.34,47.9 248.07,47.9 247.69,48.28 246.82,48.28 245.32,49.78 244.19,49.78 244.02,49.95 244.02,50.36 243.86,50.52 243.53,50.52 243.36,50.36 243.36,49.95 243.2,49.78 242.32,49.78 242.15,49.95 242.15,50.57 241.99,50.74 241.62,50.74 241.46,50.57 241.46,49.8 241.28,49.62 240.95,49.62 240.78,49.79 240.78,50.38 240.54,50.61 237.93,50.61 237.34,51.21 233.9,51.21 233.9,51.21 233.81,51.21 231.54,53.48 229.72,53.48 229.08,54.13 224.32,54.13 222.83,52.64 222.28,52.64 222.12,52.47 222.12,51.83 221.95,51.66 221.58,51.66 221.41,51.83 221.41,52.53 221.25,52.7 220.92,52.7 220.75,52.53 220.75,51.83 220.59,51.66 220.26,51.66 220.09,51.83 220.09,52.53 219.93,52.7 219.6,52.7 219.43,52.53 219.43,51.83 219.27,51.66 218.94,51.66 218.77,51.83 218.77,52.53 218.61,52.7 218.28,52.7 218.11,52.53 218.11,51.83 217.95,51.66 203.83,51.66 203,50.83 200.67,50.83
  BOTTOM w0.14: v3(251.01,46.51) 250.18,46.51 v1(250.05,46.38)
M_A_A10: length 81.4
  TOP w0.14: v4(187.83,48.48) 187.64,48.92 CPU1.BJ38 ; v3(253.64,38) 253.96,37.68 254.89,37.68 255.14,37.42 DIMM1.146
  L3 w0.089: 194.39,48.8 194.36,48.77 193.41,48.77 193,49.17 190.64,49.17 189.99,49.83 189.61,49.83 189.42,49.63 189.42,49.08 189.33,48.99 187.92,48.99 187.83,48.9 v4(187.83,48.48)
  L3 w0.165: 194.39,48.8 195.25,48.8 197.06,46.99 198.53,46.99 199.72,45.79 203.13,45.79 204.14,44.78 216.39,44.78 218.37,42.8 230.63,42.8 232.64,40.79 232.64,39.86 232.48,39.7 231.7,39.7 231.53,39.53 231.53,38.68 231.7,38.51 240.83,38.51 241.06,38.28 248.44,38.28 248.96,37.76 250.26,37.76 250.49,38 252.36,38 252.9,37.46 252.9,37.17 253.06,37 253.84,37 254.01,37.17 254.01,37.63 v3(253.64,38)
  BOTTOM w0.14: v3(253.64,38) 253.59,37.94 v1(253.59,37.19)
M_A_A11: length 76.3
  TOP w0.076: CPU1.BB47 192.22,52.27 192.56,52.15 192.67,52.15 192.84,52.22 193,52.22 193.17,52.16 193.3,52.16 193.45,52.21 193.64,52.41 194.03,52.41 194.07,52.37
  TOP w0.114: v4(200.54,53.3) 200.54,53.26 199.94,52.66 196.62,52.66 195.8,51.85 194.65,51.85 194.35,52.15 194.29,52.15 194.07,52.37
  TOP w0.14: DIMM1.120 254.45,45.92 v3(253.95,46.42)
  L3 w0.165: v3(253.95,46.42) 254.1,46.57 254.1,46.8 254.26,46.96 254.77,46.96 254.93,47.13 254.93,47.46 254.77,47.62 254.26,47.62 254.1,47.79 254.1,48.24 253.3,49.04 253.12,49.04 252.67,49.49 252.67,50.71 249.72,53.65 247.81,53.65 247.14,54.32 244.12,54.32 243.67,54.77 243.09,54.77 241.93,55.94 234.95,55.94 234.29,56.59 231.35,56.59 230.7,57.24 222.73,57.24 221.44,55.94 205.53,55.94 204.36,54.77 203.84,54.77 201.73,52.66 200.92,52.66 200.54,53.04 v4(200.54,53.3)
  BOTTOM w0.14: v3(253.95,46.42) 253.95,46.01 v1(254.28,45.68)
M_A_A12: length 77.2
  TOP w0.076: v4(198.45,51.33) 198.24,51.33 197.94,51.04 197.67,51.04 197.48,50.84 195.44,50.84 195.39,50.89 194.55,50.89 194.42,50.89 194.41,50.89 193.17,50.89 193,50.96 CPU1.BE48
  TOP w0.14: v3(251.45,47.56) 250.96,47.56 249.58,46.17 DIMM1.119
  L3 w0.089: 200.61,51.36 200.42,51.36 200.28,51.51 200.27,51.51 200.27,51.51 200.26,51.53 200.11,51.53 200.11,51.53 199.42,51.53 199.41,51.53 198.65,51.53 v4(198.45,51.33)
  L3 w0.165: 200.61,51.36 202.6,51.36 203.79,52.55 205.49,52.55 206.33,53.39 206.82,53.39 206.98,53.23 206.98,52.71 207.15,52.55 207.48,52.55 207.64,52.71 207.64,53.41 207.81,53.57 208.14,53.57 208.31,53.41 208.31,52.71 208.47,52.55 208.8,52.55 208.97,52.71 208.97,53.41 209.13,53.57 209.46,53.57 209.63,53.41 209.63,52.71 209.79,52.55 210.12,52.55 210.29,52.71 210.29,53.41 210.45,53.57 210.78,53.57 210.95,53.41 210.95,52.71 211.11,52.55 211.44,52.55 211.61,52.71 211.61,53.41 211.77,53.57 212.1,53.57 212.27,53.41 212.27,52.71 212.43,52.55 212.76,52.55 212.93,52.71 212.93,53.41 213.13,53.61 222.54,53.61 223.95,55.01 229.55,55.01 230.2,54.37 231.67,54.37 232.34,54.37 233.88,52.83 233.88,52.61 234.38,52.11 234.68,52.11 234.69,52.1 240.54,52.1 240.69,51.96 244.4,51.96 247.19,49.17 248.06,49.17 248.44,48.79 249.86,48.79 251.09,47.56 v3(251.45,47.56)
  BOTTOM w0.14: v3(251.45,47.56) v1(250.52,47.56)
M_A_A13: length 81.6
  TOP w0.14: v3(252.93,34.99) 253.47,34.45 256.08,34.45 DIMM1.158 ; CPU1.BM39 188.26,47.97 188.62,47.6 v4(188.62,47.59)
  L3 w0.089: 193.68,46.12 193.53,46.12 192.47,47.18 189.45,47.18 189.44,47.17 189.12,47.17 188.7,47.59 v4(188.62,47.59)
  L3 w0.165: v3(252.93,34.99) 253.48,34.99 253.81,34.66 253.81,33.68 253.6,33.47 252.25,33.47 252.09,33.63 241.77,33.63 241.6,33.8 241.6,34.85 241.44,35.02 241.11,35.02 240.94,34.85 240.94,33.8 240.78,33.63 240.09,33.63 240.01,33.55 237.38,33.55 237.25,33.68 234.09,33.68 233.55,34.22 226.39,34.22 221.78,38.84 217.93,38.84 215.1,41.67 204.25,41.67 201.91,44.01 198.99,44.01 198.1,44.91 195.47,44.91 194.26,46.12 193.68,46.12
  BOTTOM w0.14: v1(190.25,47.57) 189.8,47.12 189.1,47.12 v4(188.62,47.59)
M_A_A14: length 78
  TOP w0.14: v4(189.86,49.36) 190.21,49.71 CPU1.BG43 ; DIMM1.151 248.87,36.17 248.88,36.16 250.12,36.16 250.43,36.47 v3(250.43,36.46)
  L3 w0.089: 194.91,47.65 194.64,47.65 194.26,48.02 193.32,48.02 192.91,48.44 190.64,48.44 190.3,48.79 190.3,48.93 v4(189.86,49.36)
  L3 w0.165: 194.91,47.65 195.49,47.65 196.7,46.44 198.36,46.44 199.51,45.29 202.85,45.29 204.24,43.89 216.02,43.89 218,41.91 229.12,41.91 229.29,41.75 229.29,41.36 229.12,41.2 227.82,41.2 227.65,41.03 227.65,40.66 227.82,40.49 229.1,40.49 229.26,40.33 229.26,39.63 229.87,39.02 230.4,39.02 230.64,38.77 230.64,38.31 231.33,37.62 231.7,37.62 239.87,37.62 240.1,37.39 248.06,37.39 248.28,37.18 248.28,36.86 248.12,36.69 247.34,36.69 247.16,36.51 247.16,36.14 247.36,35.95 248.92,35.95 249.14,36.16 249.54,36.16 249.83,35.88 250.26,35.88 250.43,36.04 v3(250.43,36.46)
  BOTTOM w0.14: v3(250.43,36.46) v1(249.62,36.46)
M_A_A15: length 79.9
  TOP w0.14: v3(253.82,35.38) 254.28,34.92 DIMM1.156 ; CPU1.BJ42 189.56,48.85 v4(189.9,48.51)
  L3 w0.089: v4(189.9,48.51) 190.15,48.26 192.8,48.26 193.22,47.83 194.12,47.83 194.57,47.39 194.68,47.39
  L3 w0.165: 194.68,47.39 195.39,47.39 196.72,46.06 198.38,46.06 199.41,45.03 202.48,45.03 204.07,43.44 215.84,43.44 217.82,41.47 226.94,41.47 227.21,41.2 227.21,40.47 227.63,40.05 228.13,40.05 231.09,37.09 233.77,37.09 234.31,36.56 237.77,36.56 237.79,36.59 239.67,36.59 240,36.92 245.76,36.92 247.5,35.17 250.36,35.17 251.41,36.22 255.71,36.22 255.87,36.06 255.87,35.07 255.71,34.9 254.3,34.9 v3(253.82,35.38)
  BOTTOM w0.14: v3(253.82,35.38) 253.77,35.33 v1(253.77,34.57)
M_A_A16: length 81.1
  TOP w0.14: v4(189.28,47.56) 189.28,47.56 188.91,47.96 CPU1.BM41 ; v3(252.74,35.72) 253.38,35.72 253.58,35.92 DIMM1.152
  L3 w0.089: v4(189.28,47.56) 192.34,47.56 193.5,46.4 194.81,46.4
  L3 w0.165: 194.81,46.4 195.18,46.4 196.36,45.23 198.14,45.23 199.09,44.27 202.01,44.27 204.17,42.11 215.29,42.11 217.26,40.13 217.93,40.13 218.1,39.97 218.1,39.47 218.26,39.3 218.59,39.3 218.76,39.47 218.76,39.97 218.92,40.13 219.25,40.13 219.42,39.97 219.42,39.47 219.58,39.3 219.91,39.3 220.08,39.47 220.08,39.97 220.24,40.13 220.64,40.13 220.8,39.97 220.8,39.45 220.97,39.28 222.16,39.28 226.77,34.66 234.54,34.66 236.89,34.66 236.91,34.68 239.77,34.68 240.67,35.58 242,35.58 242.23,35.36 242.23,34.45 242.39,34.28 242.8,34.28 242.96,34.45 242.96,35.24 243.13,35.41 243.52,35.41 243.69,35.24 243.69,34.75 244.35,34.08 251.97,34.08 252.3,34.41 252.3,35.39 252.63,35.72 v3(252.74,35.72)
  BOTTOM w0.14: v1(251.95,35.95) 252.12,35.95 252.18,35.88 252.58,35.88 v3(252.74,35.72)
M_A_ACT_N: length 75.1
  TOP w0.076: CPU1.BE49 193.48,51.16 193.57,51.06 194.48,51.06 194.48,51.06 195.45,51.06 195.51,51.01 197.41,51.01 v4(197.8,51.39)
  TOP w0.14: DIMM1.114 254.15,47.42 253.64,47.93 v3(252.12,47.93)
  L3 w0.089: 200.61,51.61 200.42,51.61 200.33,51.71 200.18,51.71 200.18,51.71 199.53,51.71 198.11,51.71 v4(197.8,51.39)
  L3 w0.165: v3(252.12,47.93) 252.12,48.15 250.5,49.77 247.32,49.77 247.15,49.94 247.15,50.27 247.32,50.44 247.75,50.44 247.95,50.64 247.95,50.87 247.77,51.05 246.36,51.05 246.19,51.22 246.19,51.61 246.31,51.73 246.53,51.73 246.7,51.89 246.7,52.15 246.45,52.4 240.88,52.4 240.73,52.55 239.82,52.55 239.65,52.71 239.65,53.14 239.49,53.31 239.11,53.31 238.98,53.18 238.98,52.69 238.84,52.55 237.92,52.55 237.8,52.66 237.8,53.16 237.65,53.31 237.31,53.31 237.14,53.14 237.14,52.65 237.04,52.55 236.58,52.55 236.47,52.66 236.47,53.14 236.31,53.31 234.05,53.31 232.54,54.82 231.49,54.82 230.38,54.82 229.74,55.46 223.55,55.46 222.14,54.05 206.26,54.05 205.2,52.99 203.84,52.99 203.84,52.99 203.79,52.99 202.41,51.61 200.61,51.61
  BOTTOM w0.14: v4(197.8,51.39) 197.53,51.13 v1(197.53,50.65)
M_A_ALERT_N: length 71.4
  TOP w0.076: CPU1.BD46 192.26,51.47 192.5,51.41 192.68,51.41 192.85,51.36 193.03,51.36 193.19,51.42 193.3,51.42 193.85,51.23 194.55,51.23 194.55,51.22 195.52,51.22 195.53,51.21 195.75,51.21
  TOP w0.14: 195.75,51.21 196.33,51.21 196.51,51.39 v4(196.63,51.39) ; v3(253.3,47.28) 253.58,47.28 253.94,46.92 DIMM1.116
  L3 w0.089: 200.51,51.88 200.26,51.88 200.25,51.89 199.6,51.89 199.57,51.91 197.15,51.91 v4(196.63,51.39)
  L3 w0.165: 200.51,51.88 200.53,51.87 202.25,51.87 203.82,53.43 203.84,53.43 203.84,53.44 205.01,53.44 206.07,54.5 221.96,54.5 223.37,55.9 229.92,55.9 230.56,55.26 231.3,55.26 231.3,55.26 232.73,55.26 234.24,53.75 240.15,53.75 241.06,52.84 246.63,52.84 248.68,50.8 250.09,50.8 250.67,50.22 250.68,50.22 253.3,47.6 v3(253.3,47.28)
  BOTTOM w0.14: v3(253.3,47.28) 254.1,47.28 v1(254.13,47.26)
M_A_BA0: length 80.2
  TOP w0.14: CPU1.BM43 190.5,48.31 190.5,48.51 v4(190.79,48.8) ; v3(252.41,37.26) 253.24,36.42 DIMM1.150
  L3 w0.089: v4(190.79,48.8) 192.89,48.8 193.23,48.46 194.51,48.46
  L3 w0.165: v3(252.41,37.26) 252.12,36.97 250.79,36.97 250.44,37.32 248.78,37.32 248.26,37.84 240.79,37.84 240.56,38.07 231.51,38.07 231.09,38.49 231.09,39.3 230.92,39.46 230.05,39.46 229.87,39.65 229.87,40.05 230.03,40.21 231.86,40.21 232.07,40.42 232.07,40.73 231.88,40.92 229.91,40.92 229.74,41.08 229.74,41.51 229.91,41.67 230.58,41.67 230.69,41.79 230.69,42.1 230.44,42.36 218.18,42.36 216.21,44.33 204.23,44.33 203.02,45.54 199.62,45.54 198.47,46.69 196.9,46.69 195.14,48.46 194.51,48.46
  BOTTOM w0.14: v1(251.83,37.83) 251.97,37.83 252.11,37.69 252.11,37.56 v3(252.41,37.26)
M_A_BA1: length 80.9
  TOP w0.14: DIMM1.145 249.12,37.67 v3(249.84,38.39) ; CPU1.BG39 v4(188.47,49.41)
  L3 w0.089: 194.36,49.13 194.18,48.95 193.59,48.95 193.05,49.48 191.69,49.48 191.07,50.1 189.52,50.1 189.25,49.83 188.56,49.83 188.47,49.74 v4(188.47,49.41)
  L3 w0.165: 194.36,49.13 195.37,49.13 197.11,47.39 198.49,47.39 199.84,46.05 203.23,46.05 204.06,45.22 216.58,45.22 218.55,43.25 230.81,43.25 233.08,40.97 233.08,39.17 233.25,39.01 233.64,39.01 233.8,39.17 233.8,39.81 233.96,39.97 234.37,39.97 234.54,39.81 234.54,39.21 234.7,39.04 235.17,39.04 235.33,39.21 235.33,39.53 235.5,39.69 235.9,39.69 236.06,39.53 236.06,39.14 236.23,38.98 236.6,38.98 236.76,39.14 236.76,39.53 236.93,39.69 237.26,39.69 237.43,39.53 237.43,39.14 237.59,38.98 237.94,38.98 238.1,39.14 238.1,39.53 238.27,39.69 240.91,39.69 241.31,39.29 241.31,38.89 241.48,38.73 241.92,38.73 242.08,38.89 242.08,39.24 242.25,39.41 242.58,39.41 242.74,39.24 242.74,38.89 242.91,38.73 243.24,38.73 243.4,38.89 243.4,39.24 243.57,39.41 243.9,39.41 244.07,39.24 244.07,38.89 244.23,38.73 244.56,38.73 244.73,38.89 244.73,39.24 244.89,39.41 245.22,39.41 245.39,39.24 245.39,38.89 245.55,38.73 245.88,38.73 246.05,38.89 246.05,39.24 246.21,39.41 246.54,39.41 246.71,39.24 246.71,38.89 246.87,38.73 247.2,38.73 247.37,38.89 247.37,39.24 247.53,39.41 247.86,39.41 248.03,39.24 248.03,38.89 248.19,38.73 248.63,38.73 248.96,38.39 v3(249.84,38.39)
  BOTTOM w0.14: v1(249.04,38.28) 249.15,38.39 v3(249.84,38.39)
M_A_BG0: length 75
  TOP w0.076: CPU1.BB49 193.41,52.6 194.1,52.6 194.36,52.34 194.45,52.34 194.74,52.05
  TOP w0.114: 194.74,52.05 195.72,52.05 196.53,52.86 198.9,52.86 v4(199.35,53.31)
  TOP w0.14: v3(253.17,48.42) 251.24,48.42 249.99,47.17 DIMM1.115
  L3 w0.165: v3(253.17,48.42) 253.1,48.42 252.22,49.3 252.22,50.52 249.54,53.21 247.63,53.21 246.96,53.88 242.81,53.88 242.69,53.76 242.28,53.76 242,54.04 242,54.97 241.47,55.49 237.18,55.49 237.18,55.49 234.76,55.49 234.1,56.15 230.93,56.15 230.29,56.79 222.92,56.79 221.62,55.5 205.72,55.5 204.55,54.33 203.84,54.33 201.92,52.41 200.01,52.41 199.35,53.07 v4(199.35,53.31)
  BOTTOM w0.14: v1(252.07,48.97) 252.31,48.97 252.85,48.42 v3(253.17,48.42)
M_A_BG1: length 75.1
  TOP w0.076: CPU1.BD47 192.55,51.64 192.88,51.52 193,51.52 193.17,51.59 193.32,51.59 193.83,51.41 195.34,51.41 195.68,51.41 195.83,51.41 195.83,51.41 196.09,51.41 196.11,51.43
  TOP w0.114: 196.11,51.43 196.53,51.84 197.97,51.84 v4(198.4,52.27)
  TOP w0.14: DIMM1.113 249.89,47.67 251.06,48.84 252.43,48.84 v3(253.22,49.63)
  L3 w0.165: v3(253.22,49.63) 253.22,50.79 249.89,54.11 248.02,54.11 247.36,54.77 244.3,54.77 243.85,55.22 243.28,55.22 241.38,57.12 234,57.12 233.37,57.75 222.62,57.75 221.26,56.39 205.02,56.39 204.12,55.5 203.25,55.5 202.57,54.82 202.57,54.77 201.53,53.73 199.2,53.73 198.76,53.29 198.76,53.07 198.4,52.72 v4(198.4,52.27)
  BOTTOM w0.14: v1(254.03,49.63) v3(253.22,49.63)
M_A_CKE0: length 85.2
  TOP w0.076: CPU1.BG49 193.34,50.02 194.28,50.02 194.63,49.67 195.44,49.67 195.62,49.85
  TOP w0.14: v4(199.57,52.27) 199.71,52.14 203.69,52.14 203.83,52 203.83,51.71 203.7,51.58 199.78,51.58 199.64,51.44 199.64,51.16 199.78,51.02 203.67,51.02 203.81,50.88 203.81,50.59 203.68,50.46 202.39,50.46 202.02,50.09 v1(201.14,50.09) 199.53,50.09 199.3,49.86 198.74,49.86 198.72,49.88 198.14,49.88 198.09,49.93 195.7,49.93 195.62,49.85 ; DIMM1.109 249.49,48.67 249.84,49.02 249.84,50.19 v3(250.66,51.01)
  L3 w0.165: v4(199.57,52.27) 199.71,52.14 202.05,52.14 203.8,53.88 203.84,53.88 203.84,53.88 204.83,53.88 205.89,54.94 221.78,54.94 223.18,56.35 230.11,56.35 230.75,55.71 231.12,55.71 231.12,55.71 233.83,55.71 234.61,54.93 240.89,54.93 241.06,54.77 241.06,53.86 241.6,53.31 242.87,53.31 242.99,53.44 246.77,53.44 248.02,52.19 249.48,52.19 v3(250.66,51.01)
M_A_CKE1: length 89.2
  TOP w0.114: v4(188.59,51.22) 188.91,50.9 CPU1.BF41
  TOP w0.14: DIMM1.110 255.2,48.42 v3(254.66,48.97)
  L3 w0.089: v4(188.59,51.22) 188.88,51.22 189.59,51.93 189.81,51.93
  L3 w0.165: v3(254.66,48.97) 254.66,49.56 254.96,49.86 256.25,49.86 256.42,50.03 256.42,50.37 256.25,50.53 255.16,50.53 255,50.7 255,51.03 255.17,51.21 256.22,51.21 256.38,51.37 256.38,51.71 256.22,51.88 255.22,51.88 255.05,52.05 255.05,52.68 254.79,52.94 254.16,52.94 253.91,52.69 253.91,51.63 253.75,51.46 253.38,51.46 253.17,51.68 253.17,53.77 253.02,53.92 252.62,53.92 252.47,53.77 252.47,52.8 252.31,52.64 252,52.64 251.8,52.84 251.8,53.46 251.63,53.62 251.19,53.62 249.6,55.21 244.49,55.21 244.04,55.66 243.46,55.66 240.34,58.78 222.79,58.78 220.84,56.83 204.83,56.83 204.03,56.03 203.43,56.03 202.32,54.93 202.32,54.88 201.46,54.02 199.12,54.02 198.5,53.39 198.5,53.18 198.12,52.8 195.73,52.8 195.7,52.82 195.09,52.82 194.71,52.45 193.65,52.45 193.13,51.93 189.81,51.93
  BOTTOM w0.14: v3(254.66,48.97) v1(255.47,48.97)
M_A_CLK0: length 85.2
  TOP w0.076: CPU1.BL47 192.19,48.4 192.67,48.4 193.1,48.24 194.32,48.24 194.48,48.41 195,48.41 195.49,47.92 196.02,47.92 196.03,47.91 196.05,47.91
  TOP w0.102: 196.05,47.91 197.4,47.91 197.58,48.08 197.58,48.51 v4(197.7,48.64) ; DIMM1.137 250.03,41.67 250.77,40.94 v3(250.77,39.76)
  L3 w0.114: v3(250.77,39.76) 250.77,40.51 250.53,40.75 241.75,40.75 240.46,42.04 236.68,42.04 236.42,41.78 234.14,41.78 232.94,42.99 232.94,44.23 232.6,44.57 226.07,44.57 225.96,44.68 225.96,46.26 225.71,46.51 225.11,46.51 224.86,46.26 224.86,44.68 224.74,44.57 224.25,44.57 224.14,44.68 224.14,46.33 223.91,46.57 223.29,46.57 223.06,46.33 223.06,44.68 222.95,44.57 222.55,44.57 222.44,44.68 222.44,46.33 222.2,46.57 221.6,46.57 221.36,46.33 221.36,44.68 221.24,44.57 220.85,44.57 220.74,44.68 220.74,46.34 220.51,46.57 219.89,46.57 219.66,46.34 219.66,44.68 219.54,44.57 219.1,44.57 218.94,44.73 218.94,46.24 218.62,46.56 203.83,46.56 203.5,46.88 200.23,46.88 198.86,48.25 198.1,48.25 v4(197.7,48.64)
  BOTTOM w0.102: v1(250.89,40.56) 250.89,39.88 v3(250.77,39.76)
M_A_CLK1: length 89.8
  TOP w0.102: CPU1.BF43 190.21,50.92 v4(190.55,51.26) ; v3(253.93,41.53) 254.18,41.27 254.92,41.27 255.08,41.42 DIMM1.138
  L3 w0.114: v3(253.93,41.53) 253.61,41.21 253.23,41.21 252.82,40.8 252.82,39.67 252.71,39.56 252.31,39.56 252.2,39.67 252.2,40.8 251.95,41.05 251.43,41.05 250.88,41.6 242.1,41.6 241.82,41.88 241.82,43.4 241.25,43.96 240.52,43.96 240.24,43.68 240.24,43 240.13,42.89 237.29,42.89 237.18,43 234.13,43 233.79,43.34 233.79,44.9 233.27,45.42 232.18,45.42 232.06,45.53 232.06,46.63 231.7,46.98 231.27,46.98 230.98,46.7 230.98,45.5 230.9,45.42 230.44,45.42 230.36,45.5 230.36,47.2 230.14,47.42 229.5,47.42 229.28,47.2 229.28,45.49 229.21,45.42 228.73,45.42 228.66,45.49 228.66,47.19 228.43,47.42 227.81,47.42 227.58,47.19 227.58,45.49 227.51,45.42 226.93,45.42 226.85,45.5 226.85,47.17 226.6,47.42 221,47.42 221,47.42 204.39,47.42 204.37,47.4 200.53,47.4 198.63,49.3 196.77,49.3 196.11,49.96 194.88,49.96 194.68,50.16 194.68,50.6 194.43,50.85 193.45,50.85 193.33,50.97 193.33,51.14 193.08,51.39 191.54,51.39 190.96,50.81 190.35,50.81 190.22,50.93 190.22,51.18 190.3,51.26 v4(190.55,51.26)
  BOTTOM w0.102: v4(190.55,51.26) 190.44,51.14 v1(190.44,50.48)
M_A_CLK#0: length 85.2
  TOP w0.076: 196.05,48.11 196.03,48.11 196.02,48.1 195.57,48.1 195.08,48.59 194.41,48.59 194.23,48.41 193.12,48.41 193,48.46 192.66,48.62 CPU1.BL48
  TOP w0.102: v3(250.06,39.76) 250.57,40.27 250.57,40.85 249.95,41.47 249.15,41.47 249.07,41.4 249.07,41.24 249.01,41.17 DIMM1.139 ; 196.05,48.11 197.32,48.11 197.37,48.16 197.37,48.46 197.19,48.64 v4(197.12,48.64)
  L3 w0.114: v4(197.12,48.64) 197.12,48.35 197.21,48.27 197.75,48.27 198,48.02 198.77,48.02 200.13,46.65 203.41,46.65 203.73,46.33 218.53,46.33 218.71,46.15 218.71,44.63 219.01,44.34 219.64,44.34 219.89,44.59 219.89,46.24 219.98,46.34 220.41,46.34 220.51,46.24 220.51,44.59 220.76,44.34 221.34,44.34 221.59,44.59 221.59,46.23 221.7,46.34 222.1,46.34 222.21,46.23 222.21,44.59 222.46,44.34 223.04,44.34 223.29,44.59 223.29,46.24 223.39,46.34 223.81,46.34 223.91,46.24 223.91,44.59 224.16,44.34 224.84,44.34 225.09,44.59 225.09,46.16 225.2,46.28 225.61,46.28 225.73,46.16 225.73,44.59 225.97,44.34 232.51,44.34 232.71,44.14 232.71,42.89 234.05,41.55 236.52,41.55 236.77,41.81 240.36,41.81 241.65,40.52 250.43,40.52 250.54,40.41 250.54,40.2 250.1,39.76 v3(250.06,39.76)
  BOTTOM w0.102: v3(250.06,39.76) v1(249.6,40.74)
M_A_CLK#1: length 89.9
  TOP w0.102: v4(189.85,51.16) 189.66,51.16 189.56,51.06 CPU1.BF42 ; DIMM1.140 255.08,40.92 254.93,41.07 254.18,41.07 v3(253.93,40.82)
  L3 w0.114: v3(253.93,40.82) 253.76,40.98 253.33,40.98 253.05,40.71 253.05,39.58 252.8,39.33 252.22,39.33 251.97,39.58 251.97,40.71 251.86,40.82 251.34,40.82 250.79,41.37 242.01,41.37 241.59,41.79 241.59,43.3 241.16,43.73 240.61,43.73 240.47,43.59 240.47,42.91 240.22,42.66 237.19,42.66 237.08,42.77 234.03,42.77 233.56,43.24 233.56,44.81 233.18,45.19 232.08,45.19 231.84,45.44 231.84,46.53 231.61,46.76 231.37,46.76 231.21,46.6 231.21,45.4 231,45.19 230.35,45.19 230.13,45.4 230.13,47.11 230.05,47.19 229.6,47.19 229.51,47.11 229.51,45.39 229.31,45.19 228.64,45.19 228.43,45.39 228.43,47.1 228.34,47.19 227.9,47.19 227.81,47.1 227.81,45.39 227.6,45.19 226.84,45.19 226.62,45.4 226.62,47.08 226.51,47.19 220.91,47.19 204.48,47.19 204.46,47.17 200.43,47.17 198.54,49.07 196.68,49.07 196.01,49.73 194.79,49.73 194.46,50.07 194.46,50.5 194.34,50.62 193.35,50.62 193.1,50.87 193.1,51.04 192.99,51.16 191.63,51.16 191.05,50.58 190.25,50.58 190,50.84 190,51.02 v4(189.85,51.16)
  BOTTOM w0.102: v1(253.13,40.67) 253.77,40.67 v3(253.93,40.82)
M_A_CS#0: length 89.8
  TOP w0.14: v3(251.74,32.99) 251.74,33.23 252.23,33.72 252.23,36.09 251.38,36.93 249.83,36.93 249.83,36.92 249.59,36.67 DIMM1.149 ; CPU1.BM38 v4(187.89,47.56)
  L3 w0.089: v4(187.89,47.56) 188.12,47.56 188.46,47.22 188.76,47.22 188.99,46.99 189.77,46.99 189.77,47 192.36,47 193.52,45.84 193.75,45.84
  L3 w0.165: v3(251.74,32.99) 251.55,32.8 250.06,32.8 249.67,33.19 249.26,33.19 249.19,33.11 241.34,33.11 237.45,33.11 237.19,32.85 236.9,32.56 233.56,32.56 233.4,32.73 233.4,33.6 233.23,33.76 232.84,33.76 232.67,33.6 232.67,32.74 232.51,32.57 232.18,32.57 232.01,32.74 232.01,33.6 231.85,33.77 231.52,33.77 231.35,33.6 231.35,32.7 231.21,32.56 230.83,32.56 230.69,32.7 230.69,33.6 230.53,33.77 230.2,33.77 230.03,33.6 230.03,32.69 229.91,32.56 229.5,32.56 229.37,32.69 229.37,33.55 229.21,33.72 228.88,33.72 228.71,33.55 228.71,32.77 228.55,32.6 228.22,32.6 228.05,32.77 228.05,33.55 227.89,33.72 227.55,33.72 227.39,33.55 227.39,33.1 227.22,32.93 226.89,32.93 226.67,33.16 226.67,33.55 226.51,33.72 226.04,33.72 221.37,38.39 217.75,38.39 214.92,41.22 204.07,41.22 202.03,43.27 200.79,43.27 200.3,43.76 198.89,43.76 197.99,44.65 195.29,44.65 194.1,45.84 193.75,45.84
  BOTTOM w0.14: v3(251.74,32.99) 251.74,32.08 v1(251.81,32.01)
M_A_CS#1: length 88.7
  TOP w0.14: v3(251.43,35.21) 250.9,34.67 DIMM1.157 ; CPU1.BG42 189.24,49.52 189.24,48.52 v4(189.2,48.48)
  L3 w0.089: 194.58,47.13 194.44,47.13 194.08,47.5 193.18,47.5 192.62,48.07 189.8,48.07 189.39,48.48 v4(189.2,48.48)
  L3 w0.165: 194.58,47.13 195.29,47.13 196.62,45.81 198.28,45.81 199.3,44.78 202.38,44.78 204.16,43 215.65,43 217.63,41.02 224.04,41.02 224.59,40.48 224.82,40.48 225.35,41 225.58,41 225.82,40.77 225.82,40.53 225.29,40.01 225.29,39.78 225.53,39.54 225.76,39.54 226.51,40.3 226.75,40.3 226.98,40.06 226.98,39.83 226.23,39.08 226.23,38.84 226.46,38.61 226.69,38.61 227.69,39.6 227.95,39.6 228.18,39.38 228.18,39.16 227.16,38.14 227.16,37.91 227.39,37.67 227.63,37.67 228.63,38.68 228.87,38.68 229.1,38.45 229.1,38.21 228.09,37.21 228.09,36.97 228.42,36.64 228.6,36.64 229.62,37.67 229.86,37.67 230.11,37.42 230.11,37.18 229.22,36.29 229.22,36.03 229.45,35.8 229.68,35.8 230.48,36.6 233.63,36.6 234.12,36.11 237.95,36.11 237.98,36.14 239.86,36.14 240.19,36.47 245.57,36.47 247.53,34.52 250.75,34.52 v3(251.43,35.21)
  BOTTOM w0.14: v1(250.63,35.3) 250.85,35.3 250.92,35.22 251.42,35.22 v3(251.43,35.21)
M_A_DQ0: length 77.9
  TOP w0.076: v4(194.53,43.4) 193.16,43.4 192.97,43.46 CPU1.CA48
  TOP w0.114: DIMM1.208 v3(254.66,21.92)
  L3 w0.127: v3(254.66,21.92) 255,21.92 255.12,21.8 255.12,21.14 255,21.02 251.81,21.02 251.63,21.2 248.12,21.2 247.14,20.22 247.1,20.22 246.99,20.11 243.12,20.11 243.01,20.22 238.12,20.22 237.8,19.9 237.29,19.9 236.66,20.54 233.92,20.54 233.38,21.08 229.09,21.08 226.19,23.98 223.95,23.98 218.19,29.74 215.14,29.74 215.14,29.73 213.8,29.73 207.55,35.98 204.47,35.98 201.22,39.23 198.22,39.23 195.38,42.06 194.97,42.06 194.46,42.56 194.46,43.33 v4(194.53,43.4)
  BOTTOM w0.114: v1(194.33,44.98) 194.33,44.42 194.33,44.41 194.33,44.33 194.53,44.13 v4(194.53,43.4)
M_A_DQ1: length 78.5
  TOP w0.076: v4(196.07,43.89) 196.07,43.93 194.28,43.93 194.11,43.76 193.54,43.76 193.45,43.85 193.3,43.91 193.17,43.91 193,43.85 192.84,43.85 192.67,43.92 192.56,43.92 192.22,43.8 CPU1.CA47
  TOP w0.114: DIMM1.207 249.53,22.17 v3(250.06,22.71)
  L3 w0.127: v4(196.07,43.89) 196.47,43.5 196.47,42.15 198.74,39.88 201.56,39.88 204.33,37.11 207.88,37.11 214.22,30.76 214.71,30.76 214.71,30.76 218.62,30.76 224.38,25.01 226.61,25.01 229.52,22.1 233.8,22.1 234.34,21.56 237.37,21.56 237.91,22.1 240.63,22.1 241.07,22.54 244.06,22.54 244.18,22.42 244.18,21.55 244.31,21.43 244.56,21.43 244.69,21.55 244.69,22.42 244.82,22.54 245.07,22.54 245.2,22.42 245.2,21.57 245.33,21.45 245.58,21.45 245.71,21.57 245.71,22.42 245.83,22.54 246.09,22.54 246.21,22.42 246.21,21.61 246.34,21.48 246.6,21.48 246.72,21.61 246.72,22.42 246.85,22.54 248.85,22.54 249.16,22.24 250.02,22.24 250.15,22.36 250.15,22.63 v3(250.06,22.71)
  BOTTOM w0.114: v4(196.07,43.89) 196.07,44.02 196.63,44.58 196.63,44.7 v1(196.61,44.7)
M_A_DQ2: length 76.7
  TOP w0.076: CPU1.CA49 193.32,43.56 194.17,43.56 194.37,43.76 195.47,43.76 195.68,43.55 195.68,43.08 v4(196.03,42.72)
  TOP w0.114: v3(251.49,22.71) 251.02,23.17 DIMM1.203
  L3 w0.127: v4(196.03,42.72) 196.04,42.72 196.04,42.28 198.65,39.66 201.4,39.66 204.37,36.7 207.81,36.7 214.08,30.42 214.85,30.42 218.48,30.42 224.24,24.66 226.47,24.66 229.37,21.76 233.66,21.76 234.2,21.22 237.97,21.22 238.13,21.07 240.52,21.07 240.65,21.19 240.65,21.5 241.34,22.2 242.54,22.2 242.66,22.07 242.66,21.64 242.79,21.52 243.06,21.52 243.19,21.64 243.19,22.05 243.32,22.17 243.57,22.17 243.7,22.05 243.7,21.19 243.83,21.07 246.68,21.07 247.5,21.88 251.36,21.88 251.49,22.01 v3(251.49,22.71)
  BOTTOM w0.114: v1(196.17,41.95) 196.17,42.59 v4(196.03,42.72)
M_A_DQ3: length 78.1
  TOP w0.076: CPU1.BV49 193.31,44.99 194.16,44.99 194.32,44.83 196.56,44.83 196.56,44.83
  TOP w0.089: 196.56,44.83 197.5,44.83 198.72,43.6 198.72,43.01 v4(198.65,42.93)
  TOP w0.114: DIMM1.190 253,26.42 v3(252.5,25.92)
  L3 w0.127: v3(252.5,25.92) 252.5,25.43 252.63,25.3 252.98,25.3 253.11,25.17 253.11,24.6 252.98,24.47 248.6,24.47 248.02,25.05 240.73,25.05 239.94,24.26 237.05,24.26 236.87,24.08 232.68,24.08 232.56,24.2 232.56,24.83 232.43,24.95 232.17,24.95 232.05,24.83 232.05,24.2 231.92,24.08 230.29,24.08 227.54,26.84 225.14,26.84 219.38,32.59 214.98,32.59 208.58,39 204.1,39 202.31,40.8 200.4,40.8 199.05,42.14 199.05,42.53 v4(198.65,42.93)
  BOTTOM w0.114: v3(252.5,25.92) 252.5,26.09 253.1,26.69 253.1,26.7 v1(253.15,26.75)
M_A_DQ4: length 79.7
  TOP w0.076: v4(194.85,42.76) 194.62,42.76 194.15,43.23 193.13,43.23 192.87,43.32 191.93,43.32 191.79,43.36 191.56,43.54 191.29,43.65 CPU1.CA45
  TOP w0.114: DIMM1.204 253.93,22.92 253.21,22.21 v3(253.21,21.92)
  L3 w0.127: v4(194.85,42.76) 194.85,42.7 195.26,42.28 195.6,42.28 198.44,39.45 201.31,39.45 204.44,36.32 207.7,36.32 213.94,30.08 214.99,30.08 218.34,30.08 224.09,24.32 226.33,24.32 229.23,21.42 233.52,21.42 234.06,20.88 237.71,20.88 237.87,20.72 241.38,20.72 241.51,20.85 241.51,21.63 241.64,21.76 241.89,21.76 242.02,21.63 242.02,20.76 242.15,20.63 242.52,20.63 242.65,20.76 242.65,21.01 242.78,21.14 243.03,21.14 243.16,21.01 243.16,20.55 243.26,20.45 246.85,20.45 247.94,21.54 251.9,21.54 252.06,21.38 252.67,21.38 v3(253.21,21.92)
  BOTTOM w0.114: v1(195.14,44.01) 194.92,43.79 194.92,42.83 v4(194.85,42.76)
M_A_DQ5: length 79.5
  TOP w0.076: 194.69,45.21 194.54,45.21 194.43,45.32 193.09,45.32 192.64,45.16 192.31,45.16 CPU1.BV47
  TOP w0.089: 194.69,45.21 197.84,45.21 199.55,43.51 v4(199.55,42.4)
  TOP w0.114: v3(250.06,25.67) 249.56,25.17 DIMM1.195
  L3 w0.127: v3(250.06,25.67) 250.18,25.67 250.3,25.55 250.3,25.28 250.18,25.16 249.2,25.16 248.62,25.74 233.38,25.74 233.24,25.88 233.24,26.42 233.11,26.55 232.81,26.55 232.68,26.42 232.68,25.86 232.56,25.74 232.29,25.74 232.17,25.86 232.17,27.51 232.03,27.64 231.67,27.64 231.54,27.51 231.54,25.88 231.41,25.76 231.16,25.76 231.03,25.88 231.03,27.49 230.9,27.61 230.65,27.61 230.52,27.49 230.52,26.81 230.39,26.68 230.14,26.68 230.01,26.81 230.01,27.42 229.89,27.55 225.4,27.55 219.66,33.28 215.27,33.28 208.86,39.69 208.27,39.69 208.14,39.81 208.14,40.1 208.02,40.23 207.76,40.23 207.63,40.1 207.63,39.81 207.51,39.69 204.11,39.69 202.15,41.64 200.84,41.64 200.68,41.81 200.66,41.81 200.06,42.4 199.55,42.4 v4(199.55,42.4)
  BOTTOM w0.114: v3(250.06,25.67) 249.56,26.18 v1(249.56,26.46)
M_A_DQ6: length 79.9
  TOP w0.076: 194.1,44.02 194,43.92 193.62,43.92 193.54,44 193.35,44.08 193.14,44.08 192.98,44.02 192.87,44.02 192.71,44.08 192.53,44.08 192.36,44.02 192.18,44.02 191.94,43.97 191.48,43.97 191.28,44.16 CPU1.BV45
  TOP w0.089: v4(196.75,43.92) 196.42,44.25 194.33,44.25 194.1,44.02
  TOP w0.114: v3(253.93,25.92) 254.43,25.42 DIMM1.194
  L3 w0.127: v4(196.75,43.92) 196.96,43.92 200.32,40.56 202.13,40.56 204.04,38.66 208.43,38.66 214.84,32.25 219.24,32.25 224.99,26.49 227.23,26.49 229.99,23.73 237.01,23.73 237.19,23.91 240.3,23.91 241.1,24.71 247.87,24.71 248.46,24.13 254.77,24.13 254.9,24.25 254.9,24.84 254.77,24.96 254.09,24.96 253.93,25.13 v3(253.93,25.92)
  BOTTOM w0.114: v1(254.42,26.79) 254.29,26.79 254.17,26.68 254.17,26.42 253.93,26.17 v3(253.93,25.92)
M_A_DQ7: length 78.9
  TOP w0.076: CPU1.BV48 192.97,45.1 193.12,45.15 194.33,45.15 194.37,45.12
  TOP w0.089: 194.37,45.12 194.48,45 196.49,45 197.64,45 199.12,43.52 199.12,42.11 199.94,41.29 200.38,41.29 v4(200.52,41.43)
  TOP w0.114: DIMM1.191 250.99,26.17 v3(251.49,25.67)
  L3 w0.127: v4(200.52,41.43) 202.06,41.43 204.14,39.34 208.72,39.34 215.13,32.94 219.52,32.94 225.28,27.18 228.27,27.18 228.39,27.05 228.39,26.46 228.56,26.29 228.79,26.29 228.91,26.42 228.91,27.05 229.04,27.18 229.31,27.18 229.44,27.05 229.44,25.52 229.57,25.39 229.87,25.39 230,25.52 230,26.17 230.12,26.3 230.38,26.3 230.51,26.17 230.51,25.52 230.63,25.39 248.16,25.39 248.74,24.81 251.97,24.81 252.1,24.94 252.1,25.55 251.97,25.67 v3(251.49,25.67)
  BOTTOM w0.114: v3(251.49,25.67) 250.97,26.19 v1(250.97,26.46)
M_A_DQ8: length 90.9
  TOP w0.114: DIMM1.232 253.81,15.92 253.04,15.16 253.04,14.22 v3(253.03,14.21) ; CPU1.CC42 v4(189.79,42.97)
  L3 w0.127: v3(253.03,14.21) 253.45,14.63 256.07,14.63 256.19,14.5 256.19,13.79 256.07,13.66 252.48,13.66 252.18,13.36 241.38,13.36 241.18,13.56 237.12,13.56 236.9,13.34 234.17,13.34 233.51,13.99 231.89,13.99 231.53,13.62 230.85,13.62 230.18,14.3 227.47,14.3 227.25,14.52 227.22,14.52 223.95,17.79 222.58,17.79 215.21,25.16 211.85,25.16 205.89,31.12 205.89,31.12 205.86,31.15 198,31.15 194.84,34.31 194.84,34.5 194.12,35.22 193.68,35.22 193.02,35.87 193.02,37.84 191.92,38.94 191.92,39.48 191.92,39.48 191.92,39.57 191.21,40.28 191.21,41.92 190.62,42.51 190.25,42.51 v4(189.79,42.97)
M_A_DQ9: length 92.4
  TOP w0.114: DIMM1.233 250.48,15.67 251.38,14.77 251.38,11.46 v3(251.25,11.33) ; CPU1.CC39 v4(188.52,42.97)
  L3 w0.127: v4(188.52,42.97) 188.52,41.42 188.16,41.06 188.16,39.58 188.62,39.12 188.62,38.21 189.48,37.35 189.48,37.03 189.72,36.79 190.38,36.79 190.38,36.78 190.72,36.78 190.72,36.79 190.76,36.79 191.19,36.35 191.19,35.55 192.81,33.93 192.81,31.86 193.42,31.25 193.96,31.25 194.99,30.22 195.95,30.22 196.49,30.22 197.34,29.37 197.38,29.37 197.39,29.37 201.14,29.37 201.56,28.95 204.99,28.95 210.96,22.98 214.26,22.98 226.91,10.33 243.94,10.33 244.69,9.58 249.5,9.58 250.75,10.83 252.04,10.83 252.16,10.96 252.16,11.43 252.04,11.56 251.48,11.56 v3(251.25,11.33)
M_A_DQ10: length 89.4
  TOP w0.114: DIMM1.236 253.92,14.92 v3(253.74,15.1) ; CPU1.CC43 v4(190.42,42.97)
  L3 w0.127: v4(190.42,42.97) 190.57,42.97 191.43,42.11 191.43,40.37 192.14,39.66 192.14,39.39 192.14,39.03 193.24,37.93 193.24,37.7 194,36.94 194,36.4 195.22,35.18 195.22,34.23 197.85,31.61 205.89,31.61 205.89,31.6 205.89,31.6 206,31.49 206.01,31.49 206.03,31.46 206.04,31.46 211.99,25.51 215.35,25.51 222.72,18.14 224.12,18.14 227.61,14.64 230.32,14.64 231,13.97 231.39,13.97 231.75,14.33 236.63,14.33 237.01,13.96 240.94,13.96 240.96,13.94 241.28,13.94 241.52,13.7 250.96,13.7 250.96,13.7 253.43,16.18 253.43,16.27 254.15,16.99 256.3,16.99 256.42,16.86 256.42,16.07 256.3,15.94 254.12,15.94 253.74,15.56 v3(253.74,15.1)
M_A_DQ11: length 91.7
  TOP w0.114: v4(187.33,42.06) 187.61,41.78 CPU1.CE38 ; DIMM1.246 254.81,12.42 254.39,12 254.06,12 v3(254.06,11.98)
  L3 w0.127: v3(254.06,11.98) 254.16,11.88 254.16,11.34 254.26,11.24 254.26,10.75 253.63,10.12 252.72,10.12 251.12,8.52 243.7,8.52 242.92,9.29 227.38,9.29 227.37,9.29 226.49,9.29 213.89,21.9 210.58,21.9 205.01,27.47 205.01,27.48 204.73,27.75 204.73,27.75 204.58,27.9 200.71,27.9 200.05,28.56 197.23,28.56 196.22,29.57 194.72,29.57 193.69,30.6 193.16,30.6 192.17,31.59 192.17,33.44 191.55,34.05 189.61,34.05 185.62,38.04 185.62,39.21 185.67,39.25 185.67,40.4 v4(187.33,42.06)
M_A_DQ12: length 93.4
  TOP w0.114: v3(251.92,10) 250.78,11.13 250.78,11.52 251.03,11.76 251.03,12.79 250.03,13.78 250.03,14.27 249.63,14.67 DIMM1.237 ; v4(187.97,42.08) 187.97,42.17 CPU1.CC38
  L3 w0.127: v3(251.92,10) 251.92,9.8 250.98,8.86 243.84,8.86 243.07,9.64 227.52,9.64 227.52,9.64 226.63,9.64 214.03,22.24 210.72,22.24 205.35,27.61 205.35,27.62 204.87,28.09 204.87,28.09 204.72,28.24 201.11,28.24 200.42,28.94 197.21,28.94 197.21,28.94 197.16,28.94 196.31,29.79 196.13,29.79 194.81,29.79 193.78,30.81 193.25,30.81 192.38,31.68 192.38,33.75 191.23,34.9 189.08,34.9 188.42,35.56 188.42,36.65 187.6,37.47 186.68,37.47 186.22,37.92 186.22,38.57 186.46,38.8 186.46,40.88 187.26,41.68 187.57,41.68 v4(187.97,42.08)
M_A_DQ13: length 91.5
  TOP w0.114: v4(187.36,41.15) 187.67,41.15 188.13,41.61 CPU1.CE39 ; DIMM1.250 255.18,11.42 254.58,10.82 253.96,10.82 v3(253.78,11.01)
  L3 w0.127: v4(187.36,41.15) 187.33,41.11 187.33,39.73 187.61,39.45 187.61,38.92 187.85,38.67 188.03,38.67 188.34,38.37 188.34,38.11 188.98,37.47 188.98,36.76 188.81,36.59 188.81,36.16 189.09,35.89 190.17,35.89 190.94,35.12 191.32,35.12 192.6,33.84 192.6,31.77 193.33,31.03 193.87,31.03 194.9,30 196.04,30 196.04,30 196.4,30 197.25,29.16 197.3,29.16 197.3,29.15 200.73,29.15 201.29,28.59 204.87,28.59 210.82,22.64 214.12,22.64 226.77,9.98 243.2,9.98 243.31,9.88 243.49,9.88 243.6,9.98 243.78,9.98 243.96,9.8 243.96,9.62 243.85,9.52 243.85,9.34 243.98,9.21 249.61,9.21 250.24,9.83 250.42,9.83 250.84,9.41 251.02,9.41 251.2,9.59 251.2,9.77 250.78,10.19 250.78,10.37 250.89,10.49 252.99,10.49 253.12,10.61 253.12,11.31 253.24,11.44 253.55,11.44 253.68,11.31 253.68,11.11 v3(253.78,11.01)
  BOTTOM w0.114: v1(188.23,40.7) 188.2,40.7 188.19,40.71 187.8,40.71 v4(187.36,41.15)
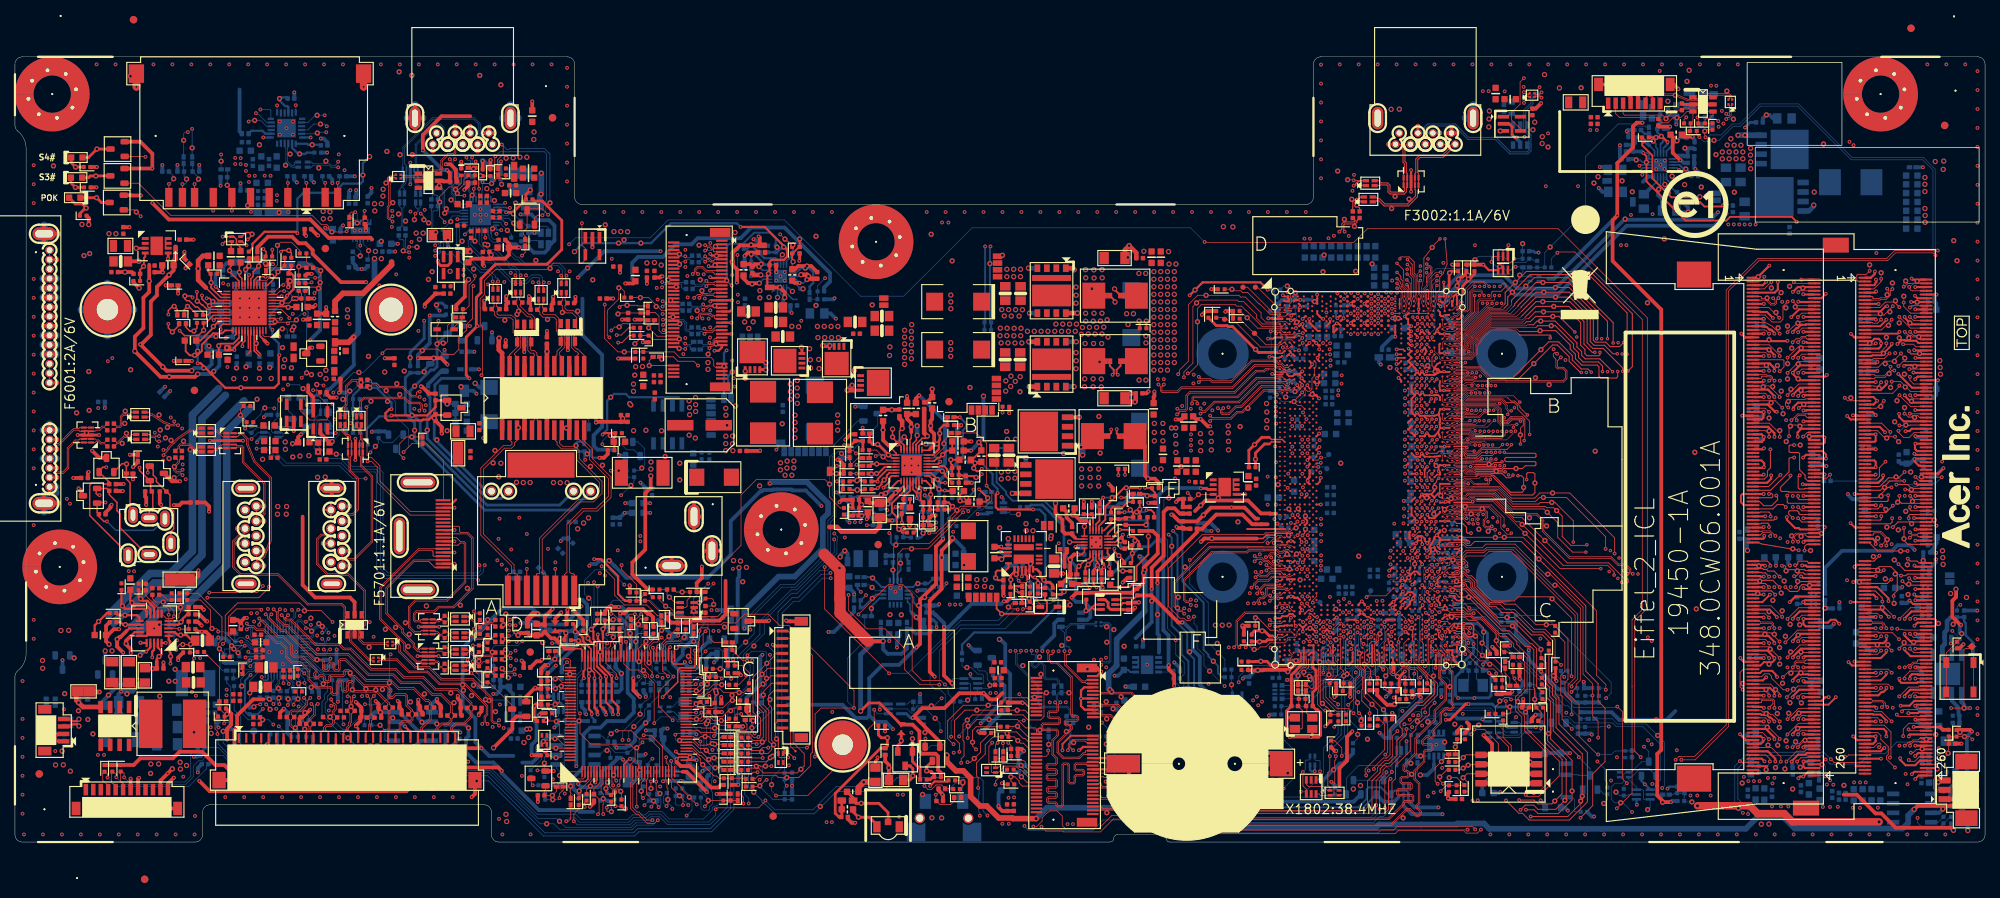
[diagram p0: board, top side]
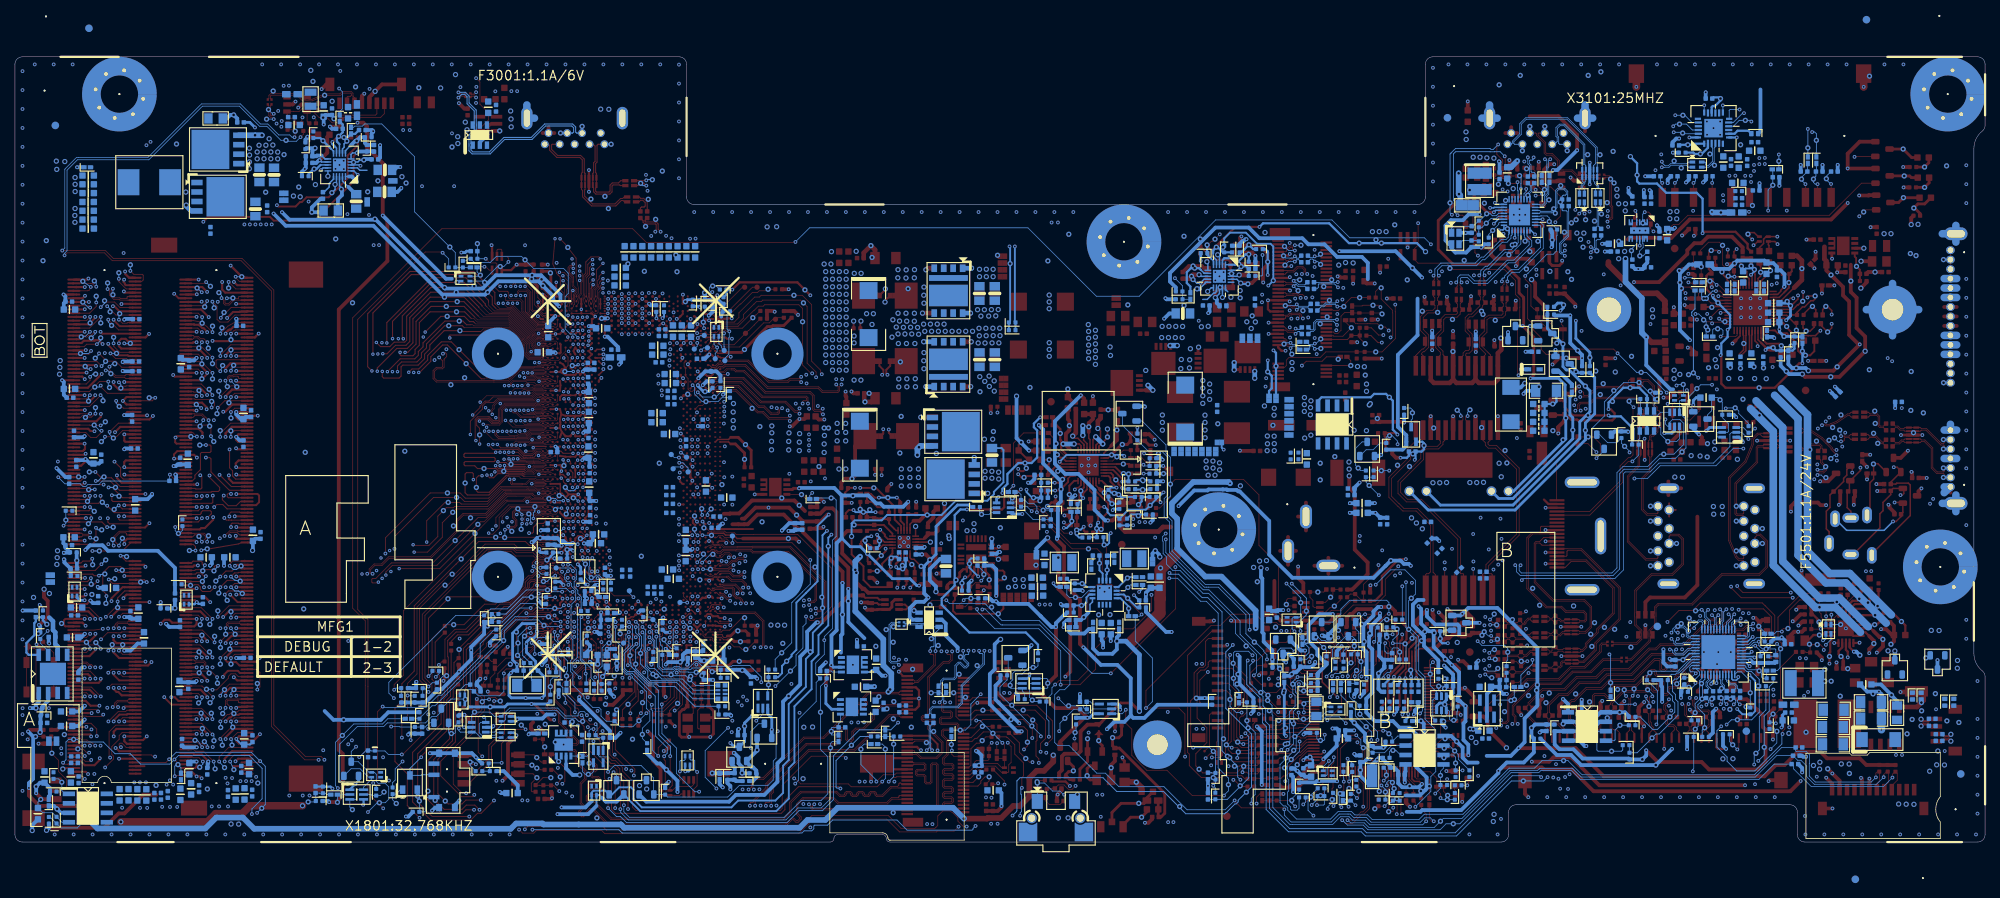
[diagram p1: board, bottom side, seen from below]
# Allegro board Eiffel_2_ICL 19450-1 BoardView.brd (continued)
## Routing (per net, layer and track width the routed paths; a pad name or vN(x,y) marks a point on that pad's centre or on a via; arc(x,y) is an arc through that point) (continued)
M_A_DQ14: length 89.5
  TOP w0.114: v3(245.22,11.46) 245.49,11.46 245.71,11.67 DIMM1.249 ; CPU1.CE42 v4(189.79,42.06)
  L3 w0.127: v4(189.79,42.06) 190.1,41.75 190.1,38.78 190.85,38.03 191.05,38.03 192.46,36.62 192.46,35.33 193.87,33.93 194.11,33.93 197.58,30.46 205.58,30.46 205.6,30.44 205.61,30.44 211.57,24.48 214.47,24.48 214.48,24.47 214.87,24.47 223.87,15.47 224.05,15.47 224.51,15.93 224.69,15.93 224.87,15.75 224.87,15.57 224.41,15.11 224.41,14.93 224.57,14.77 224.81,14.77 225.3,15.26 225.48,15.26 225.66,15.08 225.66,14.9 225.11,14.36 225.11,14.23 225.35,14 225.47,14 226.02,14.54 226.2,14.54 226.38,14.36 226.38,14.18 225.84,13.65 225.84,13.5 226.05,13.29 226.2,13.29 226.74,13.82 226.92,13.82 227.1,13.64 227.1,13.47 226.57,12.94 226.57,12.77 226.76,12.58 226.93,12.58 227.46,13.11 227.64,13.11 227.82,12.93 227.82,12.75 227.33,12.26 227.33,12.08 227.59,11.81 228.56,11.81 228.69,11.94 228.69,12.44 228.82,12.57 229.07,12.57 229.2,12.44 229.2,11.96 229.33,11.83 229.6,11.83 229.73,11.96 229.73,12.48 229.86,12.6 230.15,12.6 230.28,12.48 230.28,12.3 230.4,12.17 230.66,12.17 230.78,12.3 230.78,12.48 230.91,12.6 231.16,12.6 231.29,12.48 231.29,12.3 231.42,12.17 231.67,12.17 231.8,12.3 231.8,12.48 231.93,12.6 233.4,12.6 233.83,12.17 234.25,12.17 234.38,12.3 234.38,12.5 234.5,12.63 234.76,12.63 234.88,12.5 234.88,12.3 235.01,12.17 235.27,12.17 235.39,12.3 235.39,12.5 235.52,12.63 235.77,12.63 235.9,12.5 235.9,12.3 236.03,12.17 236.28,12.17 236.41,12.3 236.41,12.5 236.54,12.63 236.79,12.63 236.92,12.5 236.92,12.3 237.04,12.17 239.84,12.17 240.16,12.5 245.71,12.5 245.84,12.37 245.84,11.37 245.72,11.25 245.35,11.25 245.22,11.38 v3(245.22,11.46)
M_A_DQ15: length 89.1
  TOP w0.114: DIMM1.245 249.08,12.67 249.66,13.25 249.92,13.25 250.03,13.14 250.03,12.84 249.92,12.72 v3(249.8,12.72) ; CPU1.CE43 190.44,42.1 190.44,42.08 v4(190.46,42.08)
  L3 w0.127: v4(190.46,42.08) 190.46,42.07 190.99,41.53 190.99,40.19 191.71,39.48 191.71,38.85 192.81,37.75 192.81,35.96 192.81,35.78 193.59,35 194.03,35 194.62,34.41 194.62,34.22 198.04,30.8 205.72,30.8 205.75,30.78 205.75,30.78 211.71,24.82 215.07,24.82 223.11,16.77 223.29,16.77 223.8,17.28 223.98,17.28 224.19,17.06 224.19,16.88 223.71,16.4 223.71,16.22 223.89,16.04 224.07,16.04 224.55,16.52 224.73,16.52 228.26,12.99 228.62,12.99 228.75,13.12 228.75,13.68 228.88,13.8 229.13,13.8 229.26,13.68 229.26,13.12 229.39,12.99 229.64,12.99 229.77,13.12 229.77,13.68 229.89,13.8 230.15,13.8 230.27,13.68 230.27,13.12 230.4,12.99 231.82,12.99 231.95,13.12 231.95,13.5 232.08,13.63 232.33,13.63 232.46,13.5 232.46,13.12 232.58,12.99 232.84,12.99 232.96,13.12 232.96,13.5 233.09,13.63 233.35,13.63 233.47,13.5 233.47,13.12 233.6,12.99 237.04,12.99 237.26,13.22 240.93,13.22 241.23,12.92 246.32,12.92 246.45,12.79 246.45,11.55 246.58,11.42 246.83,11.42 246.96,11.55 246.96,12.79 247.09,12.92 247.81,12.92 247.94,12.79 247.94,12.32 248.07,12.19 248.32,12.19 248.45,12.32 248.45,12.59 248.58,12.72 v3(249.8,12.72)
  BOTTOM w0.114: v1(191.54,41.79) 190.75,41.79 v4(190.46,42.08)
M_A_DQ16: length 75.7
  TOP w0.076: CPU1.BT48 192.97,45.96 193.14,45.9 194.77,45.9 194.9,46.03
  TOP w0.089: 201.14,42.95 199.97,44.11 199.97,44.12 198.25,45.84 198.15,45.84 198.14,45.85 198,45.85 197.99,45.84 195.92,45.84 195.57,46.2 195.06,46.2 194.9,46.03
  TOP w0.114: DIMM1.183 249.68,28.17 249.8,28.06 250.44,28.06 250.46,28.07 251.58,28.07 v3(252.47,27.19) ; v4(214.29,35.8) 214.29,36.23 213.41,37.11 207.46,37.11 v1(201.97,42.6) 201.61,42.95 201.14,42.95
  L3 w0.127: v4(214.29,35.8) 214.09,35.6 214.09,35.42 215.55,33.96 219.95,33.96 225.42,28.49 232.27,28.49 233.36,27.4 239.94,27.4 240.21,27.13 240.21,26.65 240.37,26.49 251.05,26.49 251.18,26.61 251.18,27.21 251.31,27.34 251.69,27.34 251.82,27.21 251.82,26.9 251.94,26.77 252.34,26.77 252.47,26.9 v3(252.47,27.19)
M_A_DQ17: length 75.8
  TOP w0.076: 198.07,45.67 195.85,45.67 195.5,46.02 195.18,46.02 194.88,45.73 193.14,45.73 192.64,45.9 192.31,45.9 CPU1.BT47
  TOP w0.089: 198.07,45.67 201.54,42.2
  TOP w0.114: DIMM1.186 254.43,27.42 v3(253.93,27.93) ; v4(212.51,36.66) 207.07,36.66 v1(202.35,41.39) 201.54,42.2
  L3 w0.127: v4(212.51,36.66) 212.51,36.52 215.41,33.62 219.81,33.62 225.36,28.07 232.09,28.07 234.01,26.14 251.62,26.14 251.87,26.39 254.53,26.39 254.67,26.54 254.67,27.18 254.55,27.31 254.15,27.31 253.93,27.53 v3(253.93,27.93)
M_A_DQ18: length 74.5
  TOP w0.076: CPU1.BT49 193.32,46.07 194.69,46.07 195,46.38 196.84,46.38
  TOP w0.089: 200.17,44.19 197.98,46.38 196.84,46.38
  TOP w0.114: v4(215.3,34.85) 215.4,34.75 216.07,34.75 216.18,34.86 216.18,35.24 216.07,35.35 215.64,35.35 213.55,37.44 208.01,37.44 v1(205.01,40.44) 204.35,41.1 204.35,41.1 203.89,41.55 203.89,41.55 201.93,43.52 200.84,43.52 200.17,44.19 ; DIMM1.187 249.66,27.17 250.08,27.6 v3(250.07,27.6)
  L3 w0.127: v3(250.07,27.6) 250.3,27.37 250.3,26.96 250.17,26.83 244.26,26.83 244.13,26.96 244.13,27.45 244,27.58 243.75,27.58 243.62,27.45 243.62,26.96 243.49,26.83 243.24,26.83 243.11,26.96 243.11,27.47 242.99,27.6 242.73,27.6 242.61,27.47 242.61,26.96 242.48,26.83 242.22,26.83 242.1,26.96 242.1,27.47 241.97,27.6 241.72,27.6 241.59,27.47 241.59,26.96 241.46,26.83 241.1,26.83 240.97,26.96 240.97,27.44 240.85,27.57 240.26,27.57 240.09,27.74 233.96,27.74 232.86,28.84 225.56,28.84 220.09,34.31 215.85,34.31 215.4,34.75 215.4,34.75 v4(215.3,34.85)
M_A_DQ19: length 74
  TOP w0.076: 197.61,47.31 195.44,47.31 195.44,47.3 195.16,47.3 195.15,47.31 194.32,47.31 194.16,47.47 193.29,47.47 CPU1.BN49
  TOP w0.089: 197.61,47.31 198.72,47.31 200.71,45.32
  TOP w0.114: 200.71,45.32 204.18,45.32 204.4,45.55 v1(205.94,45.55) 206.37,45.55 208.82,43.09 v4(208.82,40.22) ; v3(253.95,29.93) 254.45,30.42 DIMM1.174
  L3 w0.127: v3(253.95,29.93) 253.95,31.27 253.52,31.69 226.75,31.69 221.28,37.16 218.36,37.16 218,37.52 217.39,37.52 214.6,40.31 210.3,40.31 210.17,40.19 210.17,39.76 210.04,39.63 209.67,39.63 209.54,39.76 209.54,40.1 209.41,40.22 v4(208.82,40.22)
M_A_DQ20: length 76.7
  TOP w0.076: CPU1.BT45 191.28,46.87 191.34,46.99 191.5,47.09 191.94,47.09 192.18,47.04 192.36,47.04 192.53,46.98 192.71,46.98 192.87,47.05 192.98,47.05 193.14,46.99 193.35,46.99 193.72,47.14 193.97,47.14 194.16,46.95 197.46,46.95
  TOP w0.089: 200.75,44.66 200.59,44.66 198.3,46.95 197.46,46.95
  TOP w0.114: 200.75,44.66 204.89,44.66 v1(205.33,44.22) 206.73,42.82 206.73,40.87 208.06,39.54 208.27,39.33 208.72,38.88 v4(210.5,38.88) ; DIMM1.182 253.39,28.42 v3(252.22,28.59)
  L3 w0.127: v3(252.22,28.59) 252.22,28.27 252.1,28.15 249.01,28.15 248.79,27.92 248.79,27.38 248.66,27.26 244.81,27.26 244.12,27.94 240.37,27.94 240.23,28.08 234.1,28.08 233,29.18 225.7,29.18 220.23,34.65 216.27,34.65 213.79,37.13 212.24,37.13 212.03,37.35 212.03,38.36 211.73,38.67 210.71,38.67 v4(210.5,38.88)
M_A_DQ21: length 76.2
  TOP w0.076: 197.54,47.13 195.1,47.13 195.08,47.14 194.2,47.14 194.04,47.3 193.67,47.3 193.3,47.15 193.17,47.15 193,47.21 192.84,47.21 192.67,47.15 192.56,47.15 192.22,47.27 CPU1.BN47
  TOP w0.089: 200.65,44.99 198.51,47.13 197.54,47.13
  TOP w0.114: v4(210.64,39.87) 210.56,39.78 208.51,39.78 207.34,40.96 207.34,43.7 v1(206.58,44.45) 206.19,44.84 205.24,44.84 205.08,44.99 200.65,44.99 ; DIMM1.170 254.02,31.42 v3(252.52,29.93)
  L3 w0.127: v3(252.52,29.93) 252.53,29.94 252.53,30.48 252.69,30.64 253.25,30.64 253.33,30.73 253.33,31.2 253.21,31.33 248.86,31.33 248.62,31.09 247.44,31.09 247.18,31.35 226.61,31.35 221.13,36.82 218.21,36.82 217.86,37.18 217.12,37.18 214.43,39.87 v4(210.64,39.87)
M_A_DQ22: length 77
  TOP w0.076: 195.3,47.64 194.51,47.64 194.3,47.84 193.13,47.84 192.8,47.71 191.58,47.71 CPU1.BN45
  TOP w0.089: 200.45,46.18 198.94,47.69 195.35,47.69 195.3,47.64
  TOP w0.114: v3(214.35,38.69) 214.35,40.8 208.34,46.81 v1(206.05,46.81) 204.34,46.81 203.64,46.12 200.51,46.12 200.45,46.18 ; DIMM1.169 250.33,31.67 v3(251.81,30.19)
  L3 w0.127: v3(251.81,30.19) 251.02,30.99 249,30.99 248.56,30.54 245.01,30.54 244.88,30.67 244.88,30.88 244.76,31.01 244.5,31.01 244.37,30.88 244.37,30.46 244.25,30.33 243.99,30.33 243.87,30.46 243.87,30.88 243.74,31.01 243.49,31.01 243.36,30.88 243.36,30.45 243.23,30.32 242.98,30.32 242.85,30.45 242.85,30.88 242.72,31.01 226.46,31.01 220.99,36.48 218.07,36.48 217.72,36.84 216.93,36.84 215.08,38.69 v3(214.35,38.69)
M_A_DQ23: length 75.3
  TOP w0.076: CPU1.BN48 192.64,47.46 193.17,47.68 194.18,47.68 194.39,47.47 195.22,47.47 195.23,47.47 195.37,47.47 195.4,47.49 198.83,47.49
  TOP w0.089: 198.83,47.49 200.41,45.91
  TOP w0.114: v3(213.15,39.32) 213.15,40.96 207.89,46.22 v1(204.82,46.22) 204.3,46.22 203.74,45.65 200.67,45.65 200.41,45.91 ; DIMM1.173 249.55,30.67 250.03,30.2 v3(250.05,30.2)
  L3 w0.127: v3(250.05,30.2) 250.05,30.52 249.93,30.64 249.15,30.64 248.7,30.2 245.84,30.2 245.4,29.76 243.1,29.76 242.79,29.45 242.43,29.45 242.26,29.62 242.26,30.54 242.14,30.66 241.88,30.66 241.76,30.54 241.76,29.59 241.63,29.46 241.37,29.46 241.25,29.59 241.25,30.54 241.12,30.66 240.87,30.66 240.74,30.54 240.74,29.69 240.62,29.57 240.35,29.57 240.23,29.69 240.23,30.54 240.1,30.66 226.32,30.66 220.85,36.14 217.93,36.14 217.57,36.49 216.79,36.49 215.63,37.65 213.48,37.65 212.9,38.24 212.9,39.07 v3(213.15,39.32)
M_A_DQ24: length 88.9
  TOP w0.114: DIMM1.212 255.19,20.92 255.04,20.78 253.75,20.78 v3(252.5,19.53) ; v4(189.88,45.79) 189.56,45.47 CPU1.BV42
  L3 w0.127: v3(252.5,19.53) 253.05,20.08 254.56,20.08 254.68,20.21 254.68,20.54 254.56,20.67 252.18,20.67 251.01,19.49 248.34,19.49 247.08,18.23 237,18.23 236.76,18.47 234.13,18.47 233.5,17.84 230.28,17.84 225.17,22.95 222.44,22.95 216.68,28.71 216.3,28.71 213.37,28.71 207.14,34.94 204.38,34.94 200.74,38.58 197.9,38.58 195.7,40.79 194.37,40.79 193.94,41.21 193.94,42.14 193.32,42.76 193.32,43.82 192.28,44.86 192.28,45.77 191.86,46.19 190.28,46.19 v4(189.88,45.79)
  BOTTOM w0.114: v1(191.07,46.46) 190.55,46.46 v4(189.88,45.79)
M_A_DQ25: length 88.9
  TOP w0.114: CPU1.BV39 v4(188.52,45.72) ; v3(251.49,20.67) 250.99,21.17 DIMM1.211
  L3 w0.127: v3(251.49,20.67) 250.85,20.04 249.91,20.04 249.72,19.85 248.21,19.85 246.94,18.57 237.14,18.57 236.9,18.81 233.99,18.81 233.36,18.18 233.1,18.18 232.97,18.31 232.97,18.89 232.84,19.02 232.59,19.02 232.46,18.89 232.46,18.31 232.34,18.18 230.43,18.18 225.32,23.29 223.67,23.29 222.98,23.98 222.6,23.98 222.35,23.73 222.17,23.73 221.99,23.91 221.99,24.09 222.34,24.44 222.34,24.62 222.16,24.8 221.98,24.8 221.64,24.47 221.46,24.47 221.28,24.65 221.28,24.83 221.62,25.16 221.62,25.34 221.44,25.52 221.26,25.52 220.94,25.2 220.76,25.2 220.58,25.38 220.58,25.56 220.9,25.88 220.9,26.06 220.72,26.24 220.54,26.24 220.21,25.91 220.03,25.91 219.85,26.09 219.85,26.27 220.18,26.6 220.18,26.78 217.91,29.05 215.42,29.05 215.42,29.05 213.51,29.05 207.28,35.28 204.39,35.28 200.88,38.8 197.99,38.8 195.79,41.01 195.35,41.01 195.34,41.02 194.46,41.02 194.16,41.32 194.16,42.22 193.53,42.85 193.53,43.91 192.5,44.95 192.5,45.86 191.95,46.41 190.16,46.41 190,46.25 189.24,46.25 188.71,45.72 v4(188.52,45.72)
  BOTTOM w0.114: v4(188.52,45.72) 188.96,46.16 v1(189.18,46.16)
M_A_DQ26: length 86.7
  TOP w0.114: v4(190.51,45.78) 190.21,45.47 CPU1.BV43 ; v3(253.92,19.53) 254.41,20.02 255.04,20.02 255.13,19.92 DIMM1.216
  L3 w0.127: v3(253.92,19.53) 254.12,19.33 254.12,19 253.88,18.76 248.28,18.76 247.41,17.89 237.07,17.89 236.68,17.51 236.29,17.51 236.29,17.5 230.04,17.5 228.96,18.58 228.78,18.58 228.44,18.25 228.26,18.25 228.02,18.48 228.02,18.66 228.37,19.01 228.37,19.19 228.19,19.37 228.01,19.37 227.66,19.02 227.48,19.02 227.3,19.2 227.3,19.38 227.65,19.73 227.65,19.9 227.47,20.08 227.29,20.08 226.95,19.74 226.77,19.74 226.59,19.92 226.59,20.1 226.93,20.44 226.93,20.62 224.94,22.61 222.29,22.61 216.54,28.36 213.23,28.36 207,34.6 204.3,34.6 200.53,38.37 197.81,38.37 196.44,39.74 194.48,39.74 193.1,41.12 193.1,43.73 191.58,45.25 191.56,45.25 191.32,45.49 191.32,45.51 191.06,45.78 v4(190.51,45.78)
  BOTTOM w0.114: v1(192.44,46.05) 192.42,46.07 191.56,46.07 191.27,45.78 v4(190.51,45.78)
M_A_DQ27: length 86.9
  TOP w0.089: CPU1.BW38 187.61,44.17 v4(187.9,43.88)
  TOP w0.114: DIMM1.224 255.04,17.92 254.87,17.76 253.1,17.76 v3(252.86,17.52)
  L3 w0.127: v4(187.9,43.88) 188.38,43.4 190.55,43.4 191.64,42.31 191.64,40.46 192.36,39.74 192.36,39.3 192.36,39.12 193.5,37.97 193.54,37.97 194.33,37.97 195.79,36.51 195.79,34.12 197.96,31.95 205.61,31.95 205.61,31.95 206.03,31.95 206.17,31.81 206.18,31.81 212.14,25.85 215.49,25.85 222.86,18.48 224.39,18.48 227.89,14.98 233.4,14.98 233.71,14.68 237.1,14.68 237.4,14.98 239.88,14.98 240.21,14.64 251.31,14.64 252.5,15.83 252.5,16.75 252.63,16.88 253.12,16.88 253.25,17.01 253.25,17.4 253.12,17.52 v3(252.86,17.52)
M_A_DQ28: length 88
  TOP w0.114: v3(250.06,20.67) 249.56,20.17 DIMM1.215 ; CPU1.BV38 v4(187.89,45.72)
  L3 w0.127: v4(187.89,45.72) 188.32,46.15 188.76,46.15 189.08,46.46 189.91,46.46 190.07,46.62 192.04,46.62 192.84,45.82 192.84,45.59 193.71,44.72 193.94,44.72 194.2,44.46 194.2,43.61 194.15,43.55 194.15,42.57 194.88,41.85 195.29,41.85 198.13,39.01 201.04,39.01 204.41,35.64 207.41,35.64 213.66,29.39 215.28,29.39 218.05,29.39 223.81,23.64 226.04,23.64 229.03,20.65 230.63,20.65 231.05,20.23 231.05,18.64 231.14,18.55 231.51,18.55 231.63,18.68 231.63,19.78 231.76,19.91 232.3,19.91 232.43,19.78 232.43,19.49 232.54,19.37 232.81,19.37 232.93,19.49 232.93,20.38 233.06,20.51 233.33,20.51 233.45,20.38 233.45,19.68 233.99,19.15 237.05,19.15 237.28,18.92 240.48,18.92 240.6,19.04 240.6,19.64 240.73,19.77 240.98,19.77 241.11,19.64 241.11,19.04 241.24,18.92 241.49,18.92 241.62,19.04 241.62,19.64 241.75,19.77 242,19.77 242.13,19.64 242.13,19.04 242.25,18.92 244.65,18.92 244.78,19.04 244.78,19.53 244.91,19.66 245.16,19.66 245.29,19.53 245.29,19.04 245.42,18.92 245.67,18.92 245.8,19.04 245.8,19.53 245.92,19.66 247.54,19.66 248.07,20.19 249.58,20.19 v3(250.06,20.67)
M_A_DQ29: length 86.5
  TOP w0.089: v4(187.87,44.81) 187.87,44.74 CPU1.BW39
  TOP w0.114: v3(252.17,17.09) 252.43,16.83 254.41,16.83 254.47,16.89 254.85,16.89 254.9,16.84 256.01,16.84 DIMM1.228
  L3 w0.127: v3(252.17,17.09) 252.15,17.07 252.15,15.97 251.17,14.99 240.35,14.99 240.02,15.32 237.26,15.32 236.96,15.02 233.85,15.02 233.54,15.33 228.03,15.33 224.54,18.82 223,18.82 215.64,26.19 212.28,26.19 206.32,32.15 206.32,32.15 206.12,32.35 198.04,32.35 196.29,34.1 196.29,36.44 194.54,38.19 193.59,38.19 192.57,39.21 192.57,39.83 192.02,40.39 192.02,43.18 191.53,43.66 190.6,43.66 189.96,44.3 188.38,44.3 v4(187.87,44.81)
M_A_DQ30: length 85.7
  TOP w0.114: DIMM1.225 248.98,17.67 249.17,17.49 250.16,17.49 v3(251.48,16.17) ; v4(189.95,44.79) 189.95,44.78 189.56,44.38 CPU1.BW42
  L3 w0.127: v4(189.95,44.79) 190.81,43.94 191.59,43.94 192.23,43.29 192.23,40.51 192.79,39.96 192.79,39.3 193.56,38.53 194.64,38.53 196.55,36.62 196.55,34.35 198.21,32.69 206.26,32.69 206.46,32.49 206.46,32.49 212.42,26.53 215.78,26.53 221.54,20.78 223.07,20.78 223.29,20.56 223.29,20.38 222.78,19.87 222.78,19.69 222.95,19.51 223.13,19.51 223.64,20.02 223.82,20.02 224,19.84 224,19.66 223.9,19.55 223.9,19.37 224.07,19.19 224.25,19.19 224.36,19.3 224.54,19.3 228.18,15.67 233.69,15.67 233.99,15.36 236.82,15.36 237.12,15.66 240.16,15.66 240.46,15.36 251.06,15.36 251.48,15.78 v3(251.48,16.17)
  BOTTOM w0.114: v1(190.12,43.98) 189.95,44.15 v4(189.95,44.79)
M_A_DQ31: length 84.1
  TOP w0.114: v4(190.75,44.78) 190.32,44.35 CPU1.BW43 ; v3(250.05,16.17) 249.55,16.67 DIMM1.229
  L3 w0.127: v4(190.75,44.78) 191.11,44.78 191.29,44.6 191.32,44.6 192.45,43.47 192.45,40.86 193.12,40.18 193.12,39.3 193.62,38.8 194.76,38.8 196.77,36.79 196.77,34.7 198.43,33.03 201.29,33.03 201.41,33.16 201.41,34.04 201.54,34.17 201.8,34.17 201.92,34.04 201.92,33.16 202.05,33.03 202.3,33.03 202.43,33.16 202.43,34.08 202.55,34.21 202.81,34.21 202.93,34.08 202.93,33.16 203.06,33.03 203.31,33.03 203.44,33.16 203.44,33.6 203.57,33.72 203.82,33.72 203.95,33.6 203.95,33.16 204.08,33.03 206.4,33.03 206.6,32.84 206.6,32.84 212.56,26.88 212.58,26.88 215.92,26.88 221.68,21.12 223.21,21.12 228.32,16.01 233.83,16.01 234.14,15.7 236.67,15.7 236.83,15.87 236.84,15.87 236.98,16.01 240.31,16.01 240.62,15.7 249.58,15.7 v3(250.05,16.17)
  BOTTOM w0.114: v4(190.75,44.78) 191.39,44.78 v1(191.58,44.6)
M_A_DQ32: length 76.8
  TOP w0.076: v4(196.84,53.24) 196.49,53.59 195.17,53.59 195,53.42 193.12,53.42 192.89,53.51 CPU1.AY48
  TOP w0.114: DIMM1.84 254.51,54.92 253.83,54.25 253.09,54.25 252.39,54.95 v3(252.39,55.15)
  L3 w0.127: v4(196.84,53.24) 196.84,53.7 197.61,54.47 201.27,54.47 201.87,55.06 201.87,55.11 203.53,56.78 203.69,56.78 204.51,57.6 204.69,57.6 204.84,57.6 206.16,58.92 209.99,58.92 210.31,58.6 210.31,57.95 210.43,57.82 210.69,57.82 210.81,57.95 210.81,58.8 210.94,58.92 211.19,58.92 211.32,58.8 211.32,57.95 211.45,57.82 211.7,57.82 211.83,57.95 211.83,58.68 211.96,58.81 212.21,58.81 212.34,58.68 212.34,57.95 212.46,57.82 212.72,57.82 212.85,57.95 212.85,58.15 212.97,58.28 213.23,58.28 213.35,58.15 213.35,57.99 213.49,57.85 220.47,57.85 222.48,59.87 233.38,59.87 234,60.49 239.72,60.49 243.78,56.43 244.35,56.43 244.8,55.98 251.56,55.98 v3(252.39,55.15)
  BOTTOM w0.114: v3(252.39,55.15) 252.61,55.15 v1(253.38,55.92)
M_A_DQ33: length 77.2
  TOP w0.076: CPU1.AY47 192.22,53.81 192.56,53.92 192.67,53.92 192.84,53.86 193,53.86 193.17,53.92 193.3,53.92 193.45,53.86 193.54,53.76 194.52,53.76 v4(194.7,53.95)
  TOP w0.114: v3(252.53,59.92) 252.53,59.89 254,58.42 DIMM1.70
  L3 w0.127: v4(194.7,53.95) 195.23,54.48 195.23,55.64 195.59,56 198.14,56 198.24,56.11 198.54,56.11 198.97,56.53 198.97,56.93 202.84,60.8 203.51,60.8 204.91,62.21 209.41,62.21 209.55,62.35 220.44,62.35 221.16,63.08 225.21,63.08 225.4,63.26 225.4,64.58 225.53,64.7 225.78,64.7 225.91,64.58 225.91,63.35 226.04,63.22 226.29,63.22 226.42,63.35 226.42,64.58 226.54,64.7 236.28,64.7 237.12,64.7 237.4,64.43 240.31,64.43 244.46,60.28 251.17,60.28 251.3,60.15 251.3,60.03 251.42,59.9 251.68,59.9 251.81,60.03 251.81,60.15 251.93,60.28 252.28,60.28 252.53,60.02 v3(252.53,59.92)
  BOTTOM w0.114: v1(252.2,59.18) 252.2,59.59 v3(252.53,59.92)
M_A_DQ34: length 76
  TOP w0.076: v4(197.43,53.24) 196.91,53.75 195.08,53.75 194.92,53.59 193.3,53.59 CPU1.AY49
  TOP w0.114: DIMM1.79 250.13,56.17 v3(251.31,55)
  L3 w0.127: v4(197.43,53.24) 198.43,54.25 201.36,54.25 202.08,54.97 202.08,55.02 203.49,56.43 203.82,56.43 203.85,56.46 203.86,56.46 204.66,57.26 204.83,57.26 204.83,57.26 204.98,57.26 205.16,57.44 206.06,57.44 206.19,57.56 206.19,58.3 206.32,58.42 206.57,58.42 206.7,58.3 206.7,57.56 206.83,57.44 207.08,57.44 207.21,57.56 207.21,58.45 207.33,58.58 207.59,58.58 207.72,58.45 207.72,57.56 207.84,57.44 208.1,57.44 208.22,57.56 208.22,58.45 208.35,58.58 208.6,58.58 208.73,58.45 208.73,57.56 208.86,57.44 209.11,57.44 209.24,57.56 209.24,58.45 209.37,58.58 209.62,58.58 209.75,58.45 209.75,57.56 209.87,57.44 220.54,57.44 222.63,59.53 233.52,59.53 234.14,60.14 236.67,60.14 236.95,59.87 236.95,59.86 237.45,59.35 240.37,59.35 243.64,56.09 244.21,56.09 244.66,55.64 250.67,55.64 v3(251.31,55)
  BOTTOM w0.114: v3(251.31,55) 251.31,54.67 v1(250.81,54.18)
M_A_DQ35: length 76.7
  TOP w0.076: v4(201.07,55.11) 199.89,53.93 196.85,53.93 196.85,53.93 195.22,53.93 194.84,54.3 194.54,54.3 194.17,53.93 193.62,53.93 193.54,54.01 193.35,54.08 193.14,54.08 192.98,54.03 192.87,54.03 192.71,54.09 192.53,54.09 192.36,54.03 192.18,54.03 191.94,53.98 191.48,53.98 191.28,54.17 CPU1.AU45
  TOP w0.114: v3(251.94,54.36) 250.39,54.36 249.57,55.17 DIMM1.83
  L3 w0.127: v3(251.94,54.36) 252.57,54.36 252.86,54.65 252.86,55.28 253.01,55.43 253.01,56.05 252.39,56.67 245.09,56.67 244.64,57.12 244.06,57.12 240.01,61.17 233.71,61.17 233.09,60.55 222.2,60.55 220.31,58.67 217.06,58.67 215.99,59.73 210.49,59.73 210.4,59.64 205.9,59.64 204.55,58.29 204.23,58.29 203.21,57.27 203.21,57.25 v4(201.07,55.11)
  BOTTOM w0.114: v3(251.94,54.36) 251.94,54.17 v1(252.42,53.7)
M_A_DQ36: length 77.4
  TOP w0.076: v4(195.67,53.23) 195.67,53.24 193.09,53.24 192.82,53.35 191.83,53.35 191.52,53.66 CPU1.AY45
  TOP w0.114: DIMM1.80 253.97,55.92 253.91,55.87 v3(252.53,55.87)
  L3 w0.127: v3(252.53,55.87) 252.53,56.05 252.25,56.32 244.95,56.32 244.5,56.77 243.92,56.77 239.87,60.83 233.85,60.83 233.23,60.21 222.34,60.21 220.44,58.31 216.17,58.31 215.9,58.58 215.9,59.27 215.78,59.39 215.52,59.39 215.39,59.27 215.39,58.32 215.27,58.2 215.01,58.2 214.89,58.32 214.89,59.19 214.76,59.31 214.51,59.31 214.38,59.19 214.38,58.46 214.25,58.33 214,58.33 213.87,58.46 213.87,59.02 213.74,59.15 213.48,59.15 213.36,59.03 213.36,58.77 213.24,58.65 212.98,58.65 212.85,58.77 212.85,59.17 212.73,59.3 206.05,59.3 204.69,57.94 204.37,57.94 201.44,55.01 201.44,54.94 201.18,54.68 196.08,54.68 195.67,54.28 v4(195.67,53.23)
  BOTTOM w0.114: v3(252.53,55.87) 252.38,55.87 v1(251.88,56.36)
M_A_DQ37: length 76.2
  TOP w0.076: CPU1.AU47 192.22,55.21 192.76,55.21 193.09,55.33 195,55.33 195.01,55.31 195.03,55.31 195.54,54.8 196.23,54.8 196.33,54.91 v4(196.33,55.1)
  TOP w0.114: DIMM1.67 245.6,59.17 v3(245.2,59.58)
  L3 w0.127: v4(196.33,55.1) 196.08,55.35 196.08,55.63 196.21,55.76 198.2,55.76 198.33,55.89 198.63,55.89 199.26,56.52 199.75,56.52 202.19,58.96 202.19,59.14 201.95,59.39 201.95,59.52 202.89,60.46 203.65,60.46 205.06,61.86 209.55,61.86 209.69,62 220.58,62 221.31,62.73 226.77,62.73 226.9,62.86 226.9,64.24 227.01,64.35 227.3,64.35 227.41,64.24 227.41,62.87 227.53,62.75 227.79,62.75 227.91,62.87 227.91,64.19 228.02,64.29 228.32,64.29 228.42,64.19 228.42,62.89 228.55,62.76 228.8,62.76 228.93,62.89 228.93,64.19 229.06,64.32 229.31,64.32 229.44,64.19 229.44,63.1 229.57,62.97 229.82,62.97 229.95,63.1 229.95,64.2 230.07,64.33 230.33,64.33 230.45,64.2 230.45,63.03 230.58,62.91 230.84,62.91 230.96,63.03 230.96,64.23 231.09,64.36 235.53,64.36 235.53,64.36 236.95,64.36 237.22,64.09 240.17,64.09 244.68,59.58 v3(245.2,59.58)
  BOTTOM w0.114: v1(246.01,59.58) v3(245.2,59.58)
M_A_DQ38: length 75
  TOP w0.076: CPU1.AU48 193.12,55.16 194.94,55.16 195.47,54.64 195.48,54.64 195.52,54.6 196.5,54.6 196.92,55.02 v4(196.92,55.08)
  TOP w0.114: DIMM1.71 249.45,58.17 v3(250.43,59.16)
  L3 w0.127: v3(250.43,59.16) 250.66,59.16 250.79,59.29 250.79,59.81 250.66,59.93 249.2,59.93 249.03,59.76 249.03,59.24 248.9,59.11 248.59,59.11 248.46,59.24 248.46,59.63 248.34,59.76 248.08,59.76 247.96,59.63 247.96,59.24 247.83,59.11 247.57,59.11 247.45,59.24 247.45,59.63 247.32,59.76 247.07,59.76 246.94,59.63 246.94,59.24 246.81,59.11 246.56,59.11 246.43,59.24 246.43,59.63 246.3,59.76 246.05,59.76 245.92,59.63 245.92,59.24 245.8,59.11 244.66,59.11 240.03,63.74 237.08,63.74 236.81,64.02 235.39,64.02 232.74,64.02 232.62,63.89 232.62,63.44 232.49,63.31 232.14,63.31 232.02,63.43 232.02,63.89 231.89,64.02 231.55,64.02 231.43,63.89 231.43,62.51 231.3,62.38 221.44,62.38 220.72,61.66 209.83,61.66 209.69,61.52 205.2,61.52 203.79,60.11 203.36,60.11 202.74,59.49 202.74,59.2 199.84,56.31 199.35,56.31 198.72,55.67 198.42,55.67 198.29,55.54 197.39,55.54 v4(196.92,55.08)
  BOTTOM w0.114: v1(250.02,58.41) 250.43,58.82 v3(250.43,59.16)
M_A_DQ39: length 74.3
  TOP w0.076: v4(198.09,55.08) 198.1,55.08 198.1,54.92 197.73,54.55 196.72,54.55 196.6,54.43 195.45,54.43 195.41,54.47 195.4,54.47 194.89,54.98 193.44,54.98 193.38,54.92 CPU1.AU49
  TOP w0.114: v3(253.95,59.92) 254.45,59.42 DIMM1.66
  L3 w0.127: v3(253.95,59.92) 254.46,60.44 255.04,60.44 255.16,60.31 255.16,59.09 255.04,58.96 252.01,58.96 251.74,58.69 244.6,58.69 239.88,63.4 236.93,63.4 236.66,63.67 235.25,63.67 235.25,63.67 233.34,63.67 231.71,62.04 221.58,62.04 220.86,61.32 209.98,61.32 209.83,61.18 205.34,61.18 203.94,59.77 203.53,59.77 202.95,59.19 202.95,59.11 199.93,56.09 199.63,56.09 198.99,55.46 198.51,55.46 198.13,55.08 v4(198.09,55.08)
  BOTTOM w0.114: v3(253.95,59.92) 254.14,59.74 v1(254.14,59.13)
M_A_DQ40: length 88
  TOP w0.089: CPU1.AY42 189.56,53.58 v4(189.92,53.94)
  TOP w0.114: v3(250.06,70.05) 249.59,69.58 248.98,69.58 248.88,69.67 DIMM1.25
  L3 w0.089: v4(189.92,53.94) 189.94,53.94 190.45,54.45 191.73,54.45 192.54,55.26 192.54,59.55 192.95,59.96 192.95,62.89 193.36,63.31 193.36,64.76 193.69,65.09 193.69,65.49 194.28,66.08
  L3 w0.127: v3(250.06,70.05) 250.06,69.72 249.94,69.59 248.72,69.59 246.99,71.32 246.96,71.32 245.29,72.99 245.11,72.99 244.77,72.65 244.59,72.65 244.41,72.83 244.41,73.01 244.75,73.34 244.75,73.52 244.57,73.7 244.39,73.7 244.06,73.37 243.88,73.37 243.7,73.54 243.7,73.72 242.99,74.43 242.99,75.3 242.86,75.42 242.61,75.42 242.48,75.3 242.48,74.75 242.35,74.63 242.1,74.63 241.97,74.75 241.97,75.81 241.85,75.94 241.59,75.94 241.46,75.81 241.46,74.75 241.34,74.63 241.08,74.63 240.96,74.75 240.96,75.81 240.83,75.94 240.58,75.94 240.45,75.81 240.45,74.75 240.32,74.63 233.07,74.63 231.98,73.53 212.75,73.53 212,72.78 200.98,72.78 194.28,66.08
  BOTTOM w0.114: v3(250.06,70.05) 250.06,70.76 v1(249.97,70.86)
M_A_DQ41: length 88.5
  TOP w0.089: v4(187.89,53.95) CPU1.AY38
  TOP w0.114: v3(253.93,70.42) 254.43,69.92 DIMM1.24
  L3 w0.089: v4(187.89,53.95) 188.3,54.37 189.3,54.37 189.75,54.81 191.58,54.81 192.18,55.41 192.18,59.7 192.59,60.11 192.59,63.04 193.01,63.46 193.01,64.91 193.33,65.23 193.33,65.74 193.98,66.39
  L3 w0.127: 193.98,66.39 201.06,73.47 211.71,73.47 212.46,74.22 231.34,74.22 234.99,77.87 238.07,77.87 239.3,76.64 242.9,76.64 242.91,76.63 242.93,76.63 248.58,70.98 253.9,70.98 254.03,70.85 254.03,70.53 v3(253.93,70.42)
  BOTTOM w0.114: v3(253.93,70.42) v1(253.93,69.61)
M_A_DQ42: length 87.4
  TOP w0.089: v4(190.55,53.97) 190.55,53.89 190.21,53.55 CPU1.AY43
  TOP w0.114: v3(251.49,70.05) 250.11,68.67 DIMM1.29
  L3 w0.089: 194.46,63.85 194.16,63.85 193.12,62.81 193.12,59.89 192.71,59.48 192.71,55.19 191.5,53.97 v4(190.55,53.97)
  L3 w0.127: 194.46,63.85 195.21,64.6 195.21,66.67 200.98,72.44 212.14,72.44 212.89,73.19 232.12,73.19 233.22,74.28 240.08,74.28 240.2,74.16 240.2,73.7 240.33,73.57 240.59,73.57 240.71,73.7 240.71,74.16 240.84,74.28 241.09,74.28 241.22,74.16 241.22,73.69 241.35,73.56 241.6,73.56 241.73,73.69 241.73,74.16 241.86,74.28 242.65,74.28 243.26,73.67 243.26,73.38 244.62,72.03 244.8,72.03 245,72.22 245.18,72.22 245.35,72.04 245.35,71.86 245.16,71.67 245.16,71.49 245.34,71.31 245.57,71.31 245.77,71.51 245.95,71.51 246.13,71.34 246.13,71.16 245.93,70.95 245.93,70.77 246.1,70.59 246.28,70.59 246.67,70.97 246.85,70.97 248.58,69.25 250.93,69.25 251.49,69.8 v3(251.49,70.05)
  BOTTOM w0.114: v3(251.49,70.05) 251.49,69.72 v1(251.05,69.28)
M_A_DQ43: length 88.2
  TOP w0.089: v4(187.92,53.03) 187.92,52.93 CPU1.BB39
  TOP w0.114: DIMM1.37 249.15,66.67 v3(249.35,66.88)
  L3 w0.089: 196.87,62.01 196.61,61.75 195.19,61.75 194.87,61.43 194.87,61.01 194.48,60.61 194.48,58.94 194.48,58.94 194.48,58.84 193.93,58.29 193.93,57.26 194.25,56.94 194.25,54.61 194.15,54.51 194.15,54.13 192.43,52.41 189.74,52.41 189.46,52.7 188.1,52.7 187.92,52.87 v4(187.92,53.03)
  L3 w0.127: 196.87,62.01 197.09,62.23 197.09,63.84 196.56,64.38 196.56,66.41 200.25,70.1 209.5,70.1 209.92,69.69 215.12,69.69 215.24,69.82 215.24,70.7 215.37,70.83 215.62,70.83 215.75,70.7 215.75,69.84 215.88,69.71 216.13,69.71 216.26,69.84 216.26,70.62 216.39,70.75 216.64,70.75 216.77,70.62 216.77,69.84 216.89,69.71 217.15,69.71 217.27,69.84 217.27,70.87 217.4,71 235.05,71 235.32,71.26 242.13,71.26 245.93,67.47 246.11,67.47 246.57,67.93 246.73,67.93 246.93,67.74 246.93,67.57 246.45,67.1 246.45,66.92 246.62,66.75 246.83,66.75 247.19,67.11 247.53,67.11 247.77,66.88 v3(249.35,66.88)
  BOTTOM w0.114: v3(249.35,66.88) v1(248.54,66.88)
M_A_DQ44: length 88.6
  TOP w0.089: v4(188.52,53.95) CPU1.AY39
  TOP w0.114: v3(252.5,70.42) 254,68.92 DIMM1.28
  L3 w0.089: v4(188.52,53.95) 189.22,53.95 189.9,54.63 191.65,54.63 192.36,55.34 192.36,59.63 192.77,60.04 192.77,62.97 193.19,63.39 193.19,64.83 193.51,65.16 193.51,65.62 194.19,66.3
  L3 w0.127: v3(252.5,70.42) 252.37,70.56 248.51,70.56 244.35,74.72 244.17,74.72 244.02,74.57 243.84,74.57 243.66,74.75 243.66,74.93 243.81,75.08 243.81,75.26 242.79,76.28 238.9,76.28 238.13,75.52 237.56,75.52 237.44,75.39 237.44,75.14 237.31,75.01 237.05,75.01 236.93,75.14 236.93,75.39 236.8,75.52 236.49,75.52 236.43,75.58 235.62,75.58 234.92,76.28 234.23,76.28 231.82,73.88 212.6,73.88 211.85,73.13 201.02,73.13 194.19,66.3
  BOTTOM w0.114: v3(252.5,70.42) v1(252.5,69.61)
M_A_DQ45: length 88.7
  TOP w0.089: v4(187.9,52.11) 187.86,52.11 187.61,52.37 CPU1.BB38
  TOP w0.114: v3(250.78,66.88) 250.78,66.5 249.95,65.68 DIMM1.41
  L3 w0.089: 196.86,61.57 195.9,61.57 195.61,61.28 195.61,61.1 195.4,60.89 195.01,60.89 194.66,60.54 194.66,58.77 194.11,58.22 194.11,57.34 194.43,57.02 194.43,54.53 194.37,54.47 194.37,54.1 192.5,52.23 189.67,52.23 189.38,52.52 188.31,52.52 v4(187.9,52.11)
  L3 w0.127: 196.86,61.57 197.35,62.06 197.35,64.05 196.92,64.47 196.92,66.47 200.15,69.69 209.43,69.69 209.77,69.35 217.53,69.35 217.66,69.47 217.66,70.52 217.78,70.65 218.04,70.65 218.16,70.52 218.16,69.48 218.29,69.35 218.59,69.35 218.71,69.48 218.71,70.53 218.84,70.65 235.19,70.65 235.46,70.92 241.94,70.92 246.45,66.41 250.77,66.41 250.9,66.54 250.9,66.76 v3(250.78,66.88)
  BOTTOM w0.114: v1(250.78,67.69) 250.78,67.51 v3(250.78,66.88)
M_A_DQ46: length 88.2
  TOP w0.089: v4(189.83,52.99) 189.81,52.99 189.81,52.96 189.56,52.72 CPU1.BB42
  TOP w0.114: v3(253.02,66.76) 254.39,66.76 254.72,66.42 DIMM1.38
  L3 w0.089: 196.66,62.15 196.44,61.93 195.11,61.93 194.69,61.51 194.69,61.08 194.3,60.69 194.3,59.01 193.45,58.16 193.45,54.73 192.57,53.84 192.57,53.26 191.9,52.59 190.23,52.59 v4(189.83,52.99)
  L3 w0.127: v3(253.02,66.76) 252.41,67.37 247.78,67.37 246.45,68.7 245.19,68.7 242.28,71.61 235.18,71.61 234.91,71.34 217.24,71.34 217.08,71.18 214.91,71.18 214.78,71.05 214.78,70.16 214.66,70.03 214.42,70.03 214.3,70.16 214.3,71.1 214.17,71.23 213.92,71.23 213.79,71.1 213.79,70.16 213.66,70.03 210.98,70.03 210.4,70.61 203.2,70.61 202.95,70.86 200.7,70.86 196.16,66.31 196.16,64.26 196.82,63.59 196.82,62.31 196.66,62.15
  BOTTOM w0.114: v3(253.02,66.76) 252.51,67.27 v1(252.51,67.61)
M_A_DQ47: length 87.5
  TOP w0.089: CPU1.BB43 190.41,53 190.44,53 190.44,53.01 v4(190.45,53.01)
  TOP w0.114: DIMM1.42 254.08,65.42 253.8,65.71 v3(253.8,65.86)
  L3 w0.089: v4(190.45,53.01) 190.8,53.01 191.2,53.41 191.88,53.41 193.28,54.81 193.28,59.19 193.67,59.59 193.67,60.5 194.51,61.34 194.51,62.4 194.31,62.6 194.31,63.04 194.55,63.28 194.88,63.28
  L3 w0.127: v3(253.8,65.86) 253.8,66.53 253.93,66.66 254.43,66.66 254.56,66.79 254.56,67.63 254.43,67.75 247.88,67.75 246.59,69.04 245.33,69.04 242.42,71.95 234.99,71.95 234.74,71.7 217.09,71.7 216.97,71.59 213.71,71.59 213.38,71.26 213.38,70.62 213.13,70.38 211.11,70.38 210.54,70.95 203.16,70.95 203,71.12 200.63,71.12 195.86,66.35 195.86,64.11 195.03,63.28 194.88,63.28
  BOTTOM w0.114: v1(255.22,65.52) 254.71,65.52 254.7,65.51 254.15,65.51 v3(253.8,65.86)
M_A_DQ48: length 78.4
  TOP w0.076: CPU1.AR48 192.95,56.33 193.15,56.41 193.35,56.41 193.47,56.36 193.67,56.16 195.29,56.16 v4(195.65,56.52)
  TOP w0.114: v3(252.51,61.21) 252.51,61.08 251.61,60.17 DIMM1.63
  L3 w0.127: v4(195.65,56.52) 196.47,57.34 197.31,57.34 197.48,57.51 198.32,57.51 199.34,58.53 199.34,58.86 204.6,64.12 208.65,64.12 209.18,64.66 221.01,64.66 221.18,64.83 221.18,65.94 221.3,66.06 221.56,66.06 221.68,65.94 221.68,65.64 221.81,65.51 222.07,65.51 222.19,65.64 222.19,66.57 222.32,66.7 222.8,66.7 222.92,66.57 222.92,66.43 223.05,66.3 223.3,66.3 223.43,66.43 223.43,66.57 223.56,66.7 223.81,66.7 223.94,66.57 223.94,66.38 224.04,66.28 224.34,66.28 224.45,66.38 224.45,66.57 224.57,66.7 224.83,66.7 224.95,66.57 224.95,66.4 225.07,66.28 225.34,66.28 225.46,66.4 225.46,66.57 225.59,66.7 237.07,66.7 237.27,66.5 241.26,66.5 245.19,62.58 251.34,62.58 251.74,62.17 253.22,62.17 253.35,62.05 253.35,61.34 253.22,61.21 v3(252.51,61.21)
  BOTTOM w0.114: v3(252.51,61.21) 252.71,61.02 v1(253.3,61.02)
M_A_DQ49: length 79
  TOP w0.076: v4(197.51,56.51) 196.84,55.83 193.36,55.83 192.99,55.96 192.8,55.96 192.63,55.9 192.54,55.9 192.24,56.01 CPU1.AR47
  TOP w0.114: DIMM1.59 249.09,61.17 249.14,61.12 249.65,61.12 250.06,61.54 v3(250.06,61.65)
  L3 w0.127: v4(197.51,56.51) 197.67,56.67 197.67,56.95 197.8,57.08 198.5,57.08 202.78,61.36 202.81,61.36 204.34,62.89 204.8,62.89 204.92,63.02 204.92,63.28 205.05,63.41 205.3,63.41 205.43,63.28 205.43,63.02 205.56,62.89 205.81,62.89 205.94,63.02 205.94,63.28 206.07,63.41 206.32,63.41 206.45,63.28 206.45,63.02 206.57,62.89 206.87,62.89 206.99,63.02 206.99,63.3 207.12,63.42 207.37,63.42 207.5,63.3 207.5,63.02 207.63,62.89 207.88,62.89 208.01,63.02 208.01,63.3 208.14,63.42 208.39,63.42 208.52,63.3 208.52,63.02 208.64,62.89 208.92,62.89 209.05,63.02 209.05,63.55 209.47,63.98 223.58,63.98 225.16,65.56 231.39,65.56 231.52,65.69 231.52,65.88 231.65,66.01 231.9,66.01 232.03,65.88 232.03,65.69 232.16,65.56 232.41,65.56 232.54,65.69 232.54,65.88 232.66,66.01 232.92,66.01 233.04,65.88 233.04,65.69 233.17,65.56 233.43,65.56 233.57,65.71 233.57,65.89 233.7,66.01 236.79,66.01 236.98,65.82 240.34,65.82 240.73,65.43 240.91,65.43 241.05,65.56 241.23,65.56 241.42,65.38 241.42,65.2 241.24,65.02 241.24,64.84 241.42,64.66 241.59,64.66 241.78,64.84 241.96,64.84 242.13,64.66 242.13,64.48 241.95,64.3 241.95,64.12 242.13,63.94 242.31,63.94 242.49,64.12 242.67,64.12 244.04,62.75 244.04,62.57 243.86,62.39 243.86,62.21 244.04,62.03 244.22,62.03 244.4,62.22 244.58,62.22 244.76,62.04 244.76,61.86 244.58,61.67 244.58,61.46 244.93,61.11 245.93,61.11 246.06,61.24 246.06,61.71 246.19,61.84 246.44,61.84 246.57,61.71 246.57,61.31 246.69,61.18 246.95,61.18 247.07,61.31 247.07,61.71 247.2,61.84 247.46,61.84 247.58,61.71 247.58,61.31 247.71,61.18 247.96,61.18 248.09,61.31 248.09,61.71 248.22,61.84 248.47,61.84 248.6,61.71 248.6,61.31 248.73,61.18 249.94,61.18 250.06,61.31 v3(250.06,61.65)
  BOTTOM w0.114: v3(250.06,61.65) 249.81,61.39 v1(249.81,60.88)
M_A_DQ50: length 77.8
  TOP w0.076: CPU1.AR49 193.4,55.99 195.71,55.99 v4(196.24,56.52)
  TOP w0.114: v3(251.49,61.75) 252.68,61.75 254,60.42 DIMM1.62
  L3 w0.127: v4(196.24,56.52) 196.24,56.61 196.75,57.12 197.4,57.12 197.57,57.29 198.41,57.29 199.56,58.44 199.56,58.59 204.74,63.78 208.79,63.78 209.33,64.32 221.5,64.32 221.63,64.45 221.63,65.02 221.76,65.15 222.05,65.15 222.18,65.02 222.18,64.43 222.29,64.32 222.57,64.32 222.68,64.43 222.68,65.81 222.81,65.94 223.07,65.94 223.19,65.81 223.19,64.84 223.32,64.71 223.57,64.71 223.7,64.84 223.7,65.81 223.83,65.94 225.83,65.94 225.96,66.06 225.96,66.23 226.08,66.36 226.42,66.36 226.55,66.23 226.55,66.07 226.67,65.94 226.93,65.94 227.05,66.07 227.05,66.23 227.18,66.36 227.44,66.36 227.56,66.23 227.56,66.07 227.69,65.94 227.94,65.94 228.07,66.07 228.07,66.23 228.2,66.36 228.45,66.36 228.58,66.23 228.58,66.07 228.71,65.94 228.96,65.94 229.09,66.07 229.09,66.23 229.21,66.36 229.47,66.36 229.59,66.23 229.59,66.07 229.72,65.94 229.98,65.94 230.1,66.07 230.1,66.23 230.23,66.36 230.48,66.36 230.61,66.23 230.61,66.07 230.74,65.94 230.99,65.94 231.12,66.07 231.12,66.23 231.25,66.36 236.93,66.36 237.12,66.16 241.12,66.16 245.07,62.21 251.03,62.21 v3(251.49,61.75)
  BOTTOM w0.114: v3(251.49,61.75) 251.49,61.11 v1(251.33,60.95)
M_A_DQ51: length 76.9
  TOP w0.076: 191.44,56.49 192.91,56.49 193.12,56.58 193.37,56.58 193.59,56.5 193.75,56.34 194.79,56.34 v4(194.98,56.53)
  TOP w0.089: CPU1.AM45 191.28,56.65 191.44,56.49
  TOP w0.114: DIMM1.45 248.88,64.68 249.05,64.85 250.51,64.85 v3(251.2,65.54)
  L3 w0.089: 195.07,58.92 194.29,58.14 194.29,57.56 194.98,56.87 v4(194.98,56.53)
  L3 w0.127: v3(251.2,65.54) 251.28,65.62 251.28,65.94 251.15,66.07 245.35,66.07 241.49,69.92 236.89,69.92 236.67,69.7 234.15,69.7 234.1,69.75 219.56,69.75 219.39,69.58 219.39,69.13 219.26,69 209.57,69 209.26,69.31 205.05,69.31 203.25,67.51 203.25,66.22 202.58,65.55 202.58,65.29 199.42,62.13 199.42,61.39 197.81,59.78 195.93,59.78 195.07,58.92
  BOTTOM w0.114: v3(251.2,65.54) v1(250.38,65.54)
M_A_DQ52: length 79.6
  TOP w0.076: CPU1.AR45 191.5,56.16 191.8,55.86 192.16,55.86 192.16,55.86 192.52,55.74 192.66,55.74 192.83,55.8 192.96,55.8 193.33,55.66 195.52,55.66 195.53,55.66 197.3,55.66 198.19,56.54 v4(198.27,56.54)
  TOP w0.114: v3(253.93,62.38) 253.93,61.92 254.43,61.42 DIMM1.58
  L3 w0.127: v3(253.93,62.38) 253.93,61.73 254.05,61.6 256.15,61.6 256.28,61.48 256.28,60.98 256.15,60.86 254,60.86 253.87,60.72 251.89,60.72 251.85,60.77 244.79,60.77 243.27,62.29 243.27,62.83 242.74,63.36 242.17,63.36 240.09,65.43 236.88,65.43 236.64,65.67 234.02,65.67 233.57,65.22 225.31,65.22 223.71,63.62 215.3,63.62 215.25,63.58 209.55,63.58 209.39,63.41 209.39,62.67 209.27,62.55 204.52,62.55 203.11,61.14 202.87,61.14 198.27,56.54 v4(198.27,56.54)
  BOTTOM w0.114: v1(253.19,62.75) 253.55,62.75 v3(253.93,62.38)
M_A_DQ53: length 76.7
  TOP w0.076: CPU1.AM47 192.52,57.79 193,57.79 193.13,57.84 193.37,57.84 193.5,57.79 194.3,57.79 194.45,57.64 194.5,57.64 194.5,57.64 194.97,57.64 v4(195.22,57.89)
  TOP w0.114: v3(252.73,65.53) 251.69,64.49 250.51,64.49 249.69,63.68 DIMM1.49
  L3 w0.127: v4(195.22,57.89) 195.22,58.4 196.4,59.57 197.9,59.57 199.75,61.41 199.75,62.12 202.79,65.17 202.79,65.39 203.59,66.18 203.59,67.28 205.28,68.97 209.08,68.97 209.5,68.55 219.69,68.55 219.81,68.68 219.81,69.21 219.94,69.34 236.79,69.34 237.03,69.58 241.35,69.58 245.21,65.72 250.31,65.72 251.01,65.02 252.35,65.02 252.73,65.4 v3(252.73,65.53)
  BOTTOM w0.114: v1(253.23,64.89) 252.73,65.39 v3(252.73,65.53)
M_A_DQ54: length 76
  TOP w0.076: v4(195.81,57.91) 195.37,57.47 195.04,57.47 195.03,57.47 194.43,57.47 194.43,57.47 194.38,57.47 194.23,57.63 193.47,57.63 193.37,57.66 193.35,57.67 193.15,57.67 193.14,57.66 193.14,57.66 193.05,57.63 193.04,57.62 CPU1.AM48
  TOP w0.114: v3(253.85,63.42) DIMM1.50
  L3 w0.127: v4(195.81,57.91) 195.81,58.19 196.94,59.33 197.97,59.33 200.1,61.46 200.1,61.89 203.01,64.79 203.01,65.12 203.93,66.04 203.93,67.14 205.18,68.39 206.48,68.39 208.22,66.65 210.24,66.65 211.58,67.99 219.99,67.99 221,68.99 236.93,68.99 237.17,69.24 241.2,69.24 245.06,65.38 250.17,65.38 250.88,64.67 254.19,64.67 254.32,64.54 254.32,63.55 254.19,63.42 v3(253.85,63.42)
  BOTTOM w0.114: v1(254.58,63.78) 254.23,63.42 v3(253.85,63.42)
M_A_DQ55: length 75.7
  TOP w0.076: CPU1.AM49 193.36,57.42 193.4,57.46 194.16,57.46 194.31,57.31 194.36,57.31 194.36,57.31 195.1,57.31 195.11,57.31 195.79,57.31 v4(196.39,57.91)
  TOP w0.114: DIMM1.46 252.99,64.42 v3(252.39,63.83)
  L3 w0.127: v3(252.39,63.83) 251.89,64.33 250.46,64.33 249.91,64.88 245.08,64.88 241.06,68.89 237.32,68.89 237.07,68.65 221.14,68.65 219.55,67.06 219.31,67.06 219.18,67.19 219.18,67.35 219.06,67.48 218.8,67.48 218.67,67.35 218.67,67.19 218.55,67.06 218.29,67.06 218.17,67.19 218.17,67.35 218.04,67.48 217.79,67.48 217.66,67.35 217.66,67.19 217.53,67.06 217.28,67.06 217.15,67.19 217.15,67.35 217.02,67.48 216.77,67.48 216.64,67.35 216.64,67.19 216.52,67.06 216.21,67.06 216.09,67.19 216.09,67.31 215.96,67.44 214.05,67.44 213.58,66.98 211.13,66.98 210.47,66.31 208.08,66.31 206.34,68.05 205.33,68.05 204.27,67 204.27,65.9 203.23,64.85 203.23,64.7 200.39,61.87 200.39,61.45 198.05,59.1 197.12,59.1 196.39,58.38 v4(196.39,57.91)
  BOTTOM w0.114: v1(251.85,64.47) 251.85,64.37 v3(252.39,63.83)
M_A_DQ56: length 96
  TOP w0.089: CPU1.AT42 189.64,55.36 189.83,55.73 v4(189.83,55.73)
  TOP w0.114: v3(253.1,72.36) 253.1,71.83 254,70.92 DIMM1.20
  L3 w0.089: v4(189.83,55.73) 189.83,55.68 190.14,55.37 190.66,55.37 190.95,55.66 190.95,55.73 191.44,56.22 191.44,57.49 191.08,57.85 191.08,58.47 191.45,58.83 191.45,59.74 192.04,60.34 192.04,63.86 192.3,64.11 192.3,65.03 192.64,65.37 192.64,66.31
  L3 w0.127: 192.64,66.31 192.64,67.06 193.06,67.48 193.06,68.92 194.49,70.34 194.49,73.91 195.72,75.14 199.08,75.14 199.7,74.51 205.6,74.51 205.72,74.64 205.72,75.05 205.85,75.17 206.1,75.17 206.23,75.05 206.23,74.64 206.36,74.51 206.61,74.51 206.74,74.64 206.74,75.36 206.87,75.49 207.12,75.49 207.25,75.36 207.25,74.64 207.37,74.51 207.63,74.51 207.76,74.64 207.76,75.48 207.88,75.61 208.14,75.61 208.26,75.48 208.26,74.64 208.39,74.51 208.64,74.51 208.77,74.64 208.77,75.48 209,75.71 226.98,75.71 227.09,75.61 230.52,75.61 233.95,79.03 242.3,79.03 248.61,72.72 252.97,72.72 253.1,72.59 v3(253.1,72.36)
  BOTTOM w0.114: v1(253.11,73.19) 253.1,73.19 v3(253.1,72.36)
M_A_DQ57: length 97
  TOP w0.089: CPU1.AT39 188.26,55.24 v4(188.57,54.93)
  TOP w0.114: DIMM1.17 249.91,71.67 250.65,72.42 251.81,72.42 v3(252.5,71.73)
  L3 w0.089: v4(188.57,54.93) 188.85,55.21 189.38,55.21 189.61,54.99 191.51,54.99 192,55.48 192,59.78 192.41,60.18 192.41,63.72 192.66,63.97 192.66,64.89 193.13,65.36 193.13,66.31
  L3 w0.127: v3(252.5,71.73) 252.5,71.47 252.37,71.34 249.02,71.34 242.02,78.34 241.72,78.34 241.59,78.21 241.59,77.2 241.47,77.07 241.21,77.07 241.09,77.2 241.09,78.21 240.96,78.34 240.7,78.34 240.58,78.21 240.58,77.2 240.45,77.07 240.2,77.07 240.07,77.2 240.07,78.21 239.94,78.34 234.23,78.34 230.76,74.88 212.26,74.88 211.2,73.81 195.45,73.81 195.17,73.53 195.17,68.96 193.13,66.92 193.13,66.31
  BOTTOM w0.114: v1(251.99,72.59) 251.99,72.24 v3(252.5,71.73)
M_A_DQ58: length 94.2
  TOP w0.089: v4(190.47,56.66) 190.47,56.66 190.35,56.54 190.35,56.54 190.21,56.4 CPU1.AR43
  TOP w0.114: DIMM1.7 249.09,74.17 250.08,75.16 v3(250.08,75.53)
  L3 w0.089: v4(190.47,56.66) 190.59,56.79 190.59,57.05 190.36,57.29 190.36,57.83 189.77,58.42 189.77,58.86 189.36,59.27 189.36,60.37 190.97,61.98 190.97,62.25 190.56,62.65 190.56,63.4 191.1,63.94 191.1,64.34 191.11,64.35
  L3 w0.127: 191.11,64.35 191.11,65.73 191.58,66.2 191.58,67.23 192.2,67.84 192.2,73.2 193.2,74.21 193.2,74.39 193.2,75.16 194.93,76.88 199.64,76.88 200.42,77.66 211.13,77.66 211.24,77.77 220.5,77.77 220.72,77.55 222.65,77.55 222.77,77.68 222.77,78.01 222.9,78.13 223.15,78.13 223.28,78.01 223.28,77.68 223.41,77.55 223.72,77.55 223.84,77.68 223.84,78.83 223.97,78.95 224.22,78.95 224.35,78.83 224.35,77.67 224.48,77.54 224.73,77.54 224.86,77.67 224.86,79.04 224.99,79.17 225.24,79.17 225.37,79.04 225.37,77.67 225.49,77.54 225.75,77.54 225.88,77.67 225.88,79.04 226,79.17 231.5,79.17 233.19,80.86 243.06,80.86 247.89,76.03 249.85,76.03 250.08,75.8 v3(250.08,75.53)
  BOTTOM w0.114: v3(250.08,75.53) v1(250.08,76.35)
M_A_DQ59: length 95.5
  TOP w0.089: v4(187.91,55.78) 187.61,55.47 CPU1.AT38
  TOP w0.114: v3(251.64,71.86) 250.46,70.67 DIMM1.21
  L3 w0.089: v4(187.91,55.78) 188.29,55.4 189.58,55.4 189.81,55.17 190.72,55.17 191.13,55.58 191.13,55.66 191.82,56.35 191.82,59.86 192.22,60.27 192.22,63.78 192.48,64.04 192.48,64.96 192.89,65.37 192.89,66.31
  L3 w0.127: 192.89,66.31 192.89,67 193.28,67.39 193.28,68.83 194.7,70.25 194.7,73.38 195.36,74.03 202.14,74.03 202.26,74.16 209.01,74.16 209.14,74.28 209.14,75.1 209.26,75.23 209.52,75.23 209.65,75.1 209.65,74.28 209.77,74.16 210.03,74.16 210.15,74.28 210.15,75.1 210.28,75.23 210.53,75.23 210.66,75.1 210.66,74.28 210.79,74.16 211.03,74.16 211.18,74.31 211.18,75.1 211.31,75.22 230.63,75.22 234.09,78.68 242.16,78.68 249.16,71.68 250.06,71.68 250.19,71.81 250.19,72.11 250.42,72.34 251.16,72.34 v3(251.64,71.86)
  BOTTOM w0.114: v1(251.24,71.11) 251.24,71.46 v3(251.64,71.86)
M_A_DQ60: length 95.2
  TOP w0.089: v4(187.88,56.71) 187.88,56.69 187.61,56.43 CPU1.AR38
  TOP w0.114: v3(253.1,74.47) 253.21,74.47 253.64,74.9 253.89,74.9 253.91,74.92 DIMM1.4
  L3 w0.089: 190.08,64.41 190.08,63.11 189.51,62.55 187.73,62.55 187.37,62.18 187.37,57.22 v4(187.88,56.71)
  L3 w0.127: v3(253.1,74.47) 253.1,73.88 252.88,73.66 252.42,73.66 252.19,73.88 252.19,74.35 249.46,77.08 247.81,77.08 243.35,81.54 232.9,81.54 231.28,79.92 220.15,79.92 219.82,79.6 219.82,78.59 219.7,78.47 210.76,78.47 210.65,78.36 202.02,78.36 201.28,79.09 196.34,79.09 192.77,75.53 192.77,74.39 191.76,73.37 191.76,71.4 191.16,70.8 191.16,68.8 191.16,67.88 190.49,67.2 190.49,65.54 190.08,65.13 190.08,64.41
  BOTTOM w0.114: v1(253.36,75.24) 253.1,74.99 v3(253.1,74.47)
M_A_DQ61: length 95.2
  TOP w0.089: v4(188.49,56.68) 188.49,56.56 188.26,56.33 CPU1.AR39
  TOP w0.114: v3(253.84,74.44) 254.01,74.03 254.27,73.92 DIMM1.8
  L3 w0.089: 189.77,64.41 189.77,63.06 189.44,62.73 187.66,62.73 187.12,62.19 187.12,56.86 187.71,56.27 188.08,56.27 v4(188.49,56.68)
  L3 w0.127: v3(253.84,74.44) 253.57,74.84 253.21,75.11 252.63,75.31 251.9,75.46 251.33,75.69 249.6,77.42 247.95,77.42 243.49,81.88 232.76,81.88 231.14,80.26 219.81,80.26 218.98,79.43 208.14,79.43 208,79.58 196.44,79.58 192.56,75.69 192.56,75.42 192.56,74.48 191.54,73.46 191.54,71.49 190.95,70.89 190.95,68.71 190.95,67.97 190.21,67.23 190.21,65.65 189.77,65.22 189.77,64.41
  BOTTOM w0.114: v1(254.9,75.19) v3(253.84,74.44)
M_A_DQ62: length 94.2
  TOP w0.089: v4(189.89,56.73) 189.9,56.73 189.9,56.73 189.83,56.71 CPU1.AR42
  TOP w0.114: v3(248.53,76.59) 248.07,76.13 246.92,76.13 246.81,76.02 246.81,75.37 247,75.17 DIMM1.3
  L3 w0.089: v4(189.89,56.73) 189.83,56.73 189.53,57.03 189.53,58.41 189.59,58.47 189.59,58.76 189.05,59.31 189.05,60.49 189.54,60.99 189.54,62.32 190.38,63.16 190.38,63.91 190.84,64.36
  L3 w0.127: v3(248.53,76.59) 247.81,76.59 243.2,81.2 233.04,81.2 231.42,79.58 223.42,79.58 223.3,79.45 223.3,78.6 223.19,78.49 222.9,78.49 222.79,78.6 222.79,79.45 222.66,79.58 222.41,79.58 222.28,79.45 222.28,78.15 222.15,78.02 221.9,78.02 221.77,78.15 221.77,79.3 221.65,79.42 221.39,79.42 221.27,79.3 221.27,78 221.16,77.9 220.86,77.9 220.76,78 220.76,79.28 220.63,79.41 220.38,79.41 220.25,79.28 220.25,78.25 220.12,78.12 210.9,78.12 210.8,78.02 201.99,78.02 201.36,78.64 196.24,78.64 192.99,75.39 192.99,74.3 191.98,73.29 191.98,67.93 190.84,66.79 190.84,64.36
  BOTTOM w0.114: v3(248.53,76.59) v1(248.53,77.41)
M_A_DQ63: length 95.3
  TOP w0.089: v4(190.49,55.73) 190.38,55.69 CPU1.AT43
  TOP w0.114: v3(253.93,71.68) 254.17,71.92 DIMM1.16
  L3 w0.089: v4(190.49,55.73) 190.66,55.73 191.25,56.32 191.25,57.43 190.9,57.78 190.9,58.54 191.22,58.86 191.22,59.77 191.87,60.41 191.87,63.93 192.12,64.19 192.12,65.11 192.42,65.4 192.42,66.31
  L3 w0.127: 192.42,66.31 192.42,67.15 192.84,67.57 192.84,70.36 194.27,71.78 194.27,74.19 195.59,75.51 199.06,75.51 199.72,74.86 205.05,74.86 205.22,75.02 205.22,75.81 205.34,75.93 205.6,75.93 205.73,75.81 205.73,75.65 205.85,75.52 206.11,75.52 206.24,75.65 206.24,75.82 206.47,76.05 227.12,76.05 227.23,75.95 230.38,75.95 233.8,79.37 242.45,79.37 248.74,73.08 254.12,73.08 254.42,72.78 255.72,72.78 255.91,72.59 255.91,72.12 255.72,71.92 254.17,71.92 v3(253.93,71.68)
  BOTTOM w0.114: v3(253.93,71.68) 254.18,71.68 v1(254.91,72.4)
M_A_DQS_DN0: length 78.9
  TOP w0.076: 194.76,44.44 194.74,44.44 194.73,44.45 194.17,44.45 193.97,44.65 193.67,44.65 193.51,44.49 193.12,44.49 193,44.54 192.85,44.54 192.85,44.54 192.55,44.43 CPU1.BY47
  TOP w0.102: v3(253.24,23.43) 253.37,23.43 253.78,23.83 254.07,23.83 254.36,24.13 254.85,24.13 254.93,24.21 254.93,24.35 255,24.42 DIMM1.198 ; v3(198.34,41.88) 197.98,41.88 197.93,41.94 197.73,41.94 197.54,42.13 197.04,42.13 196.74,42.43 196.74,43.19 197.12,43.56 197.12,44.18 196.86,44.44 194.76,44.44
  L3 w0.114: v3(198.34,41.88) 197.97,41.88 197.81,41.73 197.81,41.55 199.04,40.32 201.91,40.32 204.27,37.97 208.24,37.97 214.58,31.62 218.98,31.62 224.73,25.86 226.97,25.86 229.87,22.96 240.28,22.96 240.81,23.5 251.78,23.5 252.63,22.65 253.32,22.65 253.52,22.85 253.52,23.14 v3(253.24,23.43)
  BOTTOM w0.102: v3(198.34,41.88) 198.34,40.87 v1(198.38,40.84)
M_A_DQS_DN1: length 90.7
  TOP w0.102: CPU1.CC41 188.91,42.34 v4(189.14,42.1) ; DIMM1.240 255.27,13.92 255.04,13.69 254.35,13.69 254.12,13.46 253.93,13.46 253.85,13.38 253.76,13.38 253.74,13.36 253.71,13.36 253.27,12.93 v3(253.24,12.93)
  L3 w0.114: v3(253.24,12.93) 252.73,12.42 250.99,12.42 250.63,12.05 249.61,12.05 249.36,11.81 249.36,10.65 249.17,10.46 248.79,10.46 248.67,10.58 248.67,11.29 248.43,11.54 247.84,11.54 247.6,11.29 247.6,10.55 247.48,10.44 245.04,10.44 243.61,11.87 241.97,11.87 241.72,11.62 241.72,11.33 241.61,11.22 241.22,11.22 241.1,11.33 241.1,11.62 240.85,11.87 240.42,11.87 240.1,11.55 234.15,11.55 233.83,11.22 233.52,11.22 233.41,11.33 233.41,11.71 233.16,11.95 232.56,11.95 232.31,11.71 232.31,11.3 232.2,11.18 231.92,11.18 231.56,11.54 230.85,11.54 230.49,11.18 227.27,11.18 214.61,23.84 211.32,23.84 205.35,29.81 197.57,29.81 195.35,32.03 193.68,32.03 193.32,32.38 193.32,34.18 192.25,35.25 192.25,36.48 190.91,37.82 190.65,37.82 189.89,38.58 189.89,38.66 189.91,38.67 189.89,38.69 189.89,41.43 189.64,41.68 189.56,41.68 v4(189.14,42.1)
M_A_DQS_DN2: length 76.4
  TOP w0.076: 194.51,46.64 194.5,46.63 194.5,46.61 194.3,46.41 193.62,46.41 193.46,46.58 193.12,46.58 193,46.53 192.85,46.53 192.85,46.53 192.55,46.63 CPU1.BR47
  TOP w0.102: 204.87,42.39 204.87,43.15 203.97,44.05 200.94,44.05 198.22,46.77 194.64,46.77 194.51,46.64 ; 204.87,42.39 204.87,41.74 208.35,38.26 213.92,38.26 214.89,37.29 215.86,37.29 216.53,36.62 216.53,36.08 216.63,35.98 v3(216.79,35.98) ; 204.87,42.39 v1(205.24,42.39) ; v3(250.76,28.67) 250.65,28.94 250.54,29.21 250.25,29.5 248.9,29.5 248.73,29.67 DIMM1.177
  L3 w0.114: v3(250.76,28.67) 250.51,28.93 250.51,29.32 250.26,29.57 247.79,29.57 247.55,29.32 247.55,28.23 247.43,28.11 247.04,28.11 246.92,28.23 246.92,29.31 246.68,29.56 246.09,29.56 245.84,29.31 245.84,28.35 245.73,28.24 245.24,28.24 245.13,28.35 245.13,28.55 244.88,28.8 240.73,28.8 240.58,28.94 237.31,28.94 237.19,29.06 237.19,29.38 236.94,29.63 234.16,29.63 233.75,30.04 226.06,30.04 220.59,35.51 216.7,35.51 216.59,35.62 216.59,35.78 v3(216.79,35.98)
M_A_DQS_DN3: length 86.4
  TOP w0.102: v3(250.89,18.1) 250.64,18.35 250.64,18.64 250.27,19 248.9,19 248.73,19.17 DIMM1.219 ; CPU1.BV41 188.91,45.15 v4(189.27,44.79)
  L3 w0.114: v3(250.89,18.1) 250.69,17.9 250.69,17.28 250.45,17.03 248.64,17.03 248.52,16.92 248.52,16.58 248.27,16.34 247.69,16.34 247.44,16.58 247.44,16.92 247.33,17.03 246.93,17.03 246.82,16.92 246.82,16.58 246.57,16.34 245.99,16.34 245.74,16.58 245.74,16.92 245.63,17.03 245.23,17.03 245.12,16.92 245.12,16.58 244.87,16.34 244.29,16.34 244.04,16.58 244.04,16.92 243.92,17.03 243.53,17.03 243.42,16.92 243.42,16.58 243.17,16.34 242.59,16.34 242.34,16.58 242.34,16.92 242.22,17.03 241.83,17.03 241.72,16.92 241.72,16.58 241.47,16.34 240.88,16.34 240.64,16.58 240.64,16.92 240.52,17.03 237.42,17.03 237.03,16.64 228.58,16.64 224.69,20.53 224.69,20.88 224.99,21.18 224.99,21.34 224.71,21.62 224.55,21.62 224.25,21.32 223.9,21.32 223.47,21.75 221.94,21.75 216.18,27.51 212.87,27.51 206.71,33.67 204.49,33.67 200.23,37.93 197.63,37.93 196.31,39.25 194.36,39.25 192.66,40.94 192.66,43.55 191.4,44.81 191.38,44.81 191.02,45.17 189.41,45.17 189.27,45.03 v4(189.27,44.79)
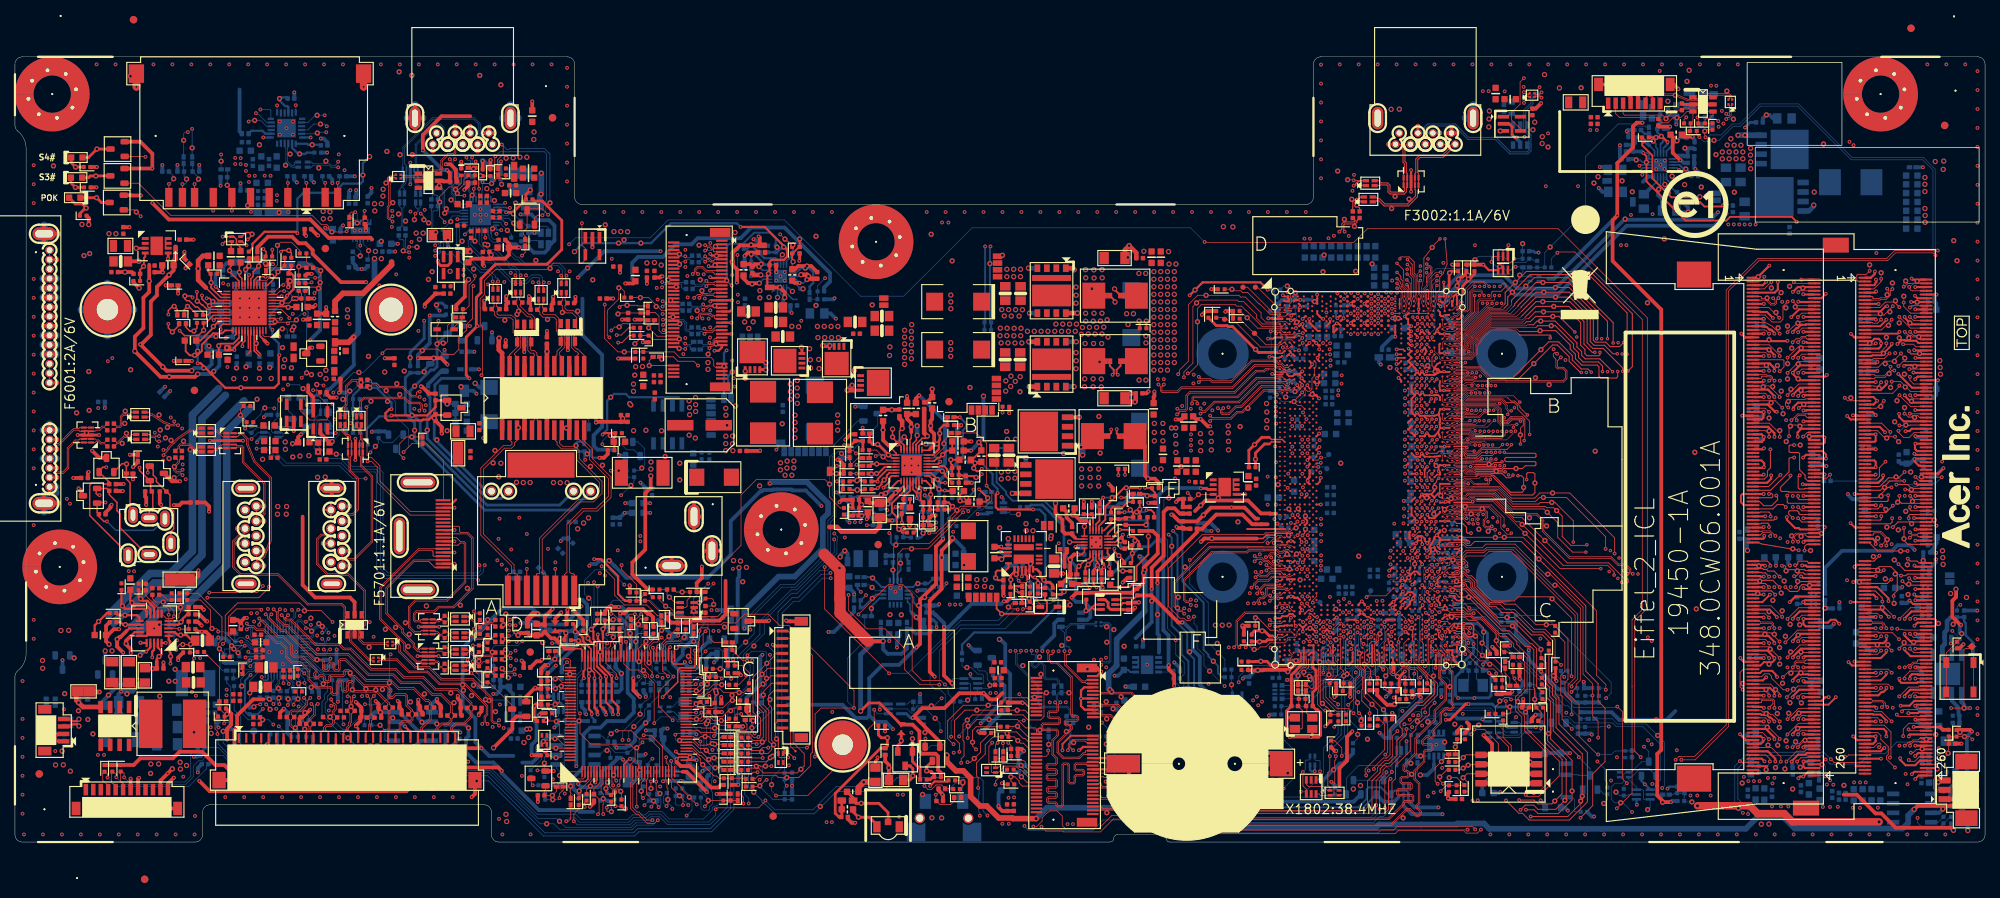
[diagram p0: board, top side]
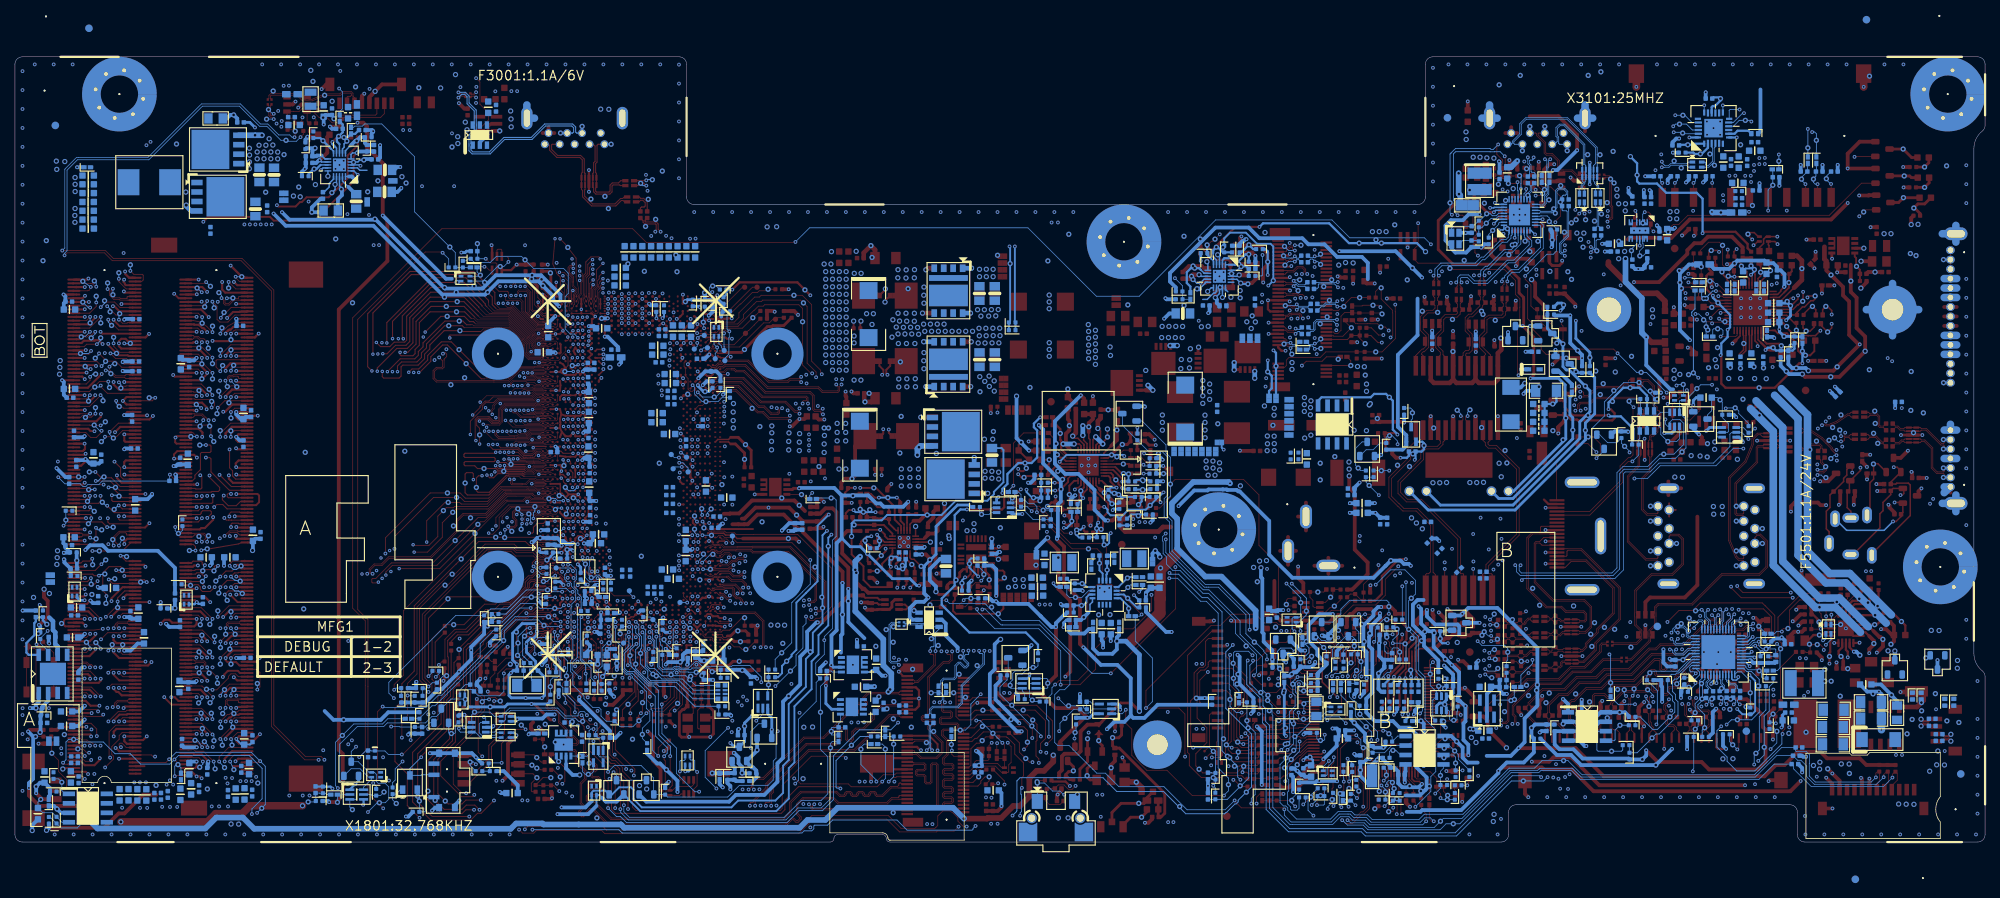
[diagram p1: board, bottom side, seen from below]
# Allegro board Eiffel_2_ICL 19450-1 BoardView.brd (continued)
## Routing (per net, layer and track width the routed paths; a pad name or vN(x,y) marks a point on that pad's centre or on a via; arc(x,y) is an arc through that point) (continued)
M_A_DQS_DN4: length 76.1
  TOP w0.076: CPU1.AV46 192.22,54.67 192.67,54.67 192.81,54.72 193.02,54.72 193.19,54.66 193.28,54.66 193.44,54.71 193.54,54.82 194.81,54.82 195.36,54.27 196.7,54.27 196.75,54.32 197.08,54.32 197.09,54.33 197.1,54.33
  TOP w0.102: 197.1,54.33 199.14,54.33 199.48,54.67 199.48,54.87 v4(199.27,55.08) ; v3(253.92,57.45) 253.94,57.42 DIMM1.74
  L3 w0.114: v4(199.27,55.08) 199.48,55.29 199.48,55.56 199.73,55.81 200.13,55.81 202.33,58.01 202.74,58.01 203.87,59.14 204.2,59.14 205.55,60.5 210.04,60.5 210.14,60.59 216.77,60.59 217.28,60.08 217.28,59.69 217.44,59.54 217.79,59.54 217.91,59.65 217.91,60.3 218.15,60.54 218.74,60.54 218.99,60.3 218.99,59.64 219.1,59.53 219.49,59.53 219.61,59.64 219.61,60.4 219.9,60.69 221.12,60.69 221.84,61.41 232.68,61.41 232.83,61.56 232.83,62.27 233.22,62.67 237.02,62.67 237.29,62.4 240,62.4 244.42,57.97 251.94,57.97 252.29,58.33 253.35,58.33 253.7,57.98 253.7,57.67 v3(253.92,57.45)
  BOTTOM w0.102: v3(253.92,57.45) 254.05,57.45 v1(254.55,56.94)
M_A_DQS_DN5: length 87.8
  TOP w0.102: DIMM1.32 254.45,67.92 v3(253.95,68.43) ; v4(188.52,53.07) 188.52,53.07 188.91,53.46 CPU1.AY41
  L3 w0.089: 194.93,63.89 194.91,63.88 194.91,63.85 194.71,63.65 194.39,63.65 193.92,63.18 193.92,62.31 194.15,62.09 194.15,61.5 193.3,60.65 193.3,59.74 192.91,59.35 192.91,54.96 191.74,53.79 191,53.79 190.76,53.56 190.22,53.56 190.21,53.55 189.15,53.55 188.66,53.07 v4(188.52,53.07)
  L3 w0.114: v3(253.95,68.43) 253.95,69.46 253.63,69.78 252.35,69.78 251.19,68.62 248.23,68.62 246.95,69.9 245.86,69.9 242.86,72.9 239.53,72.9 239.18,73.25 237.13,73.25 236.72,73.66 233.48,73.66 232.38,72.56 213.15,72.56 212.4,71.81 200.65,71.81 195.42,66.58 195.42,64.39 194.93,63.89
  BOTTOM w0.102: v3(253.95,68.43) 254.57,67.8 255.06,67.8 v1(255.11,67.75)
M_A_DQS_DN6: length 77.7
  TOP w0.076: CPU1.AN46 192.15,57.16 192.67,57.16 192.84,57.22 193,57.22 193.17,57.16 193.35,57.16 193.53,57.25 193.6,57.26 194.11,57.26 194.27,57.11 194.52,57.11 194.52,57.11 194.54,57.11
  TOP w0.083: 194.54,57.11 196.18,57.11 v4(196.98,57.91)
  TOP w0.102: v3(251.33,63.75) 251.33,63.36 250.48,62.52 249.28,62.52 249.12,62.68 DIMM1.53
  L3 w0.114: v4(196.98,57.91) 197.33,58.26 197.33,58.41 197.81,58.89 198.16,58.89 204.25,64.98 205.58,64.98 205.75,65.15 205.75,65.52 205.62,65.65 205.16,65.65 204.9,65.92 204.9,66.65 205.16,66.91 206.57,66.91 207.9,65.58 210.68,65.58 211.45,66.35 217.67,66.35 217.91,66.1 217.91,65.65 218.03,65.54 218.42,65.54 218.54,65.65 218.54,66.1 218.78,66.35 219.37,66.35 219.62,66.1 219.62,65.65 219.73,65.54 220.12,65.54 220.24,65.65 220.24,66.86 220.97,67.59 236.64,67.59 236.95,67.9 241.15,67.9 245.18,63.87 249.98,63.87 250.26,63.58 251.16,63.58 v3(251.33,63.75)
  BOTTOM w0.102: v1(250.62,64.15) 250.92,64.15 v3(251.33,63.75)
M_A_DQS_DN7: length 95.3
  TOP w0.102: CPU1.AR41 188.91,56.15 v4(188.53,55.76) ; DIMM1.11 248.89,73.17 248.97,73.1 248.97,72.92 249.02,72.88 249.85,72.88 249.95,72.98 250.68,72.98 251.11,73.41 251.11,73.97 v3(250.87,74.21)
  L3 w0.089: 191.93,66.2 191.93,66.17 191.95,66.15 191.95,65.47 191.71,65.23 191.71,64.3 190.82,63.41 190.82,62.65 191.15,62.32 191.15,61.19 190.86,60.9 190.86,59.01 190.54,58.69 190.54,57.62 190.89,57.27 190.89,56.57 190.62,56.3 189.46,56.3 189.29,56.13 189.05,56.13 188.68,55.76 v4(188.53,55.76)
  L3 w0.114: v3(250.87,74.21) 250.64,73.97 250.36,73.97 249.44,74.89 248.14,74.89 242.8,80.23 233.45,80.23 230.03,76.81 229.41,76.81 229.3,76.91 229.3,78.1 229.06,78.35 228.47,78.35 228.22,78.1 228.22,76.96 228.11,76.85 227.72,76.85 227.6,76.96 227.6,77.83 227.35,78.08 226.77,78.08 226.52,77.83 226.52,77.06 226.38,76.92 220.1,76.92 219.99,77.03 211.25,77.03 211.13,76.92 204.89,76.92 204.33,76.35 195.52,76.35 193.74,74.58 193.74,73.23 192.41,71.9 192.41,67.75 191.93,67.28 191.93,66.2
  BOTTOM w0.102: v3(250.87,74.21) v1(250.87,73.39)
M_A_DQS_DP0: length 78.7
  TOP w0.076: 194.76,44.64 194.74,44.64 194.73,44.63 194.24,44.63 194.05,44.82 193.6,44.82 193.44,44.66 193.16,44.66 193.03,44.71 192.85,44.71 192.42,44.56 192.22,44.56 191.9,44.44 CPU1.BY46
  TOP w0.102: DIMM1.200 254.45,23.92 v3(253.95,23.43) ; v3(197.89,42.33) 197.12,42.33 196.94,42.51 196.94,43.1 197.32,43.48 197.32,44.26 196.94,44.64 194.76,44.64
  L3 w0.114: v3(253.95,23.43) 253.75,23.23 253.75,22.75 253.42,22.42 252.54,22.42 251.69,23.27 240.91,23.27 240.37,22.73 229.78,22.73 226.87,25.64 224.64,25.64 218.88,31.39 214.49,31.39 208.14,37.74 204.17,37.74 201.81,40.09 198.95,40.09 197.59,41.46 197.59,41.82 197.88,42.11 197.89,42.11 v3(197.89,42.33)
  BOTTOM w0.102: v3(197.89,42.33) 197.89,42.14 v1(197.42,41.67)
M_A_DQS_DP1: length 90.7
  TOP w0.102: DIMM1.242 255.26,13.42 255.2,13.49 254.43,13.49 254.2,13.26 254.02,13.26 253.95,13.19 v3(253.95,12.93) ; CPU1.CE41 189.19,41.33 189.19,41.22 v4(189.2,41.22)
  L3 w0.114: v4(189.2,41.22) 189.41,41.43 189.57,41.43 189.66,41.34 189.66,38.48 190.55,37.59 190.82,37.59 192.03,36.38 192.03,35.15 193.09,34.08 193.09,32.29 193.58,31.8 195.25,31.8 197.47,29.58 205.25,29.58 211.22,23.61 214.52,23.61 227.17,10.96 230.59,10.96 230.95,11.31 231.47,11.31 231.83,10.96 232.29,10.96 232.54,11.2 232.54,11.61 232.65,11.73 233.07,11.73 233.18,11.61 233.18,11.24 233.43,10.99 233.92,10.99 234.25,11.32 240.19,11.32 240.52,11.64 240.76,11.64 240.87,11.53 240.87,11.24 241.12,10.99 241.7,10.99 241.95,11.24 241.95,11.53 242.07,11.64 243.52,11.64 244.95,10.21 247.58,10.21 247.82,10.46 247.82,11.2 247.94,11.31 248.33,11.31 248.45,11.2 248.45,10.48 248.69,10.23 249.26,10.23 249.59,10.56 249.59,11.71 249.7,11.83 250.72,11.83 251.09,12.19 252.82,12.19 253.1,12.46 253.48,12.46 v3(253.95,12.93)
M_A_DQS_DP2: length 76.5
  TOP w0.076: CPU1.BR46 191.9,46.63 192.22,46.5 192.42,46.5 192.85,46.35 193.03,46.35 193.16,46.4 193.38,46.4 193.55,46.23 194.38,46.23 194.62,46.48 194.64,46.48 194.66,46.5
  TOP w0.102: DIMM1.179 248.74,29.17 248.87,29.3 250.17,29.3 250.32,29.15 250.32,28.8 250.19,28.67 v3(250.05,28.67) ; 202.95,43.85 203.88,43.85 204.67,43.06 204.67,41.65 208.27,38.05 213.84,38.05 214.81,37.09 215.77,37.09 216.33,36.53 216.33,36.08 216.22,35.98 v3(216.07,35.98) ; 202.95,43.85 v1(202.95,43.48) ; 202.95,43.85 200.86,43.85 198.14,46.56 194.73,46.56 194.66,46.5
  L3 w0.114: v3(216.07,35.98) 216.36,35.69 216.36,35.53 216.61,35.28 220.49,35.28 225.97,29.81 233.66,29.81 234.07,29.4 236.85,29.4 236.96,29.29 236.96,28.96 237.21,28.71 240.49,28.71 240.63,28.57 244.79,28.57 244.9,28.46 244.9,28.26 245.15,28.01 245.82,28.01 246.07,28.26 246.07,29.22 246.19,29.33 246.58,29.33 246.69,29.22 246.69,28.13 246.94,27.89 247.53,27.89 247.77,28.13 247.77,29.22 247.89,29.34 250.17,29.34 250.28,29.22 250.28,28.9 v3(250.05,28.67)
M_A_DQS_DP3: length 86.4
  TOP w0.102: CPU1.BW41 188.91,44.48 v4(188.57,44.81) ; DIMM1.221 248.74,18.67 248.87,18.8 250.19,18.8 250.43,18.56 250.43,18.35 v3(250.18,18.1)
  L3 w0.114: v4(188.57,44.81) 188.69,44.81 188.81,44.92 188.81,44.96 189.25,45.4 191.11,45.4 191.47,45.04 191.5,45.04 192.89,43.64 192.89,41.04 194.45,39.47 196.41,39.47 197.73,38.16 200.33,38.16 204.58,33.9 206.8,33.9 212.97,27.73 216.28,27.73 222.03,21.98 223.56,21.98 223.99,21.55 224.16,21.55 224.46,21.85 224.81,21.85 225.22,21.44 225.22,21.08 224.92,20.79 224.92,20.62 228.67,16.87 236.94,16.87 237.33,17.26 240.62,17.26 240.86,17.01 240.86,16.68 240.98,16.57 241.37,16.57 241.49,16.68 241.49,17.01 241.73,17.26 242.32,17.26 242.57,17.01 242.57,16.68 242.68,16.57 243.07,16.57 243.19,16.68 243.19,17.01 243.44,17.26 244.02,17.26 244.27,17.01 244.27,16.68 244.38,16.57 244.78,16.57 244.89,16.68 244.89,17.01 245.14,17.26 245.72,17.26 245.97,17.01 245.97,16.68 246.08,16.57 246.48,16.57 246.59,16.68 246.59,17.01 246.84,17.26 247.42,17.26 247.67,17.01 247.67,16.68 247.79,16.57 248.18,16.57 248.29,16.68 248.29,17.01 248.54,17.26 250.35,17.26 250.47,17.37 250.47,17.81 v3(250.18,18.1)
M_A_DQS_DP4: length 76.1
  TOP w0.076: 197.1,54.13 197.09,54.13 197.07,54.14 196.82,54.14 196.77,54.09 195.29,54.09 194.74,54.64 193.62,54.64 193.54,54.56 193.31,54.48 193.16,54.48 192.99,54.54 192.84,54.54 192.7,54.49 192.46,54.49 CPU1.AV47
  TOP w0.102: DIMM1.76 255.23,56.92 254.94,57.22 254.34,57.22 254.11,56.99 253.73,56.99 253.27,57.45 v3(253.21,57.45) ; v4(199.9,55.08) 199.9,55.08 199.68,54.86 199.68,54.59 199.22,54.13 197.1,54.13
  L3 w0.114: v4(199.9,55.08) 199.9,55.08 199.71,55.28 199.71,55.46 199.82,55.58 200.22,55.58 202.43,57.78 202.84,57.78 203.97,58.91 204.29,58.91 205.64,60.27 210.14,60.27 210.23,60.36 216.68,60.36 217.05,59.99 217.05,59.6 217.34,59.31 217.89,59.31 218.13,59.56 218.13,60.2 218.25,60.32 218.64,60.32 218.76,60.2 218.76,59.55 219,59.3 219.59,59.3 219.84,59.55 219.84,60.3 219.99,60.46 221.22,60.46 221.94,61.18 232.77,61.18 233.06,61.47 233.06,62.18 233.32,62.44 236.92,62.44 237.19,62.17 239.9,62.17 244.32,57.75 252.04,57.75 252.39,58.1 253.26,58.1 253.47,57.88 253.47,57.71 v3(253.21,57.45)
  BOTTOM w0.102: v1(253.21,58.26) v3(253.21,57.45)
M_A_DQS_DP5: length 87.8
  TOP w0.102: DIMM1.34 255.15,67.42 255.07,67.51 255.07,67.65 254.99,67.72 254.36,67.72 254.12,67.97 253.76,67.97 253.3,68.43 v3(253.24,68.43) ; v4(189.17,53.07) 189.17,52.85 CPU1.BB41
  L3 w0.089: 195.09,63.73 195.07,63.72 195.05,63.72 194.79,63.46 194.47,63.46 194.11,63.1 194.11,62.39 194.34,62.17 194.34,61.42 193.49,60.57 193.49,59.66 193.1,59.27 193.1,54.88 191.82,53.6 191.08,53.6 190.84,53.37 190.3,53.37 190.29,53.36 189.22,53.36 189.11,53.25 189.11,53.12 v4(189.17,53.07)
  L3 w0.114: v3(253.24,68.43) 253.24,68.73 253.32,68.81 253.62,68.81 253.72,68.91 253.72,69.37 253.54,69.55 252.44,69.55 251.28,68.39 248.13,68.39 246.85,69.67 245.77,69.67 242.76,72.67 239.44,72.67 239.09,73.02 237.03,73.02 236.62,73.43 233.57,73.43 232.48,72.33 213.24,72.33 212.49,71.58 200.75,71.58 195.65,66.49 195.65,64.29 195.09,63.73
  BOTTOM w0.102: v1(253.78,67.6) 253.24,68.15 v3(253.24,68.43)
M_A_DQS_DP6: length 77.8
  TOP w0.076: 194.54,56.93 194.52,56.93 194.52,56.93 194.19,56.93 194.04,57.08 193.6,57.08 193.38,57 193.14,57 192.98,57.05 192.87,57.05 192.71,56.99 192.46,56.99 CPU1.AN47
  TOP w0.083: v4(197.56,57.92) 197.19,57.55 196.88,57.55 196.25,56.93 194.54,56.93
  TOP w0.102: v3(251.83,63.24) 251.5,63.24 250.57,62.31 249.3,62.31 249.16,62.17 DIMM1.55
  L3 w0.114: v3(251.83,63.24) 251.79,63.28 251.13,63.28 251.07,63.35 250.17,63.35 249.88,63.64 245.09,63.64 241.05,67.67 237.04,67.67 236.73,67.36 221.07,67.36 220.47,66.76 220.47,65.56 220.22,65.31 219.63,65.31 219.39,65.56 219.39,66 219.27,66.12 218.88,66.12 218.76,66 218.76,65.56 218.52,65.31 217.93,65.31 217.68,65.56 217.68,66 217.57,66.12 211.54,66.12 210.78,65.35 207.81,65.35 206.48,66.68 205.26,66.68 205.13,66.55 205.13,66.01 205.26,65.88 205.71,65.88 205.98,65.62 205.98,65.06 205.68,64.75 204.34,64.75 198.25,58.66 197.9,58.66 197.56,58.32 v4(197.56,57.92)
  BOTTOM w0.102: v3(251.83,63.24) 251.58,63.24 v1(251.14,62.81)
M_A_DQS_DP7: length 95.3
  TOP w0.102: DIMM1.13 249.93,72.67 250.04,72.78 250.76,72.78 251.31,73.33 251.31,73.9 v3(251.58,74.16) ; CPU1.AT41 188.91,55.48 v4(189.2,55.77)
  L3 w0.089: 192.16,66.2 192.16,66.17 192.14,66.15 192.14,65.39 191.9,65.15 191.9,64.22 191.01,63.33 191.01,62.72 191.34,62.4 191.34,61.12 191.05,60.83 191.05,58.93 190.73,58.61 190.73,57.7 191.08,57.35 191.08,56.49 190.7,56.11 189.54,56.11 v4(189.2,55.77)
  L3 w0.114: 192.16,66.2 192.16,67.19 192.63,67.66 192.63,71.8 193.97,73.14 193.97,74.48 195.61,76.12 204.43,76.12 204.99,76.69 211.23,76.69 211.34,76.81 219.89,76.81 220.01,76.69 226.48,76.69 226.75,76.96 226.75,77.73 226.87,77.85 227.26,77.85 227.37,77.73 227.37,76.87 227.62,76.62 228.2,76.62 228.45,76.87 228.45,78.01 228.57,78.12 228.96,78.12 229.07,78.01 229.07,76.82 229.32,76.58 230.12,76.58 233.54,80 242.71,80 248.04,74.66 249.34,74.66 250.27,73.74 251.16,73.74 v3(251.58,74.16)
  BOTTOM w0.102: v3(251.58,74.16) v1(251.58,74.98)
M_A_ODT0: length 89.3
  TOP w0.14: DIMM1.155 246.65,35.17 v3(246.34,34.86) ; CPU1.BJ39 v4(188.47,48.49)
  L3 w0.089: 194.61,46.8 194.35,46.8 193.91,47.23 193.05,47.23 192.41,47.87 189.62,47.87 189.51,47.97 188.57,47.97 188.47,48.08 v4(188.47,48.49)
  L3 w0.165: v3(246.34,34.86) 246.34,35.08 245.39,36.03 245.07,36.03 244.91,35.86 244.91,34.97 244.74,34.8 244.34,34.8 244.17,34.97 244.17,35.85 244,36.03 240.48,36.03 239.58,35.13 236.72,35.13 236.7,35.11 234.72,35.11 233.7,35.11 233.53,35.27 233.53,35.99 233.4,36.13 233.01,36.13 232.87,35.99 232.87,35.27 232.71,35.11 232.38,35.11 232.21,35.27 232.21,35.95 232.05,36.12 231.72,36.12 231.55,35.95 231.55,35.27 231.39,35.11 231.06,35.11 230.89,35.27 230.89,35.75 230.73,35.92 230.42,35.92 230.23,35.73 230.23,35.27 230.07,35.11 228.91,35.11 228.71,35.31 228.71,35.77 228.51,35.97 228.19,35.97 227.33,35.11 226.98,35.11 226.77,35.32 226.77,35.55 227.71,36.49 227.71,36.73 227.48,36.96 227.24,36.96 226.3,36.02 226.07,36.02 225.84,36.25 225.84,36.49 226.77,37.42 226.77,37.65 226.54,37.89 226.3,37.89 225.37,36.95 225.14,36.95 224.9,37.19 224.9,37.42 225.85,38.36 225.85,38.6 225.61,38.83 225.38,38.83 224.44,37.89 224.2,37.89 223.97,38.12 223.97,38.35 224.93,39.31 224.93,39.51 224.68,39.76 224.44,39.76 223.5,38.82 223.27,38.82 223.04,39.05 223.04,39.29 223.78,40.03 223.78,40.27 223.55,40.5 223.31,40.5 222.57,39.76 222.33,39.76 221.51,40.58 217.45,40.58 215.47,42.56 204.16,42.56 202.19,44.52 199.2,44.52 198.19,45.54 196.53,45.54 195.27,46.8 194.61,46.8
  BOTTOM w0.14: v3(246.34,34.86) v1(247.15,34.86)
M_A_ODT1: length 80.4
  TOP w0.14: v3(250.24,32.25) 250.24,32.72 249.29,33.67 DIMM1.161 ; CPU1.BB45 190.83,52.42 190.54,52.13 v4(189.22,52.13)
  L3 w0.089: 193.16,45.78 192.12,46.82 189.85,46.82 189.84,46.81 188.92,46.81 188.69,47.04 188.34,47.04 187.7,47.23 187.58,47.35 187.47,47.58 187.47,49.26 187.61,51.36 187.87,51.62 188.62,51.75 v4(189.22,52.13)
  L3 w0.165: v3(250.24,32.25) 250.19,32.21 249.06,32.21 246.56,32.66 241.53,32.66 241.52,32.66 237.63,32.66 237.09,32.12 227.9,32.12 226.61,32.51 221.37,37.76 221.36,37.76 218.22,37.95 217.56,37.95 214.77,40.74 204.11,40.74 203.28,41.57 198.78,43.5 198.48,43.8 196.71,44.39 195.17,44.39 193.52,45.42 193.16,45.78
  BOTTOM w0.14: v3(250.24,32.25) v1(250.24,31.44)
M_A_PARITY: length 82.3
  TOP w0.14: DIMM1.143 248.45,40.17 249.59,39.03 v3(253.61,39.03) ; CPU1.BF39 v4(188.59,50.34)
  L3 w0.089: 191.75,50.08 191.39,50.08 191.16,50.31 189.83,50.31 189.45,50.69 188.94,50.69 v4(188.59,50.34)
  L3 w0.165: v3(253.61,39.03) 254.25,39.67 254.78,39.67 255.1,39.35 255.1,38.85 254.76,38.51 250.81,38.51 250.23,39.09 249.04,39.09 248.26,39.87 241.92,39.87 241.39,39.87 240.49,40.77 237.29,40.77 236.73,40.21 235.66,40.21 235.34,40.54 234.15,40.54 230.99,43.69 218.74,43.69 216.76,45.67 203.97,45.67 203.34,46.3 200.09,46.3 198.74,47.65 197.32,47.65 195.47,49.5 194.48,49.5 193.9,50.08 191.75,50.08
  BOTTOM w0.14: v3(253.61,39.03) v1(252.69,39.03)
M_B_A0: length 71.4
  TOP w0.114: v4(189.2,66.75) 189.2,66.67 CPU1.P42
  TOP w0.14: v3(239.81,39.09) 239.81,39.63 240.11,39.92 DIMM2.144
  L4 w0.089: v4(189.2,66.75) 189.43,66.53 190.21,66.53 191,67.32 191.54,67.32 192.26,68.03 192.26,68.26 193.18,69.18 201.51,69.18 204.38,66.31 204.38,65.91 204.65,65.64
  L4 w0.165: 204.65,65.64 215.12,55.17 231.86,38.43 233.1,38.43 233.11,38.43 240.97,38.43 241.14,38.59 241.14,38.93 240.97,39.09 v3(239.81,39.09)
  BOTTOM w0.14: v1(240.62,39.09) v3(239.81,39.09)
M_B_A1: length 76
  TOP w0.076: CPU1.Y49 193.3,63.6 194.39,63.6 194.42,63.63 196.35,63.63 197.86,62.11 201.08,62.11
  TOP w0.14: v4(209.89,62.97) 209.85,63.02 209.71,63.02 208.27,64.47 208.27,65.07 206.69,66.66 206.04,66.66 v1(203.54,64.16) 201.49,62.11 201.08,62.11 ; v3(235.05,42.25) 235.04,42.25 235.04,42.4 235.04,42.4 235.04,42.62 234.9,42.76 234.05,42.76 233.97,42.67 DIMM2.133
  L4 w0.165: v3(235.05,42.25) 235.14,42.15 236.6,42.15 237.27,41.48 243.39,41.48 243.55,41.32 243.55,41.08 243.39,40.91 242.06,40.91 241.64,40.49 240.74,40.49 240.31,40.91 237.16,40.91 236.47,41.6 233.92,41.6 233.69,41.83 233.37,42.15 232.13,42.15 214.02,60.26 212.61,60.26 v4(209.89,62.97)
M_B_A2: length 72.6
  TOP w0.076: CPU1.U48 192.94,65.11 193.12,65.17 194.97,65.17 195.48,65.68 195.48,66.78 196,67.3 196,67.47 197.74,69.22 202.51,69.22 202.67,69.37 202.9,69.37 202.9,69.37
  TOP w0.14: DIMM2.132 239.45,42.92 v3(238.95,43.42) ; 202.9,69.37 203.47,69.37 203.97,69.86 v1(204.46,69.86) 206.38,69.86 209.31,66.94 209.31,66.4 209.95,65.77 209.95,65.27 210.42,64.8 212.37,64.8 v4(214.09,63.08)
  L4 w0.165: v3(238.95,43.42) 239.44,43.91 241.56,43.91 241.97,43.5 241.97,42.27 241.63,41.92 237.5,41.92 236.51,42.91 236.51,43.74 235.92,44.33 233.23,44.33 216.05,61.51 215.45,61.51 215.34,61.4 214.77,61.4 214.09,62.08 v4(214.09,63.08)
M_B_A3: length 79.8
  TOP w0.076: CPU1.Y45 191.62,64 192.26,64 192.35,63.92 192.68,63.92 192.82,63.87 192.98,63.87 193.08,63.91 193.39,63.91 193.52,63.77 194.33,63.77 194.35,63.79 196.41,63.79 197.9,62.31 200.76,62.31
  TOP w0.14: DIMM2.131 234.97,43.17 234.98,43.17 235.37,43.17 235.38,43.17 235.67,43.17 235.94,43.44 v3(235.94,43.46) ; v4(211.23,63) 210.79,63.44 209.89,63.44 208.69,64.64 208.69,65.25 206.86,67.07 205.53,67.07 v1(204.49,66.03) 200.76,62.31
  L4 w0.165: v3(235.94,43.46) 236.05,43.35 236.05,42.76 235.88,42.59 235.41,42.59 235.26,42.75 232.16,42.75 231.79,43.12 231.79,43.35 232.24,43.8 232.24,44.04 232.01,44.27 231.78,44.27 231.33,43.82 231.09,43.82 230.86,44.05 230.86,44.28 231.31,44.74 231.31,44.97 231.08,45.2 230.84,45.2 230.39,44.75 230.16,44.75 229.92,44.98 229.92,45.22 230.38,45.67 230.38,45.9 230.14,46.14 229.91,46.14 229.46,45.69 229.22,45.69 228.99,45.92 228.99,46.15 229.44,46.6 229.44,46.84 229.21,47.07 228.98,47.07 228.52,46.62 228.29,46.62 228.06,46.85 228.06,47.09 228.51,47.54 228.51,47.77 228.27,48.01 228.04,48.01 227.59,47.55 227.36,47.55 227.12,47.79 227.12,48.02 227.57,48.47 227.57,48.71 227.34,48.94 227.11,48.94 226.65,48.49 226.42,48.49 226.19,48.72 226.19,48.96 226.64,49.41 226.64,49.64 226.41,49.87 226.17,49.87 225.72,49.42 225.49,49.42 225.25,49.66 225.25,49.89 225.71,50.34 225.71,50.58 225.47,50.81 225.24,50.81 224.79,50.36 224.55,50.36 224.32,50.59 224.32,50.82 224.77,51.28 224.77,51.51 224.54,51.74 224.3,51.74 223.85,51.29 223.62,51.29 223.38,51.52 223.38,51.76 223.84,52.21 223.84,52.44 223.6,52.68 223.37,52.68 222.92,52.23 222.68,52.23 214.2,60.71 212.52,60.71 211.83,61.39 211.83,61.63 212.38,62.18 212.38,62.41 212.14,62.65 211.9,62.65 211.53,62.28 211.3,62.28 211.03,62.55 211.03,62.8 v4(211.23,63)
M_B_A4: length 78.2
  TOP w0.076: 201.58,68.46 201.23,68.81 197.81,68.81 196.33,67.33 196.33,67.16 195.84,66.67 195.84,65.57 195.11,64.84 193.54,64.84 193.42,64.72 193.27,64.66 193.18,64.66 193.02,64.72 192.81,64.72 192.67,64.66 192.53,64.66 192.3,64.74 CPU1.U47
  TOP w0.14: DIMM2.128 239.18,43.92 239.05,44.06 239.05,44.23 238.85,44.43 237.82,44.43 237.68,44.29 237.68,44.01 v3(238.22,43.47) ; v4(214.77,63.12) 214.77,62.41 214.59,62.22 212.52,62.22 212.26,62.48 212.26,63.72 212.02,63.96 209.96,63.96 209.11,64.81 209.11,65.42 208.41,66.12 208.41,66.65 206.48,68.58 v1(204.37,68.58) 204.26,68.46 201.58,68.46
  L4 w0.165: v3(238.22,43.47) 238.03,43.47 237.74,43.18 237.74,43.03 237.91,42.86 240.17,42.86 240.34,43.03 240.34,43.35 240.45,43.47 241.38,43.47 241.53,43.32 241.53,42.45 241.44,42.37 237.7,42.37 236.95,43.11 236.95,43.92 236.1,44.78 233.78,44.78 233.78,44.78 233.41,44.78 215.98,62.21 215.48,62.21 215.14,61.86 214.93,61.86 214.57,62.22 214.57,62.46 214.88,62.77 214.88,63 v4(214.77,63.12)
M_B_A5: length 75.6
  TOP w0.076: 201.91,70.55 201.63,70.27 197.86,70.27 195.34,67.74 195.34,67.57 194.62,66.86 194.62,66.56 194.11,66.04 193.37,66.04 CPU1.R49
  TOP w0.14: v4(215.44,63.14) 215.44,63.57 212.82,66.2 211.42,66.2 210.67,66.95 210.67,70.16 208.36,72.47 v1(204.74,72.47) 203.83,72.47 201.91,70.55 ; v3(238.95,44.92) 239.45,44.42 DIMM2.126
  L4 w0.165: v3(238.95,44.92) 239.48,45.45 243.53,45.45 243.82,45.17 243.82,44.64 243.53,44.36 237.15,44.36 236.28,45.22 233.59,45.22 216.14,62.68 215.9,62.68 v4(215.44,63.14)
M_B_A6: length 76.3
  TOP w0.076: 203.78,68.98 197.74,68.98 196.16,67.4 196.16,67.23 195.67,66.74 195.67,66.6 195.67,66.6 195.67,65.64 195.04,65.01 193.31,65.01 CPU1.U49
  TOP w0.14: 203.78,68.98 204.05,69.24 v1(205.87,69.24) 206.41,69.24 208.85,66.8 208.85,66.27 209.53,65.59 209.53,64.99 210.13,64.38 212.19,64.38 212.74,63.84 v4(212.74,63.08) ; DIMM2.127 233.79,44.17 233.87,44.26 235.04,44.26 235.27,44.02 235.27,43.67 v3(235.26,43.66)
  L4 w0.165: v4(212.74,63.08) 212.74,62.7 212.91,62.53 213.44,62.53 213.57,62.4 213.57,61.99 213.43,61.85 212.83,61.85 212.66,61.68 212.66,61.32 212.83,61.15 214.39,61.15 214.94,60.6 215.17,60.6 215.63,61.06 215.87,61.06 216.16,60.77 216.16,60.53 215.71,60.08 215.71,59.85 215.94,59.62 216.18,59.62 216.63,60.07 216.86,60.07 217.1,59.83 217.1,59.6 216.64,59.15 216.64,58.92 216.88,58.68 217.11,58.68 217.56,59.13 217.8,59.13 218.03,58.9 218.03,58.67 217.58,58.21 217.58,57.98 217.81,57.75 218.04,57.75 218.5,58.2 218.73,58.2 218.96,57.97 218.96,57.73 218.51,57.28 218.51,57.05 218.75,56.81 218.98,56.81 219.43,57.27 219.66,57.27 219.9,57.03 219.9,56.8 219.45,56.35 219.45,56.11 219.68,55.88 219.91,55.88 220.36,56.33 220.6,56.33 220.83,56.1 220.83,55.86 220.38,55.41 220.38,55.18 220.61,54.94 220.85,54.94 221.3,55.4 221.53,55.4 221.77,55.16 221.77,54.93 221.31,54.48 221.31,54.24 221.55,54.01 221.78,54.01 222.23,54.46 222.47,54.46 222.7,54.23 222.7,54 222.25,53.54 222.25,53.31 222.48,53.08 222.72,53.08 223.16,53.52 223.39,53.52 232.59,44.32 232.59,44.32 232.69,44.22 232.69,43.38 232.88,43.19 233.21,43.19 233.38,43.36 233.38,43.7 233.57,43.89 233.88,43.89 234.04,43.72 234.04,43.37 234.23,43.19 234.79,43.19 v3(235.26,43.66)
M_B_A7: length 74.4
  TOP w0.076: 199.57,71.59 199.36,71.38 197.57,71.38 194.35,68.16 194.35,67.98 194.04,67.68 193.52,67.68 193.34,67.75 193.15,67.75 192.97,67.69 192.85,67.69 192.66,67.75 192.58,67.76 192.15,67.65 CPU1.M47
  TOP w0.14: DIMM2.122 237.63,45.42 237.49,45.56 v3(237.49,46.46) ; v4(216.03,65.42) 216.03,70.96 210.89,76.1 203.03,76.1 v1(200.66,73.73) 200.04,73.1 200.04,72.06 199.57,71.59
  L4 w0.165: v4(216.03,65.42) 216.1,65.42 233.76,47.76 237.79,47.76 238.06,48.03 238.93,48.03 239.08,47.88 239.08,47.78 239.48,47.38 239.48,47.09 239.31,46.92 237.94,46.92 v3(237.49,46.46)
M_B_A8: length 75.9
  TOP w0.076: CPU1.M45 191.58,67.78 192.11,67.81 192.63,67.94 192.86,67.86 192.96,67.86 193.12,67.91 193.37,67.91 193.51,67.86 193.68,67.84 193.97,67.84 194.18,68.05 194.18,68.22 197.5,71.55 199.02,71.55 199.58,72.11
  TOP w0.14: v4(216.16,63.18) 216.73,63.75 216.73,70.85 211.06,76.52 202.52,76.52 v1(201.05,75.05) 199.69,73.69 199.69,72.22 199.58,72.11 ; DIMM2.125 235.57,44.67 236.15,45.26 236.95,45.26 v3(237.3,44.91)
  L4 w0.165: v3(237.3,44.91) 237.53,44.91 238.04,45.42 238.04,45.81 237.87,45.97 237.17,45.97 236.86,45.67 233.78,45.67 216.28,63.16 216.18,63.16 v4(216.16,63.18)
M_B_A9: length 76
  TOP w0.076: CPU1.R47 191.93,65.89 191.99,65.84 192.35,65.84 192.38,65.81 192.93,65.81 193.18,65.71 194.25,65.71 194.66,66.13 194.94,66.13 195.02,66.21 195.02,66.79 195.67,67.43 195.67,67.61 197.79,69.73 202.04,69.73 202.51,70.21 202.84,70.21
  TOP w0.14: 202.84,70.21 203.74,71.1 v1(204.83,71.1) 208.37,71.1 209.81,69.66 209.81,66.63 210.38,66.06 210.38,65.5 210.66,65.22 212.25,65.22 212.39,65.36 v4(212.39,65.67) ; v3(236.02,46.46) 236.2,46.29 236.2,45.9 235.41,45.11 234.34,45.11 233.78,45.67 DIMM2.121
  L4 w0.165: v3(236.02,46.46) 236.22,46.27 236.6,46.27 237.19,46.86 237.19,47.15 237.02,47.32 233.47,47.32 216.66,64.13 215.75,64.13 215.59,64.29 215.59,64.82 215.42,64.99 214.37,64.99 214.07,65.29 214.07,66.32 213.36,67.02 210.43,67.02 210.27,66.86 210.27,66.46 210.45,66.28 213.33,66.28 213.52,66.09 213.52,65.85 213.34,65.67 v4(212.39,65.67)
M_B_A10: length 74.3
  TOP w0.114: v4(188.51,66.76) CPU1.P39
  TOP w0.14: v3(238.55,37.13) 238.51,37.13 238.52,37.12 238.76,37.12 238.9,37.26 238.9,37.52 239.04,37.66 240.14,37.66 240.37,37.42 DIMM2.146
  L4 w0.089: v4(188.51,66.76) 188.92,66.35 190.28,66.35 191.08,67.15 191.24,67.15 191.62,67.15 192.33,67.86 192.43,67.96 192.43,68.18 193.26,69.01 201.44,69.01 204.12,66.32 204.12,65.84 204.46,65.5 204.46,65.48
  L4 w0.165: v3(238.55,37.13) 238.55,36.68 238.72,36.51 240,36.51 240.21,36.72 240.21,37.82 240.05,37.98 231.67,37.98 211.75,57.9 211.75,58.18 204.46,65.48
  BOTTOM w0.14: v3(238.55,37.13) v1(238.83,36.36)
M_B_A11: length 76.2
  TOP w0.076: CPU1.N46 192.26,66.51 192.51,66.46 192.63,66.46 192.79,66.4 193.03,66.4 193.17,66.45 193.25,66.46 193.38,66.46 193.62,66.21 194.04,66.21 194.45,66.62 194.45,66.91 195.17,67.64 195.17,67.81 197.87,70.51 201.25,70.51 201.87,71.14
  TOP w0.14: 201.87,71.14 203.81,73.08 v1(206.44,73.08) 208.35,73.08 211.09,70.33 211.09,67.13 211.6,66.62 212.99,66.62 214.13,65.48 v4(214.71,65.48) ; v3(238.95,46.4) 238.95,46.06 239.09,45.92 DIMM2.120
  L4 w0.165: v3(238.95,46.4) 238.95,46.29 239.32,45.91 240.36,45.91 240.53,46.08 240.53,46.56 240.69,46.72 241.11,46.72 241.27,46.56 241.27,46.06 241.43,45.9 241.89,45.9 242.05,46.06 242.05,48.31 241.88,48.48 237.88,48.48 237.63,48.23 233.92,48.23 218.16,63.99 218.16,64.01 216.16,66 214.87,66 214.71,65.84 v4(214.71,65.48)
M_B_A12: length 75.8
  TOP w0.076: 202.39,70.41 202.01,70.02 197.85,70.02 195.5,67.68 195.5,67.5 194.82,66.82 194.82,66.52 194.18,65.88 193.3,65.88 193.18,65.89 192.96,65.98 192.78,65.98 CPU1.R48
  TOP w0.14: 202.39,70.41 203.81,71.83 v1(206.19,71.83) 208.23,71.83 210.25,69.81 210.25,66.78 211.36,65.67 v4(211.72,65.67) ; DIMM2.119 235.41,46.17 235.55,46.31 235.55,46.61 235.41,46.75 235.11,46.75 v3(235.05,46.69)
  L4 w0.165: v3(235.05,46.69) 235.31,46.69 235.48,46.52 235.48,46.28 235.31,46.11 233.96,46.11 216.39,63.68 215.26,63.68 215.1,63.85 215.1,64.37 214.93,64.54 214.6,64.54 214.44,64.37 214.44,63.85 214.27,63.68 213.91,63.68 213.75,63.85 213.75,64.98 213.58,65.15 213.21,65.15 213.05,64.98 213.05,63.85 212.88,63.68 212.51,63.68 212.34,63.85 212.34,64.79 212.19,64.94 211.78,64.94 211.61,64.78 211.61,63.85 211.45,63.68 211.06,63.68 210.89,63.85 210.89,64.46 210.73,64.63 210.4,64.63 210.23,64.46 210.23,63.85 210.07,63.68 209.37,63.68 209.23,63.83 209.23,64.86 209.35,64.98 209.65,64.98 210.49,65.82 211.56,65.82 v4(211.72,65.67)
M_B_A13: length 75.4
  TOP w0.14: v3(237.24,34.19) 237.82,33.6 238.87,33.6 239.15,33.88 239.15,34.2 239.46,34.52 239.95,34.52 240.04,34.42 DIMM2.158 ; CPU1.Y41 188.91,63.64 v4(188.53,64.02)
  L4 w0.089: 200.93,63.02 200.59,63.02 200.55,62.98 198.08,62.98 196.22,64.84 192.67,64.84 191.84,64.02 v4(188.53,64.02)
  L4 w0.165: v3(237.24,34.19) 237.24,33.88 237.43,33.69 238.12,33.69 238.22,33.58 238.22,33.06 238.07,32.91 237.5,32.91 237.34,32.75 237.34,32.41 237.17,32.24 233.97,32.24 233.96,32.24 233.32,32.24 233.15,32.4 233.15,33.05 232.94,33.26 231.55,33.26 231.38,33.09 231.38,32.5 231.21,32.33 230.74,32.33 222.19,40.88 222.19,42.4 208.08,56.53 208.08,58.02 203.08,63.02 200.93,63.02
  BOTTOM w0.14: v1(189.31,63.89) 188.65,63.89 v4(188.53,64.02)
M_B_A14: length 74.7
  TOP w0.114: CPU1.V41 188.91,64.68 v4(188.62,64.97)
  TOP w0.14: DIMM2.151 232.91,36.16 234.03,36.16 234.1,36.09 234.56,36.09 v3(235.06,35.6)
  L4 w0.089: 203.58,64.62 203.23,64.98 203.23,66.47 201.22,68.47 194.82,68.47 192.85,66.51 191.19,66.51 190.35,65.66 190.18,65.66 189.81,65.29 188.71,65.29 188.62,65.21 v4(188.62,64.97)
  L4 w0.165: 203.58,64.62 204.09,64.62 210.36,58.35 210.36,57.76 210.36,57.39 225.01,42.74 225.01,42.5 224.48,41.97 224.48,41.74 224.72,41.5 224.95,41.5 225.48,42.03 225.71,42.03 225.95,41.8 225.95,41.57 225.42,41.04 225.42,40.8 225.65,40.57 225.88,40.57 226.41,41.1 226.65,41.1 226.88,40.87 226.88,40.63 226.35,40.1 226.35,39.87 226.58,39.64 226.82,39.64 227.35,40.17 227.58,40.17 227.81,39.93 227.81,39.7 227.28,39.17 227.28,38.93 227.52,38.7 227.75,38.7 227.85,38.8 228.08,38.8 228.31,38.56 228.31,38.33 228.22,38.23 228.22,38 229.57,36.65 231.47,36.65 233.59,36.65 234.12,36.11 234.54,36.11 v3(235.06,35.6)
  BOTTOM w0.14: v1(233.81,34.99) 234.53,35.11 235.05,35.53 v3(235.06,35.6)
M_B_A15: length 75.8
  TOP w0.114: v4(189.18,63.1) 189.18,63.19 CPU1.Y42
  TOP w0.14: v3(238.67,34.17) 238.67,34.38 239.22,34.94 240.13,34.94 240.14,34.92 DIMM2.156
  L4 w0.089: 199.86,62.74 198.07,62.74 196.15,64.66 193.59,64.66 192.65,63.72 189.27,63.72 189.18,63.64 v4(189.18,63.1)
  L4 w0.165: v3(238.67,34.17) 238.67,32.45 239.37,31.75 239.37,31.57 239.21,31.42 237.77,31.42 237.39,31.79 235.91,31.79 235.9,31.79 233.4,31.79 232.86,31.79 232.69,31.96 232.69,32.54 232.53,32.71 232.03,32.71 231.87,32.54 231.87,32 231.66,31.79 230.65,31.79 221.75,40.7 221.75,42.22 207.64,56.33 207.64,58.03 202.92,62.74 199.86,62.74
  BOTTOM w0.14: v4(189.18,63.1) v1(190.31,63.1)
M_B_A16: length 75.5
  TOP w0.076: CPU1.V47 192.57,64.09 192.7,64.09 192.85,64.03 192.95,64.03 193.1,64.09 193.45,64.09 193.61,63.94 193.99,63.94 v4(194.36,64.3)
  TOP w0.14: v3(238.42,35.65) 238.66,35.65 239.12,36.11 239.63,36.11 239.82,35.92 DIMM2.152
  L4 w0.089: v4(194.36,64.3) 196.26,64.3 198.09,62.47 200.01,62.47
  L4 w0.165: v3(238.42,35.65) 238.42,35.1 238.58,34.94 239.73,34.94 240.3,34.37 240.3,33.59 240.14,33.43 239.39,33.43 239.23,33.26 239.23,32.93 239.39,32.77 240.14,32.77 240.3,32.6 240.3,31.34 239.93,30.97 237.53,30.97 237.16,31.35 236.09,31.35 236.09,31.35 233.59,31.35 230.47,31.35 221.3,40.51 221.3,42.03 207.19,56.15 207.19,57.92 202.64,62.47 200.01,62.47
  BOTTOM w0.14: v3(238.42,35.65) v1(238.88,34.95)
M_B_ACT_N: length 73.6
  TOP w0.076: CPU1.M48 193,67.27 193.15,67.22 193.38,67.22 193.51,67.35 193.99,67.35 194.18,67.35 194.68,67.84 194.68,68.02 197.71,71.05 200.03,71.05 200.78,71.81
  TOP w0.14: v3(239.17,49.18) 239.09,49.18 238.96,49.04 238.96,47.48 239.09,47.34 239.77,47.34 239.85,47.42 DIMM2.114 ; v4(213.4,67.5) 213.4,69.83 208.19,75.04 v1(204.75,75.04) 203.8,75.04 201.23,72.47 201.23,72.43 200.97,72.17 200.97,71.99 200.78,71.81
  L4 w0.165: v3(239.17,49.18) 241.71,49.18 241.96,49.44 241.96,50.38 241.33,51.02 241.33,51.63 241.16,51.79 240.83,51.79 240.67,51.63 240.67,51.2 240.5,51.04 233.04,51.04 216.57,67.5 v4(213.4,67.5)
M_B_ALERT_N: length 68.8
  TOP w0.076: 200.54,72.39 200.54,72.02 199.74,71.22 197.64,71.22 194.51,68.09 194.51,67.91 194.11,67.51 193.92,67.51 193.92,67.51 193.26,67.51 193.26,67.51 CPU1.M49
  TOP w0.14: v4(214.17,66.93) 214.17,69.66 208.15,75.68 203.58,75.68 v1(202.46,74.56) 200.54,72.64 200.54,72.39 ; DIMM2.116 237.7,46.92 237.61,47.02 236.74,47.02 236.57,47.19 236.57,47.56 237.94,48.93 237.94,49.13 v3(237.92,49.15)
  L4 w0.165: v4(214.17,66.93) 214.17,66.85 214.57,66.45 216.34,66.45 218.6,64.19 218.6,64.18 234.11,48.67 237.44,48.67 v3(237.92,49.15)
M_B_BA0: length 71.9
  TOP w0.114: CPU1.T38 187.91,65.7 v4(187.91,65.84)
  TOP w0.14: DIMM2.150 239.91,36.42 239.8,36.53 237.42,36.53 237.28,36.67 237.28,36.94 237.14,37.08 236.83,37.08 236.78,37.03 v3(236.78,37.05)
  L4 w0.089: v4(187.91,65.84) 188.27,65.47 188.97,65.47 189.66,66.17 190.35,66.17 191.15,66.97 191.16,66.97 191.69,66.97 192.4,67.68 192.4,67.68 192.61,67.89 192.61,68.11 193.33,68.83 201.37,68.83 203.81,66.38 203.81,65.72 204.24,65.29 204.24,65.28
  L4 w0.165: 204.24,65.28 211.25,58.28 211.25,57.77 230.38,38.64 230.38,38.41 230.01,38.03 230.01,37.8 230.24,37.56 230.47,37.56 230.85,37.94 231.08,37.94 231.48,37.54 236.29,37.54 v3(236.78,37.05)
  BOTTOM w0.14: v3(236.78,37.05) v1(237.33,36.37)
M_B_BA1: length 76.2
  TOP w0.114: CPU1.T42 189.7,65.66 189.81,65.78 v4(189.81,65.81)
  TOP w0.14: v3(235.22,37.05) 235.22,37.28 234.83,37.67 DIMM2.145
  L4 w0.089: 203.67,65.4 203.67,65.4 203.43,65.64 203.43,66.51 201.29,68.65 193.4,68.65 192.79,68.03 192.79,67.81 192.48,67.5 191.77,66.79 191.23,66.79 190.35,65.92 189.92,65.92 v4(189.81,65.81)
  L4 w0.165: v3(235.22,37.05) 235.71,36.56 237.78,36.56 237.9,36.44 237.9,34.99 237.74,34.82 237.18,34.82 237.02,34.99 237.02,35.92 236.85,36.09 235.2,36.09 234.73,36.56 234.31,36.56 233.77,37.09 229.76,37.09 229.17,37.67 229.17,37.93 229.63,38.38 229.63,38.62 229.4,38.84 229.17,38.84 229.11,38.79 228.88,38.79 228.62,39.04 228.62,39.27 228.75,39.4 228.75,39.63 210.8,57.58 210.8,58.27 203.67,65.4
  BOTTOM w0.14: v1(233.7,37.02) 234.31,36.57 234.75,36.57 v3(235.22,37.05)
M_B_BG0: length 75.9
  TOP w0.076: 201.42,71.87 200.44,70.89 200.18,70.89 200.18,70.89 197.78,70.89 194.84,67.95 194.84,67.78 194.24,67.18 194,67.18 193.63,67.18 193.58,67.18 193.45,67.05 193.12,67.05 192.75,67.18 191.5,67.18 191.28,66.97 CPU1.R45
  TOP w0.14: v4(211.96,67.49) 212.09,67.62 212.09,70.55 208.27,74.37 v1(206.43,74.37) 203.84,74.37 201.42,71.95 201.42,71.87 ; v3(238.41,51.56) 237.9,51.56 237.73,51.39 237.73,49.64 235.26,47.17 DIMM2.115
  L4 w0.165: v3(238.41,51.56) 233.14,51.56 216.74,67.97 209.89,67.97 209.79,67.87 209.79,67.61 209.93,67.47 211.96,67.47 v4(211.96,67.49)
M_B_BG1: length 75.8
  TOP w0.076: 201.84,71.69 200.83,70.69 197.81,70.69 195.01,67.88 195.01,67.71 194.28,66.98 194.28,66.68 193.97,66.37 193.69,66.37 193.43,66.63 193.31,66.63 193.14,66.62 193,66.56 192.83,66.56 192.68,66.62 CPU1.N47
  TOP w0.14: 201.84,71.69 201.84,71.75 203.82,73.74 v1(204.86,73.74) 208.28,73.74 211.51,70.51 211.51,67.3 211.77,67.04 213.17,67.04 213.76,66.44 215.01,66.44 v4(215.57,67) ; DIMM2.113 234.99,47.67 236.58,49.26 v3(236.58,49.24)
  L4 w0.165: v4(215.57,67) 216.45,67 233.67,49.77 234.7,49.77 234.87,49.94 234.87,50.32 235.03,50.48 235.4,50.48 235.56,50.32 235.56,50.01 235.75,49.82 236.12,49.82 236.29,49.99 236.29,50.32 236.45,50.48 240.94,50.48 241.16,50.27 241.16,49.89 240.98,49.71 237.05,49.71 v3(236.58,49.24)
M_B_CKE0: length 71
  TOP w0.076: 202.4,69.63 202.24,69.47 197.77,69.47 195.83,67.54 195.83,67.36 195.25,66.78 195.25,65.69 194.9,65.34 193.09,65.34 192.77,65.22 191.58,65.22 CPU1.U45
  TOP w0.14: DIMM2.109 234.42,48.67 234.84,49.09 234.84,49.78 235.24,50.18 v3(235.24,52.65) ; v4(209.03,68.39) 206.92,70.49 v1(206.08,70.49) 206.07,70.49 203.77,70.49 203.07,69.79 202.55,69.79 202.4,69.63
  L4 w0.165: v4(209.03,68.39) 209.05,68.41 216.92,68.41 233.28,52.05 240.11,52.05 240.27,52.22 240.27,52.57 240.11,52.73 235.32,52.73 v3(235.24,52.65)
M_B_CKE1: length 72.7
  TOP w0.076: CPU1.P43 190.21,65.84 190.88,65.16 190.88,64.86 191.13,64.61 191.94,64.61 192.18,64.55 192.33,64.55 192.5,64.5 192.71,64.5 192.83,64.55 193,64.55 193.15,64.5 193.3,64.5 193.52,64.58 193.61,64.68 195.17,64.68 196,65.5 196,66.6 196.49,67.09 196.49,67.26 197.87,68.65 201.01,68.65 201.53,68.13
  TOP w0.14: DIMM2.110 240.23,48.42 239.88,48.77 239.88,49.19 239.15,49.93 239.15,52.1 239.01,52.24 237.87,52.24 237.73,52.38 237.73,53.1 237.87,53.24 v3(238.4,53.24) ; 201.53,68.13 201.67,67.99 205.71,67.99 205.82,67.89 205.82,67.69 v4(205.72,67.6)
  L4 w0.165: v4(205.72,67.6) 205.72,67.59 204.99,67.59 204.65,67.93 204.65,68.59 204.92,68.86 217.11,68.86 232.45,53.51 232.84,53.51 233.02,53.33 233.02,52.94 233.25,52.71 233.69,52.71 233.85,52.88 233.85,53.15 234.02,53.31 235.12,53.31 235.12,53.31 235.32,53.31 235.46,53.18 235.88,53.18 236.04,53.34 236.04,53.67 236.21,53.84 236.54,53.84 236.7,53.67 236.7,53.41 236.93,53.18 238.34,53.18 v3(238.4,53.24)
  BOTTOM w0.14: v3(238.4,53.24) v1(239.23,53.24)
M_B_CLK0: length 73.9
  TOP w0.076: CPU1.Y47 192.16,63.67 192.5,63.32 192.9,63.32 193.15,63.23 194.51,63.23 194.56,63.29 196.2,63.29 197.8,61.69 199.83,61.69
  TOP w0.102: v3(207.15,64.99) 206.69,64.53 206.69,63.76 206.79,63.66 207.53,63.66 207.97,63.22 207.97,62.14 207.53,61.69 205.58,61.69 ; 205.58,61.69 v1(205.58,61.33) ; 205.58,61.69 199.83,61.69 ; v3(235.91,41.05) 235.24,41.73 234.14,41.73 234.09,41.67 DIMM2.137
  L4 w0.114: v3(207.15,64.99) 207.63,65.46 207.63,66.95 207.38,67.2 206.71,67.2 206.6,67.32 206.6,67.85 206.71,67.97 208.19,67.97 208.47,67.68 208.47,66.92 208.7,66.69 209.28,66.69 209.39,66.57 209.39,66.01 209.28,65.9 208.51,65.9 208.26,65.65 208.26,63.58 212.47,59.38 213.66,59.38 231.76,41.28 233,41.28 233.91,40.37 235.22,40.37 v3(235.91,41.05)
M_B_CLK1: length 68.4
  TOP w0.102: v4(189.26,67.71) 189.56,67.41 CPU1.M42 ; DIMM2.138 241.08,41.41 238.62,41.41 238.24,41.03 v3(238.24,40.27)
  L4 w0.114: v4(189.26,67.71) 189.26,67.73 189.89,68.18 190.74,68.18 191.51,68.95 192.11,68.95 192.94,69.78 202.11,69.78 205.64,66.25 205.64,65.82 212.45,59.01 213.15,59.01 231.51,40.66 232.75,40.66 233.65,39.75 238.31,39.75 238.44,39.87 238.44,40.08 v3(238.24,40.27)
  BOTTOM w0.102: v1(238.06,41.06) v3(238.24,40.27)
M_B_CLK#0: length 73.9
  TOP w0.076: CPU1.Y48 192.59,63.58 192.66,63.5 192.93,63.5 193.18,63.41 194.44,63.41 194.49,63.46 196.28,63.46 197.87,61.87 199.74,61.87 199.75,61.88 199.81,61.88 199.82,61.89 199.83,61.89
  TOP w0.102: 203.74,61.89 v1(203.74,62.26) ; 203.74,61.89 199.83,61.89 ; 203.74,61.89 207.44,61.89 207.77,62.22 207.77,63.14 207.45,63.46 206.71,63.46 206.49,63.67 206.49,64.76 206.14,65.11 206.14,65.43 206.35,65.64 206.5,65.64 v3(206.65,65.49) ; v3(235.2,41.03) 235.29,41.03 235.39,41.13 235.39,41.29 235.15,41.52 234.22,41.52 233.88,41.17 DIMM2.139
  L4 w0.114: v3(206.65,65.49) 206.65,65.56 206.78,65.69 206.95,65.69 207.15,65.49 207.33,65.49 207.4,65.56 207.4,66.86 207.28,66.97 206.62,66.97 206.37,67.22 206.37,67.95 206.62,68.19 208.28,68.19 208.7,67.77 208.7,67.01 208.8,66.92 209.37,66.91 209.62,66.67 209.62,65.92 209.37,65.67 208.61,65.67 208.49,65.56 208.49,63.68 212.56,59.61 213.76,59.61 231.86,41.51 233.1,41.51 234.01,40.6 235.13,40.6 235.3,40.77 235.3,40.92 v3(235.2,41.03)
M_B_CLK#1: length 68.4
  TOP w0.102: DIMM2.140 240.18,40.92 239.9,41.2 238.7,41.2 238.45,40.95 238.45,40.71 238.89,40.27 v3(238.95,40.27) ; CPU1.M43 189.98,67.23 189.84,67.37 189.84,67.65 v4(189.91,67.72)
  L4 w0.114: v4(189.91,67.72) 189.91,67.85 190.02,67.95 190.83,67.95 191.61,68.73 192.21,68.73 193.03,69.55 202.01,69.55 205.41,66.15 205.41,65.72 212.35,58.78 213.05,58.78 231.41,40.43 232.65,40.43 233.56,39.52 238.41,39.52 238.67,39.77 238.67,39.98 v3(238.95,40.27)
  BOTTOM w0.102: v1(239.34,40.99) v3(238.95,40.27)
M_B_CS#0: length 71.5
  TOP w0.14: v4(189.31,64.93) 189.56,64.68 CPU1.V42 ; DIMM2.149 234.19,36.67 234.31,36.56 234.69,36.56 234.91,36.34 235.73,36.34 236.48,35.58 v3(236.48,35.6)
  L4 w0.089: v4(189.31,64.93) 189.41,65.04 189.81,65.04 190.25,65.48 190.41,65.48 191.19,66.25 193.81,66.25 195.85,68.29 201.15,68.29 203.05,66.39 203.05,64.72 203.45,64.31 203.66,64.31
  L4 w0.165: 203.66,64.31 209.86,58.12 209.86,57.26 223.97,43.15 223.97,41.62 229.39,36.2 233.41,36.2 233.75,35.86 233.75,35.34 233.99,35.11 234.86,35.11 235.58,35.11 235.73,34.97 235.73,34.84 235.89,34.68 236.32,34.68 236.48,34.84 v3(236.48,35.6)
  BOTTOM w0.14: v3(236.48,35.6) v1(237.08,35)
M_B_CS#1: length 69.8
  TOP w0.114: v4(187.91,64.95) 188.26,65.3 CPU1.T39
  TOP w0.14: DIMM2.157 233.55,34.67 233.55,34.67 234.56,34.67 v3(235.05,34.17)
  L4 w0.089: 202.96,64.39 202.73,64.62 202.73,65.67 200.29,68.11 196.16,68.11 194.03,65.97 191.16,65.97 190.48,65.29 190.31,65.29 189.58,64.56 188.45,64.56 188.06,64.95 v4(187.91,64.95)
  L4 w0.165: v3(235.05,34.17) 235.05,34.46 234.85,34.66 234.67,34.66 233.75,34.66 232.66,35.76 229.2,35.76 223.53,41.44 223.53,42.96 209.41,57.08 209.41,57.94 203.05,64.3 202.96,64.39
  BOTTOM w0.14: v1(233.53,33.33) 234.06,33.67 234.54,33.67 v3(235.05,34.17)
M_B_DQ0: length 76.6
  TOP w0.076: CPU1.AK48 193,58.46 193.32,58.35 194.25,58.35 194.41,58.51 198.28,58.51 198.83,57.96 198.83,56.39 199.13,56.1 199.39,56.1
  TOP w0.114: v3(231.52,20.45) 231.17,20.8 231.17,22.74 231.6,23.17 DIMM2.203 ; 199.39,56.1 200.09,56.1 200.61,56.62 201.58,56.62 v4(201.75,56.45)
  L4 w0.127: v4(201.75,56.45) 201.91,56.29 201.91,54.21 201.35,53.66 201.35,51.54 201.52,51.38 201.52,51.37 203.31,49.57 203.31,47.85 211.1,40.06 211.1,37.98 210.63,37.51 210.63,37.33 210.81,37.15 210.99,37.15 211.25,37.41 211.43,37.41 211.61,37.23 211.61,37.05 211.29,36.73 211.29,36.55 214.5,33.34 214.74,33.34 215.05,33.65 215.26,33.65 215.5,33.41 215.5,33.24 215.15,32.89 215.15,32.71 215.33,32.53 215.51,32.53 215.86,32.88 216.04,32.88 216.22,32.7 216.22,32.52 215.87,32.17 215.87,31.99 216.05,31.81 216.23,31.81 216.58,32.16 216.76,32.16 216.94,31.98 216.94,31.8 216.59,31.45 216.59,31.27 216.77,31.09 216.95,31.09 217.29,31.44 217.47,31.44 217.65,31.26 217.65,31.08 217.31,30.73 217.31,30.55 217.49,30.37 217.67,30.37 218.01,30.72 218.19,30.72 218.37,30.54 218.37,30.36 218.02,30.01 218.02,29.83 218.2,29.65 218.38,29.65 218.73,30 218.91,30 219.1,29.82 219.1,29.64 218.83,29.37 218.83,29.19 218.95,29.07 219.25,29.07 219.53,29.35 219.71,29.35 228.74,20.32 230.21,20.32 230.41,20.52 231.44,20.52 v3(231.52,20.45)
  BOTTOM w0.114: v1(231.52,21.26) v3(231.52,20.45)
M_B_DQ1: length 76.7
  TOP w0.076: CPU1.AK45 191.8,58.37 192.54,58.37 192.62,58.29 192.98,58.29 193.3,58.18 194.32,58.18 194.48,58.35 198.21,58.35 198.67,57.89 198.67,56.32 199.08,55.91 200.46,55.91 200.56,56.01 v4(201.24,56.01)
  TOP w0.114: DIMM2.207 234.06,22.17 234.45,22.56 235.05,22.56 235.39,22.22 235.39,21.98 236.96,20.41 v3(237.52,20.41)
  L4 w0.127: v4(201.24,56.01) 201.45,55.81 201.45,54.09 201.13,53.77 201.13,51.41 203.08,49.47 203.08,47.58 210.02,40.64 210.02,37.34 218.63,28.73 219.85,28.73 225.12,23.45 225.12,23.32 228.46,19.98 232.44,19.98 232.53,20.07 232.53,20.07 233.38,20.92 237.01,20.92 v3(237.52,20.41)
  BOTTOM w0.114: v3(237.52,20.41) 237.6,20.49 v1(238.33,20.49)
M_B_DQ2: length 75.8
  TOP w0.076: 199.02,56.91 199.02,58.01 198.35,58.68 194.34,58.68 194.18,58.51 193.6,58.51 193.45,58.66 CPU1.AK49
  TOP w0.114: v4(201.73,53.37) v1(201.73,54.6) 201.73,55.49 202.12,55.88 202.12,56.6 201.9,56.82 200.51,56.82 199.98,56.3 199.18,56.3 199.02,56.47 199.02,56.91 ; v3(238.95,21.61) 239.4,22.06 240.16,22.06 240.3,21.92 DIMM2.208
  L4 w0.127: v3(238.95,21.61) 238.95,20.87 239.16,20.65 239.59,20.65 239.72,20.53 239.72,20.02 239.59,19.9 238.52,19.9 238.39,20.02 238.39,20.89 238.26,21.02 237.4,21.02 237.15,21.27 233.24,21.27 232.9,20.92 228.62,20.92 215.55,33.99 214.33,33.99 211.96,36.37 211.96,37.39 211.44,37.91 211.44,40.21 203.7,47.94 203.7,49.48 201.73,51.45 v4(201.73,53.37)
M_B_DQ3: length 75.1
  TOP w0.076: CPU1.AG47 192.22,60.21 192.81,60.21 193.12,60.36 194.27,60.36 194.78,59.85 200.8,59.85 v4(201.66,58.99)
  TOP w0.114: v3(235.05,24.67) 234.54,25.17 DIMM2.195
  L4 w0.127: v4(201.66,58.99) 202.23,58.99 203.59,57.63 203.59,53.13 207.04,49.68 207.04,48.16 219.05,36.16 219.05,35.79 218.29,35.03 218.29,34.86 218.47,34.67 218.64,34.67 219.47,35.5 219.65,35.5 219.83,35.32 219.83,35.14 219.02,34.33 219.02,34.15 219.2,33.97 219.38,33.97 219.49,34.08 219.67,34.08 219.85,33.9 219.85,33.72 219.71,33.57 219.71,33.39 220.72,32.38 220.72,32.38 228.3,24.8 228.9,24.2 229.2,24.2 229.33,24.08 229.33,23.94 229.46,23.82 229.71,23.82 229.84,23.94 229.84,24.56 229.96,24.69 230.22,24.69 230.35,24.56 230.35,23.78 230.47,23.66 230.73,23.66 230.85,23.78 230.85,24.08 230.98,24.2 231.23,24.2 231.36,24.08 231.36,23.78 231.49,23.66 231.74,23.66 231.87,23.78 231.87,24.57 232,24.7 232.25,24.7 232.38,24.57 232.38,24.33 232.5,24.2 232.76,24.2 232.89,24.33 232.89,24.55 233.01,24.68 233.27,24.68 233.39,24.55 233.39,24.33 233.57,24.15 235.06,24.15 235.18,24.28 235.18,24.54 v3(235.05,24.67)
  BOTTOM w0.114: v3(235.05,24.67) v1(235.05,23.85)
M_B_DQ4: length 77.2
  TOP w0.076: 199.27,56.5 199.2,56.57 199.2,58.06 198.42,58.84 194.28,58.84 194.11,58.68 193.67,58.68 193.47,58.87 193.35,58.92 193.17,58.92 193,58.86 192.84,58.86 192.67,58.93 192.56,58.93 192.22,58.81 CPU1.AK47
  TOP w0.114: v4(202.23,53.83) 202.33,53.93 202.33,56.69 201.99,57.03 200.59,57.03 200.59,57.03 200.42,57.03 199.9,56.5 199.27,56.5 ; DIMM2.204 237.73,22.92 v3(236.91,22.11)
  L4 w0.127: v4(202.23,53.83) 202.23,51.42 204.87,48.78 204.87,48.33 204.74,48.2 204.36,48.2 204.23,48.07 204.23,47.82 204.36,47.69 204.74,47.69 204.87,47.57 204.87,47.26 211.78,40.35 211.78,38.05 213.06,36.77 213.06,36.59 212.73,36.26 212.73,36.08 213.01,35.81 213.19,35.81 213.25,35.87 213.43,35.87 213.61,35.69 213.61,35.51 213.54,35.45 213.54,35.27 213.83,34.98 214.01,34.98 214.18,35.15 214.36,35.15 214.54,34.98 214.54,34.8 214.37,34.62 214.37,34.44 214.48,34.34 215.69,34.34 228.76,21.26 232.75,21.26 233.1,21.61 233.44,21.61 233.57,21.74 233.57,21.85 233.7,21.98 233.95,21.98 234.08,21.85 234.08,21.75 234.21,21.62 235.06,21.62 235.19,21.75 235.19,21.84 235.31,21.97 235.57,21.97 235.69,21.84 235.69,21.75 235.82,21.62 236.79,21.62 236.91,21.75 v3(236.91,22.11)
  BOTTOM w0.114: v3(236.91,22.11) 236.91,21.35 236.86,21.3 v1(236.86,21.3)
M_B_DQ5: length 75.5
  TOP w0.076: v4(198.96,58.8) 198.94,58.8 198.94,58.84 198.77,59.01 194.21,59.01 194.04,58.84 193.74,58.84 193.57,59.01 193.38,59.09 193.14,59.09 192.98,59.03 192.87,59.03 192.71,59.09 192.53,59.09 192.36,59.04 192.18,59.04 191.94,58.98 191.44,58.98 191.29,59.14 191.29,59.92 CPU1.AG45
  TOP w0.114: DIMM2.191 234.97,26.17 v3(236.48,24.67)
  L4 w0.127: v4(198.96,58.8) 198.96,59.22 199.19,59.45 202.08,59.45 203.83,57.7 203.83,53.41 207.38,49.85 207.38,48.31 220.44,35.25 220.44,35.07 219.9,34.54 219.9,34.36 220.08,34.18 220.26,34.18 220.8,34.71 220.98,34.71 221.16,34.54 221.16,34.36 220.29,33.49 220.29,33.31 220.47,33.13 220.64,33.13 221.25,33.73 221.43,33.73 221.61,33.55 221.61,33.37 221.07,32.83 221.07,32.52 228.44,25.15 231,25.15 231.01,25.16 231.4,25.16 231.42,25.15 236.43,25.15 236.56,25.02 236.56,24.76 v3(236.48,24.67)
  BOTTOM w0.114: v3(236.48,24.67) v1(236.48,23.86)
M_B_DQ6: length 75
  TOP w0.076: CPU1.AG48 192.68,60.02 192.82,60.02 193.18,60.2 194.18,60.2 194.69,59.68 199.93,59.68 200.05,59.56
  TOP w0.114: DIMM2.194 239.63,25.42 v3(238.95,24.75) ; v4(202.67,57.27) 201.68,58.26 201.68,58.44 200.98,59.13 200.48,59.13 200.05,59.56
  L4 w0.127: v3(238.95,24.75) 238.95,24.63 239.31,24.28 239.88,24.28 240.17,24.57 240.17,25.02 239.96,25.23 237.36,25.23 237.31,25.18 237.28,25.18 236.95,24.84 236.95,24.15 236.61,23.81 232.71,23.81 232.21,23.31 229.31,23.31 217.78,34.84 217.78,35.02 218.65,35.89 218.65,36.07 206.7,48.02 206.7,49.54 203.37,52.86 203.37,57.11 203.21,57.27 v4(202.67,57.27)
  BOTTOM w0.114: v1(239.33,25.5) v3(238.95,24.75)
M_B_DQ7: length 74.3
  TOP w0.076: CPU1.AG49 193.34,60.03 194.11,60.03 194.62,59.52 199.27,59.52 199.51,59.28
  TOP w0.114: DIMM2.190 239.2,26.42 v3(237.53,24.76) ; 199.51,59.28 199.86,58.93 200.9,58.93 201.37,58.46 201.37,58.04 202.97,56.43 v4(202.97,54.65)
  L4 w0.127: v3(237.53,24.76) 237.98,24.31 237.98,24.05 237.82,23.9 237.33,23.9 236.9,23.47 232.86,23.47 232.24,22.85 229.28,22.85 217.32,34.81 217.32,35.08 218.15,35.91 218.15,36.09 217.2,37.03 217.02,37.03 216.46,36.47 216.28,36.47 216.03,36.71 216.03,36.89 216.55,37.41 216.55,37.58 216.28,37.85 216.1,37.85 215.95,37.7 215.77,37.7 215.58,37.88 215.58,38.06 215.79,38.27 215.79,38.45 206.36,47.88 206.36,49.4 203.16,52.59 203.16,54.47 v4(202.97,54.65)
  BOTTOM w0.114: v1(237.93,25.5) v3(237.53,24.76)
M_B_DQ8: length 88.9
  TOP w0.089: v4(187.83,59.43) 187.61,59.21 CPU1.AJ38
  TOP w0.114: v3(236.48,13.82) 236.48,13.92 234.72,15.67 DIMM2.233
  L4 w0.089: 191.51,52.09 191.51,52.46 191.93,52.87 191.93,53.19 191.56,53.55 191.56,54.91 191.86,55.21 191.86,55.66 191.32,56.2 191.32,57.06 190.79,57.6 190.79,58.14 190.47,58.46 189.94,58.46 189.34,59.05 188.58,59.05 188.43,58.9 187.78,58.9 187.57,59.1 187.57,59.32 187.68,59.43 v4(187.83,59.43)
  L4 w0.127: v3(236.48,13.82) 236.9,13.82 237.1,13.62 237.1,13.27 236.97,13.14 236.11,13.14 235.87,12.9 226.58,12.9 221.16,18.32 220.83,18.65 218.03,18.65 217.7,18.98 217.7,19.63 214.27,23.05 213.4,23.05 213.21,23.25 213.21,23.57 213.34,23.69 214.29,23.69 214.41,23.82 214.41,24.08 214.29,24.2 213.34,24.2 213.21,24.33 213.21,26.38 204.76,34.82 204.76,37.66 201.84,40.58 201.84,40.81 201.84,40.82 201.84,41.26 198.03,45.07 195.31,45.07 194.53,45.84 193.6,45.84 191.95,47.49 191.95,50.62 191.51,51.06 191.51,52.09
  BOTTOM w0.114: v3(236.48,13.82) 236.21,13.55 v1(236.21,12.99)
M_B_DQ9: length 89.2
  TOP w0.114: v4(188.45,57.63) 188.45,57.63 188.45,57.63 188.26,57.82 CPU1.AL39 ; DIMM2.246 240.06,12.42 239.82,12.18 238.75,12.18 v3(237.37,10.8)
  L4 w0.127: v3(237.37,10.8) 237.59,10.57 237.59,10.11 237.46,9.98 226.42,9.98 221.34,15.07 218.39,15.07 215.53,17.93 215.53,18.72 213.37,20.88 212.15,20.88 211.04,22 211.04,25.37 205.86,30.54 205.86,30.55 202.59,33.82 202.59,36.58 198.88,40.29 198.41,40.29 196.85,41.85 194.61,41.85 191.32,45.14 191.32,45.68 190.75,46.25 188.35,46.25 187.01,47.6 187.01,57.33 187.79,58.12 188.32,58.12 188.45,57.99 v4(188.45,57.63)
  BOTTOM w0.114: v3(237.37,10.8) v1(237.18,9.81)
M_B_DQ10: length 88.1
  TOP w0.089: CPU1.AJ39 188.24,59.06 188.44,59.41 v4(188.46,59.43)
  TOP w0.114: DIMM2.237 234.18,14.67 v3(235.05,13.81)
  L4 w0.089: 191.85,51.88 191.85,52.52 192.1,52.77 192.1,53.26 191.76,53.61 191.76,54.85 192.04,55.14 192.04,55.73 191.54,56.23 191.54,57.15 191,57.69 191,58.54 190.48,59.06 189.62,59.06 189.28,59.4 189.28,59.79 189.11,59.95 188.58,59.95 188.46,59.83 v4(188.46,59.43)
  L4 w0.127: v3(235.05,13.81) 235.16,13.81 235.29,13.68 235.29,13.37 235.16,13.24 226.81,13.24 221.04,19.01 220.06,19.01 219.93,19.14 219.93,19.76 219.81,19.88 219.55,19.88 219.43,19.76 219.43,19.12 219.31,19 218.97,19 218.85,19.12 218.85,19.62 218.73,19.75 218.09,19.75 217.67,20.16 217.67,20.34 217.9,20.57 217.9,20.72 217.7,20.91 217.52,20.91 217.3,20.69 217.12,20.69 216.94,20.87 216.94,21.05 217.17,21.27 217.17,21.45 216.99,21.63 216.81,21.63 216.58,21.41 216.4,21.41 216.22,21.59 216.22,21.77 216.45,21.99 216.45,22.17 216.27,22.35 216.09,22.35 215.86,22.13 215.68,22.13 215.51,22.31 215.51,22.49 215.73,22.71 215.73,22.89 215.55,23.07 215.37,23.07 215.15,22.85 214.97,22.85 214.78,23.04 214.78,24.34 214.57,24.55 213.71,24.55 213.58,24.67 213.58,24.99 213.71,25.12 214.29,25.12 214.41,25.25 214.41,25.55 214.26,25.7 213.71,25.7 213.58,25.83 213.58,26.49 205.1,34.97 205.1,37.8 202.36,40.54 202.36,41.34 201.33,42.37 201.33,42.55 198.5,45.38 196.35,45.38 195.67,46.06 193.69,46.06 192.17,47.58 192.17,50.72 191.85,51.03 191.85,51.88
  BOTTOM w0.114: v3(235.05,13.81) 234.91,13.67 v1(234.91,13)
M_B_DQ11: length 89
  TOP w0.089: v4(189.93,57.59) 189.95,57.59 189.95,57.59 190.21,57.85 CPU1.AL43
  TOP w0.114: v3(235.16,10.8) 235.16,11.14 234.63,11.67 DIMM2.249
  L4 w0.127: v4(189.93,57.59) 189.93,57.23 189.82,57.11 189.15,57.11 188.88,56.84 188.88,56.32 188.75,56.2 187.79,56.2 187.44,55.84 187.44,48.29 187.74,47.99 190.3,47.99 192.99,45.3 192.99,44.08 194.79,42.28 196.63,42.28 197.34,42.28 198.82,40.81 199.51,40.81 203.28,37.04 203.28,34.1 206.55,30.83 206.55,30.83 211.72,25.65 211.72,22.28 212.44,21.57 213.66,21.57 216.22,19.01 216.22,18.21 217.29,17.14 218.01,17.14 218.14,17.01 218.14,16.42 218.27,16.3 218.52,16.3 218.65,16.42 218.65,16.97 218.77,17.1 219.03,17.1 219.16,16.97 219.16,15.88 219.28,15.76 219.54,15.76 219.66,15.88 219.66,16.92 219.79,17.04 220.08,17.04 220.2,16.92 220.2,15.96 220.3,15.87 221.51,15.87 226.71,10.67 230.43,10.67 230.63,10.87 230.63,11.14 230.8,11.32 234.64,11.32 v3(235.16,10.8)
  BOTTOM w0.114: v1(234.66,9.71) v3(235.16,10.8)
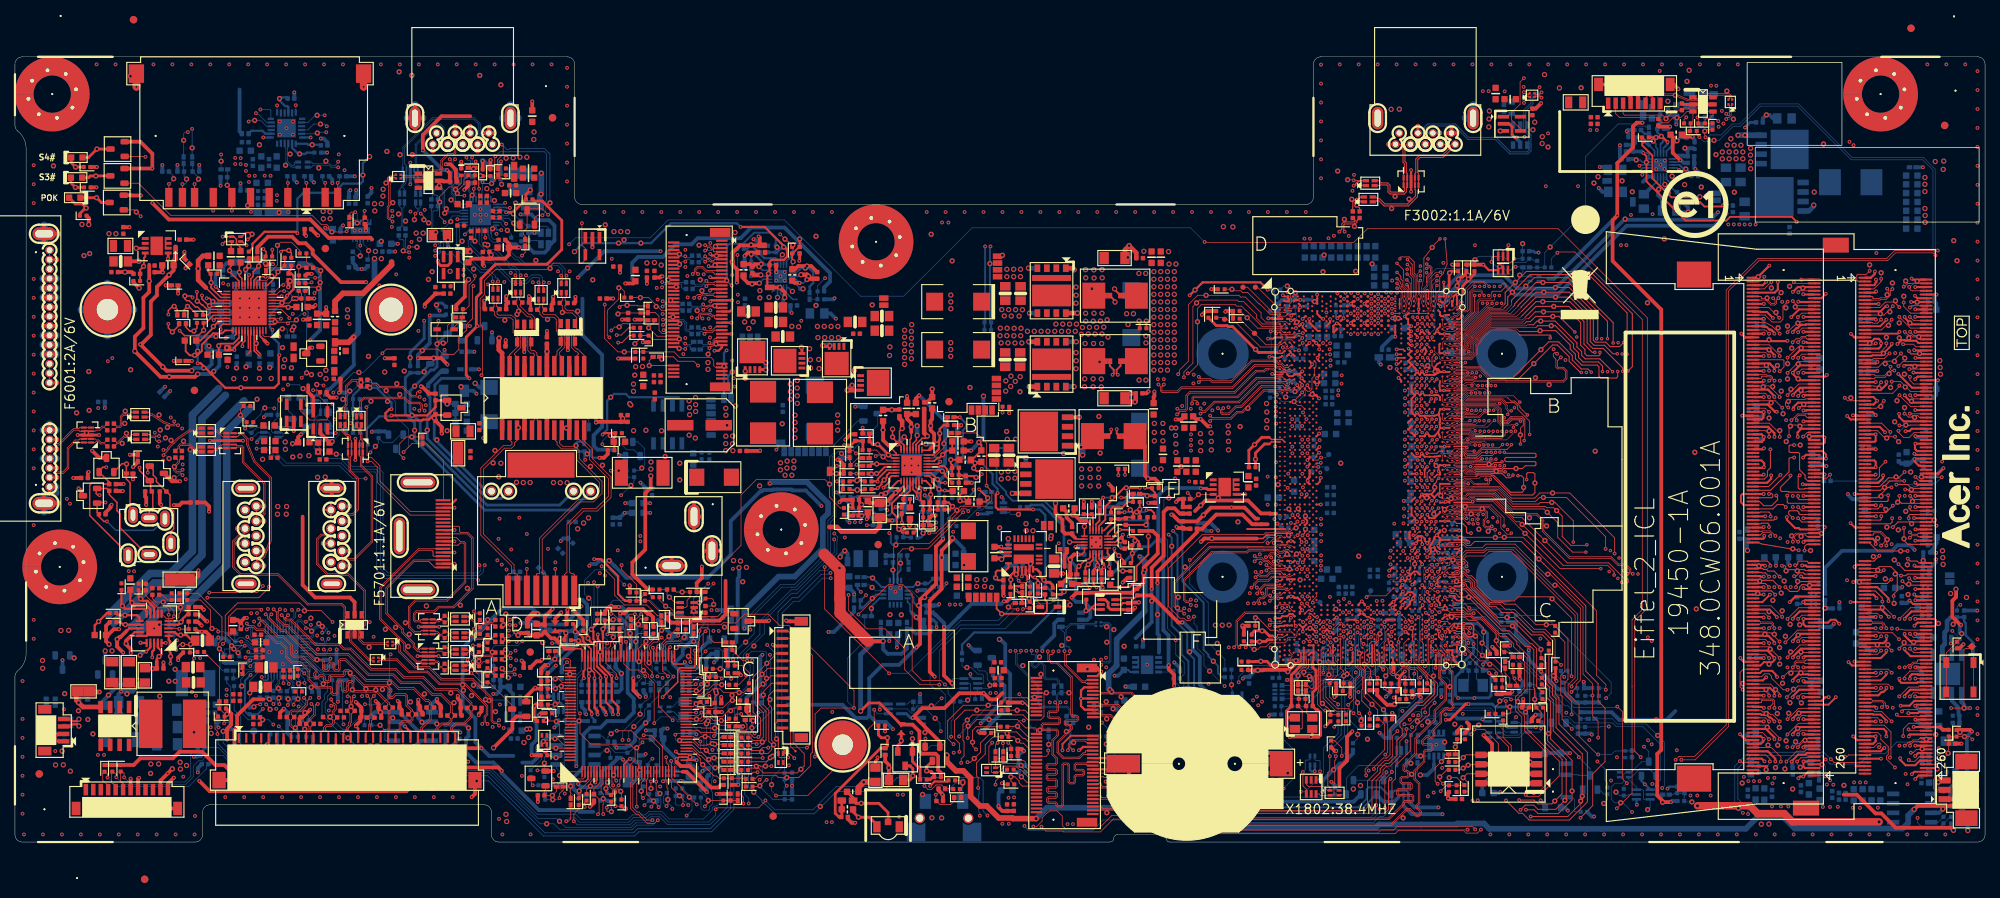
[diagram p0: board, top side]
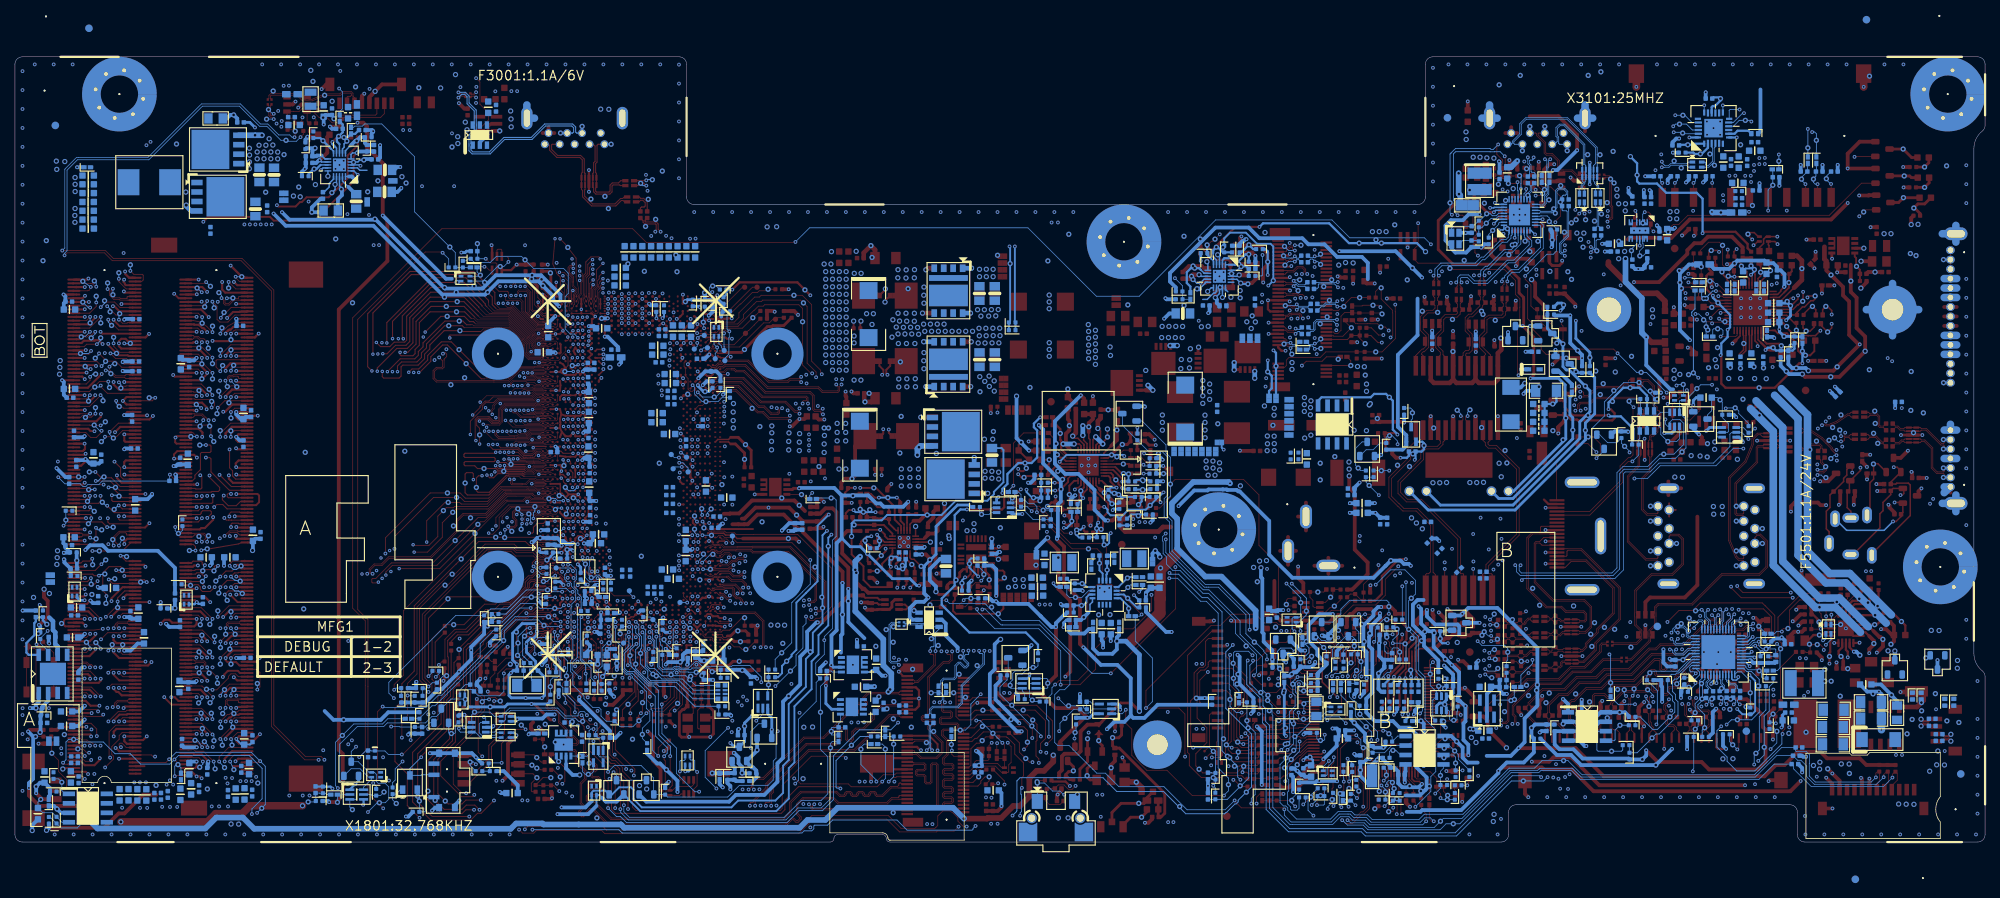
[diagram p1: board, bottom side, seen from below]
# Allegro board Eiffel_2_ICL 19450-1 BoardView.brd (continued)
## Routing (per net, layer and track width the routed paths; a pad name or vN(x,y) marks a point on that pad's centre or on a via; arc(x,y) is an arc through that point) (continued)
M_B_DQ12: length 88.6
  TOP w0.089: CPU1.AL38 187.61,58.27 v4(187.86,58.52)
  TOP w0.114: v3(238.82,10.8) 239.33,11.31 240.12,11.31 240.23,11.42 DIMM2.250
  L4 w0.127: v4(187.86,58.52) 186.79,57.45 186.79,46.27 187.84,45.22 190.85,45.22 194.23,41.84 194.23,41.62 194.85,41 197.21,41 198.27,39.95 198.74,39.95 202.25,36.44 202.25,33.38 210.64,24.99 210.64,21.91 212.78,19.77 213.78,19.77 215.19,18.36 215.19,17.78 218.24,14.73 221.19,14.73 226.28,9.64 237.89,9.64 238.82,10.57 v3(238.82,10.8)
  BOTTOM w0.114: v1(239.24,10.03) 238.82,10.46 v3(238.82,10.8)
M_B_DQ13: length 87.9
  TOP w0.114: DIMM2.232 238.99,15.92 237.52,14.46 v3(237.52,14.43) ; v4(189.8,59.44) 189.56,59.21 CPU1.AJ42
  L4 w0.089: v4(189.8,59.44) 189.8,59.73 189.87,59.81 190.57,59.81 192,58.37 192,56.28 192.4,55.88 192.4,54.99 192.18,54.77 192.18,53.69 192.46,53.41 192.46,52.6 192.31,52.45 192.31,51.9 192.3,51.9
  L4 w0.127: v3(237.52,14.43) 237.31,14.64 233.41,14.64 232.73,13.97 227.05,13.97 219.62,21.4 219.35,21.4 218.99,21.04 218.84,21.04 218.63,21.25 218.63,21.4 218.99,21.76 218.99,21.94 218.82,22.12 218.64,22.12 218.25,21.73 218.06,21.73 217.89,21.9 217.89,22.09 218.28,22.48 218.28,22.66 218.1,22.84 217.92,22.84 217.51,22.43 217.34,22.43 217.15,22.62 217.15,22.79 217.56,23.2 217.56,23.38 217.38,23.56 217.2,23.56 216.77,23.13 216.62,23.13 216.41,23.33 216.41,23.49 216.84,23.92 216.84,24.1 216.66,24.28 216.48,24.28 216.03,23.83 215.85,23.83 215.67,24.01 215.67,24.19 216.12,24.63 216.12,24.81 214.95,25.98 214.95,26.1 205.79,35.26 205.79,38.08 203.32,40.55 203.32,41.35 201.12,43.56 201.12,43.56 201.12,43.87 198.74,46.25 196.55,46.25 196.1,46.7 194.54,46.7 192.6,48.64 192.6,50.9 192.3,51.19 192.3,51.9
  BOTTOM w0.114: v3(237.52,14.43) 237.33,14.23 v1(237.33,13.59)
M_B_DQ14: length 87.8
  TOP w0.114: CPU1.AL42 189.56,58.04 189.14,57.62 v4(189.14,57.62) ; v3(236.64,10.8) 236.64,11.4 235.36,12.67 DIMM2.245
  L4 w0.127: v3(236.64,10.8) 236.17,10.33 226.57,10.33 221.48,15.41 218.53,15.41 215.87,18.07 215.87,18.87 213.52,21.23 212.3,21.23 211.38,22.14 211.38,25.51 206.2,30.69 206.2,30.69 202.93,33.96 202.93,36.9 199.26,40.57 198.61,40.57 197.12,42.06 196.9,42.06 194.7,42.06 192.77,43.99 192.77,45.21 190.95,47.03 187.88,47.03 187.22,47.69 187.22,56.6 187.74,57.11 188.63,57.11 v4(189.14,57.62)
  BOTTOM w0.114: v1(235.91,9.98) v3(236.64,10.8)
M_B_DQ15: length 87.5
  TOP w0.114: CPU1.AJ43 190.21,59.22 v4(190.42,59.44) ; DIMM2.236 240.01,14.92 239.94,14.99 239.41,14.99 238.95,14.53 v3(238.95,14.43)
  L4 w0.089: v4(190.42,59.44) 190.95,58.91 191.09,58.91 191.82,58.18 191.82,56.21 192.22,55.81 192.22,55.06 192,54.85 192,53.62 192.28,53.34 192.28,52.68 192.07,52.47 192.07,51.9
  L4 w0.127: v3(238.95,14.43) 238.95,14.98 239.1,15.13 240.9,15.13 241.22,14.81 241.22,14.01 240.92,13.71 237.56,13.71 236.96,14.3 234.04,14.3 233.33,13.59 226.95,13.59 220.01,20.52 218.63,20.52 215.12,24.03 215.12,25.33 214.61,25.84 214.61,25.96 205.45,35.12 205.45,37.94 202.83,40.56 202.83,41.36 200.9,43.29 200.9,43.71 198.93,45.68 196.61,45.68 196.01,46.27 193.78,46.27 192.38,47.67 192.38,50.81 192.07,51.12 192.07,51.9
  BOTTOM w0.114: v1(238.89,15.24) 238.89,14.49 v3(238.95,14.43)
M_B_DQ16: length 72
  TOP w0.076: v4(195.73,62.29) 195.66,62.22 195.58,62.22 195.55,62.25 195.41,62.25 195.39,62.23 194.4,62.23 194.14,62.49 193.3,62.49 CPU1.AB49
  TOP w0.114: DIMM2.173 234.47,30.67 v3(235.05,30.09)
  L4 w0.127: v4(195.73,62.29) 196,62.02 202.33,62.02 206.41,57.94 206.41,55.84 217.62,44.63 217.62,44.45 217.06,43.89 217.06,43.71 217.24,43.53 217.42,43.53 217.98,44.09 218.16,44.09 218.34,43.91 218.34,43.73 217.78,43.17 217.78,42.99 217.96,42.81 218.14,42.81 218.7,43.37 218.88,43.37 219.06,43.19 219.06,43.01 218.5,42.45 218.5,42.27 218.68,42.09 218.86,42.09 219.42,42.65 219.6,42.65 219.78,42.47 219.78,42.29 219.22,41.73 219.22,41.55 219.4,41.37 219.58,41.37 220.14,41.93 220.32,41.93 220.53,41.72 220.53,41.51 219.97,40.95 219.97,40.77 221.34,39.39 230.15,30.58 230.94,30.58 231.07,30.45 231.07,30.25 231.19,30.12 231.45,30.12 231.57,30.25 231.57,30.45 231.7,30.58 231.95,30.58 232.08,30.45 232.08,30.1 232.21,29.97 232.46,29.97 232.59,30.1 232.59,30.45 232.72,30.58 232.97,30.58 233.1,30.45 233.1,30.1 233.22,29.97 233.48,29.97 233.61,30.1 233.61,30.45 233.73,30.58 235.48,30.58 235.61,30.45 235.61,30.22 235.48,30.09 v3(235.05,30.09)
  BOTTOM w0.114: v3(235.05,30.09) v1(235.05,30.9)
M_B_DQ17: length 72
  TOP w0.076: CPU1.AB48 192.86,62.56 193.12,62.67 194.19,62.67 194.47,62.39 195.32,62.39 v4(195.86,62.93)
  TOP w0.114: DIMM2.174 239.45,30.42 v3(238.95,29.93)
  L4 w0.127: v4(195.86,62.93) 197.35,62.93 198.04,62.24 202.42,62.24 206.76,57.9 206.76,55.98 220.87,41.86 220.87,40.34 221.68,39.53 230.29,30.92 236.98,30.92 237.36,30.55 241.44,30.55 241.53,30.46 241.53,29.53 241.4,29.4 239.07,29.4 238.95,29.53 v3(238.95,29.93)
  BOTTOM w0.114: v3(238.95,29.93) v1(239.16,29.14)
M_B_DQ18: length 73.2
  TOP w0.076: v4(197.6,60.24) 197.61,60.24 197.61,60.26 197.56,60.26 197.56,60.25 196.96,60.85 195.73,60.85 195.68,60.9 194.71,60.9 194.59,61.02 194.31,61.02 194.31,61.02 193.38,61.02 CPU1.AE49
  TOP w0.114: DIMM2.187 234.55,27.17 v3(235.05,26.67)
  L4 w0.127: v3(235.05,26.67) 235.05,27.03 234.93,27.16 233.82,27.16 233.27,27.71 229.92,27.71 229.89,27.74 229.02,28.61 228.7,28.61 228.26,28.17 227.71,28.17 223.05,32.82 223.05,34.58 212.4,45.23 212.4,45.47 212.8,45.87 212.8,46.05 212.62,46.23 212.44,46.23 212.01,45.8 211.83,45.8 211.65,45.98 211.65,46.16 212.24,46.75 212.24,46.93 212.06,47.11 211.88,47.11 211.29,46.52 211.11,46.52 210.93,46.7 210.93,46.88 211.52,47.47 211.52,47.65 211.34,47.83 211.16,47.83 210.61,47.28 210.43,47.28 210.25,47.45 210.25,47.63 210.8,48.19 210.8,48.37 210.63,48.55 210.45,48.55 209.85,47.96 209.67,47.96 209.5,48.14 209.5,48.32 210.09,48.91 210.09,49.09 209.88,49.3 209.7,49.3 209.14,48.73 208.96,48.73 208.77,48.92 208.77,49.1 209.33,49.67 209.33,49.85 204.69,54.49 204.69,58.05 202.44,60.31 197.67,60.31 v4(197.6,60.24)
  BOTTOM w0.114: v3(235.05,26.67) v1(235.21,25.87)
M_B_DQ19: length 73.9
  TOP w0.076: CPU1.AE47 192.22,61.31 192.56,61.43 192.67,61.43 192.84,61.36 193,61.36 193.17,61.42 193.35,61.42 193.38,61.41 193.61,61.19 194.25,61.19 194.42,61.19 194.56,61.33 195.19,61.33 v4(195.25,61.27)
  TOP w0.114: DIMM2.186 239.45,27.42 v3(238.95,26.93)
  L4 w0.127: v3(238.95,26.93) 239.44,26.43 239.44,25.74 239.32,25.62 237.26,25.62 237.16,25.52 237.14,25.52 237.13,25.5 228.78,25.5 228.77,25.51 228.74,25.51 222.02,32.23 222.02,34.15 207.73,48.45 207.73,50 204.05,53.68 204.05,57.79 202.17,59.66 198.86,59.66 198.2,59 198.06,58.86 195.79,58.86 194.73,59.92 194.73,60.75 v4(195.25,61.27)
  BOTTOM w0.114: v1(238.95,27.74) v3(238.95,26.93)
M_B_DQ20: length 74.3
  TOP w0.076: v4(196.32,60.21) 195.85,60.69 195.66,60.69 195.61,60.74 194.64,60.74 194.52,60.86 194.38,60.86 193.34,60.86 192.96,60.97 192.77,61.16 CPU1.AE48
  TOP w0.114: v3(237.24,26.78) 238.89,28.42 DIMM2.182
  L4 w0.127: v3(237.24,26.78) 236.67,26.2 233.76,26.2 233.63,26.33 233.63,26.75 233.5,26.87 233.25,26.87 233.12,26.75 233.12,26.33 232.99,26.2 232.74,26.2 232.61,26.33 232.61,26.75 232.49,26.87 232.23,26.87 232.11,26.75 232.11,26.45 231.98,26.33 231.72,26.33 231.6,26.45 231.6,26.75 231.47,26.87 231.22,26.87 231.09,26.75 231.09,26.5 230.96,26.37 230.71,26.37 230.58,26.5 230.58,26.75 230.45,26.87 230.18,26.87 229.94,26.63 229.68,26.63 229.55,26.76 229.55,27.54 229.42,27.67 229.17,27.67 229.04,27.54 229.04,26.85 228.91,26.73 228.66,26.73 228.53,26.85 228.53,27.57 228.28,27.82 227.56,27.82 222.71,32.68 222.71,34.44 208.41,48.73 208.41,50.28 204.48,54.22 204.48,57.96 202.35,60.09 198.68,60.09 198.29,59.7 196.75,59.7 196.32,60.12 v4(196.32,60.21)
  BOTTOM w0.114: v1(237.24,27.59) v3(237.24,26.78)
M_B_DQ21: length 72.8
  TOP w0.076: v4(195.28,62.93) 194.9,62.56 194.54,62.56 194.25,62.84 193.1,62.84 192.9,62.77 192.5,62.77 CPU1.AB47
  TOP w0.102: DIMM2.169 235.33,31.67 v3(236.81,30.19)
  L4 w0.127: v4(195.28,62.93) 195.28,61.97 195.45,61.81 202.24,61.81 206.07,57.98 206.07,55.7 214.92,46.85 214.92,46.64 214.69,46.41 214.69,46.23 214.87,46.05 215.05,46.05 215.28,46.28 215.46,46.28 215.64,46.1 215.64,45.92 215.07,45.35 215.07,45.17 215.25,44.99 215.43,44.99 216,45.56 216.18,45.56 216.36,45.38 216.36,45.2 215.79,44.63 215.79,44.45 215.97,44.27 216.15,44.27 216.72,44.84 216.9,44.84 217.08,44.66 217.08,44.48 216.51,43.92 216.51,43.74 221,39.25 230.62,29.62 236.82,29.62 236.94,29.75 236.94,30.06 v3(236.81,30.19)
  BOTTOM w0.114: v3(236.81,30.19) v1(236.81,31.01)
M_B_DQ22: length 72.7
  TOP w0.076: CPU1.AB45 191.29,62.42 191.29,61.68 191.48,61.49 191.94,61.49 192.18,61.54 192.36,61.54 192.53,61.6 192.71,61.6 192.87,61.53 192.98,61.53 193.14,61.59 193.38,61.59 193.48,61.55 193.68,61.35 194.14,61.35 194.44,61.66 195.38,61.66 195.83,61.21 v4(196.06,61.21)
  TOP w0.114: v3(237.52,29.93) 239.02,31.42 DIMM2.170
  L4 w0.127: v4(196.06,61.21) 196.44,61.59 202.15,61.59 205.73,58.01 205.73,55.56 214.33,46.95 214.33,45.43 220.65,39.11 223.56,36.2 223.56,36.2 230.48,29.28 237.29,29.28 238.08,28.5 238.99,28.5 239.12,28.62 239.12,28.97 239.03,29.06 238.39,29.06 v3(237.52,29.93)
  BOTTOM w0.114: v3(237.52,29.93) v1(237.88,29.19)
M_B_DQ23: length 73.8
  TOP w0.076: v4(195.74,60.21) 195.38,60.57 194.57,60.57 194.45,60.69 193.3,60.69 192.76,60.86 191.79,60.86 191.48,61.16 CPU1.AE45
  TOP w0.114: v3(236.46,26.89) 235.44,27.92 235.44,27.94 235.32,28.06 234.8,28.06 234.68,28.17 DIMM2.183
  L4 w0.127: v4(195.74,60.21) 195.74,60.03 196.69,59.08 197.97,59.08 198.11,59.22 198.77,59.88 202.26,59.88 204.26,57.87 204.26,53.95 208.07,50.14 208.07,48.59 222.37,34.29 222.37,32.37 228.88,25.86 234.72,25.86 234.73,25.86 237.02,25.86 237.71,26.56 237.71,27.16 237.4,27.48 236.67,27.48 236.46,27.27 v3(236.46,26.89)
  BOTTOM w0.114: v3(236.46,26.89) v1(236.46,26.08)
M_B_DQ24: length 81.5
  TOP w0.089: v4(187.89,62.19) 187.89,62.16 187.63,61.74 CPU1.AD38
  TOP w0.114: DIMM2.212 238.93,20.92 v3(237.44,19.43)
  L4 w0.089: 195.17,51.97 195.17,53.43 195.3,53.57 195.3,54.29 194.77,54.82 194.77,56.22 194.62,56.38 194.62,57 194.25,57.37 194.25,58.79 194.43,58.97 194.43,60.42 192.13,62.73 188.09,62.73 187.89,62.53 v4(187.89,62.19)
  L4 w0.127: v3(237.44,19.43) 237.44,19.82 236.68,20.58 233.52,20.58 232.55,19.61 228.35,19.61 224.78,23.18 224.78,23.31 219.71,28.38 218.49,28.38 209.68,37.19 209.68,40.5 201.7,48.48 199.99,48.48 198.58,49.89 197.24,49.89 195.17,51.97
  BOTTOM w0.114: v3(237.44,19.43) 237.44,19.09 v1(237.85,18.68)
M_B_DQ25: length 82
  TOP w0.089: v4(188.52,62.19) CPU1.AD39
  TOP w0.114: v3(238.93,19.42) 239.44,19.92 DIMM2.216
  L4 w0.089: 195.06,54.24 194.59,54.7 194.59,56.15 194.44,56.3 194.44,56.92 193.82,57.55 193.82,58.61 194.26,59.05 194.26,60.34 192.05,62.55 188.61,62.55 188.52,62.46 v4(188.52,62.19)
  L4 w0.127: 195.06,54.24 195.11,54.19 195.11,53.65 194.97,53.51 194.97,52.07 194.95,52.05 194.95,51.88 197.18,49.65 198.44,49.65 199.83,48.26 201.47,48.26 203.53,46.2 203.53,46.16 209.33,40.36 209.33,37.05 218.35,28.04 219.56,28.04 224.44,23.17 224.44,22.96 228.13,19.27 233.66,19.27 233.84,19.45 233.84,20.04 234.03,20.24 236.53,20.24 236.95,19.82 236.95,19.24 237.26,18.94 238.99,18.94 239.12,19.06 239.12,19.29 238.99,19.42 v3(238.93,19.42)
  BOTTOM w0.114: v3(238.93,19.42) 238.93,19.12 v1(239.39,18.66)
M_B_DQ26: length 81.9
  TOP w0.089: v4(188.52,61.27) CPU1.AE39
  TOP w0.114: v3(237.53,16.48) 237.54,16.48 238.99,17.92 DIMM2.224
  L4 w0.089: 193.7,50.41 193.7,50.89 193.07,51.51 193.07,52.18 193.17,52.28 193.17,53.7 193,53.88 193,54.59 193.11,54.7 193.11,56.18 192.71,56.57 192.71,59.49 192,60.21 191.35,60.21 191.13,60.42 191.13,60.63 190.81,60.96 189.39,60.96 189.33,60.9 188.64,60.9 188.52,61.02 v4(188.52,61.27)
  L4 w0.127: v3(237.53,16.48) 237.36,16.64 236.79,16.64 236.66,16.77 236.66,17.29 236.54,17.42 236.29,17.42 236.16,17.28 236.16,16.79 236.03,16.66 226.3,16.66 216.34,26.62 216.34,26.84 207.16,36.02 207.16,38.65 205.23,40.59 205.23,41.39 199.74,46.87 199.42,46.87 198.76,47.53 196.73,47.53 196.54,47.72 196.05,47.72 193.7,50.07 193.7,50.41
  BOTTOM w0.114: v1(237.69,17.27) 237.53,17.12 v3(237.53,16.48)
M_B_DQ27: length 84
  TOP w0.089: v4(190.47,60.4) 190.47,60.51 190.21,60.77 CPU1.AE43
  TOP w0.114: DIMM2.225 233.97,17.67 234.19,17.45 234.91,17.45 235.25,17.11 235.54,17.11 v3(236.48,16.17)
  L4 w0.089: 193.08,50.53 193.08,51 192.72,51.36 192.72,52.33 192.82,52.42 192.82,53.56 192.64,53.73 192.64,54.73 192.75,54.84 192.75,56.03 192.35,56.43 192.35,59.35 191.89,59.81 191.08,59.81 190.5,60.4 v4(190.47,60.4)
  L4 w0.127: 193.08,50.53 193.08,49.13 194.92,47.29 196.36,47.29 196.79,46.86 198.82,46.86 201.5,44.17 201.5,44.14 204.25,41.4 204.25,40.59 206.48,38.37 206.48,35.74 215.66,26.55 215.66,26.33 226.01,15.98 227.15,15.98 227.31,15.82 227.31,14.82 227.43,14.7 227.78,14.7 227.9,14.82 227.9,15.32 228.03,15.45 228.36,15.45 228.49,15.32 228.49,14.81 228.62,14.69 228.97,14.69 229.1,14.81 229.1,15.35 229.22,15.48 229.55,15.48 229.67,15.36 229.67,15.36 229.68,15.35 229.68,14.81 229.81,14.69 230.09,14.69 230.22,14.81 230.22,15.23 230.35,15.36 236.98,15.36 237.18,15.56 237.18,16 237,16.17 v3(236.48,16.17)
  BOTTOM w0.114: v3(236.48,16.17) v1(236.43,15.36)
M_B_DQ28: length 82.6
  TOP w0.089: v4(187.87,61.27) CPU1.AE38
  TOP w0.114: DIMM2.228 239.95,16.92 239.91,16.97 239.44,16.97 v3(238.95,16.48)
  L4 w0.089: 192.52,51.88 192.52,52.38 192.64,52.5 192.64,53.48 192.47,53.65 192.47,54.81 192.57,54.92 192.57,55.95 192.17,56.35 192.17,58.47 190.61,60.03 190.08,60.03 190.03,59.98 189.71,59.98 189.56,60.06 188.86,60.59 188.63,60.72 188.51,60.72 188.29,60.88 v4(187.87,61.27)
  L4 w0.127: v3(238.95,16.48) 237.36,15.02 230.91,15.02 230.21,14.31 227.19,14.31 215.32,26.19 215.32,26.41 206.13,35.59 206.13,38.23 203.79,40.57 203.79,41.37 201.33,43.83 201.33,44.01 198.71,46.63 196.71,46.63 196.27,47.07 194.79,47.07 192.82,49.05 192.82,50.99 192.52,51.28 192.52,51.88
  BOTTOM w0.114: v3(238.95,16.48) 238.95,17.18 v1(239.05,17.28)
M_B_DQ29: length 82.7
  TOP w0.114: v4(190.54,62.09) 190.54,62.07 CPU1.AD43 ; DIMM2.215 233.91,20.17 233.94,20.2 234.61,20.2 235.06,19.75 v3(235.06,19.63)
  L4 w0.089: 194.17,52.72 194.17,53.83 194.33,53.98 194.33,54.76 194.25,54.84 194.25,56.86 193.43,57.68 193.43,60.3 191.36,62.37 190.64,62.37 190.54,62.27 v4(190.54,62.09)
  L4 w0.127: 194.17,52.72 194.17,52.35 197.09,49.44 198.34,49.44 199.73,48.05 201.16,48.05 207.17,42.03 207.17,41.23 208.99,39.41 208.99,36.81 218.17,27.63 218.17,27.43 219.28,26.33 219.46,26.33 220.02,26.89 220.2,26.89 220.37,26.71 220.37,26.53 219.8,25.96 219.8,25.78 219.98,25.6 220.16,25.6 220.75,26.19 220.93,26.19 221.11,26.01 221.11,25.83 220.53,25.25 220.53,25.07 220.71,24.89 220.89,24.89 221.47,25.47 221.65,25.47 221.83,25.29 221.83,25.11 221.25,24.53 221.25,24.35 221.43,24.17 221.61,24.17 222.21,24.77 222.35,24.77 222.57,24.55 222.57,24.41 221.96,23.8 221.96,23.62 222.14,23.44 222.32,23.44 222.75,23.87 222.93,23.87 223.15,23.65 223.15,23.47 222.84,23.16 222.84,22.96 223.05,22.74 223.23,22.74 223.61,23.12 223.79,23.12 227.99,18.92 234.93,18.92 235.06,19.05 v3(235.06,19.63)
  BOTTOM w0.114: v1(234.65,20.45) 235.06,20.04 v3(235.06,19.63)
M_B_DQ30: length 82.2
  TOP w0.114: v4(189.9,62.16) 189.9,62.08 CPU1.AD42 ; v3(236.48,19.62) 236.48,19.95 235.25,21.17 DIMM2.211
  L4 w0.089: 194.48,51.74 193.85,52.37 193.85,53.75 194.13,54.03 194.13,54.43 194.13,54.44 194.13,54.71 193.85,54.99 193.85,56.2 193.48,56.57 193.48,57.38 193.25,57.61 193.25,59.96 191.54,61.67 189.96,61.67 189.85,61.78 189.85,62.11 v4(189.9,62.16)
  L4 w0.127: v3(236.48,19.62) 236.48,18.77 236.29,18.58 233.92,18.58 233.79,18.45 233.79,18.29 233.66,18.16 233.41,18.16 233.28,18.29 233.28,18.45 233.15,18.58 232.9,18.58 232.77,18.45 232.77,18.29 232.65,18.16 232.39,18.16 232.27,18.29 232.27,18.45 232.14,18.58 231.88,18.58 231.76,18.45 231.76,18.29 231.63,18.16 231.38,18.16 231.25,18.29 231.25,18.45 231.12,18.58 230.87,18.58 230.74,18.45 230.74,18.29 230.61,18.16 230.36,18.16 230.23,18.29 230.23,18.45 230.11,18.58 229.85,18.58 229.73,18.45 229.73,18.29 229.6,18.16 229.34,18.16 229.22,18.29 229.22,18.45 229.09,18.58 228.84,18.58 228.71,18.45 228.71,18.29 228.58,18.16 228.33,18.16 228.2,18.29 228.2,18.45 228.07,18.58 227.84,18.58 223.94,22.49 223.68,22.49 223.3,22.11 222.96,22.11 217.83,27.23 217.83,27.49 208.65,36.67 208.65,39.27 206.74,41.18 206.74,41.46 206.74,41.46 206.74,41.98 200.89,47.83 199.6,47.83 198.21,49.22 196.37,49.22 195.51,50.08 195.51,50.71 194.48,51.74
  BOTTOM w0.114: v1(235.92,20.44) v3(236.48,19.62)
M_B_DQ31: length 81.3
  TOP w0.089: CPU1.AE42 189.88,60.51 189.88,60.38 v4(189.84,60.35)
  TOP w0.114: DIMM2.229 233.83,16.67 233.86,16.65 234.58,16.65 v3(235.05,16.17)
  L4 w0.089: 193.33,50.53 193.33,51.01 192.9,51.44 192.9,52.25 192.99,52.35 192.99,53.63 192.82,53.8 192.82,54.66 192.93,54.77 192.93,56.1 192.53,56.5 192.53,59.42 191.96,59.99 191.16,59.99 190.85,60.3 190.85,60.53 190.62,60.76 190.19,60.76 189.84,60.41 v4(189.84,60.35)
  L4 w0.127: 193.33,50.53 193.33,50.31 193.33,50.31 193.33,50.14 193.33,50.14 193.33,49.22 193.82,48.72 194.74,48.72 195.96,47.5 196.45,47.5 196.8,47.15 198.84,47.15 199.36,46.62 199.51,46.62 204.74,41.39 204.74,40.59 206.82,38.51 206.82,35.88 216,26.7 216,26.47 226.16,16.32 227.52,16.32 227.65,16.19 227.65,15.94 227.78,15.81 228.03,15.81 228.16,15.94 228.16,16.17 228.28,16.3 228.54,16.3 228.67,16.17 228.67,15.97 228.79,15.85 229.05,15.85 229.17,15.97 229.17,16.17 229.3,16.3 229.55,16.3 229.68,16.17 229.68,15.83 229.81,15.7 230.06,15.7 230.19,15.83 230.19,16.17 230.32,16.3 230.57,16.3 230.7,16.17 230.7,15.83 230.82,15.7 231.08,15.7 231.21,15.83 231.21,16.17 231.33,16.3 231.59,16.3 231.71,16.17 231.71,15.83 231.84,15.7 232.09,15.7 232.22,15.83 232.22,16.17 232.35,16.3 232.6,16.3 232.73,16.17 232.73,15.83 232.86,15.7 233.11,15.7 233.24,15.83 233.24,16.17 233.36,16.3 233.62,16.3 233.75,16.17 233.75,15.83 233.87,15.7 234.93,15.7 235.05,15.83 v3(235.05,16.17)
  BOTTOM w0.114: v3(235.05,16.17) v1(234.82,15.4)
M_B_DQ32: length 63.2
  TOP w0.076: CPU1.J48 192.93,68.61 193.18,68.51 193.38,68.51 193.59,68.72 194.21,68.72 197.37,71.88 197.57,71.88 v4(197.94,72.25)
  TOP w0.114: v3(235.07,54.33) 235.07,54.66 234.55,55.17 DIMM2.83
  L4 w0.127: v3(235.07,54.33) 235.07,53.99 234.94,53.86 233.69,53.86 233.38,54.17 233.38,54.46 233.24,54.6 232.16,54.6 217.32,69.44 203.3,69.44 202.44,70.3 199.24,70.3 199.12,70.42 199.12,70.89 198.99,71.02 198.74,71.02 198.61,70.89 198.61,70.42 198.48,70.3 195.39,70.3 195.27,70.42 195.27,70.75 195.39,70.88 197.82,70.88 197.94,71 v4(197.94,72.25)
  BOTTOM w0.114: v3(235.07,54.33) v1(235.07,55.14)
M_B_DQ33: length 65
  TOP w0.076: v4(198.58,72.25) 198.04,71.71 197.44,71.71 194.28,68.56 193.66,68.56 193.44,68.33 193.18,68.33 192.82,68.47 191.75,68.47 191.58,68.64 191.43,68.64 CPU1.J45
  TOP w0.114: v3(236.49,54.33) 236.49,54.78 235.09,56.17 DIMM2.79
  L4 w0.127: v3(236.49,54.33) 235.87,54.95 232.3,54.95 217.46,69.78 217.31,69.78 217.22,69.88 217.22,70.03 217.08,70.16 216.71,70.16 216.59,70.04 216.59,69.92 216.46,69.79 216.21,69.79 216.08,69.92 216.08,70.04 215.95,70.16 215.7,70.16 215.57,70.04 215.57,69.92 215.44,69.79 215.19,69.79 215.06,69.92 215.06,70.04 214.94,70.16 214.68,70.16 214.56,70.04 214.56,69.92 214.43,69.79 214.17,69.79 214.05,69.92 214.05,70.04 213.92,70.16 213.67,70.16 213.54,70.04 213.54,69.92 213.41,69.79 213.16,69.79 213.03,69.92 213.03,70.04 212.9,70.16 212.65,70.16 212.52,70.04 212.52,69.92 212.4,69.79 212.14,69.79 212.02,69.92 212.02,70.04 211.89,70.16 211.63,70.16 211.51,70.04 211.51,69.92 211.38,69.79 211.13,69.79 211,69.92 211,70.04 210.87,70.16 210.62,70.16 210.49,70.04 210.49,69.92 210.36,69.79 210.11,69.79 209.98,69.92 209.98,70.04 209.86,70.16 209.6,70.16 209.48,70.04 209.48,69.92 209.35,69.79 209.09,69.79 208.97,69.92 208.97,70.04 208.84,70.16 208.59,70.16 208.46,70.04 208.46,69.92 208.33,69.79 208.08,69.79 207.95,69.92 207.95,70.03 207.82,70.16 207.52,70.16 207.39,70.03 207.39,69.92 207.26,69.79 207.01,69.79 206.88,69.92 206.88,70.03 206.75,70.16 206.5,70.16 206.37,70.03 206.37,69.92 206.25,69.79 205.99,69.79 205.86,69.92 205.86,70.03 205.74,70.16 203.02,70.16 202.67,70.51 200.09,70.51 198.58,72.03 v4(198.58,72.25)
  BOTTOM w0.114: v3(236.49,54.33) v1(236.49,55.18)
M_B_DQ34: length 62.5
  TOP w0.076: v4(197.31,72.25) 197.31,72.09 194.11,68.89 193.33,68.89 CPU1.J49
  TOP w0.114: DIMM2.84 240.17,54.92 v3(239.62,54.38)
  L4 w0.089: 201.41,70.73 201.26,70.73 199.37,72.61 197.67,72.61 v4(197.31,72.25)
  L4 w0.127: v3(239.62,54.38) 241.32,54.38 241.44,54.25 241.44,53.9 241.32,53.78 237.71,53.78 236.15,55.33 232.4,55.33 217.22,70.51 203.12,70.51 202.9,70.73 201.41,70.73
  BOTTOM w0.114: v3(239.62,54.38) v1(240.43,54.38)
M_B_DQ35: length 63.5
  TOP w0.089: v4(196.91,74.51) 197.03,74.63 197.03,74.78 196.81,75 195.62,75 194.66,74.04 194.66,71.41 194.52,71.27 193.86,71.27 193.2,70.61 192.93,70.61 192.74,70.42 192.44,70.42 192.08,70.06 CPU1.G47
  TOP w0.114: v3(237.64,58.28) 237.5,58.28 237.26,58.52 237.26,58.95 237.65,59.34 239.83,59.34 239.92,59.42 DIMM2.66
  L4 w0.089: v4(196.91,74.51) 197.27,74.87 199.21,74.87 200.03,74.06
  L4 w0.127: v3(237.64,58.28) 237.78,58.28 237.91,58.41 237.91,58.62 237.78,58.75 233.95,58.75 231.61,61.09 231.24,61.09 230.48,61.85 230.3,61.85 230.01,61.56 229.77,61.56 218.32,73.02 201.06,73.02 200.03,74.06
  BOTTOM w0.114: v3(237.64,58.28) v1(237.64,59.09)
M_B_DQ36: length 64.7
  TOP w0.076: CPU1.J47 192.35,69 192.5,69.05 192.67,69.05 192.81,69 192.99,69 193.18,69.06 194.05,69.06 196.08,71.1 196.08,71.55 196.08,72.35 196.34,72.61 198.2,72.61 198.27,72.68 v4(198.27,73.29)
  TOP w0.114: v3(237.73,54.43) 237.73,55.44 238.22,55.92 DIMM2.80
  L4 w0.089: 201.44,70.97 201.26,70.97 199.44,72.79 198.78,72.79 v4(198.27,73.29)
  L4 w0.127: 201.44,70.97 202.99,70.97 203.11,70.85 217.37,70.85 230.57,57.64 231.66,57.64 231.93,57.37 231.93,56.71 232.93,55.71 236.32,55.71 236.78,55.24 238.6,55.24 238.73,55.12 238.73,54.83 238.44,54.54 238.44,54.36 238.37,54.29 237.88,54.29 v3(237.73,54.43)
  BOTTOM w0.114: v3(237.73,54.43) 237.59,54.16 v1(237.36,53.71)
M_B_DQ37: length 64.4
  TOP w0.076: CPU1.G45 191.28,69.22 191.46,69.04 191.68,69.04 191.8,69.16 192.31,69.16 192.47,69.22 192.71,69.22 192.84,69.16 192.97,69.16 193.17,69.23 193.95,69.23 193.99,69.24 195.92,71.16 195.92,72.51 196.25,72.84 197.7,72.84 197.89,73.04 197.89,73.56
  TOP w0.114: v4(198.99,74.51) 199.42,74.95 199.59,74.95 199.83,74.7 199.83,74.54 199.15,73.86 198.01,73.86 197.89,73.74 197.89,73.56 ; DIMM2.71 234.55,58.17 v3(235.05,57.67)
  L4 w0.089: v4(198.99,74.51) 199.21,74.51 201.04,72.68 201.2,72.68
  L4 w0.127: 201.2,72.68 218.17,72.68 229.8,61.05 229.98,61.05 230.28,61.34 230.46,61.34 230.66,61.14 230.66,60.96 230.37,60.67 230.37,60.49 230.6,60.25 230.78,60.25 231.27,60.74 231.46,60.74 231.64,60.56 231.64,60.38 231.15,59.88 231.15,59.7 231.35,59.5 231.53,59.5 231.94,59.91 232.12,59.91 233.65,58.38 235.29,58.38 235.42,58.26 235.42,57.8 235.29,57.67 v3(235.05,57.67)
  BOTTOM w0.114: v3(235.05,57.67) v1(235.05,56.86)
M_B_DQ38: length 62.2
  TOP w0.089: v4(195.64,74.51) 194.87,73.74 194.87,71.37 194.59,71.1 193.94,71.1 193.27,70.43 193,70.43 192.68,70.11 CPU1.G48
  TOP w0.114: v3(239.04,58.2) 239.06,58.2 239.06,58.25 239.24,58.42 DIMM2.70
  L4 w0.089: 200.24,74.15 199.34,75.05 196.18,75.05 v4(195.64,74.51)
  L4 w0.127: v3(239.04,58.2) 239.17,58.34 239.93,58.34 240.05,58.46 240.05,58.98 239.93,59.11 234.07,59.11 231.75,61.43 231.39,61.43 230.36,62.45 229.37,62.45 218.46,73.36 201.03,73.36 200.24,74.15
  BOTTOM w0.114: v1(239.69,58.68) v3(239.04,58.2)
M_B_DQ39: length 61
  TOP w0.089: CPU1.E48 193.24,70.9 194.41,72.07 194.41,74.22 195.37,75.18 196.88,75.18 v4(197.55,74.51)
  TOP w0.114: v3(236.82,58.24) 235.89,59.17 DIMM2.67
  L4 w0.089: v4(197.55,74.51) 197.91,74.15 199.3,74.15 201.12,72.34 201.36,72.34
  L4 w0.127: 201.36,72.34 217.98,72.34 231.19,59.13 232.42,59.13 233.42,58.13 233.42,57.92 234.15,57.19 236.92,57.19 237.04,57.32 237.04,58.02 v3(236.82,58.24)
  BOTTOM w0.114: v3(236.82,58.24) v1(236.93,57.44)
M_B_DQ40: length 66.8
  TOP w0.102: DIMM2.59 235.05,61.17 236.48,59.75 v3(236.48,59.67)
  TOP w0.114: v4(187.97,69.52) 187.97,69.42 CPU1.J38
  L4 w0.089: v4(187.97,69.52) 188.42,69.06 189.43,69.06 189.55,68.94 190.13,68.94 190.72,69.53 191.35,69.53 193.39,71.57 193.39,72.41 194.12,73.14 194.12,74.18 195.35,75.41 199.59,75.41
  L4 w0.127: v3(236.48,59.67) 236.57,59.67 236.7,59.8 236.7,60.55 236.57,60.68 236.19,60.68 236.07,60.55 236.07,60.32 235.94,60.2 235.63,60.2 235.48,60.34 235.48,60.55 235.35,60.68 233.49,60.68 232.05,62.12 231.67,62.12 230.62,63.17 229.62,63.17 218.74,74.05 203.49,74.05 203.36,74.18 203.36,75.17 203.23,75.3 202.49,75.3 202.38,75.41 199.59,75.41
  BOTTOM w0.114: v1(236.69,60.46) v3(236.48,59.67)
M_B_DQ41: length 66
  TOP w0.114: v3(237.53,62.92) 237.89,63.28 237.89,63.29 239.03,64.42 DIMM2.46 ; CPU1.G39 188.26,70.05 v4(187.93,70.38)
  L4 w0.089: 194.67,77.26 187.93,70.52 v4(187.93,70.38)
  L4 w0.127: v3(237.53,62.92) 237.53,62.75 237.4,62.62 237.12,62.62 236.99,62.75 236.99,63.48 236.86,63.61 236.56,63.61 236.16,64 235.51,64 235.15,64.36 233.92,64.36 233.31,64.97 232.86,64.97 231.77,66.06 230.77,66.06 219.93,76.91 211.74,76.91 210.5,78.15 201.62,78.15 201.02,78.75 196.16,78.75 194.67,77.26
  BOTTOM w0.114: v3(237.53,62.92) v1(237.53,62.11)
M_B_DQ42: length 65.4
  TOP w0.114: DIMM2.50 239.45,63.42 v3(238.95,62.92) ; v4(187.32,70.4) 187.32,70.26 CPU1.G38
  L4 w0.089: v4(187.32,70.4) 187.68,71.55 187.87,71.73 190.7,73.65 190.96,73.91
  L4 w0.127: 190.96,73.91 196.02,78.97 201.22,78.97 201.69,78.5 210.64,78.5 211.89,77.25 220.07,77.25 230.92,66.4 231.91,66.4 233,65.32 233.45,65.32 234.06,64.7 235.37,64.7 238.33,63.55 v3(238.95,62.92)
  BOTTOM w0.114: v3(238.95,62.92) v1(238.95,62.11)
M_B_DQ43: length 65.7
  TOP w0.114: DIMM2.45 236.94,64.68 237.05,64.56 237.05,63.71 v3(236.48,63.14) ; CPU1.G42 189.56,70.08 v4(189.23,70.4)
  L4 w0.089: v4(189.23,70.4) 188.8,70.84 188.8,71.07 194.71,76.98
  L4 w0.127: v3(236.48,63.14) 235.96,63.66 235.37,63.66 235.01,64.02 233.78,64.02 233.17,64.63 232.71,64.63 231.66,65.69 230.67,65.69 219.79,76.56 211.28,76.56 211.12,76.73 211.12,77.04 210.35,77.81 200.74,77.81 200.33,78.23 196.77,78.23 196.61,78.39 196.23,78.39 196.08,78.24 196.08,77.5 195.95,77.38 195.11,77.38 194.71,76.98
  BOTTOM w0.114: v1(236.17,63.9) v3(236.48,63.14)
M_B_DQ44: length 66.9
  TOP w0.114: v3(235.05,59.67) 234.55,60.17 DIMM2.63 ; v4(187.92,68.63) 187.92,68.72 CPU1.J39
  L4 w0.089: 199.51,75.19 199.47,75.23 195.42,75.23 194.86,74.67 194.86,72.56 191.43,69.13 190.57,69.13 190.12,68.68 189.92,68.68 189.45,68.21 188.01,68.21 187.92,68.3 v4(187.92,68.63)
  L4 w0.127: 199.51,75.19 200.73,75.19 200.86,75.06 200.86,74.07 200.98,73.95 201.3,73.95 201.43,74.07 201.43,74.83 201.56,74.95 201.81,74.95 201.94,74.83 201.94,73.86 202.06,73.74 202.32,73.74 202.44,73.86 202.44,74.83 202.57,74.95 202.83,74.95 202.95,74.83 202.95,73.86 203.11,73.71 218.6,73.71 229.48,62.83 230.48,62.83 231.53,61.77 231.9,61.77 233.34,60.33 234.93,60.33 235.23,60.03 235.23,59.8 235.1,59.67 v3(235.05,59.67)
  BOTTOM w0.114: v3(235.05,59.67) v1(235.32,58.91)
M_B_DQ45: length 66.5
  TOP w0.114: CPU1.J42 189.27,69.34 v4(189.27,69.47) ; DIMM2.62 240.11,60.42 240.03,60.34 239.47,60.34 v3(238.95,59.82)
  L4 w0.089: 199.78,75.64 195.32,75.64 193.88,74.2 193.88,73.22 193.21,72.55 193.21,71.64 191.72,70.15 191.07,70.15 190.03,69.12 189.62,69.12 v4(189.27,69.47)
  L4 w0.127: v3(238.95,59.82) 238.58,59.45 237.17,59.45 237.04,59.58 237.04,60.16 237.29,60.4 237.39,60.4 237.6,60.61 237.6,60.89 237.47,61.02 233.63,61.02 232.19,62.46 231.81,62.46 230.76,63.51 229.76,63.51 218.89,74.39 203.85,74.39 203.72,74.52 203.72,75.51 203.6,75.64 199.78,75.64
  BOTTOM w0.114: v1(239.33,60.57) v3(238.95,59.82)
M_B_DQ46: length 64.9
  TOP w0.114: v3(235.05,63.2) 235.05,63.56 234.94,63.68 DIMM2.49 ; v4(189.88,70.64) 189.88,70.31 CPU1.G43
  L4 w0.089: 195.3,77 191.54,73.24 191.54,72.66 191.05,72.18 190.9,72.18 189.88,71.16 v4(189.88,70.64)
  L4 w0.127: v3(235.05,63.2) 235.05,63.46 234.84,63.67 233.64,63.67 233.03,64.29 232.57,64.29 231.52,65.34 230.52,65.34 219.64,76.22 210.97,76.22 210.78,76.41 210.78,76.76 210.65,76.88 210.31,76.88 209.87,76.88 209.75,77.01 209.75,77.34 209.62,77.47 209.37,77.47 209.24,77.34 209.24,76.92 209.11,76.79 208.86,76.79 208.73,76.92 208.73,77.34 208.6,77.47 208.35,77.47 208.22,77.34 208.22,77.03 208.1,76.9 207.84,76.9 207.72,77.03 207.72,77.34 207.59,77.47 202.37,77.47 202.18,77.28 201.53,77.28 201.21,77.6 200.68,77.6 200.54,77.45 200.54,77.16 200.41,77.02 200.1,77.02 199.97,77.15 199.97,77.84 199.84,77.97 199.5,77.97 199.38,77.84 199.38,77.15 199.25,77.02 199,77.02 198.87,77.15 198.87,77.85 198.74,77.98 198.45,77.98 198.33,77.85 198.33,77.09 198.24,77 195.3,77
  BOTTOM w0.114: v1(234.7,63.93) v3(235.05,63.2)
M_B_DQ47: length 66.1
  TOP w0.114: v4(189.88,69.48) 189.88,69.39 CPU1.J43 ; v3(237.54,59.93) 239.03,61.42 DIMM2.58
  L4 w0.089: 199.63,75.98 195.33,75.98 192.66,73.31 192.66,72.25 v4(189.88,69.48)
  L4 w0.127: v3(237.54,59.93) 237.55,59.93 238.06,60.44 238.33,60.44 238.46,60.57 238.46,61.24 238.33,61.36 233.77,61.36 232.33,62.8 231.96,62.8 230.9,63.86 229.91,63.86 219.03,74.74 204.21,74.74 204.08,74.86 204.08,75.86 203.95,75.98 199.63,75.98
  BOTTOM w0.114: v1(237.97,60.71) v3(237.54,59.93)
M_B_DQ48: length 67.4
  TOP w0.076: CPU1.B43 190.37,72.81 190.37,74.46 v4(190.55,74.64)
  TOP w0.114: DIMM2.42 239.45,65.42 v3(238.95,64.92)
  L4 w0.127: v4(190.55,74.64) 189.98,75.21 189.98,76.81 191.26,78.09 191.97,78.09 194.67,80.79 207.33,80.79 208.18,79.94 211.32,79.94 212.59,78.67 221.62,78.67 233.6,66.69 236.16,66.69 237.4,65.45 238.66,65.45 239.35,66.14 239.53,66.14 239.75,65.91 239.75,65.73 v3(238.95,64.92)
  BOTTOM w0.114: v3(238.95,64.92) v1(238.95,64.11)
M_B_DQ49: length 70.1
  TOP w0.076: CPU1.D43 190.08,71.45 190.37,71.74 190.37,72.28 190.53,72.44 190.53,73.67 190.68,73.81
  TOP w0.114: DIMM2.24 240.06,69.92 239.29,69.77 239.09,69.69 238.3,69.15 v3(237.53,68.38) ; v4(191.63,80.91) 191.93,77.53 191.42,76.38 191.42,76.25 191.2,76.03 191.2,76.03 190.92,75.76 190.92,74.06 190.68,73.81
  L4 w0.127: v3(237.53,68.38) 236.54,69.36 234,69.36 222.52,80.84 218.44,80.84 217.17,82.12 213.31,82.12 213.18,82.24 213.18,82.66 213.05,82.79 212.8,82.79 212.67,82.66 212.67,82.24 212.55,82.12 212.32,82.12 212.2,82.24 212.2,82.64 212.07,82.77 211.82,82.77 211.69,82.64 211.69,82.24 211.56,82.12 209.09,82.12 208.25,82.96 193.68,82.96 v4(191.63,80.91)
  BOTTOM w0.114: v3(237.53,68.38) 237.53,69.18 v1(237.52,69.19)
M_B_DQ50: length 66.5
  TOP w0.076: v4(190.55,75.28) 189.97,74.7 189.97,74.3 190.08,74.07 CPU1.A43
  TOP w0.114: v3(237.53,64.96) 238.99,66.42 DIMM2.38
  L4 w0.127: v3(237.53,64.96) 237.15,64.96 237.02,65.09 237.02,65.32 235.99,66.35 233.43,66.35 231.97,67.8 231.75,67.8 231.45,67.5 231.27,67.5 230.72,68.05 230.72,68.23 231.07,68.58 231.07,68.73 230.83,68.97 230.65,68.97 230.32,68.64 230.14,68.64 229.96,68.82 229.96,69 230.29,69.33 230.29,69.51 221.47,78.33 212.44,78.33 211.18,79.59 208.04,79.59 207.18,80.45 200.3,80.45 199.96,80.45 199.96,80.45 194.97,80.45 191.56,77.04 190.83,77.04 190.19,76.4 190.19,75.63 v4(190.55,75.28)
  BOTTOM w0.114: v3(237.53,64.96) v1(237.53,64.15)
M_B_DQ51: length 69.2
  TOP w0.076: CPU1.C40 188.48,72.31 188.38,72.89 188.32,73.05 188.32,73.24 188.04,73.53 188.04,75.1 188.02,75.11 187.97,75.16 187.97,76.22 v4(188.33,76.58)
  TOP w0.114: DIMM2.29 234.47,68.67 234.65,68.57 v3(235.05,68.17)
  L4 w0.127: v4(188.33,76.58) 188.76,77.01 188.76,78.33 190.5,80.08 191.85,80.08 194.05,82.28 207.94,82.28 208.8,81.42 211.94,81.42 212.52,80.84 213.59,80.84 213.71,80.71 213.71,80.32 213.84,80.19 214.09,80.19 214.22,80.32 214.22,81.3 214.35,81.43 214.6,81.43 214.73,81.3 214.73,80.7 214.86,80.57 215.11,80.57 215.24,80.7 215.24,81.3 215.36,81.43 215.62,81.43 215.75,81.3 215.75,80.72 215.87,80.59 216.13,80.59 216.25,80.72 216.25,81.3 216.38,81.43 216.84,81.43 216.97,81.3 216.97,80.28 217.1,80.16 222.24,80.16 233.72,68.68 234.55,68.68 v3(235.05,68.17)
  BOTTOM w0.114: v3(235.05,68.17) v1(235.05,67.36)
M_B_DQ52: length 69.2
  TOP w0.076: v4(190.57,75.94) 190.58,75.94 190.58,75.94 189.78,75.15 189.78,73.1 189.84,72.96 189.84,72.73 189.78,72.56 189.78,72.45 189.84,72.31 CPU1.C43
  TOP w0.114: v3(236.48,65.17) 236.48,65.29 235.09,66.67 DIMM2.37
  L4 w0.127: v4(190.57,75.94) 190.57,76.48 190.92,76.82 192.8,76.82 195.52,79.54 202.28,79.54 202.84,80.1 207.04,80.1 207.9,79.25 211.04,79.25 212.3,77.98 221.33,77.98 226.51,72.8 226.51,72.62 226.18,72.29 226.18,72.11 226.36,71.93 226.54,71.93 226.87,72.26 227.05,72.26 227.23,72.08 227.23,71.9 226.9,71.57 226.9,71.39 227.08,71.21 227.26,71.21 227.59,71.55 227.77,71.55 227.95,71.37 227.95,71.19 227.62,70.85 227.62,70.67 227.8,70.49 227.98,70.49 228.31,70.83 228.49,70.83 228.67,70.65 228.67,70.47 228.34,70.13 228.34,69.96 228.52,69.78 228.7,69.78 229.03,70.11 229.21,70.11 229.49,69.83 229.49,69.65 229.15,69.32 229.15,69.14 231.16,67.13 232.15,67.13 233.28,66 235.65,66 v3(236.48,65.17)
  BOTTOM w0.114: v3(236.48,65.17) v1(236.48,65.99)
M_B_DQ53: length 70.4
  TOP w0.076: 189.62,75.62 189.62,73.07 189.67,72.93 189.67,72.76 189.6,72.56 189.6,72.45 189.67,72.28 189.67,71.91 189.67,71.91 189.75,71.83 189.75,71.31 189.66,71.21 CPU1.D40
  TOP w0.089: 189.62,75.62 190.41,76.41 v4(191.04,76.41)
  TOP w0.114: v3(235.05,65.19) 234.57,65.68 DIMM2.41
  L4 w0.127: v3(235.05,65.19) 235.14,65.27 235.14,65.53 235.01,65.66 233.14,65.66 232.05,66.75 231.06,66.75 225.6,72.2 225.6,72.38 225.94,72.71 225.94,72.89 225.76,73.07 225.58,73.07 225.25,72.74 225.07,72.74 224.89,72.92 224.89,73.1 225.22,73.43 225.22,73.61 225.04,73.79 224.86,73.79 224.53,73.46 224.35,73.46 224.1,73.7 224.1,73.88 224.43,74.21 224.43,74.39 224.25,74.57 224.07,74.57 223.74,74.24 223.56,74.24 223.38,74.42 223.38,74.6 223.71,74.93 223.71,75.11 223.53,75.29 223.35,75.29 223.03,74.96 222.85,74.96 222.67,75.14 222.67,75.32 222.99,75.65 222.99,75.83 222.81,76 222.63,76 222.31,75.68 222.13,75.68 221.95,75.86 221.95,76.04 222.27,76.36 222.27,76.54 222.09,76.72 221.91,76.72 221.59,76.4 221.41,76.4 221.23,76.58 221.23,76.76 221.55,77.08 221.55,77.26 221.37,77.44 221.19,77.44 220.87,77.12 220.69,77.12 220.21,77.59 212.21,77.59 210.89,78.91 207.75,78.91 206.9,79.76 203.01,79.76 202.58,79.33 195.81,79.33 192.48,75.99 191.46,75.99 v4(191.04,76.41)
  BOTTOM w0.114: v3(235.05,65.19) v1(235.05,66)
M_B_DQ54: length 68.3
  TOP w0.076: CPU1.B40 188.54,72.93 188.49,73.08 188.49,73.32 188.23,73.58 188.23,75.22 v4(188.33,75.31)
  TOP w0.114: DIMM2.25 234.58,69.67 235.46,69.19 v3(236.48,68.17)
  L4 w0.127: v3(236.48,68.17) 235.63,69.02 233.86,69.02 222.38,80.5 217.48,80.5 217.35,80.63 217.35,81.44 217.02,81.77 213.45,81.77 213.33,81.65 213.33,81.42 213.2,81.29 212.95,81.29 212.82,81.42 212.82,81.65 212.69,81.77 208.93,81.77 208.08,82.62 193.91,82.62 191.67,80.38 190.4,80.38 187.91,77.89 187.91,75.91 187.98,75.65 v4(188.33,75.31)
  BOTTOM w0.114: v1(236.26,68.96) v3(236.48,68.17)
M_B_DQ55: length 67.5
  TOP w0.076: CPU1.A40 188.75,73.35 188.47,73.64 188.47,74.18 188.8,75.66 188.8,75.81
  TOP w0.114: 188.8,75.81 188.8,78.3 v1(189.92,79.74) 190.32,80.27 v4(190.96,80.9) ; v3(238.95,68.37) 239.5,68.92 DIMM2.28
  L4 w0.127: v3(238.95,68.37) 238.95,69.08 238.32,69.7 234.15,69.7 222.71,81.14 222.71,81.14 222.66,81.19 218.58,81.19 217.31,82.46 214.04,82.46 213.25,83.25 211.69,83.25 210.9,82.46 209.24,82.46 208.39,83.31 193.54,83.31 193.48,83.25 192.94,83.25 190.96,81.26 v4(190.96,80.9)
M_B_DQ56: length 77.1
  TOP w0.076: 185.79,74.1 185.91,73.98 185.91,73.06 186,72.88 CPU1.B35
  TOP w0.114: 185.79,74.1 185.59,74.3 185.59,74.53 v4(185.2,74.91) ; v3(235.36,75.11) 235.34,75.11 234.4,74.17 DIMM2.7
  L4 w0.127: v3(235.36,75.11) 235.63,75.11 235.79,74.96 235.79,74.73 235.66,74.61 234.5,74.61 233.95,75.15 233.95,76.52 230.42,80.05 229.3,80.05 228.41,80.93 228.41,81.11 228.57,81.27 228.57,81.45 228.39,81.63 228.21,81.63 228.05,81.47 227.87,81.47 227.69,81.65 227.69,81.83 227.85,81.99 227.85,82.17 227.67,82.35 227.49,82.35 227.33,82.19 227.15,82.19 226.97,82.37 226.97,82.55 227.13,82.71 227.13,82.89 226.95,83.07 226.77,83.07 226.61,82.91 226.43,82.91 226.25,83.09 226.25,83.27 226.41,83.43 226.41,83.61 226.23,83.79 226.05,83.79 225.89,83.63 225.71,83.63 225.53,83.81 225.53,83.99 225.69,84.15 225.69,84.33 225.51,84.51 225.33,84.51 225.18,84.35 225,84.35 224.7,84.65 220.44,84.65 219.38,85.7 219.2,85.7 219.07,85.56 218.89,85.56 218.71,85.74 218.71,85.92 218.84,86.06 218.84,86.24 218.58,86.51 191.07,86.51 184.13,79.56 184.13,76.92 185.05,76 185.29,76 185.61,75.68 185.61,75.04 185.48,74.91 v4(185.2,74.91)
  BOTTOM w0.114: v3(235.36,75.11) v1(235.36,74.3)
M_B_DQ57: length 79
  TOP w0.076: CPU1.D35 186.46,71.7 186.46,72.09 186.46,72.09 186.59,72.45 186.59,72.59 186.52,72.77 186.52,72.9 186.59,73.09 186.59,74.13 186.13,74.59 186.13,75.54 186.06,75.61 186.06,75.75 186.06,75.76
  TOP w0.114: DIMM2.21 234.52,70.67 235.46,69.74 236.55,69.74 236.92,70.1 236.92,71.85 v3(237.54,72.47) ; 186.06,75.76 186.06,76.74 v4(185.2,77.61)
  L4 w0.127: v4(185.2,77.61) 185.2,78.36 185.42,78.59 185.94,78.59 192.03,84.68 215.3,84.68 215.42,84.55 215.42,83.99 215.55,83.86 215.8,83.86 215.93,83.99 215.93,84.55 216.06,84.68 217.03,84.68 218.89,82.82 223.94,82.82 230.27,76.49 230.27,76.31 229.97,76.01 229.97,75.83 233.03,72.78 234.8,72.78 234.93,72.65 234.93,72.14 235.09,71.98 237.41,71.98 237.54,72.11 v3(237.54,72.47)
  BOTTOM w0.114: v3(237.54,72.47) v1(237.3,71.64)
M_B_DQ58: length 75.9
  TOP w0.076: CPU1.A35 186.16,74.06 185.8,74.42 185.8,74.45 185.8,74.45 185.8,74.74 185.65,74.89
  TOP w0.114: v3(234.42,75.81) 234.42,75.68 233.91,75.17 DIMM2.3 ; v4(185.2,75.55) 185.65,75.1 185.65,74.89
  L4 w0.127: v4(185.2,75.55) 185.03,75.72 184.29,75.72 183.86,76.16 183.86,79.77 190.93,86.85 218.72,86.85 220.56,85.01 225.5,85.01 229.41,81.1 229.41,80.94 229.25,80.78 229.25,80.6 229.46,80.39 229.68,80.39 230.56,81.27 230.74,81.27 230.92,81.09 230.92,80.91 230.57,80.56 230.57,80.38 230.75,80.2 230.93,80.2 231.28,80.55 231.46,80.55 231.64,80.37 231.64,80.19 231.29,79.84 231.29,79.66 231.47,79.48 231.65,79.48 232,79.83 232.18,79.83 232.36,79.65 232.36,79.47 232.01,79.12 232.01,78.94 232.19,78.76 232.37,78.76 232.72,79.11 232.9,79.11 233.08,78.93 233.08,78.75 232.73,78.4 232.73,78.22 232.99,77.96 233.17,77.96 233.32,78.1 233.5,78.1 233.68,77.92 233.68,77.75 233.53,77.6 233.53,77.42 234.74,76.21 234.74,75.94 234.61,75.81 v3(234.42,75.81)
  BOTTOM w0.114: v3(234.42,75.81) v1(233.61,75.81)
M_B_DQ59: length 78.2
  TOP w0.076: v4(185.2,74.28) 185.74,73.74 185.74,73.02 185.85,72.82 185.85,71.87 185.86,71.85 185.86,71.01 185.97,70.9 186.34,70.9 186.65,71.21 CPU1.D38
  TOP w0.114: v3(238.38,75.1) 238.55,74.92 DIMM2.4
  L4 w0.127: v3(238.38,75.1) 236.88,75.53 236.66,75.58 236.45,75.66 235.45,76.02 234.55,77.02 233.44,79.2 231.21,81.43 230.85,81.65 229.41,81.69 229.21,81.81 225.67,85.35 221.77,85.35 220.48,85.58 218.86,87.19 190.79,87.19 183.58,79.98 183.58,75.69 184.39,74.87 v4(185.2,74.28)
  BOTTOM w0.114: v1(237.8,74.52) v3(238.38,75.1)
M_B_DQ60: length 77.9
  TOP w0.076: CPU1.C35 186.32,72.19 186.41,72.43 186.41,72.6 186.35,72.74 186.35,72.92 186.41,73.08 186.41,74.05 185.97,74.49 185.97,74.51 185.96,74.52 185.96,74.81 185.93,74.84 185.93,75.3
  TOP w0.114: DIMM2.8 239.17,73.92 v3(238.97,73.73) ; v4(185.2,76.39) 185.71,75.88 185.71,75.52 185.93,75.3
  L4 w0.127: v3(238.97,73.73) 239.24,73.73 239.4,73.9 239.4,74.24 239.28,74.37 237.84,74.37 237.71,74.23 237.71,73.29 237.58,73.16 237.23,73.16 237.1,73.29 237.1,74.06 236.9,74.26 234.36,74.26 233.57,75.04 233.57,75.87 233.57,76.41 230.28,79.7 229.15,79.7 224.55,84.3 220.06,84.3 219.35,85.02 218.83,85.02 217.68,86.16 191.22,86.16 184.35,79.29 184.35,77.17 185.13,76.39 v4(185.2,76.39)
  BOTTOM w0.114: v3(238.97,73.73) 239.53,74.29 v1(239.59,74.29)
M_B_DQ61: length 77.4
  TOP w0.076: CPU1.C38 187.72,72.31 187.82,72.89 187.88,73.05 187.88,73.29 187.81,73.47 187.81,75.99 187.74,76.05
  TOP w0.114: v3(238.24,72.55) 238.24,72.55 238.87,71.92 DIMM2.16 ; 187.74,76.05 187.5,76.29 187.5,77.79 186.82,78.47 185.73,78.47 185.58,78.32 v4(185.58,78.21)
  L4 w0.127: v3(238.24,72.55) 238.63,72.94 239.32,72.94 239.46,72.8 239.46,72.01 239.09,71.64 233.68,71.64 229.48,75.83 229.48,76 229.78,76.31 229.78,76.49 223.8,82.48 218.75,82.48 217.74,83.49 214.47,83.49 213.62,84.33 192.21,84.33 186.08,78.21 v4(185.58,78.21)
  BOTTOM w0.114: v3(238.24,72.55) v1(238.57,71.77)
M_B_DQ62: length 75.9
  TOP w0.076: 187.53,75.92 187.62,75.82 187.62,73.48 187.71,73.25 187.71,73.08 187.66,72.93 CPU1.B38
  TOP w0.114: v3(238.91,70.39) 239.44,70.92 DIMM2.20 ; 187.53,75.92 187.23,76.21 187.23,77.46 v4(186.6,78.1)
  L4 w0.127: v3(238.91,70.39) 238.91,70.06 239.04,69.93 240.96,69.93 241.08,70.06 241.08,70.97 240.96,71.1 236.1,71.1 236,71.2 233.64,71.2 228.99,75.85 228.99,76.05 229.27,76.33 229.27,76.51 223.65,82.13 218.6,82.13 217.59,83.14 214.32,83.14 213.48,83.99 192.49,83.99 v4(186.6,78.1)
  BOTTOM w0.114: v3(238.91,70.39) v1(238.91,69.58)
M_B_DQ63: length 75.4
  TOP w0.076: 187.33,75.78 187.45,75.66 CPU1.A38
  TOP w0.114: v4(186.58,77.45) 187,77.03 187,76.1 187.33,75.78 ; v3(236.41,70.3) 235.04,71.67 DIMM2.17
  L4 w0.127: v3(236.41,70.3) 235.86,70.85 233.49,70.85 228.49,75.86 228.49,76.04 228.79,76.33 228.79,76.51 228.61,76.69 228.43,76.69 228.13,76.4 227.95,76.4 227.77,76.58 227.77,76.76 228.07,77.05 228.07,77.23 227.89,77.41 227.71,77.41 227.41,77.11 227.23,77.11 227.05,77.29 227.05,77.47 227.35,77.77 227.35,77.95 227.17,78.13 226.99,78.13 226.69,77.83 226.51,77.83 226.27,78.08 226.27,78.26 226.55,78.53 226.55,78.71 226.37,78.89 226.19,78.89 225.91,78.62 225.73,78.62 225.55,78.8 225.55,78.98 225.83,79.25 225.83,79.43 225.65,79.61 225.47,79.61 225.19,79.33 225.01,79.33 224.83,79.51 224.83,79.69 225.11,79.97 225.11,80.15 224.93,80.33 224.75,80.33 224.47,80.05 224.29,80.05 224.11,80.23 224.11,80.41 224.39,80.69 224.39,80.87 224.21,81.05 224.03,81.05 223.75,80.77 223.57,80.77 223.39,80.95 223.39,81.13 223.61,81.35 223.61,81.53 223.43,81.71 223.25,81.71 223.03,81.49 222.86,81.49 222.56,81.79 218.46,81.79 217.45,82.8 214.18,82.8 213.34,83.65 192.78,83.65 v4(186.58,77.45)
  BOTTOM w0.114: v1(235.98,71.02) v3(236.41,70.3)
M_B_DQS_DN0: length 75.4
  TOP w0.076: v4(200.5,57.83) 200.31,57.83 199.96,58.17 199.96,58.57 199.17,59.35 194.51,59.35 194.03,59.83 193.77,59.83 193.35,59.66 193.17,59.66 193,59.72 192.84,59.72 192.67,59.66 192.15,59.66 CPU1.AH46
  TOP w0.102: v3(238.24,23.43) 238.42,23.61 238.42,24.07 238.63,24.28 239.88,24.28 240.02,24.42 DIMM2.198
  L4 w0.114: v3(238.24,23.43) 237.65,22.84 233.12,22.84 232.5,22.22 229.02,22.22 214.91,36.33 214.91,36.49 215.31,36.89 215.31,37.24 214.89,37.66 214.54,37.66 214.06,37.17 213.9,37.17 213.62,37.45 213.62,37.61 213.95,37.94 213.95,38.29 213.53,38.7 212.94,38.7 212.64,39 212.64,39.58 213.03,39.97 213.03,40.32 205.73,47.62 205.73,49.14 202.83,52.03 202.83,54.22 202.41,54.64 202.41,55.08 202.99,55.67 202.99,56.38 202.28,57.09 200.91,57.09 200.5,57.5 200.5,57.83 v4(200.5,57.83)
  BOTTOM w0.102: v1(237.98,22.65) v3(238.24,23.43)
M_B_DQS_DN1: length 88
  TOP w0.102: v3(238.2,12.71) 238.27,12.71 238.72,13.17 239.08,13.17 239.54,13.63 239.91,13.63 240.01,13.73 240.01,13.86 240.08,13.92 DIMM2.240 ; v4(189.22,58.61) 189.22,58.64 188.91,58.95 CPU1.AJ41
  L4 w0.089: 191.18,52.56 191.18,52.58 191.16,52.6 191.16,55.02 191.05,55.12 191.05,57.04 190.55,57.54 190.55,57.75 190.11,58.19 189.18,58.19 189.04,58.33 189.04,58.52 189.13,58.61 v4(189.22,58.61)
  L4 w0.114: v3(238.2,12.71) 238.2,12.44 238.32,12.33 238.59,12.33 238.68,12.23 238.68,11.85 238.41,11.59 237.11,11.59 237,11.7 237,12.12 236.75,12.36 236.22,12.36 235.92,12.06 235.92,11.81 235.8,11.7 235.47,11.7 234.9,12.27 229.6,12.27 229.36,12.02 229.36,11.76 229.24,11.65 228.85,11.65 228.73,11.76 228.73,12.02 228.49,12.27 227.9,12.27 227.65,12.02 226.57,12.02 220.57,18.03 217.62,18.03 217.07,18.57 217.07,19.36 214.01,22.43 212.79,22.43 212.58,22.64 212.58,26.01 211.99,26.6 211.42,27.17 211.42,27.17 207.62,30.97 204.13,34.46 204.13,37.4 201.21,40.32 201.21,41.59 198.06,44.74 194.3,44.74 191.74,47.3 191.74,49.73 191.18,50.29 191.18,52.56
  BOTTOM w0.102: v3(238.2,12.71) 238.2,13.06 v1(238.61,13.47)
M_B_DQS_DN2: length 73.5
  TOP w0.076: v4(197.23,61.21) 197.45,61.43 197.45,61.49 197.19,61.76 195.51,61.76 195.39,61.88 194.26,61.88 193.99,62.14 193.63,62.14 193.48,61.99 193.17,61.99 193,62.06 192.83,62.06 192.68,62.01 CPU1.AC47
  TOP w0.102: DIMM2.177 233.73,29.67 233.9,29.5 235.45,29.5 235.68,29.28 235.68,28.76 v3(235.76,28.67)
  L4 w0.114: v3(235.76,28.67) 235.6,28.51 235.6,28.01 235.37,27.79 234.23,27.79 233.66,28.36 230.16,28.36 229.01,29.51 228.71,29.51 228.26,29.06 227.85,29.06 227.45,29.46 227.45,29.81 227.99,30.35 227.99,30.51 227.7,30.8 227.54,30.8 226.94,30.2 226.58,30.2 226.17,30.61 226.17,30.97 226.78,31.58 226.78,31.77 226.51,32.03 226.32,32.03 225.73,31.44 225.36,31.44 224.96,31.84 224.96,32.21 225.55,32.8 225.55,32.99 225.3,33.25 225.11,33.25 224.51,32.65 224.13,32.65 223.68,33.1 223.68,34.87 223.21,35.34 213.43,45.12 213.43,46.64 204.99,55.08 204.99,58.13 202.53,60.59 197.74,60.59 197.5,60.83 197.5,60.93 v4(197.23,61.21)
  BOTTOM w0.102: v3(235.76,28.67) v1(235.76,27.86)
M_B_DQS_DN3: length 82.5
  TOP w0.102: DIMM2.219 234.14,19.17 234.15,19.17 235.58,19.17 235.78,18.97 v3(235.78,18) ; v4(189.17,61.27) CPU1.AE41
  L4 w0.089: 194.13,50.23 194.13,50.25 194.15,50.27 194.15,50.69 193.29,51.55 193.29,52.06 193.35,52.12 193.35,53.78 193.18,53.95 193.18,54.51 193.35,54.69 193.35,56.18 192.89,56.65 192.89,59.8 191.42,61.27 189.17,61.27 v4(189.17,61.27)
  L4 w0.114: v3(235.78,18) 235.78,17.8 235.27,17.29 226.57,17.29 226.18,17.68 226.18,18.08 226.57,18.46 226.57,18.62 226.29,18.9 226.13,18.9 225.75,18.52 225.4,18.52 224.98,18.93 224.98,19.29 225.36,19.67 225.36,19.83 225.09,20.11 224.92,20.11 224.54,19.72 224.19,19.72 223.77,20.13 223.77,20.49 224.16,20.87 224.16,21.03 223.88,21.31 223.69,21.31 223.29,20.91 222.94,20.91 216.97,26.88 216.97,27.13 207.79,36.31 207.79,38.91 205.88,40.82 205.88,41.62 200.39,47.12 199.54,47.12 198.9,47.75 196.8,47.75 196.62,47.93 196.14,47.93 195.61,48.46 195.61,49.02 195.14,49.49 194.58,49.49 194.13,49.94 194.13,50.23
  BOTTOM w0.102: v1(236.16,17.23) v3(235.78,18)
M_B_DQS_DN4: length 63.4
  TOP w0.076: v4(196.24,73.29) 196.51,73.56 196.51,73.74 196.4,73.86 195.51,73.86 195.25,73.6 195.25,71.06 193.83,69.63 193.34,69.63 193.14,69.65 193,69.71 192.83,69.71 192.68,69.66 CPU1.H47
  TOP w0.102: v3(238.05,56.57) 238.88,57.4 239.92,57.4 239.95,57.42 DIMM2.74
  L4 w0.089: 204.22,71.71 204.2,71.71 204.18,71.69 201.37,71.69 199.2,73.86 196.91,73.86 196.79,73.74 196.2,73.74 196.08,73.61 196.08,73.45 v4(196.24,73.29)
  L4 w0.114: 204.22,71.71 217.72,71.71 230.93,58.5 232.16,58.5 232.79,57.87 232.79,57.06 233.29,56.56 236.67,56.56 237.13,56.1 238.17,56.1 238.28,56.22 238.28,56.38 238.08,56.57 v3(238.05,56.57)
  BOTTOM w0.102: v1(237.91,55.77) v3(238.05,56.57)
M_B_DQS_DN5: length 66.3
  TOP w0.102: DIMM2.53 234.71,62.68 234.8,62.59 235.28,62.59 235.53,62.34 235.53,62.13 v3(235.79,61.88) ; CPU1.G41 188.91,70.04 v4(188.59,70.36)
  L4 w0.089: v4(188.59,70.36) 188.91,70.04 189.92,70.04 192.08,72.2 192.08,73.41 195.36,76.69 201.81,76.69 201.83,76.71 201.86,76.71
  L4 w0.114: v3(235.79,61.88) 235.54,62.12 235.54,62.37 235.22,62.69 233.73,62.69 232.77,63.66 232.31,63.66 231.26,64.71 230.26,64.71 219.38,75.59 210.41,75.59 210.3,75.71 210.3,76.01 210.05,76.25 209.47,76.25 209.22,76.01 209.22,75.72 209.11,75.6 208.71,75.6 208.6,75.72 208.6,76.02 208.35,76.27 207.77,76.27 207.52,76.02 207.52,75.71 207.4,75.59 206.96,75.59 206.85,75.71 206.85,76.59 206.6,76.84 205.85,76.84 205.6,76.59 205.6,75.68 205.51,75.59 205.07,75.59 204.98,75.68 204.98,76.59 204.73,76.84 202.47,76.84 202.34,76.71 201.86,76.71
  BOTTOM w0.102: v3(235.79,61.88) v1(235.54,61.08)
M_B_DQS_DN6: length 68.6
  TOP w0.076: CPU1.C42 189.2,72.4 189.2,72.61 189.13,72.78 189.13,72.88 189.18,73.05 189.18,73.29 189.13,73.43 189.13,73.43 189.05,73.63 188.87,73.81 188.87,74.11 189.33,74.57 189.33,75.09 189.34,75.1 189.34,75.12
  TOP w0.102: v3(238.22,67.03) 238.67,67.49 239.11,67.49 239.43,67.81 239.98,67.81 240.09,67.92 DIMM2.32 ; 189.34,75.12 189.34,75.7 189.88,76.23 189.88,77.07 189.62,77.32 189.37,77.32 v4(189.18,77.51)
  L4 w0.114: v3(238.22,67.03) 238.45,66.8 238.45,66.47 238.33,66.36 237.7,66.36 236.51,67.55 233.96,67.55 221.98,79.53 212.94,79.53 211.68,80.79 208.54,80.79 207.68,81.65 194.31,81.65 191.54,78.87 191.14,78.87 189.6,77.33 189.36,77.33 v4(189.18,77.51)
  BOTTOM w0.102: v1(238.09,66.23) v3(238.22,67.03)
M_B_DQS_DN7: length 77.5
  TOP w0.076: v4(186.55,76.16) 187.18,75.54 187.18,73.6 187.17,73.6 187.17,73.1 187.23,72.96 187.23,72.73 187.17,72.56 187.07,71.99 CPU1.D36
  TOP w0.102: DIMM2.11 233.94,73.17 234.02,73.1 234.02,72.92 234.07,72.88 234.71,72.88 235.37,72.22 235.75,72.22 235.85,72.32 235.85,72.68 v3(235.6,72.93)
  L4 w0.114: v3(235.6,72.93) 235.82,73.14 235.82,73.34 235.75,73.41 234,73.41 232.72,74.69 232.72,74.93 232.36,75.29 232.36,75.64 232.68,75.97 232.68,76.08 232.36,76.41 232.24,76.41 231.78,75.95 231.43,75.95 231.02,76.36 231.02,76.71 231.47,77.16 231.47,77.29 231.16,77.6 231.03,77.6 230.71,77.28 230.36,77.28 229.95,77.7 229.95,78.05 230.25,78.35 230.25,78.51 229.97,78.79 229.81,78.79 229.51,78.49 229.16,78.49 224.2,83.45 219.15,83.45 217.29,85.31 191.57,85.31 184.78,78.52 184.78,77.36 185.06,77.08 185.7,77.08 186.03,76.76 186.03,76.03 186.16,75.9 186.26,75.9 v4(186.55,76.16)
  BOTTOM w0.102: v3(235.6,72.93) 235.57,72.96 v1(234.79,72.96)
M_B_DQS_DP0: length 75.4
  TOP w0.076: v4(200.04,57.36) 200.08,57.4 200.08,57.8 199.78,58.1 199.78,58.49 199.1,59.18 194.43,59.18 193.96,59.66 193.77,59.66 193.38,59.5 193.14,59.5 192.98,59.56 192.87,59.56 192.71,59.49 192.46,59.49 CPU1.AH47
  TOP w0.102: DIMM2.200 239.89,23.92 239.73,24.08 238.72,24.08 238.62,23.98 238.62,23.75 v3(238.95,23.43)
  L4 w0.114: v3(238.95,23.43) 238.89,23.43 238.43,22.96 238.1,22.96 237.75,22.61 233.21,22.61 232.59,21.99 228.93,21.99 214.68,36.24 214.68,36.59 215.08,36.99 215.08,37.15 214.8,37.43 214.64,37.43 214.15,36.94 213.8,36.94 213.39,37.36 213.39,37.71 213.72,38.03 213.72,38.2 213.44,38.47 212.85,38.47 212.41,38.91 212.41,39.67 212.8,40.06 212.8,40.22 205.5,47.52 205.5,49.04 202.61,51.93 202.61,54.13 202.18,54.55 202.18,55.18 202.77,55.76 202.77,56.28 202.19,56.86 200.82,56.86 200.32,57.36 v4(200.04,57.36)
  BOTTOM w0.102: v3(238.95,23.43) v1(239.3,22.69)
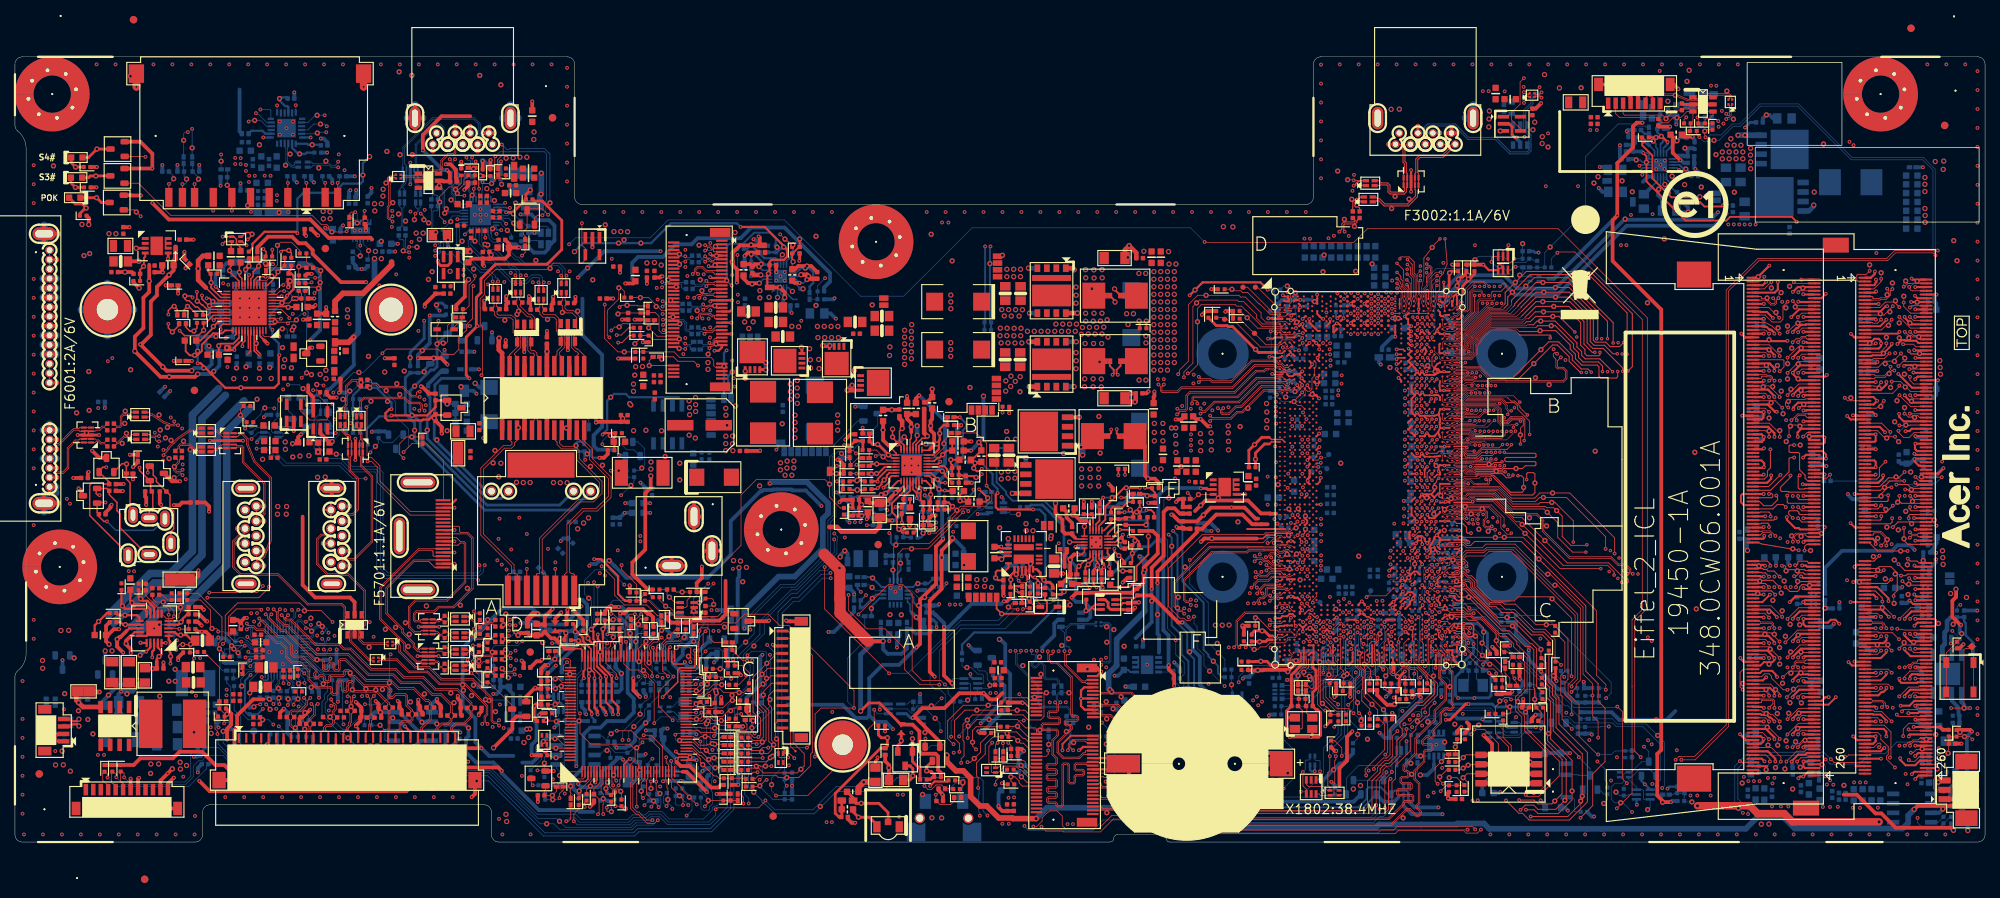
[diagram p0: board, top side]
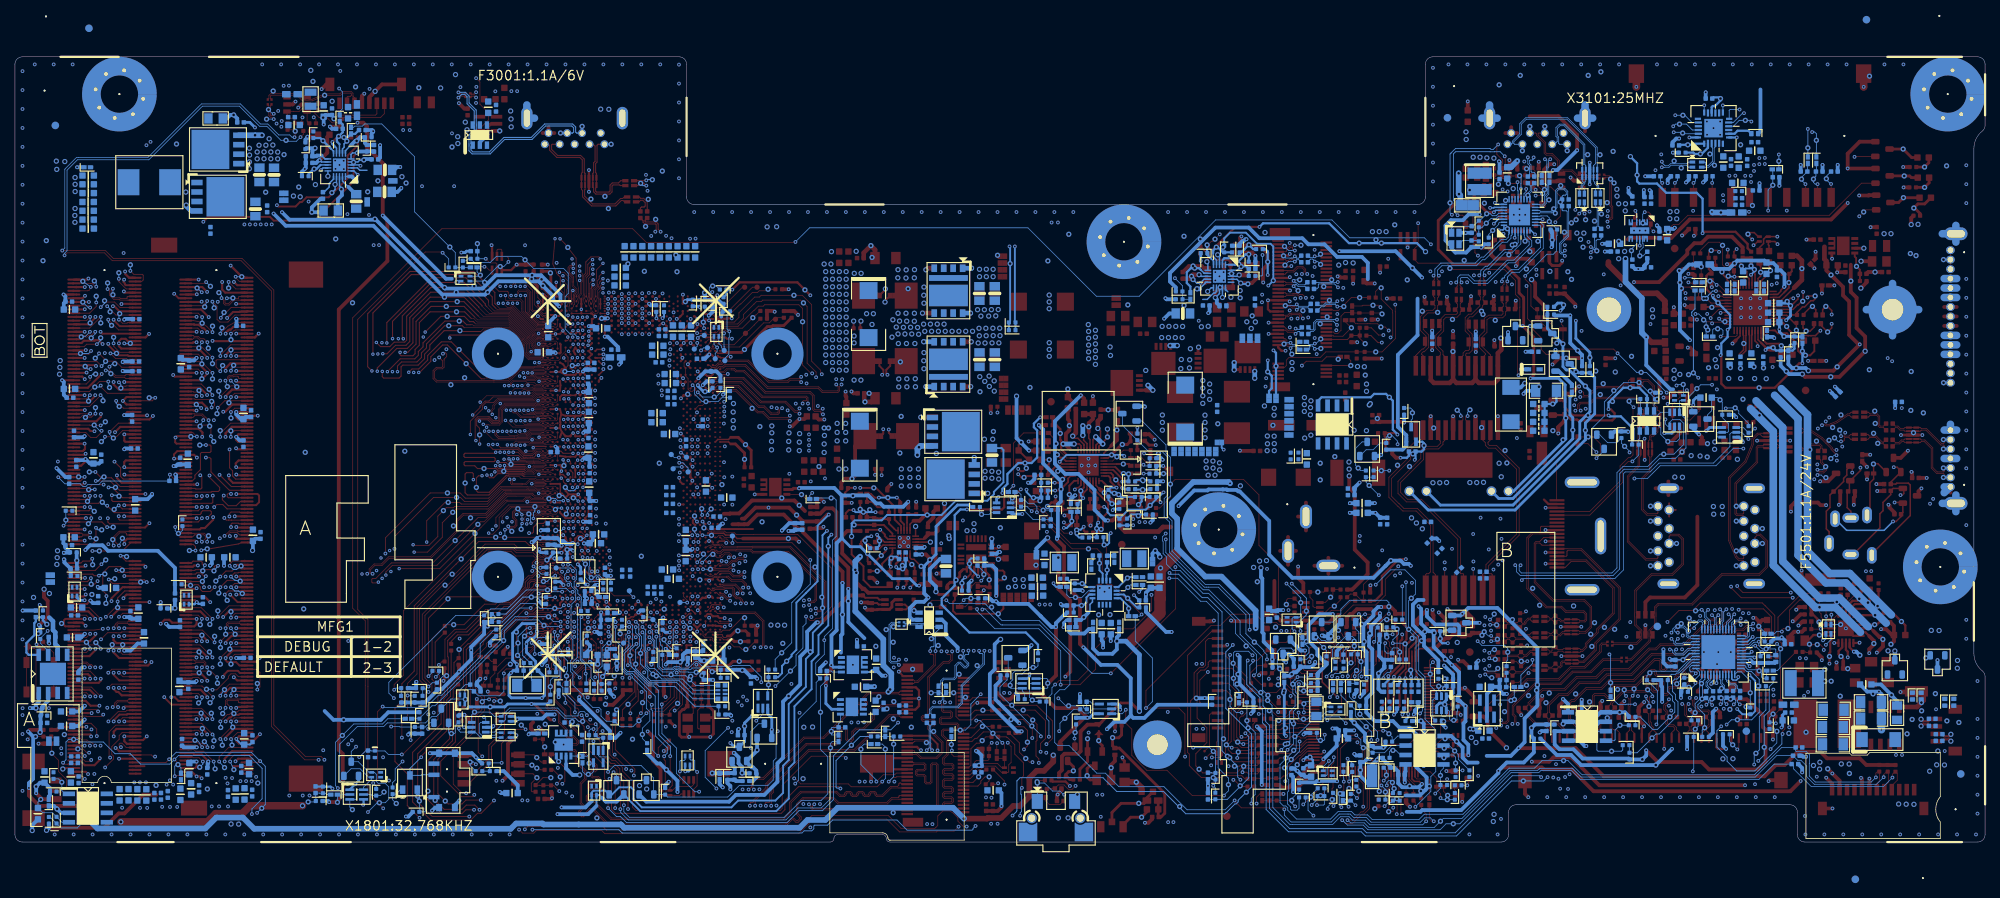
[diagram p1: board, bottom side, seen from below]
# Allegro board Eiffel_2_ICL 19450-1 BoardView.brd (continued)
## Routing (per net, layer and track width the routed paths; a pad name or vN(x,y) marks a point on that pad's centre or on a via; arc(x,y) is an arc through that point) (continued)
M_B_DQS_DP1: length 88
  TOP w0.102: v4(188.49,58.53) 188.47,58.53 188.47,58.51 CPU1.AL41 ; DIMM2.242 240.26,13.42 239.62,13.42 v3(238.91,12.71)
  L4 w0.089: 190.95,52.56 190.95,52.58 190.97,52.6 190.97,54.94 190.86,55.05 190.86,56.96 190.36,57.46 190.36,57.67 190.04,58 189.1,58 188.57,58.53 v4(188.49,58.53)
  L4 w0.114: 190.95,52.56 190.95,50.2 191.51,49.64 191.51,47.21 194.2,44.52 197.96,44.52 200.98,41.49 200.98,40.22 203.9,37.3 203.9,34.36 207.29,30.97 211.19,27.08 211.19,27.07 211.76,26.51 212.35,25.91 212.35,22.55 212.7,22.2 213.92,22.2 216.85,19.27 216.85,18.47 217.52,17.8 220.47,17.8 226.48,11.79 227.75,11.79 228,12.04 228.39,12.04 228.51,11.93 228.51,11.67 228.75,11.42 229.34,11.42 229.58,11.67 229.58,11.93 229.7,12.04 234.81,12.04 235.38,11.47 235.9,11.47 236.15,11.72 236.15,11.96 236.32,12.14 236.65,12.14 236.77,12.02 236.77,11.61 237.02,11.36 238.51,11.36 238.91,11.76 v3(238.91,12.71)
  BOTTOM w0.102: v3(238.91,12.71) 239.41,13.49 239.56,13.64 v1(239.87,13.64)
M_B_DQS_DP2: length 73.6
  TOP w0.076: v4(197.81,61.21) 197.63,61.39 197.63,61.56 197.26,61.93 195.59,61.93 195.47,62.05 194.33,62.05 194.06,62.32 193.55,62.32 193.4,62.17 193.17,62.17 193.03,62.23 192.8,62.23 192.63,62.17 192.51,62.17 192.26,62.12 CPU1.AC46
  TOP w0.102: DIMM2.179 233.74,29.17 233.87,29.3 235.37,29.3 235.47,29.19 235.47,29.03 235.12,28.67 v3(235.05,28.67)
  L4 w0.114: v4(197.81,61.21) 197.73,61.13 197.73,60.92 197.84,60.82 202.63,60.82 205.22,58.23 205.22,55.17 213.66,46.73 213.66,45.21 220.03,38.85 220.03,38.85 223.3,35.57 223.91,34.96 223.91,33.19 224.22,32.88 224.41,32.88 225.01,33.48 225.39,33.48 225.78,33.09 225.78,32.71 225.19,32.11 225.19,31.94 225.46,31.67 225.63,31.67 226.23,32.26 226.61,32.26 227.01,31.86 227.01,31.48 226.4,30.87 226.4,30.7 226.67,30.43 226.85,30.43 227.45,31.03 227.8,31.03 228.22,30.61 228.22,30.26 227.68,29.72 227.68,29.55 227.94,29.29 228.17,29.29 228.61,29.74 229.11,29.74 230.25,28.59 233.75,28.59 234.33,28.02 235.28,28.02 235.37,28.11 235.37,28.36 v3(235.05,28.67)
  BOTTOM w0.102: v3(235.05,28.67) v1(234.49,27.86)
M_B_DQS_DP3: length 82.6
  TOP w0.102: DIMM2.221 233.96,18.67 234.02,18.74 234.02,18.89 234.1,18.97 235.49,18.97 235.58,18.89 235.58,18.55 235.07,18.04 v3(235.07,17.99) ; v4(189.17,62.19) CPU1.AD41
  L4 w0.089: 194.36,50.23 194.36,50.24 194.34,50.26 194.34,50.77 193.48,51.63 193.48,51.98 193.54,52.04 193.54,53.86 193.37,54.03 193.37,54.43 193.54,54.61 193.54,56.26 193.08,56.73 193.08,59.88 191.5,61.46 189.62,61.46 189.46,61.62 189.46,61.9 v4(189.17,62.19)
  L4 w0.114: v3(235.07,17.99) 235.26,17.8 235.26,17.6 235.18,17.52 226.67,17.52 226.41,17.78 226.41,17.98 226.8,18.37 226.8,18.72 226.38,19.13 226.03,19.13 225.65,18.75 225.49,18.75 225.21,19.03 225.21,19.19 225.59,19.57 225.59,19.92 225.18,20.34 224.83,20.34 224.44,19.95 224.28,19.95 224,20.23 224,20.39 224.39,20.78 224.39,21.13 223.98,21.54 223.59,21.54 223.19,21.14 223.03,21.14 217.2,26.97 217.2,27.23 208.02,36.41 208.02,39.01 206.11,40.92 206.11,41.72 200.49,47.34 199.63,47.34 198.99,47.98 196.89,47.98 196.72,48.16 196.23,48.16 195.84,48.55 195.84,49.11 195.23,49.71 194.67,49.71 194.36,50.03 194.36,50.23
  BOTTOM w0.102: v1(234.66,17.23) v3(235.07,17.99)
M_B_DQS_DP4: length 63.5
  TOP w0.076: v4(196.88,73.29) 196.69,73.48 196.69,73.82 196.47,74.03 195.44,74.03 195.07,73.67 195.07,71.13 193.75,69.81 193.34,69.81 193.17,69.82 193.03,69.87 192.8,69.87 192.63,69.81 192.51,69.81 192.26,69.76 CPU1.H46
  TOP w0.102: DIMM2.76 240.16,56.92 239.89,57.19 238.96,57.19 238.63,56.86 238.63,56.71 v3(238.77,56.57)
  L4 w0.089: v4(196.88,73.29) 196.88,73.53 196.88,73.54 196.88,73.56 196.99,73.67 199.12,73.67 201.29,71.5 204.18,71.5 204.2,71.48 204.22,71.48
  L4 w0.114: v3(238.77,56.57) 238.62,56.43 238.62,56.43 238.51,56.31 238.51,56.12 238.26,55.87 237.04,55.87 236.58,56.33 233.19,56.33 232.56,56.97 232.56,57.78 232.07,58.27 230.83,58.27 217.63,71.48 204.22,71.48
  BOTTOM w0.102: v3(238.77,56.57) v1(239.19,55.76)
M_B_DQS_DP5: length 66.3
  TOP w0.102: v3(235.08,61.88) 235.2,61.88 235.33,62 235.33,62.25 235.2,62.38 234.71,62.38 234.63,62.47 234.15,62.47 234.07,62.39 234.07,62.26 233.99,62.17 DIMM2.55 ; v4(188.56,69.55) 188.56,69.55 188.91,69.19 CPU1.J41
  L4 w0.089: 201.86,76.48 201.83,76.48 201.81,76.5 195.44,76.5 192.27,73.33 192.27,72.12 190,69.85 188.85,69.85 v4(188.56,69.55)
  L4 w0.114: 201.86,76.48 202.44,76.48 202.57,76.61 204.63,76.61 204.75,76.5 204.75,75.59 204.97,75.36 205.6,75.36 205.83,75.59 205.83,76.5 205.94,76.61 206.5,76.61 206.62,76.5 206.62,75.61 206.87,75.37 207.5,75.37 207.75,75.61 207.75,75.93 207.86,76.04 208.25,76.04 208.37,75.93 208.37,75.62 208.62,75.37 209.2,75.37 209.45,75.62 209.45,75.91 209.56,76.02 209.96,76.02 210.07,75.91 210.07,75.61 210.32,75.36 219.29,75.36 230.17,64.49 231.16,64.49 232.22,63.43 232.67,63.43 233.64,62.46 235.12,62.46 235.31,62.28 235.31,62.11 v3(235.08,61.88)
  BOTTOM w0.102: v1(234.27,61.06) v3(235.08,61.88)
M_B_DQS_DP6: length 68.7
  TOP w0.076: CPU1.D42 189.12,71.82 189.12,72.02 189.02,72.13 189.02,72.6 188.95,72.78 188.95,72.89 189.02,73.08 189.02,73.25 188.92,73.51 188.69,73.74 188.69,74.18 189.15,74.65 189.15,75.09 189.14,75.1 189.14,75.12
  TOP w0.102: v3(238.94,67.03) 239.52,67.61 240,67.61 240.18,67.42 DIMM2.34 ; v4(189.18,76.93) 189.37,77.12 189.54,77.12 189.67,76.98 189.67,76.32 189.14,75.78 189.14,75.12
  L4 w0.114: v4(189.18,76.93) 189.36,77.1 189.69,77.1 191.23,78.64 191.63,78.64 194.41,81.42 207.59,81.42 208.44,80.56 211.58,80.56 212.85,79.3 221.88,79.3 233.86,67.32 236.42,67.32 237.61,66.13 238.43,66.13 238.68,66.38 238.68,66.77 v3(238.94,67.03)
  BOTTOM w0.102: v1(239.35,66.26) v3(238.94,67.03)
M_B_DQS_DP7: length 77.2
  TOP w0.076: v4(186.52,75.38) 187,74.9 187,73.6 187.01,73.6 187.01,73.07 187.06,72.93 187.06,72.76 187.01,72.61 CPU1.C36
  TOP w0.102: v3(236.31,72.95) 236.06,72.69 236.06,72.24 235.84,72.01 235.28,72.01 234.62,72.67 DIMM2.13
  L4 w0.114: v4(186.52,75.38) 186.25,75.67 186.07,75.67 185.8,75.94 185.8,76.66 185.61,76.85 184.96,76.85 184.56,77.26 184.56,78.61 191.48,85.53 217.39,85.53 219.24,83.68 224.29,83.68 229.25,78.72 229.41,78.72 229.72,79.02 230.07,79.02 230.48,78.61 230.48,78.26 230.18,77.95 230.18,77.79 230.46,77.51 230.62,77.51 230.94,77.83 231.26,77.83 231.7,77.39 231.7,77.07 231.25,76.61 231.25,76.45 231.53,76.17 231.69,76.17 232.15,76.63 232.46,76.63 232.91,76.18 232.91,75.87 232.59,75.54 232.59,75.38 232.95,75.02 232.95,74.78 234.1,73.63 235.85,73.63 236.05,73.43 236.05,73.22 v3(236.31,72.95)
  BOTTOM w0.102: v1(236.67,73.68) 236.31,73.33 v3(236.31,72.95)
M_B_ODT0: length 71.5
  TOP w0.114: CPU1.V43 190.35,64.78 190.46,64.89 v4(190.46,64.92)
  TOP w0.14: v3(236.48,34.17) 235.56,35.09 233.72,35.09 233.64,35.17 DIMM2.155
  L4 w0.089: 202.94,64.05 202.71,64.28 202.71,64.29 202.55,64.45 202.55,65.6 200.22,67.93 196.48,67.93 194.03,65.48 192.36,65.48 191.79,64.92 v4(190.46,64.92)
  L4 w0.165: 202.94,64.05 208.97,58.02 208.97,56.89 223.08,42.78 223.08,41.25 229.94,34.39 230.34,34.39 230.51,34.56 230.51,34.92 230.67,35.08 230.99,35.08 231.16,34.92 231.16,34.62 231.32,34.45 231.74,34.45 231.9,34.62 231.9,34.99 232.07,35.15 232.54,35.15 232.71,34.99 232.71,34.44 232.87,34.27 233.52,34.27 234.11,33.68 236.31,33.68 236.48,33.85 v3(236.48,34.17)
  BOTTOM w0.14: v1(236.69,33.39) v3(236.48,34.17)
M_B_ODT1: length 68.4
  TOP w0.114: CPU1.V38 187.65,64.47 v4(187.89,64.05)
  TOP w0.14: DIMM2.161 235.39,33.67 v3(235.88,33.18)
  L4 w0.089: v4(187.89,64.05) 188.21,64.38 191.95,64.38 192.6,65.02 196.29,65.02 198.15,63.16 200.11,63.16 200.26,63.31 201.81,63.31
  L4 w0.165: 201.81,63.31 203.32,63.31 208.52,58.11 208.52,56.71 222.64,42.6 222.64,41.07 229.9,33.8 233.03,33.8 234.15,32.68 235.38,32.68 v3(235.88,33.18)
  BOTTOM w0.14: v1(235.56,32.41) v3(235.88,33.18)
M_B_PARITY: length 72.9
  TOP w0.114: CPU1.P38 187.88,66.58 v4(187.88,66.75)
  TOP w0.14: v3(239.03,39.13) 234.04,39.98 233.6,40.17 DIMM2.143
  L4 w0.089: v4(187.88,66.75) 188.26,67.12 190.54,67.12 190.94,67.53 191.5,67.53 192.08,68.11 192.08,68.33 193.11,69.36 201.79,69.36 204.81,66.34
  L4 w0.165: v3(239.03,39.13) 239.03,39.12 238.78,38.87 233.29,38.87 232.38,39.78 231.14,39.78 215.31,55.61 212.44,58.48 212.33,58.48 204.81,66 204.81,66.34
  BOTTOM w0.14: v1(238.23,39.32) v3(239.03,39.13)
M_VREF_CA_DIMMB: length 3.6
  TOP w0.305: v3(237.83,32.17) 238.58,32.93 DIMM2.164
  vias: v1(240.47,34.42)
M_VREF_DQ_DIMMA: length 1.7
  TOP w0.279: v3(254.51,33.2) 254.79,32.93 255.86,32.93
  TOP w0.305: DIMM1.164 255.86,32.93
  vias: v1(253.69,33.2)
MCT1: length 7.4
  TOP w0.61: XF3101.10 v3(74.28,57.1) ; XF3101.7 v3(71.28,57.1) ; XF3101.4 v3(68.28,57.1) ; XF3101.1 v3(65.28,57.1)
  vias: v1(67.47,55.58) v1(73.89,55.52)
ME_CNTL1: length 3.1
  BOTTOM w0.102: Q1901.1 212.32,7.03 212.93,6.43 R1914.1 213.42,6.4 213.42,5.69 v1(212.9,5.17)
ME_CNTL2: length 6.8
  BOTTOM w0.102: MFG1.1 208.69,6.02 209,5.71 209,4.15 209.1,4.05 R1915.1 v1(209.81,5.5) 209.81,5.98 210.08,6.25 Q1901.2
ME_UNLOCK: length 49.6
  TOP w0.102: v3(183.64,11.72) 183.91,12 183.91,14.68 183.91,14.68 183.91,16.03 183.65,16.29 R2031.2 183.66,16.5 183.66,17.46 v1(183.38,17.74) 181,20.12 181,23.1 180.87,23.23 180.87,25.39 CPU1.DU24
  L3 w0.127: v3(212.05,10.8) 210.41,12.44 203.63,12.44 202.85,13.23 196.56,13.23 195.73,12.4 190.01,12.4 189.34,11.72 v3(183.64,11.72)
  BOTTOM w0.102: v3(212.05,10.8) 213.05,9.81 213.05,8.31 213.39,7.97 R1914.2
MIC_CAP: length 4.1
  TOP w0.203: U2701.19 31.22,75.93 v3(31.37,76.07)
  BOTTOM w0.254: v3(31.37,76.07) 30.91,76.53 v1(30.91,76.78) 31.06,76.92 32.06,76.92 C2713.1
MINI1_WAKE#: length 11.2
  TOP w0.114: v3(146.91,8.1) 146.35,8.66 145.96,8.66 145.87,8.75 NGFFE1.55
  BOTTOM w0.114: R6111.1 148.4,14.16 R6105.2 147.37,14.15 R6112.1 v1(146.25,13.13) 146.25,8.76 v3(146.91,8.1)
MINI_CLKREQ#_WLAN_C: length 11.6
  TOP w0.102: NGFFE1.53 145.88,9.25 146.11,9.03 147.64,9.03 v3(148.56,8.1)
  BOTTOM w0.102: v3(148.56,8.1) 148.56,8.31 150.64,10.38 v1(150.64,12.45) 150.64,12.71 150.21,13.13 R6107.1
MODE_CFG0: length 6.6
  TOP w0.114: R5611.1 38.21,23.18 v3(38.77,22.62)
  BOTTOM w0.114: TSMT1.47 39.31,23.67 39.57,23.42 39.57,22.95 39.45,22.83 38.98,22.83 v3(38.77,22.62) 39.35,22.04 R5612.1 40.49,22.04 v1(41.31,21.22)
MODE_CFG1: length 6.1
  TOP w0.114: v3(38.81,21.33) 38.07,21.33 v1(38,21.26) 38,20.99 38.48,20.51 R5617.1
  BOTTOM w0.114: TSMT1.48 38.27,22.8 38.27,22.4 38.81,21.86 v3(38.81,21.33) 38.81,21.15 R5618.1
PB_IN_N_1: length 25.4
  TOP w0.102: v3(85.49,26.06) 85.51,26.06 85.51,26.06 85.6,25.98 ECIO1.72
  L4 w0.127: v3(85.49,26.06) 85.51,26.06 85.51,26.06 86.48,25.09 92.73,25.09 92.77,25.13 98.08,25.13 v3(98.17,25.04)
  BOTTOM w0.102: R24016.2 85.98,24.19 C2418.2 85.98,25.59 85.51,26.06 85.51,26.06 v3(85.49,26.06) ; R24058.1 99.99,20.33 100.72,21.06 v1(100.72,21.95) 100.72,25.37 100.5,25.59 98.71,25.59 v3(98.17,25.04)
PCH_D1_SST: length 7.7
  TOP w0.102: R24095.1 v1(96.14,18.99) 95.86,18.99 94.86,17.99 93.64,17.99 93.56,17.91 91.14,17.91 91.01,17.78 ECIO1.50
PCH_DPWROK: length 119.5
  TOP w0.102: R1726.1 200.72,22.82 C1705.1 200.73,22.17 v3(200.95,21.95) 200.95,21.68 201.2,21.43 R1727.2 ; R24023.2 v1(94.5,23.23) 94.97,23.23 R24110.1 95.98,22.22 v3(95.98,21.89)
  L3 w0.127: v3(180.02,20.13) 180.09,20.06 181.36,20.06 182.69,21.4 191.7,21.4 192.83,22.52 196.69,22.52 197.31,23.14 199.76,23.14 v3(200.95,21.95) ; v3(159.95,21.21) 158.87,20.13 156.29,20.13 155.25,19.09 144.58,19.09 143.22,17.73 137.14,17.73 136.27,18.6 135.77,18.6 135.23,19.13 133.52,19.13 133.19,18.8 123.8,18.8 122.74,19.87 122.21,19.87 121.75,20.32 119.46,20.32 118.92,19.78 115.63,19.78 115.01,20.4 107.01,20.4 105.69,21.72 96.15,21.72 v3(95.98,21.89)
  L4 w0.127: v3(180.02,20.13) 179.98,20.17 179.98,21 178.04,22.94 175.94,22.94 175.66,23.21 174.95,23.21 174.58,22.84 161.58,22.84 v3(159.95,21.21)
PCH_DPWROK_EC: length 7
  TOP w0.102: R24023.1 92.59,23.19 92.59,21.9 91.94,21.26 v3(91.94,21.17) 91.35,20.58 ECIO1.57
  BOTTOM w0.102: v3(91.94,21.17) 91.94,20.41 91.8,20.26 v1(91.31,20.26) R24048.1
PCH_DPWROK_R: length 12.6
  TOP w0.102: R1727.1 200.31,21.99 199.69,22.61 R1722.2 199.53,23.32 198.18,24.67 197.01,24.67 v1(196.65,25.03) 195.61,26.07 194.79,26.07 194.36,26.5 194.36,27.16 194.07,27.45 194.05,27.45 194.03,27.48 193.69,27.48 193.39,27.77 193.08,27.77 192.92,27.61 192.92,27.18 CPU1.DR48
PCH_JTAG_TCK: length 1.6
  TOP w0.102: CPU1.R5 172,65.87 v3(172.06,65.93)
  BOTTOM w0.102: TP9910.1 171.71,66.28 v3(172.06,65.93)
PCH_JTAG_TDO: length 9.9
  TOP w0.102: v3(168.27,68.49) 168.66,68.49 168.83,68.65 169.65,68.65 169.95,68.35 CPU1.K2 CPU1.K3
  BOTTOM w0.102: R311.2 168.19,71.17 168.58,70.78 168.58,68.79 v3(168.27,68.49) 168.27,67.72 168.33,67.67 168.33,65.42 168.87,64.88 TP9909.1
PCH_OPI_RCOMP: length 7.9
  TOP w0.102: 170.86,24.02 170.96,24.13 170.96,24.69 171.12,24.86 171.12,25.18 170.78,25.52 CPU1.DU3
  TOP w0.381: 170.86,24.02 170.54,23.71 168.29,23.71 167.77,24.23 v1(166.94,24.23) 166.27,24.23 166.23,24.19 R310.2
PCH_PWROK: length 96.2
  L4 w0.127: v3(188.96,17.4) 189.04,17.32 189.04,16.37 188.76,16.09 188.37,16.09 188.1,15.82 188.1,14.49 181.69,8.08 180.6,8.08 180.54,8.14 180.07,8.14 179.86,7.93 178.41,7.93 177.7,7.22 170.04,7.22 v3(170,7.18) ; v3(126.53,14.16) 126.79,14.42 128.01,14.42 128.69,13.74 129.59,13.74 130.08,14.23 133.18,14.23 134.25,13.15 136.18,13.15 136.55,12.79 152.2,12.79 153.49,14.08 159,14.08 160.93,16.01 163.59,16.01 163.9,15.7 167.24,15.7 167.62,15.32 v3(168.44,15.32)
  BOTTOM w0.102: R1720.1 190.09,19.8 188.96,18.67 v3(188.96,17.4) ; Q4007.D 130.9,23.01 131.06,22.85 131.06,22.37 R4044.1 131.04,21.74 132,20.78 132,19.82 v1(127.73,15.55) 126.53,14.35 v3(126.53,14.16) ; v3(170,7.18) 171.51,8.69 171.51,12.25 v3(168.44,15.32)
PCH_PWROK_C_1: length 7.4
  BOTTOM w0.102: R4026.2 128.68,19.93 129.01,20.26 Q4009.6 130.53,20.62 130.64,20.72 v1(130.64,21.01) 130.64,21.41 130.29,21.76 130.29,22.62 129.96,22.95 129.23,22.95 129,23.19 Q4007.G
PCH_PWROK_C_2: length 4.3
  BOTTOM w0.102: R4013.2 127.47,18.83 v1(127.68,19.04) 128.05,19.41 128.05,21.18 127.96,21.27 Q4009.2
PCH_PWROK_C_3: length 6
  BOTTOM w0.102: Q4009.5 129.76,21.27 129.82,21.33 129.82,22.27 129.56,22.52 129.03,22.52 128.14,23.41 v1(127.56,23.41) 127.13,23.41 126.91,23.63 R4027.2
PCH_PWROK_R: length 7.8
  TOP w0.102: v3(191.26,27.69) 191.46,27.49 CPU1.DN47
  BOTTOM w0.102: R1720.2 v1(190.09,22.26) 190.09,22.8 189.96,22.94 189.96,24.3 R1729.2 190.72,25.09 190.72,25.68 191.02,25.98 191.02,26.79 191.26,27.03 v3(191.26,27.69)
PCH_RTCRST_DOWN: length 8.7
  TOP w0.102: CMOS1.4 CMOS1.2 258.8,25.37 259.65,26.22 259.67,26.22 260.21,26.76 R2531.1 260.87,27.51 v1(260.87,27.95)
PCH_SUSCLK_WLAN: length 6.7
  TOP w0.114: NGFFE1.50 136.2,10 135.9,10.3 135.9,12.51 135.15,13.26 134.73,13.26 v1(134.39,13.61) 133.88,14.11 R6108.2
PCH_THERMTRIP: length 10.1
  TOP w0.102: CPU1.E3 170.26,70.52 169.7,70.52 169.63,70.45 169.38,70.45 169.1,70.73 168.22,70.73 166.8,72.15 166.73,72.15 165.19,73.69 164.49,73.69 164.26,73.93 163.35,73.93 163.14,74.13 v1(163.07,74.13) R302.2
PCIE_RCOMPN: length 5
  TOP w0.127: CPU1.DN1 169.82,27.81 169.24,27.81 169.18,27.75 169.18,27.62 169,27.43 168.73,27.43 168.53,27.63
  TOP w0.381: R1601.2 165.72,27.94 166.1,28.32 v1(167.13,28.32) 167.42,28.32 168.11,27.63 168.53,27.63
PCIE_RCOMPP: length 5.1
  TOP w0.127: CPU1.DN3 169.9,27.45 169.36,27.45 169.03,27.12 168.47,27.12
  TOP w0.381: R1601.1 165.74,26.9 166.76,26.9 v1(166.79,26.87) 166.82,26.9 167.6,26.9 167.83,27.12 168.47,27.12
PCIE_WAKE#: length 197.1
  TOP w0.089: CPU1.DL45 191.28,28.57 191.67,28.18 191.7,28.18 191.7,28.18 v3(191.69,28.18)
  TOP w0.114: R6301.1 82.24,68.96 81.26,67.99 v3(80.63,67.99) ; v3(190.24,18.67) 189.52,17.94 189.52,17.09 189.5,17.08 189.5,17.06 189.23,16.79 189.02,16.79 187.73,15.5 187.73,15.1 186.97,14.33 186.97,12.2 184.98,10.22 184.98,8.48 184.52,8.02 v3(184.52,4.56)
  L4 w0.127: v3(99.62,17.36) 101.8,17.36 102.75,16.41 106.15,16.41 106.51,16.05 112.17,16.05 113.88,14.33 118.23,14.33 119.23,15.33 121.24,15.33 121.92,16.01 125.14,16.01 126.52,17.39 133.86,17.39 134.46,16.78 137.27,16.78 138.04,16.01 v3(145.66,16.01) ; v3(80.63,67.99) 80.63,67.44 80,66.81 80,51.43 79,50.44 79,48.33 79.58,47.75 79.58,37.78 80.1,37.26 80.1,36.59 80.47,36.22 80.47,33.72 81.84,32.35 84.14,32.35 86.73,29.76 87.51,29.76 88,29.27 89.53,29.27 91.5,27.3 98.8,27.3 100.14,25.96 100.93,25.96 101.17,25.72 v3(101.17,25.1)
  BOTTOM w0.114: v3(191.69,28.18) 191.69,27.16 191.23,26.7 191.23,24.65 190.86,24.28 190.86,22.02 191.13,21.74 R1716.1 190.57,20.69 190.57,19.76 190.24,19.44 v3(190.24,18.67) ; v3(184.52,4.56) 183.38,3.41 182.85,3.41 182.04,2.6 160.53,2.6 158.92,4.21 155.79,4.21 154.3,5.7 154.3,11.57 150.83,15.05 R6105.1 146.63,15.05 v3(145.66,16.01) ; v3(99.62,17.36) 100.35,17.36 101.17,18.19 v1(101.17,19.11) 101.17,20.38 101.28,20.49 101.28,24.99 v3(101.17,25.1)
PCIRST1#: length 13.8
  TOP w0.102: v3(87.27,11.37) 87.27,10.63 87.6,10.31 ECIO1.30 87.6,8.5 87.97,8.13 87.97,7.3 v1(89.05,6.21) 89.52,5.74 v3(89.52,4.95)
  BOTTOM w0.102: R24008.1 88.54,6.16 R24106.2 88.54,5.07 88.65,4.95 v3(89.52,4.95) ; v3(87.27,11.37) 87.27,10.88 88.17,9.98 88.17,9.01 88.27,8.91 RN2405.2
PCIRST2#: length 10
  TOP w0.089: 88,8.6 ECIO1.31
  TOP w0.102: ECIO1.31 88,10.8 v3(87.92,10.88) ; 88,8.6 89.4,7.2 89.4,7 v1(90.37,6.03) v3(91.36,5.04)
  BOTTOM w0.102: v3(91.36,5.04) 91.08,5.32 91.08,5.67 91.04,5.71 R24105.1 ; RN2405.1 88.68,10.12 v3(87.92,10.88)
PCIRST_LAN#: length 5.4
  TOP w0.102: R3115.1 R3114.1 61.63,89.41 C3128.1 61.63,87.73 v3(61.49,87.58) 61.49,86.89 61.33,86.74 v1(61.27,86.74)
  BOTTOM w0.102: LAN1.19 61.78,86.96 61.49,87.26 v3(61.49,87.58)
PECI_EC: length 114.7
  TOP w0.102: v3(157.99,30.24) 157.46,29.71 156.96,29.71 156.66,30.01 156.13,30.01 154.59,31.55 154.59,36.74 159.12,41.26 165,41.26 165.01,41.25 167.36,41.25 167.58,41.47 168.68,41.47 168.9,41.7 170.31,41.7 170.33,41.72 170.63,41.72 170.68,41.67 170.93,41.67 171.24,41.98 CPU1.CD5 ; R24002.1 92.75,18.99 93.05,19.29 v3(93.05,19.59)
  L3 w0.127: v3(93.05,19.59) 93.66,18.99 94.84,18.99 95.72,19.88 104.93,19.88 106.51,18.29 111.37,18.29 112.78,16.89 116.11,16.89 117.27,18.04 122.41,18.04 123.17,17.28 132.02,17.28 132.44,16.86 135.38,16.86 136.03,16.2 144.03,16.2 144.98,17.16 148.88,17.16 149.29,17.56 155.88,17.56 156.92,18.61 159.79,18.61 v3(162.1,20.91)
  BOTTOM w0.102: v3(162.1,20.91) v1(160.08,22.93) 159.33,23.68 159.33,25.1 158.4,26.03 158.4,28.9 157.99,29.31 v3(157.99,30.24)
PECI_EC_R: length 5.9
  TOP w0.102: ECIO1.51 90.91,18.18 91.53,18.8 R24002.2 92.39,18.27 93.38,18.27 93.75,18.65 C2417.1 93.76,19.43 93.99,19.66 v1(93.99,19.98)
PLT_RST#: length 419.1
  TOP w0.102: v3(159.41,80.48) 159.5,80.38 179.37,80.38 181.23,82.25 206.79,82.25 218.74,70.3 218.74,31.36 217.05,29.66 217.05,20.98 217.05,12.18 v3(217.86,11.38) ; R24064.2 96.59,17.08 96.69,17.18 v3(97.32,17.18) ; R3114.2 60.16,88.83 60.16,88.21 59.28,87.32 v1(59.28,86.98) 59.57,86.69 v3(60.22,86.69) ; v3(212.16,11.74) 212.04,11.74 209.59,14.19 209.59,18.44 208.12,19.91 208.12,21.07 209.06,22.01 209.06,30.39 200.47,38.98 197.52,38.98 196.89,38.35 194.5,38.35 194.22,38.08 193.84,38.08 193.68,37.92 192.99,37.92 CPU1.CM49
  L3 w0.127: v3(60.22,86.69) 59.1,86.69 54.65,82.23 53.45,82.23 52.27,81.05 52.27,77.15 51.24,76.13 v3(51.1,76.13)
  L4 w0.127: v3(51.1,76.13) 51.38,76.13 55.78,71.73 57.09,71.73 57.37,71.46 57.37,69.75 53.05,65.43 53.05,55.7 53.47,55.28 53.47,51.85 57.02,48.31 57.02,30.87 58.86,29.03 58.86,23.79 64.67,17.98 66.17,17.98 68.71,15.43 70.05,15.43 71.15,14.34 78.02,14.34 79.87,16.19 82.72,16.19 82.92,16.4 87.11,16.4 87.64,15.86 95.62,15.86 96.94,17.18 v3(97.32,17.18) ; v3(60.22,86.69) 60.8,87.27 60.8,87.7 66.03,92.93 68.31,92.93 70.37,90.86 70.37,87.33 73.4,84.31 73.4,81.28 74.26,80.42 v3(74.26,80.16)
  BOTTOM w0.102: v3(217.86,11.38) 216.97,12.27 EC1720.1 216.31,12.27 216.26,12.22 D6903.1 214.43,12.22 213.95,11.74 v3(212.16,11.74) ; v3(159.41,80.48) 157.52,82.37 128.26,82.37 119.08,73.19 113.34,73.19 103.1,83.43 87.52,83.43 85.12,81.03 75.13,81.03 v3(74.26,80.16)
PLT_RST_N_SSD: length 9.9
  TOP w0.102: v1(80.81,70.82) 80.94,70.95 C6301.1 83.84,70.95 D6301.1 84.76,70.95 R6303.2 85.82,71 86.31,70.51 86.31,68.62 86.74,68.19 87.12,68.19 87.33,68.4 NGFFM1.50
PLT_WLAN_RST#: length 66.6
  TOP w0.102: NGFFE1.52 136.01,9.5 135.41,10.1 135.41,10.7 135.18,10.93 133.63,10.93 133.48,11.08 R6120.1 133.48,11.54 C6103.1 133.48,12.94 v3(133.11,13.31)
  L4 w0.127: v3(91.85,13.49) 94.86,13.49 97.32,15.95 97.83,15.95 97.83,15.95 101.41,15.95 102.28,15.08 103.96,15.08 104.86,14.18 106.48,14.18 109.82,10.84 111.95,10.84 114.3,13.19 115.59,13.19 116.61,12.17 124.04,12.17 125.47,13.6 127.18,13.6 127.42,13.36 129.63,13.36 129.63,13.35 129.74,13.35 130.24,13.84 132.57,13.84 v3(133.11,13.31)
  BOTTOM w0.102: v3(91.85,13.49) 91.85,13.49 91.85,13.49 91.85,12.2 v1(92.98,11.07) 93.51,10.54 93.51,8.54 93.31,8.35 93.31,6.85 93.49,6.68 93.49,5.12 93.09,4.72 93.09,4.41 92.95,4.27 92.19,4.27 91.93,4.54 91.93,5.51 91.91,5.53 91.91,5.97 R24105.2
PLTRST_LAN_N: length 129.9
  TOP w0.102: v3(57.58,83.12) 57.58,83.25 56.91,83.92 v1(56.91,85.82) 56.91,86.58 58.19,87.86 59.31,87.86 59.81,88.36 ED6902.2 60.04,89.4 60.31,89.67 60.31,89.99 R3115.2
  L3 w0.127: v3(48.83,74.65) 49.62,75.44 51.52,75.44 53.31,77.23 53.31,78.85 v3(57.58,83.12)
  L4 w0.127: v3(90.23,4.96) 90.23,5.13 88.47,6.89 82.16,6.89 82.14,6.91 75.1,6.91 73.49,5.29 72.83,5.29 72.21,5.91 68.81,5.91 67.22,7.5 67.22,9.96 65.51,11.67 62.75,11.67 60.89,13.52 59.63,13.52 56.07,17.08 56.07,20.03 54.42,21.67 54.42,25.92 47.61,32.74 47.61,49.27 48.91,50.57 48.91,58.3 48.03,59.18 48.03,66.01 47.02,67.02 47.02,72.83 v3(48.83,74.65)
  BOTTOM w0.102: R24106.1 89.43,5.77 89.78,5.41 89.79,5.41 90.06,5.14 90.06,5.14 v3(90.23,4.96)
PLTRST_N_SIO: length 6.3
  TOP w0.102: R24064.1 95.45,16.3 v1(94.65,16.3) 93.61,16.3 93.09,16.81 92.59,16.81 92.01,16.23 91.23,16.23 91.19,16.18 ECIO1.46
PLTRST_SSD: length 147.9
  TOP w0.102: R6303.1 83.47,71.89 83.38,71.98 v1(82.02,71.98) 81.27,71.98 v3(81.02,71.74)
  L3 w0.127: v3(81.02,71.74) 79.65,71.74 79.38,71.46 60.83,71.46 57.45,68.07 49.08,68.07 47.69,69.47 v3(44.84,69.47)
  L4 w0.127: v3(90,3.54) 87.28,3.54 86.65,4.17 83.21,4.17 81.23,6.15 75.42,6.15 73.8,4.53 69.12,4.53 66.46,7.19 66.46,8.97 64.53,10.9 62.43,10.9 60.58,12.76 59.31,12.76 54.9,17.17 54.9,20.03 53.01,21.92 53.01,26.26 46.84,32.43 46.84,46.98 46.52,47.31 46.52,48.95 48.49,50.91 48.49,53.29 46.48,55.3 46.48,64.99 44.84,66.63 v3(44.84,69.47)
  BOTTOM w0.102: R24008.2 90.2,6.43 90.2,6.03 90.72,5.5 90.72,4.26 v3(90,3.54)
PM_BATLOW#: length 8.8
  TOP w0.102: CPU1.DH48 192.64,29.93 192.89,30.18 193.05,30.18 193.08,30.21 193.39,30.21 193.42,30.18 194.11,30.18 194.22,30.08 194.41,30.08 194.76,29.73 195.31,29.73 195.81,29.73 196.8,28.73 v1(196.8,28.17) 196.8,26.5 197.66,25.64 R1715.1
PM_CLKRUN#_EC: length 7.9
  BOTTOM w0.102: R24067.2 84.52,25.59 v1(84.52,26.28) 84.52,27.31 84.8,27.59 Q2401.D 85.68,27.59 87.44,25.82 87.44,24.56 R1916.1
PM_CLKRUN#_EC_R: length 17.8
  TOP w0.102: v3(83.08,30.55) 82.39,30.55 81.87,30.03 81.87,27.58 82.4,27.06 ECIO1.80
  BOTTOM w0.102: v3(83.08,30.55) 83.28,30.55 Q2401.G 84.34,28.59 83.91,28.17 83.91,25.79 84.07,25.63 84.07,25.18 R24067.1 84.06,24.62 v1(83.63,24.19) 83.6,24.16 83.6,22.83 83.61,22.82 83.61,22.82 84.01,22.41 84.01,21.96 83.22,21.16 R24001.1
PM_PWRBTN#: length 168.8
  TOP w0.102: v3(190.67,33.57) 190.25,33.57 189.78,34.04 CPU1.CY42
  L3 w0.127: v3(213.22,19.3) 212.89,18.96 209.05,18.96 207.05,20.97 207.05,21.81 204.55,24.31 195.68,24.31 194.58,23.21 192.5,23.21 192.22,22.94 188.23,22.94 187.6,23.57 185.24,23.57 184.68,24.13 180.39,24.13 178.96,22.71 176,22.71 175.57,23.14 174.97,23.14 174.67,22.84 169.48,22.84 169.15,22.51 164.36,22.51 160.07,18.23 157.08,18.23 156.04,17.18 149.45,17.18 148.99,16.73 145.1,16.73 144.19,15.82 132.94,15.82 131.88,16.88 122.78,16.88 122.13,17.54 117.62,17.54 116.56,16.48 112.64,16.48 111.21,17.91 101.58,17.91 101.11,18.38 88.84,18.38 v3(87.8,19.42)
  BOTTOM w0.102: R24009.2 87.37,19.85 v3(87.8,19.42) ; v3(213.22,19.3) 213.9,19.97 213.9,21.42 204.92,30.39 R1717.1 201.11,30.39 200.23,31.27 198.02,31.27 195.48,33.81 192.63,33.81 192.63,33.8 192.63,33.8 v1(192.63,33.81) 192.24,33.81 192.01,33.57 v3(190.67,33.57)
PM_RSMRST#: length 12.4
  TOP w0.102: CPU1.DG49 194.07,30.51 194.3,30.28 195.02,30.28 195.21,30.08 195.24,30.08 195.4,29.93 195.57,29.93 196.4,29.93 198.51,27.82 v1(198.51,27.02) 198.51,26.53 R1728.2 200.24,25.46 200.75,24.95 R1709.2 200.14,24.21 R1722.1
PM_SLP_S0#: length 35.9
  TOP w0.076: CPU1.CL45 191.59,38.95 192.14,38.95 192.27,38.82 192.27,38.51 192.52,38.27 192.95,38.27 193.09,38.24 193.21,38.12 193.6,38.12 193.76,38.28
  TOP w0.102: 193.76,38.28 194.04,38.28 194.56,38.8 196.82,38.8 197.21,39.19 200.76,39.19 209.41,30.54 209.41,21.86 208.59,21.03 v3(208.59,20.85)
  BOTTOM w0.102: v1(206.16,22.3) 206.57,22.3 207.46,21.42 R1718.2 207.47,21.36 208.08,21.36 v3(208.59,20.85)
PM_SLP_S3#: length 500.9
  TOP w0.102: v3(214.65,4.52) 216.69,6.56 216.69,20.83 216.69,29.81 218.07,31.18 218.07,70.08 209.02,79.13 206.8,79.13 v3(206.69,79.02) ; v3(107.2,11.45) 107.2,11.85 107.22,11.87 107.22,17.16 108.03,17.97 v3(112.44,17.97) 112.44,20.32 103.72,29.04 102.48,29.04 100.96,30.56 97.75,30.56 96.56,29.37 95.73,29.37 95.66,29.44 94.94,29.44 94.65,29.14 91.22,29.14 R24068.2 ; v3(127.75,44.37) 127.44,44.68 126.87,44.68 125.64,43.46 125.64,43.09 124.2,41.64 124.14,41.64 122.54,40.03 118.27,40.03 117.75,39.52 117.75,34.65 117.64,34.54 117.05,34.54 113.03,30.52 v3(113.03,30.52) ; R4035.1 44.8,82.42 44.82,82.41 44.82,82.28 v3(44.44,81.9) 44.36,81.81 v1(42.46,81.81) 42.05,82.23 42.05,82.56 41.78,82.83 41.04,82.83 39.82,84.05 20.87,84.05 16.56,88.35 Q6803.G ; v3(183.57,4.56) 183.57,8.41 184.52,9.36 v3(184.52,9.41) ; CPU1.DF47 192.26,30.82 192.36,30.82 192.36,30.81 194.06,30.81 194.38,30.48 195.1,30.48 195.3,30.29 195.32,30.29 195.48,30.13 195.81,30.13 196.49,30.13 199.03,27.59 199.85,27.59 200.83,26.61 200.83,26.19 201.74,25.29 201.98,25.29 202.63,24.63 202.63,20.52 201.42,19.31 201.42,17.75 202.27,16.9 202.27,14.97 205.26,11.97 205.26,7.77 204.04,6.54 v3(203.54,6.54)
  L3 w0.127: v3(183.57,4.56) 184.06,4.07 190.84,4.07 191.14,4.36 191.94,4.36 194.02,6.45 198.26,6.45 198.47,6.23 200.27,6.23 200.84,6.8 202.64,6.8 202.89,6.54 v3(203.54,6.54) 203.65,6.43 204.57,6.43 205.46,5.53 212.35,5.53 213.36,4.52 v3(214.65,4.52) ; v3(107.2,11.45) 108.52,10.14 113.34,10.14 115.54,12.35 125.15,12.35 125.52,11.98 v3(125.8,11.98)
  L4 w0.127: v3(125.8,11.98) 126.22,11.56 129.2,11.56 129.42,11.78 134.04,11.78 135.01,10.8 152.97,10.8 154.99,12.83 158.97,12.83 161.02,14.87 v3(161.79,14.87) ; v3(107.2,11.45) 107.2,12.24 106.32,13.13 104.84,13.13 103.65,14.32 101.96,14.32 101.23,15.05 98.86,15.05 95.3,11.5 91.5,11.5 89.53,13.47 86.23,13.47 85.67,12.91 83.68,12.91 82.42,14.17 81.23,14.17 78.15,11.1 67.77,11.1 63.88,14.98 62.76,14.98 60.91,16.83 60.91,19.58 57.34,23.15 57.34,26.59 55.72,28.21 55.72,29 54.24,30.47 53.46,30.47 50.19,33.75 50.19,48.67 52.7,51.19 52.7,54.97 51.8,55.87 51.8,65.62 54.61,68.43 54.61,69.48 54.37,69.72 54.37,72.6 51.33,75.64 49.96,75.64 46.29,79.32 45.33,79.32 44.87,79.78 44.87,81.46 v3(44.44,81.9)
  BOTTOM w0.102: v3(113.03,30.52) 113.25,30.29 PR5405.2 113.88,26.98 111.59,24.69 111.59,18.82 v3(112.44,17.97) ; v3(127.75,44.37) 128.37,44.99 129.17,44.99 R4036.1 ; R4045.1 205.88,78.21 v3(206.69,79.02) ; U4009.2 185.83,11.62 185.62,11.42 184.62,11.42 184.52,11.32 v3(184.52,9.41) 183.68,10.25 180.07,10.25 178.42,8.61 178.42,6.42 D4004.2 176.9,6.39 R1841.2 176.54,6.03 168.49,6.03 166.92,7.6 163.08,7.6 162.38,8.3 162.38,10.86 162.01,11.24 162.01,14.65 v3(161.79,14.87)
PM_SLP_S3_N: length 6.5
  TOP w0.102: R24068.1 90.95,27.94 v1(90.95,26.9) 90.66,26.61 87.4,26.61 87.2,26.4 ECIO1.68
PM_SLP_S4#: length 389.7
  TOP w0.102: v3(194.89,31.38) 194.25,32.02 193.07,32.02 193.07,32.03 192.96,32.03 CPU1.DC48 ; Q6801.G 17.43,91.95 v3(17.49,91.89) ; v3(214.72,18.16) 215.4,17.48 215.4,8.49 v3(215.99,7.9) ; R24057.2 86.07,30.34 86.07,30.39 84.67,31.79 81.67,31.79 80.37,33.09 80.37,35.23 v3(78.63,36.98) ; v3(115.14,17.75) 115.14,15.94 114.34,15.14 114.34,11.63 112.33,9.62 109.63,9.62 106.24,6.24 102,6.24 101.99,6.23 v3(101.98,6.23)
  L3 w0.127: v3(31.71,54.05) 31.71,55.05 31.81,55.14 31.81,58.5 28.15,62.16 28.02,62.16 28,62.17 15.78,62.17 v3(13.05,64.9) ; v3(101.98,6.23) 102,6.21 102,5.71 102.17,5.55 105.14,5.55 105.49,5.9 115.59,5.9 117.69,8 124.35,8 125.94,6.42 129.67,6.42 129.85,6.6 134.67,6.6 135.32,7.25 152.49,7.25 152.89,7.65 158.36,7.65 159.05,8.34 159.05,8.67 159.45,9.07 168.54,9.07 169.43,9.95 178.58,9.95 180.18,11.56 182.83,11.56 183.13,11.25 189.41,11.25 190.17,12.02 195.94,12.02 196.75,12.82 202.71,12.82 203.47,12.06 207.53,12.06 209.29,10.31 213.7,10.31 215.99,8.02 v3(215.99,7.9) ; v3(62.08,35.13) 62.31,35.36 62.36,35.36 62.59,35.59 75.51,35.59 76.21,36.29 77.93,36.29 v3(78.63,36.98) 78.63,37.84 80.52,39.73 90.14,39.73 93.17,36.7 94.15,36.7 95.14,35.71 108.82,35.71 109.15,35.38 v3(109.32,35.38)
  L4 w0.127: v3(17.49,91.89) 17.49,82.39 15.55,80.45 15.55,78.05 17.75,75.84 17.75,69.91 13.05,65.21 v3(13.05,64.9)
  BOTTOM w0.102: v3(31.71,54.05) 32.6,54.94 Q3401.2 33.95,54.94 34.19,54.7 34.19,53.03 36.4,50.82 43.7,50.82 44.87,49.64 48.22,49.64 48.45,49.41 48.45,36.49 49.61,35.33 61.88,35.33 v3(62.08,35.13) ; v3(215.99,7.9) 215.59,7.5 R4011.1 ; v3(194.89,31.38) 196.33,31.38 199.11,28.6 199.4,28.6 R1842.2 199.76,28.5 201.66,26.6 201.66,24.83 206.8,19.69 207.27,19.69 208.92,18.03 214.59,18.03 v3(214.72,18.16) ; v3(109.32,35.38) 108.21,35.38 105.11,32.28 104.35,32.28 102.77,30.7 102.77,9.96 101.39,8.58 v1(101.39,7.7) 101.39,6.86 101.98,6.27 v3(101.98,6.23) ; v3(115.14,17.75) 115.14,17.7 115.64,17.21 U4020.1
PM_SLP_S4_N: length 5.3
  TOP w0.102: ECIO1.74 84.8,26.38 85.92,27.51 85.93,27.51 86.09,27.67 86.09,27.83 v1(86.65,28.39) 86.62,28.41 R24057.1
PM_SLP_SUSB#: length 193.2
  TOP w0.102: R24081.1 76.35,5.31 v3(76.35,4.72) ; v3(123.87,21.1) 121.27,21.1 119.21,23.16 119.21,25.98 116.59,28.59 114.18,28.59 111.72,31.06 111.72,33.13 v3(111.7,33.14) ; v3(194.77,26.71) 194.73,26.74 194.73,27.13 194.04,27.83 193.89,27.83 193.77,27.95 193.5,27.95 193.47,27.98 192.99,27.98 CPU1.DM49 ; v3(135.08,31.24) 135.09,31.24 135.21,31.36 R5305.1
  L3 w0.127: v3(194.35,25.21) 194.35,25.11 193.88,24.64 193.53,24.64 192.68,25.49 188.29,25.49 187.46,26.33 184.49,26.33 183.97,25.81 180.02,25.81 179.24,25.03 177.73,25.03 177.34,24.64 175.83,24.64 175.8,24.66 167.01,24.66 166.81,24.46 161.71,24.46 158.34,21.09 156.18,21.09 154.93,19.85 142.65,19.85 142.16,19.36 136.43,19.36 134.85,20.94 125.72,20.94 125.38,20.6 124.37,20.6 v3(123.87,21.1) ; v3(111.7,33.14) 111.1,33.75 108.18,33.75 107.87,34.06 82.66,34.06 82.55,33.95 82.16,33.95 82.06,34.06 81.78,34.06 81.65,34.19 v3(81.65,34.51)
  BOTTOM w0.102: v3(194.35,25.21) 194.35,26.29 v3(194.77,26.71) 194.54,26.94 194.34,26.94 193.84,27.43 193.11,27.43 193.1,27.43 192.69,27.43 R1840.2 ; v3(81.65,34.51) 79.66,36.5 77.74,36.5 76.34,35.11 76.34,33.24 v1(76.89,32.7) 77.24,32.34 77.24,28.88 75.89,27.53 75.89,23 75.04,22.15 75.04,16.49 73.61,15.05 73.61,9.44 74.27,8.77 74.27,6.79 v3(76.35,4.72) ; v3(123.87,21.1) 123.87,25.67 126.8,28.61 132.7,28.61 135.08,30.99 v3(135.08,31.24)
PM_SLP_SUSB#_ECIO: length 3.4
  TOP w0.102: ECIO1.5 77.6,8.5 77.11,8.02 v1(77.11,7.5) 76.6,6.98 R24081.2
PMCALERT#: length 6.1
  TOP w0.102: CPU1.CL39 188.26,38.53 v3(187.93,38.2)
  BOTTOM w0.102: R1732.1 185.34,34.92 186.52,34.92 186.54,34.9 187,34.9 187.56,35.45 v1(187.56,37.28) 187.93,37.66 v3(187.93,38.2)
PROC_TCK: length 11.8
  TOP w0.102: CPU1.P3 170.48,66.67 CPU1.N2 170.02,67 169.74,66.72 169.66,66.72 169.66,66.72 169.56,66.72 169.23,66.39 166.9,66.39 163.67,69.62 162.91,69.62 162.43,70.11 TP9905.1 161.88,70.32 R301.2
PROC_TDI: length 7.3
  TOP w0.102: CPU1.K5 171.15,68.04 169.81,68.04 CPU1.K1 169.09,68.35 v3(168.98,68.24)
  BOTTOM w0.102: v3(168.98,68.24) 168.98,66.48 168.96,66.46 TP9906.1 169.34,66.3 169.34,66.55 169.68,66.88 RN303.4
PROC_TMS: length 5.4
  TOP w0.102: CPU1.N3 171.13,66.67 CPU1.P4 170.94,66.43 170.63,66.13 170.35,66.13 170.15,66.33 v3(169.91,66.33)
  BOTTOM w0.102: TP9907.1 170.16,65.53 169.91,65.79 v3(169.91,66.33) 170.33,66.75 RN303.3
PROC_TRST#: length 9.2
  TOP w0.102: CPU1.N5 171.45,67 171.1,67.35 169.85,67.35 CPU1.N1 169.19,66.69 167.64,66.69 TP9908.1 165.73,68.6 165.67,68.6 164.93,69.34 164.93,69.36 164.11,70.18 R313.2
PROCHOT#_CPU: length 5.5
  TOP w0.203: 116.96,52.05 117.52,51.5 PU4601.2
  TOP w0.381: 116.96,52.05 115.7,53.31 v1(115.61,53.31) 114.95,53.31 PR4613.1 R4602.1
PROCHOT#_CPU_R: length 82.5
  TOP w0.305: R4602.2 113.63,55.49 113.59,55.53 v3(113.59,55.58) ; v3(157.42,73.32) v1(158.14,74.05) 159.15,75.06 166.89,75.06 v3(167.87,74.08)
  L3 w0.305: v3(157.42,73.32) 157.42,77.58 154.43,80.58 126.84,80.58 114.86,68.6 114.86,64.19 115.79,63.26 115.79,60.51 113.59,58.31 v3(113.59,55.58)
  BOTTOM w0.305: R325.2 113.59,55.57 v3(113.59,55.58) ; R306.2 168.65,73.47 R24924.1 168.64,74.08 v3(167.87,74.08)
PROCHOT_N_CPU: length 4.8
  TOP w0.102: CPU1.C3 170.79,72.14 171.03,72.38 171.03,72.94 170.94,73.03 170.94,73.37 v3(170.55,73.75)
  BOTTOM w0.102: v3(170.55,73.75) 170.74,73.75 170.95,73.97 170.95,74.39 170.77,74.56 v1(170.5,74.56) 170.01,74.56 R24924.2
PROCHOT_N_EC: length 4.7
  TOP w0.102: ECIO1.11 80,7.77 v3(80.17,7.6)
  BOTTOM w0.102: v3(80.17,7.6) 80.17,8 79.93,8.24 79.67,8.24 v1(79.42,7.99) 79.42,7.12 79.33,7.02 79.33,6.58 R24071.1
PROCHOT_N_OCP: length 48.4
  TOP w0.102: R24087.2 98.35,21.73 98.44,21.82 98.44,22.66 97.44,23.67 R24059.1 96.45,24.39 96.34,24.49 96.23,24.49 v3(96.23,24.49)
  BOTTOM w0.102: Q4301.D 115.61,55.91 R325.1 112.1,52.4 110.3,52.4 109.52,51.62 109.52,46.54 110.01,46.05 110.01,43.63 109.3,42.93 109.3,38.86 104.62,34.18 104.35,34.18 102.74,34.18 99.05,30.49 99.05,27.94 v1(97.92,26.81) 97.68,26.57 97.53,26.57 96.64,25.67 96.64,25.53 96.23,25.12 96.23,24.49 v3(96.23,24.49)
PROCHOT_N_OCP_R: length 9.2
  TOP w0.102: R24087.1 97.98,20.4 97.64,20.06 v1(97.05,20.06) 94.96,20.06 94.47,20.54 93.52,20.54 93.09,20.1 92.92,20.1 92.19,19.38 ECIO1.54
PS8625_BKLT_EN: length 42.6
  TOP w0.114: R5509.1 26.82,16.45 26.82,15.18 27.14,14.85 v3(27.14,14.49)
  L3 w0.127: v3(35.36,15.52) 43.91,15.52 44.04,15.64 v3(44.04,15.77)
  BOTTOM w0.114: v3(35.36,15.52) 35.93,14.94 35.93,12.76 34.57,11.39 34.57,10.83 33.28,9.54 30.85,9.54 27.23,13.15 27.23,14.4 v3(27.14,14.49) ; TSMT1.44 39.22,24.87 41.01,23.09 41.01,23.04 41.14,22.91 44.7,22.91 v1(44.92,22.69) 45.32,22.29 R5623.1 45.32,21.71 43.92,20.31 43.92,15.9 v3(44.04,15.77)
PS8625_BKLT_PWM: length 7.3
  TOP w0.114: R5512.2 28.79,26.1 v1(29.03,26.33) v3(30.8,26.33)
  BOTTOM w0.114: R5619.1 30.08,25.62 v3(30.8,26.33) 31.11,26.33 31.54,25.9 31.92,25.9 32.14,25.67 TSMT1.19
PS8625_HPD_R: length 6.7
  BOTTOM w0.102: R5627.2 39.34,16.86 v1(38.85,17.35) 38.85,18.55 38.27,19.13 38.27,21.62 37.94,21.95 TSMT1.1
PS8625_LCD_PW_EN: length 52.7
  TOP w0.114: v3(30.33,26.87) 29.42,26.87 28.6,27.68 28.6,30.17 29.7,31.27 32.91,31.27 v3(33.02,31.15)
  L3 w0.127: v3(60.65,24.43) 60.32,24.76 58.08,24.76 55.76,27.08 55.01,27.08 54.08,28.01 44.83,28.01 42.72,30.12 39.81,30.12 37.9,32.03 33.47,32.03 33.02,31.59 v3(33.02,31.15)
  BOTTOM w0.114: R5622.1 28.2,24.91 C5621.1 28.05,25.81 28.14,25.9 v1(29.34,25.9) 29.85,25.9 30.33,26.37 v3(30.33,26.87) 30.4,26.8 30.99,26.8 31.64,26.14 32.1,26.14 32.17,26.07 TSMT1.20 ; v3(60.65,24.43) 60.65,23.93 62.2,22.38 R5536.2
PSYS: length 45.5
  TOP w0.102: R4601.2 110.6,44.8 109.16,46.23 v1(109.16,48) 108.53,48.63 99.38,48.63 97.3,46.56 97.3,39.79 94.67,37.16 94.67,30.75 94.18,30.26 88.41,30.26 87.6,31.08 86.24,31.08 84.95,32.37 R4319.2
PWR_1D05V:
  vias: v1(127.18,37.14)
PWR_1D05V_EN: length 5
  BOTTOM w0.102: PU5401.6 120.15,33.7 121.04,32.81 v1(121.89,32.81) 122.7,32.81 123.05,33.15 PR5403.1
PWR_1D8V:
  vias: v1(130.86,34.16) v2(128.9,35.19) v2(128.86,34.28) v2(129.92,34.28) v2(130.01,35.19)
PWR_1D8V_BT: length 2.3
  TOP w0.305: v3(132.04,38.89) 132.04,38.89 132.05,38.88 PU5301.20
  BOTTOM w0.508: PC5320.2 132.46,38.64 132.22,38.88 132.05,38.88 132.04,38.89 v3(132.04,38.89)
PWR_1D8V_EN: length 6
  TOP w0.102: PR5331.2 135.82,34.26 135.27,34.81 134.67,34.81 134.53,34.95 134.53,35.03 v3(134.51,35.06) 134.51,35.11 134.37,35.24 134.37,35.68 134.44,35.75 PU5301.2
  BOTTOM w0.102: v3(134.51,35.06) 134.16,35.4 v1(134.16,35.89) 134.16,36.21 PC5314.1
PWR_1D8V_EN_R: length 6
  TOP w0.102: PR5331.1 135.98,33.33 R5305.2 135.98,32.23 136.66,31.55 D5301.A 137.41,31.9 v3(136.87,32.44)
  BOTTOM w0.102: v3(136.87,32.44) 136.62,32.68 v1(135.9,32.68) PR5325.2
PWR_1D8V_PFM: length 4.8
  TOP w0.254: v3(134.93,35.63) 134.93,36.57 PU5301.3
  BOTTOM w0.254: v3(134.93,35.63) 136.09,36.79 v1(136.09,37.32) 136.09,37.83 135.88,38.03 PR5303.1
PWR_1D8V_PG: length 4.3
  TOP w0.305: PU5301.1 133.94,36.27 133.45,35.78 v1(133.45,35.18) 133.42,35.15 133.42,34.18 PR5327.2 133.8,34.16 133.95,34.31 134.52,34.31 134.52,34.31 PR5326.2
PWR_1D8V_PH: length 1.2
  BOTTOM w0.508: PC5320.1 v2(133.11,40.69)
  vias: v1(131.95,42.14)
PWR_1D8V_SS: length 4.5
  TOP w0.254: PU5301.22 133.14,36.81 132.74,36.41 131.62,36.41 131.42,36.2 v1(131.42,35.43) 131.74,35.1 PC5313.1
PWR_1D8V_TON: length 4.1
  TOP w0.305: 137.12,36.39 136.94,36.58 PU5301.6
  TOP w0.381: 137.12,36.39 137.4,36.12 137.4,35.62 v1(137.89,35.13) 138.19,34.83 138.67,34.83 139.05,34.45 139.07,34.44 PR5301.2
PWR_1D8V_VFB: length 6
  TOP w0.254: PU5301.5 135.94,35.93 136.37,35.5 v3(136.69,35.5) 137.07,35.11 PR5302.2 137.18,34.09 PC5312.2
  BOTTOM w0.254: PR5304.1 v1(137.1,34.72) 137.1,35.09 v3(136.69,35.5)
PWR_1D8V_VFB_A: length 11.7
  TOP w0.254: PR5302.1 137.55,33.31 137.65,33.21 PC5312.1 138.04,32.46 138.28,32.22 138.28,30.99 137.9,30.61 v1(132.23,30.61) 131.55,31.29 PG5315.1
PWR_2D5V_EN: length 9.2
  BOTTOM w0.305: PU5201.8 262.15,25.1 262.46,25.41 262.46,26.68 261.4,27.74 261.4,29.36 261.2,29.56 PC5205.1 261.19,30.15 260.26,30.15 PR5204.2 260.25,29.72 v1(259.72,29.2)
PWR_2D5V_FB: length 5.7
  BOTTOM w0.508: PU5201.2 259.54,18.94 260.32,18.16 260.32,17.96 PR5201.1 260.32,17.95 260.45,17.82 260.45,17.06 PR5203.2 PC5204.2 260.57,14.77 v1(260.63,14.71)
PWR_2D5V_VIN:
  vias: v1(257.75,29.31)
PWR_2D5V_VPP:
  vias: v1(257.38,14.41)
PWR_3D3V:
  vias: v1(102.82,56.09) v2(104.53,57.24) v2(104.53,56.27) v2(104.53,55.26) v2(104.52,54.22) v2(110.24,57.26) v2(110.24,56.27) v2(110.24,55.23)
PWR_3D3V_5V_PG: length 6.3
  BOTTOM w0.203: 105.09,76.72 105.07,76.72 104.69,76.34 104.69,76.34 104.62,76.27 PU4503.7
  BOTTOM w0.305: 105.09,76.72 105.33,76.96 v1(105.92,76.96) 106.42,76.96 106.97,76.41 106.97,74.97 106.49,74.49 PR4511.2
PWR_3D3V_BOOT2: length 3.5
  TOP w0.508: v3(105.13,75) 105.13,75 105.13,74.99 104.47,74.99 PR4501.2
  BOTTOM w0.203: PU4503.9 104.66,75.47 v3(105.13,75) 105.19,74.94 105.64,74.94 v1(106.13,75.44)
PWR_3D3V_BOOT2_A: length 3.9
  TOP w0.508: PR4501.1 104.54,76.82 104.97,77.25 v1(106.13,77.25) 106.69,77.25 PC4512.2
PWR_3D3V_CS2: length 3
  BOTTOM w0.203: PU4503.5 103.39,77.91 103.75,78.28
  BOTTOM w0.305: v1(104.25,80.08) 104.25,79.01 PR4503.1 104.22,78.74 103.75,78.28
PWR_3D3V_EN2: length 4.8
  TOP w0.254: v2(104.28,77.82) 104.14,77.95 104.14,78.93 R4501.2 104.2,78.93 105.09,79.82 C4501.1 v1(105.16,80.87)
  BOTTOM w0.203: PU4503.6 104.14,77.69 v2(104.28,77.82)
PWR_3D3V_FB2: length 5.1
  BOTTOM w0.203: PU4503.4 102.99,78.05 103.43,78.49 103.43,78.98
  BOTTOM w0.305: PR4507.1 PR4505.2 102.13,79.08 102.83,79.78 v1(103.01,79.78) 103.43,79.36 103.43,78.98
PWR_3D3V_FB2_A: length 43
  L3 w0.254: v3(96.04,74.63) 95.48,74.06 95.48,67.87 96.05,67.3 96.05,65.88 95.5,65.34 95.5,58.78 95.89,58.39 95.89,57.98 97.09,56.78 97.09,53.58 97.63,53.05 101.61,53.05 v3(102.03,52.62)
  BOTTOM w0.254: v3(102.03,52.62) 102.29,52.89 PG4529.1 ; v3(96.04,74.63) v1(95.38,75.29) 95.38,79.86 95.74,80.23 97.56,80.23 99.05,81.71 101.19,81.71 101.96,80.95 PR4505.1
PWR_3D3V_HG2: length 22.1
  TOP w0.406: 112.42,60.59 PU4501.4
  TOP w0.635: v2(111.52,60.59) 112.42,60.59
  L3 w0.635: v2(111.52,60.59) 112.06,61.14 112.06,62.28 111.51,62.84 111.51,69.99 110.49,71.01 108.98,71.01 105.8,74.19 v2(105.61,74.19)
  BOTTOM w0.203: PU4503.10 104.38,75.07 105.26,74.19
  BOTTOM w0.635: 105.26,74.19 v2(105.61,74.19) ; v2(111.52,60.59) v1(112.17,61.25)
PWR_3D3V_LDO3: length 1.4
  BOTTOM w0.203: PU4503.3 102.59,78.51
  BOTTOM w0.254: 102.59,78.51 v2(102.83,78.76)
  vias: v1(102.13,79.75)
PWR_3D3V_LG2: length 12.3
  TOP w0.406: v2(108.25,66.58) 108.37,66.47 PU4504.4
  L3 w0.762: v2(104.18,73.84) 104.18,72.27 106.2,70.25 106.2,67.73 107.35,66.58 v2(108.25,66.58)
  BOTTOM w0.203: PU4503.11 103.7,74.32 v2(104.18,73.84)
  BOTTOM w0.711: v1(109.2,66.58) v2(108.25,66.58)
PWR_3D3V_PH2: length 20.4
  TOP w0.61: v2(105.33,76.08) 106.13,76.08 v1(106.34,75.87) 106.67,75.54 PC4512.1
  L3 w0.635: v2(105.33,76.08) 105.46,76.08 106.63,74.92 106.63,74.62 109.35,71.89 110.86,71.89 112.39,70.36 112.39,63.33 v2(112.47,63.25)
  BOTTOM w0.203: PU4503.8 105.1,75.87 105.31,76.08 v2(105.33,76.08)
PWR_5V:
  vias: v1(95.43,55.89) v2(95.25,58.17) v2(95.25,53.43) v2(95.25,52.49) v2(95.28,57.25) v2(95.26,54.43) v2(96.18,54.45) v2(96.16,53.41) v2(96.2,52.49)
PWR_5V_BOOT1: length 5.3
  TOP w0.508: v2(99.74,74.95) 98.25,74.95 97.63,75.57 PR4502.1
  BOTTOM w0.203: v2(99.74,74.95) 100.26,75.47 PU4503.17
  BOTTOM w0.254: v2(99.74,74.95) 99.63,74.84 v1(98.78,74.84)
PWR_5V_BOOT1_A: length 2.6
  TOP w0.508: PR4502.2 98.51,77.5 PC4513.1 99.14,77.5 v1(100,77.5)
PWR_5V_BYP1: length 26.5
  L3 w0.305: v3(96.12,64.59) 96.64,65.11 96.64,70.63 97.6,71.59 97.6,75.52 99.2,77.11 100.38,77.11 101.19,76.3 101.19,75.25 102.48,73.96 102.48,73.32 v2(102.19,73.04)
  BOTTOM w0.203: PU4503.14 v2(102.19,73.04)
  BOTTOM w0.305: PG4530.1 95.95,60.49 95.58,60.86 95.58,62.51 v1(96.13,63.06) 96.13,64.58 v3(96.12,64.59)
PWR_5V_CS1: length 4.7
  BOTTOM w0.203: PU4503.1 101.32,77.42
  BOTTOM w0.305: PR4504.1 v1(98.67,78.82) 99.1,78.82 99.33,78.59 99.33,78.58 100.17,77.74 100.18,77.74 100.5,77.42 101.32,77.42
PWR_5V_EN1: length 3.7
  BOTTOM w0.203: 100.07,76.78 100.18,76.67 PU4503.20
  BOTTOM w0.254: 99.68,77.17 v1(99.69,77.17) ; 99.68,77.17 99.66,77.19 98.98,77.19 C4502.1 R4502.2 ; 99.68,77.17 100.07,76.78
PWR_5V_FB1: length 6.4
  BOTTOM w0.203: PU4503.2 102.19,78.04 102.07,78.16
  BOTTOM w0.305: PR4506.2 98.07,79.52 v1(98.64,80.09) 99.29,79.45 99.66,79.08 PR4508.1 99.89,78.81 100.4,78.3 101.93,78.3 102.07,78.16
PWR_5V_FB1_A: length 21.1
  L3 w0.305: v3(95.36,65.94) 95.36,67.15 94.84,67.67 94.84,74.76 v3(96.13,76.05)
  BOTTOM w0.305: PG4531.1 v1(95.02,63.82) 95.02,65.6 v3(95.36,65.94) ; v3(96.13,76.05) v1(96.13,77.81) 96.13,79.21 96.43,79.52 PR4506.1
PWR_5V_HG1: length 13.1
  TOP w0.406: PU4502.4 100.57,63.36 v2(100.62,63.31)
  L3 w0.635: v2(99.82,73.95) 99.47,73.6 99.47,71.7 100.62,70.55 v2(100.62,63.31)
  BOTTOM w0.635: v2(100.62,63.31) v1(100.62,64.3)
PWR_5V_LDO5: length 5.6
  TOP w0.508: PG4533.1 v1(102.5,74.38) 103.15,73.73 v2(103.15,73.02)
  BOTTOM w0.203: PU4503.13 102.59,73.56 103.13,73.02 v2(103.15,73.02)
  BOTTOM w0.508: v2(103.15,73.02) 103.15,72.95 102.95,72.75 102.95,72.29 PC4517.1
PWR_5V_LG1: length 11.1
  TOP w0.406: PU4505.4 105.46,66.3 v2(105.39,66.36)
  L3 w0.762: v2(101.06,73.05) 101.06,72.21 102.29,70.98 102.29,67.54 103.47,66.36 v2(105.39,66.36)
  BOTTOM w0.203: PU4503.15 101.79,74.12 101.47,73.79
  vias: v1(99.81,72.97)
PWR_5V_PH1: length 19.2
  TOP w0.61: PC4513.2 99.07,76.05 v2(99.95,76.05)
  L3 w0.635: v2(97.87,62.2) 99.54,63.87 99.54,63.88 99.73,64.07 99.73,70.19 98.58,71.33 98.58,75.06 99.57,76.05 v2(99.95,76.05)
  BOTTOM w0.203: PU4503.18 100.13,75.87 v2(99.95,76.05)
  BOTTOM w0.635: v2(97.87,62.2) v1(97.87,63.13)
PWR_DCBATOUT_1D8V: length 7.8
  TOP w0.381: PR5301.1 140.21,33.21 v2(140.58,33.58)
  BOTTOM w0.508: PC5316.1 140.04,37.96 141.41,36.59 141.41,35.09 140.58,34.26 v2(140.58,33.58)
  vias: v1(138.8,40.69) v1(138.87,41.09) v3(139.88,40.06)
PWR_DCBATOUT_3D3V:
  vias: v1(114.87,72.03)
PWR_DCBATOUT_5V:
  vias: v1(98.21,70.56) v2(97.78,69.75) v2(98.34,68.87) v2(98.93,69.77)
PWR_DCBATOUT_VCCAUX: length 41.1
  TOP w0.254: PR5033.2 147.09,34.19 149.34,34.19 150.29,35.14 150.29,36.98 151.89,38.58 v2(151.89,40.98)
  BOTTOM w0.254: PC5006.1 131.79,52.83 131.54,52.58 131.54,48.25 132.82,46.96 132.82,46.64 133.69,45.77 137.92,45.77 139.83,43.86 v1(141.75,43.86) 147.13,43.86 147.85,43.14 151.48,43.14 151.89,42.73 v2(151.89,40.98)
  vias: v1(132.88,55.05) v2(132.98,54.02) v2(134.09,54.02)
PWR_DCBATOUT_VCOREA:
  vias: v1(134.68,60.38) v2(132.78,61.84) v2(132.77,60.47) v2(133.43,61.1) v2(133.46,62.48) v2(134.04,61.78) v2(134.71,62.41)
PWR_DCBATOUT_VCOREB:
  vias: v1(132.33,78.69) v2(132.92,76.81) v2(132.92,75.82) v2(133.83,76.81) v2(133.83,75.82) v2(134.75,76.81) v2(134.75,75.82)
PWR_DCBATOUT_VDDQ: length 17.2
  TOP w0.254: PR5111.1 218.04,93.44 219.42,92.06 219.42,89.01 221.96,86.47 224.92,86.47 225.57,85.82 225.8,85.82 226.39,85.23 228.72,85.23 v3(228.89,85.4)
  vias: v1(230.4,87.15)
PWR_DDR_SN: length 2.8
  BOTTOM w0.508: PR5105.2 235.61,97.04 235.13,97.51 v1(234.7,97.51) 234.21,97.03 PC5104.1
PWR_DMIC:
  vias: v1(209.88,101.16)
PWR_ID0: length 94.4
  TOP w0.102: CNVBD1.4 12.5,7.55 11.76,8.28 11.76,9.2 R5522.2 12.07,9.44 12.41,9.1 v3(12.41,8.65) ; ECIO1.18 82.8,8.23 82.49,7.93 82.49,4.49 83.24,3.74 83.49,3.74 84.75,2.48 85.7,2.48 v3(86.15,2.93)
  BOTTOM w0.102: v3(86.15,2.93) 86.1,2.93 85.44,2.27 83.31,2.27 82.69,1.65 73.02,1.65 72.23,2.45 v1(71.26,2.45) 70.38,2.45 63.52,9.3 59.81,9.3 59.53,9.58 55.41,9.58 54.24,8.41 30.3,8.41 28.26,10.45 EC5501.1 25.65,10.19 25.65,9.8 23.29,7.44 13.62,7.44 v3(12.41,8.65)
PWR_ID1: length 92.1
  TOP w0.102: ECIO1.19 83.2,8.2 82.79,7.8 82.79,4.62 83.37,4.04 83.62,4.04 84.72,2.94 v3(85.44,2.94) ; CNVBD1.5 13.5,7.45 12.94,8.01 12.94,9.34 R5523.2 13.19,9.44 13.59,9.04 v3(13.59,8.7)
  BOTTOM w0.102: v3(13.59,8.7) 14.54,7.74 22.88,7.74 23.91,8.77 23.91,10.2 24.67,10.96 25.12,10.96 EC5502.1 27.92,11.59 30.79,8.71 54.12,8.71 55.29,9.88 59.66,9.88 59.75,9.79 59.76,9.79 59.95,9.61 63.65,9.61 70.09,3.17 72.6,3.17 v1(72.98,2.79) 73.81,1.96 82.57,1.96 83.19,2.57 85.01,2.57 85.38,2.94 v3(85.44,2.94)
PWR_ID2: length 122.9
  TOP w0.102: CNVBD1.6 14.5,7.85 14.16,8.2 14.16,9.43 R5524.2 14.42,9.44 14.63,9.24 v3(14.63,8.67) ; ECIO1.76 84,23.36 84.93,22.43 84.93,22.06 85.66,21.32 v3(85.66,15.93)
  BOTTOM w0.102: v3(14.63,8.67) 15.26,8.05 22.75,8.05 23.56,8.85 23.56,10.5 23.52,10.53 23.52,11.71 23.94,12.12 25.29,12.12 25.4,12.23 25.4,12.67 EC5503.1 27.25,12.68 30.92,9.02 53.99,9.02 55.89,10.92 v1(56.48,10.92) 59.36,10.92 60.37,9.91 63.77,9.91 69.96,3.72 75.15,3.72 75.85,3.02 82.13,3.02 82.74,3.64 84.45,3.64 84.92,4.11 86.68,4.11 87.7,3.09 92.26,3.09 93.44,4.26 93.44,4.57 93.71,4.84 94.02,4.84 94.48,5.3 94.48,10.38 92.32,12.55 92.32,14.16 90.34,16.13 88.83,16.13 88.73,16.24 88.73,16.39 88.33,16.79 86.52,16.79 v3(85.66,15.93)
PWR_ISEN1: length 22.8
  TOP w0.305: U5501.17 18.15,26.1 v3(17.58,25.53)
  TOP w0.508: CNVBD1.12 20.5,7.83 21.29,8.62 v3(21.29,8.62)
  L4 w0.508: v3(17.58,25.53) 17.58,23.45 21.29,19.74 v3(21.29,8.62)
  BOTTOM w0.508: v1(16.78,25.05) 17.26,25.53 v3(17.58,25.53)
PWR_ISEN2: length 23.6
  TOP w0.305: U5501.16 16.86,26.7
  TOP w0.508: CNVBD1.11 19.5,8.23 v3(20.46,9.19) v1(21.09,9.82) ; 16.86,26.7 v3(16.82,26.74)
  L4 w0.508: v3(16.82,26.74) 16.82,26.27 16.54,25.98 16.54,22.96 20.23,19.27 20.23,9.43 v3(20.46,9.19)
PWR_ISEN3: length 23
  TOP w0.305: 15.52,27.62 16.06,28.15 U5501.14
  TOP w0.508: CNVBD1.8 16.5,8.48 v3(16.62,8.61) ; 15.52,27.62 14.9,27 v1(14.9,26.62) 14.9,26.49 15.52,25.87 v3(15.52,25.33)
  L4 w0.508: v3(16.62,8.61) 16.62,21.12 15.52,22.22 v3(15.52,25.33)
PWR_ISEN4: length 24.6
  TOP w0.305: 14.97,28.32 15.31,28.65 U5501.13
  TOP w0.508: v3(14.5,25.41) 13.68,26.23 13.68,27.18 13.69,27.18 ; CNVBD1.7 v3(15.5,8.5) ; 14.97,28.32 14.13,27.47 13.98,27.47 13.69,27.18 ; v1(13.7,27.18) 13.69,27.18
  L4 w0.508: v3(14.5,25.41) 14.5,21.54 15.5,20.54 v3(15.5,8.5)
PWR_ISET: length 3.3
  TOP w0.305: U5501.12 v1(14.8,29.15) 14.5,29.15 14.17,29.49 R5507.1
PWR_LPF: length 5.3
  TOP w0.305: U5501.9 18.15,31.22 17.45,31.92 15.88,31.92 v1(15.69,32.11) 15.47,32.33 C5511.1
PWR_MCT1_R: length 6.8
  BOTTOM w0.305: C3125.1 57.43,59.05 57.74,58.74 v1(57.93,58.74) R3156.2 59.02,57.55 R3159.2 59.03,56.36 R3158.2 R3157.2
PWR_RT: length 6.1
  TOP w0.305: R5514.1 14.27,31.78 v1(14.41,31.65) 14.78,31.28 17.34,31.28 17.65,30.97 U5501.10
PWR_SSTCMP: length 3.8
  TOP w0.305: R5508.1 13.87,30.42 v1(14.75,30.42) 16.39,30.42 16.69,30.12 U5501.11
PWR_SSTCMP_1: length 4
  TOP w0.305: R5508.2 12.33,30.7 v1(11.21,29.57) 10.69,29.06 C5509.1
PWR_STATUS: length 4.4
  TOP w0.305: R5513.1 16.57,32.91 v1(16.86,32.62) 17.13,32.35 17.75,32.35 18.65,31.46 U5501.8
PWR_VCCAUX_BOOT: length 4.3
  TOP w0.203: PU5001.10 144.06,42.62 143.59,43.09
  TOP w0.508: PR5007.1 141.94,44.7 141.94,43.93 142.79,43.09 143.59,43.09
PWR_VCCAUX_BOOTA: length 3
  TOP w0.508: PR5007.2 140.93,44.29 140.93,43.51 141.66,42.78 PC5003.1
PWR_VCCAUX_COMP: length 7.1
  TOP w0.203: 146.41,41.35 PU5001.5
  TOP w0.254: 146.41,41.35 147.57,42.52 148.84,42.52 PC5012.1 149.33,42.53 149.34,42.53 v1(151.55,42.53) 151.77,42.75 PC5010.1
PWR_VCCAUX_COMPA: length 5.6
  TOP w0.254: v3(148.69,44.24) 148.63,44.19 PR5013.1 ; v3(151.63,44.52) 152.26,44.52 152.67,44.11 152.67,43.56 PC5010.2
  BOTTOM w0.254: v3(151.63,44.52) 151.36,44.24 v1(150.3,44.24) v3(148.69,44.24)
PWR_VCCAUX_COMPB: length 2.1
  TOP w0.254: PC5011.2 v1(150.73,44.62) 150.73,45.6 PR5014.1
PWR_VCCAUX_CS_DIS: length 5.2
  TOP w0.203: 146.41,39.07 PU5001.1
  TOP w0.254: PR5004.2 v1(148.45,36.33) 148.05,36.33 147.79,36.59 147.79,37.32 146.41,38.7 146.41,39.07
PWR_VCCAUX_EN: length 5.5
  TOP w0.203: 145.56,37.7 145.26,38 PU5001.19
  TOP w0.305: v3(145.91,36.88) 145.91,36.85 ; 145.91,36.85 145.62,36.55 PR5052.2 ; 145.91,36.85 145.94,36.88 145.94,37.31 145.56,37.7
  BOTTOM w0.305: v3(145.91,36.88) 145.91,36.85 145.7,36.64 v1(145.04,36.64) 144.94,36.64 144.64,36.95 PC5002.1
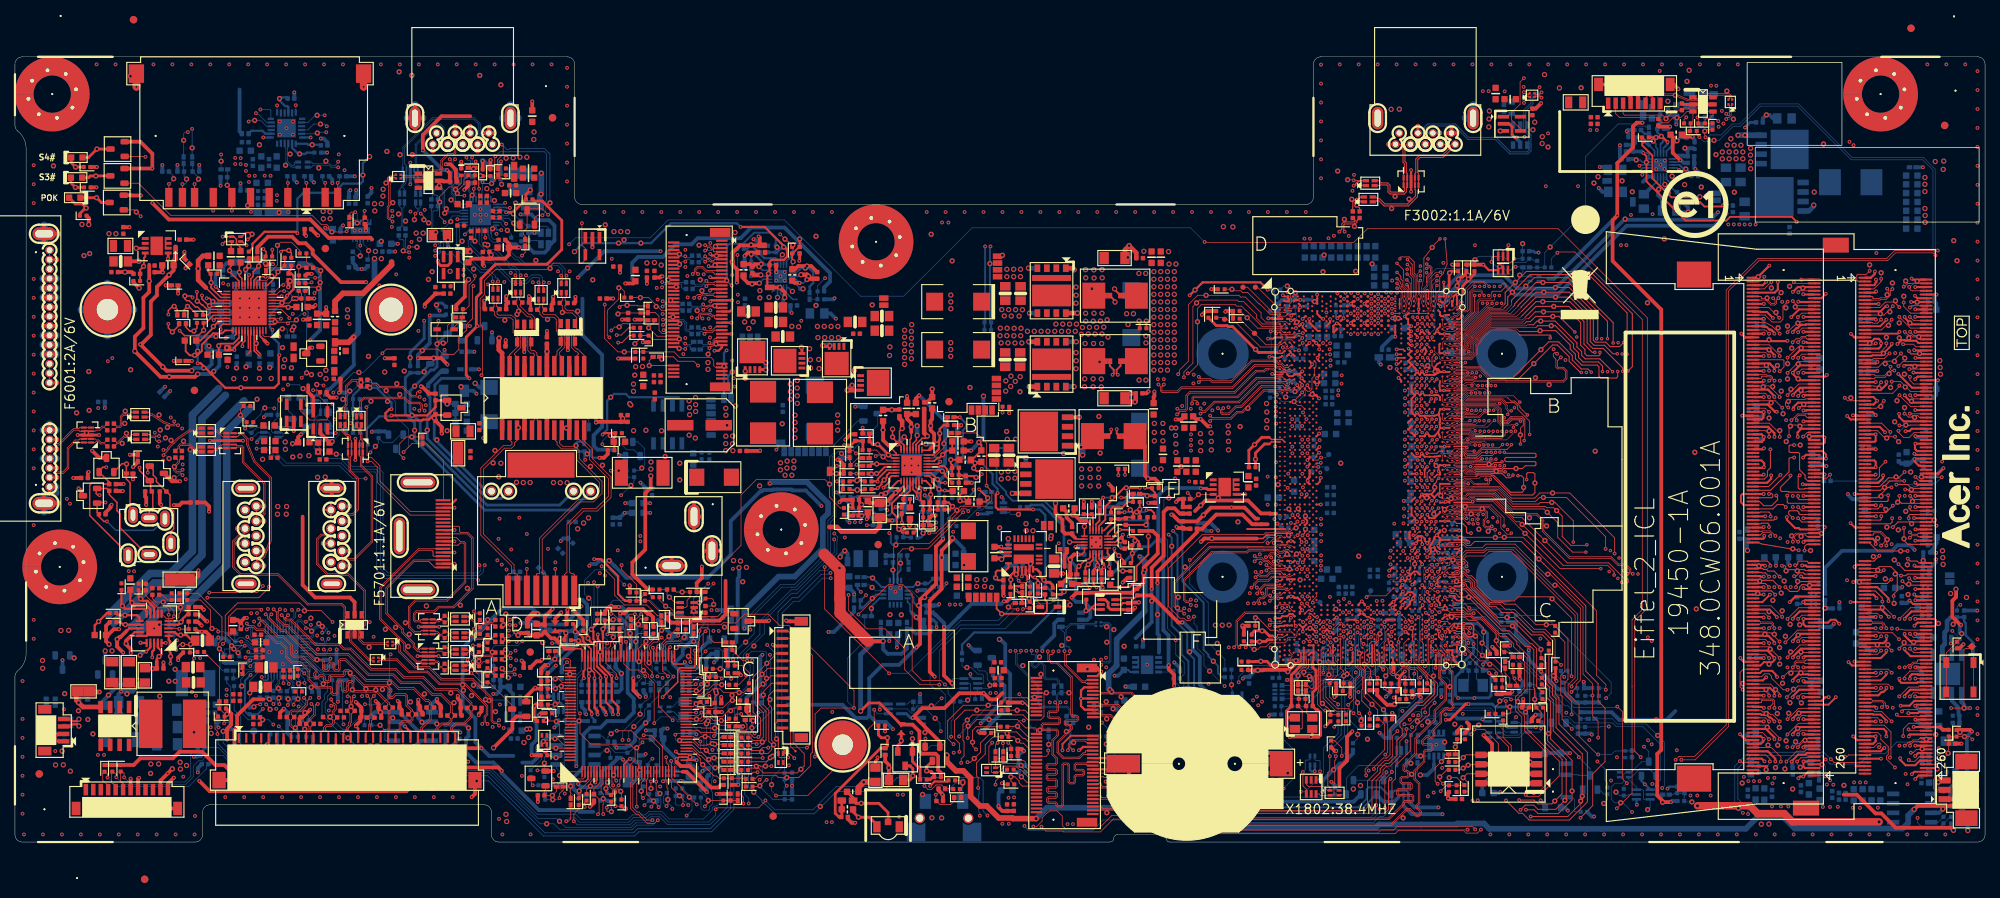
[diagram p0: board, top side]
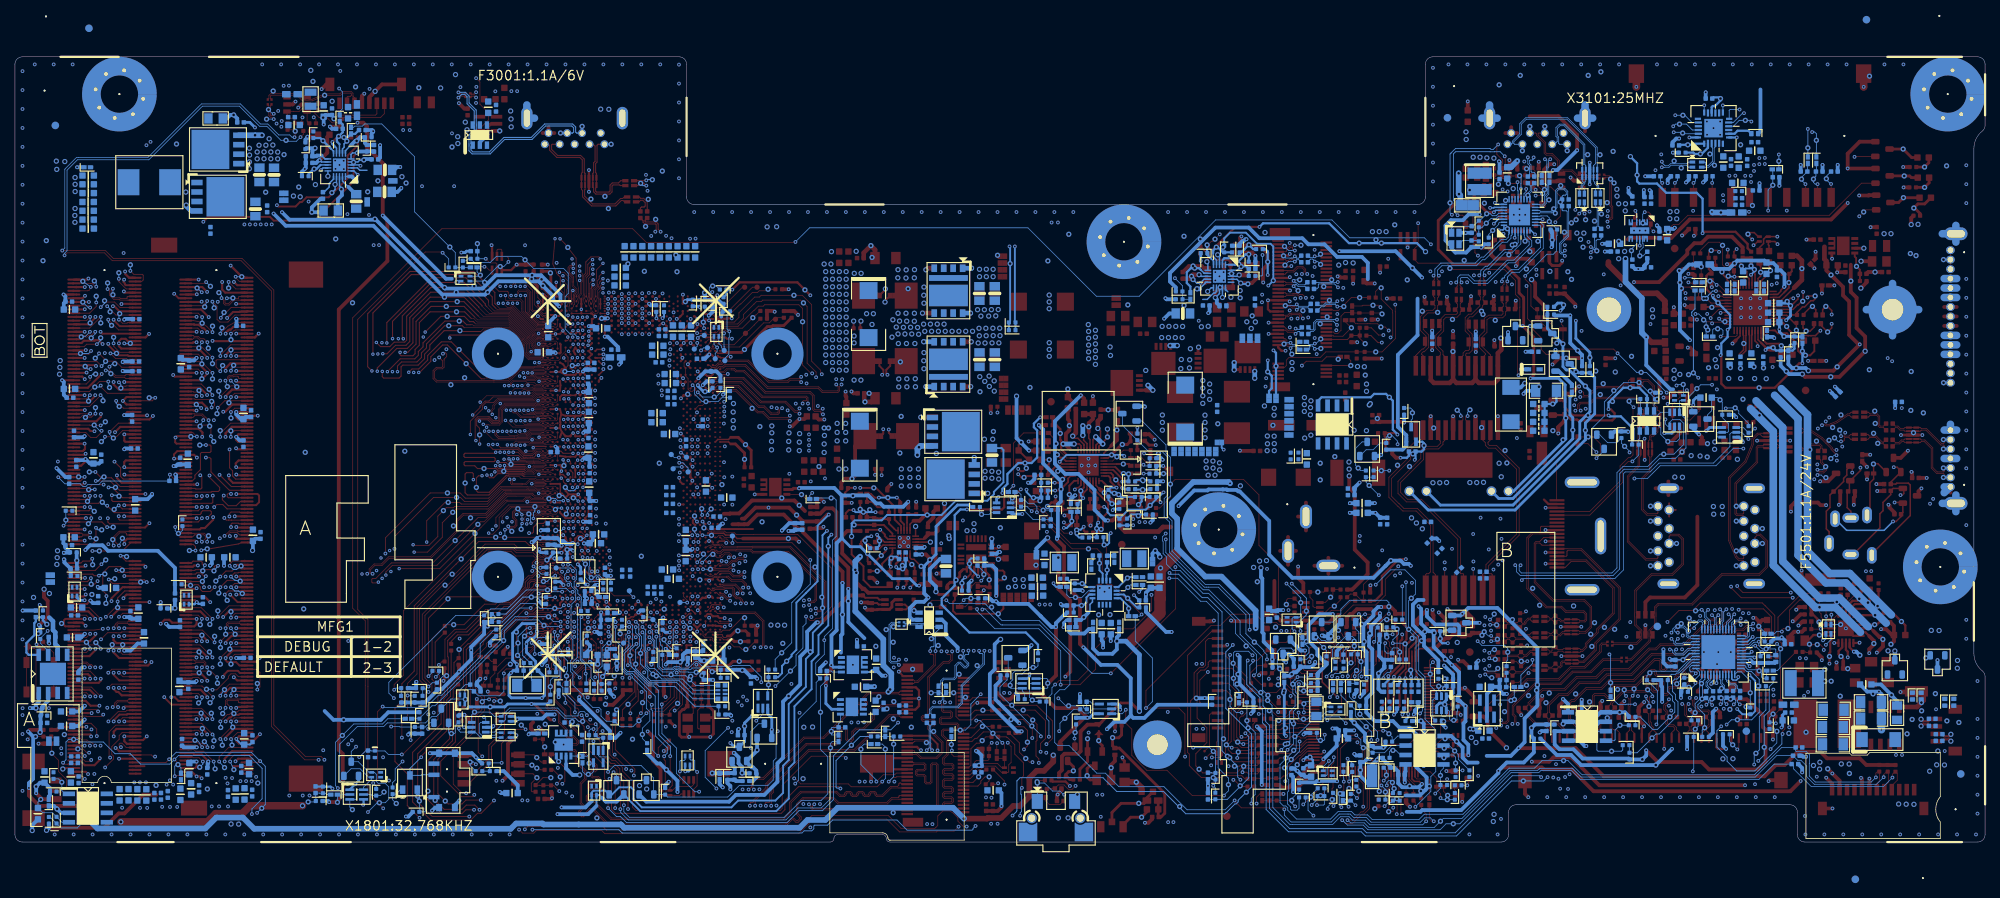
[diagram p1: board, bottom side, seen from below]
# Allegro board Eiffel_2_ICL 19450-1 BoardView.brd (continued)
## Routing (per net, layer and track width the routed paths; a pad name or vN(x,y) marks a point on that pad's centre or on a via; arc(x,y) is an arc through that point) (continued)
PWR_VCCAUX_FB: length 6.4
  TOP w0.203: 146.17,42.01 145.93,41.77 PU5001.6
  TOP w0.254: v1(149.45,44.56) 149.84,44.17 PC5011.1 148.98,43.54 PC5012.2 148.36,43.42 148.25,43.3 PR5013.2 PR5015.1 146.87,42.71 146.17,42.01
PWR_VCCAUX_FSWEL: length 3.3
  TOP w0.203: PU5001.9 144.46,42.83
  TOP w0.254: 144.46,42.83 144.46,43.81 PR5005.1 PR5006.1
PWR_VCCAUX_HG: length 22.9
  TOP w0.203: v2(143.31,42.32) PU5001.11
  TOP w0.508: v2(142.62,56.97) PU5002.4
  L3 w0.762: v2(143.31,42.32) 143.31,42.46 140.82,44.95 140.82,49.64 v2(143.07,51.9) 143.28,52.1 143.28,55.96 142.62,56.62 v2(142.62,56.97)
  BOTTOM w0.762: v2(143.07,51.9) 143.07,52.73 v1(142.86,52.94) 142.69,53.12 PU5005.4
PWR_VCCAUX_ISENSEN: length 23.6
  TOP w0.203: PU5001.3 147.48,40.22 147.69,40.43
  TOP w0.254: v3(147.65,55.37) 147.65,54.77 PG5006.2 ; PC5005.1 148.47,40.48 v3(148.47,41.21) 147.69,40.43 ; PR5011.2 v3(147.86,49.18)
  L4 w0.254: v3(148.47,41.21) 148.33,41.07 147.92,41.07 146.85,42.14 146.85,46.68 147.45,47.28 147.45,48.78 v3(147.86,49.18) 147.45,49.59 147.45,55.17 v3(147.65,55.37)
  BOTTOM w0.254: v3(148.47,41.21) 148.47,41.13 148.16,40.81 v1(148.16,40.39) 148.16,39.75 PR5010.2
PWR_VCCAUX_ISENSEP: length 6.2
  TOP w0.203: PC5005.2 148.16,39.34 147.67,39.82 PU5001.2
  TOP w0.254: PR5008.2 149.73,37.62 v1(149.73,38.71) PR5009.1 149.38,39.81 148.91,39.34 PC5005.2
PWR_VCCAUX_ISENSEP_A: length 20.2
  TOP w0.254: v3(147.33,39.34) 147.33,39 v1(147.91,38.41) 148.64,37.69 PR5008.1 ; PG5005.2 146.9,54.89 v3(146.9,55.32)
  L4 w0.254: v3(146.9,55.32) 146.9,55.29 146.95,55.29 147.07,55.17 147.07,47.44 146.47,46.84 146.47,41.98 147.33,41.12 v3(147.33,39.34)
PWR_VCCAUX_LG: length 22.5
  TOP w0.203: PU5001.13 v2(141.33,40.22)
  TOP w0.635: v2(133.65,46.76) PU5003.4
  L3 w0.635: v2(133.65,46.76) 134.4,47.52 134.65,47.52 135.46,48.33 135.46,48.91 ; 135.46,48.91 v2(135.46,51.56) ; 135.46,48.91 136.45,48.91 136.96,48.4 136.96,45.84 139.6,43.19 139.6,41.39 140.77,40.22 v2(141.33,40.22)
  BOTTOM w0.635: PU5004.4 v2(135.46,51.56)
PWR_VCCAUX_NTC: length 14.9
  TOP w0.254: v3(149.24,41.01) 149.3,40.94 149.97,40.94 150.62,40.29 PR5009.2 ; PR5011.1 v3(148.75,49.24)
  L4 w0.254: v3(148.75,49.24) 148.75,48.96 148.21,48.43 148.21,46.96 147.61,46.36 147.61,44.25 149.24,42.62 v3(149.24,41.01)
  BOTTOM w0.254: v3(149.24,41.01) 149.3,40.94 149.83,40.94 150.08,40.69 v1(150.08,40.43) 150.08,40.09 PR5010.1
PWR_VCCAUX_PG: length 46.2
  TOP w0.203: PU5001.4 147.03,40.62 147.2,40.79
  TOP w0.254: PR5003.1 149.67,41.87 v3(148.06,41.87) 147.44,41.25 147.44,41.03 147.2,40.79
  L3 w0.254: v3(113.36,33.54) 113.56,33.74 114.5,33.74 115.21,33.02 119.54,33.02 121.73,35.22 126.06,35.22 128.1,33.18 129.82,33.18 135.35,38.71 141.88,38.71 142.24,39.07 142.64,39.07 143.72,40.16 143.72,41.13 144.46,41.87 v3(148.06,41.87)
  BOTTOM w0.254: PR5402.2 112.9,34 v3(113.36,33.54)
PWR_VCCAUX_PH: length 15.2
  TOP w0.203: 142.06,40.79 142.23,40.62 PU5001.12
  TOP w0.508: 142.06,40.79 141.66,41.19 PC5003.2 140.72,41.37 140.36,41.73 140.36,43.2 139.44,44.12 v2(139.44,45.42)
  L3 w0.762: v2(139.44,45.42) 138.81,46.04 138.81,50.39 v2(140.53,52.11)
  vias: v1(145.25,57.08) v1(145.42,52.16) v2(142.93,50.03) v2(142.93,48.89) v2(142.93,47.74) v2(144.08,50.03) v2(144.08,48.89) v2(144.08,47.74) v2(145.22,50.03) v2(145.22,48.89) v2(145.22,47.74)
PWR_VCCAUX_PVCC: length 7.6
  TOP w0.203: v3(142.45,38.56) 142.94,38.56 143.31,38.93 PU5001.15
  TOP w0.508: v3(142.45,38.56) 141.93,38.56 141.4,38.04 v1(141.4,37.85) PR5002.1 141.4,35.78 140.25,34.62 PR5001.2
  BOTTOM w0.508: PC5001.1 142.45,38.56 v3(142.45,38.56)
PWR_VCCAUX_VCC: length 3.7
  TOP w0.203: PU5001.16 144.06,38.12 143.86,37.92 143.51,37.92 v1(142.57,36.98) 142.29,36.7 PR5002.2
PWR_VCCAUX_VID0: length 2.9
  TOP w0.203: PU5001.18 144.86,37.76
  TOP w0.254: PR5035.2 144.52,36.54 v1(145.08,37.09) 145.08,37.54 144.86,37.76
PWR_VCCAUX_VID1: length 3
  TOP w0.203: PU5001.17 144.46,37.87
  TOP w0.254: 144.46,37.87 v1(143.82,37.22) 143.43,36.84 PR5034.2
PWR_VCCAUX_VOUT: length 2.9
  TOP w0.203: PU5001.8 144.86,42.61
  TOP w0.254: PR5012.1 145.33,44.43 145.33,43.08 144.86,42.61
PWR_VCCAUX_VOUTA: length 10.1
  TOP w0.254: PR5015.2 146.87,44.65 147.13,44.9 148.41,44.9 149.12,45.61 PR5014.2 149.83,45.62 PR5016.1 149.31,46.7 148.8,46.19 v3(148.23,46.19) ; v3(145.82,46.19) 145.37,45.74 PR5012.2
  BOTTOM w0.254: v3(145.82,46.19) v1(147.03,46.19) v3(148.23,46.19)
PWR_VCCAUX_VSYS: length 6
  TOP w0.203: 146.48,37.74 146.18,38.04 145.79,38.04 145.66,38.17 PU5001.20
  TOP w0.254: 146.48,37.74 146.63,37.59 146.63,36.92 146.62,36.92 ; v3(146.62,36.92) 146.62,36.91 146.61,36.91 146.61,36.9 146.78,36.73 PR5033.1 ; v3(146.62,36.92) 146.62,36.92 146.62,36.92 ; v3(146.62,36.92) 146.62,36.92
  BOTTOM w0.254: v3(146.62,36.92) 146.62,36.92 146.63,36.92 146.63,36.97 146.83,37.18 146.83,37.83 v1(146.57,38.09) 146.39,38.27 145.85,38.27 PC5004.1
PWR_VCORE_ALERT#: length 5.3
  TOP w0.102: PU4601.3 116.91,51.1 v1(116.34,51.66) 115.45,52.56 PR4630.2 PR4674.2
PWR_VCORE_BOOTA: length 7.1
  TOP w0.203: PU4601.25 122.49,52.55 122.63,52.69
  TOP w0.508: PR4612.1 122.91,56.71 122.7,56.51 v1(122.7,55.84) 122.7,55.22 123.17,54.75 123.17,53.22 122.63,52.69
PWR_VCORE_BOOTA_A: length 2.5
  TOP w0.508: PC4604.2 122.2,58.96 PR4612.2 v1(122.91,60.76)
PWR_VCORE_BOOTB: length 5.3
  TOP w0.203: 117.09,53.14 118.09,52.14 PU4601.1
  TOP w0.508: 117.09,53.14 116.33,53.9 v1(116.33,55.26) PR4616.1
PWR_VCORE_BOOTB_A: length 2.2
  TOP w0.508: PR4616.2 v1(117.5,57.96) 118.47,57.96 PC4607.2
PWR_VCORE_CLK: length 4
  TOP w0.203: PU4601.5 116.55,50.3
  TOP w0.254: 116.55,50.3 115.67,49.41 v1(115.45,49.41) 115.45,49.41 PR4634.2
PWR_VCORE_COMP: length 8
  TOP w0.203: v3(121.97,47.28) 121.72,47.52 121.49,47.52 121.14,47.87 PU4601.15
  TOP w0.305: v3(124.55,46.34) PC4612.1 125.1,45.54 v1(125.64,45) 125.22,44.58 124.55,44.58 PR4640.1
  L3 w0.305: v3(121.97,47.28) 122.71,47.28 123.65,46.34 v3(124.55,46.34)
PWR_VCORE_DATA: length 3.7
  TOP w0.203: PU4601.4 116.37,50.7
  TOP w0.254: PR4636.2 114.71,50.7 v1(115.48,50.7) 116.37,50.7
PWR_VCORE_FB: length 6.7
  TOP w0.203: PU4601.16 121.9,48.44
  TOP w0.254: PC4612.2 PR4640.2 PR4641.1 PC4613.1 122.59,45.89 122.71,46 v1(122.71,46.6) 122.71,47.78 122.05,48.44 121.9,48.44
PWR_VCORE_HGA: length 31.5
  TOP w0.203: PU4601.26 121.14,53.14 121.38,53.39 v2(122.07,53.39)
  TOP w0.635: PU4701.1 v2(135.93,61.07)
  L3 w0.635: 138.87,61.07 v2(135.93,61.07) ; 138.87,61.07 v2(141.92,61.07) ; 138.87,61.07 138.87,60.59 137.14,58.86 132.21,58.86 126.88,53.53 122.22,53.53 v2(122.07,53.39)
  BOTTOM w0.635: v2(122.07,53.39) v1(123.54,53.39) ; PU4702.1 v2(141.92,61.07)
PWR_VCORE_HGB: length 46.3
  TOP w0.203: PU4601.32 118.74,53.08 117.6,54.22 v1(117.6,54.32) v2(117.6,55.39)
  TOP w0.635: PU4704.1 141.72,76.95 v2(141.93,76.74)
  L3 w0.635: 138.89,76.95 138.89,75.46 137.52,74.09 132.03,74.09 127.94,70 127.94,64.99 121.89,58.94 120.53,58.94 117.6,56.01 v2(117.6,55.39) ; 138.89,76.95 141.72,76.95 v2(141.93,76.74) ; 138.89,76.95 135.83,76.95 v2(135.81,76.96)
  BOTTOM w0.635: PU4703.1 135.83,76.95 v2(135.81,76.96)
PWR_VCORE_IMON: length 9
  TOP w0.203: PU4601.11 119.54,47.72
  TOP w0.254: PR4601.2 118.88,41.5 v1(118.45,41.94) 118.21,42.18 118.21,43.56 117.52,44.25 117.52,45.43 119.54,47.46 119.54,47.72
PWR_VCORE_ISEN1N: length 4.2
  TOP w0.203: PU4601.19 123.6,49.9
  TOP w0.254: 123.6,49.9 124.1,49.9 v1(124.26,49.73) 124.66,49.33 124.66,49.12 PR4629.1
PWR_VCORE_ISEN1N_A: length 35.4
  TOP w0.254: PR4662.2 PC4601.1 ; PR4662.2 PR4629.2 ; PR4662.2 126.85,49.23 127,49.07 PC4608.2 128.61,49.07 v1(128.79,48.9) 129.13,48.9 v3(129.56,49.33) ; PG4707.1 148.16,63.86 147.62,63.32 147.62,62.83 v3(147.79,62.66)
  L3 w0.254: v3(129.56,49.33) 129.73,49.5 130.12,49.5 130.6,49.98 130.6,54.55 132.25,56.19 137.53,56.19 140.55,59.21 146.73,59.21 147.66,60.14 147.66,62.53 v3(147.79,62.66)
PWR_VCORE_ISEN1P: length 7.4
  TOP w0.203: 123.85,50.31 123.83,50.3 PU4601.20
  TOP w0.254: 123.85,50.31 123.97,50.43 124.49,50.43 124.9,50.03 124.9,49.77 125.44,49.23 PR4662.1 125.59,49.28 PC4601.2 125.59,50.56 125.41,50.75 v1(125.41,51.27) PR4628.1
PWR_VCORE_ISEN1P_A: length 32.3
  TOP w0.254: PR4655.2 129.06,50.99 128.47,50.41 v1(128.47,50.13) 128.88,49.73 129.24,49.73 v3(129.56,50.05) ; v3(147.08,62.66) 147.24,62.83 147.24,63.32 146.71,63.86 PG4706.1
  L3 w0.254: v3(147.08,62.66) 147.28,62.46 147.28,60.29 146.58,59.59 140.39,59.59 137.37,56.58 132.09,56.58 130.22,54.71 130.22,50.14 129.96,49.88 129.75,49.88 129.58,50.05 v3(129.56,50.05)
PWR_VCORE_ISEN1P_B: length 3.2
  TOP w0.254: PR4628.2 128.26,51.27 PR4655.1 129.5,53.27 v1(129.16,53.61)
PWR_VCORE_ISEN2N: length 3.9
  TOP w0.203: PU4601.18 122.76,49.5 123.08,49.17
  TOP w0.254: v3(124.66,48.18) 124.07,48.18 v1(123.63,48.63) 123.08,49.17
  BOTTOM w0.254: PR4635.1 v3(124.66,48.18)
PWR_VCORE_ISEN2N_A: length 51.3
  TOP w0.254: v2(147.36,74.18) 147.36,74.09 PG4701.1
  L3 w0.254: v2(147.36,74.18) 146.73,73.55 146.73,72.05 147.21,71.56 147.21,68.03 148.76,66.48 148.76,59.62 147.84,58.7 140.76,58.7 137.74,55.69 132.46,55.69 131.11,54.34 131.11,48.96 130.86,48.71 129.53,48.71 128.74,47.91 128.74,47.55 v3(128.45,47.26)
  BOTTOM w0.254: v3(128.45,47.26) 128.45,46.93 127.69,46.18 v1(127.51,46.18) PC4610.2 PR4663.2 PR4635.2 126.48,49.23 PC4611.1
PWR_VCORE_ISEN2P: length 6.5
  TOP w0.203: 122.88,48.75 122.53,49.1 PU4601.17
  TOP w0.254: PR4633.1 124.68,47.07 v3(124.61,47.14) 124.02,47.14 123.84,47.32 ; 123.84,47.32 v1(123.82,47.32) ; 123.84,47.32 122.88,48.28 122.88,48.75
  BOTTOM w0.254: v3(124.61,47.14) 124.61,47.14 PR4663.1 PC4610.1
PWR_VCORE_ISEN2P_A: length 46.4
  TOP w0.254: PG4712.1 147.41,72.59 v2(147.41,72.41) ; PR4646.2 130.09,45.65 130.35,45.9 v1(130.35,46.15) v3(129.21,47.3)
  L3 w0.254: v2(147.41,72.41) 147.59,72.23 147.59,68.19 149.14,66.64 149.14,59.47 148,58.32 140.92,58.32 137.9,55.31 132.62,55.31 131.49,54.18 131.49,48.8 131.01,48.32 129.69,48.32 129.12,47.75 129.12,47.38 v3(129.21,47.3)
PWR_VCORE_ISEN2P_B: length 2.7
  TOP w0.254: PR4646.1 126.77,45.65 v1(126.65,45.77) 126.65,46.54 PR4633.2
PWR_VCORE_LGA: length 36.3
  TOP w0.203: PU4601.28 120.34,53.44 120.8,53.89 120.8,54.43 v2(120.9,54.54)
  TOP w0.635: PU4701.8 v2(135.85,67.09)
  L3 w0.635: 138.76,67.09 138.76,65.76 138.13,65.13 133.25,65.13 123.73,55.6 121.97,55.6 v2(120.9,54.54) ; 138.76,67.09 v2(135.85,67.09) ; 138.76,67.09 v2(142.23,67.09)
  BOTTOM w0.635: v2(120.9,54.54) v1(120.9,55.82) ; PU4702.8 v2(142.23,67.09)
PWR_VCORE_LGB: length 42.3
  TOP w0.203: v2(119.17,54.33) 119.54,53.96 PU4601.30
  TOP w0.635: PU4704.8 v2(142.38,70.93)
  L3 w0.635: 139.19,70.93 139.19,70.29 138.61,69.71 131.47,69.71 130.25,68.49 130.25,63.91 123.13,56.79 121.53,56.79 119.17,54.42 v2(119.17,54.33) ; 139.19,70.93 v2(135.95,70.93) ; 139.19,70.93 v2(142.38,70.93)
  BOTTOM w0.635: v2(119.17,54.33) v1(118.22,53.38) ; PU4703.8 v2(135.95,70.93)
PWR_VCORE_NTC1N: length 77.1
  TOP w0.254: PR4639.1 v2(151.61,69.86)
  L3 w0.254: v2(151.61,69.86) 151.45,70.02 151.45,74.26 146.44,79.27 132.03,79.27 130.17,77.41 130.17,75.31 123.87,69.02 123.87,66.01 120.35,62.49 119.38,62.49 117.81,60.91 117.81,59.8 115.53,57.52 115.53,53.46 116.89,52.09 116.89,47.25 115.69,46.05 115.69,42.9 v3(117.17,41.43)
  BOTTOM w0.254: PR4665.1 118.14,39.95 v1(118.04,39.85) 117.62,39.85 117.37,40.11 117.37,41.23 v3(117.17,41.43)
PWR_VCORE_NTC1N_A: length 4.3
  TOP w0.254: PR4677.2 118.83,43.84 118.84,43.82 v3(118.84,42.84)
  BOTTOM w0.254: PR4643.1 120.03,40.88 PR4665.2 119.02,42.05 ; v1(119.04,42.05) 119.02,42.05 ; 119.02,42.05 119.02,42.65 v3(118.84,42.84)
PWR_VCORE_NTC1P: length 78.3
  TOP w0.254: PR4639.2 150.72,69.77 v2(150.64,69.86) ; PR4601.1 120.5,41.5 120.78,41.78 v3(120.78,42.28)
  L3 w0.254: v3(120.78,42.28) 120.78,42.17 120.53,41.92 117.66,41.92 116.33,43.25 116.33,45.79 117.53,46.99 117.53,52.36 116.17,53.72 116.17,57.26 118.44,59.53 118.44,60.65 119.65,61.85 120.62,61.85 124.51,65.75 124.51,68.75 130.8,75.05 130.8,77.15 132.29,78.64 146.17,78.64 150.82,73.99 150.82,70.04 v2(150.64,69.86)
  BOTTOM w0.254: v3(120.78,42.28) 121.17,41.89 121.68,41.89 v1(121.74,41.84) 121.74,41.84 121.74,41.16 121.41,40.83 PR4643.2
PWR_VCORE_PHA: length 30.5
  TOP w0.203: v2(122.26,54.44) 121.97,54.15 121.57,54.15 120.74,53.33 120.74,53.2 120.74,53.19 PU4601.27
  TOP w0.61: PC4604.1 121.84,54.86 v2(122.26,54.44)
  L3 w0.635: v2(122.26,54.44) 122.4,54.29 126.57,54.29 131.9,59.62 133.12,59.62 135.9,62.4 135.9,62.68 136.7,63.48 v2(142.19,63.48)
  vias: v1(145.35,64.39) v2(142.19,65.64) v2(142.21,64.55) v2(143.33,61.06) v2(143.41,66.85) v2(143.35,62.12) v2(144.54,66.85) v2(144.48,62.12) v2(144.48,61.05) v2(145.62,66.85) v2(145.57,62.1) v2(145.57,61.04)
PWR_VCORE_PHB: length 39.2
  TOP w0.203: PU4601.31 119.14,53.23 118.53,53.84 118.53,55.11 v2(118.89,55.46)
  TOP w0.61: PC4607.1 118.51,56.82 118.89,56.45 v2(118.89,55.46)
  L3 w0.635: v2(142.21,73.33) 132.35,73.33 128.7,69.69 128.7,64.67 122.21,58.18 120.85,58.18 118.89,56.22 v2(118.89,55.46)
  vias: v1(144.32,74.21) v2(142.19,74.42) v2(142.19,72.26) v2(143.46,76.76) v2(143.48,75.67) v2(143.47,70.91) v2(144.58,76.73) v2(144.6,75.64) v2(144.6,70.91) v2(145.67,76.76) v2(145.69,75.67) v2(145.66,70.91)
PWR_VCORE_PSYS: length 9
  TOP w0.203: 118.13,48.22 118.35,48.44 PU4601.9
  TOP w0.254: 118.13,48.22 116.69,46.78 116.69,46.77 v1(116.69,46.77) 116.35,46.43 113.37,46.43 113.11,46.18 PC4624.2 PR4637.2 PR4688.2
PWR_VCORE_PVCC: length 6.3
  TOP w0.203: PU4601.29 119.94,53.97 120.11,54.13 120.11,54.98
  TOP w0.508: PR4609.2 PC4603.1 119.55,56.74 120.11,56.19 v1(120.11,55.68) 120.11,54.98
PWR_VCORE_RGND: length 5.8
  TOP w0.203: PU4601.13 120.34,47.28
  TOP w0.254: 120.34,47.28 120.85,46.78 v3(120.85,46.12)
  BOTTOM w0.254: v1(121.18,47.09) 121.18,46.45 v3(120.85,46.12) 121.61,45.36 PR4644.1 121.6,45.31 PR4672.1
PWR_VCORE_SET1: length 7.8
  TOP w0.203: 117.4,49.03 117.46,49.1 PU4601.8
  TOP w0.254: 117.4,49.03 117.21,48.84 117.21,48.35 v3(116.39,47.53)
  BOTTOM w0.254: v3(116.39,47.53) 117.17,47.53 PR4624.1 117.12,46.87 116.37,46.87 v1(116.09,46.58) 115.78,46.27 PR4666.2
PWR_VCORE_SET1_A: length 2.3
  BOTTOM w0.254: v1(113.44,45.25) 113.02,45.67 PR4666.1 111.97,46.27 PR4619.2
PWR_VCORE_SET1_B: length 2.2
  BOTTOM w0.254: 116.97,45.36 117.47,45.87 PR4624.2 ; 116.97,45.36 116.18,45.36 PR4669.1 ; 116.97,45.36 v1(117,45.36)
PWR_VCORE_SET2: length 5.4
  TOP w0.203: PU4601.7 117.15,49.5
  TOP w0.254: PR4660.2 115.11,47.33 115.11,47.33 115.48,47.33 v3(115.63,47.49) 116.13,47.99 116.13,48.22 v1(116.48,48.57) 116.84,48.93 116.84,49.19 117.15,49.5
  BOTTOM w0.254: v3(115.63,47.49) 115.46,47.32 PR4625.1
PWR_VCORE_SET2_A: length 2.2
  TOP w0.254: PR4620.2 112,47.18 v1(112.87,47.18) 113.74,47.18 PR4660.1
PWR_VCORE_SET2_B: length 2.1
  BOTTOM w0.254: PR4668.1 111.91,47.27 v1(112.88,47.27) 113.84,47.27 PR4625.2
PWR_VCORE_SET3: length 6
  TOP w0.203: PU4601.6 116.82,49.9
  TOP w0.254: PR4661.2 114.78,48.37 115.11,48.37 115.11,48.37 115.56,48.37 v3(115.61,48.33) 115.61,48.68 116.82,49.9
  BOTTOM w0.254: v3(115.61,48.33) 115.58,48.36 PR4626.1 v1(114.78,49.35)
PWR_VCORE_SET3_A: length 2.1
  TOP w0.254: PR4661.1 113.81,48.45 v1(112.83,48.45) 111.92,48.45 PR4621.2
PWR_VCORE_SET3_B: length 2.2
  BOTTOM w0.254: PR4626.2 113.69,48.57 v1(112.91,48.57) 112.04,48.57 PR4667.1
PWR_VCORE_SNA: length 2.7
  TOP w0.61: v1(150.09,59.02) 150.19,59.12 PC4701.1
  TOP w0.635: PR4704.2 149.23,59.02 v1(150.09,59.02)
PWR_VCORE_SNB: length 4
  TOP w0.61: v1(149.3,79.98) 150.27,79.02 PC4708.1
  TOP w0.635: v1(149.3,79.98) 148.75,79.42 PR4705.2
PWR_VCORE_TSEN: length 60
  TOP w0.203: PU4601.21 123.69,50.7
  TOP w0.254: 123.69,50.7 v3(124,51)
  L3 w0.254: v3(115.35,51.76) 114.26,52.84 114.26,58.05 116.54,60.32 116.54,63.45 115.52,64.46 115.52,68.32 127.07,79.88 130.01,79.88 v3(130.01,79.87)
  BOTTOM w0.254: v3(124,51) 123.09,51.92 v1(117.05,51.92) 115.51,51.92 v3(115.35,51.76) ; v3(130.01,79.87) 130.01,69.78 PR4702.2 PR4701.2
PWR_VCORE_TSEN_A: length 62
  L3 w0.254: v3(114.16,42.48) 114.67,42.99 114.67,44.6 113.35,45.92 113.35,47.64 115.98,50.27 115.98,52.11 114.9,53.19 114.9,57.79 117.17,60.06 117.17,63.71 116.16,64.73 116.16,68.06 126.79,78.69 129.54,78.69 130.09,79.24 130.27,79.24 130.64,79.61 130.64,79.79 130.73,79.88 v3(130.73,79.87)
  BOTTOM w0.254: v3(114.16,42.48) PR4627.1 115.13,42.48 115.15,42.46 115.99,42.46 PR4622.2 ; PR4701.1 PR4702.1 130.64,69.86 v1(130.64,77.57) 130.64,79.81 130.73,79.89 v3(130.73,79.87)
PWR_VCORE_TSEN_A_A: length 2.9
  BOTTOM w0.254: PR4659.1 113.27,43.93 v1(113.46,43.74) 113.65,43.94 114.4,43.94 PR4627.2
PWR_VCORE_VCC: length 6.5
  TOP w0.203: 118.65,47.35 119.14,47.84 PU4601.10
  TOP w0.508: PC4602.1 114.51,45.49 PR4604.2 116.66,45.49 v1(118.02,46.85) 118.33,47.16 118.46,47.16 118.65,47.35
PWR_VCORE_VCCST: length 11.8
  TOP w0.381: PG4601.2 109.7,50.01 v3(110.13,50.44) ; PR4630.1 113.63,52.61 PR4613.2 113.58,53.8 PC4609.1 112.03,53.23 v3(111.13,53.23)
  L3 w0.381: v3(111.13,53.23) 110.83,53.23 109.64,52.03 109.64,50.93 v3(110.13,50.44)
  BOTTOM w0.381: v1(110.09,49.4) PR4632.1 111.07,50.43 PR4631.1 v3(110.13,50.44)
PWR_VCORE_VIN: length 5.2
  TOP w0.203: PU4601.22 123.18,51.1
  TOP w0.254: PC4605.1 PR4605.1 124.88,52.5 v1(124.32,51.94) 123.92,51.54 123.63,51.54 123.18,51.1
PWR_VCORE_VR_EN: length 5.3
  TOP w0.102: R4603.1 124.49,53.84 v1(124.49,53.43) 124.49,52.91 123.08,51.5 PU4601.23
PWR_VCORE_VR_READY: length 7
  TOP w0.203: PU4601.24 123.01,51.9
  TOP w0.305: R4604.1 PR4607.2 124.44,55.9 123.92,55.39 v1(123.92,54.8) 123.92,53.94 123.81,53.83 123.81,52.7 123.01,51.9
PWR_VCORE_VREF: length 17.4
  TOP w0.203: 119.94,47.73 PU4601.12
  TOP w0.254: v3(110.09,46.9) 110.63,46.9 110.96,47.22 PR4620.1 PR4621.1 ; v3(118.04,44.94) 118.2,44.94 118.21,44.94 PR4677.1 119.05,45.16 PR4615.2 119.05,46.23 119.94,47.12 119.94,47.73
  BOTTOM w0.254: v3(118.04,44.94) 117.95,44.94 117.59,44.58 117.59,44.23 117.19,43.82 116.45,43.82 PR4622.1 114.78,44.57 112.47,44.57 v1(111.89,45.16) 111.06,45.98 PR4619.1 110.7,46.28 v3(110.09,46.9)
PWR_VCORE_VREF_A: length 1.1
  TOP w0.254: PR4615.1 PC4606.1
PWR_VCORE_VSEN: length 7.4
  TOP w0.203: 120.74,47.56 PU4601.14
  TOP w0.254: v1(121.69,41.42) 121.7,41.44 PR4671.1 PR4638.1 PR4641.2 PC4613.2 121.36,45.89 121.36,46.94 120.74,47.56
PWR_VDDQ_BOOT: length 4.9
  BOTTOM w0.203: v1(220.26,87.55) 220.26,87.74 220.51,87.99 PU5103.18
  BOTTOM w0.508: v1(220.26,87.55) 220.18,87.47 220.18,86.75 220.72,86.22 PR5115.1
PWR_VDDQ_BOOT_A: length 4.3
  BOTTOM w0.508: PR5115.2 222.87,84.46 v1(224.22,84.46) 224.22,85.1 223.05,86.26 PC5111.1
PWR_VDDQ_CS: length 3.4
  BOTTOM w0.203: PU5103.13 223.05,90.8
  BOTTOM w0.305: 223.05,90.8 223.59,90.26 v1(223.9,90.26) 223.96,90.26 224.65,89.58 PR5106.1
PWR_VDDQ_EN: length 4.9
  BOTTOM w0.203: PU5103.8 220.51,93.59
  BOTTOM w0.305: PR5113.2 220.08,96.23 PC5110.1 220.08,95.18 v1(220.63,94.64) 220.85,94.41 220.85,93.93 220.51,93.59
PWR_VDDQ_FB: length 5.8
  BOTTOM w0.203: 219,93.42 219.71,92.71 PU5103.6
  BOTTOM w0.508: PC5112.2 216.84,93.48 PR5117.2 217.09,93.74 PR5116.1 217.73,94.52 v1(218.21,94.03) 218.39,94.03 219,93.42
PWR_VDDQ_HG: length 26.6
  L3 w0.635: v2(221.1,88.19) 222.32,86.96 223.88,86.96 225.39,88.47 237.98,88.47 v2(241.04,85.41)
  BOTTOM w0.203: v1(221.53,87.08) 221.1,87.51 v2(221.1,88.19) 220.91,88.38 PU5103.17
  BOTTOM w0.635: v2(241.04,85.41) 241.04,85.27 240.41,84.63 PU5101.4
PWR_VDDQ_LG: length 16.5
  L3 w0.762: v2(222.06,89.29) 222.06,91.4 223.02,92.36 226.62,92.36 229.44,95.18 230.51,95.18 230.91,94.78 v2(230.9,94.78)
  BOTTOM w0.203: PU5103.15 v2(222.06,89.29)
  BOTTOM w0.762: PU5102.4 v1(231.82,94.78) v2(230.9,94.78)
PWR_VDDQ_PG: length 3.7
  BOTTOM w0.203: 221.63,92.96 221.31,92.64 PU5103.10
  BOTTOM w0.305: PR5110.2 223.08,94.41 v1(222.72,94.05) 221.63,92.96
PWR_VDDQ_PH: length 21.7
  L3 w0.635: v2(241.1,87.16) 240.55,87.16 238.35,89.36 224.73,89.36 223.74,88.37 v2(223.74,88.16)
  BOTTOM w0.203: PU5103.16 221.31,88.89 221.89,88.31 221.89,87.84 222.58,87.15 PC5111.2
  vias: v1(242.35,93.61)
PWR_VDDQ_TON: length 4.5
  TOP w0.305: v3(221.45,93.88) 220.84,94.49 v1(219.91,94.49) PR5111.2
  BOTTOM w0.203: 221.07,93.23 220.91,93.07 PU5103.9
  BOTTOM w0.305: v3(221.45,93.88) 221.45,93.61 221.07,93.23
PWR_VDDQ_VDD: length 6.3
  TOP w0.508: v3(223.16,91.43) 222.15,92.44 222.15,94.56 PR5109.2
  BOTTOM w0.203: PU5103.12 222.93,91.2 223.16,91.43 223.16,91.43 v3(223.16,91.43)
  BOTTOM w0.508: PC5108.1 223.61,91.08 223.27,91.43 v3(223.16,91.43)
PWR_VDDQ_VDDQ: length 51.5
  TOP w0.254: v3(238.75,83.18) 238.1,83.84 229.83,83.84 229.33,83.34 223.88,83.34 218.62,88.59 v1(218.62,91.16) 218.62,91.98 v3(218.19,92.41)
  L4 w0.254: v3(255.67,90.49) 248.36,83.18 v3(238.75,83.18)
  BOTTOM w0.203: PU5103.5 218.96,92.21 218.76,92.41 v3(218.19,92.41)
  BOTTOM w0.508: PR5120.1 v3(255.67,90.49) ; v3(218.19,92.41) 217.99,92.61 PR5117.1 216.84,92.62 215.96,92.62 215.95,92.62 215.91,92.62 PC5112.1
PWR_VDDQ_VID: length 4.9
  BOTTOM w0.203: 222.9,92.06 222.44,91.6 PU5103.11
  BOTTOM w0.508: PR5108.1 224.95,93.05 v1(223.79,93.05) 224.14,92.7 PC5109.1 223.63,91.96 223.53,92.06 222.9,92.06
PWR_VDDQ_VLDOIN: length 3.2
  BOTTOM w0.203: 219.32,87.85 220.11,88.64 PU5103.19
  BOTTOM w0.508: 219.32,87.85 218.34,86.88 PC5102.1
  vias: v1(216.73,87.2)
PWR_VDDQ_VTT: length 4.1
  BOTTOM w0.203: 216.83,90.09 217.78,90.09 218.1,90.4 PU5103.2 ; 219.23,89.25 PU5103.20
  BOTTOM w0.508: 218.15,88.54 218.87,89.25 219.23,89.25
  vias: v1(215.36,88.67)
PWR_VDDQ_VTTREF: length 2.9
  BOTTOM w0.203: v1(217.25,91.47) 217.27,91.45 217.8,91.45 218.04,91.2 PU5103.4
  BOTTOM w0.508: v1(217.25,91.47) 217.12,91.6 216.3,91.6 216.25,91.55 PC5113.1
PWR_VNN:
  vias: v1(110.49,36.74)
PWR_VNN1D05V_BOOTA: length 2.5
  BOTTOM w0.254: PU5401.2 117.74,35.88 117.65,35.97 v1(117.65,36.48) PC5404.2
PWR_VNN1D05V_BOOTA_A: length 1
  BOTTOM w0.508: PR5401.1 PC5404.1
PWR_VNN1D05V_BOOTB: length 3.5
  BOTTOM w0.254: PU5401.3 118.24,36.01 118.67,36.44 v1(118.67,37.4) 118.67,37.56 118.67,37.56 PC5405.2
PWR_VNN1D05V_BOOTB_A: length 1
  BOTTOM w0.254: PC5405.1 119.56,37.85 119.76,37.65 PR5423.1
PWR_VNN1D05V_FB2: length 3.9
  BOTTOM w0.254: PR5408.2 122.39,34.66 121.99,34.66 PR5407.1 121.81,34.67 121.8,34.66 v1(120.99,34.66) 120.87,34.66 120.75,34.55 120.7,34.55 120.35,34.2 PU5401.5
PWR_VNN1D05V_PG1: length 18.9
  L3 w0.254: v3(124.83,34.71) 122.92,34.71 120.73,32.52 114.64,32.52 v3(114.04,33.11)
  BOTTOM w0.254: v3(124.83,34.71) 124.83,34.56 124.48,34.22 PR5403.2 ; PU5401.14 115.4,33.2 v1(114.89,32.69) 113.66,31.46 PR5420.2 113.23,31.56 113.23,32.29 PC5406.2 114.04,33.11 v3(114.04,33.11)
PWR_VNN1D05V_PG2: length 4.5
  BOTTOM w0.254: PU5401.7 120.04,33.2 120.42,32.81 120.42,32.14 120.84,31.72 v1(121.08,31.72) PC5407.2 122.14,30.8 PR5421.2
PWR_VNN1D05V_VCC: length 5.2
  BOTTOM w0.203: PU5401.8 119.61,32.2 119.94,31.87 119.94,30.98 120.14,30.78
  BOTTOM w0.508: PR5413.2 PC5401.2 121.14,29.78 v1(120.78,30.14) 120.14,30.78
PWR_VNN1D05V_VID: length 3.4
  BOTTOM w0.254: PR5405.1 v1(114.77,31.33) 114.77,31.6 115.86,32.7 PU5401.13
PWR_VNN1D05V_VINA:
  vias: v1(117.26,30.5)
PWR_VNN1D05V_VINB:
  vias: v1(118.78,30.47)
PWR_VNN1D05V_VOUT1: length 3.1
  BOTTOM w0.254: PR5419.1 114.81,35.53 v1(114.93,35.41) 116.14,34.2 PU5401.16
PWR_VNN_EN: length 2.9
  BOTTOM w0.102: PR5402.1 114.53,34.48 v1(114.86,34.14) 115.31,33.7 PU5401.15
PWR_VREF: length 4.1
  TOP w0.305: C5504.2 23.74,27.01 23,27.76 v1(22.2,27.76) 21.82,27.76 21.43,28.15 U5501.2
PWR_VTT_EN: length 4.4
  BOTTOM w0.203: v1(219.52,94) 219.89,93.63 219.89,93.17 220.11,92.95 PU5103.7
  BOTTOM w0.305: v1(219.52,94) 219.52,94.41 218.97,94.96 PR5114.2 218.41,94.96 PC5116.1
PWRBTN#: length 10.9
  TOP w0.102: L6405.1 125.87,5.5 125.39,5.02 123.96,5.02 EC6401.1 123.4,5.58 v3(123.4,6.35)
  BOTTOM w0.102: v3(123.4,6.35) 123.4,6.32 123.44,6.32 123.95,6.83 124.94,6.83 126.02,7.91 v1(127,7.91) PWRBT1.1
PWRBTN#_1: length 3.5
  TOP w0.102: L6405.2 126.79,6.5 126.62,6.67 R6409.2 127.03,7.52 v1(127.03,8.09) 126.85,8.27 R6408.1
PWRBTN_IN: length 44.5
  TOP w0.102: R6409.1 125.2,7.11 125.14,7.17 C6401.1 124.65,7.18 124.18,7.66 123.42,7.66 122.82,7.06 122.34,7.06 v3(121.88,7.53)
  L3 w0.127: v3(121.88,7.53) 121.85,7.56 117.79,7.56 115.75,5.52 105.91,5.52 105.55,5.17 100.81,5.17 100.75,5.11 100.37,5.11 100.31,5.17 v3(98.32,5.17)
  BOTTOM w0.102: v3(98.32,5.17) 98.32,5.85 97.8,6.38 97.8,14.69 98.92,15.8 v1(98.92,16.28) R24088.1 99.92,18.74 R24058.2
PWRGD_PS_L: length 4.6
  BOTTOM w0.102: Q2403.2 72.84,20.02 73.22,20.39 v1(73.22,20.9) C2424.1 R24097.1 73.26,21.89 R24018.2
PWRGD_PS_L1: length 6.6
  BOTTOM w0.102: R24100.2 70.68,17.57 70.77,17.48 70.77,16.43 70.88,16.33 v1(71.21,16.33) 71.63,16.33 71.74,16.44 71.74,17.51 71.9,17.67 Q2403.6 72.19,16.94 72.26,16.87 72.74,16.87 72.84,16.97 Q2403.5
PWRLED_CON: length 8.1
  TOP w0.381: LED1.2 117,3.96 115.77,5.19 v1(113.41,5.19) 112.69,5.19 R6412.2 112.31,5.93 L6401.1
PWRLED_CON_5V: length 3.2
  TOP w0.762: L6401.2 113.03,7.31 v1(113.74,8.02) 113.77,8.06 R6404.1
PWROK3_1: length 6.9
  TOP w0.102: v3(87.31,4.82) 87.5,5.01 v1(87.5,5.7) 87.5,7.15 87.37,7.29 87.37,8.27 87.2,8.44 ECIO1.29
  BOTTOM w0.102: R24089.2 86.91,6.13 86.91,5.23 v3(87.31,4.82)
PWROK3_1_R: length 13.7
  TOP w0.102: R24032.1 95.9,5.56 C2403.1 94.94,5.57 R24062.1 93.23,5.56 v3(92.44,4.78)
  L4 w0.127: v3(88.09,4.43) 88.16,4.43 88.2,4.39 92.06,4.39 v3(92.44,4.78)
  BOTTOM w0.102: R24112.2 91.91,6.79 92.91,5.79 v1(92.91,5.58) 92.91,5.24 v3(92.44,4.78) ; R24089.1 87.37,5.43 88.09,4.7 v3(88.09,4.43)
Q4002_2: length 8.4
  BOTTOM w0.102: Q4001.2 129.9,44.84 129.58,44.52 128.83,44.52 127.58,43.27 R4038.1 C4001.1 125.14,43.34 R4002.2 126.19,44.52 v1(126.22,44.5)
Q4002_6: length 4.7
  BOTTOM w0.102: 133.21,44.19 133.46,43.94 v1(134.47,43.94) 134.72,44.19 134.72,44.91 R4003.2 ; 133.21,44.19 133.31,44.29 133.31,44.67 133.15,44.84 Q4001.5 ; 133.21,44.19 Q4001.6
Q9639_AB_EC: length 4.3
  BOTTOM w0.102: 125.6,21.3 125.6,20.72 125.7,20.62 Q4009.1 ; 125.6,21.3 v1(125.6,21.3) ; 125.6,21.3 125.6,21.79 125.73,21.92 Q4009.3
RING2: length 63.5
  TOP w0.203: U2701.17 32.02,75.33 32.5,75.81 v3(33.58,75.81) 33.6,75.82 33.6,76.54 R2733.1 ; AUDS1.3 17.67,38.57 14.09,42.15 14.09,44.02 13.67,44.44 13.67,45.56 12.64,46.59 EC2913.1 12.33,47.42 ED2905.2 10.89,47.29 10.89,46.73 11.09,46.53 v3(11.33,46.53)
  L4 w0.203: v3(33.58,75.81) 32.63,76.76 25.21,76.76 23.7,75.25 23.7,73.82 21.6,71.72 20.52,71.72 19.52,70.72 19.52,65.73 14.55,60.76 14.55,50.88 11.33,47.67 v3(11.33,46.53)
  BOTTOM w0.203: v3(33.58,75.81) 33.61,75.83 34.36,75.83 v1(34.42,75.89)
RSMRST_PWRGD#: length 90.5
  TOP w0.102: v3(100.56,5.58) 100.56,5.49 99.66,4.59 94.1,4.59 v3(93.9,4.38) ; PR5317.2 133.67,32.05 v1(133.13,31.51) 133.36,31.27 134.28,31.27 v3(134.37,31.18) ; v3(73.87,2.78) 74.14,2.78 74.47,3.11 R24031.1
  BOTTOM w0.102: v3(93.9,4.38) 93.9,3.6 92.98,2.69 87.59,2.69 86.53,3.75 85.36,3.75 85.07,3.75 84.6,3.29 82.89,3.29 82.27,2.67 75.65,2.67 75.07,3.25 74.34,3.25 v3(73.87,2.78) ; v3(134.37,31.18) 134.28,31.27 134.01,31.27 131.85,29.12 131.65,29.12 131.64,29.11 126.67,29.11 122.63,25.08 122.63,21.14 123.35,20.43 124,20.43 124.67,19.75 124.67,13.35 124.28,12.96 122.75,12.96 119.03,9.24 117.88,9.24 116.07,7.43 110.03,7.43 106.93,4.33 101.82,4.33 v3(100.56,5.58)
RSMRST_PWRGD#_ECIO: length 5.3
  TOP w0.102: ECIO1.2 76.4,8.72 76.13,8.46 74.58,8.46 74.47,8.35 v1(74.47,7.49) R24031.2
RSVD: length 7.3
  TOP w0.102: CPU1.J3 166.53,68.91 v1(165.12,70.32) 164.99,70.45 164.96,70.45 164.72,70.69 164.69,70.69 164.15,71.23 R403.2
RTC_DET#: length 96.5
  TOP w0.102: v3(212.15,14) 212.15,16.19 211.39,16.95 v3(211.39,19.65) 211.39,21.27 210.12,22.53 210.12,31.52 205.73,35.92 v1(205.41,35.92) 205.04,35.92 201,39.96 197.1,39.96 196.61,39.47 194.5,39.47 194.12,39.85 193.59,39.85 193.34,39.6 191.59,39.6 CPU1.CH45
  L3 w0.127: v3(165.39,12.63) 166.93,11.09 168.19,11.09 168.76,11.65 174.67,11.65 176.08,13.06 177.41,13.06 177.89,12.58 188.28,12.58 189.5,13.81 196.31,13.81 196.5,13.61 203,13.61 203.77,12.84 210.98,12.84 v3(212.15,14)
  BOTTOM w0.102: v3(211.39,19.65) 211.34,19.6 R2003.1 ; Q2501.D 164.35,15.87 165.39,14.83 v3(165.39,12.63)
RTC_INTRUDER#: length 8.8
  TOP w0.102: v3(191.69,26.36) 191.93,26.6 CPU1.DR47
  BOTTOM w0.102: R1704.2 v1(192.26,20.84) 192.26,21.68 191.92,22.02 191.37,22.02 191.07,22.32 191.07,24.19 191.52,24.64 R1746.1 191.98,24.65 C1701.1 191.98,26.08 v3(191.69,26.36)
RTC_RST#: length 113.9
  TOP w0.102: CPU1.DT47 192.64,26.27 192.87,26.5 193.41,26.5 193.53,26.38 193.9,26.38 195.03,25.25 195.03,24.74 196.55,23.22 198.15,23.22 198.48,22.89 v3(198.48,22.61) ; CMOS1.3 CMOS1.1 262.45,24.93 262.22,25.16 G2530.1 261.37,25.97 261.17,25.77 v1(261.17,17.96) v3(259.45,17.96)
  L3 w0.127: v3(259.45,17.96) 259.64,17.77 259.64,11.3 259.64,10.99 259.64,10.95 258.92,10.23 258.92,8.1 256.36,5.54 256.32,5.54 256.06,5.28 249.09,5.28 248.56,4.76 248.53,4.76 247.62,3.85 245.3,3.85 238.57,3.85 238.51,3.91 232.86,3.91 232.68,4.1 232.68,4.13 232.08,4.72 232.05,4.72 229.09,7.68 226.71,7.68 226.71,7.68 223.24,7.68 222.26,6.7 220.5,6.7 v3(219.41,7.79)
  BOTTOM w0.102: v3(198.48,22.61) 198.48,20.18 199.05,19.62 201.91,19.62 C1821.1 202.77,20.47 203.59,20.47 203.72,20.33 RN1804.3 203.72,19.3 203.85,19.18 205.59,19.18 Q1820.D 206.87,17.48 207.54,16.82 208.14,16.82 208.98,15.98 214.09,15.98 214.6,15.48 218.13,15.48 220.48,13.13 220.48,8.34 219.93,7.79 v3(219.41,7.79)
RTC_RST#_R: length 3.9
  BOTTOM w0.102: R1833.1 205,15.62 205,14.65 205.1,14.55 v1(205.51,14.55) 205.78,14.55 205.89,14.65 Q1820.S
RTCRST_ON: length 159.5
  L3 w0.127: v3(213.58,15.49) 212.63,16.44 206.23,16.44 204.99,17.68 196.26,17.68 194.51,15.93 193.53,15.93 192.75,15.15 187.49,15.15 v3(187.22,15.42)
  L4 w0.127: v3(82.24,13.68) 83.4,12.52 85.82,12.52 86.39,13.09 89.37,13.09 90.13,12.33 90.13,10.42 92.62,7.93 93.23,7.93 93.48,7.69 95.2,7.69 96.03,8.52 98.53,8.52 100.41,6.64 100.65,6.64 100.86,6.43 101.06,6.43 101.41,6.08 101.41,5.76 101.67,5.5 106.65,5.5 107.25,6.1 115.11,6.1 116.12,7.11 119.92,7.11 120.36,6.67 123.05,6.67 123.23,6.84 124.53,6.84 125,6.38 129.41,6.38 130.25,7.22 134.39,7.22 134.62,6.99 142.38,6.99 143.26,6.11 154.69,6.11 155.29,6.71 155.43,6.85 160,6.85 161.07,7.92 162.46,7.92 163.23,8.68 164.33,8.68 164.59,8.95 170.96,8.95 170.98,8.93 175.49,8.93 175.88,9.32 177.64,9.32 177.78,9.46 179.04,9.46 179.59,10.01 181.19,10.01 185.21,14.03 185.61,14.03 186.26,14.68 186.65,14.68 187.22,15.25 v3(187.22,15.42)
  BOTTOM w0.102: v3(213.58,15.49) 212.46,15.49 212.4,15.43 R1821.1 209.44,15.43 C1823.1 209.01,15.42 208.81,15.62 208.8,15.62 208.43,15.99 Q1820.G ; R24033.2 86.32,19.67 R24056.1 84.38,17.74 84.38,16.93 v1(82.94,15.48) 82.24,14.79 v3(82.24,13.68)
RTCRST_ON_R: length 6.5
  TOP w0.102: v3(85.38,22.24) 85.38,22.79 84.4,23.78 ECIO1.75
  BOTTOM w0.102: R24033.1 86.11,21.28 85.38,22.01 v3(85.38,22.24) 85.38,23.64 v1(84.98,24.05)
RTL_ISOLATE_N: length 6.6
  TOP w0.114: R3160.2 63.7,89.32 63.25,89.32 63.25,89.32 62.69,89.32 R3161.1 62.67,89.32 62.22,89.32 62.13,89.23 62.13,88.82 62.13,88.82 62.13,87.68 v3(62.2,87.61)
  BOTTOM w0.114: v1(62.38,89.36) 62.19,89.17 62.19,88.31 62.2,88.29 v3(62.2,87.61) 62.2,86.94 62.18,86.92 LAN1.20
SA1_DIMB: length 4.7
  TOP w0.102: v3(242.58,8.82) 242.48,8.92 DIMM2.260
  BOTTOM w0.102: v3(242.58,8.82) 242.58,10.18 242.38,10.38 v1(242.15,10.38) 241.75,9.98 R1302.2
SATAXPCIE1: length 3
  TOP w0.102: CPU1.CR42 189.52,36.78 189.22,36.48 v3(189.22,36.33)
  BOTTOM w0.102: TP1611.1 191.47,36.75 189.64,36.75 v3(189.22,36.33)
SD3_RCOMP: length 3.5
  TOP w0.305: v3(190.75,38.79) 190.21,39.33 CPU1.CJ43
  BOTTOM w0.305: v3(190.75,38.79) 190.79,38.82 R1902.1 191.9,38.61 192.18,38.33 192.18,38.31 192.66,37.83 v1(192.71,37.83)
SD_CD_N#: length 27.5
  TOP w0.114: CRS1.11 v3(43.26,88.39)
  L3 w0.127: v3(31.32,96.63) 31.37,96.68 34.66,96.68 35.94,97.96 41.75,97.96 42.31,97.4 42.31,89.34 v3(43.26,88.39)
  BOTTOM w0.114: EC3328.1 43.5,88.63 v3(43.26,88.39) ; U3301.10 33.73,95.99 32.94,96.78 v1(32.13,96.78) 31.47,96.78 v3(31.32,96.63)
SD_CLK: length 17.3
  L3 w0.127: v3(37.64,98.81) 36.07,98.81 34.45,97.19 29.94,97.19 27.63,94.88 v3(27.63,92.2)
  BOTTOM w0.114: v3(27.63,92.2) v1(27.63,91.31) R3305.1 ; U3301.18 v3(37.64,98.81)
SD_CLK_1: length 7.6
  TOP w0.114: CRS1.5 v3(29.07,84.68)
  BOTTOM w0.114: R3305.2 28.45,90.14 EC3326.1 v1(28.45,88.08) 29.07,87.46 v3(29.07,84.68)
SD_CMD: length 24.9
  TOP w0.114: CRS1.2 v3(36.57,88.39)
  L3 w0.127: v3(36.57,88.39) 36.57,94.88 37.64,95.95 38.23,95.95 39.07,95.11 39.25,95.11 39.43,95.29 39.43,95.47 38.26,96.64 38.26,96.82 38.44,97 38.62,97 39.89,95.72 40.07,95.72 40.25,95.9 40.25,96.08 39.47,96.86 39.47,97.04 39.89,97.46 v3(41.51,97.46)
  BOTTOM w0.114: v3(36.57,88.39) 36.51,88.45 EC3327.1 ; U3301.20 39.25,96.49 40.23,97.46 v1(40.49,97.46) v3(41.51,97.46)
SD_DATA0: length 17.4
  L3 w0.127: v3(23.75,95.63) 26.9,98.79 v3(35.14,98.79)
  BOTTOM w0.114: U3301.13 v3(35.14,98.79) ; v3(23.75,95.63) v1(23.75,93.09) R3303.1
SD_DATA0_1: length 5.1
  TOP w0.114: CRS1.7 v3(24.07,88.23)
  BOTTOM w0.114: R3303.2 23.81,90.93 EC3322.1 24.6,89.13 v1(24.6,88.9) 24.6,88.77 v3(24.07,88.23)
SD_DATA1: length 17.4
  L3 w0.127: v3(32.89,98.24) 27.02,98.24 23.88,95.1 23.28,95.1 v3(23.17,95.21)
  BOTTOM w0.114: v3(23.17,95.21) 22.83,95.21 22.61,94.99 v1(22.61,94.11) R3304.1 ; U3301.12 34.29,98.12 34.18,98.24 v3(32.89,98.24)
SD_DATA1_1: length 5.1
  TOP w0.114: CRS1.8 v3(22.44,88.23)
  BOTTOM w0.114: R3304.2 22.61,89.98 EC3323.1 22.67,89.31 23,88.98 v1(23,88.9) 23,88.47 22.76,88.23 v3(22.44,88.23)
SD_DATA2: length 24.9
  TOP w0.114: CRS1.9 v3(41.57,88.39)
  L3 w0.127: v3(41.72,95.18) 41.84,95.06 41.84,94.17 41.17,93.5 41.17,92.7 41.04,92.58 39.67,92.58 39.54,92.45 39.54,92.2 39.67,92.07 41.34,92.07 41.47,91.94 41.47,91.69 41.34,91.56 39.76,91.56 39.63,91.43 39.63,91.18 39.76,91.05 41.74,91.05 41.87,90.93 41.87,90.67 41.74,90.54 40.11,90.54 39.98,90.42 39.98,90.16 40.11,90.04 41.74,90.04 41.87,89.91 41.87,89.66 41.74,89.53 41.17,89.53 41.05,89.4 41.05,88.92 v3(41.57,88.39)
  BOTTOM w0.114: EC3324.1 41.21,88.75 v3(41.57,88.39) ; v3(41.72,95.18) 40.62,95.18 v1(40.52,95.08) 40.43,94.99 U3301.23
SD_DATA3: length 24.8
  TOP w0.114: CRS1.1 v3(39.07,88.39)
  L3 w0.127: v3(39.07,88.39) 39.07,89.04 39.2,89.17 40.48,89.17 40.61,89.3 40.61,89.55 40.51,89.66 38.21,89.66 38.06,89.8 38.06,90.06 38.19,90.18 39.45,90.18 39.57,90.31 39.57,90.57 39.45,90.69 38.19,90.69 38.06,90.82 38.06,91.07 38.19,91.2 39.08,91.2 39.21,91.33 39.21,91.58 39.08,91.71 38.19,91.71 38.06,91.84 38.06,92.09 38.19,92.22 38.94,92.22 39.07,92.34 39.07,93.27 v3(41.79,95.98)
  BOTTOM w0.114: v3(41.79,95.98) 41.49,96.28 v1(40.95,96.28) 40.02,96.28 39.23,95.49 U3301.22 ; v3(39.07,88.39) 38.8,88.66 EC3325.1
SD_WP: length 23.7
  TOP w0.114: CRS1.10 20.63,88.24 v3(20.64,88.25)
  L3 w0.127: v3(32.3,97.75) 29.36,97.75 23.05,91.44 21.26,91.44 20.64,90.82 v3(20.64,88.25)
  BOTTOM w0.114: v3(20.64,88.25) 20.69,88.25 21.27,88.83 v1(21.27,88.95) 21.27,89.28 EC3321.1 ; U3301.11 33.75,96.49 32.49,97.75 v3(32.3,97.75)
SDREG: length 3.8
  BOTTOM w0.305: U3301.16 36.64,98.55 36.49,98.7 36.2,98.7 35.45,99.44 v1(35.45,99.7) 35.61,99.86 36.39,99.86 C3301.1
SE_BJT_B1: length 3
  BOTTOM w0.102: Q4012.5 216.28,6.37 216.14,6.23 R4011.2 215.02,6.23 v1(214.54,6.7)
SE_BJT_B2: length 4.3
  BOTTOM w0.102: R4014.2 222.21,6.36 222.41,6.55 R4012.1 223.18,6.55 223.2,6.57 C4024.1 223.72,6.07 223.67,6.02 223.67,5.51 R4033.2 223.8,5.38 v1(224.71,5.38)
SE_BJT_B3: length 2.7
  BOTTOM w0.102: Q4012.2 220.56,6.37 R4014.1 v1(220.79,5.33)
SE_VPP_EN_B: length 11.2
  BOTTOM w0.102: Q4013.B 218.96,9.83 217.74,9.83 216.6,8.69 RN4001.4 216.19,8.45 217.28,7.37 Q4012.6 218.1,7.02 218.24,6.88 218.24,5.8 218.32,5.72 Q4012.3 219.12,4.69 v1(218.78,4.35)
SE_VTT_EN: length 29.7
  BOTTOM w0.102: PR5114.1 218.61,95.85 218.46,96.01 217.45,96.01 217.15,96.3 214.85,96.3 210.44,91.89 210.44,84.51 v1(205.72,79.79) 204.99,79.06 R4045.2 204.98,77.05 R4022.2 203.97,77.06 R4018.2
SELEEVE: length 67.6
  TOP w0.203: U2701.18 31.62,75.56 31.92,75.85 31.92,76.49 v1(32.65,77.23) 32.65,77.5 33.58,78.42 R2723.1 33.65,78.6 33.65,79.17 v3(33.29,79.53) ; v3(12.13,45.54) 11.11,45.54 ED2905.1 11.02,44.22 11.25,43.99 EC2909.1 11.25,43.66 11.92,42.99 v3(12.33,42.99)
  L4 w0.203: v3(12.13,45.54) 11.42,45.54 10.7,46.27 10.7,50.19 13.38,52.87 13.38,61.24 15.73,63.59 18.36,66.22 18.36,71.21 22.53,75.38 22.53,75.73 26.33,79.53 v3(33.29,79.53)
  BOTTOM w0.203: AUDS1.4 18.56,41.81 13.52,41.81 v3(12.33,42.99)
SIO_AGND: length 100.3
  TOP w0.203: ECIO1.83 v3(81.2,26.67)
  TOP w0.508: RT2402.2 81.01,27.65 81.2,27.46 v3(81.2,26.67) ; RT2401.2 v3(133.23,57.52)
  L3 w0.508: v3(79.06,35.75) 79.81,35.75 80.14,36.08 83.31,36.08 83.84,35.56 92.26,35.56 92.45,35.75 93.76,35.75 94.76,34.74 108.25,34.74 108.65,34.34 109.75,34.34 111.32,35.91 111.32,39.43 113.31,41.43 v3(113.31,42.91)
  L4 w0.508: v3(81.2,26.67) 81.2,27.79 80.69,28.3 80.61,28.3 78.62,30.29 78.62,31.16 79.18,31.72 79.18,33.17 79.14,33.21 79.14,35.67 v3(79.06,35.75) ; v3(113.31,42.91) 113.31,48.26 114.63,49.58 114.63,54.16 116.7,56.23 122.87,56.23 124.46,54.64 130.92,54.64 133.23,56.96 v3(133.23,57.52)
  BOTTOM w0.508: 80.45,24.45 80.51,24.39 C2421.2 80.51,23.37 v1(81.26,22.61) 81.29,22.59 81.29,20.53 80.91,20.15 C2414.2 ; 80.45,24.45 80.44,24.44 C2404.2 ; 80.45,24.45 80.69,24.45 81.2,24.96 v3(81.2,26.67) 81.13,26.73 C2427.2
SIO_ATXPG: length 10.9
  TOP w0.102: ECIO1.98 73.6,22.98 73.51,23.07 73.51,23.65 v3(73.99,24.12)
  BOTTOM w0.102: R24054.1 74,16.62 74,19.04 Q2403.3 73.49,20.13 74.35,20.99 v1(74.35,22.53) 74.35,23.77 v3(73.99,24.12)
SIO_AUDIO_MUTE: length 85.8
  L3 w0.127: v3(47.55,29.5) 49.14,31.09 57.99,31.09 60.7,33.79 62.63,33.79 63.13,34.29 v3(78.09,34.29)
  L4 w0.127: v3(38.81,70.82) 38.81,70.81 43.95,65.67 43.95,60.5 44.39,60.06 44.39,50.99 45.3,50.09 45.3,46.91 45.7,46.51 45.7,31.34 v3(47.55,29.5)
  BOTTOM w0.102: R24015.2 78.09,29.85 v3(78.09,34.29) ; R2754.1 v1(37.38,69.09) 37.38,69.84 38.35,70.82 v3(38.81,70.82)
SIO_BOARD_ID1: length 4.4
  TOP w0.102: R24084.2 71.41,21.64 R24065.1 71.86,21.63 72.11,21.89 v1(72.42,21.89) 72.85,21.89 73.36,21.38 ECIO1.102
SIO_BOARD_ID2: length 4.3
  TOP w0.102: ECIO1.103 72.9,20.98 72.48,20.57 v1(72.43,20.57) 71.41,20.57 R24011.1 71.41,20.56 R24013.2
SIO_BOARD_ID3: length 6.2
  TOP w0.102: ECIO1.104 73.18,20.58 72.99,20.39 72.99,18.85 72.59,18.46 v1(72.39,18.46) 71.43,18.46 R24101.2 71.41,17.86 R24055.1
SIO_CE_N: length 14.1
  TOP w0.102: v3(80.66,14.93) 82.59,14.93 83.69,13.83 85.08,13.83 86.4,12.51 ECIO1.27
  BOTTOM w0.102: v3(80.66,14.93) 80.3,14.93 v1(79.89,14.52) 79.45,14.08 R24076.2 78.7,14.21 U2401.1
SIO_CLK_DB: length 7.8
  TOP w0.102: ECIO1.48 91.03,16.98 91.09,16.92 91.55,16.92 v3(91.99,17.36)
  BOTTOM w0.102: v3(91.99,17.36) 91.99,16.68 91.79,16.48 v1(91.33,16.48) 90.82,16.48 90.42,16.88 R24103.1 88.87,16.88 88.28,17.48 RN2404.2
SIO_COPEN#: length 7.7
  TOP w0.102: ECIO1.65 88.4,25.9 88.63,26.14 90.33,26.14 90.52,25.95 v3(90.52,24.13)
  BOTTOM w0.102: R24029.1 90.91,24.51 90.45,24.97 90.31,24.97 v1(90.25,24.9) 90.19,24.85 90.19,24.51 90.52,24.18 v3(90.52,24.13)
SIO_DAT_DB: length 6.5
  TOP w0.102: ECIO1.49 v3(91.28,17.38)
  BOTTOM w0.102: RN2404.1 88.13,18.13 88.81,18.81 R24103.2 91.03,18.81 91.28,18.56 v1(91.28,18.54) v3(91.28,17.38)
SIO_DEBUG_RX: length 3.6
  TOP w0.102: ECIO1.124 v1(72.47,12.58) 71.43,12.58 71.27,12.75 RN2403.2
SIO_DEBUG_TX: length 4.8
  TOP w0.102: RN2403.1 70.62,13.56 70.73,13.67 71.65,13.67 71.84,13.86 v1(72.36,13.86) 72.73,13.86 73.6,12.98 ECIO1.123
SIO_GP17: length 4.9
  TOP w0.102: ECIO1.25 85.6,8.5 85.22,8.12 v3(85.22,8.12) v1(85.23,7.18)
  BOTTOM w0.102: R24039.1 85,8.34 v3(85.22,8.12) 85.22,9 R24019.2
SIO_HOLD#: length 5.2
  BOTTOM w0.102: 71.08,12.22 v1(71.08,12.22) ; 71.08,12.22 70.56,11.7 70.56,11.08 R24109.2 ; 71.08,12.22 71.81,12.94 U2401.7
SIO_K8PWR_EN: length 4
  TOP w0.102: R24075.1 71.72,11.64 72.05,11.31 v1(72.51,11.31) 73.08,11.31 73.19,11.42 73.19,12.03 73.34,12.18 ECIO1.125
SIO_MAIN_VCC3: length 6
  TOP w0.203: ECIO1.89 78.8,27.26
  TOP w0.305: 78.8,27.26 v1(78.8,28.56) 79.05,28.82 R24107.1 79.08,29.75 R24051.1
SIO_PCICLK: length 9.7
  TOP w0.114: R24034.2 97.86,16.01 98.1,15.78 98.1,15.11 97.98,15 96.54,15 96.48,15.05 94.41,15.05 94.18,15.28 v1(93.75,15.28) 92,15.28 91.9,15.38 ECIO1.44
SIO_PSON_N: length 10.6
  TOP w0.102: ECIO1.73 85.2,25.71 85.03,25.87 85.03,26.25 85.59,26.81 86.04,26.81 v3(86.66,27.42)
  BOTTOM w0.102: R24066.1 88.25,25.7 v1(88.62,26.08) 89.88,27.34 Q2404.G 89.48,27.59 88.92,27.03 88.44,27.03 88.25,26.84 87.25,26.84 v3(86.66,27.42)
SIO_PSON_N_1: length 13.7
  TOP w0.102: R24051.2 80.16,30.6 v3(79.89,30.6)
  BOTTOM w0.102: v3(79.89,30.6) v1(79.89,31.57) 79.89,32.12 80.19,32.42 85.14,32.42 86.33,31.24 86.33,30.59 87.42,29.49 Q2404.D
SIO_SCK: length 22.3
  L3 w0.127: v3(70.01,9.61) 70.01,8.42 71.46,6.97 75.7,6.97 76.31,6.36 82.94,6.36 v3(84.36,4.94)
  BOTTOM w0.102: R24102.2 v3(84.36,4.94) ; v3(70.01,9.61) R24006.2 v1(70.95,10.59) 70.95,11.38 71.25,11.67 U2401.6
SIO_SCK_R: length 4.9
  TOP w0.102: v3(84.16,5.89) 83.93,6.13 v1(83.93,6.84) 83.93,7.97 84.4,8.44 ECIO1.22
  BOTTOM w0.102: v3(84.16,5.89) 84.72,6.45 R24102.1
SIO_SI: length 19.7
  TOP w0.102: ECIO1.21 84,8.5 83.33,7.83 v3(83.33,4.74)
  L3 w0.127: v3(83.33,4.74) 82.78,4.74 81.55,5.97 74.2,5.97 v3(73.68,6.5)
  BOTTOM w0.102: v3(73.68,6.5) 72.98,7.2 R24086.2 v1(72.98,8.93) 72.98,9.5 72.58,9.9 U2401.5
SIO_SO: length 14.9
  TOP w0.102: ECIO1.28 86.8,12.77 85.25,14.32 v3(84.26,14.32)
  BOTTOM w0.102: U2401.2 79.51,12.94 80.48,11.98 R24045.2 82.24,11.98 82.57,12.31 82.6,12.31 82.93,12.64 v1(83.32,12.64) 83.65,12.97 83.65,13.71 v3(84.26,14.32)
SIO_VCORE: length 5
  TOP w0.203: 90.98,10.98 ECIO1.33
  TOP w0.305: v3(91.35,10.98) 90.98,10.98
  BOTTOM w0.305: v3(91.35,10.98) 90.96,11.38 v1(90.46,11.38) 90.07,10.99 90.07,10.52 C2401.2 90.95,10.29 C2415.1
SIO_VIN1: length 11.1
  TOP w0.203: v3(76.92,22.24) 76.8,22.37 ECIO1.94
  TOP w0.305: v3(76.92,22.24) 76.92,17.81 77.29,17.44 v3(77.29,17.17)
  BOTTOM w0.305: R24020.2 77.67,16.38 77.29,16.75 v3(77.29,17.17) ; v1(76.97,23.05) 76.92,23.01 v3(76.92,22.24) 76.85,22.16 R24027.1
SIO_VIN2: length 15.5
  TOP w0.203: 76.93,26.15 77.2,25.88 ECIO1.93 77.2,23.14 77.67,22.67 v3(77.67,21.97)
  TOP w0.305: v3(77.67,21.97) 77.67,18 78.08,17.59 v3(78.08,17.1) ; R24096.1 75.09,28.93 v1(75.09,28.2) 75.35,28.2 76.15,27.4 76.15,26.93 76.93,26.15
  BOTTOM w0.305: R24007.1 77.86,17.32 v3(78.08,17.1) ; v3(77.67,21.97) 77.75,21.89 C2407.1
SIO_VIN3: length 14.6
  TOP w0.203: 77.29,26.7 77.6,26.39 ECIO1.92 77.6,23.23 78.47,22.35 v3(78.47,21.99)
  TOP w0.305: v3(78.47,21.99) 78.47,18.23 79.21,17.49 v3(79.21,17.07) ; R24010.1 76.79,27.68 v1(76.79,27.32) 76.79,27.2 77.29,26.7
  BOTTOM w0.305: v3(78.47,21.99) 78.47,21.28 R24073.1 ; C2413.1 78.81,17.47 v3(79.21,17.07)
SIO_VIN4: length 16.4
  TOP w0.203: 77.52,27.18 78,26.71 ECIO1.91 78,23.55
  TOP w0.305: 77.52,27.18 77.52,28.22 v1(77.23,28.51) 78.01,29.3 R24003.1 ; v3(80.13,17.14) 80.13,17.83 79.21,18.74 v3(79.21,22.16) 79.21,22.33 78,23.55
  BOTTOM w0.305: v3(80.13,17.14) 80.15,17.14 79.8,17.49 R24098.1 ; C2411.1 79.21,21.47 v3(79.21,22.16)
SIO_VIN5: length 52.5
  TOP w0.203: 78.62,23.58 78.4,23.8 ECIO1.90 78.4,26.9
  TOP w0.305: 78.4,26.9 78.11,27.19 v3(78.11,27.84) ; 78.62,23.58 79.95,22.25 ; 79.95,22.25 79.97,22.23 79.97,19.05 80.84,18.18 v3(80.84,17.12) ; 79.95,22.25 v3(79.96,22.25) ; v3(77.61,37.94) 78.55,37.94 80.83,35.66 80.83,33.27 81.72,32.39 81.81,32.39 81.85,32.34 R4322.2
  L4 w0.305: v3(78.11,27.84) 76.53,29.42 76.53,31.83 76.18,32.18 76.18,34.96 77.43,36.21 77.43,36.55 77.67,36.79 77.67,37.88 v3(77.61,37.94) 77.61,45.06 76.21,46.46 76.21,51.03 v3(76.43,51.26)
  BOTTOM w0.305: C2414.1 80.54,21.14 79.96,21.72 v3(79.96,22.25) ; R24077.1 v3(80.84,17.12) ; D4302.2 75.4,53.68 75.18,53.46 v1(75.18,53.17) 75.18,52.68 75.5,52.37 C4304.1 76.32,51.37 v3(76.43,51.26)
SIO_VREF: length 14.3
  TOP w0.102: v3(80.62,21.98) 80.62,22.54 79.2,23.97 ECIO1.88 79.2,26.5 v3(79.36,26.67)
  BOTTOM w0.102: C2421.1 79.62,22.91 79.77,22.76 80.1,22.76 80.62,22.24 v3(80.62,21.98) ; R24046.2 77.59,26.45 v1(77.71,26.58) 77.8,26.67 v3(79.36,26.67) 79.36,27.12 78.58,27.9 78.58,28.57 78.82,28.81 R24114.2
SIO_WP#: length 3.3
  BOTTOM w0.102: R24115.2 79.8,12.14 79.65,12.29 v1(79.35,12.29) 78.95,12.29 78.33,11.67 U2401.3
SIO_WRST#: length 8.2
  TOP w0.102: R24104.2 96.27,17.97 v1(95.91,17.61) 95.6,17.61 94.84,16.86 94.42,16.86 94.41,16.85 93.56,16.85 C2422.1 92.71,17.43 91.86,16.58 ECIO1.47
SM_DRAMRST#: length 122.7
  TOP w0.102: DIMM1.108 v3(258.19,48.92) ; DIMM2.108 242.12,48.92 242.3,48.74 242.7,48.74 v3(243.23,49.27)
  L3 w0.127: v3(258.19,48.92) 259.6,47.52 259.6,35.72 260.66,34.66 260.66,33.58 259.67,32.58 259.67,28.97 260.15,28.49 260.15,28.05 258.94,26.83 258.94,26.8 258.88,26.75 258.88,17.86 259.26,17.48 259.26,11.14 258.54,10.42 258.54,8.26 256.2,5.92 256.17,5.92 255.9,5.66 248.93,5.66 248.4,5.14 248.37,5.14 248.33,5.1 246.01,5.1 245.15,4.24 238.72,4.24 238.67,4.29 233.05,4.29 232.24,5.1 232.21,5.1 229.25,8.06 226.87,8.06 226.86,8.06 221.56,8.06 v3(220.73,7.23)
  BOTTOM w0.102: R511.1 214.05,16.53 214.74,15.83 218.59,15.83 v1(220.13,14.29) 221.04,13.38 221.04,7.55 v3(220.73,7.23) ; v3(258.19,48.92) 257.31,48.04 C501.1 256.3,48.04 256.29,48.05 255.26,48.05 254.9,47.69 254.48,47.69 254.22,47.95 252.75,47.95 252.3,48.41 243.32,48.41 C1325.1 243.29,49.21 v3(243.23,49.27)
SM_DRAMRST#_CPU: length 28.2
  TOP w0.102: v3(190.88,29.55) 190.92,29.6 191.94,29.6 CPU1.DK47
  BOTTOM w0.102: v3(190.88,29.55) 191.83,29.55 v1(192.5,30.22) 196.98,30.22 198.78,28.42 198.78,27.21 207.71,18.28 208.1,18.28 209.78,16.59 209.78,16.54 R510.2 209.81,16.54 210.37,16.54 210.38,16.53 R511.2
SM_PGCNTL: length 26.1
  TOP w0.102: v4(188.56,67.64) 188.56,67.53 CPU1.M39
  BOTTOM w0.102: R4022.1 203.54,77.94 203.27,78.22 R4020.1 202.4,77.7 200.33,77.7 199.48,78.55 196.12,78.55 v1(195.64,78.07) 194.49,76.92 190.48,76.92 189.86,76.29 189.86,73.56 190.26,73.16 190.26,68.81 189.58,68.13 189.02,68.13 188.56,67.67 v4(188.56,67.64)
SM_RCOMP_0: length 7.2
  TOP w0.102: CPU1.D47 192.64,71.35 193.03,71.74 193.28,71.74 193.37,71.74 193.55,71.92 193.55,72.2 193.5,72.25 193.5,72.51 193.57,72.57 193.57,72.64 193.93,73.01 193.93,73.62 194.01,73.7
  TOP w0.381: R505.2 195.57,76.15 194.94,75.51 v1(194.76,75.51) 194.76,75.34 194.01,74.58 194.01,73.7
SM_RCOMP_1: length 6.7
  TOP w0.127: 192.19,74.32 192.19,73.7 191.81,73.32 191.81,73.31 191.79,73.3 191.79,73 191.62,72.83 191.62,72.64 191.64,72.48 191.64,72.25 191.53,72.13 191.53,71.76 191.6,71.69 CPU1.E46
  TOP w0.381: 192.19,74.32 192.19,76.27 v1(192.24,76.32) 192.47,76.55 R506.2
SM_RCOMP_2: length 5.9
  TOP w0.102: 193.36,74.24 192.44,73.32 192.44,73.02 192.28,72.85 192.28,72.31 CPU1.C47
  TOP w0.381: 193.36,74.24 193.36,75.38 v1(193.43,75.45) 193.75,75.77 193.98,75.77 194.49,76.28 R507.2
SML1ALERT: length 34.9
  TOP w0.076: CPU1.CL48 192.59,38.65 192.78,38.46 192.92,38.46 193.18,38.4 193.25,38.33 193.52,38.33 193.68,38.49
  TOP w0.102: 193.68,38.49 193.78,38.49 194.43,39.14 196.83,39.14 197.17,39.47 200.98,39.47 206.01,34.44 v1(206.36,34.44) 206.7,34.44 209.77,31.37 209.77,21.71 209.21,21.16 209.21,20.75 v3(208.59,20.12)
  BOTTOM w0.102: v3(208.59,20.12) 209.1,20.63 R1513.1 209.36,19.63 R1505.2
SNDW_RCOMP: length 1.8
  TOP w0.305: v3(187.25,34.52) 187.61,34.88 CPU1.CV38
  BOTTOM w0.381: v3(187.25,34.52) 187.5,34.52 R1903.1
SPEED_100_L1: length 45.8
  BOTTOM w0.381: RJ1.10 72.99,45.19 63.25,45.19 54.31,54.13 54.31,56.34 52.95,57.7 52.95,60.52 v1(53.56,61.14) 55.73,63.31 56.12,63.31 56.57,63.76 v1(56.57,66.79) ED3102.3 58.65,68.88 R3138.1 58.65,71.78 R3152.1
SPEED_1000_L1: length 41.5
  BOTTOM w0.381: RJ1.9 74.62,44.53 62.98,44.53 53.56,53.95 v1(53.56,55.21) 53.56,56.19 52.31,57.44 52.31,62.28 R3151.1 R3139.1 54.46,62.93 ED3101.3
SPI_CLK_ROM: length 3.8
  TOP w0.114: U2501.6 U2504.6 195.31,10.42 v1(194.07,9.91) 193.53,9.69 R1823.1
SPI_CLK_ROM_R: length 42
  TOP w0.114: v3(191.37,7.82) 190.93,8.27 v1(190.93,8.73) 191.88,9.69 R1823.2 ; v3(189.27,33.55) 189.27,33.42 CPU1.DB42
  L4 w0.127: v3(189.27,33.55) 190.02,33.55 190.5,33.07 190.79,33.07 191.19,32.67 191.19,32.64 192.43,31.4 193.6,31.4 196.87,28.14 197.38,28.14 198.94,26.57 198.94,25.59 199.79,24.74 199.79,24.62 200.1,24.31 200.1,23.28 200.1,23.28 200.1,21.17 200.1,21.17 200.1,20.85 200.1,20.85 200.1,20.02 200.53,19.6 200.66,19.6 200.96,19.3 200.96,18.41 197.9,15.35 197.9,14.58 191.56,8.24 191.56,8.01 v3(191.37,7.82)
  BOTTOM w0.114: v3(189.27,33.55) 189.65,33.55 190.13,34.02 R1839.2
SPI_CS_CPU_N0: length 36.5
  TOP w0.114: CPU1.DB43 190.21,32.89 v3(189.97,32.66) ; v3(200.47,19.13) 200.22,19.37 199.61,19.37 199.61,19.37 199.6,19.37 198.39,18.16 R2508.2 198.39,14.53 200.13,12.8 200.13,10.88 203.13,7.88 U2501.1
  L4 w0.127: v3(200.47,19.13) 200.25,19.13 199.72,19.66 199.72,20.7 199.72,23.12 199.72,24.15 199.34,24.53 199.34,24.65 198.49,25.5 198.49,26.49 198.01,26.97 197.32,26.97 194.09,30.21 193.25,30.21 191.22,32.23 190.4,32.23 v3(189.97,32.66)
  BOTTOM w0.114: v3(200.47,19.13) 201.07,19.13 v1(201.38,18.82)
SPI_HOLD_ROM: length 5.6
  TOP w0.114: R1826.1 194.7,6.75 194.8,6.85 194.8,7.88 v1(194.06,8.63) 194.06,8.63 194.58,9.15 U2504.7 U2501.7
SPI_HOLD_ROM_R: length 46.5
  TOP w0.114: v1(192.19,8.63) 193.23,8.63 R1826.2 194.21,7.61 193.66,7.61 193.65,7.6 193.2,7.6 R1531.2 192.17,7.61 R1534.1 191.83,7.6 v3(191.06,6.83) ; CPU1.DD41 188.91,32.23 188.49,32.65 v3(188.49,32.67)
  L4 w0.127: v3(188.49,32.67) 188.49,33.36 189.11,33.99 191.41,33.99 193.61,31.78 193.77,31.78 195.45,30.11 195.95,30.11 199.33,26.73 199.33,25.74 200.39,24.68 200.39,24.56 200.48,24.47 200.48,23.44 200.48,21.01 201.11,20.38 201.11,19.68 201.49,19.31 201.49,18.41 200.13,17.04 200.13,16.94 198.28,15.1 198.28,14.42 191.94,8.08 191.94,7.71 v3(191.06,6.83)
SPI_SI_ROM: length 4.1
  TOP w0.114: U2501.5 U2504.5 194.44,11.69 v1(194.08,11.33) 193.47,10.72 R1825.1
SPI_SI_ROM_R: length 38.9
  TOP w0.114: CPU1.DD43 190.21,32.17 v3(189.79,31.75) ; v3(190.64,7.81) 190.31,8.13 190.31,9.96 v1(191.15,10.8) 191.53,11.17 191.53,11.58 191.72,11.76 R1510.2 192.13,11.76 R1825.2
  L4 w0.127: v3(189.79,31.75) 190.47,31.07 190.47,30.64 190.71,30.4 190.95,30.4 193.8,27.55 194.43,27.55 194.75,27.23 195.56,27.23 198.95,23.84 198.95,22.81 198.95,20.38 198.95,17.74 195.63,14.42 195.63,12.85 190.64,7.86 v3(190.64,7.81)
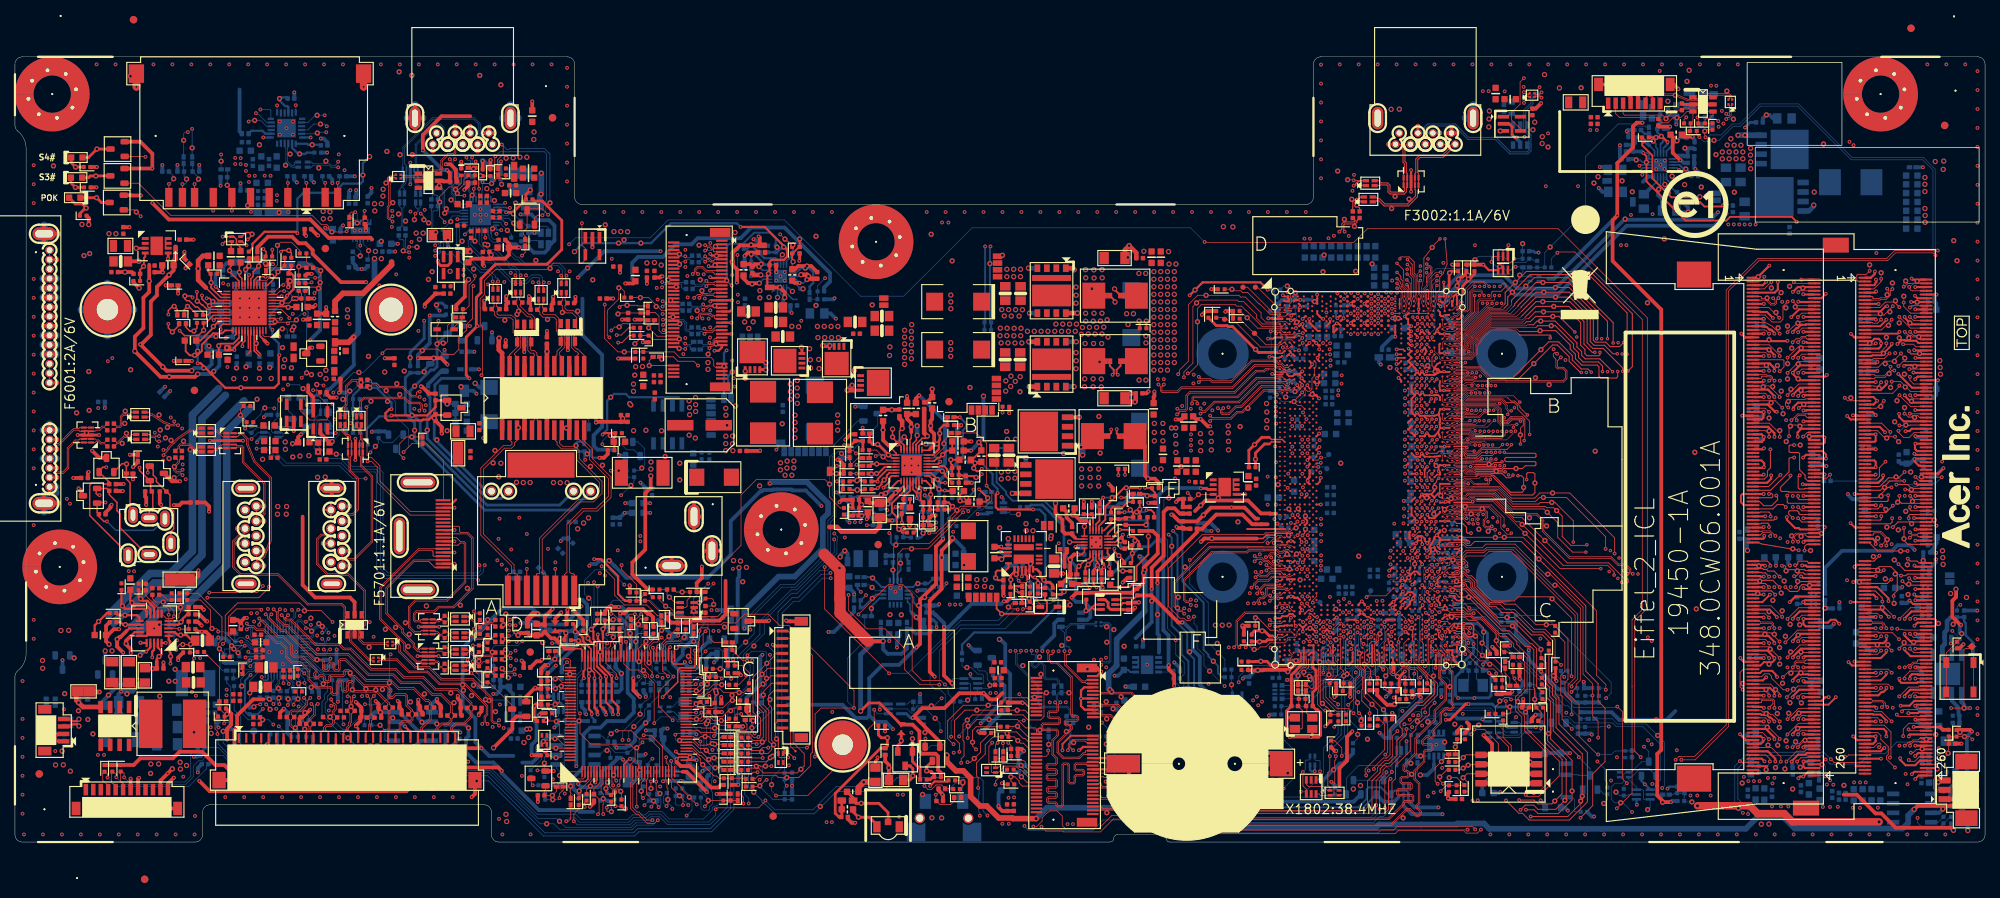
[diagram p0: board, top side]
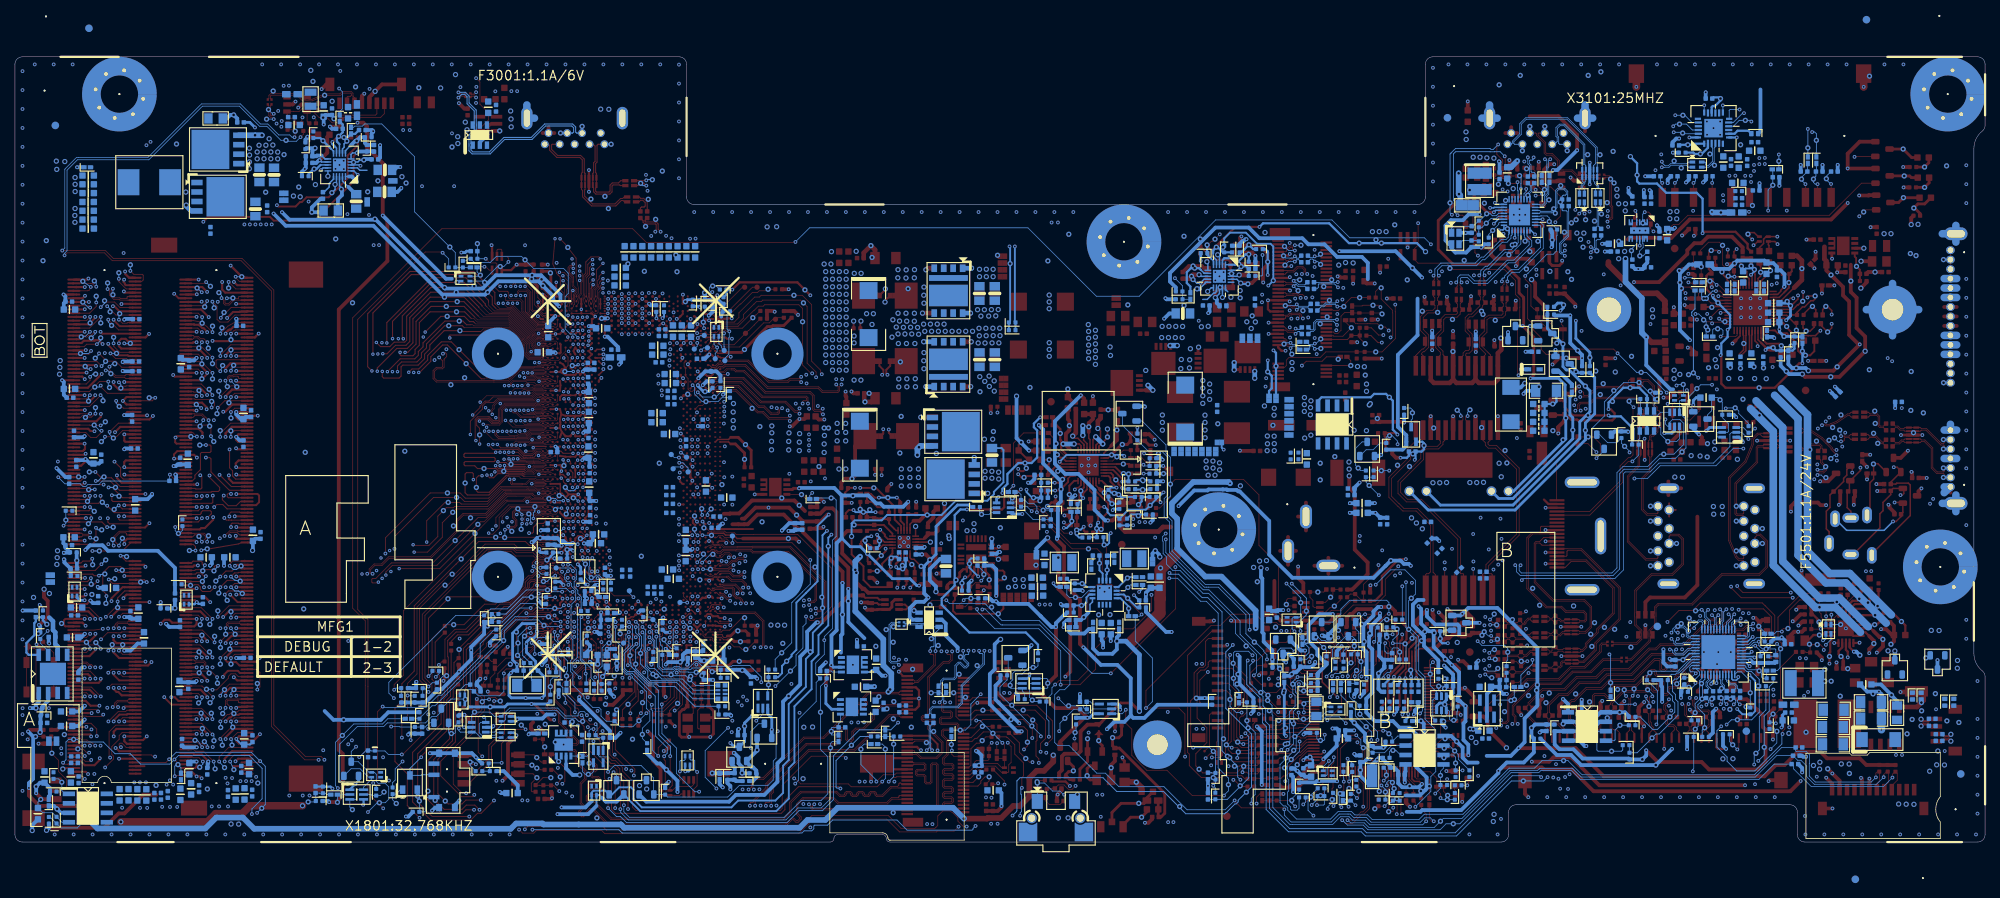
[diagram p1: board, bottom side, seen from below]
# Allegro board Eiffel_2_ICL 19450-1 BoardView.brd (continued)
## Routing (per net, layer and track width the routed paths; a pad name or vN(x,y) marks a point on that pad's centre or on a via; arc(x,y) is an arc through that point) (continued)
SPI_SO_ROM: length 9.6
  TOP w0.114: R1827.1 199.42,14.03 200.5,12.95 200.5,11.19 202.53,9.15 U2501.2
SPI_SO_ROM_R: length 25.3
  TOP w0.114: CPU1.DF43 190.68,30.82 v3(190.89,30.82) ; R1827.2 200.33,17.2 200.44,17.32 200.44,18.04 200.3,18.18 199.87,18.18 199.79,18.26 v3(199.79,18.91)
  L4 w0.127: v3(190.89,30.82) 190.89,31.1 191.01,31.23 191.71,31.23 192.41,30.52 192.41,30.25 192.03,29.86 192.03,29.68 192.26,29.44 192.44,29.44 192.78,29.79 192.96,29.79 193.14,29.61 193.14,29.43 192.8,29.08 192.8,28.9 192.98,28.72 193.16,28.72 193.5,29.07 193.68,29.07 193.86,28.89 193.86,28.71 193.52,28.36 193.52,28.18 193.93,27.78 194.52,27.78 194.69,27.61 195.72,27.61 199.33,24 199.33,22.97 199.34,22.97 199.34,21.49 199.33,21.49 199.33,20.54 199.34,20.54 199.34,19.5 199.79,19.05 v3(199.79,18.91)
  BOTTOM w0.114: v3(199.79,18.91) v1(198.96,18.91)
SPI_WP_R_N: length 4.1
  TOP w0.114: v3(80.88,7.59) 81.05,7.76 81.05,8.35 81.2,8.5 ECIO1.14
  BOTTOM w0.114: v3(80.88,7.59) 80.36,7.06 v1(80.36,6.71) R24028.1
SPI_WP_ROM: length 3.9
  TOP w0.114: U2501.3 v3(202.23,10.42)
  BOTTOM w0.114: R1824.1 202.26,9.54 203.01,10.29 v1(203.01,10.73) 202.54,10.73 v3(202.23,10.42)
SPI_WP_ROM_R: length 32.5
  TOP w0.114: CPU1.DF42 189.91,30.94 v3(189.91,30.88) ; v3(198.78,10.62) 198.78,13.22 196.9,15.11 v3(195.57,15.11)
  L4 w0.127: v3(195.57,15.11) 195.57,16.27 198.01,18.71 198.01,23.22 196.11,25.12 195.72,25.12 194.3,26.54 194.3,26.95 193.93,27.32 193.71,27.32 190.85,30.17 190.62,30.17 v3(189.91,30.88)
  BOTTOM w0.114: v3(195.57,15.11) v1(196.15,15.68) ; R1824.2 201.37,9.51 R1506.2 200.37,9.92 200.52,10.07 R1514.1 200.44,10.62 v3(198.78,10.62)
SRTC_RST#: length 20.8
  TOP w0.102: CPU1.DK46 191.51,29.28 191.14,28.91 190.88,28.91 190.88,28.92 v3(190.87,28.92)
  BOTTOM w0.102: v3(190.87,28.92) 192.98,28.92 v1(193.1,29.05) 193.85,29.79 196.91,29.79 198.43,28.28 198.43,27.06 202.99,22.49 C1820.1 203.64,21.11 204.37,20.39 RN1804.4
SSD1_CLK_CPU_CON_N: length 4.9
  TOP w0.102: NGFFM1.53 94.06,67.65 93.91,67.5 93.78,67.5 93.56,67.28 93.56,66.85 93.4,66.7 93.17,66.7 93.07,66.8 v3(93.07,66.95)
  BOTTOM w0.102: v1(93.94,66.79) 93.78,66.95 v3(93.07,66.95) 92.82,66.71 92.21,66.71 R6314.1
SSD1_CLK_CPU_CON_P: length 4.8
  TOP w0.102: NGFFM1.55 94.12,67.15 93.98,67.3 93.86,67.3 93.76,67.2 93.76,66.77 93.49,66.49 93.32,66.49 v3(93.07,66.24)
  BOTTOM w0.102: v1(92.89,65.42) 93.07,65.6 v3(93.07,66.24) 92.8,66.5 92.3,66.5 R6313.1
SSD1_CLK_CPU_N: length 123.1
  TOP w0.076: v3(168.34,38.17) 168.15,38.36 168.15,38.47 168.3,38.62 168.84,38.62 169.32,38.15 169.32,38.15 169.35,38.11 169.89,38.11 CPU1.CL2
  L4 w0.114: v3(168.34,38.17) 168.34,39 166.85,40.48 159.85,40.48 157.89,38.52 157,38.52 153.94,35.47 153.94,34.32 152.48,32.86 150.32,32.86 148.85,31.38 145.17,31.38 144.91,31.11 135.79,31.11 135.34,30.66 122.83,30.66 121.89,29.72 114.3,29.72 113.76,29.17 110.01,29.17 108.96,30.22 106.65,30.22 102.45,34.42 99.68,34.42 98.77,35.32 95.65,35.32 94.15,36.82 93.26,36.82 92.27,37.81 92.27,39.71 89.76,42.21 89.76,58.83 88.73,59.87 88.73,63.5 90.53,65.3 90.53,66.1 89.82,66.81 v3(89.82,66.84)
  BOTTOM w0.102: R6314.2 90.6,66.74 89.92,66.74 v3(89.82,66.84) 89.65,66.84 v1(89.02,67.47)
SSD1_CLK_CPU_P: length 122.7
  TOP w0.076: v3(167.63,38.2) 167.83,38.2 167.97,38.34 167.97,38.54 168.23,38.8 168.92,38.8 169.16,38.55 169.33,38.55 CPU1.CL1
  L4 w0.114: v3(89.82,66.13) 90.17,66.13 90.3,66 90.3,65.4 88.5,63.6 88.5,59.77 89.53,58.74 89.53,42.11 92.04,39.61 92.04,37.71 93.16,36.59 94.06,36.59 95.55,35.09 98.67,35.09 99.58,34.19 102.36,34.19 106.55,29.99 108.87,29.99 109.92,28.95 113.85,28.95 114.4,29.49 121.99,29.49 122.92,30.43 135.43,30.43 135.88,30.88 145,30.88 145.27,31.15 148.94,31.15 150.42,32.63 152.58,32.63 154.17,34.22 154.17,35.37 157.09,38.3 157.99,38.3 159.94,40.25 166.76,40.25 168.11,38.9 168.11,38.74 168.04,38.66 167.76,38.66 167.63,38.53 v3(167.63,38.2)
  BOTTOM w0.102: R6313.2 90.6,66.04 90.5,66.14 90.5,66.43 90.4,66.53 90.16,66.53 89.82,66.2 v3(89.82,66.13) 89.76,66.19 v1(89.01,66.19)
SSD1_CLKREQ_CPU_N: length 165.4
  TOP w0.102: R1813.2 188.21,21.6 187.92,21.89 187.92,22.23 187.97,22.27 187.97,22.85 187.66,23.16 187.13,23.16 187.13,23.16 186.96,23.16 186.57,23.56 185.78,23.56 185.49,23.85 185.49,26.53 185.41,26.61 v3(185.41,26.82) 185.41,27.43 CPU1.DN34 ; R6302.1 84.33,69.51 84.08,69.51 84.08,69.5 82.8,69.5 82.79,69.51 82.42,69.51 82.41,69.5 81.4,69.5 v1(80.97,69.07) 80.39,69.07 v3(79.91,68.59)
  L3 w0.127: v3(185.41,26.82) 184.17,26.82 183.49,26.14 179.97,26.14 179.24,25.41 177.78,25.41 177.24,24.87 176.06,24.87 176.04,24.89 166.92,24.89 166.86,24.84 161.55,24.84 158.18,21.47 155.19,21.47 153.94,20.23 142.49,20.23 142,19.74 136.58,19.74 135,21.32 126.52,21.32 126.22,21.61 122.87,21.61 122.87,21.61 122.54,21.95 118.3,21.95 117.83,21.47 116.72,21.47 116.15,22.04 107.52,22.04 v3(105.67,23.89)
  L4 w0.127: v3(105.67,23.89) 105.67,23.98 105.19,24.47 101.1,24.47 100.63,24.93 100.63,25.35 100.41,25.58 99.98,25.58 98.64,26.92 91.34,26.92 89.37,28.89 87.05,28.89 83.97,31.97 81.69,31.97 80.09,33.56 80.09,36.06 79.72,36.43 79.72,37.1 79.2,37.62 79.2,47.59 78.62,48.17 78.62,50.6 79.62,51.59 79.62,66.97 80.13,67.48 80.13,68.38 v3(79.91,68.59)
SSD1_PCIE_RX_N0: length 124.1
  TOP w0.102: v3(92.13,70.21) 92.06,70.21 91.82,70.45 91.82,70.62 91.93,70.72 92.89,70.72 92.93,70.68 93.15,70.68 93.39,70.45 93.71,70.45 93.77,70.39 93.77,70.23 93.86,70.15 NGFFM1.43 ; CPU1.CA6 171.9,43.72 v3(171.9,43.86)
  L4 w0.114: v3(92.13,70.21) 92.01,70.1 92.01,69.94 92.23,69.72 94.15,69.72 94.44,69.44 94.44,65.19 94.68,64.95 94.68,51.61 97.86,48.44 97.86,40.01 100.73,37.13 103.51,37.13 107.74,32.9 110.07,32.9 110.46,32.51 120.82,32.51 122.5,34.2 128.1,34.2 128.58,33.71 130.16,33.71 133.43,36.98 140.59,36.98 141.44,36.13 142.31,36.13 143.61,34.84 147.39,34.84 148.11,35.55 150.19,35.55 158.59,43.95 163.33,43.95 164.21,44.83 171.2,44.83 171.55,44.48 171.55,44.1 171.79,43.86 v3(171.9,43.86)
  BOTTOM w0.102: v3(171.9,43.86) 171.98,43.94 v1(171.98,44.7)
SSD1_PCIE_RX_N1: length 128.4
  TOP w0.102: NGFFM1.29 93.75,73.65 93.61,73.5 92.79,73.5 92.73,73.57 92.02,73.57 91.89,73.43 91.47,73.43 v3(91.01,72.97) ; CPU1.CC5 171.53,42.65 v3(171.85,42.98)
  L4 w0.114: v3(91.01,72.97) 91.01,71.79 89.96,70.74 89.96,69.99 91.68,68.27 91.68,67.48 92.32,66.84 92.32,66.7 92.35,66.68 92.35,65.94 93.79,64.5 93.79,51.25 96.94,48.1 96.94,39.68 100.37,36.26 103.15,36.26 107.39,32.01 109.72,32.01 110.1,31.64 121.18,31.64 122.83,33.28 127.78,33.28 128.22,32.84 130.52,32.84 133.78,36.09 137.47,36.09 138.52,35.04 141.13,35.04 142.77,33.41 148.07,33.41 149.33,34.68 150.56,34.68 158.95,43.07 164.14,43.07 164.95,43.88 170.25,43.88 170.92,43.21 171.62,43.21 v3(171.85,42.98)
  BOTTOM w0.102: v3(171.85,42.98) 171.68,42.8 v1(171.68,42.13)
SSD1_PCIE_RX_N2: length 133.8
  TOP w0.102: NGFFM1.17 92.72,76.65 92.18,77.19 91.41,77.19 91.04,76.82 91.04,76.38 v3(90.83,76.17) ; CPU1.CE6 172.18,41.45 v3(171.87,41.14)
  L4 w0.114: v3(171.87,41.14) 172.22,41.49 172.22,41.68 172.05,41.85 168.77,41.85 168.19,42.42 159.22,42.42 150.83,34.03 149.66,34.03 148.39,32.76 142.5,32.76 140.87,34.4 138.18,34.4 138.01,34.23 133.98,34.23 133.62,33.87 132.47,33.87 130.7,32.1 128,32.1 127.52,32.58 123.14,32.58 121.54,30.98 109.82,30.98 109.44,31.37 107.12,31.37 102.89,35.6 100.11,35.6 96.26,39.45 96.26,47.65 93.09,50.83 93.09,62.05 92.08,63.05 92.08,64.04 91.69,64.43 91.69,66.35 91.67,66.37 91.67,66.57 91.03,67.21 91.03,68 89.28,69.75 89.28,73.79 90.83,75.34 v3(90.83,76.17)
  BOTTOM w0.102: v1(170.66,41.13) 170.66,41.14 v3(171.87,41.14)
SSD1_PCIE_RX_N3: length 139.1
  TOP w0.102: NGFFM1.5 93.43,79.65 93.15,79.93 92.59,79.93 v3(92.49,80.03) ; v3(173.05,40.24) CPU1.CG7
  L4 w0.114: v3(173.05,40.24) 172.54,39.72 169.74,39.72 168.48,40.98 158.7,40.98 151.08,33.36 149.91,33.36 148.42,31.87 144.97,31.87 144.72,31.62 135.44,31.62 135.13,31.94 134.06,31.94 133.28,31.15 122.62,31.15 121.81,30.33 113.96,30.33 113.32,29.69 110.2,29.69 109.17,30.72 106.85,30.72 102.62,34.95 99.84,34.95 98.95,35.84 95.83,35.84 94.99,36.68 94.99,47.19 91.82,50.35 91.82,61.41 90.69,62.54 90.69,64.71 90.66,64.74 91.02,65.1 91.02,66.3 90.38,66.94 90.38,67.73 88.62,69.5 88.62,75.54 89.7,76.62 90.14,76.62 90.97,77.44 90.97,79.53 91.47,80.03 v3(92.49,80.03)
  BOTTOM w0.102: v3(92.49,80.03) v1(91.68,80.03)
SSD1_PCIE_RX_P0: length 124.3
  TOP w0.102: v3(171.19,43.85) 171.53,43.51 CPU1.CA5 ; v3(91.41,70.21) 91.62,70.42 91.62,70.7 91.84,70.93 92.98,70.93 93.02,70.89 93.24,70.89 93.47,70.65 NGFFM1.41
  L4 w0.114: v3(171.19,43.85) 171.33,43.98 171.33,44.38 171.1,44.6 164.31,44.6 163.42,43.72 158.68,43.72 150.29,35.32 148.2,35.32 147.49,34.61 143.51,34.61 142.22,35.91 141.34,35.91 140.49,36.75 133.52,36.75 130.25,33.48 128.49,33.48 128,33.97 122.6,33.97 120.91,32.29 110.36,32.29 109.98,32.67 107.65,32.67 103.42,36.9 100.64,36.9 97.63,39.91 97.63,48.34 94.45,51.52 94.45,64.85 94.21,65.1 94.21,69.34 94.06,69.5 92.13,69.5 v3(91.41,70.21)
  BOTTOM w0.102: v1(170.71,44.66) 171.19,44.18 v3(171.19,43.85)
SSD1_PCIE_RX_P1: length 128.4
  TOP w0.102: v3(172.6,42.98) 172.6,42.95 CPU1.CC6 ; v3(91.72,72.97) 92.11,73.36 92.64,73.36 92.71,73.3 93.61,73.3 93.75,73.15 NGFFM1.31
  L4 w0.114: v3(172.6,42.98) 172.14,43.44 171.02,43.44 170.35,44.11 164.85,44.11 164.04,43.3 158.86,43.3 150.46,34.9 149.24,34.9 147.97,33.64 142.86,33.64 141.23,35.27 138.61,35.27 137.56,36.32 133.69,36.32 130.43,33.06 128.31,33.06 127.87,33.51 122.73,33.51 121.09,31.87 110.19,31.87 109.81,32.24 107.48,32.24 103.24,36.48 100.46,36.48 97.17,39.78 97.17,48.19 94.02,51.34 94.02,64.59 92.57,66.04 92.57,66.77 92.55,66.8 92.55,66.94 91.91,67.57 91.91,68.36 90.19,70.08 90.19,70.65 91.24,71.69 91.24,72.45 91.34,72.55 91.54,72.55 91.72,72.74 v3(91.72,72.97)
  BOTTOM w0.102: v1(172.93,43.72) 172.93,43.3 v3(172.6,42.98)
SSD1_PCIE_RX_P2: length 133.7
  TOP w0.102: v3(91.54,76.17) 91.24,76.47 91.24,76.73 91.5,76.99 92.09,76.99 92.63,76.45 93.51,76.45 93.8,76.15 94.44,76.15 NGFFM1.19 ; CPU1.CE7 172.83,41.42 v3(172.53,41.12)
  L4 w0.114: v3(172.53,41.12) 172.45,41.2 172.45,41.77 172.15,42.08 168.86,42.08 168.29,42.65 159.13,42.65 150.73,34.26 149.56,34.26 148.3,32.99 142.59,32.99 140.96,34.62 138.08,34.62 137.92,34.46 133.89,34.46 133.53,34.09 132.37,34.09 130.61,32.33 128.1,32.33 127.62,32.81 123.04,32.81 121.44,31.21 109.92,31.21 109.53,31.59 107.22,31.59 102.98,35.83 100.2,35.83 96.49,39.54 96.49,47.75 93.32,50.93 93.32,62.14 92.31,63.15 92.31,64.13 91.92,64.53 91.92,66.45 91.9,66.46 91.9,66.67 91.26,67.31 91.26,68.1 89.51,69.84 89.51,73.7 91.06,75.25 91.06,75.67 91.17,75.79 91.37,75.79 91.54,75.96 v3(91.54,76.17)
  BOTTOM w0.102: v1(172.93,41.96) 172.92,41.96 172.92,41.51 v3(172.53,41.12)
SSD1_PCIE_RX_P3: length 139.8
  TOP w0.102: v3(92.49,79.32) 92.66,79.32 92.78,79.44 92.78,79.68 92.83,79.73 93.07,79.73 93.35,79.45 93.54,79.45 93.63,79.36 93.63,79.22 93.7,79.15 NGFFM1.7 ; CPU1.CG6 v3(172.42,40.24)
  L4 w0.114: v3(92.49,79.32) 92.49,79.17 92.29,78.97 91.96,78.97 91.88,79.05 91.88,79.69 91.76,79.81 91.57,79.81 91.2,79.44 91.2,77.35 90.24,76.39 89.8,76.39 88.85,75.44 88.85,69.59 90.61,67.83 90.61,67.04 91.25,66.4 91.25,65 90.92,64.67 90.92,62.64 92.05,61.5 92.05,50.45 95.22,47.28 95.22,36.78 95.92,36.07 99.05,36.07 99.93,35.18 102.71,35.18 106.95,30.95 109.26,30.95 110.29,29.92 113.22,29.92 113.86,30.56 121.71,30.56 122.53,31.38 133.18,31.38 133.96,32.16 135.22,32.16 135.54,31.85 144.62,31.85 144.87,32.1 148.33,32.1 149.82,33.59 150.98,33.59 158.6,41.21 168.57,41.21 169.83,39.95 172.13,39.95 v3(172.42,40.24)
  BOTTOM w0.102: v1(93.88,79.88) 93.88,79.88 93.88,79.86 93.35,79.32 92.98,79.32 92.98,79.32 v3(92.49,79.32)
SSD1_PCIE_TX_CON_N0: length 3.7
  TOP w0.102: v3(92.39,68.86) 92.68,68.56 93.36,68.56 93.94,69.15 NGFFM1.47
  BOTTOM w0.102: C6307.1 91.81,68.76 92.3,68.76 v3(92.39,68.86)
SSD1_PCIE_TX_CON_N1: length 6.5
  TOP w0.102: v3(92.23,72.09) 92.52,71.81 92.74,71.81 92.94,72 93.65,72 93.8,72.15 NGFFM1.35
  BOTTOM w0.102: v1(93.77,71.93) 92.39,71.93 v3(92.23,72.09) 91.98,71.85 90.7,71.85 90.38,72.17 C6309.1
SSD1_PCIE_TX_CON_N2: length 5.3
  TOP w0.102: v3(92.65,75.26) 92.91,75 93.65,75 93.8,75.15 NGFFM1.23
  BOTTOM w0.102: v1(91.84,75.39) 92.52,75.39 v3(92.65,75.26) 92.39,74.99 92.24,74.99 91.98,74.73 91.16,74.73 C6311.1
SSD1_PCIE_TX_CON_N3: length 5.4
  TOP w0.102: v3(92.49,78.55) 92.75,78.3 93.05,78.3 93.35,78 93.65,78 93.8,78.15 NGFFM1.11
  BOTTOM w0.102: v1(94.01,78.61) 93.71,78.31 92.9,78.31 92.9,78.32 92.73,78.32 v3(92.49,78.55) 92.24,78.3 91.97,78.3 C6332.1
SSD1_PCIE_TX_CON_P0: length 3.7
  TOP w0.102: NGFFM1.49 93.73,68.65 93.44,68.36 92.61,68.36 v3(92.4,68.14)
  BOTTOM w0.102: v3(92.4,68.14) 92.06,68.48 91.92,68.48 C6306.1
SSD1_PCIE_TX_CON_P1: length 5.2
  TOP w0.102: v3(92.23,71.38) 92.45,71.6 92.83,71.6 93.02,71.8 93.65,71.8 93.8,71.65 NGFFM1.37
  BOTTOM w0.102: C6308.1 90.73,71.64 91.41,71.64 ; 91.41,71.64 v1(91.41,71.27) ; 91.41,71.64 91.97,71.64 v3(92.23,71.38)
SSD1_PCIE_TX_CON_P2: length 5.3
  TOP w0.102: v3(92.65,74.54) 92.91,74.8 93.65,74.8 93.8,74.65 NGFFM1.25
  BOTTOM w0.102: C6310.1 91.16,74.52 92.06,74.52 92.32,74.78 92.41,74.78 v3(92.65,74.54) v1(92.06,73.95)
SSD1_PCIE_TX_CON_P3: length 5.1
  TOP w0.102: v3(92.49,77.84) 92.75,78.09 92.97,78.09 93.26,77.8 93.65,77.8 93.8,77.65 NGFFM1.13
  BOTTOM w0.102: C6331.1 91.97,78.09 92.24,78.09 v3(92.49,77.84) 93.33,77.84 v1(93.81,77.36)
SSD1_PCIE_TX_N0: length 130
  TOP w0.076: 168.08,37.38 168.09,37.36 168.11,37.36 168.44,37.03 CPU1.CP1
  TOP w0.102: v3(166.12,37.65) 166.39,37.91 167.06,37.91 167.38,37.59 167.86,37.59 168.08,37.38
  L4 w0.114: v3(166.12,37.65) 165.9,37.65 165.72,37.83 165.72,37.99 165.6,38.11 164.74,38.11 163.32,39.52 160.25,39.52 156.31,35.58 156.31,35.25 151.48,30.43 145.95,30.43 145.56,30.03 142.38,30.03 142.05,29.71 123.4,29.71 122.46,28.77 116.12,28.77 115.05,27.69 110.15,27.69 108.57,29.27 106.25,29.27 102.19,33.33 99.41,33.33 98.37,34.37 95.25,34.37 94.43,35.19 92.48,35.19 91.27,36.4 91.27,39.35 88.79,41.83 88.79,58.16 87.77,59.19 87.77,65.4 86.06,67.11 86.06,69.5 86.36,69.81 86.59,69.81 v3(86.84,70.06)
  BOTTOM w0.102: C6307.2 90.34,68.69 90.09,68.69 89.99,68.79 89.99,69.66 89.59,70.06 88.17,70.06 ; 88.17,70.06 v3(86.84,70.06) ; 88.17,70.06 v1(88.17,70.42)
SSD1_PCIE_TX_N1: length 132.9
  TOP w0.102: CPU1.CR3 168.38,36.47 168.16,36.68 167.95,36.68 167.71,36.44 v3(167.71,36.44)
  L4 w0.114: v3(86.8,72.53) 86.49,72.23 85.87,72.23 85.4,71.75 85.4,66.85 87.13,65.13 87.13,58.48 88.05,57.55 88.05,41.66 90.59,39.12 90.59,35.78 92.64,33.72 98.11,33.72 99.14,32.68 101.92,32.68 106,28.61 107.59,28.61 109.16,27.04 115.32,27.04 116.39,28.12 124.83,28.12 125.76,29.06 142.55,29.06 142.87,29.38 146.22,29.38 146.62,29.78 151.75,29.78 157.01,35.03 157.01,35.21 160.63,38.84 163.05,38.84 165.19,36.71 167.43,36.71 167.71,36.43 167.71,36.44 v3(167.71,36.44)
  BOTTOM w0.102: 87.86,72.29 87.04,72.29 v3(86.8,72.53) ; 87.86,72.29 v1(87.86,72.65) ; 87.86,72.29 88.39,72.29 88.69,71.98 89.29,71.98 C6309.2
SSD1_PCIE_TX_N2: length 138.5
  TOP w0.102: CPU1.CT2 169.98,35.9 169.63,36.25 168.17,36.25 167.68,35.76 166.93,35.76 166.74,35.95 166.53,35.95 v3(166.25,36.22)
  L4 w0.114: v3(166.25,36.22) 166.01,35.98 165.1,35.98 162.77,38.31 160.88,38.31 151.93,29.36 146.89,29.36 146.49,28.96 143.04,28.96 142.72,28.64 126.01,28.64 125.07,27.7 118.79,27.7 117.41,26.32 109.29,26.32 107.42,28.19 105.82,28.19 101.75,32.26 98.97,32.26 97.94,33.3 92.47,33.3 90.15,35.62 90.15,38.48 87.63,40.99 87.63,57.17 86.71,58.09 86.71,64.95 84.98,66.68 84.98,72.38 85.89,73.29 87.63,73.29 87.88,73.54 87.88,74.35 87.37,74.86 86.97,74.86 v3(86.74,75.1)
  BOTTOM w0.102: v1(87.56,75.4) 87.56,75.05 ; 87.56,75.05 86.79,75.05 v3(86.74,75.1) ; 87.56,75.05 89.9,75.05 C6311.2
SSD1_PCIE_TX_N3: length 144.7
  TOP w0.076: CPU1.CT3 170.27,35.64 170.25,35.63 170.05,35.63 169.97,35.66 169.68,35.66 169.62,35.64 169.6,35.63 168.65,35.63 168.64,35.65 168.62,35.65
  TOP w0.102: v3(165.71,34.12) 165.98,34.39 165.98,34.62 166.54,35.18 167.92,35.18 168.39,35.65 168.62,35.65
  L4 w0.114: v3(89.83,78.55) 89.53,78.25 88.45,78.25 86.81,76.62 86.43,76.62 85.23,75.42 85.23,73.89 83.77,72.43 83.77,69.27 83.41,68.91 83.41,66.3 85.83,63.87 85.83,54.49 86.5,53.82 86.5,38.91 85.83,38.24 85.83,36.42 86.58,35.68 88.85,35.68 92.12,32.4 97.59,32.4 98.61,31.39 101.08,31.39 102.57,29.89 102.57,29.28 104.57,27.28 106.74,27.28 108.63,25.39 119.31,25.39 120.74,26.82 125.44,26.82 126.37,27.76 143.08,27.76 143.41,28.09 146.85,28.09 147.25,28.48 152.29,28.48 156.78,32.97 157.77,32.97 157.87,32.87 163.41,32.87 165.17,34.63 165.9,34.63 165.99,34.53 165.99,34.41 v3(165.71,34.12)
  BOTTOM w0.102: v1(89.05,78.84) 89.34,78.55 v3(89.83,78.55) 89.99,78.38 90.49,78.38 C6332.2
SSD1_PCIE_TX_P0: length 130
  TOP w0.076: CPU1.CP2 169.99,37.03 169.72,37.3 169.29,37.3 169.2,37.21 168.51,37.21 168.23,37.49 168.23,37.51 168.22,37.52
  TOP w0.102: 168.22,37.52 167.95,37.79 167.46,37.79 167.14,38.11 166.37,38.11 v3(166.12,38.36)
  L4 w0.114: v3(166.12,38.36) 165.72,38.36 165.7,38.33 164.83,38.33 163.41,39.75 160.15,39.75 156.08,35.68 156.08,35.34 151.39,30.65 145.85,30.65 145.46,30.26 142.29,30.26 141.96,29.93 123.3,29.93 122.37,28.99 116.03,28.99 114.95,27.92 110.24,27.92 108.67,29.5 106.35,29.5 102.29,33.56 99.51,33.56 98.47,34.6 95.35,34.6 94.53,35.42 92.58,35.42 91.5,36.49 91.5,39.45 89.02,41.93 89.02,58.26 88,59.28 88,65.49 86.29,67.2 86.29,69.41 86.46,69.58 86.61,69.58 v3(86.84,69.35)
  BOTTOM w0.102: C6306.2 90.66,68.13 90.31,68.48 90,68.48 89.78,68.7 89.78,69.58 89.5,69.86 89.1,69.86 ; 89.1,69.86 87.35,69.86 v3(86.84,69.35) ; 89.1,69.86 v1(89.1,69.5)
SSD1_PCIE_TX_P1: length 133.5
  TOP w0.102: CPU1.CR4 170.94,36.47 170.63,36.77 170.33,36.77 170.31,36.75 170.13,36.75 170.05,36.67 168.47,36.67 168.25,36.89 167.96,36.89 167.71,37.15 167.71,37.15 v3(167.7,37.15)
  L4 w0.114: v3(167.7,37.15) 167.71,37.15 167.71,37.15 167.49,36.93 165.28,36.93 163.15,39.07 160.54,39.07 156.78,35.31 156.78,35.13 151.66,30.01 146.52,30.01 146.12,29.61 142.77,29.61 142.45,29.29 125.67,29.29 124.73,28.35 116.3,28.35 115.22,27.27 109.25,27.27 107.69,28.84 106.09,28.84 102.02,32.91 99.24,32.91 98.2,33.95 92.74,33.95 90.82,35.87 90.82,39.22 88.28,41.75 88.28,57.65 87.35,58.57 87.35,65.22 85.63,66.95 85.63,71.66 85.97,72 86.62,72 v3(86.8,71.82)
  BOTTOM w0.102: C6308.2 88.98,71.78 88.61,71.78 88.3,72.09 87.06,72.09 v3(86.8,71.82) 85.93,71.82 v1(85.93,71.81)
SSD1_PCIE_TX_P2: length 138.5
  TOP w0.102: v3(166.25,35.51) 166.48,35.74 166.66,35.74 166.84,35.56 167.77,35.56 168.26,36.05 169.36,36.05 CPU1.CT1
  L4 w0.114: v3(86.71,74.39) 86.96,74.63 87.27,74.63 87.65,74.26 87.65,73.63 87.53,73.52 85.79,73.52 84.75,72.48 84.75,66.58 86.48,64.86 86.48,58 87.4,57.07 87.4,40.9 89.92,38.38 89.92,35.53 92.38,33.07 97.85,33.07 98.88,32.04 101.66,32.04 105.73,27.96 107.32,27.96 109.2,26.09 117.51,26.09 118.89,27.47 125.17,27.47 126.11,28.41 142.81,28.41 143.14,28.73 146.59,28.73 146.98,29.13 152.02,29.13 160.97,38.08 162.68,38.08 165.01,35.75 166.01,35.75 v3(166.25,35.51)
  BOTTOM w0.102: v3(86.71,74.39) 87.17,74.84 88.62,74.84 ; C6310.2 89.54,74.18 89.35,74.37 89.35,74.77 89.28,74.84 88.62,74.84 ; 88.62,74.84 v1(88.62,74.49)
SSD1_PCIE_TX_P3: length 144.8
  TOP w0.076: 168.62,35.44 168.64,35.44 168.65,35.46 169.63,35.46 169.68,35.47 169.74,35.5 169.94,35.5 170.02,35.47 170.29,35.47 170.46,35.54 170.91,35.61 171.13,35.73 CPU1.CT5
  TOP w0.102: 168.62,35.44 168.47,35.44 168.01,34.98 166.62,34.98 166.18,34.53 166.18,34.36 v3(166.42,34.12)
  L4 w0.114: v3(89.83,77.84) 89.64,78.03 88.55,78.03 86.91,76.39 86.52,76.39 85.46,75.33 85.46,73.79 84,72.33 84,69.17 83.64,68.81 83.64,66.39 86.06,63.97 86.06,54.59 86.73,53.92 86.73,38.81 86.06,38.14 86.06,36.52 86.67,35.9 88.95,35.9 92.22,32.63 97.69,32.63 98.7,31.62 101.18,31.62 102.8,29.99 102.8,29.37 104.67,27.51 106.83,27.51 108.72,25.62 119.21,25.62 120.64,27.05 125.34,27.05 126.28,27.99 142.99,27.99 143.31,28.31 146.76,28.31 147.16,28.71 152.19,28.71 156.68,33.2 157.86,33.2 157.96,33.1 163.32,33.1 165.07,34.85 165.99,34.85 166.22,34.63 166.22,34.32 v3(166.42,34.12)
  BOTTOM w0.102: v1(89.05,77.46) 89.42,77.84 v3(89.83,77.84) 89.83,77.9 90.11,78.18 90.38,78.18 90.74,77.82 C6331.2
SSD_CLKREQ#: length 5.2
  TOP w0.102: R6302.2 85.69,69.74 v1(84.92,68.97) 86.06,67.83 87.27,67.83 87.34,67.9 NGFFM1.52
SSD_WAKE#: length 7.1
  TOP w0.114: v1(83.07,66.83) 83.79,67.55 R6309.2 ; NGFFM1.54 85.44,67.4 R6310.2 84.91,67.92 R6309.2 ; R6301.2 R6309.2
SUS_CLK_CPU: length 227.3
  TOP w0.114: R6108.1 131.16,14.11 131.06,14.01 130.99,14.01 130.02,13.04 130.02,11.8 128.85,10.62 128.85,8.87 129.07,8.64 v3(129.07,7.27) ; v3(195.46,30.69) 194.47,30.69 194.08,31.08 193.29,31.08 CPU1.DF49 ; R6311.1 88.24,65.07 88.84,64.47 90.96,64.47 v3(91.54,63.89)
  L3 w0.127: v3(109.29,36.09) 109.16,36.21 96.64,36.21 v3(96.22,36.63)
  L4 w0.127: v3(96.22,36.63) 95.72,37.13 95.72,47.49 92.59,50.62 92.59,61.77 91.54,62.81 v3(91.54,63.89) ; v3(195.46,30.69) 196.08,30.69 199.83,26.94 199.83,25.95 201.02,24.77 201.02,23.59 203.24,21.37 203.24,19.14 201.62,17.52 201.62,16.56 199.56,14.5 199.08,14.5 192.45,7.87 192.45,7.5 191.09,6.14 190.1,6.14 185.34,1.38 157.28,1.38 155.63,3.03 142.39,3.03 141.22,4.19 136.79,4.19 135.74,3.14 134.87,3.14 134.85,3.12 133.92,3.12 133.57,3.46 131.82,3.46 131.42,3.06 129.77,3.06 v3(129.3,3.53) ; v3(99.79,8.35) 100.28,8.85 100.94,8.85 101.68,8.11 101.68,7.79 101.74,7.73 102.11,7.73 102.45,7.39 102.45,7.15 103.02,6.58 103.26,6.58 103.44,6.39 106.28,6.39 106.88,6.99 114.74,6.99 115.75,8 124.63,8 125.36,7.27 v3(129.07,7.27)
  BOTTOM w0.114: v3(109.29,36.09) 109.11,35.92 108.06,35.92 104.91,32.77 104.15,32.77 102.25,30.87 102.25,12.23 v1(101.53,11.51) 100.15,10.13 100.15,8.72 v3(99.79,8.35) ; v3(129.07,7.27) 129.21,7.13 129.21,6.44 129.13,6.37 129.13,4.09 129.3,3.91 v3(129.3,3.53)
SUSCLK_SSD: length 4.7
  TOP w0.114: R6311.2 85,64.56 v1(85,63.9) NGFFM1.68
SUSLED_1: length 5.9
  TOP w0.381: v1(120.27,13.85) Q6401.1 120.27,10.8 121.29,9.78 R6405.1
SUSLED_2: length 4.4
  TOP w0.381: R6405.2 122.65,8.38 122.98,8.71 R6402.2 123.19,9.06 122.81,9.44 122.28,9.44 v1(122.17,9.55) 122.17,10.11 Q6402.D
SUSLED_CON: length 19.3
  TOP w0.381: 116.91,13.98 116.91,12.9 L6406.1 116.01,12.6 109.92,6.51 109.92,3.86 110.43,3.36 EC6402.1 110.8,3.44 110.8,4.37 R6411.2 110.8,4.39 110.8,5.5 110.79,5.51 R6412.1 ; 116.91,13.98 116.09,13.98 115.71,14.36 115.71,15.61 R6410.1 ; 116.91,13.98 v1(116.91,13.99)
SUSLED_CON_OR: length 4.5
  TOP w0.381: R6411.1 112.31,4.05 v1(113.03,3.33) 114.48,3.33 115.5,2.3 LED1.1
SUSLED_CON_P1: length 3.8
  TOP w0.381: R6407.1 119.94,8.33 120.32,8.71 v1(120.32,8.89) 120.32,9.85 119.94,10.23 Q6401.3
SUSLED_N: length 47.8
  TOP w0.102: v3(122.02,13.88) 121.96,13.83 Q6402.S ; ECIO1.20 83.6,10.38 83.46,10.51 83.46,12.73 v3(84.1,13.38)
  L3 w0.127: v3(122.02,13.88) 121.62,13.49 114.55,13.49 113.17,14.87 112.06,14.87 110.99,15.93 102.67,15.93 102.09,15.35 99.09,15.35 97.36,13.62 92.86,13.62 92.48,14 91.54,14 91.13,13.6 84.33,13.6 v3(84.1,13.38)
  BOTTOM w0.102: v3(122.02,13.88) 122.02,14.62 v1(121.94,14.69) 121.81,14.83 R6403.2
SVID_ALERT#_CPU: length 4.4
  TOP w0.102: v1(110.76,52.11) 111.28,51.59 R706.2 111.84,51.15 111.89,51.1 111.89,51.09 111.95,51.02 111.95,50.58 R707.2 112.02,50.57 112.95,51.49 PR4674.1
SVID_ALERT#_CPU_R: length 76.5
  TOP w0.102: R706.1 112.34,52.48 v3(112.7,52.12) ; CPU1.H1 167.17,69.47 166.37,70.27 166.37,70.75 164.97,72.14 164.96,72.14 164.63,72.47 163.99,72.47 163.78,72.68 158.72,72.68 v1(158.34,72.3) 157.85,71.81 157.85,64.23 156.64,63.02 v3(156.64,62.33)
  L4 w0.127: v3(156.64,62.33) 156.51,62.2 156.51,62.1 153.38,58.97 132.02,58.97 130.7,57.64 128.47,57.64 127.94,57.64 127.19,58.39 114.21,58.39 112.49,56.67 112.49,54.2 112.79,53.89 112.79,52.98 112.79,52.97 112.79,52.2 v3(112.7,52.12)
SVID_CLK_CPU: length 80.3
  TOP w0.102: CPU1.H2 169.85,69.17 167.1,69.17 164.97,71.3 164.94,71.3 164.38,71.86 163.74,71.86 163.54,72.06 158.96,72.06 158.46,71.56 v1(158.46,69.77) 158.46,64.48 158.46,63.98 157.34,62.86 v3(157.17,62.86) ; PR4634.1 v3(112.75,49.41) 111.96,49.41 R702.2
  L4 w0.127: v3(112.75,49.41) 113.42,50.07 113.42,52.71 113.43,52.71 113.43,54.16 113.12,54.46 113.12,56.41 114.47,57.76 126.93,57.76 127.68,57.01 128.2,57.01 128.73,57.01 130.96,57.01 132.28,58.33 153.11,58.33 153.11,58.33 153.64,58.33 157.17,61.86 v3(157.17,62.86)
  BOTTOM w0.102: v3(112.75,49.41) 111.96,49.41 PR4632.2
SVID_DATA_CPU: length 82.8
  TOP w0.102: PR4636.1 112.91,50.46 v3(112.77,50.6) ; v3(155.88,62.73) 156.03,62.89 156.03,63.28 157.24,64.48 157.24,72.06 158.49,73.32 v1(159.61,73.32) 164.01,73.32 164.24,73.08 164.88,73.08 166.99,70.98 166.99,70.35 167.61,69.72 169.32,69.72 169.38,69.78 170.33,69.78 170.64,69.47 CPU1.H3
  L4 w0.127: v3(112.77,50.6) 112.42,50.95 112.4,50.95 112.15,51.21 112.15,53.23 112.16,53.24 112.16,53.63 111.85,53.93 111.85,56.93 113.95,59.03 115.37,59.03 127.45,59.03 128.2,58.28 130.43,58.28 131.76,59.6 153.11,59.6 155.88,62.37 v3(155.88,62.73)
  BOTTOM w0.102: R708.2 111.94,50.44 PR4631.2 112.61,50.44 v3(112.77,50.6)
SW_ON_N_SIO: length 12
  TOP w0.102: R24044.1 89.88,27.67 v1(89.67,27.47) 89.14,26.93 87.38,26.93 86.91,26.46 86.91,25.98 86.8,25.86 ECIO1.69 86.8,22.95 v3(87.52,22.23)
  BOTTOM w0.102: R24016.1 85.97,23.02 86.4,22.59 87.16,22.59 v3(87.52,22.23) 87.52,21.43 R24009.1
SYS_PWROK: length 263.4
  TOP w0.102: v3(97.61,5.17) 97.61,6.03 97.19,6.45 R24032.2 ; CPU1.DP19 178.29,26.98 178.29,23.03 179.4,21.92 179.4,19.14 v3(178.66,18.4) ; Q6805.G 15.99,84.78 v1(16.27,84.49) v3(16.85,83.91) ; R1730.1 176.83,13.6 177.8,12.63 v3(177.8,11.54)
  L3 w0.127: v3(97.61,5.17) 99.3,6.86 102,6.86 102.14,6.72 102.2,6.72 102.47,6.45 102.47,6.39 102.93,5.93 104.82,5.93 105.18,6.28 115.43,6.28 117.53,8.38 124.51,8.38 126.09,6.8 129.51,6.8 129.7,6.98 134.51,6.98 135.16,7.63 152.34,7.63 152.73,8.03 156.73,8.03 158.15,9.45 168.38,9.45 169.27,10.33 176.59,10.33 v3(177.8,11.54) ; v3(12.45,64.48) 15.13,61.79 27.84,61.79 30.09,59.54 30.09,53.36 30.69,52.76 32.4,52.76 32.4,52.76 v3(32.39,52.76)
  L4 w0.127: v3(16.85,83.91) 16.85,83.27 15.16,81.59 15.16,77.8 17.37,75.6 17.37,70.07 12.45,65.15 v3(12.45,64.48) ; v3(46.99,48.75) 47.22,48.52 47.22,47.14 47.22,32.58 53.39,26.42 53.39,22.08 55.28,20.19 55.28,17.33 59.47,13.14 60.73,13.14 62.59,11.28 64.69,11.28 66.84,9.13 66.84,7.35 69.27,4.91 73.64,4.91 75.26,6.53 81.98,6.53 83.09,5.42 86.51,5.42 86.84,5.09 86.84,4.63 87.53,3.94 89.74,3.94 89.81,4.01 90.34,4.01 90.86,3.49 95.94,3.49 v3(97.61,5.17)
  BOTTOM w0.102: v3(177.8,11.54) 178.56,12.3 178.56,17.32 178.56,17.32 178.56,17.61 178.75,17.8 178.75,18.29 178.64,18.4 v3(178.66,18.4) ; v3(32.39,52.76) 33.76,52.76 36.06,50.46 43.53,50.46 45.24,48.75 v3(46.99,48.75)
SYS_RESET#: length 13.2
  TOP w0.102: CPU1.DK19 178.6,29.17 178.88,28.9 v3(178.96,28.9)
  BOTTOM w0.102: v3(178.96,28.9) 178.96,28.75 178.55,28.34 178.55,27.31 178.26,27.02 178.26,26.09 177.9,25.74 177.9,23.49 177.22,22.81 175.81,22.81 175.49,23.13 175.15,23.13 174.83,22.81 173.78,22.81 173.74,22.77 v1(172.71,22.77) 172.28,22.77 172.17,22.65 R1701.2
SYS_TMPIN1: length 7.1
  TOP w0.102: RT2402.1 79.71,28.65 79.39,28.32 v3(79.39,27.86) 80.07,27.86 80.17,27.75 v1(80.17,27.47) 80.17,27.15 79.82,26.79 79.82,26.28 79.6,26.06 ECIO1.87
  BOTTOM w0.102: v3(79.39,27.86) 79.44,27.8 C2427.1 80.24,28.27 80.19,28.33 R24114.1
TBT_LSX0_RXD: length 16.8
  TOP w0.102: CPU1.DK17 177.57,29.17 177.22,28.82 177.22,28.46 177.22,28.45 177.22,27.7 177.39,27.54 v3(178.05,27.54)
  BOTTOM w0.102: v3(178.05,27.54) 178.05,26.18 177.7,25.82 177.7,25.67 177.7,25.66 177.7,23.58 177.24,23.12 175.78,23.12 175.57,23.33 175.07,23.33 174.86,23.12 173.45,23.12 173.23,23.34 171.06,23.34 v1(170.57,22.85) 170.11,22.85 169.86,23.1 R1523.1 169.42,23.1 R1522.2
TBT_LSX1_RXD: length 7.2
  TOP w0.102: R1524.2 177.93,20.72 178.06,20.84 R1525.1 v1(178.06,22.27) 178.06,22.87 177.61,23.32 CPU1.DP17
TBT_LSX2_RXD: length 10
  TOP w0.102: CPU1.DL34 186.17,28.84 v3(186.36,28.84)
  BOTTOM w0.102: v3(186.36,28.84) 186.99,28.84 v1(187.16,28.67) 187.35,28.48 R1527.1 187.35,27.66 188.02,26.98 188.02,24.5 186.8,23.28 186.8,22.01 186.4,21.62 R1526.2
TBT_LSX3_RXD: length 10.1
  TOP w0.102: CPU1.DL33 184.81,28.52 184.48,28.19 184.48,28.2 v3(184.48,28.2)
  BOTTOM w0.102: v3(184.48,28.2) 184,27.71 184,27.08 v1(184.38,26.69) 184.66,26.69 185.32,26.03 185.32,23.59 185.83,23.08 185.83,21.4 185.63,21.2 R1508.2 184.77,21.2 184.7,21.27 R1517.1
TCRCOMP_DN: length 5.8
  TOP w0.203: CPU1.AY1 168.37,53.66 168.09,53.38
  TOP w0.381: 168.09,53.38 167.45,53.38 166.23,52.17 v1(166.23,51.33) R402.1
TCRCOMP_DP: length 8.1
  TOP w0.203: CPU1.AY2 169.82,53.99 168.38,53.99 168.09,54.27
  TOP w0.381: R402.2 165.34,52.53 v1(166.11,53.3) 167.08,54.27 168.09,54.27
TEST_MODE: length 9.3
  BOTTOM w0.114: TSMT1.2 37.54,21.83 37.88,21.5 37.88,19.02 38.48,18.42 38.48,17.98 37.58,17.08 37.58,15.35 37.6,15.33 ; 37.6,15.33 37.6,15.33 37.6,15.32 37.9,15.02 R5602.1 ; 37.6,15.33 v1(37.58,15.33)
THERMAL_SHUT#: length 122.2
  TOP w0.114: v3(181.07,8.93) 181.07,9.25 180.93,9.39 180.93,9.77 183.55,12.39 183.55,14.53 183.55,14.53 183.55,15.77 182.83,16.49 R2041.1 182.6,17.71 v1(181.84,18.47) 180.79,19.52 180.79,23.01 180.27,23.53 180.27,25.26 179.91,25.62 CPU1.DU22
  L4 w0.127: v3(181.07,8.93) 179.59,8.93 179.36,8.7 178.1,8.7 177.95,8.55 176.2,8.55 175.8,8.16 170.38,8.16 170.36,8.18 164.99,8.18 164.72,7.92 163.59,7.92 162.78,7.11 161.35,7.11 160.33,6.09 155.78,6.09 155.04,5.35 142.95,5.35 142.06,6.23 134.3,6.23 134.07,6.46 130.57,6.46 129.72,5.62 126.77,5.62 126.65,5.5 122.35,5.5 122.24,5.6 119.98,5.6 119.72,5.34 107.65,5.34 107.06,4.74 100.53,4.74 100.37,4.91 100.37,5.11 100.09,5.39 100.09,5.72 98.88,6.92 93.16,6.92 92.92,7.17 91.97,7.17 90.77,8.37 90.74,8.37 89.38,9.74 87.78,9.74 86.24,11.27 85.53,11.27 v3(85.43,11.17)
  BOTTOM w0.114: R24019.1 84.81,10.55 v3(85.43,11.17)
TP_CPU_PWRGD: length 2.9
  TOP w0.102: v3(167.85,40.1) 168.09,40.1 168.62,40.63 169.29,40.63 CPU1.CF1
  BOTTOM w0.102: v3(167.85,40.1) 167.86,40.11 TP1702.1
TP_DA11: length 2.4
  TOP w0.102: v3(173.92,32.11) 173.92,32.43 174.41,32.91 CPU1.DA11
  BOTTOM w0.102: TP619.1 174.85,32.11 v3(173.92,32.11)
TP_ISP_0: length 2.6
  TOP w0.102: CPU1.BF11 174.89,50.76 v3(174.99,50.86)
  BOTTOM w0.102: TP603.1 173.8,50.17 174.49,50.86 v3(174.99,50.86)
TP_ISP_1: length 1.7
  TOP w0.102: v3(174.75,52.22) 174.75,52.18 174.41,51.83 CPU1.BD11
  BOTTOM w0.102: v3(174.75,52.22) 174.69,52.15 174.55,52.15 TP602.1
TP_ISP_TRIG_0: length 2.4
  TOP w0.102: CPU1.BE10 174.61,51.22 174.93,51.54 175,51.54 175.02,51.56 v3(175.02,51.56)
  BOTTOM w0.102: v3(175.02,51.56) 175.64,51.56 TP604.1
TP_ISP_TRIG_1: length 2
  TOP w0.102: v3(174.64,50.3) CPU1.BF10
  BOTTOM w0.102: v3(174.64,50.3) 175.56,50.3 TP605.1
TP_PCH_IST_1: length 5.2
  TOP w0.102: CPU1.CY32 184.72,34.04 183.7,33.02 181.29,33.02 v3(181.12,32.84)
  BOTTOM w0.102: v3(181.12,32.84) 181.67,33.39 TP607.1
TP_PROC_SELECT#: length 7.9
  TOP w0.102: CPU1.D4 170.52,71.26 170.28,71.02 170.02,71.02 169.98,71.06 168.52,71.06 165.17,74.4 TP609.1
TP_SKTOCC#: length 6.5
  TOP w0.102: TP608.1 166.5,74.4 169.19,71.72 169.64,71.72 169.73,71.63 170.61,71.63 170.67,71.57 171.14,71.57 CPU1.C5
TS#_DIMM1_0: length 3.5
  TOP w0.102: DIMM1.134 v3(257.48,42.42)
  BOTTOM w0.102: v3(257.48,42.42) 257.18,42.73 v1(257.18,43.18) 257.18,44.41 R1231.2
TS#_DIMM1_1: length 3.8
  TOP w0.102: DIMM2.134 242.33,42.42 v3(242.52,42.24)
  BOTTOM w0.102: v3(242.52,42.24) 242.52,41.75 242.15,41.38 v1(242.09,41.38) 241.95,41.38 241.56,41.78 R1303.2
TSMT_SMB_SCL_U: length 7.8
  BOTTOM w0.114: R5615.2 48.56,12.35 48.72,12.18 v1(50.05,12.18) 51.85,12.18 52.02,12.35 52.02,14.65 51.81,14.86 U5602.6
TSMT_SMB_SCL_U_R: length 18.8
  BOTTOM w0.114: R5615.1 47.67,11.99 R5613.2 46.62,11.97 v1(44.63,13.96) 44.1,14.49 43.67,14.49 41.15,17.01 41.15,18.8 41.48,19.13 41.48,19.78 41.89,20.2 41.89,21.55 41.58,21.86 41.26,21.86 40.66,22.45 40.66,22.67 39.25,24.07 TSMT1.46
TSMT_SMB_SDA_U: length 4.7
  BOTTOM w0.114: R5616.2 v1(48.93,15.66) 49.58,15.01 49.58,13.71 49.7,13.59 U5602.5
TSMT_SMB_SDA_U_R: length 17.9
  BOTTOM w0.114: R5616.1 46.87,15.68 46.87,16.31 46.86,16.32 46.86,16.77 R5614.2 46.21,16.78 44.54,15.11 43.9,15.11 v1(42.23,16.78) 41.58,17.43 41.58,18.64 41.9,18.96 41.9,19.03 41.9,19.03 41.9,19.56 42.53,20.19 42.53,21.7 R5610.1 42.53,21.72 42.53,22 42.04,22.49 41.49,22.49 41.31,22.67 41.04,22.67 40.05,23.66 40.05,23.7 39.28,24.47 TSMT1.45
USB1_USB20_CON_N: length 14.5
  TOP w0.102: EL3509.2 51.85,89.16 54.64,89.16 55.41,89.93 56.47,89.93 ED3505.6 57.27,90.15 57.27,91.32 58.06,92.11 58.8,92.11 59.08,92.4 59.08,93.73 60.1,94.75 60.1,94.98 60.2,95.08 USB3R1.2
  BOTTOM w0.102: USB3R1.2 v1(61,95.96)
USB1_USB20_CON_P: length 14.2
  TOP w0.102: USB3R1.3 59.8,95.08 59.9,94.98 59.9,94.83 58.88,93.81 58.88,92.49 58.71,92.32 57.98,92.32 57.07,91.41 57.07,90.24 56.96,90.13 55.32,90.13 54.55,89.36 54.34,89.36 ED3505.1 54.06,89.61 53.81,89.36 51.83,89.36 EL3509.3
  BOTTOM w0.102: USB3R1.3 v1(59,95.96)
USB1_USB20_N: length 193.8
  TOP w0.102: v3(173.49,27.56) 173.35,27.56 CPU1.DN8 ; EL3509.1 50.89,89.15 50.42,89.15 50.28,89 50.28,85.75 ; 50.28,85.75 50.28,85.33 50.1,85.15 50.1,83.77 50.2,83.67 50.34,83.67 v3(50.6,83.92) ; 50.28,85.75 v1(50.64,85.75)
  L4 w0.114: v3(173.49,27.56) 173.26,27.33 173.14,27.33 172.77,27.7 172.03,27.7 171.72,28 167.76,28 167.57,27.81 160.86,27.81 155.33,22.28 153.97,22.28 153.5,21.82 148.74,21.82 147.67,20.75 137.17,20.75 135.88,22.04 123.77,22.04 122.49,20.77 118.87,20.77 118.04,19.94 115.11,19.94 114.28,20.77 103.29,20.77 102.86,21.2 95.71,21.2 95.47,21.45 92.92,21.45 91.68,20.21 71.55,20.21 70.92,19.58 69.06,19.58 67.65,20.99 66.73,20.99 63.47,24.25 63.47,28.2 60.31,31.35 60.31,50.93 58.67,52.57 58.67,72 57.63,73.03 56.33,73.03 51.66,77.7 51.66,79.6 52.01,79.94 52.01,80 52.99,80.98 52.99,83.02 52.56,83.44 51.07,83.44 50.94,83.56 50.94,83.81 50.83,83.92 v3(50.6,83.92)
USB1_USB20_P: length 194.1
  TOP w0.102: v1(49.72,88.39) 50.08,88.39 ; 50.08,88.39 50.08,89.09 50.34,89.35 50.9,89.35 EL3509.4 ; 50.08,88.39 50.08,85.42 49.89,85.23 49.89,83.68 50.11,83.46 50.34,83.46 v3(50.6,83.21) ; CPU1.DP8 173.35,26.91 v3(173.51,26.91)
  L4 w0.114: v3(173.51,26.91) 173.32,27.1 173.04,27.1 172.67,27.47 171.94,27.47 171.63,27.78 167.85,27.78 167.66,27.59 160.96,27.59 155.43,22.06 154.06,22.06 153.59,21.59 148.83,21.59 147.77,20.52 137.08,20.52 135.78,21.81 123.86,21.81 122.59,20.54 118.96,20.54 118.13,19.71 115.01,19.71 114.18,20.54 103.2,20.54 102.76,20.97 95.62,20.97 95.37,21.22 93.01,21.22 91.77,19.98 71.64,19.98 71.01,19.35 68.97,19.35 67.56,20.76 66.64,20.76 63.24,24.16 63.24,28.1 60.09,31.26 60.09,50.84 58.44,52.48 58.44,71.9 57.54,72.81 56.23,72.81 51.43,77.61 51.43,79.69 51.78,80.04 51.78,80.09 52.76,81.07 52.76,82.92 52.47,83.21 v3(50.6,83.21)
USB1_USB30_RX_CON_N: length 15.7
  BOTTOM w0.102: v1(56,92.71) USB3R1.5 57.03,93.58 57.13,93.68 57.13,94.55 57.3,94.72 57.3,95.72 56.96,96.07 56.42,96.07 53.84,93.49 53.84,90.86 53.98,90.72 ED3504.10 ED3504.1 53.98,88.65 53.84,88.51 53.84,88.37 54.13,88.08 54.13,87.74 54.35,87.51 EL3508.4
USB1_USB30_RX_CON_P: length 15.3
  BOTTOM w0.102: 53.64,92.18 v1(53.26,92.18) ; 53.64,92.18 53.64,90.86 53.5,90.72 ED3504.9 ED3504.2 53.5,88.65 53.64,88.51 53.64,88.28 53.92,88 53.92,87.74 53.7,87.51 EL3508.3 ; 53.64,92.18 53.64,93.58 56.33,96.27 57.04,96.27 57.51,95.81 57.51,94.63 57.34,94.46 57.34,93.94 57.7,93.58 USB3R1.6
USB1_USB30_RX_N: length 186.1
  TOP w0.102: v3(54.38,84.28) 54.8,83.86 v1(54.8,83.46) ; CPU1.DJ8 173.16,29.82 v3(173.47,30.12)
  L4 w0.114: v3(54.38,84.28) 54.14,84.04 54.14,83.38 54.28,83.24 55.19,83.24 55.59,82.84 55.59,80.97 54.55,79.92 54.55,77.54 57.76,74.33 58.17,74.33 60.44,72.06 60.44,52.9 61.61,51.73 61.61,33.36 64.96,30.01 64.96,27.31 65.89,26.38 67.37,26.38 68.72,25.04 68.72,22.9 70.11,21.5 89.03,21.5 91.02,23.49 96.55,23.49 96.71,23.32 98.48,23.32 99.3,22.5 103.4,22.5 103.73,22.16 115.36,22.16 115.94,21.58 117.77,21.58 118.26,22.06 121.2,22.06 122.72,23.59 127.16,23.59 127.61,24.03 129.01,24.03 129.37,23.67 136.1,23.67 137.72,22.04 146.05,22.04 147.21,23.2 152.58,23.2 155.22,25.84 156.34,25.84 160.73,30.23 166.35,30.23 166.77,30.66 168.14,30.66 168.41,30.93 171.93,30.93 172.74,30.12 v3(173.47,30.12)
  BOTTOM w0.102: v3(54.38,84.28) 54.13,84.53 54.13,84.95 54.35,85.17 EL3508.2
USB1_USB30_RX_P: length 186
  TOP w0.102: v1(53.53,83.46) 53.53,84.14 v3(53.67,84.28) ; v3(172.62,29.5) 172.3,29.82 CPU1.DJ6
  L4 w0.114: v3(53.67,84.28) 53.91,84.04 53.91,83.29 54.19,83.01 55.1,83.01 55.37,82.74 55.37,81.06 54.32,80.01 54.32,77.45 57.67,74.1 58.08,74.1 60.21,71.97 60.21,52.81 61.38,51.63 61.38,33.27 64.73,29.92 64.73,27.22 65.8,26.15 67.28,26.15 68.49,24.94 68.49,22.8 70.02,21.28 89.13,21.28 91.11,23.26 96.45,23.26 96.62,23.1 98.38,23.1 99.21,22.27 103.3,22.27 103.64,21.93 115.27,21.93 115.85,21.35 117.87,21.35 118.35,21.84 121.3,21.84 122.82,23.36 127.25,23.36 127.7,23.81 128.91,23.81 129.28,23.44 136,23.44 137.63,21.82 146.15,21.82 147.3,22.97 152.67,22.97 155.32,25.61 156.43,25.61 160.83,30 166.44,30 166.86,30.43 168.23,30.43 168.5,30.7 171.84,30.7 172.62,29.92 v3(172.62,29.5)
  BOTTOM w0.102: EL3508.1 53.7,85.15 53.92,84.92 53.92,84.53 v3(53.67,84.28)
USB1_USB30_TX_CMC_N: length 4.2
  BOTTOM w0.102: EL3507.2 52.2,85.23 51.98,85 51.98,83.28 ; 51.98,83.28 v1(52.34,83.28) ; 51.98,83.28 51.98,82.59 C3513.2
USB1_USB30_TX_CMC_P: length 4.2
  BOTTOM w0.102: C3514.2 51.77,82.57 51.77,84.23 ; v1(51.41,84.23) 51.77,84.23 ; 51.77,84.23 51.77,85 51.55,85.23 EL3507.1
USB1_USB30_TX_CON_N: length 23.4
  BOTTOM w0.102: EL3507.4 52.2,87.53 51.98,87.76 51.98,87.94 52.32,88.28 52.32,88.51 52.46,88.65 ED3504.4 ED3504.7 52.46,90.72 52.18,91 52.18,93.09 56.03,96.94 61.47,96.94 62.15,96.25 62.15,94.89 63.15,93.9 63.15,93.68 63.05,93.58 USB3R1.8 v1(62,92.7)
USB1_USB30_TX_CON_P: length 23
  BOTTOM w0.102: EL3507.3 51.55,87.53 51.77,87.76 51.77,88.02 52.12,88.37 52.12,88.51 51.98,88.65 ED3504.5 ED3504.6 51.98,92.17 ; 51.98,92.17 51.98,93.17 55.94,97.14 61.55,97.14 62.36,96.33 62.36,94.98 63.35,93.98 63.35,93.74 63.51,93.58 USB3R1.9 ; 51.98,92.17 v1(51.6,92.17)
USB1_USB30_TX_N: length 180.1
  TOP w0.102: v1(53.87,79.78) 53.85,79.8 v3(52.82,79.8) ; CPU1.DJ2 169.94,29.61 169.66,29.33 168.38,29.33 v3(168.14,29.09)
  L4 w0.114: v3(52.82,79.8) 52.58,79.56 52.33,79.56 52.08,79.31 52.08,77.94 56.57,73.45 57.81,73.45 59.47,71.79 59.47,52.63 60.74,51.36 60.74,32.96 64.07,29.63 64.07,24.24 66.91,21.41 67.96,21.41 69.37,20 70.45,20 71.07,20.63 89.48,20.63 91.45,22.61 95.99,22.61 96.98,21.62 103.03,21.62 103.47,21.19 114.92,21.19 115.55,20.56 118.07,20.56 118.69,21.19 121.58,21.19 123.06,22.67 127.51,22.67 127.99,23.15 128.54,23.15 129.23,22.46 136.05,22.46 137.34,21.17 147.5,21.17 148.65,22.32 153.14,22.32 153.84,23.02 155.29,23.02 160.54,28.27 165.59,28.27 166.41,29.09 v3(168.14,29.09)
  BOTTOM w0.102: v3(52.82,79.8) 52.67,79.65 52.43,79.65 52.33,79.75 C3513.1
USB1_USB30_TX_P: length 179.8
  TOP w0.102: CPU1.DJ1 169.43,29.53 168.41,29.53 v3(168.14,29.8) ; v1(52.03,79.29) 52.23,79.09 v3(52.82,79.09)
  L4 w0.114: v3(168.14,29.8) 167.69,29.8 167.6,29.71 167.6,29.41 167.51,29.32 166.32,29.32 165.5,28.5 160.44,28.5 155.19,23.25 153.75,23.25 153.05,22.55 148.56,22.55 147.4,21.4 137.44,21.4 136.15,22.69 129.33,22.69 128.64,23.38 127.9,23.38 127.41,22.89 122.97,22.89 121.49,21.42 118.6,21.42 117.97,20.79 115.64,20.79 115.02,21.42 103.56,21.42 103.13,21.85 97.07,21.85 96.08,22.84 91.36,22.84 89.38,20.86 70.98,20.86 70.35,20.23 69.47,20.23 68.06,21.64 67,21.64 64.3,24.34 64.3,29.72 60.97,33.06 60.97,51.46 59.7,52.73 59.7,71.89 57.9,73.68 56.66,73.68 52.31,78.04 52.31,79.22 52.42,79.33 52.58,79.33 v3(52.82,79.09)
  BOTTOM w0.102: v3(52.82,79.09) 52.82,79.15 52.53,79.44 52.35,79.44 52.13,79.66 52.13,80.64 51.99,80.78 51.6,80.78 51.44,80.93 C3514.1
USB2_COMP: length 7.3
  TOP w0.114: CPU1.DN5 171.1,28.17 169.35,28.17 169.11,28.41 168.22,28.41 166.55,30.08 v1(166.23,30.08) 166.21,30.06 R1603.1
USB2_USB20_CON_N: length 28.9
  TOP w0.14: v3(204.57,99.83) 204.36,100.04 203.75,100.04 EL3503.2
  BOTTOM w0.14: v1(190.89,95.08) USB3R2.2 189.27,95.08 189.13,95.22 189.13,95.78 189.38,96.03 192.9,96.03 194.71,94.22 198.37,94.22 200.3,92.29 202.74,92.29 203.16,92.7 203.16,94.81 202.45,95.52 202.45,95.95 ED3502.6 202.45,96.36 202.45,98.04 203.41,99.01 203.41,99.94 203.74,100.27 204.12,100.27 v3(204.57,99.83)
USB2_USB20_CON_P: length 29.2
  TOP w0.14: v3(204.57,100.54) 204.33,100.3 203.72,100.3 EL3503.3
  BOTTOM w0.14: v1(188,95.97) USB3R2.3 188.73,95.08 188.87,95.22 188.87,95.89 189.27,96.29 193.01,96.29 194.82,94.49 198.48,94.49 200.41,92.55 202.63,92.55 202.89,92.82 202.89,93.22 ED3502.1 202.89,93.7 202.89,94.7 202.18,95.41 202.18,98.15 203.15,99.12 203.15,100.05 203.63,100.54 v3(204.57,100.54)
USB2_USB20_N: length 114.9
  TOP w0.14: EL3503.1 202.86,100.02 202.38,100.02 v3(202.21,99.85) ; v3(175.38,29.51) 175.2,29.51 CPU1.DK11
  L3 w0.127: v3(175.38,29.51) 175.21,29.34 175.07,29.34 174.95,29.47 174.95,29.7 175.19,29.95 175.19,30.39 175.13,30.44 175.13,35.06 175.86,35.78 175.86,43.61 174.17,45.29 170.4,45.29 166.21,49.48 166.21,74.96 169.36,78.11 179.25,78.11 181.74,80.6 181.74,84.57 183.24,86.07 183.24,91.65 180.61,94.28 180.61,98.5 183.31,101.19 200.49,101.19 201.35,100.33 201.72,100.33 v3(202.21,99.85)
USB2_USB20_P: length 116
  TOP w0.14: v3(202.21,100.56) 202.48,100.29 202.86,100.29 EL3503.4 ; CPU1.DJ11 174.87,29.63 174.73,29.49 v3(174.47,29.49)
  L3 w0.127: v3(174.47,29.49) 174.72,29.74 174.72,29.8 174.96,30.04 174.96,30.29 174.91,30.35 174.91,35.15 175.63,35.87 175.63,43.51 174.08,45.06 170.31,45.06 165.99,49.39 165.99,75.06 169.27,78.34 179.16,78.34 181.51,80.69 181.51,84.66 183.01,86.16 183.01,91.56 180.39,94.18 180.39,98.59 183.21,101.42 200.59,101.42 201.45,100.56 v3(202.21,100.56)
  BOTTOM w0.14: v3(174.47,29.49) 174.36,29.49 v1(173.53,28.66)
USB2_USB30_RX_CON_N: length 13.4
  TOP w0.14: EL3502.4 182.82,88.69 183.12,88.39 183.96,88.39 184.25,88.09 184.25,87.3 184.39,87.16 186.05,87.16 186.19,87.3 186.19,87.68 186.08,87.79 ED3501.1 ED3501.10 186.08,89.67 186.19,89.78 186.19,90.99 186,91.18 186,93.44 185.86,93.58 USB3R2.5
  BOTTOM w0.14: USB3R2.5 v1(184.11,93.58)
USB2_USB30_RX_CON_P: length 12.8
  TOP w0.14: 184.94,86.9 184.28,86.9 183.99,87.19 183.99,87.98 183.85,88.12 182.97,88.12 182.88,88.04 EL3502.3 ; 184.94,86.9 186.16,86.9 186.46,87.19 186.46,87.71 186.56,87.82 ED3501.2 ED3501.9 186.56,89.67 186.46,89.78 186.46,91.1 186.26,91.29 186.26,93.33 186.51,93.58 USB3R2.6 ; 184.94,86.9 v1(184.94,86.58)
USB2_USB30_RX_N: length 82.1
  TOP w0.14: EL3502.2 179.45,88.69 v3(179.39,88.74) ; CPU1.DG9 173.66,30.63 174.11,30.18 v3(174.49,30.18)
  L3 w0.127: v3(179.39,88.74) 179.64,88.5 180.02,88.5 180.28,88.24 180.28,85.57 180.88,84.98 180.88,80.98 178.9,79.01 169.04,79.01 165.33,75.3 165.33,48.95 166.93,47.35 166.93,45.38 167.6,44.72 172.08,44.72 174.57,42.23 174.57,34.98 174.24,34.66 174.24,32.74 174.57,32.42 174.57,30.26 v3(174.49,30.18)
  BOTTOM w0.14: v3(179.39,88.74) 179.3,88.84 178.6,88.84 v1(178.59,88.82)
USB2_USB30_RX_P: length 82.2
  TOP w0.14: v3(173.77,31.11) 173.31,31.11 CPU1.DG7 ; EL3502.1 180.5,88.04 180.37,88.18 180.37,88.28 180.23,88.42 179.78,88.42 179.67,88.31 179.67,88.17 179.53,88.03 v3(179.39,88.03)
  L3 w0.127: v3(173.77,31.11) 173.77,30.95 173.91,30.81 174.21,30.81 174.34,30.94 174.34,32.32 174.01,32.65 174.01,34.76 174.34,35.08 174.34,42.13 171.99,44.49 167.5,44.49 166.7,45.29 166.7,47.26 165.11,48.85 165.11,75.4 168.95,79.24 178.81,79.24 180.65,81.08 180.65,84.88 180.05,85.48 180.05,88.14 179.92,88.27 179.64,88.27 v3(179.39,88.03)
  BOTTOM w0.14: v3(179.39,88.03) 179.84,88.03 v1(180.15,88.34)
USB2_USB30_TX_CMC_N: length 3.4
  TOP w0.14: 179.38,85.95 179.75,86.32 180.16,86.32 180.35,86.51 EL3501.2 ; 179.38,85.95 v1(179.13,86.2) ; 179.38,85.95 179.28,85.85 C3501.2
USB2_USB30_TX_CMC_P: length 3.1
  TOP w0.14: C3502.2 180.19,85.02 180.05,85.16 179.69,85.16 179.55,85.3 179.55,85.74 179.86,86.05 180.18,86.05 180.37,85.86 EL3501.1
USB2_USB30_TX_CON_N: length 18.5
  TOP w0.14: USB3R2.8 192,93.58 192.09,93.5 192.09,92.89 191.28,92.08 188.19,92.08 187.71,91.59 187.71,89.78 187.6,89.67 ED3501.7 ED3501.4 187.6,87.52 187.67,87.46 187.67,86.63 187.04,86 ; EL3501.4 182.35,86.51 182.56,86.3 182.85,86.3 183.58,85.57 186.61,85.57 187.04,86 ; v1(186.82,86.23) 187.04,86
USB2_USB30_TX_CON_P: length 18.5
  TOP w0.14: EL3501.3 182.33,85.86 182.51,86.04 182.74,86.04 183.47,85.31 184.48,85.31 ; 184.48,85.31 v1(184.48,84.96) ; 184.48,85.31 186.72,85.31 187.23,85.81 187.93,86.52 187.93,87.37 188.08,87.52 ED3501.5 ED3501.6 188.08,89.67 187.98,89.78 187.98,91.48 188.31,91.81 191.39,91.81 192.35,92.78 192.35,93.41 192.52,93.58 USB3R2.9
USB2_USB30_TX_N: length 76.5
  TOP w0.14: C3501.1 179.56,83.4 179.56,83.23 179.48,83.15 178.14,83.15 ; CPU1.DJ3 170.81,29.91 v3(170.98,30.09) ; 178.14,83.15 178.07,83.15 177.81,82.89 177.81,82.18 v3(177.48,81.85) ; 178.14,83.15 v1(178.14,83.5)
  L3 w0.127: v3(177.48,81.85) 177.48,81.46 177.62,81.32 177.81,81.32 177.96,81.17 177.96,80.4 177.68,80.12 168.61,80.12 164.21,75.72 164.21,48.11 165.61,46.71 165.61,44.5 168.39,41.72 173.56,41.72 173.68,41.6 173.68,35.55 171.59,33.45 171.59,30.03 171.33,29.77 171.11,29.77 170.98,29.9 v3(170.98,30.09)
USB2_USB30_TX_P: length 76.4
  TOP w0.14: 179.5,82.89 178.18,82.89 178.07,82.78 178.07,81.97 v3(178.19,81.85) ; 179.5,82.89 179.59,82.89 179.83,83.12 179.83,83.32 C3502.1 ; 179.5,82.89 v1(179.5,82.56) ; CPU1.DJ5 171.46,29.17 v3(171.65,28.98)
  L3 w0.127: v3(171.65,28.98) 171.71,29.04 171.71,29.83 171.82,29.93 171.82,33.36 173.91,35.45 173.91,41.69 173.65,41.95 168.48,41.95 165.84,44.6 165.84,46.81 164.44,48.2 164.44,75.63 168.71,79.89 177.78,79.89 178.19,80.3 v3(178.19,81.85)
USB3_USB20_CON_N: length 33.8
  TOP w0.102: EL3401.3 47.91,24.35 47.39,24.35 44.83,26.91 44.83,27.08 44.83,27.51 ED3401.1 44.83,28.05 44.83,28.33 44.1,29.06 44.1,31.44 43.74,31.79 39.2,31.79 35.22,35.78 30.21,35.78 29.16,36.83 29.16,40.37 30.08,41.29 30.67,41.29 30.84,41.46 USB3R3.2
  BOTTOM w0.102: USB3R3.2 v1(29.85,42.04)
USB3_USB20_CON_P: length 33.4
  TOP w0.102: EL3401.2 47.89,24.56 47.47,24.56 45.04,27 45.04,28.41 44.3,29.15 44.3,30.21 ED3401.6 44.3,30.74 44.3,31.53 43.83,32 39.29,32 35.3,35.99 30.29,35.99 29.36,36.91 29.36,40.29 30.17,41.09 30.59,41.09 30.84,40.84 USB3R3.3
  BOTTOM w0.102: USB3R3.3 v1(29.85,40.04)
USB3_USB20_N: length 145.4
  TOP w0.102: 61.45,19.91 60.25,21.11 56.84,21.11 55.23,22.71 52.77,22.71 51.12,24.37 48.85,24.37 EL3401.4 ; 61.45,19.91 v1(61.18,19.64) ; 61.45,19.91 63.15,18.2 63.15,17.16 62.87,16.87 62.87,16.08 v3(62.63,15.84) ; CPU1.DP13 176.22,26.78 v3(176.3,26.78)
  L3 w0.114: v3(62.63,15.84) 62.86,15.6 62.86,15.33 63.6,14.59 66.28,14.59 67.01,15.31 69.51,15.31 72.77,18.58 72.77,19.18 76.3,22.71 88.38,22.71 88.96,22.14 91.49,22.14 92.08,22.74 96.8,22.74 97.04,22.98 101.74,22.98 103.13,24.37 105.85,24.37 107.67,22.56 116.24,22.56 116.86,21.93 117.54,21.93 118.06,22.45 122.69,22.45 123.27,23.04 128.5,23.04 128.99,22.55 136.14,22.55 137.66,21.03 141,21.03 141.46,21.48 147.62,21.48 148.35,22.21 153.66,22.21 154.16,22.7 157.6,22.7 161.52,26.62 170.16,26.62 171.05,25.73 175.25,25.73 v3(176.3,26.78)
USB3_USB20_P: length 145.7
  TOP w0.102: CPU1.DN13 176.2,27.45 v3(176.24,27.45) ; 62.8,18.84 v1(63.07,19.11) ; 62.8,18.84 63.36,18.29 63.36,17.07 63.07,16.79 63.07,16.1 v3(63.34,15.84) ; 62.8,18.84 60.33,21.31 56.92,21.31 55.31,22.92 52.86,22.92 51.2,24.57 48.84,24.57 EL3401.1
  L3 w0.114: v3(176.24,27.45) 176.24,27.35 175.87,26.99 175.87,26.67 175.16,25.96 171.15,25.96 170.25,26.85 161.42,26.85 157.51,22.93 154.06,22.93 153.57,22.44 148.25,22.44 147.53,21.71 141.36,21.71 140.91,21.25 137.75,21.25 136.23,22.78 129.08,22.78 128.6,23.27 123.18,23.27 122.59,22.68 117.97,22.68 117.44,22.16 116.96,22.16 116.33,22.78 107.76,22.78 105.94,24.6 103.03,24.6 101.64,23.21 96.95,23.21 96.7,22.96 91.99,22.96 91.4,22.37 89.05,22.37 88.48,22.94 76.21,22.94 72.54,19.28 72.54,18.67 69.41,15.54 66.91,15.54 66.19,14.82 63.69,14.82 63.09,15.42 63.09,15.59 v3(63.34,15.84)
USB3_USB30_RX_CON_N: length 25.7
  TOP w0.102: USB3R3.5 32.34,37.68 32.44,37.78 33.03,37.78 33.45,38.21 34.36,40.41 34.36,48.9 32.19,51.07 31.47,52.81 31.24,53.36 31.24,54.1 30.52,54.83 ED3402.10 ED3402.1 27.5,54.83 27.05,55.28 26.77,55.28 26.55,55.5 EL3404.4
  BOTTOM w0.102: USB3R3.5 v1(33.33,37.04)
USB3_USB30_RX_CON_P: length 25.6
  TOP w0.102: USB3R3.6 32.34,38.09 32.44,37.99 32.95,37.99 33.28,38.32 34.16,40.45 34.16,48.82 32.02,50.96 31.04,53.32 31.04,54.02 30.43,54.63 30.1,54.63 29.83,54.35 ED3402.9 ED3402.2 27.8,54.35 27.53,54.63 27.41,54.63 26.97,55.07 26.74,55.07 26.52,54.85 EL3404.3
  BOTTOM w0.102: USB3R3.6 v1(33.33,39.04)
USB3_USB30_RX_N: length 204.2
  TOP w0.102: CPU1.DE7 172.83,31.59 v3(172.44,31.98) ; EL3404.2 24.52,55.5 24.29,55.27 23.36,55.27 21.81,54.23 21.18,53.6 ; v3(19.91,52.58) 20.28,52.58 20.44,52.74 20.44,52.86 21.18,53.6 ; 21.18,53.6 v1(20.91,53.87)
  L3 w0.114: v3(19.91,52.58) 19.91,52.53 20.2,52.24 20.38,52.24 20.94,51.68 21.5,48.48 21.6,48.2 22.32,46.93 25.83,38.54 25.83,38.53 26.73,34.04 26.73,29.37 26.12,28.76 26.12,20.33 32.5,13.95 53.35,13.95 53.99,14.58 56.6,15.67 61.46,15.67 62.85,17.06 66.23,17.06 69.28,20.11 71.54,20.11 75.69,24.26 88.99,24.26 89.59,23.67 90.71,23.67 91.3,24.26 92.86,24.26 93.86,25.26 96.06,25.26 96.75,25.95 106.55,25.95 108.42,24.08 122.1,24.08 122.62,24.6 129.52,24.6 129.69,24.43 142.21,24.43 143.88,26.1 147.7,26.1 148.67,25.12 153.14,25.12 154.28,26.27 156.93,26.27 160.57,29.9 166.55,29.9 168,28.46 171.84,28.46 172.13,28.75 172.13,29.07 172.06,29.15 171.94,29.26 171.94,29.74 172.93,30.73 172.93,31.6 172.85,31.68 172.55,31.68 172.44,31.79 v3(172.44,31.98)
USB3_USB30_RX_P: length 204.9
  TOP w0.102: CPU1.DE9 173.16,31.87 v3(173.16,32) ; EL3404.1 24.51,54.85 24.3,55.06 23.42,55.06 21.94,54.08 21.33,53.46 20.64,52.77 20.64,52.65 19.91,51.92 v3(19.91,51.87)
  L3 w0.114: v3(173.16,32) 173.16,30.63 172.17,29.65 172.17,29.36 172.29,29.24 172.29,29.24 172.36,29.17 172.36,28.65 171.94,28.23 167.9,28.23 166.46,29.68 160.66,29.68 157.03,26.04 154.37,26.04 153.23,24.9 148.58,24.9 147.6,25.87 143.97,25.87 142.3,24.2 129.59,24.2 129.42,24.37 122.72,24.37 122.2,23.85 108.33,23.85 106.46,25.72 96.85,25.72 96.15,25.03 93.96,25.03 92.96,24.03 91.4,24.03 90.8,23.44 89.49,23.44 88.9,24.03 75.79,24.03 71.64,19.88 69.37,19.88 66.32,16.83 62.95,16.83 61.55,15.44 56.65,15.44 54.12,14.39 53.45,13.72 32.41,13.72 25.9,20.23 25.9,28.86 26.5,29.46 26.5,34.02 25.61,38.47 22.11,46.83 21.39,48.1 21.28,48.42 20.73,51.57 20.29,52.01 20.05,52.01 v3(19.91,51.87)
  BOTTOM w0.102: v3(19.91,51.87) 20.22,51.87 v1(20.66,51.43)
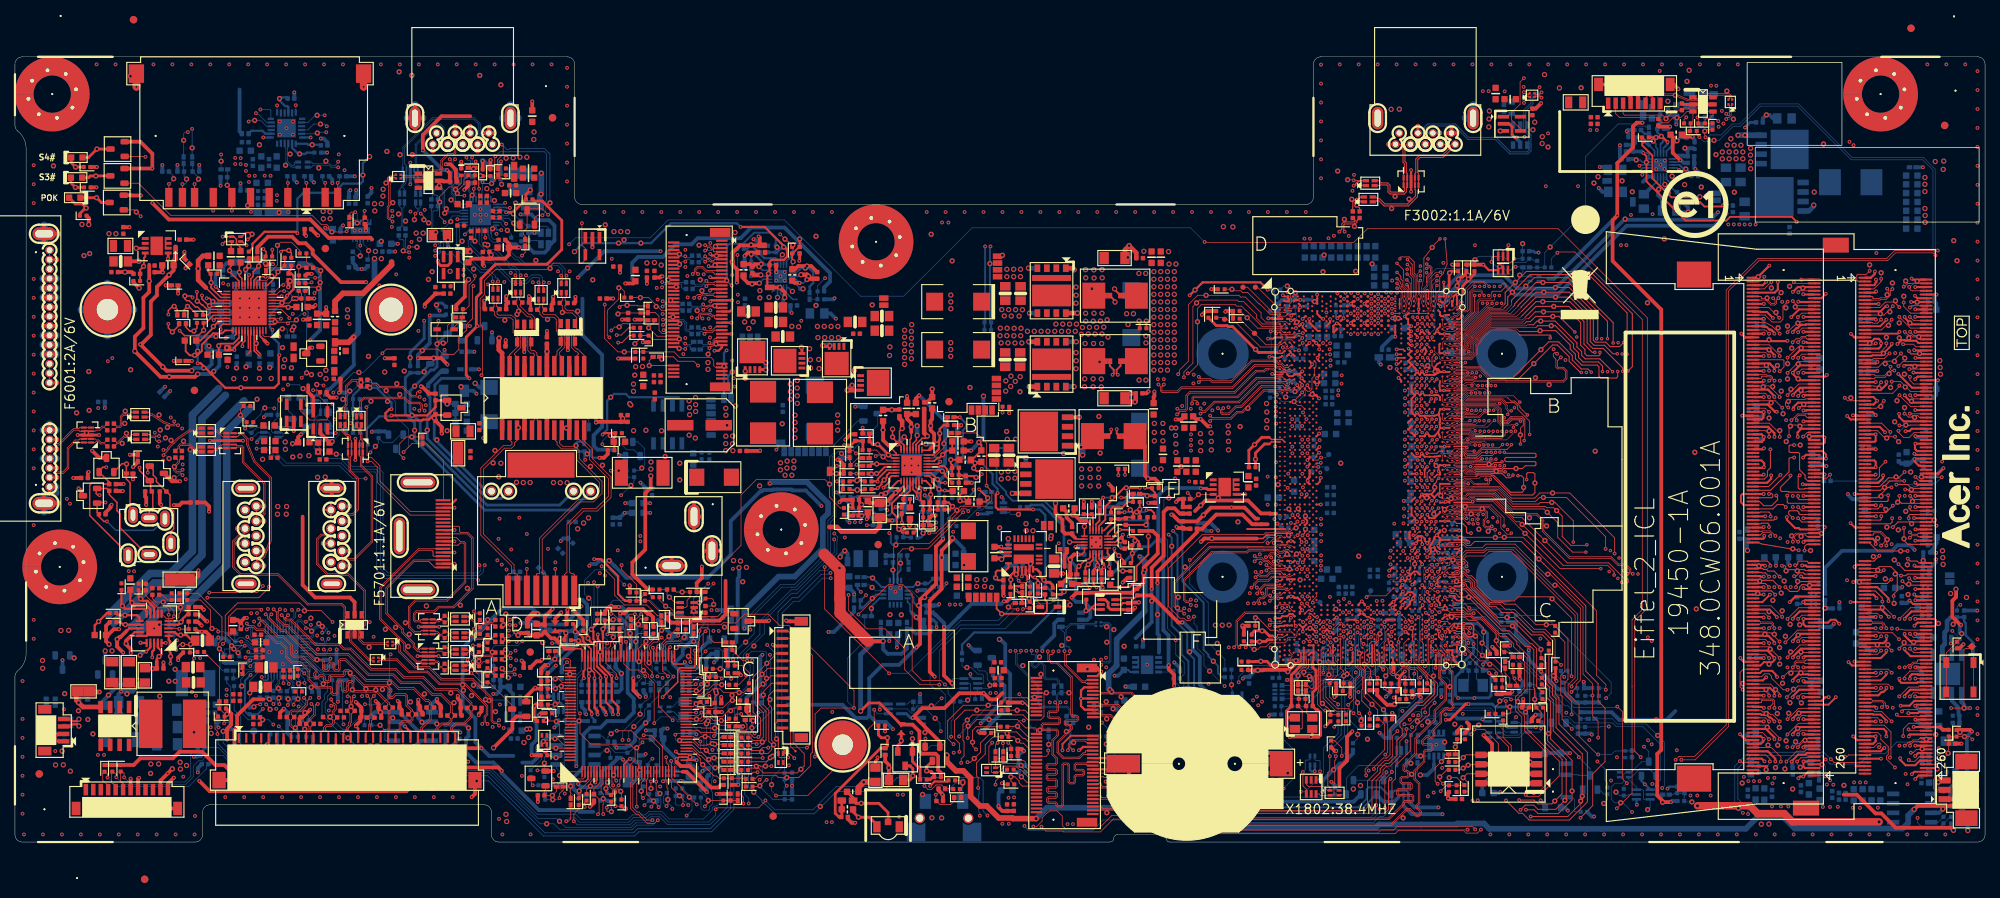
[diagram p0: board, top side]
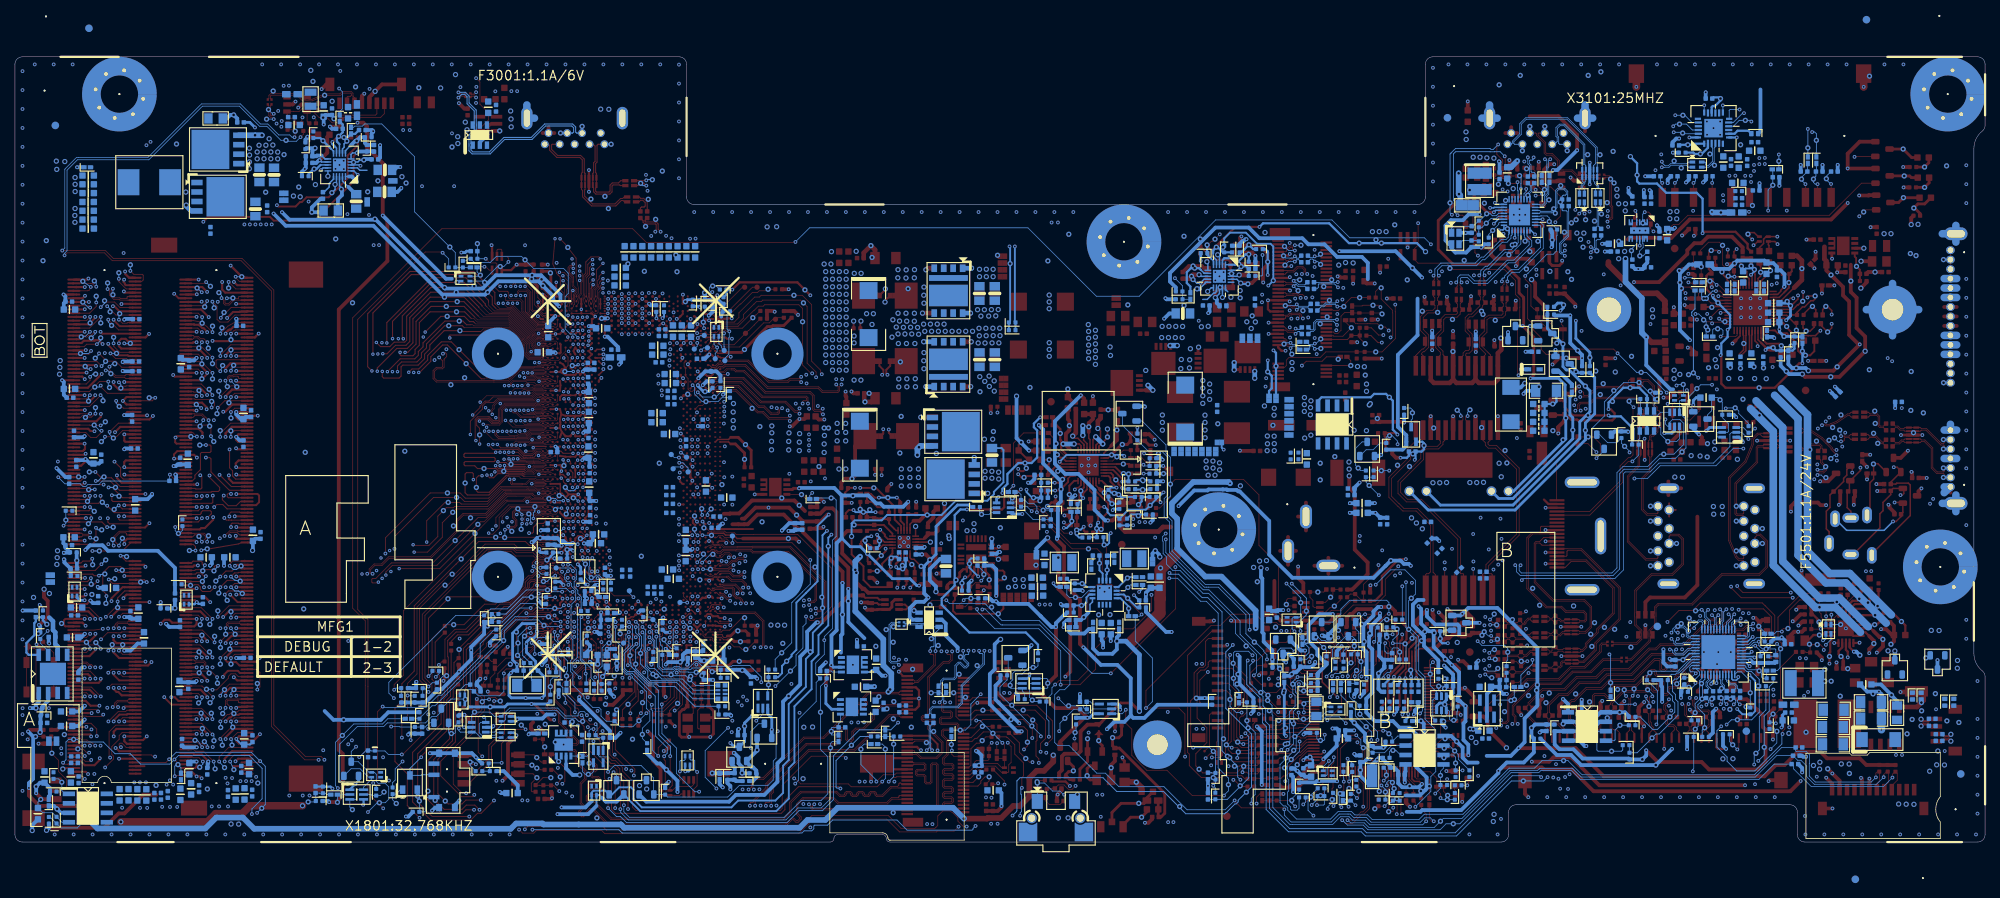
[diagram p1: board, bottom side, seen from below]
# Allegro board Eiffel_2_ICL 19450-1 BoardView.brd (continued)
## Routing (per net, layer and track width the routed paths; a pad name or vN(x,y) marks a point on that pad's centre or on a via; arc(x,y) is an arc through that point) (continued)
USB3_USB30_TX_CMC_N: length 4.8
  TOP w0.102: v1(22.59,53.77) 22.59,53.38 ; 22.59,53.38 23.51,53.38 24.11,52.79 24.42,52.79 24.62,52.99 EL3403.2 ; 22.59,53.38 22.12,53.38 21.86,53.12 21.86,52.81 C3413.2
USB3_USB30_TX_CMC_P: length 4.5
  TOP w0.102: EL3403.1 24.68,52.33 24.43,52.58 24.03,52.58 23.73,52.88 ; 23.73,52.88 23.43,53.18 22.21,53.18 22.06,53.03 22.06,52.76 C3414.2 ; 23.73,52.88 v1(23.48,52.63)
USB3_USB30_TX_CON_N: length 18
  TOP w0.102: USB3R3.8 32.34,43.69 32.44,43.79 33.29,43.79 33.51,44.01 33.51,48.13 30.67,50.98 30.67,52.95 30.45,53.17 29.76,53.17 29.62,53.31 ED3402.7 ED3402.4 27.8,53.31 27.66,53.17 27.44,53.17 27.03,52.76 26.78,52.76 26.56,52.99 EL3403.4
  BOTTOM w0.102: USB3R3.8 v1(33.33,43.04)
USB3_USB30_TX_CON_P: length 17.6
  TOP w0.102: EL3403.3 26.53,52.33 26.76,52.56 27.11,52.56 27.52,52.97 27.66,52.97 27.8,52.83 ED3402.5 ED3402.6 29.59,52.83 29.73,52.97 30.37,52.97 30.47,52.87 30.47,50.89 33.31,48.05 33.31,44.1 33.21,44 32.45,44 32.34,44.11 USB3R3.9
  BOTTOM w0.102: USB3R3.9 v1(33.33,45.04)
USB3_USB30_TX_N: length 192.9
  TOP w0.102: v3(22.46,49.22) 22.18,49.5 21.63,49.5 21.27,49.86 21.27,50.39 21.83,50.96 21.83,51.23 C3413.1 ; v3(169.82,31.41) 170.16,31.41 170.35,31.21 170.55,31.21 CPU1.DF3
  L3 w0.114: v3(169.82,31.41) 169.54,31.41 169.25,31.12 169.25,30.88 168.92,30.54 160.62,30.54 157.69,27.62 154.94,27.62 152.86,25.54 148.85,25.54 147.87,26.52 143.7,26.52 142.04,24.85 129.86,24.85 129.68,25.04 122.03,25.04 121.49,24.5 108.63,24.5 106.75,26.37 102.61,26.37 102.06,26.92 99.8,26.92 99.25,26.37 96.58,26.37 95.88,25.68 93.69,25.68 92.69,24.68 75.52,24.68 72.01,21.16 69.43,21.16 65.74,17.48 61.96,17.48 60.58,16.1 54.91,16.1 53.18,14.37 32.67,14.37 26.54,20.5 26.54,28.54 27.15,29.15 27.15,37.23 26.52,40.53 25.43,42.09 24.4,47.93 23.69,48.94 22.93,49.47 22.72,49.47 v3(22.46,49.22)
  BOTTOM w0.102: v1(21.33,48.87) 21.61,48.87 21.96,49.22 v3(22.46,49.22)
USB3_USB30_TX_P: length 193.7
  TOP w0.102: C3414.1 22.04,51.23 22.04,50.87 21.47,50.31 21.47,49.94 21.71,49.7 22.23,49.7 v3(22.46,49.93) ; CPU1.DF5 171.26,30.95 170.81,31.41 170.81,31.62 170.61,31.82 170.35,31.82 170.33,31.8 170,31.8 169.99,31.81 169.65,31.81 169.64,31.8 169.35,31.8 v3(169.02,31.47)
  L3 w0.114: v3(169.02,31.47) 169.02,30.97 168.82,30.77 160.52,30.77 157.6,27.85 154.84,27.85 152.77,25.77 148.94,25.77 147.96,26.75 143.61,26.75 141.94,25.08 129.95,25.08 129.77,25.26 121.93,25.26 121.4,24.73 108.72,24.73 106.85,26.6 102.7,26.6 102.16,27.14 99.7,27.14 99.16,26.6 96.48,26.6 95.79,25.9 93.59,25.9 92.6,24.91 75.43,24.91 71.91,21.39 69.33,21.39 65.65,17.71 61.87,17.71 60.49,16.33 54.82,16.33 53.09,14.6 32.77,14.6 26.77,20.6 26.77,28.45 27.37,29.05 27.37,37.25 26.73,40.62 25.64,42.18 24.61,48.02 23.85,49.11 23,49.7 22.68,49.7 v3(22.46,49.93)
  BOTTOM w0.102: v3(22.46,49.93) 21.78,49.93 21.37,50.34 21.37,50.34 v1(21.37,50.34)
USB4_USB20_CON_N: length 25.8
  TOP w0.102: USB3R4.2 42.34,41.44 42.18,41.28 41.02,41.28 40.41,40.67 40.41,37.23 41.87,35.77 44.64,35.77 46.75,33.67 46.75,30.75 ED3401.4 46.75,30.2 46.75,29.16 46,28.42 46,27.17 46.66,26.51 47.46,26.51 ; 47.46,26.51 v1(47.46,26.12) ; 47.46,26.51 49.8,26.51 EL3402.3
USB4_USB20_CON_P: length 26
  TOP w0.102: USB3R4.3 42.34,40.97 42.24,41.07 41.1,41.07 40.62,40.59 40.62,37.32 41.96,35.98 44.73,35.98 46.95,33.75 46.95,29.08 46.2,28.33 46.2,28.05 ED3401.3 46.44,27.78 46.2,27.54 46.2,27.25 46.75,26.71 49.81,26.71 EL3402.2
  BOTTOM w0.102: USB3R4.3 v1(41.35,40.04)
USB4_USB20_N: length 141.7
  TOP w0.102: EL3402.4 50.73,26.49 51.28,26.49 51.43,26.34 51.43,25.51 53.61,23.32 55.48,23.32 57.09,21.72 61.3,21.72 61.72,21.3 ; v3(174.36,28.85) 174.05,29.17 CPU1.DK10 ; 61.72,21.3 63.81,19.21 63.81,16.22 64.15,15.88 64.61,15.88 v3(64.87,15.63) ; 61.72,21.3 v1(61.45,21.03)
  L3 w0.114: v3(174.36,28.85) 174.16,28.85 172.9,27.59 171.46,27.59 171.38,27.66 167.55,27.66 167.3,27.92 160.02,27.92 157.32,25.21 154.46,25.21 153.5,24.25 147.74,24.25 146.76,25.22 144.28,25.22 140.73,21.67 137.93,21.67 136.28,23.32 129.56,23.32 129.2,23.68 122.98,23.68 122.5,23.2 108.03,23.2 106.16,25.08 102.91,25.08 101.48,23.64 94.23,23.64 93.98,23.38 91.72,23.38 91.12,22.79 89.23,22.79 88.63,23.38 76.06,23.38 71.68,19 69.47,19 66.29,15.82 65.05,15.82 v3(64.87,15.63)
USB4_USB20_P: length 142.1
  TOP w0.102: 64.01,17.49 64.01,19.29 61.39,21.92 57.17,21.92 55.57,23.53 53.7,23.53 51.63,25.59 51.63,26.42 51.36,26.69 50.76,26.69 EL3402.1 ; 64.01,17.49 64.01,16.3 64.23,16.09 64.61,16.09 v3(64.87,16.34) ; 64.01,17.49 v1(64.4,17.49) ; CPU1.DJ10 173.88,29.82 v3(173.54,29.47)
  L3 w0.114: v3(173.54,29.47) 173.68,29.47 173.94,29.21 173.94,28.95 172.8,27.82 171.55,27.82 171.48,27.89 167.65,27.89 167.39,28.14 159.93,28.14 157.22,25.44 154.37,25.44 153.4,24.48 147.83,24.48 146.85,25.45 144.19,25.45 140.64,21.9 138.02,21.9 136.38,23.55 129.66,23.55 129.29,23.91 122.89,23.91 122.41,23.43 108.13,23.43 106.25,25.3 102.82,25.3 101.38,23.87 94.14,23.87 93.88,23.61 91.62,23.61 91.03,23.02 89.32,23.02 88.73,23.61 75.96,23.61 71.58,19.23 69.38,19.23 66.19,16.05 65.16,16.05 v3(64.87,16.34)
USB4_USB30_RX_CON_N: length 23.3
  TOP w0.102: EL3406.4 46.43,55.65 46.23,55.46 46.23,55.08 46.5,54.81 46.5,53.94 46.63,53.81 ED3403.1 ED3403.10 46.63,51.8 46.49,51.67 46.49,50.51 47.94,49.07 47.94,40.26 45.49,37.81 43.97,37.81 43.84,37.68 USB3R4.5
  BOTTOM w0.102: USB3R4.5 v1(44.83,37.04)
USB4_USB30_RX_CON_P: length 23.3
  TOP w0.102: USB3R4.6 43.84,38.12 43.94,38.01 45.41,38.01 47.74,40.34 47.74,48.98 46.29,50.43 46.29,51.67 46.15,51.8 ED3403.9 ED3403.2 46.15,53.82 46.3,53.96 46.3,54.73 46.03,55 46.03,55.43 45.77,55.69 EL3406.3
  BOTTOM w0.102: USB3R4.6 v1(44.83,39.04)
USB4_USB30_RX_N: length 188.9
  TOP w0.102: EL3406.2 46.43,59.06 46.81,59.45 49.93,59.45 ; v3(54.19,57.86) 54.39,58.07 54.39,58.57 54.19,58.77 52.83,58.77 52.16,59.45 49.93,59.45 ; 49.93,59.45 v1(49.93,59.09) ; v3(172.5,32.94) 172.83,32.61 CPU1.DC7
  L4 w0.114: v3(54.19,57.86) 54.39,57.65 54.39,51.62 57.44,48.56 57.44,31.05 59.29,29.2 59.29,24.81 60.7,23.4 61.21,23.4 65.83,18.79 66.66,18.79 69.15,16.31 71.48,16.31 73.2,18.02 81.38,18.02 81.97,17.43 89.89,17.43 90.35,17.89 93.93,17.89 94.77,18.73 102.26,18.73 103.17,17.81 106.2,17.81 106.84,18.46 113.21,18.46 114.61,17.06 118.69,17.06 119.31,17.68 124.13,17.68 125.57,19.12 135.38,19.12 135.96,18.54 137.88,18.54 138.73,17.69 143.69,17.69 144.44,18.44 148.6,18.44 149.03,18.86 155.17,18.86 160.82,24.51 164.68,24.51 165.36,25.19 177.05,25.19 177.55,25.7 177.55,29.08 175.39,31.24 175.39,32.37 173.61,34.15 172.8,34.15 172.5,33.85 v3(172.5,32.94)
USB4_USB30_RX_P: length 189.1
  TOP w0.102: EL3406.1 45.77,57.93 45.88,58.04 46.12,58.04 46.22,58.14 46.22,59.14 46.73,59.65 51.56,59.65 ; 51.56,59.65 52.24,59.65 52.92,58.98 54.27,58.98 54.6,58.65 54.6,58.15 v3(54.9,57.85) ; 51.56,59.65 v1(51.56,60.01) ; v3(173.21,32.94) 173.5,32.94 173.6,32.84 173.6,32.58 CPU1.DC9
  L4 w0.114: v3(173.21,32.94) 173.21,33.18 173.1,33.29 172.85,33.29 172.73,33.4 172.73,33.75 172.9,33.92 173.52,33.92 175.16,32.27 175.16,31.15 177.33,28.98 177.33,25.79 176.96,25.42 165.27,25.42 164.59,24.74 160.72,24.74 155.07,19.09 148.93,19.09 148.5,18.66 144.35,18.66 143.6,17.91 138.83,17.91 137.97,18.77 136.06,18.77 135.47,19.35 125.47,19.35 124.03,17.91 119.22,17.91 118.59,17.29 114.71,17.29 113.31,18.69 106.75,18.69 106.1,18.04 103.27,18.04 102.35,18.96 94.67,18.96 93.83,18.12 90.25,18.12 89.79,17.66 82.06,17.66 81.47,18.25 73.11,18.25 71.39,16.54 69.24,16.54 66.76,19.02 65.92,19.02 61.31,23.63 60.79,23.63 59.52,24.91 59.52,29.3 57.67,31.14 57.67,48.66 54.62,51.71 54.62,57.58 v3(54.9,57.85)
USB4_USB30_TX_CMC_N: length 7.2
  TOP w0.102: 44.51,60.48 v1(44.87,60.48) ; 44.51,60.48 44.51,58.61 44.14,58.24 44.14,57.61 44.24,57.51 EL3405.2 ; 44.51,60.48 44.51,61.09 45.21,61.8 45.71,61.8 45.85,61.65 45.85,61.27 46,61.12 C3415.2
USB4_USB30_TX_CMC_P: length 7.2
  TOP w0.102: 44.3,59.39 44.3,61.18 45.13,62 C3416.2 ; 44.3,59.39 v1(43.94,59.39) ; 44.3,59.39 44.3,58.7 43.93,58.33 43.93,57.92 43.84,57.83 43.69,57.83 43.59,57.73 EL3405.1
USB4_USB30_TX_CON_N: length 16.7
  TOP w0.102: USB3R4.8 43.84,43.56 44.1,43.83 45.31,43.83 46.02,44.55 46.02,48.8 44.97,49.85 44.97,51.66 45.11,51.8 ED3403.7 ED3403.4 45.11,53.79 44.97,53.93 44.97,54.41 44.75,54.63 44.5,54.63 44.04,55.09 44.04,55.48 44.24,55.67 EL3405.4
  BOTTOM w0.102: USB3R4.8 v1(44.83,43.04)
USB4_USB30_TX_CON_P: length 16.7
  TOP w0.102: EL3405.3 43.59,55.68 43.84,55.43 43.84,55 44.41,54.43 44.66,54.43 44.77,54.33 44.77,53.92 44.63,53.79 ED3403.5 ED3403.6 44.63,51.77 44.77,51.63 44.77,49.77 45.82,48.71 45.82,44.63 45.22,44.03 43.94,44.03 43.84,44.13 USB3R4.9
  BOTTOM w0.102: USB3R4.9 v1(44.83,45.04)
USB4_USB30_TX_N: length 171.1
  TOP w0.102: CPU1.DF2 169.84,30.64 164.89,30.64 163.83,29.59 163.83,26.36 v3(164.07,26.12) ; v1(49.75,60.54) 49.75,60.91 ; 49.75,60.91 48.79,60.91 48.4,61.3 47.78,61.3 47.61,61.12 C3415.1 ; 49.75,60.91 51.93,60.91 53.15,59.69 v3(54.25,59.69)
  L4 w0.114: v3(164.07,26.12) 163.79,25.83 163.79,25.59 163.54,25.34 160.73,25.34 154.9,19.51 148.76,19.51 148.4,19.15 144.17,19.15 143.35,18.34 142.33,18.34 141.46,19.21 136.46,19.21 135.19,20.48 125.96,20.48 125.22,19.74 123.76,19.74 122.38,18.36 114.54,18.36 113.76,19.13 106.57,19.13 106,18.56 103.34,18.56 102.53,19.38 95.38,19.38 94.84,19.92 94.39,19.92 93.07,18.61 89.94,18.61 89.4,18.08 82.24,18.08 81.64,18.67 72.82,18.67 71.68,17.54 68.95,17.54 67.02,19.46 66.07,19.46 61.89,23.65 61.89,24.84 59.97,26.76 59.97,29.54 58.16,31.35 58.16,48.85 55.57,51.44 55.57,59.56 55.2,59.93 54.49,59.93 v3(54.25,59.69)
USB4_USB30_TX_P: length 171
  TOP w0.102: v3(163.36,26.12) 163.63,26.39 163.63,29.67 164.8,30.85 169.4,30.85 CPU1.DF1 ; 51.17,61.11 48.87,61.11 48.48,61.5 47.88,61.5 47.78,61.6 47.78,61.87 47.64,62 C3416.1 ; 51.17,61.11 v1(51.17,61.47) ; 51.17,61.11 52.01,61.11 53.24,59.89 53.71,59.89 53.82,59.99 53.82,60.3 53.92,60.4 v3(54.25,60.4)
  L4 w0.114: v3(54.25,60.4) 54.49,60.16 55.29,60.16 55.8,59.66 55.8,51.53 58.39,48.95 58.39,31.45 60.2,29.64 60.2,26.85 62.12,24.93 62.12,23.74 66.17,19.69 67.12,19.69 69.04,17.77 71.59,17.77 72.72,18.9 81.74,18.9 82.33,18.31 89.31,18.31 89.84,18.84 92.98,18.84 94.29,20.15 94.93,20.15 95.48,19.61 102.62,19.61 103.43,18.79 105.91,18.79 106.48,19.36 113.85,19.36 114.63,18.58 122.28,18.58 123.66,19.97 125.12,19.97 125.87,20.71 135.28,20.71 136.56,19.44 141.55,19.44 142.42,18.57 143.26,18.57 144.07,19.38 148.31,19.38 148.66,19.74 154.81,19.74 160.64,25.57 163.44,25.57 163.56,25.68 163.56,25.93 v3(163.36,26.12)
USB_EN: length 11.9
  BOTTOM w0.102: Q3401.6 35.8,54.29 35.93,54.42 35.93,54.84 35.82,54.94 Q3401.5 34.49,54.94 34.39,55.05 34.39,56.11 35.22,56.93 R3401.2 35.22,59 v1(35.52,59.3) 35.82,59.6 C3401.1 36.67,59.55 36.67,57.8 37.19,57.28 Q3402.D
USB_EN_FRONT: length 236.3
  TOP w0.102: v3(39.96,60.6) 40.59,60.6 C3412.1 40.87,59.67 41.88,58.67 U3402.4 41.88,56.7 41.77,56.59 39.51,56.59 38.31,57.79 U3401.4 ; U3504.4 201.74,95.64 200.55,96.83 200.55,97.81 201.69,98.95 201.69,101.93 v3(202.2,102.44) ; v3(62.52,62.6) 62.65,62.74 62.65,69.2 62.35,69.5 62.35,71.71 62.33,71.72 62.33,72.84 62.94,73.44 62.94,75.33 64.41,76.79 71.31,76.79 72.14,77.63 75.98,77.63 76.43,78.08 U3503.4 76.43,79.59 75.97,80.05 v3(75.97,82.99)
  L3 w0.127: v3(75.97,82.99) 104.12,82.99 112.57,74.55 117.88,74.55 127.28,83.94 166.18,83.94 166.56,83.56 169.43,83.56 174.41,83.56 176.1,85.25 176.1,97.98 181.34,103.22 201.42,103.22 v3(202.2,102.44) ; v3(62.52,62.6) 62.52,61.45 61.93,60.87 60.86,60.87 60.12,61.62 54.05,61.62 53.18,60.75 41.94,60.75 41.79,60.6 v3(39.96,60.6)
  L4 w0.127: v3(39.96,60.6) 39.21,60.6 36.77,58.15 v3(34.75,58.15)
  BOTTOM w0.102: R3403.2 31.69,56.15 33,57.46 33,57.81 33.41,58.22 v1(33.49,58.22) 34.69,58.22 v3(34.75,58.15)
USB_EN_REAR: length 6.7
  TOP w0.102: R3402.2 30.65,58.46 30.23,58.03 v1(30.23,57.23) 31.05,56.41 R3404.1 31.05,55.67 v3(30.83,55.45)
  BOTTOM w0.102: v3(30.83,55.45) 31.39,54.89 R3403.1 32.4,55.59 Q3401.3
USB_ID: length 9.5
  TOP w0.102: R1604.1 164.8,26.92 165.89,25.83 v1(166.06,25.83) 166.54,25.83 166.89,26.17 167.62,26.17 168.17,26.72 170.19,26.72 170.49,27.02 170.49,27.31 170.65,27.47 171.57,27.47 171.8,27.7 171.8,28.19 CPU1.DL6
USB_OC#: length 41.6
  TOP w0.102: v3(189.88,36.34) 190.21,36.01 CPU1.CT43 ; v3(179.38,17.28) 178.76,17.89 177.21,17.89 175.66,19.44 175.66,21.54 175.99,21.87 176.31,21.87 176.64,22.2 176.64,23.1 176.37,23.37 176.37,23.98 176.38,23.98 176.38,24.03 CPU1.DW14
  BOTTOM w0.102: v3(179.38,17.28) v1(180.38,16.27) 181.18,15.47 182.91,15.47 R1606.1 184.76,16.2 185.47,16.91 185.47,17.78 185.73,18.04 186.56,18.04 187.75,19.24 187.75,19.57 189.24,21.05 189.24,22.55 189.54,22.85 189.54,24.32 189.23,24.63 189.23,27.12 189.48,27.37 189.48,31.49 189.38,31.58 189.38,31.92 188.89,32.41 188.89,32.84 188.86,32.87 188.86,33.74 189.43,34.3 189.43,34.66 189.66,34.9 190.02,34.9 190.09,34.97 190.09,35.03 190.33,35.27 190.33,35.89 v3(189.88,36.34)
USB_SIO_EUP: length 95
  TOP w0.102: R24070.1 81.28,4.81 v3(80.47,4.81)
  L3 w0.127: v3(59.05,11.53) 59.16,11.64 61.53,11.64 62.3,10.86 63.06,10.86 63.48,10.44 67.4,10.44 72.83,5.01 75.44,5.01 76,5.58 79.57,5.58 80.4,4.75 v3(80.47,4.81)
  L4 w0.127: v3(36.59,61.32) 37.96,61.32 38.13,61.49 40.26,61.49 40.95,60.81 40.95,53.78 44.82,49.91 44.82,49.89 44.87,49.84 44.87,46.8 45.32,46.35 45.32,31.06 47.35,29.03 47.99,29.03 51.87,25.15 51.87,21.22 53.2,19.89 53.2,17.25 58.84,11.62 58.96,11.62 v3(59.05,11.53)
  BOTTOM w0.102: R24038.1 79.34,5.54 79.6,5.28 80,5.28 v3(80.47,4.81) ; v3(36.59,61.32) 38.1,61.32 v1(38.62,60.81) 39.61,59.82 39.61,58.47 39.1,57.96 Q3402.G
USB_SIO_EUP_R: length 4.9
  TOP w0.102: ECIO1.10 79.6,7.57 79.71,7.45 79.71,7.41 80.01,7.11 80.86,7.11 v1(81.18,6.8) 81.29,6.69 R24070.2
USB_VBUSSENSE: length 6.3
  TOP w0.114: CPU1.DL11 175.19,28.84 v3(175.34,28.84)
  BOTTOM w0.114: v3(175.34,28.84) 175.51,28.84 175.79,28.57 175.79,26.42 R1602.1 176.07,25.97 177.02,26.92 v1(177.02,27.14)
V_5_LED: length 2.7
  TOP w0.381: G6401.2 118.75,14.61 118.77,14.6 v1(118.77,13.6) 118.77,13.41 118.3,12.94 Q6401.2
V_SMA_VREF_CA: length 120
  TOP w0.305: CPU1.C44 v4(191.05,71.82)
  L4 w0.508: v3(257.44,37.91) 257.03,37.91 256.53,38.42 256.53,48.84 257.2,49.51 257.2,61.19 256.5,61.9 256.5,65.55 257.5,66.55 257.5,70.95 257.5,71.62 257.04,72.08 257.04,72.97 256.85,73.16 256.85,77.24 253.35,80.73 237.71,80.73 234.16,84.28 v3(229.34,84.28)
  BOTTOM w0.508: v4(191.05,71.82) 191.88,72.65 191.88,73.23 v1(193.25,74.6) 193.84,75.2 199.22,75.2 201.01,73.41 206.73,73.41 215.97,82.65 227.71,82.65 v3(229.34,84.28) ; R1214.2 256.52,36.64 C1221.1 257.37,37.5 257.37,37.91 v3(257.44,37.91)
V_SMA_VREF_CA_C: length 2.2
  BOTTOM w0.508: R1215.1 255.72,37.76 v1(255.71,37.75) 255.7,37.74 255.7,36.71 C1221.2
V_SMB_VREF_CA: length 129.7
  TOP w0.254: CPU1.B45 191.16,72.38 v4(190.9,72.63)
  L4 w0.508: v3(254.55,39.18) 255.35,39.97 255.35,76.57 252,79.92 237.22,79.92 233.67,83.46 229.2,83.46 v3(228.21,84.46)
  BOTTOM w0.508: v3(228.21,84.46) 227.21,83.46 215.63,83.46 206.4,74.23 201.34,74.23 199.56,76.01 v1(194.7,76.01) 193.51,76.01 190.9,73.4 v4(190.9,72.63) ; C1328.1 242.55,33.34 R1305.2 242.55,36.77 244.84,39.06 251.53,39.06 252.26,39.79 253.94,39.79 v3(254.55,39.18)
V_SMB_VREF_CA_C: length 2.2
  BOTTOM w0.508: C1328.2 242.56,32.44 242.56,31.37 v1(242.56,31.36) 242.89,31.36 242.93,31.32 R1306.1
VCORE_EN: length 104.7
  TOP w0.102: R24041.1 75.56,4.42 74.89,3.76 v3(74.89,2.78) ; v3(122.5,41.42) 123.42,41.42 124,42 124.05,42 125.29,43.24 125.29,43.6 126.72,45.04 130.1,45.04 130.91,45.85 130.91,47 130.2,47.7 v3(130.2,47.79) 130.2,53.48 128.82,54.86 R4603.2
  L4 w0.127: v3(122.5,41.42) 122.5,41.42 122.04,40.96 116.97,40.96 116.66,41.28 113.66,41.28 113.51,41.43 110.62,41.43 v3(109.78,40.59)
  BOTTOM w0.102: R4037.1 130.88,47.11 v3(130.2,47.79) ; v3(109.78,40.59) 109.78,38.84 104.77,33.83 104.01,33.83 99.83,29.64 99.83,27.85 96.82,24.84 96.82,20.4 v1(96.1,19.68) 96.1,18.87 95.54,18.32 95.54,17.09 95.45,16.99 95.45,4.65 93.13,2.33 92.83,2.33 87.44,2.33 86.38,3.39 85.21,3.39 84.75,2.93 83.04,2.93 82.42,2.31 75.36,2.31 v3(74.89,2.78)
VCORE_EN_EC: length 4.2
  TOP w0.102: R24041.2 75.56,6.79 v1(75.61,6.85) 75.61,6.88 77.2,8.47 ECIO1.4
VCORE_PWRGD: length 52.5
  TOP w0.305: v3(126.61,56.96) 126.39,56.96 126.38,56.97 R4604.2 ; v3(136.43,44.6) 131.74,44.6 131.43,44.91 131.43,46.56 v3(131.68,46.8)
  BOTTOM w0.305: v3(136.43,44.6) 137.31,44.6 138.08,43.84 138.08,34.38 139.81,32.65 139.81,31.82 136.09,28.1 128.54,28.1 126.91,26.47 R4027.1 ; v3(126.61,56.96) 127.46,56.12 127.46,55.63 127.02,55.19 127.02,51.57 127.77,50.83 v1(128.65,50.83) 129.53,50.83 131.01,49.36 131.01,48.03 131.68,47.36 v3(131.68,46.8)
VRALERT#: length 6.8
  TOP w0.102: CPU1.CN38 187.27,38.04 187.27,38.1 v3(187.27,38.1)
  BOTTOM w0.102: R2201.1 184.13,35.03 184.35,35.25 185.2,35.25 185.41,35.46 185.41,35.46 185.51,35.56 185.51,35.56 185.75,35.8 186.09,35.8 186.32,35.56 186.32,35.56 186.43,35.46 v1(186.77,35.46) 187.08,35.77 187.08,36.97 187,37.05 187,37.83 v3(187.27,38.1)
VRD_TMPIN2: length 95.8
  TOP w0.102: v3(80.38,26.67) 80.38,26.34 80,25.96 ECIO1.86 ; RT2401.1 v3(132.34,57.59)
  L3 w0.127: v3(112.56,42.9) 112.56,41.48 111.45,40.37 110.42,40.37 109.79,39.74 109.79,35.18 109.51,34.91 108.89,34.91 108.47,35.33 94.98,35.33 93.99,36.32 90.95,36.32 89.22,38.05 83.7,38.05 82.3,36.65 78.98,36.65 78.67,36.34 78.67,36.34 v3(78.38,36.05)
  L4 w0.127: v3(80.38,26.67) 80.38,27.52 79.86,28.04 79.86,28.05 79.58,28.33 79.57,28.33 77.34,30.56 77.34,32.2 78.1,32.97 78.1,32.98 78.56,33.44 78.56,35.43 78.38,35.62 v3(78.38,36.05) ; v3(112.56,42.9) 112.56,48.32 114.06,49.81 114.06,52.44 114.06,52.45 114.06,54.42 114.06,54.42 114.06,54.47 116.71,57.12 122.79,57.12 124.69,55.22 127.68,55.22 128.2,55.74 130.82,55.74 132.34,57.27 v3(132.34,57.59)
  BOTTOM w0.102: v3(80.38,26.67) 80.45,26.6 80.45,25.61 80.18,25.34 79.47,25.34 C2404.1 79.46,25.88 79.31,26.04 78.68,26.04 78.45,25.81 v1(78.45,25.48) 78.45,24.51 R24046.1
VTT_CT_3D3V_S0: length 3.1
  BOTTOM w0.102: C4008.1 47.39,78.23 v1(47.39,79.31) 47.39,79.52 46.68,80.23 U4003.10
VTT_CT_5V_S0: length 3.8
  BOTTOM w0.102: C4007.1 45.82,78.61 v1(46.27,78.61) 46.33,78.67 46.33,79.23 45.82,79.74 45.82,80.22 45.88,80.27 U4003.12
W_DISABLE#2: length 51.5
  TOP w0.102: v3(131.68,13.31) 131.39,13.02 R6133.2 ; CPU1.DW12 v3(175.32,22.72)
  L4 w0.127: v3(175.32,22.72) 175.06,22.46 162.06,22.46 156.79,17.19 149.72,17.19 149.12,16.59 147.01,16.59 145.96,15.54 137.83,15.54 137.08,16.29 v3(135.18,16.29)
  BOTTOM w0.102: v3(131.68,13.31) v1(132.95,14.58) 134.66,16.29 v3(135.18,16.29)
W_DISABLE#2_CON: length 8.7
  TOP w0.102: NGFFE1.54 136,9 135.05,9.95 135.05,10.05 v1(134.83,10.27) 134.56,10.54 132.33,10.54 131.77,9.97 RN6119.2 131.39,9.98 R6133.1 R6134.1
WIFI_DISABLE_N: length 66.1
  TOP w0.102: ECIO1.58 91.04,20.98 v3(91.23,21.17) ; NGFFE1.56 136,8.5 134.78,9.71 134.6,9.71 134.13,10.18 132.62,10.18 131.76,9.32 RN6119.1 130.93,9.32 130.83,9.42 130.83,10.35 130.51,10.67 130.51,12.81 130.96,13.26 v3(130.96,13.32)
  L3 w0.127: v3(130.96,13.32) 126.4,13.32 126.13,13.6 125.58,13.6 125.09,13.11 114.99,13.11 112.78,10.9 109.76,10.9 106.09,14.57 101.55,14.57 99.64,12.65 98.21,12.65 98.04,12.82 93.93,12.82 v3(93.47,12.36)
  BOTTOM w0.102: R24049.1 90.48,21.17 v3(91.23,21.17) 91.69,21.63 92.13,21.63 92.4,21.36 92.4,20.1 92.1,19.79 92.1,18.08 92.67,17.51 v1(92.67,15.86) 92.67,13.16 v3(93.47,12.36)
WLAN_CLK_CPU_CON_N: length 49.5
  TOP w0.102: NGFFE1.49 143.7,10.25 143.55,10.4 142.23,10.4 142.13,10.3 142.13,9.85 142.23,9.75 143.12,9.75 143.34,9.53 143.34,9.08 143.12,8.86 142.23,8.86 142.13,8.76 142.13,8.02 141.91,7.8 141.34,7.8 141.12,8.02 141.12,10.3 141.01,10.4 140.61,10.4 140.51,10.3 140.51,4.92 140.29,4.69 139.71,4.69 139.49,4.92 139.49,5.07 139.39,5.17 138.47,5.17 138.25,5.39 138.25,5.84 138.47,6.06 139.39,6.06 139.49,6.16 139.49,6.44 139.39,6.54 138.47,6.54 138.25,6.76 138.25,7.21 138.47,7.43 139.39,7.43 139.49,7.53 139.49,8.17 139.39,8.27 138.41,8.27 138.19,8.49 138.19,8.94 138.41,9.16 139.39,9.16 139.49,9.26 139.49,9.54 139.39,9.64 138.41,9.64 138.19,9.86 138.19,10.31 138.41,10.53 139.39,10.53 139.49,10.63 139.49,11.17 138.96,11.7 138.96,13.69 139.62,14.36 139.62,14.84 139.52,14.94 137.74,14.94 137.52,15.16 137.52,15.73 137.74,15.95 139.8,15.95 139.9,16.06 139.9,16.46 139.8,16.56 138.61,16.56 138.39,16.78 138.39,17.36 138.61,17.58 139.52,17.58 139.62,17.68 139.62,18.49 139.38,18.73 v3(139.38,18.73)
  BOTTOM w0.102: v1(138.22,20.02) R6109.1 139.53,19.71 139.53,18.88 v3(139.38,18.73)
WLAN_CLK_CPU_CON_P: length 49.5
  TOP w0.102: v3(140.09,18.73) 140.09,18.73 139.83,18.47 139.83,17.6 139.61,17.38 138.69,17.38 138.59,17.27 138.59,16.87 138.69,16.77 139.88,16.77 140.1,16.55 140.1,15.97 139.88,15.75 137.82,15.75 137.72,15.65 137.72,15.24 137.82,15.14 139.61,15.14 139.83,14.92 139.83,14.27 139.16,13.61 139.16,11.79 139.69,11.26 139.69,10.55 139.47,10.33 138.49,10.33 138.39,10.23 138.39,9.95 138.49,9.85 139.47,9.85 139.69,9.63 139.69,9.18 139.47,8.96 138.49,8.96 138.39,8.86 138.39,8.58 138.49,8.47 139.47,8.47 139.69,8.25 139.69,7.45 139.47,7.23 138.56,7.23 138.45,7.13 138.45,6.85 138.56,6.75 139.47,6.75 139.69,6.53 139.69,6.08 139.47,5.86 138.56,5.86 138.45,5.76 138.45,5.48 138.56,5.37 139.47,5.37 139.69,5.15 139.69,5 139.79,4.9 140.2,4.9 140.3,5 140.3,10.38 140.52,10.6 141.1,10.6 141.32,10.38 141.32,8.11 141.42,8 141.83,8 141.93,8.11 141.93,8.84 142.15,9.06 143.04,9.06 143.14,9.16 143.14,9.44 143.04,9.55 142.15,9.55 141.93,9.77 141.93,10.38 142.15,10.6 143.55,10.6 143.7,10.75 NGFFE1.47
  BOTTOM w0.102: v3(140.09,18.73) 140.09,18.73 139.73,19.09 139.73,19.85 139.9,20.02 R6110.1 v1(141.23,20.02)
WLAN_CLK_CPU_N: length 54.7
  TOP w0.102: CPU1.CK3 170.07,38.94 169.87,38.74 169.39,38.74 169.07,39.06 167.4,39.06 167.38,39.04 165.41,39.04 165.15,38.77 160.45,38.77 156.78,35.11 156.78,32.52 156.98,32.32 157.39,32.32 v3(157.57,32.51)
  L3 w0.114: v3(157.57,32.51) 157.37,32.31 156.42,32.31 155.36,31.25 155.36,30.9 155.73,30.53 155.73,30.37 155.54,30.18 155.38,30.18 155.01,30.55 154.66,30.55 152.27,28.15 142.94,28.15 142.16,27.38 137.75,27.38 136.71,26.34 136.71,26.24 136.59,26.13 136.29,26.13 136.22,26.06 v3(136.22,25.67)
  BOTTOM w0.102: 137.84,22.5 137.84,22.04 138.11,21.77 139.53,21.77 139.74,21.57 139.74,21.24 139.4,20.91 R6109.2 ; 137.84,22.5 v1(137.48,22.5) ; 137.84,22.5 137.84,23.59 137.52,23.92 137.38,23.92 136.81,23.35 136.5,23.35 136.18,23.67 136.18,24 136.73,24.54 136.73,25.03 136.63,25.13 136.28,25.13 136.19,25.22 136.19,25.64 v3(136.22,25.67)
WLAN_CLK_CPU_P: length 54.9
  TOP w0.102: v3(157.57,31.8) 157.25,32.12 156.9,32.12 156.58,32.44 156.58,35.19 160.36,38.98 165.07,38.98 165.33,39.24 167.29,39.24 167.31,39.26 169.16,39.26 169.47,38.95 169.79,38.95 169.99,39.14 170.25,39.14 170.35,39.24 170.61,39.24 170.91,38.94 CPU1.CK4
  L3 w0.114: v3(157.57,31.8) 157.29,32.08 156.51,32.08 155.59,31.16 155.59,30.99 155.96,30.63 155.96,30.27 155.64,29.95 155.28,29.95 154.92,30.32 154.75,30.32 152.36,27.93 143.03,27.93 142.26,27.15 137.84,27.15 136.93,26.24 v3(136.93,25.65)
  BOTTOM w0.102: R6110.2 139.94,21.21 139.94,21.24 139.94,21.65 139.62,21.97 138.19,21.97 138.04,22.12 138.04,23.68 137.6,24.12 137.29,24.12 136.73,23.56 136.59,23.56 136.39,23.75 136.39,23.91 136.93,24.46 136.93,24.82 ; 136.93,24.82 v1(137.29,24.82) ; 136.93,24.82 v3(136.93,25.65)
WLAN_CLKREQ_CPU#: length 65.7
  TOP w0.102: CPU1.DP36 186.69,27.22 186.12,26.65 186.12,24.29 187.05,23.36 187.88,23.36 188.99,22.25 188.99,22.08 189.24,21.84 R1812.2 189.84,20.67 189.84,19.99 188.55,18.69 188.13,18.69 187.71,18.69 184.26,15.25 184.26,14.83 184.26,11.71 183.83,11.27 183.75,11.27 183.74,11.27 183.37,11.27 182.1,10 v3(182.1,9.79) ; v3(147.78,8.1) 148.46,7.42 151.94,7.42 152.32,7.8 153.48,7.8 158.71,7.8 159.44,8.53 v3(159.58,8.53)
  L3 w0.127: v3(159.58,8.53) 159.58,8.53 175.59,8.53 175.67,8.6 179.09,8.6 180.74,10.25 181.61,10.25 182.07,9.79 v3(182.1,9.79)
  BOTTOM w0.102: v3(147.78,8.1) 147.36,8.52 v1(147.36,12.45) 147.36,12.73 147.77,13.13 R6107.2
WLAN_PCIE_RX_N: length 70.5
  TOP w0.102: CPU1.CM7 172.83,37.78 v3(172.57,37.51) ; NGFFE1.43 143.21,11.75 142.64,11.18 140.45,11.18 139.64,11.99 139.64,13.4 141.48,15.24 141.48,15.47 141.38,15.57 140.83,15.57 140.61,15.79 140.61,16.16 140.83,16.38 142.25,16.38 142.35,16.49 142.35,16.69 142.25,16.79 141.7,16.79 141.48,17.01 141.48,22.05 139.54,23.99 138.83,23.99 138.41,24.4 v3(138.41,25.57)
  L3 w0.114: v3(138.41,25.57) 138.41,26.4 138.66,26.64 142.52,26.64 143.3,27.42 148.29,27.42 149.23,26.48 152.39,26.48 154.4,28.5 157.06,28.5 160.11,31.55 168.14,31.55 168.76,32.16 169.47,32.16 170,32.69 170,37.93 170.39,38.32 171.92,38.32 172.29,37.95 172.29,37.8 v3(172.57,37.51)
  BOTTOM w0.102: v1(171.74,38.63) 171.74,38.34 v3(172.57,37.51)
WLAN_PCIE_RX_P: length 70.8
  TOP w0.102: CPU1.CM6 172.18,37.73 v3(171.92,37.47) ; v3(139.12,25.57) 139.12,25.26 139.02,25.15 138.72,25.15 138.62,25.05 138.62,24.48 138.91,24.19 139.63,24.19 141.68,22.13 141.68,17.1 141.78,16.99 142.33,16.99 142.55,16.77 142.55,16.4 142.33,16.18 140.91,16.18 140.81,16.08 140.81,15.88 140.91,15.78 141.46,15.78 141.68,15.55 141.68,15.16 139.85,13.32 139.85,12.07 140.54,11.38 142.56,11.38 143.13,11.95 143.35,11.95 143.43,12.03 143.43,12.17 143.51,12.25 NGFFE1.41
  L3 w0.114: v3(139.12,25.57) 139.12,25.83 138.98,25.97 138.73,25.97 138.64,26.05 138.64,26.3 138.76,26.42 142.61,26.42 143.39,27.19 148.2,27.19 149.14,26.26 152.48,26.26 154.49,28.27 157.15,28.27 160.21,31.32 168.24,31.32 168.85,31.93 169.56,31.93 170.23,32.6 170.23,37.83 170.48,38.09 171.83,38.09 172.06,37.86 172.06,37.61 v3(171.92,37.47)
  BOTTOM w0.102: v3(171.92,37.47) 170.8,38.58 v1(170.47,38.58)
WLAN_PCIE_TX_N: length 8.7
  TOP w0.102: v3(141.81,12.31) 141.75,12.31 141.34,12.72 141.34,13.06 141.83,13.55 143.41,13.55 143.7,13.25 NGFFE1.37
  BOTTOM w0.102: 141.49,13.34 141.49,12.64 v3(141.81,12.31) ; 141.49,13.34 141.49,15.67 C6101.1 ; 141.49,13.34 v1(141.86,13.34)
WLAN_PCIE_TX_N_C: length 58.4
  TOP w0.102: CPU1.CY3 170.34,33.99 170.26,34.07 169.06,34.07 168.95,34.18 167.8,34.18 167.58,33.96 167.58,33.17 167.34,32.93 167.34,32.93 167.24,32.83 166.85,32.83 166.54,32.52 166.54,32.38 166.17,32 166.03,32 v3(166.03,32.01)
  L3 w0.114: v3(134.8,25.65) 134.89,25.74 134.89,25.96 134.78,26.08 134.52,26.08 134.41,26.19 134.41,26.4 134.9,26.89 136.53,26.89 137.51,27.87 141.88,27.87 142.66,28.66 152,28.66 157.14,33.79 158.57,33.79 160.4,31.97 163.67,31.97 164.26,32.56 166.18,32.56 166.31,32.44 166.31,32.14 166.18,32.01 v3(166.03,32.01)
  BOTTOM w0.102: 134.81,23.41 134.29,23.92 134.29,25.19 134.38,25.28 134.7,25.28 134.8,25.38 v3(134.8,25.65) ; 134.81,23.41 v1(135.07,23.67) ; 134.81,23.41 137.21,21 137.21,18.69 137.69,18.21 141.05,18.21 141.46,17.8 141.46,17.23 C6101.2
WLAN_PCIE_TX_P: length 8.7
  TOP w0.102: NGFFE1.35 141.74,13.75 141.14,13.15 141.14,12.35 v3(141.1,12.31)
  BOTTOM w0.102: v1(140.9,14.83) 141.29,14.83 ; 141.29,14.83 141.29,15.61 C6102.1 ; 141.29,14.83 141.29,12.5 v3(141.1,12.31)
WLAN_PCIE_TX_P_C: length 58.5
  TOP w0.102: v3(166.74,32) 166.74,32.44 166.93,32.63 167.32,32.63 167.42,32.73 167.43,32.73 167.79,33.08 167.79,33.88 167.89,33.98 168.86,33.98 168.98,33.87 170.17,33.87 170.35,33.69 170.61,33.69 170.91,33.99 CPU1.CY4
  L3 w0.114: v3(166.74,32) 166.54,32.21 166.54,32.53 166.28,32.79 164.17,32.79 163.57,32.2 160.49,32.2 158.67,34.02 157.04,34.02 151.91,28.89 142.57,28.89 141.78,28.1 137.42,28.1 136.43,27.12 134.8,27.12 134.09,26.41 v3(134.09,25.65)
  BOTTOM w0.102: 137,19.41 137,18.61 137.61,18.01 140.96,18.01 141.26,17.72 141.26,17.21 C6102.2 ; 137,19.41 137,20.92 134.09,23.83 v3(134.09,25.65) ; 137,19.41 v1(136.63,19.41)
XCLK_BIASREF: length 9.2
  TOP w0.203: CPU1.DU6 172.05,25.63 172.33,25.35 172.33,24.28 172.08,24.03 171.69,24.03 171.45,23.79
  TOP w0.508: 171.45,23.79 170.76,23.11 167.3,23.11 167.22,23.03 v1(166.53,23.03) 165.31,23.03 R1819.1
XDP_PRDY#: length 1.6
  TOP w0.102: v3(172.57,66.94) 172.22,66.6 CPU1.P6
  BOTTOM w0.102: v3(172.57,66.94) 172.57,66.51 TP9902.1
XDP_PREQ#: length 1.6
  TOP w0.102: v3(172.5,67.6) 172.15,67.25 CPU1.M6
  BOTTOM w0.102: v3(172.5,67.6) 172.17,67.93 171.64,67.93 TP9901.1
XRF_TDC1: length 24.4
  TOP w0.61: 71.28,62.02 70.83,61.57 68.74,61.57 68.28,62.02 ; 71.28,62.02 71.73,61.57 73.86,61.57 74.28,61.99 XF3101.15 ; 71.28,62.02 XF3101.18 C3151.1 ; 68.28,62.02 67.83,61.57 65.73,61.57 65.28,62.02 XF3101.24 65.28,65.56 64.84,66.01 C3152.1 64.84,67.53 v1(64.89,67.58) ; 68.28,62.02 XF3101.21
XTL_32K_X1_CPU: length 11.9
  TOP w0.114: CPU1.DL48 192.59,28.68 192.81,28.91 193.39,28.91 193.43,28.87 194.84,28.87 v3(195.01,28.7)
  BOTTOM w0.114: v1(196.59,26.69) 196.59,26.69 ; 196.59,26.69 196.59,27.53 195.43,28.7 v3(195.01,28.7) ; 196.59,26.69 196.59,24.95 195.81,24.17 R1811.1 195.81,23.02 C1802.1 195.84,21.86 X1801.1
XTL_32K_X2_CPU: length 10.7
  TOP w0.114: v3(194.86,28.03) 194.86,28.25 194.47,28.65 193.26,28.65 CPU1.DL49
  BOTTOM w0.114: v3(194.86,28.03) 195.29,28.03 v1(195.72,27.61) 195.96,27.36 195.96,25.03 195.73,24.8 195.72,24.8 194.94,24.01 R1811.2 194.57,23.65 194.57,23.22 C1801.1 194.8,21.71 X1801.2
XTL_38D4M_X1_CPU: length 6.5
  TOP w0.114: CPU1.DW8 173.33,24.42 173.33,23.39 172.64,22.7 172.64,22.33 172.75,22.22 v1(173.45,22.22) 173.81,22.22 173.98,22.05 173.98,20.67 173.89,20.58 173.67,20.58 173.1,21.15 ER1801.1
XTL_38D4M_X1_CPU_R: length 4.1
  TOP w0.114: X1802.3 173.7,16.69 173.11,17.28 173.11,18.14 C1805.1 172.92,18.32 R1820.1 172.92,20.2 ER1801.2
XTL_38D4M_X2_CPU: length 5.4
  TOP w0.114: CPU1.DU8 173,25.38 173,24.35 173.1,24.25 173.1,23.62 172.86,23.38 172.59,23.38 171.95,22.73 v1(171.95,22.31) ER1802.1
XTL_38D4M_X2_CPU_R: length 6.3
  TOP w0.114: ER1802.2 172.04,20.18 R1820.2 172.04,18.34 C1806.1 172.51,17.66 172.51,15.29 172.39,15.17 X1802.1

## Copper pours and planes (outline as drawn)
1V_CPU_CORE on TOP: 185.88,45.44 186.74,45.44 186.83,45.35 186.83,44.57 186.83,42.54 186.73,42.44 186.73,41.4 186.45,41.12 186.45,38.65 186.43,38.64 186.43,37.91 186.45,37.89 186.45,37.71 186.25,37.51 186.25,37.18 186.45,36.98 186.45,35.77 186.38,35.7 185.73,35.7 185.28,35.25 184.29,35.25 183.95,35.6 183.95,42.56 183.95,42.56 183.95,42.85 184.08,42.99 185.32,42.99 185.79,43.45 185.79,45.35
1V_CPU_CORE on TOP: 173.88,47.74 174.9,47.74 175.27,47.38 175.27,39.32 175.05,39.1 173.92,39.1 173.77,39.26 173.77,42.05 173.29,42.53 173.29,46.22 173.46,46.38 173.49,46.38 173.49,46.91 173.33,47.07 173.33,47.19
1V_CPU_CORE on TOP: 155.38,79.68 183.13,79.68 183.7,79.1 183.7,73.49 183.71,73.48 183.71,69.11 183.86,68.96 184.56,68.96 184.68,68.83 184.68,68.34 184.68,68.34 184.68,63.33 184.68,63.33 184.68,61.99 184.61,61.91 175.24,61.91 175.08,62.06 175.08,64.2 175.76,64.87 176.51,64.87 176.76,65.13 176.76,67.18 176.58,67.36 176.58,67.82 177.84,69.08 177.84,73.87 177.6,74.11 169.38,74.11 167.63,75.86 158.48,75.86 156.62,74 156.62,64.78 155.08,63.24 155.08,62.9 154.73,62.55 152.21,62.55 152.06,62.4 152.06,61.46 151.95,61.35 148.67,61.35 148.56,61.45 148.56,76.99 148.84,77.27 151.03,77.27 151.94,78.18 154.54,78.18 155.17,78.81 155.17,78.96 155.18,78.97 155.18,79.48 ; 4 cut-outs
1V_CPU_CORE on BOTTOM: outline of 96 points within 148.39,36.19 187.46,79.91 ; 63 cut-outs
1V_CPU_CORE on L3: 156.24,77.68 156.24,66.82 156.56,66.5 156.56,64.68 154.61,62.74 152.43,62.74 152.26,62.91 152.26,77.49 152.74,77.97 155.95,77.97
1V_CPU_CORE on L3: 183.98,76.24 170.24,76.24 167.75,73.74 167.75,52.78 169.79,50.73 169.79,48.85 171.63,47.02 175.6,47.02 177.46,45.16 177.46,36.08 177.69,35.85 186.01,35.85 186.22,36.05 186.22,36.38 184.96,37.64 184.96,41.26 186.45,42.75 186.45,44.83 185.69,45.6 185.69,61.42 184.22,62.89 184.22,62.91 183.89,63.24 182.59,63.24 182.25,63.58 182.25,64.48 182.62,64.86 183.36,64.86 183.55,65.05 183.55,68.38 183.5,68.43 183.5,70.26 184.22,70.97 184.22,76
1V_CPU_CORE on L4: 184.57,66.91 184.57,73.3 182.14,75.73 182.14,79.9 181.9,80.13 151.53,80.13 150.19,78.79 150.19,60.6 150.27,60.51 152.27,60.51 152.79,61.03 152.79,62.11 153.17,62.49 154.93,62.49 155.09,62.66 155.09,63.08 155.67,63.65 157.9,63.65 158.3,63.25 158.3,59.49 158.54,59.24 174.74,59.24 175.3,59.79 175.3,62.53 177.25,64.48 177.25,68.67 176.73,69.19 176.73,70.36 176.91,70.55 178.39,70.55 178.59,70.35 178.59,66.93 178.88,66.65 184.31,66.65
5V_AUDIO_S0 on TOP: 35.98,67.68 39.74,67.68 39.83,67.58 39.83,67.12 39.65,66.94 38.48,66.94 38.16,66.61 38.16,65.91 37.94,65.68 36.77,65.68 36.57,65.89 33.83,65.89 32.76,66.96 32.76,67.36 32.96,67.56 33.55,67.56 33.72,67.39 35.69,67.39 ; 4 cut-outs
5V_AUDIO_S0 on BOTTOM: 30.4,67.23 34.36,67.23 34.95,66.64 34.95,64.82 34.91,64.79 34.78,64.79 34.78,64.79 29.41,64.79 29.35,64.86 29.37,64.88 29.37,65.36 29.41,65.4 29.78,65.4 30.03,65.65 30.03,66.86 ; 10 cut-outs
5V_AUDIO_S0_S on TOP: 42.35,66.39 43.22,66.39 43.32,66.3 43.32,64.22 43.18,64.08 38.08,64.08 37.23,63.24 36.87,63.24 36.68,63.43 36.68,65.25 36.82,65.39 38.17,65.39 38.34,65.22 39.75,65.22 39.75,65.23 39.92,65.39 41.36,65.39 ; 4 cut-outs
5V_HDD on TOP: 6.36,80.94 12.11,80.94 12.29,80.76 12.65,80.76 12.66,80.76 13.7,80.76 13.82,80.64 13.82,77.24 13.26,76.67 13.26,75.68 12.85,75.27 11.09,75.27 8.98,73.16 8.98,69.9 7.76,68.68 3.51,68.68 3.17,69.01 3.17,71.93 3.61,72.36 5.61,72.36 5.87,72.62 5.87,80.44 ; 2 cut-outs
5V_HDMI on TOP: 58.65,55.96 59.99,55.96 60.17,55.78 60.17,54.06 60.36,53.87 60.36,52.55 60.24,52.43 58.65,52.43 58.45,52.63 58.45,53.57 58.3,53.71 57.73,53.71 57.52,53.92 57.52,55.44 57.78,55.7 58.39,55.7
5V_HDMI_CONN on TOP: 56.04,54.41 56.63,54.41 57.58,53.46 57.61,53.49 58.27,53.49 58.37,53.39 58.37,52 58.46,51.91 62.09,51.91 62.21,51.78 62.21,50.63 62.15,50.57 60.4,50.57 60.11,50.28 60.11,45.79 59.5,45.18 56.35,45.18 56.33,45.2 56.33,45.48 56.35,45.5 58.05,45.5 58.06,45.5 58.46,45.5 58.58,45.62 58.58,46.42 58.39,46.6 58.39,50.47 55.92,52.94 55.92,54.3 ; 2 cut-outs
5V_PANEL_VCC on TOP: 30.85,17.22 32.13,17.22 32.26,17.09 32.26,12.47 32.71,12.01 35.13,12.01 35.15,12 35.64,12 35.88,11.77 35.88,10.54 35.63,10.29 31.58,10.29 29.81,12.06 29.81,14.88 30.69,15.76 30.69,17.06 ; 2 cut-outs
5V_PANEL_VCC on BOTTOM: 67.39,17.58 69.11,17.58 69.33,17.36 69.33,13.57 68.6,12.84 67.16,12.84 67.03,12.98 67.03,14.17 67.31,14.44 67.31,17.5 ; 4 cut-outs
5V_PANEL_VCC on L3: 33.28,10.28 33.08,10.48 33.08,11.79 33.26,11.98 53.18,11.98 55.55,14.34 66.33,14.34 66.34,14.35 67.1,14.35 67.59,14.84 69.7,14.84 69.83,14.71 69.83,13.95 69.83,13.94 69.83,13.23 69.68,13.08 56.96,13.08 54.16,10.28
5V_S0 on TOP: 44.26,71.95 45.11,71.95 48.52,68.55 48.52,64.94 49.14,64.31 56.61,64.31 57.88,63.04 59.2,63.04 61.2,61.04 62.74,61.04 63.06,60.72 63.06,55.99 62.87,55.79 61.75,55.79 61.62,55.67 61.62,54.2 61.52,54.1 60.63,54.1 60.53,54.2 60.53,55.96 60.2,56.29 60.19,56.29 59.07,57.4 59.07,59.47 57.72,60.82 55.71,60.82 54.88,61.65 52.49,61.65 52.07,62.08 48.08,62.08 46.66,63.49 46.66,63.49 46.16,64 44.14,64 43.81,64.32 43.81,66.32 44.07,66.58 45.56,66.58 45.92,66.95 45.92,67.78 45.49,68.21 44.27,68.21 44.05,68.43 44.05,71.74 ; 6 cut-outs
5V_S0 on TOP: 12.35,81.99 14.16,81.99 14.22,81.94 15.64,81.94 15.66,81.91 15.66,79.21 15.43,78.98 14,78.98 14,80.84 13.86,80.99 12.39,80.99 12.27,81.1 12.27,81.15 12.28,81.15 12.28,81.36 12.27,81.37 12.27,81.91 ; 2 cut-outs
5V_S0 on BOTTOM: 21.88,83.71 35.38,83.71 38.47,80.62 41.48,80.62 42.16,81.31 45.47,81.31 45.57,81.2 45.57,80.45 45.51,80.39 45.3,80.39 44.79,79.88 44.79,77.65 45.05,77.39 45.05,70.1 44.91,69.95 42.79,69.95 42.4,70.35 42.4,75.75 39.99,78.16 37.22,78.16 33.91,81.48 23.79,81.48 22.7,80.4 16.48,80.4 15.38,79.3 12.47,79.3 12.25,79.51 12.25,81.88 12.38,82 13.01,82 13.01,82 15.09,82 16.3,83.2 21.37,83.2 ; 6 cut-outs
5V_S0 on BOTTOM: 256.09,8.48 256.92,8.48 256.99,8.41 256.99,7.17 256.88,7.05 255.72,7.05 255.58,6.91 255.58,5.97 255.67,5.88 257.94,5.88 258.13,6.07 258.13,7 258.19,7.07 258.67,7.07 258.73,7.01 258.73,5.47 258.1,4.84 255.84,4.84 254.9,3.91 254.23,3.91 253.92,4.22 253.92,7.35 254.83,8.26 255.87,8.26 ; 2 cut-outs
5V_S5 on TOP: 78.04,79.55 80.32,79.55 80.6,79.27 80.6,76.64 78.68,74.72 78.68,67.33 79.79,66.22 79.79,65.12 81.41,63.5 81.41,60.54 82.29,59.67 87.24,59.67 87.61,60.03 91.3,60.03 91.31,60.03 91.6,60.32 97.11,60.32 97.27,60.15 97.27,58.24 97.07,58.04 96.29,58.04 95.23,59.1 92.08,59.1 91.64,58.65 91.64,57.41 91.19,56.95 79.31,56.95 78.79,57.47 78.79,62.48 78.69,62.58 77.77,62.58 77.15,62.58 76.91,62.82 76.91,65.21 76.32,65.8 76.32,76.56 77.94,78.18 77.94,79.44 ; 9 cut-outs
5V_S5 on TOP: 38,63.84 41.87,63.84 42.15,63.57 43.27,63.57 43.36,63.48 43.36,62.88 43.36,62.77 43.08,62.49 43.08,61.77 42.95,61.65 40.08,61.65 39.76,61.33 39.76,60.48 40.45,59.79 40.45,56.97 40.28,56.79 39.58,56.79 39.47,56.9 39.47,58.82 38.86,59.43 38.86,59.64 38.78,59.72 37.87,59.72 37.81,59.66 37.81,57.57 37.69,57.45 34.25,57.45 33.46,56.66 33.15,56.66 32.55,57.25 31.82,57.25 31.37,57.7 31.35,57.7 31.28,57.77 31.28,59.66 31.9,60.28 35.99,60.28 36.9,61.19 36.9,61.62 36.62,61.89 36.62,62.46 ; 6 cut-outs
5V_S5 on TOP: 99.41,48.39 106.2,48.39 109.02,45.57 109.02,45.55 109.61,44.97 109.61,40.82 109.62,40.8 109.62,37.8 109.38,37.56 109.38,37.56 107.68,37.56 107.59,37.65 107.59,43.69 104.71,46.57 99.35,46.57 98.93,47 98.93,47.91
5V_S5 on TOP: 201.09,97.94 202.4,97.94 202.49,97.85 205.32,97.85 205.93,97.24 205.93,92.95 205.69,92.72 202.5,92.72 201.87,93.34 201.87,94.71 202.02,94.85 202.66,94.85 202.74,94.92 202.74,95.81 202.31,96.24 201.15,96.24 200.9,96.48 200.9,97.75 ; 2 cut-outs
5V_S5 on BOTTOM: 90.22,59.99 92.94,59.99 93.07,59.87 93.07,54.28 92.94,54.15 91.89,54.15 91.44,54.6 89.91,56.13 89.91,59.68
5V_S5 on BOTTOM: 179.68,102.67 185.03,102.67 187.15,100.56 187.15,97.56 186.69,97.1 184.29,97.1 183.89,97.51 183.89,98.74 183.56,99.07 181.14,99.07 178.3,96.23 178.3,84.77 175.28,81.75 161.57,81.75 161.19,82.13 161.19,83.39 161.51,83.71 163.99,83.71 164.03,83.75 174.39,83.75 175.65,85.01 175.65,98.64
5V_S5 on BOTTOM: 69.16,28.09 71.57,28.09 71.88,27.79 71.88,26.99 71.88,26.98 71.88,23.55 70.88,22.55 70.88,21.11 69.24,19.47 69.24,19.13 69.27,19.11 69.27,18.15 67.28,18.15 67.09,18.35 67.09,21.09 68.66,22.66 68.66,24.35 68.88,24.56 68.88,27.81 ; 4 cut-outs
5V_S5 on BOTTOM: 40.92,85.98 46.29,85.98 46.41,85.86 46.41,82.74 46.36,82.69 46.18,82.69 46.16,82.72 46.16,84.29 46,84.44 45.58,84.44 45.39,84.24 45.39,83.83 45.59,83.62 45.59,82.73 45.57,82.7 44.55,82.7 44.13,83.12 44.12,83.11 40.92,83.11 40.72,83.31 40.72,85.78 ; 3 cut-outs
5V_S5 on BOTTOM: 75.48,43.95 77.05,43.95 77.24,43.77 77.24,43.3 75.55,41.61 74.94,41.61 74.84,41.72 74.84,43.31 ; 2 cut-outs
5V_S5 on BOTTOM: 260.02,33.24 262.2,33.24 262.32,33.12 262.32,32.41 262.1,32.2 260.61,32.2 260.06,31.65 260.06,31.64 259.76,31.34 259.76,29.73 259.7,29.67 259.12,29.67 259.05,29.74 259.05,30.61 259.07,30.63 259.07,32.26 259.06,32.27
5V_S5 on L3: 195.52,93.16 191.44,97.23 184.44,97.23 183.98,97.69 183.98,99.81 184.38,100.21 199.27,100.21 200.3,99.18 203.42,99.18 205.1,97.5 205.1,93.47 204.79,93.16
5V_S5 on L3: 39.34,85.55 39.34,78.46 40.87,76.94 40.87,63.98 40.46,63.58 40.46,61.93 40.83,61.56 59.31,61.56 63.1,65.35 76.32,65.35 76.34,65.34 77.2,65.34 78.79,63.75 78.79,56.77 81.42,54.14 81.42,48.86 74.85,42.29 74.85,39.89 75.01,39.73 78.35,39.73 84.7,46.08 84.7,50.46 91.72,57.48 91.72,59.67 91.49,59.9 89.76,59.9 86.27,63.39 83.21,63.39 82.71,63.89 82.71,68.39 82.25,68.84 82.25,70.18 81.49,70.95 78.75,70.95 78.31,70.51 60.16,70.51 57.57,67.92 49.41,67.92 49.39,67.9 47.67,67.9 46.35,69.22 46.35,76.66 43.64,79.38 43.64,85.47 43.26,85.85 39.65,85.85
5V_S5 on L3: 253.73,3.4 254.12,3.01 254.76,3.01 259.33,7.58 259.33,9.71 260.3,10.68 260.3,26.43 261.14,27.27 261.14,32.26 260.93,32.48 260.93,33.12 261.1,33.29 261.1,81.68 256.88,85.9 256.88,91.48 257.19,91.79 258.93,91.79 258.93,91.79 259.06,91.79 259.3,91.55 259.3,87.04 262.63,83.71 262.63,16.17 261.86,15.4 261.86,15.38 261.85,15.37 261.85,8.5 261.15,7.8 261.15,7.11 255.99,1.94 249.66,1.94 249.16,2.44 249.16,3.13 249.17,3.13 249.44,3.4
5V_S5 on L4: 161.46,82.99 163.84,82.99 164.05,82.79 164.05,81.27 163.79,81.02 132.84,81.02 132.31,81.54 127.98,81.54 119.18,72.73 117.09,72.73 115.26,70.91 112.37,70.91 110.03,73.25 109.57,73.25 105.53,77.29 105.53,78.17 104.27,79.43 94.88,79.43 93.62,80.69 91.56,80.69 90.65,79.78 85.12,79.78 83.03,77.69 79.85,77.69 79.75,77.79 79.75,79.44 80.15,79.84 82.3,79.84 85.2,82.74 94.61,82.74 96.07,81.27 97.57,81.27 98.6,82.3 104.86,82.3 112.41,74.75 117.79,74.75 126.22,83.18 161.27,83.18
5V_S5 on L4: 224.87,96.72 224.89,96.69 225.73,96.69 225.96,96.92 225.96,99.69 226.37,100.1 229.14,100.1 230.18,101.15 242.66,101.15 250.81,93 258.63,93 259.08,92.55 259.08,89.85 258.89,89.66 256.61,89.66 256.34,89.94 256.34,90.51 255.96,90.89 247.47,90.89 241.27,97.09 231.45,97.09 227.96,93.59 227.89,93.65 216.14,93.65 213.5,91.01 202.3,91.01 202.07,91.25 202.07,96.33 202.9,97.17 223.18,97.17 223.63,96.72
5V_S5 on L4: 97.96,52.88 100.24,50.6 100.24,47.37 100.04,47.18 98.86,47.18 97.99,48.04 97.99,49.64 96.69,50.94 96.69,57.33 95.65,58.36 95.65,59.25 96.47,60.06 97.24,60.06 97.96,59.34
5V_S5 on L4: 69.59,29.9 69.59,28.48 69.95,28.12 69.95,26.31 70.27,25.99 71.46,25.99 71.77,26.31 71.77,29.68 71.45,30 71.45,30.88 76.05,35.48 76.05,38.06 76.09,38.1 76.09,38.67 77.3,39.88 77.3,44.47 76.93,44.84 74.38,44.84 73.31,43.78 73.31,39.1 69.57,35.36 69.57,29.92
5V_USB30E on TOP: 192.2,100.32 198.2,100.32 198.22,100.3 198.75,100.3 198.91,100.15 199.99,100.15 200.08,100.06 200.08,97.87 200.26,97.69 200.26,96.98 200.18,96.9 198.54,96.9 198.36,96.72 198.36,95.13 196.4,93.17 194.5,93.17 193.78,93.89 193.78,93.89 193.26,94.42 191.54,94.42 191.29,94.67 191.29,99.41 ; 4 cut-outs
5V_USB30E on BOTTOM: 199.23,98.29 200.94,98.29 201.98,97.25 201.98,95.2 201.75,94.97 197.7,94.97 197.2,95.48 197.2,98.17 197.3,98.27 199.2,98.27 ; 4 cut-outs
5V_USB30F on TOP: 62.12,100.85 67.33,100.85 68.51,99.67 68.51,97.7 69.13,97.07 70.04,97.07 70.57,96.55 70.57,88.63 70.46,88.52 69.05,88.52 68.93,88.64 68.93,91.08 69.2,91.35 69.2,91.92 68.79,92.33 68.57,92.33 67.15,93.75 66.52,94.38 61.94,94.38 61.8,94.52 61.8,95.77 60.95,96.62 60.95,99.68 ; 5 cut-outs
5V_USB30F on TOP: 78.36,84.03 82.56,84.03 82.77,83.81 82.77,80.83 82.12,80.17 78.11,80.17 77.97,80.31 77.97,83.64
5V_USB30F on BOTTOM: 68.61,95.5 72.96,95.5 73.5,94.97 73.5,85.33 75.32,83.51 82.31,83.51 82.5,83.31 82.5,81.37 82.38,81.25 74.84,81.25 71.82,84.27 71.82,92.32 70.94,93.2 68.65,93.2 68.47,93.38 68.47,95.39 68.5,95.39
5V_USB30H on TOP: 39.24,56.23 40.19,56.23 40.29,56.13 40.29,54.6 40.82,54.07 41.01,54.07 41.12,53.96 41.12,50.27 40.06,49.21 40.06,46.4 40.48,45.98 42.74,45.98 43.08,45.64 43.08,43.85 42.66,43.43 38,43.43 37.52,43.91 37.52,52.43 37.92,52.83 38.82,52.83 38.99,52.99 38.99,55.98 ; 8 cut-outs
5V_USB30H on BOTTOM: 36.87,52.29 39.72,52.29 39.88,52.13 39.88,51.37 39.76,51.26 36.9,51.26 36.72,51.44 36.72,52.14
5V_USB30H on L3: 37.14,52.41 37.14,43.44 37.62,42.96 42.74,42.96 43.11,43.33 43.11,45.6 42.71,46 40.99,46 40.98,45.98 40.75,45.98 39.96,46.77 39.96,52.19 39.43,52.72 37.46,52.72
5V_USB30H on L4: 37.29,52.54 37.29,43.6 37.65,43.25 43.03,43.25 43.11,43.33 43.11,45.54 42.81,45.83 40.4,45.83 39.88,46.35 39.88,52.43 39.61,52.7 37.46,52.7
5V_USB30R on TOP: 35.17,57.28 36.71,57.28 36.78,57.22 36.78,54.32 37.27,53.83 37.27,43.35 37.06,43.14 34.92,43.14 34.62,43.45 34.62,49.78 34.88,50.05 34.88,51.96 34.77,52.08 34.52,52.08 34.29,52.3 34.29,56.94 34.63,57.28 35.17,57.28 ; 7 cut-outs
5V_USB30R on BOTTOM: 36.12,54.07 37.6,54.07 37.72,53.95 37.72,53.43 36.54,52.25 35.97,52.25 35.84,52.38 35.84,53.79
5V_USB30R on L3: 29.51,44.4 29.51,43.2 30.11,42.6 31.42,42.6 32.2,41.82 36.47,41.82 37.05,42.4 37.05,53.95 36.82,54.18 35.32,54.18 34.86,53.72 34.86,50.26 34.29,49.69 29.05,49.69 28.48,49.12 28.48,45.43
5V_USB30R on L4: 29.68,46.57 33.18,46.57 34.14,47.52 34.14,53.45 35.53,54.85 36.67,54.85 36.9,54.62 36.9,43.04 36.49,42.64 29.68,42.64 29.22,43.1 29.22,46.11
19V_AD_JK on TOP: 81.13,55.56 86.6,55.56 87.31,54.85 89.31,54.85 93.4,50.76 93.4,47.1 93.09,46.8 91.52,46.8 89.95,45.23 89.95,41.29 91.27,39.97 91.27,39.95 91.42,39.79 91.42,35.69 91.1,35.37 85.32,35.37 84.66,36.02 84.66,46.9 85.19,47.43 87.72,47.43 88.03,47.74 88.03,51.28 87.73,51.58 83.52,51.58 82.45,52.65 81.1,52.65 80.97,52.78 80.97,55.4 ; 6 cut-outs
19V_AD_JK on BOTTOM: 81.12,59.41 88.43,59.41 88.54,59.3 88.54,55.23 88.01,54.7 81.15,54.7 80.89,54.96 80.89,59.17
19V_ADP on TOP: 84.99,51.36 87.76,51.36 87.84,51.28 87.84,47.88 87.71,47.75 85,47.75 84.83,47.93 84.83,51.2
19V_ADP on BOTTOM: 85.15,54.46 89.62,54.46 89.74,54.33 89.74,52.31 89.75,52.31 89.75,51.95 90.28,51.42 91.36,51.42 91.65,51.71 93.25,51.71 93.48,51.48 93.48,51.14 90.49,48.15 85.18,48.15 84.82,48.52 84.82,54.13 ; 7 cut-outs
19V_BOOST_ISW_R on TOP: 12.22,22.23 18.34,22.23 18.64,21.92 18.64,20.24 18.34,19.94 16.41,19.94 15.8,19.33 15.8,17.27 15.49,16.97 12.65,16.97 12.34,17.27 12.34,20.6 12.15,20.79 12.15,22.16
19V_BOOST_LX on TOP: 16.59,19.46 19.58,19.46 20.12,18.92 20.12,12.5 19.66,12.04 16.4,12.04 15.69,11.33 10.29,11.33 10.13,11.48 10.13,14.1 10.46,14.43 15.77,14.43 16.31,14.96 16.31,19.18
19V_BOOST_LX on BOTTOM: 10.67,16.97 12.62,16.97 12.88,16.71 12.88,11.43 12.78,11.33 10.6,11.33 9.98,11.94 9.98,14.71 10.48,15.21 10.48,16.78
19V_DCBATOUT on TOP: 80.55,51.46 84.24,51.46 84.5,51.21 84.5,39.09 84.23,38.82 80.42,38.82 80.33,38.91 80.33,51.24
19V_DCBATOUT on TOP: 136.48,44.08 138,44.08 138.93,43.16 138.93,42.69 137.07,42.69 136.35,43.41 136.35,43.95
19V_DCBATOUT on TOP: 208.96,103.87 231.49,103.87 231.53,103.83 231.85,103.83 231.98,103.7 231.98,96.68 228.34,93.03 228.34,86.19 228.28,86.13 225.47,86.13 225.37,86.23 225.37,92.11 225.85,92.8 230.06,97.01 230.06,97.5 230.52,97.96 230.55,97.96 230.55,101.33 230.04,101.83 223.72,101.83 223.05,102.51 213.2,102.51 213,102.71 211.39,102.71 210.63,101.94 204.83,101.94 204.66,102.11 201.56,102.11 200.98,101.52 200.15,101.52 199.93,101.3 199.28,101.3 198.82,101.76 198.82,101.76 197.09,101.76 196.75,102.11 183.07,102.11 178.06,97.1 178.06,87.06 177.86,86.86 177.86,83.39 175.36,80.89 148.89,80.89 148.87,80.91 129.75,80.91 129.19,80.35 129.19,79.19 129.33,79.04 131.34,79.04 131.42,78.97 131.42,62.82 131.29,62.69 131.29,58.79 131.42,58.66 131.42,58.26 131.25,58.08 127.11,58.08 125.65,59.54 125.65,59.59 123.52,61.72 117.95,61.72 117.92,61.75 117.92,71.42 117.74,71.6 116.65,71.6 116.58,71.67 116.58,74.11 118.17,75.69 118.19,75.69 120.55,78.05 120.59,78.05 126.39,83.85 126.39,83.9 174,83.9 175.5,85.4 175.5,101.85 177.51,103.87 208.96,103.87 ; 2 cut-outs
19V_DCBATOUT on BOTTOM: outline of 119 points within 22.27,17.96 120.89,72.99 ; 19 cut-outs
19V_DCBATOUT on BOTTOM: 225.63,88.44 227.44,88.44 227.77,88.12 227.77,85.68 227.74,85.65 225.65,85.65 225.43,85.88 225.43,88.24
19V_DCBATOUT on BOTTOM: 205.31,103.86 224.63,103.86 224.71,103.78 224.71,103.13 224.64,103.07 220.21,103.07 220.09,103.19 205.96,103.19 205.16,102.39 204.87,102.39 204.45,102.82 204.45,102.99
19V_DCBATOUT on L3: 204.33,103.93 224.73,103.93 224.92,103.73 224.92,101.69 224.7,101.47 204.43,101.47 204.15,101.74 204.15,103.76
19V_DCBATOUT_LCD on TOP: 21.74,24.21 23.47,24.21 23.72,23.95 23.72,20.52 24.76,19.48 25.71,19.48 26.59,18.6 26.59,12.64 26.36,12.41 21.34,12.41 20.98,12.77 20.98,23.45
19V_DCBATOUT_LCD on BOTTOM: 21.23,23.11 23.74,23.11 24.69,22.15 24.69,19.47 25.26,18.9 25.95,18.9 26.08,18.78 26.08,17.73 26.19,17.61 26.19,15.84 26.49,15.54 26.49,15.32 26.48,15.32 26.48,14.93 26.62,14.79 26.62,14.41 26.37,14.16 22.97,14.16 22.86,14.27 22.86,18.65 22.36,19.15 20.5,19.15 20.2,19.45 20.2,22.98 20.33,23.1 21.22,23.1 ; 5 cut-outs
19V_DCBATOUT_LCD_BOOST on TOP: 17.55,10.82 19.6,10.82 19.83,10.6 19.83,9.49 18.87,8.53 18.87,6.32 18.8,6.25 17.32,6.25 17.25,6.32 17.25,10.53
19V_DCBATOUT_LCD_BOOST on BOTTOM: 18.02,25.15 19.73,25.15 20.04,24.84 20.04,10.01 19.56,9.53 15.88,9.53 15.57,9.84 15.57,19.33 16.39,20.14 17.44,20.14 17.85,20.56 17.85,24.98
GND on TOP: 150.92,79.99 154.75,79.99 154.94,79.8 154.94,78.84 154.65,78.55 151.9,78.55 151.54,78.2 151.54,77.96 151.5,77.91 150.78,77.91 150.74,77.95 150.74,79.81 ; 5 cut-outs
GND on TOP: 196.49,101.52 198.7,101.52 199.22,101 200.84,101 201.64,100.21 201.64,99.24 201.5,99.1 200.72,99.1 200.53,99.29 200.53,99.92 200.07,100.38 199.16,100.38 199.06,100.49 196.5,100.49 196.38,100.6 196.38,101.41
GND on TOP: 94.15,50.79 96.75,50.79 97.09,50.44 97.09,39.92 93.97,36.81 92.82,36.81 91.57,38.06 91.57,39.99 90.13,41.43 90.13,45.1 91.14,46.12 91.14,46.12 91.67,46.64 93.51,46.64 93.88,47.01 93.88,50.51
GND on TOP: 93.88,63.3 96.52,63.3 96.8,63.02 96.8,60.56 96.67,60.43 95.86,60.43 95.86,60.43 92.48,60.43 92.32,60.59 92.32,61.92 92.42,62.02 93.38,62.02 93.86,62.49 93.86,63.28
GND on TOP: 122.07,74.12 125.25,74.12 125.25,74.12 125.73,74.12 125.8,74.05 125.8,70.92 125.62,70.74 122.15,70.74 121.97,70.92 121.97,74.02
GND on TOP: 122.07,67.69 125.7,67.69 125.73,67.66 125.73,64.45 125.59,64.31 122.15,64.31 121.97,64.49 121.97,67.59
GND on TOP: 90.51,31.66 91.77,31.66 91.9,31.53 91.9,31.24 91.98,31.16 91.99,31.16 92.04,31.11 92.92,31.11 93.22,31.4 94.22,31.4 94.38,31.24 94.38,30.72 94.01,30.35 90.57,30.35 90.47,30.44 90.47,31.63
GND on TOP: 65.96,52.43 74.94,52.43 75.07,52.29 75.07,51.05 76.43,49.69 76.43,46.28 76.33,46.17 75.45,46.17 70.1,40.82 70.1,38.01 69.38,37.3 67.55,37.3 63.67,41.18 63.67,50.13
GND on TOP: 85.22,61.98 87.25,61.98 87.45,61.77 87.45,60.11 87.32,59.98 82.53,59.98 82.46,60.06 82.46,61.71 82.6,61.85 85.09,61.85 ; 9 cut-outs
GND on TOP: 131.6,73.1 135.59,73.1 135.61,73.08 135.61,71.26 135.65,71.22 136.26,71.22 136.3,71.26 136.3,71.44 136.34,71.48 140,71.48 140.03,71.45 140.03,70.36 140.22,70.17 142.35,70.17 142.63,70.45 146.75,70.45 147.03,70.17 147.79,70.17 148.06,69.9 148.06,67.68 147.61,67.23 146.35,67.23 145.86,67.72 142.22,67.72 141.91,67.41 141.91,66.55 141.86,66.5 137.71,66.5 137.47,66.74 135.8,66.74 135.76,66.7 135.76,65.1 135.71,65.05 131.85,65.05 131.6,65.3
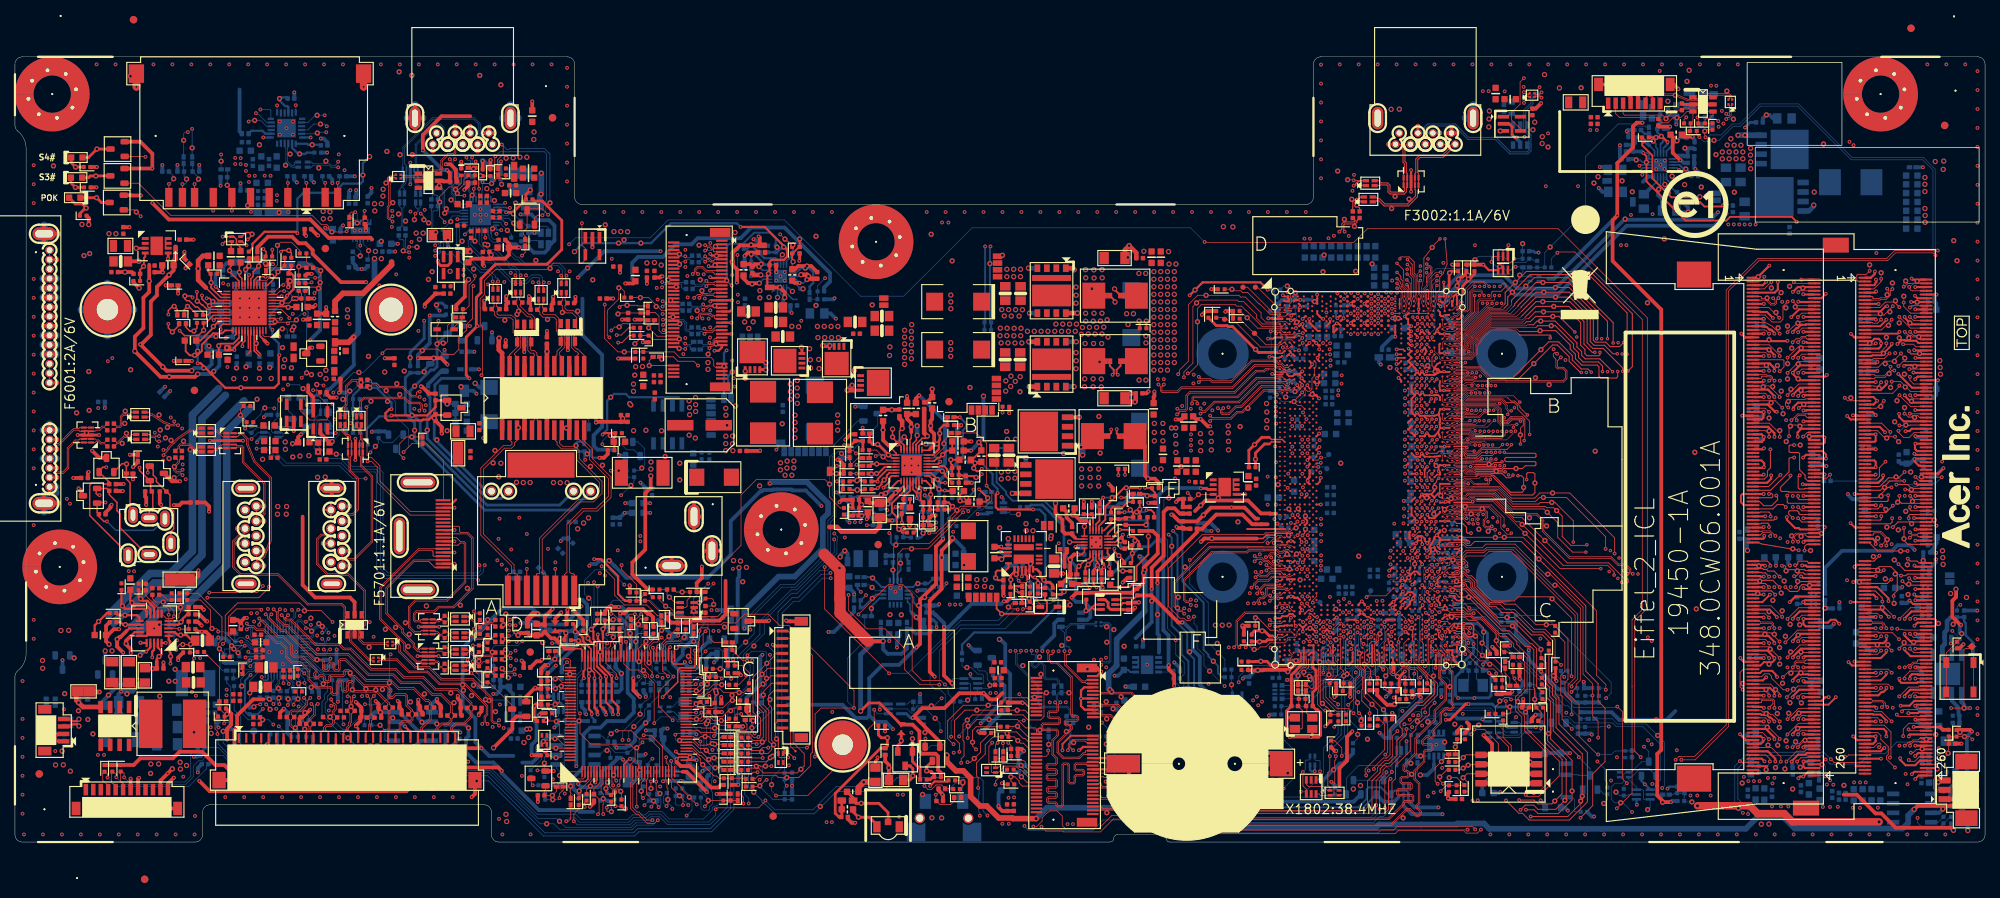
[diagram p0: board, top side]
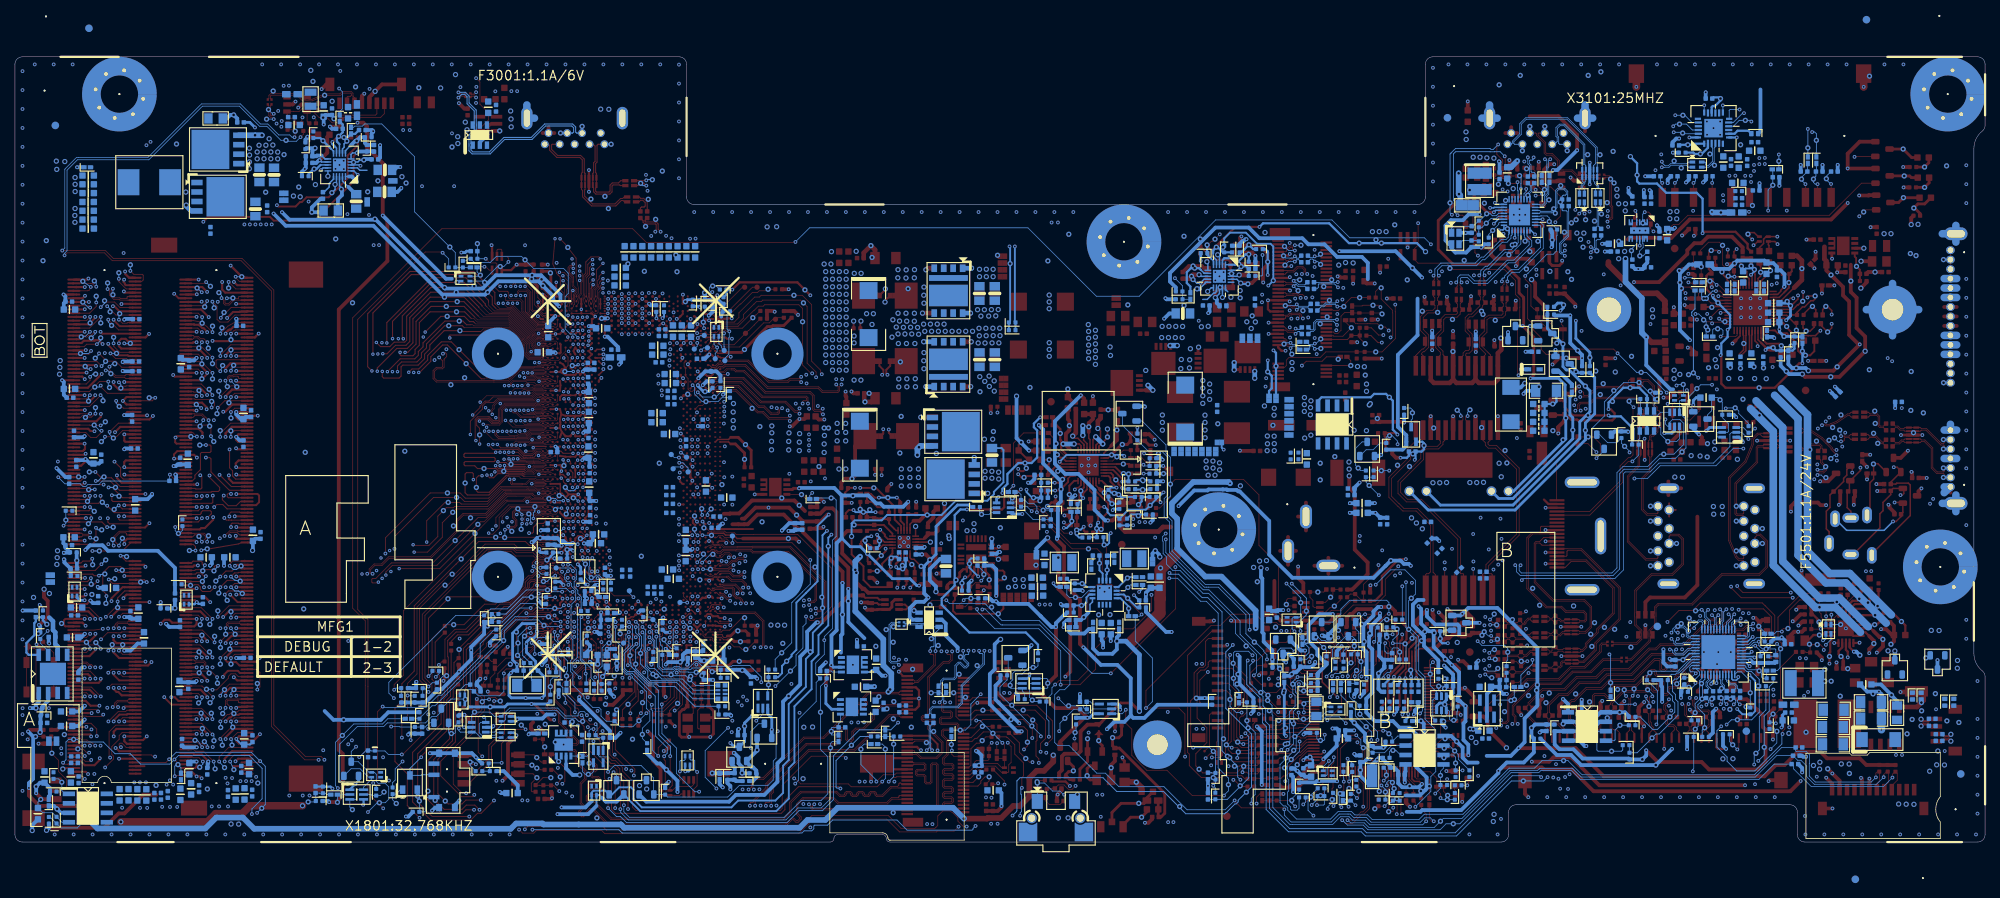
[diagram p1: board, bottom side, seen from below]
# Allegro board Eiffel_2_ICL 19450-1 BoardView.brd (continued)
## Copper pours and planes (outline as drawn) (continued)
GND on TOP: 183.86,73.94 185.36,73.94 185.36,73.92 185.49,73.78 185.49,73.06 185.64,72.9 185.64,67.58 185.52,67.46 184.78,67.46 184.74,67.5 184.74,68.86 184.59,69 183.97,69 183.82,69.16 183.82,73.9
GND on TOP: 35.76,64.12 36.32,64.12 36.42,64.02 36.42,61.97 36.3,61.86 35.84,61.86 35.63,62.07 35.63,63.98
GND on TOP: 40.57,17.96 42.16,17.96 42.34,17.78 42.34,17.48 42.16,17.3 41.66,17.3 41.66,16.48 41.27,16.1 41.27,15.6 41.1,15.42 40.67,15.42 40.59,15.49 40.59,17.02 40.49,17.12 40.49,17.89 40.56,17.95 ; 2 cut-outs
GND on TOP: 31.68,56.64 32.22,56.64 32.43,56.44 33.87,56.44 33.87,56.43 34.07,56.24 34.07,52.14 34.34,51.87 34.53,51.87 34.6,51.8 34.6,51.06 34.38,50.84 32.16,50.84 32.16,52.23 32.26,52.33 32.66,52.33 32.78,52.45 32.78,53.1 32.64,53.24 32.25,53.24 32.16,53.32 32.16,54.34 31.64,54.86 31.64,56.6 ; 10 cut-outs
GND on TOP: outline of 116 points within 164.74,33.18 174.55,60.45 ; 3 cut-outs
GND on TOP: 96.76,73.81 97.47,73.81 97.91,73.36 97.91,70.46 97.88,70.43 96.57,70.43 96.52,70.48 96.52,73.14 96.52,73.14 96.52,73.57
GND on TOP: 155.21,50.22 158.57,50.22 158.69,50.1 158.69,49.33 158.36,49 158.36,47.56 158.22,47.41 155.37,47.41 155.01,47.78 155.01,50.02 ; 7 cut-outs
GND on TOP: outline of 113 points within 220.61,3.44 263.24,104.54 ; 1 cut-out
GND on TOP: 23.83,25 25.34,25 25.5,24.84 25.5,20.75 25.44,20.68 24.31,20.68 24.23,20.76 24.23,23.86 23.68,24.41 23.68,24.84
GND on TOP: 62.02,55.57 62.84,55.57 63.02,55.39 63.02,52.55 62.61,52.15 60.81,52.15 60.63,52.32 60.63,53.77 60.76,53.9 61.75,53.9 61.87,54.03 61.87,55.43 ; 2 cut-outs
GND on TOP: 185.05,33.75 185.28,33.75 185.38,33.65 185.38,33.37 184.32,32.3 184.14,32.3 183.43,31.59 183.25,31.59 182.61,30.96 182.49,30.96 182.39,31.06 182.39,31.21 182,31.59 181.65,31.59 181.55,31.69 181.55,32.3 181.95,32.71 184.01,32.71
GND on TOP: 116.57,71.26 117.73,71.26 117.75,71.24 117.75,64.2 117.68,64.13 116.78,64.13 116.56,64.36 116.56,71.25
GND on TOP: 87.39,56.6 91.15,56.6 91.65,56.1 91.65,54.01 91.45,53.81 90.5,53.81 89.3,55 87.53,55 87.36,55.17 87.36,56.58
GND on TOP: 41.85,54.49 43.92,54.49 44.24,54.17 44.24,49.59 44.66,49.16 44.66,46.55 44.31,46.2 40.73,46.2 40.16,46.77 40.16,48.85 40.83,49.52 40.85,49.52 41.45,50.12 41.45,51.95 41.58,52.08 41.58,54.22 ; 6 cut-outs
GND on TOP: outline of 284 points within 0.76,0.76 263.24,104.54 ; 5 cut-outs
GND on TOP: 130.32,51.63 135.65,51.63 136.25,51.03 136.25,47.6 136.17,47.53 134.69,47.53 134.36,47.21 130.38,47.21 130.23,47.35 130.23,51.54
GND on TOP: 138.55,37.11 140.81,37.11 140.88,37.04 140.87,37.04 140.87,35.64 140.68,35.44 139.54,35.44 139.49,35.39 138.55,35.39 138.5,35.44 138.5,37.06
GND on TOP: 170.79,27.33 172.68,27.33 173.39,26.62 173.51,26.62 173.58,26.55 173.58,26.15 173.38,25.95 171.92,25.95 171.72,25.75 170.61,25.75 170.61,24.43 170.28,24.11 168.37,24.11 167.74,24.73 164.82,24.73 164.72,24.63 164.72,22.76 164.63,22.66 163.86,22.66 163.82,22.63 163.59,22.63 163.47,22.74 163.47,25.54 163.57,25.63 164.53,25.63 164.69,25.79 164.69,26.34 164.77,26.42 165.33,26.42 165.53,26.22 167.98,26.22 168.38,26.62 170.28,26.62 170.56,26.9 170.56,27.09 ; 3 cut-outs
GND on TOP: 134.88,43.59 135.84,43.59 137.2,42.24 137.2,40.87 136.55,40.22 134.77,40.22 134.73,40.26 134.73,43.44
GND on TOP: 175.9,32.95 179.13,32.95 179.4,32.68 179.4,31.65 179.27,31.53 176.61,31.53 176.41,31.33 176.41,30.92 176.51,30.82 176.78,30.82 176.91,30.69 176.91,30.1 176.78,29.98 175.02,29.98 174.62,30.38 174.06,30.38 173.96,30.47 173.96,31.63 174.04,31.7 174.06,31.7 174.07,31.71 174.61,31.71 174.72,31.6 174.72,30.92 174.86,30.78 175.47,30.78 175.64,30.94 175.64,32.69
GND on TOP: 31.38,21.54 32.48,21.54 32.54,21.48 32.54,20.13 32.48,20.08 32.25,20.08 30.51,18.34 28.72,18.34 28.57,18.49 28.06,18.49 27.97,18.58 27.97,20.6 28.11,20.74 28.53,20.74 28.72,20.56 28.72,19.37 28.8,19.29 30.55,19.29 31.36,20.1 31.36,21.52 ; 2 cut-outs
GND on TOP: 72.44,41.87 73.44,41.87 73.63,41.69 73.63,37.3 73.48,37.16 71.23,37.16 71.08,37.31 71.08,40.52
GND on TOP: 125.74,35.98 126.8,35.98 127.04,35.75 127.04,32.3 127.04,32.29 127.04,31.6 126.99,31.55 124.84,31.55 124.76,31.63 124.76,32.93 125.59,33.77 125.59,35.84 ; 6 cut-outs
GND on TOP: 32.64,18.1 33.43,18.1 33.6,17.93 33.6,15.21 33.53,15.14 32.58,15.14 32.48,15.24 32.48,17.94 ; 3 cut-outs
GND on TOP: 186.67,40.96 187.03,40.96 187.35,40.65 187.35,38.61 187.16,38.42 187.16,37.66 187.08,37.59 187.08,37.21 187.14,37.15 187.14,36.85 187.03,36.75 186.86,36.75 186.4,37.21 186.4,37.48 186.63,37.71 186.63,38.04 186.52,38.15 186.52,40.81
GND on TOP: 130,24.44 131.53,24.44 131.6,24.37 131.6,20.44 131.77,20.27 131.77,19.86 131.5,19.6 130.61,19.6 130.32,19.89 130.29,19.89 129.89,20.29 129.89,24.33 ; 6 cut-outs
GND on TOP: 211.31,96.63 212.42,96.63 212.6,96.45 212.6,95.29 212.47,95.16 210.87,95.16 210.73,95.3 210.73,96.5 210.85,96.62 211.3,96.62 ; 2 cut-outs
GND on TOP: 238.54,77.74 250.49,77.74 250.81,77.42 250.81,76.34 250.67,76.21 246.7,76.21 246.47,75.98 246.47,43.27 246.34,43.14 245.82,43.14 245.59,42.91 245.59,42.6 246.47,41.72 246.47,11.47 246.23,11.24 243.12,11.24 242.41,11.95 242.41,69.16 242.24,69.32 242.24,70.49 242.39,70.64 242.41,70.64 242.41,75.71 242.26,75.86 238.54,75.86 238.48,75.92 238.48,77.67
GND on TOP: 143.08,8.39 145.14,8.39 145.17,8.36 145.17,8.13 145.14,8.1 143.45,8.1 143.31,7.96 143.31,6.99 143.4,6.91 145.19,6.91 145.21,6.88 145.21,6.65 145.16,6.6 143.31,6.6 143.23,6.52 143.23,5.51 143.37,5.38 145.13,5.38 145.2,5.31 145.2,5.15 145.15,5.1 143.37,5.1 143.28,5.02 143.28,4 143.38,3.9 145.23,3.9 145.31,3.83 145.31,3.68 145.31,3.67 145.31,2.18 145.15,2.01 140.71,2.01 140.54,2.18 140.54,5.85
GND on TOP: 32.74,28.12 33.25,28.12 34.86,26.5 35.29,26.5 36.04,25.76 36.04,24.74 36.3,24.49 36.3,21.29 36.1,21.09 35.76,21.09 35.42,21.43 35.42,22.38 35.11,22.69 34.44,22.69 34.44,22.69 34.07,22.69 34.06,22.7 34.06,24.15 33.73,24.48 32.95,24.48 32.89,24.54 32.89,27.23 32.66,27.46 32.66,28.04 ; 8 cut-outs
GND on TOP: 60.39,86.04 63.49,86.04 63.57,85.96 63.57,85.85 64.38,85.04 64.4,85.04 64.4,83.48 63.97,83.06 62.88,83.06 62.44,82.62 62.44,82.3 62.43,82.3 62.43,81.66 62.32,81.55 60.92,81.55 60.31,82.16 59.95,82.16 59.84,82.28 59.84,84.62 60.1,84.88 60.1,85.76 ; 13 cut-outs
GND on TOP: 11.91,26.02 13.16,26.02 14.28,24.9 16.05,24.9 16.16,24.78 16.16,23.58 16.12,23.54 12.23,23.54 11.69,24.08 11.69,25.8
GND on TOP: 152.14,51.78 154.25,51.78 154.37,51.66 154.37,49.76 154.25,49.64 152.17,49.64 152.01,49.8 152.01,51.65 ; 1 cut-out
GND on TOP: 67.53,92.2 68.74,92.2 68.92,92.02 68.92,91.63 68.91,91.62 68.91,91.37 68.42,90.88 68.42,86.95 68.14,86.67 66.69,86.67 66.62,86.73 66.62,87.53 66.8,87.71 66.8,88.29 66.91,88.4 67.37,88.4 67.51,88.54 67.51,91.44 67.31,91.64 67.31,91.98 ; 1 cut-out
GND on TOP: 192.96,26.38 193.62,26.38 193.92,26.07 193.92,24.47 193.51,24.05 193.51,23.84 193.45,23.78 193.19,23.78 192.62,24.35 192.62,24.84 192.45,25 192.45,25.3 192.48,25.33 192.48,25.4 192.35,25.54 191.87,25.54 191.81,25.59 191.81,25.89 192.01,26.08 192.66,26.08
GND on TOP: 62.51,40.14 63.01,40.14 66.23,36.92 66.23,36.19 66.16,36.12 66.1,36.12 66,36.02 65.46,36.02 65.34,35.9 65.34,34.69 65.26,34.61 63.34,34.61 63.21,34.74 63.21,37.83 62.34,38.71 62.34,39.96
GND on TOP: 104.36,15.61 106.41,15.61 106.49,15.52 106.49,13.48 106.34,13.33 104.38,13.33 104.27,13.44 104.27,15.52
GND on TOP: 177.13,73.83 177.69,73.83 177.81,73.7 177.81,70.87 177.73,70.78 175.55,70.78 175.5,70.83 175.5,73.54 175.49,73.55 175.64,73.7 176,73.7 176.11,73.59 176.11,72.21 176.24,72.08 176.62,72.08 176.87,72.33 176.87,73.58
GND on TOP: 44.25,19.05 44.53,19.05 44.68,18.9 44.68,18.72 43.92,17.96 43.92,17.27 44.13,17.06 44.31,17.06 44.45,16.92 44.45,16.46 44.37,16.38 43.87,16.38 43.81,16.43 43.81,16.92 43.43,17.3 43.33,17.3 43.31,17.32 43.31,18.11
GND on TOP: 102.35,72.41 103.51,72.41 105.28,70.64 105.62,70.64 105.62,70.63 112.29,70.63 112.51,70.41 112.51,66.05 112.4,65.94 109.62,65.94 109.58,65.98 109.58,67.23 109.5,67.31 107.92,67.31 107.76,67.15 107.76,65.9 108.13,65.53 108.13,63.29 108.13,63.29 108.13,62.77 107.45,62.08 106.12,62.08 105.79,61.76 105.79,58.68 105.51,58.4 103.59,58.4 103.47,58.51 103.47,61.47 104.93,62.93 104.93,65.07 104.95,65.1 106.02,65.1 106.12,65.2 106.12,66.5 105.59,67.03 103.28,67.03 103.23,67.08 103.23,68.69 102.9,69.02 102.74,69.02 102.74,69.01 102.39,69.01 102.26,69.14 102.26,72.32 ; 2 cut-outs
GND on BOTTOM: 145.28,18.85 146.14,18.85 146.83,18.16 149,18.16 149.51,17.65 149.51,17.41 149.54,17.38 150.77,17.38 150.81,17.34 150.81,16.71 151.01,16.51 151.02,16.51 151.13,16.39 152.84,16.39 153.03,16.21 153.03,14.99 146.4,14.99 145.11,16.28 145.11,18.69 ; 9 cut-outs
GND on BOTTOM: 143.91,41.06 145.99,41.06 146.12,40.93 146.12,38.67 145.95,38.51 144.38,38.51 143.87,39.02 143.15,39.02 142.97,39.2 142.97,40.13 ; 4 cut-outs
GND on BOTTOM: 227.16,97.52 228.02,97.52 228.59,96.95 228.59,95.8 228.42,95.64 226.98,95.64 226.89,95.72 226.89,96.55 227.1,96.76 227.1,97.46 ; 2 cut-outs
GND on BOTTOM: 174.19,49.09 175.78,49.09 176.14,48.73 176.14,43.98 176,43.84 173.59,43.84 173.33,43.58 173.33,42.76 171.57,42.76 171.33,42.51 171.33,41.73 171.31,41.72 170.46,41.72 170.45,41.72 170.25,41.72 170.16,41.8 170.16,42.88 170.08,42.96 170.08,44.1 169.95,44.24 168.76,44.24 168.69,44.32 168.69,45.55 168.89,45.75 168.89,46.31 170.35,47.78 173.63,47.78 173.96,48.11 173.96,48.87 ; 14 cut-outs
GND on BOTTOM: 256.21,11.84 256.72,11.84 256.81,11.75 256.81,10.47 257.04,10.24 260.34,10.24 260.62,9.97 260.62,9.1 260.49,8.98 258.43,8.98 257.94,8.49 257.29,8.49 256.85,8.93 256.19,8.93 256.19,8.93 255.76,8.5 255.19,8.5 255.14,8.55 255.14,9.09 255.18,9.13 255.91,9.13 256.06,9.29 256.06,9.81 256.12,9.87 256.12,11.75 ; 4 cut-outs
GND on BOTTOM: 229.94,84.77 232.42,84.77 232.51,84.68 232.51,83.95 233.02,83.45 238.1,83.45 238.15,83.39 238.15,82.38 238.07,82.31 229.5,82.31 229.33,82.48 229.33,83.2 229.79,83.66 229.79,84.62 ; 2 cut-outs
GND on BOTTOM: 254.65,31.89 255.41,31.89 255.47,31.83 255.47,31.43 255.46,31.42 255.46,31.05 255.85,30.66 255.85,30.15 255.36,29.66 254.55,29.66 254.41,29.8 254.41,30.18 254.59,30.36 254.59,31.82 ; 2 cut-outs
GND on BOTTOM: 117.06,34.49 118.96,34.49 119,34.45 119,32.26 119.15,32.12 119.51,32.12 119.7,31.93 119.7,31.54 119.58,31.43 118.57,31.43 118.54,31.46 118.54,32.27 118.39,32.42 117.49,32.42 117.4,32.33 117.4,31.42 117.35,31.37 116.25,31.37 116.12,31.5 116.12,32.15 116.21,32.23 116.89,32.23 116.99,32.33 116.99,34.42
GND on BOTTOM: 138.5,36.6 140.79,36.6 140.9,36.49 140.9,35.41 140.81,35.32 138.54,35.32 138.44,35.42 138.44,36.55
GND on BOTTOM: 216.36,11.71 216.97,11.71 217.02,11.66 217.02,11.15 217.02,11.15 217.02,10.82 216.94,10.74 214.5,10.74 214.38,10.87 214.38,11.53 214.48,11.63 216.28,11.63 ; 1 cut-out
GND on BOTTOM: 125.74,35.91 126.59,35.91 126.84,35.67 126.84,32.87 127.04,32.67 127.04,31.67 126.9,31.53 124.86,31.53 124.77,31.62 124.77,33.15 125.42,33.81 125.42,35.59 ; 6 cut-outs
GND on BOTTOM: 232.41,11.31 234.47,11.31 234.63,11.15 234.63,10.23 234.27,9.86 232.29,9.86 232.19,9.95 232.19,11.09 ; 4 cut-outs
GND on BOTTOM: 131.97,51.74 134.08,51.74 134.26,51.56 134.26,50.12 134.58,49.8 136.14,49.8 136.25,49.68 136.25,46.39 136.1,46.24 134.34,46.24 134.06,46.52 134.06,47.82 133.77,48.12 132.17,48.12 131.73,48.55 131.73,51.5
GND on BOTTOM: 188.63,16.23 189.64,16.23 189.74,16.13 189.74,14.13 189.72,14.11 187.74,14.11 187.7,14.15 187.7,15.3 188.5,16.11 188.51,16.11 ; 2 cut-outs
GND on BOTTOM: 29.87,94.18 30.66,94.18 30.79,94.04 30.79,91.55 31.27,91.08 35.62,91.08 35.82,90.87 35.82,89.84 35.72,89.74 30.15,89.74 29.18,90.7 29.18,93.49 ; 13 cut-outs
GND on BOTTOM: 63.51,53.01 74.43,53.01 74.89,52.55 74.89,48.47 72.24,45.83 68.9,45.83 66.57,48.16 63.52,48.16 63.21,48.46 63.21,52.7 63.51,53
GND on BOTTOM: 66.41,17.56 67.01,17.56 67.11,17.47 67.11,15.65 66.88,15.43 66.88,14.56 66.77,14.45 66.77,13.67 66.68,13.58 65.34,13.58 65.23,13.68 65.23,15.41 65.52,15.69 66.19,15.69 66.36,15.87 66.36,17.51 ; 3 cut-outs
GND on BOTTOM: 89.96,55.02 90.84,55.02 93.25,52.61 93.25,51.91 93.2,51.86 90.43,51.86 89.9,52.4 89.9,54.95 ; 5 cut-outs
GND on BOTTOM: 64.84,43.8 74.19,43.8 74.53,43.46 74.53,40.7 69.78,35.95 65.49,35.95 64.37,37.07 64.37,43.33 ; 11 cut-outs
GND on BOTTOM: 28.95,74.18 35.09,74.18 35.2,74.06 35.2,71.86 34.92,71.58 33.27,71.58 33.12,71.42 33.12,68.73 32.97,68.58 29.64,68.58 29.63,68.57 29.63,68.42 29.52,68.3 28.76,68.3 28.59,68.47 28.59,73.82 ; 16 cut-outs
GND on BOTTOM: 20.76,18.89 22.32,18.89 22.4,18.8 22.4,14.23 22.69,13.95 24.54,13.95 24.81,13.68 24.81,12.44 24.73,12.36 23.55,12.36 23.35,12.17 23.35,9.61 23.19,9.45 20.84,9.45 20.65,9.63 20.65,18.79 ; 1 cut-out
GND on BOTTOM: 149.48,51.44 154.12,51.44 154.39,51.17 154.39,49.21 154.06,48.88 149.45,48.88 149.33,49 149.33,51.29
GND on BOTTOM: outline of 170 points within 0.76,0.76 263.24,104.54 ; 4 cut-outs
GND on BOTTOM: 229.81,94.76 231.63,94.76 231.99,94.76 232.82,93.93 234.72,93.93 234.81,93.85 234.81,91.82 234.86,91.77 234.86,89.95 234.8,89.89 228.55,89.89 228.4,90.04 228.4,93.34
GND on BOTTOM: 173.35,70.56 176.33,70.56 177.04,69.85 177.81,69.85 178.05,69.61 178.05,68.59 177.9,68.44 172.99,68.44 172.85,68.3 172.85,68.15 172.69,68 172.41,68 172.27,68.14 172.27,70.2 172.63,70.56 173.34,70.56 ; 13 cut-outs
GND on BOTTOM: 33.23,89.57 35.41,89.57 35.5,89.48 35.5,85.53 35.2,85.23 33.24,85.23 33.18,85.3 33.18,89.52 ; 8 cut-outs
GND on BOTTOM: 124.74,42.72 126.45,42.72 126.53,42.64 126.53,39.3 126.52,39.29 126.52,38.2 126.44,38.11 125.59,38.11 125.48,38.22 125.48,39.12 124.64,39.96 124.64,42.62 ; 3 cut-outs
GND on BOTTOM: 103.56,62.54 108.53,62.54 108.74,62.33 108.74,58.52 108.51,58.29 102.64,58.29 102.59,58.34 102.59,61.57 ; 1 cut-out
GND on BOTTOM: 194.53,99.71 200.88,99.71 200.99,99.6 200.99,98.73 200.83,98.57 197.2,98.57 196.91,98.28 196.91,95.44 196.36,94.89 194.77,94.89 193.67,95.98 193.67,98.86 ; 3 cut-outs
GND on BOTTOM: 35.96,65.14 36.55,65.14 36.78,64.9 36.78,63.07 36.65,62.93 29.56,62.93 29.38,63.11 29.38,64.4 29.56,64.58 35.4,64.58 ; 7 cut-outs
GND on BOTTOM: 131.6,73.13 135.48,73.13 135.59,73.03 135.59,70.13 135.66,70.05 137.57,70.05 137.59,70.08 137.59,71.4 137.79,71.6 141.77,71.6 142.91,70.46 146.6,70.46 147.02,70.05 150.57,70.05 150.98,69.65 150.98,66.57 150.85,66.45 146.74,66.45 145.55,67.64 141.78,67.64 141.74,67.68 141.73,67.67 140.46,67.67 140.34,67.54 140.36,67.51 140.36,66.57 140.28,66.5 135.99,66.5 135.79,66.29 135.79,65.1 135.66,64.97 131.95,64.97 131.57,65.35 131.57,73.1
GND on BOTTOM: 217.61,85.6 219.57,85.6 220.08,85.09 220.57,85.09 220.7,84.95 220.7,84.06 220.49,83.85 217.71,83.85 217.54,84.02 217.54,85.54
GND on BOTTOM: 178.17,67.11 178.83,67.11 179.28,66.65 179.28,63.46 178.35,62.53 177.99,62.17 177.99,54.22 176.39,52.63 173.92,52.63 173.74,52.81 173.74,53.3 173.83,53.39 175.66,53.39 176.21,53.94 176.21,60.88 176.47,61.15 176.47,63.11 176.55,63.18 177.64,63.18 177.86,63.39 177.86,64.46 177.86,64.47 177.86,66.8 ; 27 cut-outs
GND on BOTTOM: 96.14,73.87 98.75,73.87 99.17,73.45 99.17,72.56 99.34,72.39 101.83,72.39 101.96,72.26 101.96,71.47 101.85,71.37 98.56,71.37 98.5,71.43 98.5,72.17 98.31,72.36 95.91,72.36 95.83,72.44 95.83,73.56 ; 2 cut-outs
GND on BOTTOM: 176.6,37.06 177.69,37.06 178.8,35.95 183.59,35.95 183.83,36.19 183.83,36.54 183.99,36.69 184.37,36.69 184.75,36.31 185.23,36.31 185.45,36.09 185.45,35.76 184.93,35.24 183.86,35.24 182.53,33.9 181,33.9 180.79,33.7 180.79,30.6 180.7,30.51 180.24,30.51 180.11,30.64 180.11,33.5 179.7,33.9 175.92,33.9 175.84,33.98 175.84,35.48 176.47,36.1 176.47,36.93 ; 14 cut-outs
GND on BOTTOM: 172.59,81.55 182.36,81.55 182.78,81.14 182.78,79.5 182.63,79.35 172.45,79.35 172.34,79.46 172.34,81.31 ; 16 cut-outs
GND on BOTTOM: 239.01,7.01 240.81,7.01 241.07,6.76 241.07,6.46 241.3,6.23 243.88,6.23 244.04,6.07 248.77,6.07 250.53,6.07 250.74,6.28 250.74,6.91 250.79,6.96 252.75,6.96 252.84,6.87 252.84,2.45 252.71,2.33 250.55,2.33 250.47,2.41 250.47,3.2 249.4,4.28 232.9,4.28 231.86,5.32 231.86,6.41 238.41,6.41 ; 29 cut-outs
GND on BOTTOM: 183.27,77.72 184.63,77.72 184.86,77.49 184.86,73.34 184.75,73.23 183.81,73.23 183.15,73.89 183.15,77.6 ; 6 cut-outs
GND on BOTTOM: 254.55,89.98 256.32,89.98 256.52,89.78 256.52,81.81 256.36,81.65 254.5,81.65 254.39,81.76 254.39,89.82 ; 12 cut-outs
GND on L2GND: 174.76,104.3 174.83,104.47 175,104.54 263,104.54 263.17,104.47 263.24,104.3 263.24,1 263.17,0.83 263,0.76 154.99,0.76 154.54,1.48 153.75,1.76 147.75,1.76 146.96,1.48 146.51,0.76 64.85,0.76 64.68,0.83 64.61,1 64.61,4 64.1,5.25 62.85,5.76 26.15,5.76 24.9,5.25 24.39,4 24.39,1 24.32,0.83 24.15,0.76 1,0.76 0.83,0.83 0.76,1 0.76,22.18 0.79,22.28 1.89,23.67 2.26,25.3 2.26,93 1.89,94.63 0.85,95.94 0.79,96.02 0.76,96.12 0.76,104.3 0.83,104.47 1,104.54 74,104.54 74.17,104.47 74.24,104.3 74.24,86.5 74.75,85.25 76,84.74 173,84.74 174.25,85.25 174.76,86.5 ; 112 cut-outs
GND on L3: 154.99,0.76 154.54,1.48 153.75,1.76 147.75,1.76 147.4,1.71 147.09,1.57 147.09,2.14 147.41,2.24 147.75,2.27 153.75,2.27 154.69,2 155.34,1.27 257.04,1.27 262.73,6.96 262.73,21.98 263.24,21.98 263.24,1 263.17,0.83 263,0.76
GND on L3: outline of 120 points within 0.76,0.76 263.24,104.54
GND on L4: 63.23,70.06 73.45,70.06 76.22,67.3 76.22,65.96 75.6,65.34 63.14,65.34 62.89,65.59 62.89,69.72
GND on L4: 193.44,0.76 193.44,1.27 256.06,1.27 262.73,7.94 262.73,21.98 263.24,21.98 263.24,1 263.17,0.83 263,0.76
GND on L4: outline of 117 points within 0.76,0.76 263.24,104.54 ; 1 cut-out
GND on L4: 141.61,65.78 141.61,64.9 141.26,64.56 129.64,64.56 129.5,64.7 129.5,70.06 132.16,72.72 132.16,74.86 132.38,75.08 141.24,75.08 141.46,74.86 141.46,72 141.87,71.58 146.4,71.58 146.84,71.14 146.84,67.51 146.66,67.32 143.15,67.32
GND on L5GND: 174.76,104.3 174.83,104.47 175,104.54 263,104.54 263.17,104.47 263.24,104.3 263.24,1 263.17,0.83 263,0.76 154.99,0.76 154.54,1.48 153.75,1.76 147.75,1.76 146.96,1.48 146.51,0.76 64.85,0.76 64.68,0.83 64.61,1 64.61,4 64.1,5.25 62.85,5.76 26.15,5.76 24.9,5.25 24.39,4 24.39,1 24.32,0.83 24.15,0.76 1,0.76 0.83,0.83 0.76,1 0.76,22.18 0.79,22.28 1.89,23.67 2.26,25.3 2.26,93 1.89,94.63 0.85,95.94 0.79,96.02 0.76,96.12 0.76,104.3 0.83,104.47 1,104.54 74,104.54 74.17,104.47 74.24,104.3 74.24,86.5 74.75,85.25 76,84.74 173,84.74 174.25,85.25 174.76,86.5 ; 51 cut-outs
VCCPLL_OC on BOTTOM: 190,16.15 192.3,16.15 192.34,16.11 193.18,16.11 193.29,15.99 193.29,15.25 193.2,15.15 193.2,14.19 193.15,14.15 190.06,14.15 189.96,14.25 189.96,16.11 ; 2 cut-outs
0D6V_VREF_S0 on BOTTOM: 238.81,9.65 241.03,9.65 241.09,9.59 241.09,7.38 241,7.29 238.98,7.29 238.84,7.14 238.84,7.04 238.38,6.59 237.74,6.59 237.65,6.68 237.65,9.31 237.7,9.37 238.53,9.37 ; 7 cut-outs
0D6V_VREF_S0 on BOTTOM: 255.15,12.95 255.92,12.95 256,12.87 256,12.02 255.87,11.89 255.87,9.43 255.77,9.33 254.85,9.33 254.26,8.74 251.45,8.74 250.41,7.69 250.41,6.67 250.35,6.61 248.4,6.61 248.33,6.68 248.33,7.46 248.52,7.64 248.52,8.66 248.54,8.69 248.54,9.79 249.18,10.43 254.88,10.43 255.1,10.65 255.1,12.9 ; 3 cut-outs
0D6V_VREF_S0 on BOTTOM: 211.22,89.86 212.52,89.86 212.62,89.76 212.62,89.31 212.8,89.13 213.13,89.13 213.21,89.05 213.21,88.2 213.19,88.19 212.14,88.19 211.84,87.89 211.23,87.89 211.14,87.98 211.14,89.79
0D6V_VREF_S0 on L4: 238.64,6.3 238.95,5.98 255.45,5.98 257.12,7.65 257.12,12.54 258.74,14.15 258.74,33.64 261.08,35.98 261.08,79.55 260.68,79.96 258.83,79.96 258.42,79.55 258.42,37.34 255.25,34.16 255.25,11.15 254.63,10.52 254.61,10.52 253.75,9.66 253.06,9.66 252.78,9.38 241.29,9.38 241.03,9.12 238.73,9.12 238.64,9.03
1D2V_EDP on TOP: 32.16,24.26 33.3,24.26 33.45,24.1 33.45,21.93 33.3,21.78 31.13,21.78 31.01,21.66 31.01,20.03 30.51,19.52 28.99,19.52 28.94,19.57 28.94,20.32 28.94,20.32 28.94,22.81 29.04,22.91 30.98,22.91 31.27,23.21 31.27,23.68 31.43,23.83 31.73,23.83 ; 4 cut-outs
1D2V_EDP_SWR on TOP: 29.62,25.87 30.29,25.87 31.19,24.97 31.19,24.65 31,24.46 31,23.29 30.92,23.21 29.65,23.21 29.54,23.33 29.54,25.79 ; 2 cut-outs
1D2V_S3 on TOP: 218.03,27.71 219.48,27.71 219.63,27.56 219.63,16.26 220.17,15.72 220.17,13.36 219.58,12.78 218.87,12.78 218.31,13.34 218.31,16.1 217.96,16.46 217.96,27.64
1D2V_S3 on TOP: 186.75,63.3 187.27,63.3 187.4,63.17 187.4,61.85 186.91,61.35 186.91,57.48 187.4,56.98 187.4,55.57 186.93,55.1 186.93,54.66 187.37,54.23 187.37,52.88 187.16,52.67 187.16,51.67 187.43,51.4 187.43,50.04 186.92,49.54 186.92,49.24 187.4,48.76 187.4,47.62 187.76,47.27 188.38,47.27 188.48,47.17 188.48,46.98 187.97,46.46 187.97,46.3 187.17,45.5 186.92,45.5 186.8,45.63 185.95,45.63 185.78,45.8 185.78,61.44 185.99,61.64 185.99,62.39 185.98,62.4 185.98,62.53
1D2V_S3 on TOP: 216.27,84.58 216.82,84.58 217.05,84.36 217.05,83.85 216.18,82.98 216.18,78.77 216,78.59 215.36,78.59 215.09,78.85 215.09,83.41
1D2V_S3 on TOP: 257.7,65.07 259.49,65.07 260.31,64.25 260.31,35.25 258.67,33.61 254.53,33.61 254.39,33.75 254.39,34.11 254.48,34.2 257.23,34.2 257.4,34.37 257.4,34.92 257.14,35.18 254.51,35.18 254.42,35.26 254.42,35.71 254.46,35.75 257.1,35.75 257.23,35.88 257.23,36.55 257.08,36.7 254.5,36.7 254.27,36.92 254.27,37.19 254.44,37.36 254.63,37.36 254.83,37.15 257.52,37.15 257.92,37.56 257.92,39.68 257.4,40.21 254.5,40.21 254.38,40.33 254.38,40.66 254.42,40.71 257.11,40.71 257.11,41.56 257,41.67 254.59,41.67 254.33,41.93 254.33,42.09 254.39,42.15 257.8,42.15 257.9,42.25 257.9,47.96 258.22,48.28 258.5,48.28 258.88,48.67 258.88,50.34 258.61,50.62 257.79,50.62 257.7,50.72 257.7,61.06 258.03,61.39 258.03,62.25 257.5,62.78 257.48,62.78 257.48,64.85
1D2V_S3 on BOTTOM: 216.22,85.7 217.25,85.7 217.28,85.67 217.28,83.95 217.15,83.82 216.34,83.82 216.18,83.99 216.18,85.66
1D2V_S3 on BOTTOM: outline of 86 points within 185.92,12.42 259.34,91.08 ; 157 cut-outs
1D2V_S3 on BOTTOM: 201.52,14.95 208.06,14.95 209.13,13.88 209.52,13.88 209.52,13.88 209.69,13.88 209.7,13.87 212.62,13.87 212.98,14.22 219.33,14.22 219.74,13.82 219.74,12.88 219.56,12.7 217.68,12.7 217.45,12.93 214.76,12.93 213.92,12.09 209.65,12.09 209.12,12.62 203.91,12.62 203.29,12 201.97,12 201.69,11.73 199.94,11.73 197.54,9.32 190.73,9.32 190.58,9.47 190.58,12.09 190.47,12.19 189.28,12.19 189.25,12.17 187.77,12.17 187.72,12.22 187.72,13.71 187.79,13.78 188.32,13.78 188.46,13.92 193.42,13.92 193.45,13.94 195.43,13.94 195.66,13.72 195.66,13.22 195.86,13.02 198.26,13.02 198.34,13.09 198.35,13.09 199.73,14.48 201.05,14.48 ; 1 cut-out
1D05V_LAN on TOP: 62.63,87.99 63.4,87.99 63.59,87.79 63.59,87.08 63.82,86.86 63.96,86.86 65.38,85.44 65.38,84.18 65.45,84.11 65.94,84.11 66.16,83.89 66.16,82.76 66.06,82.66 65.02,82.66 63.81,81.46 63.81,80.89 63.54,80.61 60.48,80.61 60.02,81.07 60.02,81.63 60.15,81.75 60.48,81.75 60.88,81.35 62.34,81.35 62.68,81.69 62.68,82.57 63,82.89 64.08,82.89 64.62,83.42 64.62,85.02 63.76,85.88 63.76,86.06 63.55,86.27 62.1,86.27 62.02,86.35 62.02,86.94 62.11,87.03 62.12,87.03 62.57,87.48 62.59,87.49 62.59,87.94 ; 4 cut-outs
1D05V_LAN on BOTTOM: 66.33,91.1 70.75,91.1 70.94,90.91 70.94,88.82 70.74,88.61 65.98,88.61 65.36,87.99 63.91,87.99 63.58,87.66 63.58,87.48 63.08,86.99 63.08,85.77 63.08,85.76 62.89,85.76 62.88,85.77 62.88,87.16 62.89,87.17 62.89,88.29 63.03,88.43 63.03,89.19 63.3,89.45 64.43,89.45 64.66,89.23 65.5,89.23 65.7,89.43 65.7,90.47 ; 3 cut-outs
1D05V_LAN on L4: 66.83,83.02 64.63,83.02 63.78,82.17 63.78,80.96 63.49,80.66 60.49,80.66 60.07,81.08 60.07,85.55 60.83,86.31 60.83,86.84 61.03,87.05 62.53,87.05 62.81,87.33 62.81,88.01 63.53,88.72 66.94,88.72 67.21,88.46 67.21,83.4
1D05V_LAN_OUT on BOTTOM: 66.15,88.32 69.41,88.32 69.5,88.23 69.5,86.84 69.15,86.48 69.15,84.8 69,84.65 66.68,84.65 66.63,84.71 66.63,84.92 66.65,84.94 66.62,84.96 66.62,85.35 66.2,85.78 63.68,85.78 63.68,86.64 64.54,86.64 66.08,88.18 66.08,88.25
1D05V_S5_OUT on TOP: 160.42,44.38 164.54,44.38 165.96,42.96 167.07,42.96 167.08,42.96 168.57,42.96 168.61,42.92 169.71,42.92 169.88,43.09 169.88,44.01 169.95,44.07 170.28,44.07 170.36,44 170.36,42.93 169.81,42.38 167.82,42.38 167.8,42.36 165.45,42.36 164.18,43.64 161.07,43.64 159.06,41.63 158.18,41.63 158.11,41.71 158.11,42.51 158.16,42.57 158.61,42.57 ; 1 cut-out
1D05V_S5_OUT on BOTTOM: 152.2,27.27 153.98,27.27 154.36,26.89 154.36,24.31 153.96,23.92 152.71,23.92 152.57,23.77 152.57,21.19 153.9,19.86 153.9,18.25 153.88,18.27 152.84,18.27 152.71,18.15 152.71,16.66 152.65,16.61 151.09,16.61 151,16.7 151,21.2 150.86,21.34 150.86,22.53 150.85,22.54 150.85,25.05 150.84,25.07 150.84,25.7 150.87,25.73 151.77,25.73 151.83,25.79 151.83,26.9 ; 2 cut-outs
1D05V_S5_VCCPRIM_OUT on TOP: 182.95,31.27 184.19,31.27 184.32,31.14 184.32,30.4 184.25,30.33 182.8,30.33 182.7,30.43 182.7,31.01
1D05V_VCCPLL on TOP: 161.1,43.5 164.09,43.5 165.27,42.32 165.39,42.2 170.29,42.2 170.33,42.17 170.33,41.87 170.24,41.78 167.54,41.78 167.23,41.47 161.01,41.47 160.83,41.65 160.83,43.23
1D05V_VCCST on TOP: 160.08,45.27 164.89,45.27 166.54,43.62 169.59,43.62 169.72,43.49 169.72,43.13 169.67,43.08 167.65,43.08 167.64,43.09 165.97,43.09 164.57,44.5 160.39,44.5 158.58,42.69 156.11,42.69 156,42.8 156,43.4 156.06,43.46 158.27,43.46
1D05V_VCCST on BOTTOM: 145.84,20.99 147.8,20.99 148.73,20.06 150.68,20.06 150.83,19.91 150.83,17.65 150.7,17.52 149.87,17.52 149.11,18.29 146.99,18.29 145.73,19.55 145.73,20.88 ; 4 cut-outs
1D05V_VCCST on BOTTOM: 167.74,44.12 169.8,44.12 169.85,44.06 169.85,43.15 169.75,43.05 167.82,43.05 167.68,43.19 167.68,44.06 ; 1 cut-out
1D05V_VCCSTG on TOP: 158.93,46.2 165.15,46.2 166.77,44.58 168.45,44.58 168.77,44.26 169.5,44.26 169.7,44.06 169.7,43.85 169.6,43.75 166.55,43.75 164.9,45.41 159.9,45.41 159.07,44.58 159.07,44.58 158.16,43.67 156.04,43.67 155.95,43.76 155.95,44.39 156,44.43 157.85,44.43 157.98,44.56 157.98,45.24
1D05V_VCCSTG on BOTTOM: 149.03,27.86 150.44,27.86 150.66,27.63 150.66,23.19 150.66,23.19 149.73,23.19 148.93,23.99 148.21,23.99 148.15,24.05 148.15,26.98 ; 3 cut-outs
1D05V_VCCSTG_OUT_FUSE_R on BOTTOM: 183.94,66.72 185.33,66.72 185.69,66.36 185.69,63.37 185.44,63.13 184.23,63.13 183.64,63.72 183.64,66.41 ; 3 cut-outs
1D05V_VCCSTG_TERM on BOTTOM: 169.1,70.72 170.33,70.72 170.54,70.51 170.54,69.31 170.64,69.2 170.64,68.62 170.57,68.56 169.08,68.56 169.04,68.59 169.04,70.67
1D8V_FCH_C10 on TOP: 163.17,48.91 164.6,48.91 164.6,48.38 164.72,48.26 165.91,48.26 165.99,48.19 167.07,48.19 167.28,47.97 167.28,46.39 167.98,45.69 167.98,45.69 168.3,45.38 168.3,45.38 168.73,44.95 170.21,44.95 170.33,44.82 170.33,44.46 170.28,44.41 168.74,44.41 168.45,44.7 166.88,44.7 165.01,46.57 163.19,46.57 163.11,46.65 163.11,47.4 163.11,47.4 163.11,48.84 ; 3 cut-outs
1D8V_FCH_C10 on BOTTOM: 169.78,49.08 173.49,49.08 173.71,48.85 173.71,48.2 173.4,47.89 170.3,47.89 168.54,46.13 168.55,46.12 168.55,45.17 168.42,45.03 167.62,45.03 167.48,45.17 167.48,46.1 167.44,46.14 167.44,46.73 ; 2 cut-outs
1D8V_S0 on TOP: 20.11,81.24 22.28,81.24 22.34,81.17 22.34,79.58 22.14,79.37 20.08,79.37 20.01,79.44 20.01,81.15 ; 1 cut-out
1D8V_S5 on TOP: 159.1,49.77 162.84,49.77 162.99,49.63 162.99,46.43 162.88,46.33 161.27,46.33 161.27,47.56 161.14,47.7 159.96,47.7 159.78,47.88 158.71,47.88 158.71,49.06 158.96,49.3 158.96,49.63 ; 1 cut-out
1D8V_S5 on TOP: 16.7,81.26 19.66,81.26 19.82,81.1 19.82,78.29 19.37,77.83 19.37,77.03 19.27,76.93 18.5,76.93 17.75,76.93 17.72,76.96 17.72,78.22 17.8,78.3 17.94,78.3 18.15,78.52 18.15,79.98 18.07,80.06 16.66,80.06 16.62,80.1 16.62,81.18 ; 1 cut-out
1D8V_S5 on TOP: 176.63,31.29 179.37,31.29 179.47,31.19 179.47,30.4 179.35,30.28 177.38,30.28 177.26,30.4 177.26,30.87 177.22,30.92 176.64,30.92 176.55,31 176.55,31.2
1D8V_S5 on TOP: 184.82,20.56 185.73,20.56 185.86,20.43 185.86,18.68 186.24,18.3 186.24,17.49 186.07,17.31 185.18,17.31 184.61,17.87 184.61,20.35 ; 2 cut-outs
1D8V_S5 on TOP: 127.54,32.7 130.88,32.7 130.95,32.63 130.95,31.03 131.12,30.86 138.64,30.86 138.67,30.89 142.75,30.89 143.34,30.3 154.56,30.3 155.46,29.41 158.17,29.41 159.06,30.3 162.46,30.3 162.79,29.98 162.79,25.48 162.21,24.9 150.93,24.9 148.52,27.31 143.34,27.31 143.34,27.33 133.57,27.33 133.03,26.79 127.89,26.79 127.45,27.23 127.45,32.61
1D8V_S5 on BOTTOM: 171.66,34.14 175.38,34.14 175.87,33.65 179.17,33.65 179.88,32.93 179.88,31.07 179.29,30.47 176.23,30.47 175.99,30.23 176.01,30.21 176.01,29.39 175.91,29.29 175.42,29.29 175.09,28.96 175.09,26.47 174.86,26.24 160.66,26.24 160,26.9 160,31.68 160.47,32.15 169.65,32.15 170.89,33.39 170.91,33.39 ; 4 cut-outs
1D8V_S5 on L3: 177.62,30.09 180.81,30.09 180.89,30.17 180.89,31.74 181.9,32.74 184.73,32.74 185.48,31.99 185.48,31.58 185.59,31.46 186.42,31.46 186.58,31.62 186.58,34.09 186.34,34.33 185.81,34.33 185.77,34.29 177.34,34.29 177.01,33.97 177.01,33.95 176.64,33.57 176.64,32.66 176.67,32.63 176.67,31.04
1D8V_VCCIN_AUX on TOP: 175.11,67.16 176.35,67.16 176.63,66.88 176.63,65.39 176.37,65.13 175.73,65.13 175.39,64.78 175.17,64.78 175.07,64.88 175.07,65.56 174.82,65.81 174.66,65.81 174.51,65.96 174.51,66.24 174.63,66.36 174.83,66.36 174.99,66.52 174.99,67.04
1D8V_VCCIN_AUX on TOP: 174.38,55.77 175.05,55.77 175.36,55.45 175.36,54.03 173.53,52.2 173.53,52.08 173.32,51.87 173.08,51.87 172.92,52.02 172.92,52.25 173.13,52.45 173.13,52.72 172.95,52.9 172.95,53.13 173.19,53.37 173.19,53.59 172.96,53.83 172.96,54.07 173.19,54.31 173.19,54.51 172.98,54.72 172.98,55.04 173.44,55.49 174.11,55.49
1D8V_VCCIN_AUX on TOP: 174.22,39.04 175.13,39.04 175.28,38.89 175.28,33.74 175.51,33.51 175.51,30.99 175.44,30.92 174.93,30.92 174.88,30.97 174.88,31.59 174.69,31.79 174.35,31.79 174.26,31.87 174.26,32.37 174.24,32.39 174.24,32.77 174.67,33.2 174.67,33.48 174.24,33.91 174.24,34.07 173.79,34.52 173.79,38.61
1D8V_VCCIN_AUX on TOP: 167.45,59.71 168.73,59.71 168.76,59.68 169.55,59.68 169.75,59.47 169.75,56.93 169.57,56.76 168.96,56.76 168.44,56.23 168.44,54.97 168.16,54.69 166.81,54.69 164.84,52.72 164.84,50.02 164.75,49.92 159.39,49.92 158.7,50.61 155.72,50.61 154.26,52.06 154.04,52.06 154.02,52.08 148.96,52.08 148.53,52.51 148.53,57.55 148.88,57.9 154.19,57.9 155.94,56.15 158.61,56.15 159.46,55.29 160.37,55.29 161.16,56.08 163.22,56.08 164.1,56.97 164.71,56.97 ; 15 cut-outs
1D8V_VCCIN_AUX on BOTTOM: 173.07,68.23 176.52,68.23 176.52,68.23 177.93,68.23 178.07,68.09 178.07,67.29 177.7,66.92 177.7,63.54 177.45,63.29 176.37,63.29 176.25,63.17 176.25,61.24 176.02,61 176.02,54.18 175.34,53.5 173.76,53.5 173.61,53.36 173.61,51.96 171.35,49.69 169.05,49.69 166.76,47.4 166.76,43.99 169.09,41.66 169.64,41.66 170.28,41.03 170.28,40.38 172.12,38.54 173.04,38.54 173.13,38.45 174.5,38.45 174.7,38.65 175.39,38.65 175.69,38.35 175.69,37.57 176.29,36.97 176.29,36.13 175.69,35.53 175.69,34.58 175.42,34.31 171.31,34.31 169.38,32.37 166.13,32.37 165.71,32.79 165.71,37.11 158.96,43.86 158.96,46.81 158.13,47.64 157.09,47.64 155.1,49.62 155.1,51.62 154.09,52.63 149.75,52.63 149.48,52.89 149.48,58.7 150.06,59.28 172.02,59.28 172.55,59.81 172.55,62.44 172.17,62.81 172.17,65.07 172.98,65.88 172.98,68.14 ; 29 cut-outs
1D8V_VCCIN_AUX on L4: 150.67,56.8 161.75,56.8 164.39,59.43 169.2,59.43 169.55,59.08 169.55,55.56 169.1,55.11 167.31,55.11 164.44,52.24 156.09,52.24 155.54,51.69 150.56,51.69 150.2,52.06 150.2,56.33
2D5V_S3 on TOP: 246.53,9.82 248.73,9.82 248.76,9.79 248.76,8.1 248.32,7.66 245.91,7.66 245.82,7.74 245.82,9.11
2D5V_S3 on TOP: 231.03,9.9 233.9,9.9 234.05,9.75 234.05,7.97 233.96,7.87 231.11,7.87 230.88,8.1 230.88,9.75
2D5V_S3 on BOTTOM: 244.27,8.68 245.91,8.68 245.93,8.66 245.94,8.67 248.14,8.67 248.27,8.54 248.27,7.84 248.02,7.59 248.02,6.34 247.97,6.29 244.19,6.29 244.13,6.35 244.13,7.15 244.13,7.16 244.13,8.54 ; 8 cut-outs
2D5V_S3 on BOTTOM: 231.33,9.59 234.08,9.59 234.15,9.52 234.15,8.1 233.69,7.64 233.69,6.77 233.63,6.71 231.15,6.71 231.07,6.79 231.07,9.34 ; 3 cut-outs
2D5V_S3 on BOTTOM: 257.89,13.35 259.84,13.35 259.99,13.2 259.99,11.95 259.41,11.38 257.73,11.38 257.39,11.72 257.39,12.86
2D5V_S3 on L3: 231.88,8.7 234.07,8.7 235.6,7.17 244.53,7.17 245.86,8.49 250.83,8.49 252.58,10.24 254.58,10.24 255.17,10.83 255.17,12.15 256,12.99 258.26,12.99 258.53,12.72 258.53,11.17 258.37,11.01 257.41,11.01 257.03,10.63 257.03,7.55 255.22,5.74 233.93,5.74 231.8,7.87 231.8,8.63
3D3V_AUDIO_S0 on TOP: 42.51,70.24 43.29,70.24 43.42,70.1 43.42,67.82 43.35,67.74 35.87,67.74 35.39,68.23 34.3,68.23 34.06,68.47 34.06,68.48 33.94,68.6 33.94,69.48 34.01,69.55 36.32,69.55 36.5,69.72 39.91,69.72 40.06,69.87 42.33,69.87 42.42,69.96 42.42,70.14 ; 8 cut-outs
3D3V_AUX_S5 on TOP: 93.46,29.17 100.84,29.17 101.09,28.93 101.09,24.97 100.79,24.68 99.25,24.68 98.7,25.23 98.7,27.15 98.02,27.83 93.44,27.83 93.29,27.97 93.29,29
3D3V_AUX_S5 on BOTTOM: 86.7,19.74 87.1,19.74 87.4,19.44 87.4,18.98 86.76,18.35 86.76,17.11 86.64,16.98 84.24,16.98 84.21,17.01 84.21,17.67 84.29,17.75 85.27,17.75 85.48,17.96 85.48,18.53
3D3V_AUX_S5 on BOTTOM: 93.31,30.39 95.15,30.39 95.29,30.26 96.36,30.26 96.45,30.17 96.45,29.07 95.52,28.14 94.62,28.14 94.29,27.81 94.29,26.84 93.89,26.43 92.73,26.43 92.59,26.57 92.59,27.7 93.21,28.31 93.21,30.29 ; 3 cut-outs
3D3V_AUX_S5 on BOTTOM: 66.76,12.29 68.26,12.29 68.56,12 68.56,9.14 68.62,9.08 72.27,9.08 72.48,8.86 72.48,6.44 72.3,6.26 70.79,6.26 70.66,6.38 70.66,8.02 70.57,8.12 70.08,8.12 70.08,8.11 67.23,8.11 67.14,8.2 67.14,8.2 66.54,8.8 66.54,12.07 ; 9 cut-outs
3D3V_CAM on TOP: 220.18,99.89 222.04,99.89 222.18,99.75 222.18,98.28 222.14,98.24 220.2,98.24 220.07,98.37 220.07,99.77
3D3V_CAM on BOTTOM: 220.5,100.58 222.67,100.58 223.62,99.63 226.56,99.63 226.72,99.48 226.72,99.13 226.57,98.98 225.63,98.98 225.38,98.73 225.38,98.23 225.25,98.09 225.17,98.09 225.16,98.09 222.95,98.09 222.95,98.09 220.31,98.09 220.24,98.16 220.24,100.33 ; 6 cut-outs
3D3V_CAM_R on BOTTOM: 218.96,103 226.39,103 226.67,102.72 226.67,99.93 226.55,99.81 225.39,99.81 225.15,100.05 223.6,100.05 223.51,100.14 223.51,101.06 223.18,101.39 220.04,101.39 219.84,101.19 219.84,98.16 219.76,98.08 218.95,98.08 218.83,98.2 218.83,102.87 ; 1 cut-out
3D3V_CARD_C on TOP: 31.05,89.6 32.6,89.6 32.81,89.39 32.81,84.35 32.69,84.24 30.96,84.24 30.83,84.36 30.83,89.38
3D3V_CARD_C on BOTTOM: 30.96,89.63 32.62,89.63 32.85,89.4 32.85,84.05 32.75,83.94 31.01,83.94 30.74,84.2 30.74,89.41 ; 9 cut-outs
3D3V_DMIC_R on TOP: 206.38,101.81 208.71,101.81 208.8,101.73 208.8,98.42 208.76,98.39 207.73,98.39 207.64,98.48 207.64,98.81 206.17,100.27 206.17,101.6
3D3V_DMIC_R on BOTTOM: 206.57,103.06 218.48,103.06 218.7,102.84 218.7,99.01 218.7,99.01 218.7,98.48 218.63,98.41 217.73,98.41 217.54,98.59 217.54,99.9 217.65,100.01 217.66,100.01 217.83,100.18 217.83,101.54 217.63,101.73 208,101.73 207.89,101.63 207.89,100.92 207.66,100.69 206.61,100.69 206.29,101.01 206.29,102.78
3D3V_EDP_VDDIO on TOP: 36.63,23.39 37.29,23.39 37.39,23.29 37.39,22.89 37.59,22.68 38.2,22.68 38.28,22.61 38.28,21.84 38.1,21.67 37.69,21.67 37.49,21.46 37.49,20.93 37.87,20.55 37.87,20.44 37.89,20.42 37.89,19.98 37.57,19.66 36.37,19.66 36.21,19.81 33.91,19.81 33.57,19.47 33.57,19.01 33.47,18.91 32.98,18.91 32.91,18.98 32.91,21.41 33.04,21.53 34.94,21.53 35.63,20.84 36.1,20.84 36.55,21.29 36.55,23.32 ; 5 cut-outs
3D3V_EDP_VDDIOX on TOP: 28.88,28.88 30.49,28.88 30.62,28.76 30.62,28.37 30.86,28.13 32.32,28.13 32.4,28.05 32.4,27.41 32.65,27.16 32.65,24.57 32.6,24.51 31.87,24.51 31.01,25.37 31.01,25.64 31.28,25.91 31.28,26.48 30.5,27.27 30.19,27.27 30,27.08 29.54,27.08 28.79,27.83 28.79,28.79 ; 6 cut-outs
3D3V_LAN on TOP: 65.71,92.13 66.94,92.13 67.16,91.92 67.16,91.08 67.25,90.99 67.25,90.23 67.18,90.17 66.15,90.17 66.03,90.04 65.56,90.04 65.48,90.12 65.48,91.9 ; 2 cut-outs
3D3V_LAN on TOP: 58.09,86.11 59.78,86.11 59.93,85.96 59.93,85.11 59.54,84.72 59.54,83.06 59.66,82.93 59.66,80.88 60.05,80.49 63.4,80.49 63.4,80.5 63.67,80.5 63.94,80.77 63.94,81.41 64.96,82.43 65.43,82.43 65.45,82.45 66.42,82.45 67.34,83.36 67.95,83.36 68.05,83.26 68.05,82.18 67.49,81.61 65.66,81.61 65.12,81.07 65.12,80.18 65.17,80.12 65.17,79.01 65,78.84 61.17,78.84 61.11,78.78 60.37,78.78 59.78,78.18 59.78,77.53 59.68,77.43 59.12,77.43 58.85,77.7 58.85,79.46 58.75,79.56 57.56,79.56 57.32,79.8 57.32,82.68 57.44,82.79 57.77,82.79 57.94,82.97 57.94,83.48 57.21,84.21 57.21,85.23 ; 11 cut-outs
3D3V_LAN on BOTTOM: 59.18,67.94 62.23,67.94 63.68,66.5 66.23,66.5 66.8,67.07 73.61,67.07 73.76,67.23 74.42,67.23 74.67,66.98 74.67,65.51 74.56,65.41 62.59,65.41 61.49,66.5 60.27,66.5 60.2,66.42 60.2,62.76 60.05,62.61 57.3,62.61 56.95,62.97 56.95,63.86 57.48,64.39 58.14,64.39 58.95,65.2 58.95,67.72 ; 6 cut-outs
3D3V_LAN on L4: 65.5,92.19 67.11,92.19 67.22,92.07 67.22,90.53 67.06,90.36 65.58,90.36 65.43,90.51 65.43,92.12
3D3V_LAN on L4: 64.57,82.58 66.59,82.58 66.67,82.49 66.67,81.25 66.58,81.16 64.4,81.16 64.27,81.29 64.27,82.28
3D3V_LAN_EN on TOP: 55.57,77 57.74,77 57.8,76.94 57.8,74.27 57.62,74.08 55.66,74.08 55.36,74.39 55.36,76.79 ; 3 cut-outs
3D3V_LAN_VDDREG on TOP: 66.37,89.69 67.23,89.69 67.3,89.62 67.3,88.87 67.12,88.69 66.83,88.69 66.56,88.42 66.56,87.8 66.16,87.39 66.16,86.98 66.16,86.67 66.08,86.59 65.35,86.59 64.96,86.98 63.88,86.98 63.73,87.14 63.73,87.64 63.87,87.78 64.27,87.78 64.61,88.13 64.61,88.76 64.81,88.95 65.47,88.95 65.48,88.96 65.8,88.96 65.81,88.95 66.07,88.95 66.29,89.18 66.29,89.61 ; 4 cut-outs
3D3V_LAN_VDDREG on BOTTOM: 64.02,87.78 65,87.78 65.07,87.71 65.07,87.45 64.49,86.87 63.65,86.87 63.53,86.74 63.53,85.83 63.45,85.75 63.3,85.75 63.3,86.97 63.75,87.42 63.75,87.51
3D3V_MAIN_MSSD on BOTTOM: 31.14,95.4 31.95,95.4 32.02,95.33 32.02,94.49 32.51,94.01 33.21,94.01 33.23,94.02 33.59,94.02 33.6,94.01 34.88,94.01 35.12,94.25 35.54,94.25 35.67,94.12 35.67,92.91 35.86,92.72 35.86,91.53 35.59,91.26 31.33,91.26 30.99,91.61 30.99,95.25 ; 14 cut-outs
3D3V_RTC_AUX on BOTTOM: 203.47,18.88 204.62,18.88 204.76,18.74 204.76,17.74 204.54,17.53 203.55,17.53 203.34,17.74 203.34,18.75
3D3V_S0 on TOP: 150.67,9.65 158.27,9.65 158.27,9.64 158.89,9.64 159.06,9.47 159.06,8.26 158.88,8.08 152.12,8.08 151.92,7.87 149.89,7.87 149.83,7.92 149.83,8.81
3D3V_S0 on TOP: 234.48,10.42 237.33,10.42 238.34,9.42 238.34,8.52 238.67,8.18 242.67,8.18 243.37,8.88 243.37,9.69 243.99,10.31 246.65,10.31 246.81,10.15 246.81,9.96 245.2,8.35 245.2,6.04 245.03,5.87 236.06,5.87 234.38,7.54 234.38,10.33
3D3V_S0 on TOP: 167.92,22.69 170.66,22.69 170.89,22.46 170.89,19.54 170.17,18.81 170.17,14.48 170.68,13.97 174.39,13.97 174.51,13.86 174.51,9.51 173.96,8.97 173.96,7.87 173.9,7.81 173.5,7.81 173.45,7.86 173.45,8.96 172.91,9.5 172.27,9.5 172.27,8.34 172.25,8.32 172.35,8.21 172.35,6.22 172.84,5.74 173.33,5.74 173.45,5.86 173.45,7.01 173.51,7.07 173.88,7.07 174.03,6.92 174.03,5.87 174.13,5.78 175.45,5.78 175.5,5.83 177.56,5.83 177.57,5.82 178.13,5.82 178.49,6.17 178.49,7.29 178.49,9.64 178.85,10.01 178.85,13.18 179.74,14.07 179.74,15.25 179.74,15.25 179.74,15.93 179.8,15.99 183.04,15.99 183.34,15.69 183.34,12.27 180.93,9.86 180.93,4.82 180.65,4.54 166.37,4.54 165.91,5 165.91,8.32 165.68,8.55 159.8,14.43 156.33,14.43 156.18,14.58 156.18,17.45 156.24,17.51 167.34,17.51 167.67,17.84 167.67,22.44 ; 6 cut-outs
3D3V_S0 on TOP: 83.97,65.14 84.7,65.14 84.93,64.92 84.93,63.94 85.32,63.55 89.08,63.55 89.13,63.5 89.13,62.28 89.07,62.22 87.49,62.22 87.43,62.28 84.99,62.28 84.8,62.09 82.76,62.09 82.61,62.25 82.61,64.14 82.65,64.19 83.58,64.19 83.81,64.42 83.81,64.98 ; 6 cut-outs
3D3V_S0 on TOP: 6.21,46.39 8.16,46.39 8.26,46.29 8.26,45.42 9.14,44.54 9.14,43.51 10.47,42.18 10.47,41.14 11.82,39.8 13,39.8 13.51,39.29 13.51,37.26 13.61,37.15 13.61,32.72 8.34,27.45 8.34,23.16 7.89,22.71 3.49,22.71 3.2,23 3.2,26.42 11.14,34.35 11.14,38.47 10.51,39.09 10.51,39.54 9.52,40.53 9.5,40.53 6.13,43.9 6.13,46.31
3D3V_S0 on TOP: 83.11,80.77 88.95,80.77 89.05,80.67 89.05,79.78 89.03,79.76 87.22,79.76 87.02,79.55 87.02,78.23 87.2,78.05 89.08,78.05 89.13,78 89.13,76.33 89.05,76.25 81.99,76.25 81.71,76.53 81.71,79.37 ; 6 cut-outs
3D3V_S0 on TOP: 68.03,15.62 72.4,15.62 72.61,15.4 72.61,14.85 71.6,13.84 70.51,13.84 70.19,13.51 70.19,11.87 70.09,11.77 69.63,11.77 68.74,10.87 68.74,3.84 69.67,2.9 75.3,2.9 75.77,3.37 83.64,3.37 84.37,2.63 100.73,2.63 103.33,5.23 108.51,5.23 109.91,3.84 109.91,1.42 109.53,1.05 69.72,1.05 69.25,1.52 66.09,1.52 65.31,2.31 65.31,12.94 65.54,13.17 65.58,13.17
3D3V_S0 on TOP: 118.11,6.78 121.77,6.78 122.69,5.86 122.69,5.29 123.21,4.78 128.27,4.78 130.31,2.73 133.32,2.73 133.45,2.59 133.45,1.57 133.32,1.45 120.47,1.45 119.86,2.05 119.86,3.98 119.6,4.24 118.03,4.24 117.81,4.47 117.81,6.1 117.83,6.12 117.83,6.5
3D3V_S0 on BOTTOM: 151.05,8.74 152.1,8.74 152.27,8.56 152.27,6.91 152.26,6.9 152.26,5.83 152.04,5.61 152.04,5.59 151.86,5.42 138.34,5.42 136.34,3.41 136.34,3.39 135.5,2.56 134.92,2.56 134.59,2.22 132.4,2.22 132.05,2.56 132.05,4.83 132.37,5.15 134.16,5.15 134.36,5.35 134.36,7.08 134.74,7.47 146.2,7.47 146.21,7.46 149.51,7.46 149.86,7.82 149.86,8.43 150.15,8.72 151.04,8.72
3D3V_S0 on BOTTOM: 217.82,97.91 218.58,97.91 218.79,97.7 219.72,97.7 219.85,97.57 219.85,96.7 219.57,96.42 218.45,96.42 218.32,96.29 217.81,96.29 217.69,96.42 217.69,97.79 ; 2 cut-outs
3D3V_S0 on BOTTOM: 41.4,61.01 42.24,61.01 42.39,60.86 42.39,59.68 43.06,59.02 43.06,58.51 42.92,58.37 41.91,58.37 41.83,58.29 41.83,57.12 41.81,57.09 41.4,57.09 41.38,57.12 41.38,58.83 41.27,58.93 41.27,60.88
3D3V_S0 on BOTTOM: 203.8,76.31 205.72,76.31 205.76,76.27 205.76,74.79 205.69,74.72 203.8,74.72 203.75,74.78 203.75,76.25
3D3V_S0 on BOTTOM: 234.63,9.02 235.99,9.02 236.14,8.86 236.14,6.92 235.83,6.61 233.99,6.61 233.91,6.69 233.91,7.55 234.41,8.05 234.41,8.76 234.39,8.78 ; 2 cut-outs
3D3V_S0 on BOTTOM: 156.92,15.95 158.56,15.95 158.79,15.72 158.79,7.51 158.67,7.39 156.69,7.39 156.54,7.54 156.54,14.33 156.53,14.34 156.54,14.35 156.54,15.57
3D3V_S0 on BOTTOM: 85.61,10.69 86.57,10.69 87.31,9.95 87.77,9.95 87.9,9.82 87.9,8.01 87.78,7.89 86.56,7.89 86.48,7.98 86.48,9.75 86.26,9.97 85.59,9.97 85.54,10.02 85.54,10.62
3D3V_S0 on BOTTOM: 47.07,81.36 49.48,81.36 49.53,81.31 49.53,77.98 49.4,77.85 48.01,77.85 47.87,78 47.87,79.72 47.49,80.1 47.04,80.1 46.99,80.15 46.99,81.28 ; 4 cut-outs
3D3V_S0 on BOTTOM: 19.82,103.48 48.59,103.48 50.97,101.09 50.97,86.24 50.75,86.02 49.28,86.02 48.23,87.07 48.23,97.7 45.38,100.55 23.01,100.55 17.52,95.06 17.52,91.55 16.22,90.25 12.72,90.25 12.17,89.7 12.17,82.92 11.5,82.24 7.12,82.24 6.28,83.07 6.28,89.94
3D3V_S0 on BOTTOM: 243.83,8.65 243.95,8.53 243.95,6.83 243.83,6.71 243.83,6.6 241.47,6.6 241.4,6.67 241.4,8.48 241.57,8.65 ; 3 cut-outs
3D3V_S0 on BOTTOM: 5.06,10.73 7.82,10.73 8.39,10.17 8.39,8.91 10.23,7.06 23.17,7.06 24.47,8.36 58.9,8.36 59.56,7.69 63.86,7.69 66.64,4.92 66.64,2.36 66.47,2.19 65.41,2.19 65.26,2.34 65.26,4.75 63.72,6.29 62.63,6.39 27.77,6.39 25.45,6.29 23.77,4.62 23.77,2.46 22.96,1.65 6.53,1.65 6.26,1.92 6.26,6.23 4.94,7.54 4.94,10.61
3D3V_S0 on BOTTOM: 117.96,6.68 119.25,6.68 119.43,6.5 119.43,4.67 118.85,4.09 110.16,4.09 109.78,3.71 109.78,2.51 109.68,2.41 108.56,2.41 108.46,2.51 108.46,4.75 109.3,5.59 117.63,5.59 117.81,5.77 117.81,6.53
3D3V_S0 on L3: 199.78,8.97 192.7,8.97 192.06,8.33 177.64,8.33 177.3,7.99 177.3,6.27 178.29,5.28 192.06,5.28 193.91,7.13 197.02,7.13 197.04,7.1 199.72,7.1 199.96,7.35 199.96,8.8
3D3V_S0 on L3: 48.03,77.19 52.19,77.19 52.41,77.41 52.41,81.08 53.81,82.48 54.43,82.48 58.95,87 62.07,87 62.36,86.7 66.32,86.7 66.6,86.41 66.6,83.37 67.23,82.73 67.23,78.92 69.01,77.14 79.2,77.14 80.47,75.87 80.47,73.98 82.4,72.05 82.4,68.93 82.82,68.51 82.82,64.01 83.15,63.68 85.85,63.68 86.21,64.04 86.21,76.11 86.51,76.41 87,76.41 87.48,76.89 87.48,78.21 87.27,78.42 86.41,78.42 86.21,78.62 86.21,80.26 85.3,81.17 80.23,81.17 79.45,81.95 75.86,81.95 71.62,86.19 71.62,89.01 69.95,90.68 64.97,90.68 63.93,91.72 63.63,91.72 62.61,90.7 55.09,90.7 52.57,88.18 49.06,88.18 48.87,87.99 48.87,86.48 49.17,86.18 49.73,86.18 49.73,85.34 47.57,83.19 47.57,77.65
3D3V_S0 on L3: 66.9,4.83 65.89,5.84 65.12,6.6 64.63,6.6 63.04,8.2 55.17,8.2 54.91,7.94 54.91,6.74 55.17,6.48 63.29,6.48 65.33,4.44 65.33,2.2 65.4,2.13 66.56,2.13 66.9,2.47
3D3V_S0 on L3: 13.81,36.98 13.41,37.38 13.41,37.87 13.42,37.87 13.42,38.8 12.45,39.77 11.85,39.77 10.46,41.16 10.46,42.28 9.16,43.58 9.16,43.69 9.17,43.7 9.17,44.58 8.67,45.08 8.67,56.62 11.01,58.96 11.01,67.34 10.07,68.28 10.07,73.73 10.27,73.93 17.33,73.93 17.66,74.26 17.66,75.43 17.36,75.73 12.37,75.73 11.38,76.72 11.38,82.85 11.02,83.21 7.26,83.21 6.41,82.36 6.41,65.93 6.04,65.56 6.04,43.51 7.08,42.47 8.36,41.1 10.8,38.65 10.8,34.29 5.7,29.18 5.7,28.15 5.97,27.88 7.62,27.88 13.81,34.07
3D3V_S0 on L4: 1.78,9.71 6.66,9.71 7.03,10.08 7.03,14.72 5.07,16.67 5.07,24.53 4.82,24.78 3.23,24.78 2.83,24.38 2.83,22.96 1.61,21.74 1.61,9.88
3D3V_S0 on L4: 215.86,8.55 231.3,8.55 232.08,7.77 234.22,7.77 234.3,7.85 234.3,8.73 234.48,8.91 236.04,8.91 236.14,8.8 236.14,5.41 235.95,5.22 235.04,5.22 234.28,4.46 231.34,4.46 231.07,4.19 223.66,4.19 223.62,4.24 219.97,4.24 219.47,3.74 207.43,3.74 203.95,7.21 198.33,7.21 198.09,7.46 198.09,9.86 198.22,10 214.42,10
3D3V_S0 on L4: 65.3,4.39 65.3,2.51 65.54,2.27 66.6,2.27 66.66,2.33 66.66,4.96 63.91,7.71 55.48,7.71 55.36,7.59 55.36,7.12 56.08,6.39 61.44,6.39 61.76,6.08 63.61,6.08
3D3V_S5 on TOP: 180.71,31.7 181.44,31.7 181.73,31.42 181.85,31.42 182.7,30.56 182.7,30.37 182.63,30.3 181.52,30.3 180.48,31.34 180.48,31.47
3D3V_S5 on TOP: 101.91,11.11 103.28,11.11 104.08,10.31 104.08,10.04 103.91,9.88 101.9,9.88 101.79,9.99 101.79,10.99
3D3V_S5 on TOP: 177.15,7.89 177.97,7.89 178.08,7.78 178.08,6.13 178,6.06 177.08,6.06 176.95,6.19 176.95,7.68
3D3V_S5 on TOP: 58.19,76.98 60.2,76.98 60.33,76.85 60.33,75.87 59.76,75.3 59.76,73.38 59.46,73.08 58.14,73.08 58.03,73.19 58.03,76.82 ; 3 cut-outs
3D3V_S5 on TOP: 129.47,10.33 130.33,10.33 130.65,10 130.65,9.13 131.06,8.73 131.06,7.3 131.34,7.01 135.54,7.01 135.8,6.75 135.8,4.69 135.96,4.53 137.83,4.53 137.83,3.83 137.8,3.79 134.38,3.79 134.24,3.94 134.24,4.62 134.12,4.74 132.71,4.74 132.59,4.86 132.59,5.14 132.36,5.37 130.29,5.37 129.55,6.11 129.55,8.31 129.23,8.63 129.23,10.09 ; 2 cut-outs
3D3V_S5 on TOP: 96.14,38.3 97.43,38.3 99.73,35.99 105.04,35.99 107.9,33.13 107.9,31.35 118.93,20.32 124.47,20.32 125.61,21.45 125.61,22.65 129.27,26.32 132.9,26.32 133.72,27.15 148.24,27.15 154.82,20.56 167.13,20.56 167.45,20.24 167.45,17.98 167.24,17.78 153.83,17.78 147.52,24.09 145.92,24.09 145.86,24.15 142.67,24.15 142.38,24.44 142.38,25.55 142,25.92 134.35,25.92 134.1,25.67 134.1,24.14 134.6,23.64 137.77,23.64 137.89,23.52 137.89,22.85 137.88,22.85 137.88,21.33 135.37,21.33 133.72,19.68 132.01,19.68 131.85,19.84 131.85,24.34 131.67,24.52 129.76,24.52 129.52,24.29 129.52,21.53 129.48,21.49 129.48,20.59 126.25,17.36 118.72,17.36 118.72,17.38 106.71,29.39 106.71,30.09 105.15,31.65 105.14,31.65 103.81,32.98 95.18,32.98 94.99,33.16 94.99,37.16 ; 7 cut-outs
3D3V_S5 on TOP: 47.88,86.06 49.56,86.06 49.75,85.86 49.75,82.39 50.14,81.99 51.01,81.99 51.76,82.74 56.39,82.74 56.62,82.51 56.62,80.68 56.33,80.39 56.11,80.39 55.88,80.16 55.88,79.03 54.04,77.19 50.13,77.19 49.95,77.37 49.95,78.21 47.7,80.47 47.7,85.88
3D3V_S5 on TOP: 198.01,21.12 198.6,21.12 198.73,20.99 198.73,20.37 198.97,20.13 199.19,20.13 199.29,20.03 199.29,19.27 197.78,17.76 197.78,15.8 197.49,15.5 193.72,15.5 192.92,14.7 192.76,14.7 192.42,14.36 192.42,12.7 190.2,10.49 190.2,7.27 190.48,6.99 190.48,6.6 191.78,5.29 193.34,5.29 193.45,5.41 193.45,6.21 193.39,6.27 193.05,6.27 192.85,6.47 192.85,7.01 192.97,7.13 195.1,7.13 195.26,7.29 195.26,8.09 195.51,8.35 197.62,8.35 198.2,7.77 198.2,6.47 200.92,3.75 201.09,3.75 201.1,3.76 201.32,3.76 201.93,3.15 210.82,3.15 211.38,3.71 211.42,3.71 212.42,4.71 212.44,4.71 212.44,8.17 212.74,8.47 213.98,8.47 214.29,8.16 214.29,4.32 215.52,3.09 232.41,3.09 232.42,3.11 235.54,3.11 235.73,2.92 235.73,1.86 235.43,1.56 199.95,1.56 198.72,2.79 189.29,2.79 188.76,3.32 188.76,7.07 188.79,7.11 188.79,10.88 190.12,12.21 190.14,12.21 190.85,12.92 190.85,14.87 192.72,16.74 192.72,16.74 194.06,18.08 195,18.08 196.25,19.33 197.69,19.33 197.91,19.54 197.91,20.08 197.91,20.08 197.91,21.02 ; 4 cut-outs
3D3V_S5 on TOP: 176.83,16.56 178.82,16.56 178.91,16.47 178.91,15.25 179.04,15.12 179.48,15.12 179.56,15.04 179.56,14.19 179.49,14.11 176.45,14.11 176.39,14.17 176.39,15.5 176.77,15.88 176.77,16.5 ; 4 cut-outs
3D3V_S5 on BOTTOM: 53.51,82.17 55.57,82.17 55.75,81.99 55.75,78.14 56.73,77.15 60.3,77.15 63.13,74.32 74.59,74.32 75.88,75.61 75.89,75.61 76.1,75.81 84.8,75.81 85.51,75.1 85.51,71.77 86.13,71.15 86.13,68.92 88.48,66.58 88.48,65.47 89.21,64.74 93.87,64.74 94.33,64.27 94.33,61.03 93.4,60.1 87,60.1 82.01,65.09 82.01,67.92 80.1,69.83 64.67,69.83 63.96,70.54 62.21,70.54 59.05,73.7 55.23,73.7 53.32,75.61 53.32,81.98
3D3V_S5 on BOTTOM: 175.62,20.26 177.38,20.26 177.53,20.11 177.53,19.59 177.53,19.02 177.19,18.68 177.13,18.68 177.13,16.4 177.53,15.99 177.53,14.83 177.33,14.63 175.16,14.63 175.16,19.8
3D3V_S5 on BOTTOM: 184.99,20.68 187.66,20.68 187.73,20.6 187.73,19.89 187.67,19.83 186.37,19.83 186.1,19.57 186.1,18.33 186.01,18.24 185.64,18.24 185.27,17.86 185.27,17.14 184.88,16.76 183.32,16.76 183.21,16.86 183.21,17.53 184.21,18.53 184.21,19.45 184.85,20.09 184.85,20.54 ; 6 cut-outs
3D3V_S5 on BOTTOM: 166.55,22.4 169.21,22.4 169.21,17.82 169.05,17.65 165.86,17.65 164.69,18.82 163.83,18.82 163.74,18.92 163.74,20.48 164.83,21.57 165.73,21.57 ; 5 cut-outs
3D3V_S5 on BOTTOM: 184.62,34.32 185.23,34.32 185.36,34.18 185.36,33.7 185.36,33.7 185.36,32.52 186.03,32.52 186.29,32.26 186.29,31.69 186.43,31.55 187.53,31.55 187.7,31.37 187.7,30.58 187.65,30.53 186.09,30.53 185.49,31.13 185.19,31.13 184.99,31.32 184.99,31.55 184.74,31.8 184.34,31.8 183.83,31.28 182.98,31.28 182.65,30.95 182.65,30.62 183.04,30.23 183.04,29.59 182.88,29.43 182.3,29.43 181.8,29.93 181.16,29.93 180.97,30.12 180.97,33.42 181.16,33.61 182.52,33.61 183.19,34.28 184.58,34.28 ; 7 cut-outs
3D3V_S5 on BOTTOM: 102.61,52.21 109,52.21 109,48.93 108.83,48.76 102.82,48.76 102.75,48.83 102.75,49.26 102.49,49.52 102.49,49.52 102.15,49.86 102.15,51.1 102.56,51.52 102.56,52.16
3D3V_S5 on BOTTOM: 142.74,25.22 144.73,25.22 144.91,25.04 144.91,16.07 145.72,15.25 145.72,13.7 144.91,12.88 144.91,9.45 143.26,7.8 134.59,7.8 134.22,7.43 134.22,5.46 134.09,5.33 132.98,5.33 132.85,5.46 132.85,7.41 132.68,7.58 132.68,9.15 133.17,9.64 140.93,9.64 142.85,11.56 142.85,12.51 142.46,12.9 142.46,17.03 142.01,17.48 142.01,20.76 142.46,21.21 142.46,24.94 ; 10 cut-outs
